                <enumeratedValue>
                  <name>111</name>
                  <description>Alternative 7 (chip-specific).</description>
                  <value>#111</value>
                </enumeratedValue>
              </enumeratedValues>
            </field>
            <field>
              <name>IRQC</name>
              <description>Interrupt Configuration</description>
              <bitOffset>16</bitOffset>
              <bitWidth>4</bitWidth>
              <access>read-write</access>
              <enumeratedValues>
                <enumeratedValue>
                  <name>0000</name>
                  <description>Interrupt/DMA request disabled.</description>
                  <value>#0000</value>
                </enumeratedValue>
                <enumeratedValue>
                  <name>0001</name>
                  <description>DMA request on rising edge.</description>
                  <value>#0001</value>
                </enumeratedValue>
                <enumeratedValue>
                  <name>0010</name>
                  <description>DMA request on falling edge.</description>
                  <value>#0010</value>
                </enumeratedValue>
                <enumeratedValue>
                  <name>0011</name>
                  <description>DMA request on either edge.</description>
                  <value>#0011</value>
                </enumeratedValue>
                <enumeratedValue>
                  <name>1000</name>
                  <description>Interrupt when logic 0.</description>
                  <value>#1000</value>
                </enumeratedValue>
                <enumeratedValue>
                  <name>1001</name>
                  <description>Interrupt on rising-edge.</description>
                  <value>#1001</value>
                </enumeratedValue>
                <enumeratedValue>
                  <name>1010</name>
                  <description>Interrupt on falling-edge.</description>
                  <value>#1010</value>
                </enumeratedValue>
                <enumeratedValue>
                  <name>1011</name>
                  <description>Interrupt on either edge.</description>
                  <value>#1011</value>
                </enumeratedValue>
                <enumeratedValue>
                  <name>1100</name>
                  <description>Interrupt when logic 1.</description>
                  <value>#1100</value>
                </enumeratedValue>
              </enumeratedValues>
            </field>
            <field>
              <name>ISF</name>
              <description>Interrupt Status Flag</description>
              <bitOffset>24</bitOffset>
              <bitWidth>1</bitWidth>
              <access>read-write</access>
              <enumeratedValues>
                <enumeratedValue>
                  <name>0</name>
                  <description>Configured interrupt is not detected.</description>
                  <value>#0</value>
                </enumeratedValue>
                <enumeratedValue>
                  <name>1</name>
                  <description>Configured interrupt is detected. If the pin is configured to generate a DMA request, then the corresponding flag will be cleared automatically at the completion of the requested DMA transfer. Otherwise, the flag remains set until a logic 1 is written to the flag. If the pin is configured for a level sensitive interrupt and the pin remains asserted, then the flag is set again immediately after it is cleared.</description>
                  <value>#1</value>
                </enumeratedValue>
              </enumeratedValues>
            </field>
          </fields>
        </register>
        <register>
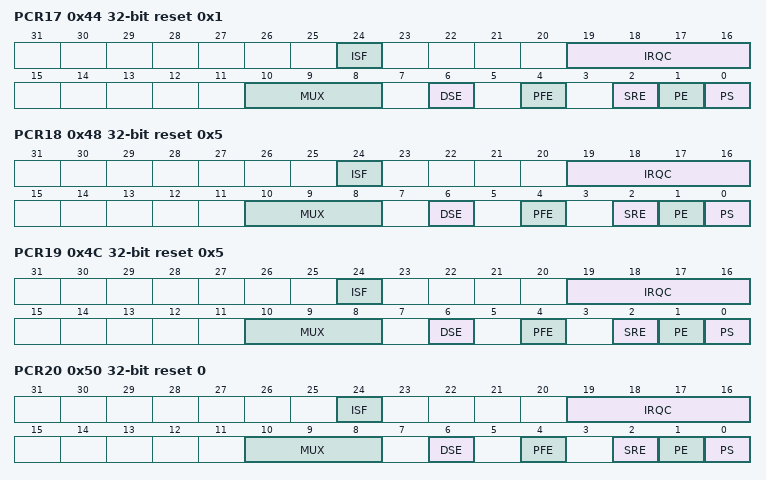
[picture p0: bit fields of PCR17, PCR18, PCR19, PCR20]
          <name>PCR17</name>
          <description>Pin Control Register n</description>
          <addressOffset>0x44</addressOffset>
          <size>32</size>
          <access>read-write</access>
          <resetValue>0x1</resetValue>
          <resetMask>0xFFFFFFFF</resetMask>
          <fields>
            <field>
              <name>PS</name>
              <description>Pull Select</description>
              <bitOffset>0</bitOffset>
              <bitWidth>1</bitWidth>
              <access>read-write</access>
              <enumeratedValues>
                <enumeratedValue>
                  <name>0</name>
                  <description>Internal pulldown resistor is enabled on the corresponding pin, if the corresponding PE field is set.</description>
                  <value>#0</value>
                </enumeratedValue>
                <enumeratedValue>
                  <name>1</name>
                  <description>Internal pullup resistor is enabled on the corresponding pin, if the corresponding PE field is set.</description>
                  <value>#1</value>
                </enumeratedValue>
              </enumeratedValues>
            </field>
            <field>
              <name>PE</name>
              <description>Pull Enable</description>
              <bitOffset>1</bitOffset>
              <bitWidth>1</bitWidth>
              <access>read-write</access>
              <enumeratedValues>
                <enumeratedValue>
                  <name>0</name>
                  <description>Internal pullup or pulldown resistor is not enabled on the corresponding pin.</description>
                  <value>#0</value>
                </enumeratedValue>
                <enumeratedValue>
                  <name>1</name>
                  <description>Internal pullup or pulldown resistor is enabled on the corresponding pin, if the pin is configured as a digital input.</description>
                  <value>#1</value>
                </enumeratedValue>
              </enumeratedValues>
            </field>
            <field>
              <name>SRE</name>
              <description>Slew Rate Enable</description>
              <bitOffset>2</bitOffset>
              <bitWidth>1</bitWidth>
              <access>read-write</access>
              <enumeratedValues>
                <enumeratedValue>
                  <name>0</name>
                  <description>Fast slew rate is configured on the corresponding pin, if the pin is configured as a digital output.</description>
                  <value>#0</value>
                </enumeratedValue>
                <enumeratedValue>
                  <name>1</name>
                  <description>Slow slew rate is configured on the corresponding pin, if the pin is configured as a digital output.</description>
                  <value>#1</value>
                </enumeratedValue>
              </enumeratedValues>
            </field>
            <field>
              <name>PFE</name>
              <description>Passive Filter Enable</description>
              <bitOffset>4</bitOffset>
              <bitWidth>1</bitWidth>
              <access>read-only</access>
              <enumeratedValues>
                <enumeratedValue>
                  <name>0</name>
                  <description>Passive input filter is disabled on the corresponding pin.</description>
                  <value>#0</value>
                </enumeratedValue>
                <enumeratedValue>
                  <name>1</name>
                  <description>Passive input filter is enabled on the corresponding pin, if the pin is configured as a digital input. Refer to the device data sheet for filter characteristics.</description>
                  <value>#1</value>
                </enumeratedValue>
              </enumeratedValues>
            </field>
            <field>
              <name>DSE</name>
              <description>Drive Strength Enable</description>
              <bitOffset>6</bitOffset>
              <bitWidth>1</bitWidth>
              <access>read-only</access>
              <enumeratedValues>
                <enumeratedValue>
                  <name>0</name>
                  <description>Low drive strength is configured on the corresponding pin, if pin is configured as a digital output.</description>
                  <value>#0</value>
                </enumeratedValue>
                <enumeratedValue>
                  <name>1</name>
                  <description>High drive strength is configured on the corresponding pin, if pin is configured as a digital output.</description>
                  <value>#1</value>
                </enumeratedValue>
              </enumeratedValues>
            </field>
            <field>
              <name>MUX</name>
              <description>Pin Mux Control</description>
              <bitOffset>8</bitOffset>
              <bitWidth>3</bitWidth>
              <access>read-write</access>
              <enumeratedValues>
                <enumeratedValue>
                  <name>000</name>
                  <description>Pin disabled (analog).</description>
                  <value>#000</value>
                </enumeratedValue>
                <enumeratedValue>
                  <name>001</name>
                  <description>Alternative 1 (GPIO).</description>
                  <value>#001</value>
                </enumeratedValue>
                <enumeratedValue>
                  <name>010</name>
                  <description>Alternative 2 (chip-specific).</description>
                  <value>#010</value>
                </enumeratedValue>
                <enumeratedValue>
                  <name>011</name>
                  <description>Alternative 3 (chip-specific).</description>
                  <value>#011</value>
                </enumeratedValue>
                <enumeratedValue>
                  <name>100</name>
                  <description>Alternative 4 (chip-specific).</description>
                  <value>#100</value>
                </enumeratedValue>
                <enumeratedValue>
                  <name>101</name>
                  <description>Alternative 5 (chip-specific).</description>
                  <value>#101</value>
                </enumeratedValue>
                <enumeratedValue>
                  <name>110</name>
                  <description>Alternative 6 (chip-specific).</description>
                  <value>#110</value>
                </enumeratedValue>
                <enumeratedValue>
                  <name>111</name>
                  <description>Alternative 7 (chip-specific).</description>
                  <value>#111</value>
                </enumeratedValue>
              </enumeratedValues>
            </field>
            <field>
              <name>IRQC</name>
              <description>Interrupt Configuration</description>
              <bitOffset>16</bitOffset>
              <bitWidth>4</bitWidth>
              <access>read-write</access>
              <enumeratedValues>
                <enumeratedValue>
                  <name>0000</name>
                  <description>Interrupt/DMA request disabled.</description>
                  <value>#0000</value>
                </enumeratedValue>
                <enumeratedValue>
                  <name>0001</name>
                  <description>DMA request on rising edge.</description>
                  <value>#0001</value>
                </enumeratedValue>
                <enumeratedValue>
                  <name>0010</name>
                  <description>DMA request on falling edge.</description>
                  <value>#0010</value>
                </enumeratedValue>
                <enumeratedValue>
                  <name>0011</name>
                  <description>DMA request on either edge.</description>
                  <value>#0011</value>
                </enumeratedValue>
                <enumeratedValue>
                  <name>1000</name>
                  <description>Interrupt when logic 0.</description>
                  <value>#1000</value>
                </enumeratedValue>
                <enumeratedValue>
                  <name>1001</name>
                  <description>Interrupt on rising-edge.</description>
                  <value>#1001</value>
                </enumeratedValue>
                <enumeratedValue>
                  <name>1010</name>
                  <description>Interrupt on falling-edge.</description>
                  <value>#1010</value>
                </enumeratedValue>
                <enumeratedValue>
                  <name>1011</name>
                  <description>Interrupt on either edge.</description>
                  <value>#1011</value>
                </enumeratedValue>
                <enumeratedValue>
                  <name>1100</name>
                  <description>Interrupt when logic 1.</description>
                  <value>#1100</value>
                </enumeratedValue>
              </enumeratedValues>
            </field>
            <field>
              <name>ISF</name>
              <description>Interrupt Status Flag</description>
              <bitOffset>24</bitOffset>
              <bitWidth>1</bitWidth>
              <access>read-write</access>
              <enumeratedValues>
                <enumeratedValue>
                  <name>0</name>
                  <description>Configured interrupt is not detected.</description>
                  <value>#0</value>
                </enumeratedValue>
                <enumeratedValue>
                  <name>1</name>
                  <description>Configured interrupt is detected. If the pin is configured to generate a DMA request, then the corresponding flag will be cleared automatically at the completion of the requested DMA transfer. Otherwise, the flag remains set until a logic 1 is written to the flag. If the pin is configured for a level sensitive interrupt and the pin remains asserted, then the flag is set again immediately after it is cleared.</description>
                  <value>#1</value>
                </enumeratedValue>
              </enumeratedValues>
            </field>
          </fields>
        </register>
        <register>
          <name>PCR18</name>
          <description>Pin Control Register n</description>
          <addressOffset>0x48</addressOffset>
          <size>32</size>
          <access>read-write</access>
          <resetValue>0x5</resetValue>
          <resetMask>0xFFFFFFFF</resetMask>
          <fields>
            <field>
              <name>PS</name>
              <description>Pull Select</description>
              <bitOffset>0</bitOffset>
              <bitWidth>1</bitWidth>
              <access>read-write</access>
              <enumeratedValues>
                <enumeratedValue>
                  <name>0</name>
                  <description>Internal pulldown resistor is enabled on the corresponding pin, if the corresponding PE field is set.</description>
                  <value>#0</value>
                </enumeratedValue>
                <enumeratedValue>
                  <name>1</name>
                  <description>Internal pullup resistor is enabled on the corresponding pin, if the corresponding PE field is set.</description>
                  <value>#1</value>
                </enumeratedValue>
              </enumeratedValues>
            </field>
            <field>
              <name>PE</name>
              <description>Pull Enable</description>
              <bitOffset>1</bitOffset>
              <bitWidth>1</bitWidth>
              <access>read-write</access>
              <enumeratedValues>
                <enumeratedValue>
                  <name>0</name>
                  <description>Internal pullup or pulldown resistor is not enabled on the corresponding pin.</description>
                  <value>#0</value>
                </enumeratedValue>
                <enumeratedValue>
                  <name>1</name>
                  <description>Internal pullup or pulldown resistor is enabled on the corresponding pin, if the pin is configured as a digital input.</description>
                  <value>#1</value>
                </enumeratedValue>
              </enumeratedValues>
            </field>
            <field>
              <name>SRE</name>
              <description>Slew Rate Enable</description>
              <bitOffset>2</bitOffset>
              <bitWidth>1</bitWidth>
              <access>read-write</access>
              <enumeratedValues>
                <enumeratedValue>
                  <name>0</name>
                  <description>Fast slew rate is configured on the corresponding pin, if the pin is configured as a digital output.</description>
                  <value>#0</value>
                </enumeratedValue>
                <enumeratedValue>
                  <name>1</name>
                  <description>Slow slew rate is configured on the corresponding pin, if the pin is configured as a digital output.</description>
                  <value>#1</value>
                </enumeratedValue>
              </enumeratedValues>
            </field>
            <field>
              <name>PFE</name>
              <description>Passive Filter Enable</description>
              <bitOffset>4</bitOffset>
              <bitWidth>1</bitWidth>
              <access>read-only</access>
              <enumeratedValues>
                <enumeratedValue>
                  <name>0</name>
                  <description>Passive input filter is disabled on the corresponding pin.</description>
                  <value>#0</value>
                </enumeratedValue>
                <enumeratedValue>
                  <name>1</name>
                  <description>Passive input filter is enabled on the corresponding pin, if the pin is configured as a digital input. Refer to the device data sheet for filter characteristics.</description>
                  <value>#1</value>
                </enumeratedValue>
              </enumeratedValues>
            </field>
            <field>
              <name>DSE</name>
              <description>Drive Strength Enable</description>
              <bitOffset>6</bitOffset>
              <bitWidth>1</bitWidth>
              <access>read-only</access>
              <enumeratedValues>
                <enumeratedValue>
                  <name>0</name>
                  <description>Low drive strength is configured on the corresponding pin, if pin is configured as a digital output.</description>
                  <value>#0</value>
                </enumeratedValue>
                <enumeratedValue>
                  <name>1</name>
                  <description>High drive strength is configured on the corresponding pin, if pin is configured as a digital output.</description>
                  <value>#1</value>
                </enumeratedValue>
              </enumeratedValues>
            </field>
            <field>
              <name>MUX</name>
              <description>Pin Mux Control</description>
              <bitOffset>8</bitOffset>
              <bitWidth>3</bitWidth>
              <access>read-write</access>
              <enumeratedValues>
                <enumeratedValue>
                  <name>000</name>
                  <description>Pin disabled (analog).</description>
                  <value>#000</value>
                </enumeratedValue>
                <enumeratedValue>
                  <name>001</name>
                  <description>Alternative 1 (GPIO).</description>
                  <value>#001</value>
                </enumeratedValue>
                <enumeratedValue>
                  <name>010</name>
                  <description>Alternative 2 (chip-specific).</description>
                  <value>#010</value>
                </enumeratedValue>
                <enumeratedValue>
                  <name>011</name>
                  <description>Alternative 3 (chip-specific).</description>
                  <value>#011</value>
                </enumeratedValue>
                <enumeratedValue>
                  <name>100</name>
                  <description>Alternative 4 (chip-specific).</description>
                  <value>#100</value>
                </enumeratedValue>
                <enumeratedValue>
                  <name>101</name>
                  <description>Alternative 5 (chip-specific).</description>
                  <value>#101</value>
                </enumeratedValue>
                <enumeratedValue>
                  <name>110</name>
                  <description>Alternative 6 (chip-specific).</description>
                  <value>#110</value>
                </enumeratedValue>
                <enumeratedValue>
                  <name>111</name>
                  <description>Alternative 7 (chip-specific).</description>
                  <value>#111</value>
                </enumeratedValue>
              </enumeratedValues>
            </field>
            <field>
              <name>IRQC</name>
              <description>Interrupt Configuration</description>
              <bitOffset>16</bitOffset>
              <bitWidth>4</bitWidth>
              <access>read-write</access>
              <enumeratedValues>
                <enumeratedValue>
                  <name>0000</name>
                  <description>Interrupt/DMA request disabled.</description>
                  <value>#0000</value>
                </enumeratedValue>
                <enumeratedValue>
                  <name>0001</name>
                  <description>DMA request on rising edge.</description>
                  <value>#0001</value>
                </enumeratedValue>
                <enumeratedValue>
                  <name>0010</name>
                  <description>DMA request on falling edge.</description>
                  <value>#0010</value>
                </enumeratedValue>
                <enumeratedValue>
                  <name>0011</name>
                  <description>DMA request on either edge.</description>
                  <value>#0011</value>
                </enumeratedValue>
                <enumeratedValue>
                  <name>1000</name>
                  <description>Interrupt when logic 0.</description>
                  <value>#1000</value>
                </enumeratedValue>
                <enumeratedValue>
                  <name>1001</name>
                  <description>Interrupt on rising-edge.</description>
                  <value>#1001</value>
                </enumeratedValue>
                <enumeratedValue>
                  <name>1010</name>
                  <description>Interrupt on falling-edge.</description>
                  <value>#1010</value>
                </enumeratedValue>
                <enumeratedValue>
                  <name>1011</name>
                  <description>Interrupt on either edge.</description>
                  <value>#1011</value>
                </enumeratedValue>
                <enumeratedValue>
                  <name>1100</name>
                  <description>Interrupt when logic 1.</description>
                  <value>#1100</value>
                </enumeratedValue>
              </enumeratedValues>
            </field>
            <field>
              <name>ISF</name>
              <description>Interrupt Status Flag</description>
              <bitOffset>24</bitOffset>
              <bitWidth>1</bitWidth>
              <access>read-write</access>
              <enumeratedValues>
                <enumeratedValue>
                  <name>0</name>
                  <description>Configured interrupt is not detected.</description>
                  <value>#0</value>
                </enumeratedValue>
                <enumeratedValue>
                  <name>1</name>
                  <description>Configured interrupt is detected. If the pin is configured to generate a DMA request, then the corresponding flag will be cleared automatically at the completion of the requested DMA transfer. Otherwise, the flag remains set until a logic 1 is written to the flag. If the pin is configured for a level sensitive interrupt and the pin remains asserted, then the flag is set again immediately after it is cleared.</description>
                  <value>#1</value>
                </enumeratedValue>
              </enumeratedValues>
            </field>
          </fields>
        </register>
        <register>
          <name>PCR19</name>
          <description>Pin Control Register n</description>
          <addressOffset>0x4C</addressOffset>
          <size>32</size>
          <access>read-write</access>
          <resetValue>0x5</resetValue>
          <resetMask>0xFFFFFFFF</resetMask>
          <fields>
            <field>
              <name>PS</name>
              <description>Pull Select</description>
              <bitOffset>0</bitOffset>
              <bitWidth>1</bitWidth>
              <access>read-write</access>
              <enumeratedValues>
                <enumeratedValue>
                  <name>0</name>
                  <description>Internal pulldown resistor is enabled on the corresponding pin, if the corresponding PE field is set.</description>
                  <value>#0</value>
                </enumeratedValue>
                <enumeratedValue>
                  <name>1</name>
                  <description>Internal pullup resistor is enabled on the corresponding pin, if the corresponding PE field is set.</description>
                  <value>#1</value>
                </enumeratedValue>
              </enumeratedValues>
            </field>
            <field>
              <name>PE</name>
              <description>Pull Enable</description>
              <bitOffset>1</bitOffset>
              <bitWidth>1</bitWidth>
              <access>read-write</access>
              <enumeratedValues>
                <enumeratedValue>
                  <name>0</name>
                  <description>Internal pullup or pulldown resistor is not enabled on the corresponding pin.</description>
                  <value>#0</value>
                </enumeratedValue>
                <enumeratedValue>
                  <name>1</name>
                  <description>Internal pullup or pulldown resistor is enabled on the corresponding pin, if the pin is configured as a digital input.</description>
                  <value>#1</value>
                </enumeratedValue>
              </enumeratedValues>
            </field>
            <field>
              <name>SRE</name>
              <description>Slew Rate Enable</description>
              <bitOffset>2</bitOffset>
              <bitWidth>1</bitWidth>
              <access>read-write</access>
              <enumeratedValues>
                <enumeratedValue>
                  <name>0</name>
                  <description>Fast slew rate is configured on the corresponding pin, if the pin is configured as a digital output.</description>
                  <value>#0</value>
                </enumeratedValue>
                <enumeratedValue>
                  <name>1</name>
                  <description>Slow slew rate is configured on the corresponding pin, if the pin is configured as a digital output.</description>
                  <value>#1</value>
                </enumeratedValue>
              </enumeratedValues>
            </field>
            <field>
              <name>PFE</name>
              <description>Passive Filter Enable</description>
              <bitOffset>4</bitOffset>
              <bitWidth>1</bitWidth>
              <access>read-only</access>
              <enumeratedValues>
                <enumeratedValue>
                  <name>0</name>
                  <description>Passive input filter is disabled on the corresponding pin.</description>
                  <value>#0</value>
                </enumeratedValue>
                <enumeratedValue>
                  <name>1</name>
                  <description>Passive input filter is enabled on the corresponding pin, if the pin is configured as a digital input. Refer to the device data sheet for filter characteristics.</description>
                  <value>#1</value>
                </enumeratedValue>
              </enumeratedValues>
            </field>
            <field>
              <name>DSE</name>
              <description>Drive Strength Enable</description>
              <bitOffset>6</bitOffset>
              <bitWidth>1</bitWidth>
              <access>read-only</access>
              <enumeratedValues>
                <enumeratedValue>
                  <name>0</name>
                  <description>Low drive strength is configured on the corresponding pin, if pin is configured as a digital output.</description>
                  <value>#0</value>
                </enumeratedValue>
                <enumeratedValue>
                  <name>1</name>
                  <description>High drive strength is configured on the corresponding pin, if pin is configured as a digital output.</description>
                  <value>#1</value>
                </enumeratedValue>
              </enumeratedValues>
            </field>
            <field>
              <name>MUX</name>
              <description>Pin Mux Control</description>
              <bitOffset>8</bitOffset>
              <bitWidth>3</bitWidth>
              <access>read-write</access>
              <enumeratedValues>
                <enumeratedValue>
                  <name>000</name>
                  <description>Pin disabled (analog).</description>
                  <value>#000</value>
                </enumeratedValue>
                <enumeratedValue>
                  <name>001</name>
                  <description>Alternative 1 (GPIO).</description>
                  <value>#001</value>
                </enumeratedValue>
                <enumeratedValue>
                  <name>010</name>
                  <description>Alternative 2 (chip-specific).</description>
                  <value>#010</value>
                </enumeratedValue>
                <enumeratedValue>
                  <name>011</name>
                  <description>Alternative 3 (chip-specific).</description>
                  <value>#011</value>
                </enumeratedValue>
                <enumeratedValue>
                  <name>100</name>
                  <description>Alternative 4 (chip-specific).</description>
                  <value>#100</value>
                </enumeratedValue>
                <enumeratedValue>
                  <name>101</name>
                  <description>Alternative 5 (chip-specific).</description>
                  <value>#101</value>
                </enumeratedValue>
                <enumeratedValue>
                  <name>110</name>
                  <description>Alternative 6 (chip-specific).</description>
                  <value>#110</value>
                </enumeratedValue>
                <enumeratedValue>
                  <name>111</name>
                  <description>Alternative 7 (chip-specific).</description>
                  <value>#111</value>
                </enumeratedValue>
              </enumeratedValues>
            </field>
            <field>
              <name>IRQC</name>
              <description>Interrupt Configuration</description>
              <bitOffset>16</bitOffset>
              <bitWidth>4</bitWidth>
              <access>read-write</access>
              <enumeratedValues>
                <enumeratedValue>
                  <name>0000</name>
                  <description>Interrupt/DMA request disabled.</description>
                  <value>#0000</value>
                </enumeratedValue>
                <enumeratedValue>
                  <name>0001</name>
                  <description>DMA request on rising edge.</description>
                  <value>#0001</value>
                </enumeratedValue>
                <enumeratedValue>
                  <name>0010</name>
                  <description>DMA request on falling edge.</description>
                  <value>#0010</value>
                </enumeratedValue>
                <enumeratedValue>
                  <name>0011</name>
                  <description>DMA request on either edge.</description>
                  <value>#0011</value>
                </enumeratedValue>
                <enumeratedValue>
                  <name>1000</name>
                  <description>Interrupt when logic 0.</description>
                  <value>#1000</value>
                </enumeratedValue>
                <enumeratedValue>
                  <name>1001</name>
                  <description>Interrupt on rising-edge.</description>
                  <value>#1001</value>
                </enumeratedValue>
                <enumeratedValue>
                  <name>1010</name>
                  <description>Interrupt on falling-edge.</description>
                  <value>#1010</value>
                </enumeratedValue>
                <enumeratedValue>
                  <name>1011</name>
                  <description>Interrupt on either edge.</description>
                  <value>#1011</value>
                </enumeratedValue>
                <enumeratedValue>
                  <name>1100</name>
                  <description>Interrupt when logic 1.</description>
                  <value>#1100</value>
                </enumeratedValue>
              </enumeratedValues>
            </field>
            <field>
              <name>ISF</name>
              <description>Interrupt Status Flag</description>
              <bitOffset>24</bitOffset>
              <bitWidth>1</bitWidth>
              <access>read-write</access>
              <enumeratedValues>
                <enumeratedValue>
                  <name>0</name>
                  <description>Configured interrupt is not detected.</description>
                  <value>#0</value>
                </enumeratedValue>
                <enumeratedValue>
                  <name>1</name>
                  <description>Configured interrupt is detected. If the pin is configured to generate a DMA request, then the corresponding flag will be cleared automatically at the completion of the requested DMA transfer. Otherwise, the flag remains set until a logic 1 is written to the flag. If the pin is configured for a level sensitive interrupt and the pin remains asserted, then the flag is set again immediately after it is cleared.</description>
                  <value>#1</value>
                </enumeratedValue>
              </enumeratedValues>
            </field>
          </fields>
        </register>
        <register>
          <name>PCR20</name>
          <description>Pin Control Register n</description>
          <addressOffset>0x50</addressOffset>
          <size>32</size>
          <access>read-write</access>
          <resetValue>0</resetValue>
          <resetMask>0xFFFFFFFF</resetMask>
          <fields>
            <field>
              <name>PS</name>
              <description>Pull Select</description>
              <bitOffset>0</bitOffset>
              <bitWidth>1</bitWidth>
              <access>read-only</access>
              <enumeratedValues>
                <enumeratedValue>
                  <name>0</name>
                  <description>Internal pulldown resistor is enabled on the corresponding pin, if the corresponding PE field is set.</description>
                  <value>#0</value>
                </enumeratedValue>
                <enumeratedValue>
                  <name>1</name>
                  <description>Internal pullup resistor is enabled on the corresponding pin, if the corresponding PE field is set.</description>
                  <value>#1</value>
                </enumeratedValue>
              </enumeratedValues>
            </field>
            <field>
              <name>PE</name>
              <description>Pull Enable</description>
              <bitOffset>1</bitOffset>
              <bitWidth>1</bitWidth>
              <access>read-only</access>
              <enumeratedValues>
                <enumeratedValue>
                  <name>0</name>
                  <description>Internal pullup or pulldown resistor is not enabled on the corresponding pin.</description>
                  <value>#0</value>
                </enumeratedValue>
                <enumeratedValue>
                  <name>1</name>
                  <description>Internal pullup or pulldown resistor is enabled on the corresponding pin, if the pin is configured as a digital input.</description>
                  <value>#1</value>
                </enumeratedValue>
              </enumeratedValues>
            </field>
            <field>
              <name>SRE</name>
              <description>Slew Rate Enable</description>
              <bitOffset>2</bitOffset>
              <bitWidth>1</bitWidth>
              <access>read-only</access>
              <enumeratedValues>
                <enumeratedValue>
                  <name>0</name>
                  <description>Fast slew rate is configured on the corresponding pin, if the pin is configured as a digital output.</description>
                  <value>#0</value>
                </enumeratedValue>
                <enumeratedValue>
                  <name>1</name>
                  <description>Slow slew rate is configured on the corresponding pin, if the pin is configured as a digital output.</description>
                  <value>#1</value>
                </enumeratedValue>
              </enumeratedValues>
            </field>
            <field>
              <name>PFE</name>
              <description>Passive Filter Enable</description>
              <bitOffset>4</bitOffset>
              <bitWidth>1</bitWidth>
              <access>read-only</access>
              <enumeratedValues>
                <enumeratedValue>
                  <name>0</name>
                  <description>Passive input filter is disabled on the corresponding pin.</description>
                  <value>#0</value>
                </enumeratedValue>
                <enumeratedValue>
                  <name>1</name>
                  <description>Passive input filter is enabled on the corresponding pin, if the pin is configured as a digital input. Refer to the device data sheet for filter characteristics.</description>
                  <value>#1</value>
                </enumeratedValue>
              </enumeratedValues>
            </field>
            <field>
              <name>DSE</name>
              <description>Drive Strength Enable</description>
              <bitOffset>6</bitOffset>
              <bitWidth>1</bitWidth>
              <access>read-only</access>
              <enumeratedValues>
                <enumeratedValue>
                  <name>0</name>
                  <description>Low drive strength is configured on the corresponding pin, if pin is configured as a digital output.</description>
                  <value>#0</value>
                </enumeratedValue>
                <enumeratedValue>
                  <name>1</name>
                  <description>High drive strength is configured on the corresponding pin, if pin is configured as a digital output.</description>
                  <value>#1</value>
                </enumeratedValue>
              </enumeratedValues>
            </field>
            <field>
              <name>MUX</name>
              <description>Pin Mux Control</description>
              <bitOffset>8</bitOffset>
              <bitWidth>3</bitWidth>
              <access>read-write</access>
              <enumeratedValues>
                <enumeratedValue>
                  <name>000</name>
                  <description>Pin disabled (analog).</description>
                  <value>#000</value>
                </enumeratedValue>
                <enumeratedValue>
                  <name>001</name>
                  <description>Alternative 1 (GPIO).</description>
                  <value>#001</value>
                </enumeratedValue>
                <enumeratedValue>
                  <name>010</name>
                  <description>Alternative 2 (chip-specific).</description>
                  <value>#010</value>
                </enumeratedValue>
                <enumeratedValue>
                  <name>011</name>
                  <description>Alternative 3 (chip-specific).</description>
                  <value>#011</value>
                </enumeratedValue>
                <enumeratedValue>
                  <name>100</name>
                  <description>Alternative 4 (chip-specific).</description>
                  <value>#100</value>
                </enumeratedValue>
                <enumeratedValue>
                  <name>101</name>
                  <description>Alternative 5 (chip-specific).</description>
                  <value>#101</value>
                </enumeratedValue>
                <enumeratedValue>
                  <name>110</name>
                  <description>Alternative 6 (chip-specific).</description>
                  <value>#110</value>
                </enumeratedValue>
                <enumeratedValue>
                  <name>111</name>
                  <description>Alternative 7 (chip-specific).</description>
                  <value>#111</value>
                </enumeratedValue>
              </enumeratedValues>
            </field>
            <field>
              <name>IRQC</name>
              <description>Interrupt Configuration</description>
              <bitOffset>16</bitOffset>
              <bitWidth>4</bitWidth>
              <access>read-write</access>
              <enumeratedValues>
                <enumeratedValue>
                  <name>0000</name>
                  <description>Interrupt/DMA request disabled.</description>
                  <value>#0000</value>
                </enumeratedValue>
                <enumeratedValue>
                  <name>0001</name>
                  <description>DMA request on rising edge.</description>
                  <value>#0001</value>
                </enumeratedValue>
                <enumeratedValue>
                  <name>0010</name>
                  <description>DMA request on falling edge.</description>
                  <value>#0010</value>
                </enumeratedValue>
                <enumeratedValue>
                  <name>0011</name>
                  <description>DMA request on either edge.</description>
                  <value>#0011</value>
                </enumeratedValue>
                <enumeratedValue>
                  <name>1000</name>
                  <description>Interrupt when logic 0.</description>
                  <value>#1000</value>
                </enumeratedValue>
                <enumeratedValue>
                  <name>1001</name>
                  <description>Interrupt on rising-edge.</description>
                  <value>#1001</value>
                </enumeratedValue>
                <enumeratedValue>
                  <name>1010</name>
                  <description>Interrupt on falling-edge.</description>
                  <value>#1010</value>
                </enumeratedValue>
                <enumeratedValue>
                  <name>1011</name>
                  <description>Interrupt on either edge.</description>
                  <value>#1011</value>
                </enumeratedValue>
                <enumeratedValue>
                  <name>1100</name>
                  <description>Interrupt when logic 1.</description>
                  <value>#1100</value>
                </enumeratedValue>
              </enumeratedValues>
            </field>
            <field>
              <name>ISF</name>
              <description>Interrupt Status Flag</description>
              <bitOffset>24</bitOffset>
              <bitWidth>1</bitWidth>
              <access>read-write</access>
              <enumeratedValues>
                <enumeratedValue>
                  <name>0</name>
                  <description>Configured interrupt is not detected.</description>
                  <value>#0</value>
                </enumeratedValue>
                <enumeratedValue>
                  <name>1</name>
                  <description>Configured interrupt is detected. If the pin is configured to generate a DMA request, then the corresponding flag will be cleared automatically at the completion of the requested DMA transfer. Otherwise, the flag remains set until a logic 1 is written to the flag. If the pin is configured for a level sensitive interrupt and the pin remains asserted, then the flag is set again immediately after it is cleared.</description>
                  <value>#1</value>
                </enumeratedValue>
              </enumeratedValues>
            </field>
          </fields>
        </register>
        <register>
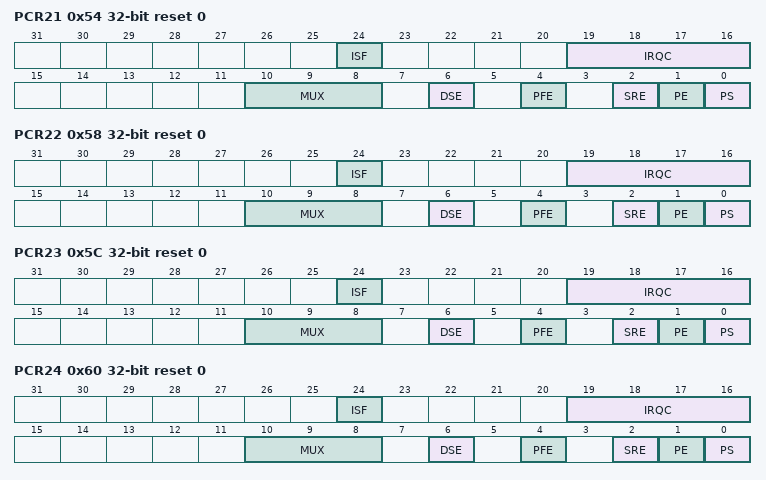
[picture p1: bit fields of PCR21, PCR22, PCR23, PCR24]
          <name>PCR21</name>
          <description>Pin Control Register n</description>
          <addressOffset>0x54</addressOffset>
          <size>32</size>
          <access>read-write</access>
          <resetValue>0</resetValue>
          <resetMask>0xFFFFFFFF</resetMask>
          <fields>
            <field>
              <name>PS</name>
              <description>Pull Select</description>
              <bitOffset>0</bitOffset>
              <bitWidth>1</bitWidth>
              <access>read-only</access>
              <enumeratedValues>
                <enumeratedValue>
                  <name>0</name>
                  <description>Internal pulldown resistor is enabled on the corresponding pin, if the corresponding PE field is set.</description>
                  <value>#0</value>
                </enumeratedValue>
                <enumeratedValue>
                  <name>1</name>
                  <description>Internal pullup resistor is enabled on the corresponding pin, if the corresponding PE field is set.</description>
                  <value>#1</value>
                </enumeratedValue>
              </enumeratedValues>
            </field>
            <field>
              <name>PE</name>
              <description>Pull Enable</description>
              <bitOffset>1</bitOffset>
              <bitWidth>1</bitWidth>
              <access>read-only</access>
              <enumeratedValues>
                <enumeratedValue>
                  <name>0</name>
                  <description>Internal pullup or pulldown resistor is not enabled on the corresponding pin.</description>
                  <value>#0</value>
                </enumeratedValue>
                <enumeratedValue>
                  <name>1</name>
                  <description>Internal pullup or pulldown resistor is enabled on the corresponding pin, if the pin is configured as a digital input.</description>
                  <value>#1</value>
                </enumeratedValue>
              </enumeratedValues>
            </field>
            <field>
              <name>SRE</name>
              <description>Slew Rate Enable</description>
              <bitOffset>2</bitOffset>
              <bitWidth>1</bitWidth>
              <access>read-only</access>
              <enumeratedValues>
                <enumeratedValue>
                  <name>0</name>
                  <description>Fast slew rate is configured on the corresponding pin, if the pin is configured as a digital output.</description>
                  <value>#0</value>
                </enumeratedValue>
                <enumeratedValue>
                  <name>1</name>
                  <description>Slow slew rate is configured on the corresponding pin, if the pin is configured as a digital output.</description>
                  <value>#1</value>
                </enumeratedValue>
              </enumeratedValues>
            </field>
            <field>
              <name>PFE</name>
              <description>Passive Filter Enable</description>
              <bitOffset>4</bitOffset>
              <bitWidth>1</bitWidth>
              <access>read-only</access>
              <enumeratedValues>
                <enumeratedValue>
                  <name>0</name>
                  <description>Passive input filter is disabled on the corresponding pin.</description>
                  <value>#0</value>
                </enumeratedValue>
                <enumeratedValue>
                  <name>1</name>
                  <description>Passive input filter is enabled on the corresponding pin, if the pin is configured as a digital input. Refer to the device data sheet for filter characteristics.</description>
                  <value>#1</value>
                </enumeratedValue>
              </enumeratedValues>
            </field>
            <field>
              <name>DSE</name>
              <description>Drive Strength Enable</description>
              <bitOffset>6</bitOffset>
              <bitWidth>1</bitWidth>
              <access>read-only</access>
              <enumeratedValues>
                <enumeratedValue>
                  <name>0</name>
                  <description>Low drive strength is configured on the corresponding pin, if pin is configured as a digital output.</description>
                  <value>#0</value>
                </enumeratedValue>
                <enumeratedValue>
                  <name>1</name>
                  <description>High drive strength is configured on the corresponding pin, if pin is configured as a digital output.</description>
                  <value>#1</value>
                </enumeratedValue>
              </enumeratedValues>
            </field>
            <field>
              <name>MUX</name>
              <description>Pin Mux Control</description>
              <bitOffset>8</bitOffset>
              <bitWidth>3</bitWidth>
              <access>read-write</access>
              <enumeratedValues>
                <enumeratedValue>
                  <name>000</name>
                  <description>Pin disabled (analog).</description>
                  <value>#000</value>
                </enumeratedValue>
                <enumeratedValue>
                  <name>001</name>
                  <description>Alternative 1 (GPIO).</description>
                  <value>#001</value>
                </enumeratedValue>
                <enumeratedValue>
                  <name>010</name>
                  <description>Alternative 2 (chip-specific).</description>
                  <value>#010</value>
                </enumeratedValue>
                <enumeratedValue>
                  <name>011</name>
                  <description>Alternative 3 (chip-specific).</description>
                  <value>#011</value>
                </enumeratedValue>
                <enumeratedValue>
                  <name>100</name>
                  <description>Alternative 4 (chip-specific).</description>
                  <value>#100</value>
                </enumeratedValue>
                <enumeratedValue>
                  <name>101</name>
                  <description>Alternative 5 (chip-specific).</description>
                  <value>#101</value>
                </enumeratedValue>
                <enumeratedValue>
                  <name>110</name>
                  <description>Alternative 6 (chip-specific).</description>
                  <value>#110</value>
                </enumeratedValue>
                <enumeratedValue>
                  <name>111</name>
                  <description>Alternative 7 (chip-specific).</description>
                  <value>#111</value>
                </enumeratedValue>
              </enumeratedValues>
            </field>
            <field>
              <name>IRQC</name>
              <description>Interrupt Configuration</description>
              <bitOffset>16</bitOffset>
              <bitWidth>4</bitWidth>
              <access>read-write</access>
              <enumeratedValues>
                <enumeratedValue>
                  <name>0000</name>
                  <description>Interrupt/DMA request disabled.</description>
                  <value>#0000</value>
                </enumeratedValue>
                <enumeratedValue>
                  <name>0001</name>
                  <description>DMA request on rising edge.</description>
                  <value>#0001</value>
                </enumeratedValue>
                <enumeratedValue>
                  <name>0010</name>
                  <description>DMA request on falling edge.</description>
                  <value>#0010</value>
                </enumeratedValue>
                <enumeratedValue>
                  <name>0011</name>
                  <description>DMA request on either edge.</description>
                  <value>#0011</value>
                </enumeratedValue>
                <enumeratedValue>
                  <name>1000</name>
                  <description>Interrupt when logic 0.</description>
                  <value>#1000</value>
                </enumeratedValue>
                <enumeratedValue>
                  <name>1001</name>
                  <description>Interrupt on rising-edge.</description>
                  <value>#1001</value>
                </enumeratedValue>
                <enumeratedValue>
                  <name>1010</name>
                  <description>Interrupt on falling-edge.</description>
                  <value>#1010</value>
                </enumeratedValue>
                <enumeratedValue>
                  <name>1011</name>
                  <description>Interrupt on either edge.</description>
                  <value>#1011</value>
                </enumeratedValue>
                <enumeratedValue>
                  <name>1100</name>
                  <description>Interrupt when logic 1.</description>
                  <value>#1100</value>
                </enumeratedValue>
              </enumeratedValues>
            </field>
            <field>
              <name>ISF</name>
              <description>Interrupt Status Flag</description>
              <bitOffset>24</bitOffset>
              <bitWidth>1</bitWidth>
              <access>read-write</access>
              <enumeratedValues>
                <enumeratedValue>
                  <name>0</name>
                  <description>Configured interrupt is not detected.</description>
                  <value>#0</value>
                </enumeratedValue>
                <enumeratedValue>
                  <name>1</name>
                  <description>Configured interrupt is detected. If the pin is configured to generate a DMA request, then the corresponding flag will be cleared automatically at the completion of the requested DMA transfer. Otherwise, the flag remains set until a logic 1 is written to the flag. If the pin is configured for a level sensitive interrupt and the pin remains asserted, then the flag is set again immediately after it is cleared.</description>
                  <value>#1</value>
                </enumeratedValue>
              </enumeratedValues>
            </field>
          </fields>
        </register>
        <register>
          <name>PCR22</name>
          <description>Pin Control Register n</description>
          <addressOffset>0x58</addressOffset>
          <size>32</size>
          <access>read-write</access>
          <resetValue>0</resetValue>
          <resetMask>0xFFFFFFFF</resetMask>
          <fields>
            <field>
              <name>PS</name>
              <description>Pull Select</description>
              <bitOffset>0</bitOffset>
              <bitWidth>1</bitWidth>
              <access>read-only</access>
              <enumeratedValues>
                <enumeratedValue>
                  <name>0</name>
                  <description>Internal pulldown resistor is enabled on the corresponding pin, if the corresponding PE field is set.</description>
                  <value>#0</value>
                </enumeratedValue>
                <enumeratedValue>
                  <name>1</name>
                  <description>Internal pullup resistor is enabled on the corresponding pin, if the corresponding PE field is set.</description>
                  <value>#1</value>
                </enumeratedValue>
              </enumeratedValues>
            </field>
            <field>
              <name>PE</name>
              <description>Pull Enable</description>
              <bitOffset>1</bitOffset>
              <bitWidth>1</bitWidth>
              <access>read-only</access>
              <enumeratedValues>
                <enumeratedValue>
                  <name>0</name>
                  <description>Internal pullup or pulldown resistor is not enabled on the corresponding pin.</description>
                  <value>#0</value>
                </enumeratedValue>
                <enumeratedValue>
                  <name>1</name>
                  <description>Internal pullup or pulldown resistor is enabled on the corresponding pin, if the pin is configured as a digital input.</description>
                  <value>#1</value>
                </enumeratedValue>
              </enumeratedValues>
            </field>
            <field>
              <name>SRE</name>
              <description>Slew Rate Enable</description>
              <bitOffset>2</bitOffset>
              <bitWidth>1</bitWidth>
              <access>read-only</access>
              <enumeratedValues>
                <enumeratedValue>
                  <name>0</name>
                  <description>Fast slew rate is configured on the corresponding pin, if the pin is configured as a digital output.</description>
                  <value>#0</value>
                </enumeratedValue>
                <enumeratedValue>
                  <name>1</name>
                  <description>Slow slew rate is configured on the corresponding pin, if the pin is configured as a digital output.</description>
                  <value>#1</value>
                </enumeratedValue>
              </enumeratedValues>
            </field>
            <field>
              <name>PFE</name>
              <description>Passive Filter Enable</description>
              <bitOffset>4</bitOffset>
              <bitWidth>1</bitWidth>
              <access>read-only</access>
              <enumeratedValues>
                <enumeratedValue>
                  <name>0</name>
                  <description>Passive input filter is disabled on the corresponding pin.</description>
                  <value>#0</value>
                </enumeratedValue>
                <enumeratedValue>
                  <name>1</name>
                  <description>Passive input filter is enabled on the corresponding pin, if the pin is configured as a digital input. Refer to the device data sheet for filter characteristics.</description>
                  <value>#1</value>
                </enumeratedValue>
              </enumeratedValues>
            </field>
            <field>
              <name>DSE</name>
              <description>Drive Strength Enable</description>
              <bitOffset>6</bitOffset>
              <bitWidth>1</bitWidth>
              <access>read-only</access>
              <enumeratedValues>
                <enumeratedValue>
                  <name>0</name>
                  <description>Low drive strength is configured on the corresponding pin, if pin is configured as a digital output.</description>
                  <value>#0</value>
                </enumeratedValue>
                <enumeratedValue>
                  <name>1</name>
                  <description>High drive strength is configured on the corresponding pin, if pin is configured as a digital output.</description>
                  <value>#1</value>
                </enumeratedValue>
              </enumeratedValues>
            </field>
            <field>
              <name>MUX</name>
              <description>Pin Mux Control</description>
              <bitOffset>8</bitOffset>
              <bitWidth>3</bitWidth>
              <access>read-write</access>
              <enumeratedValues>
                <enumeratedValue>
                  <name>000</name>
                  <description>Pin disabled (analog).</description>
                  <value>#000</value>
                </enumeratedValue>
                <enumeratedValue>
                  <name>001</name>
                  <description>Alternative 1 (GPIO).</description>
                  <value>#001</value>
                </enumeratedValue>
                <enumeratedValue>
                  <name>010</name>
                  <description>Alternative 2 (chip-specific).</description>
                  <value>#010</value>
                </enumeratedValue>
                <enumeratedValue>
                  <name>011</name>
                  <description>Alternative 3 (chip-specific).</description>
                  <value>#011</value>
                </enumeratedValue>
                <enumeratedValue>
                  <name>100</name>
                  <description>Alternative 4 (chip-specific).</description>
                  <value>#100</value>
                </enumeratedValue>
                <enumeratedValue>
                  <name>101</name>
                  <description>Alternative 5 (chip-specific).</description>
                  <value>#101</value>
                </enumeratedValue>
                <enumeratedValue>
                  <name>110</name>
                  <description>Alternative 6 (chip-specific).</description>
                  <value>#110</value>
                </enumeratedValue>
                <enumeratedValue>
                  <name>111</name>
                  <description>Alternative 7 (chip-specific).</description>
                  <value>#111</value>
                </enumeratedValue>
              </enumeratedValues>
            </field>
            <field>
              <name>IRQC</name>
              <description>Interrupt Configuration</description>
              <bitOffset>16</bitOffset>
              <bitWidth>4</bitWidth>
              <access>read-write</access>
              <enumeratedValues>
                <enumeratedValue>
                  <name>0000</name>
                  <description>Interrupt/DMA request disabled.</description>
                  <value>#0000</value>
                </enumeratedValue>
                <enumeratedValue>
                  <name>0001</name>
                  <description>DMA request on rising edge.</description>
                  <value>#0001</value>
                </enumeratedValue>
                <enumeratedValue>
                  <name>0010</name>
                  <description>DMA request on falling edge.</description>
                  <value>#0010</value>
                </enumeratedValue>
                <enumeratedValue>
                  <name>0011</name>
                  <description>DMA request on either edge.</description>
                  <value>#0011</value>
                </enumeratedValue>
                <enumeratedValue>
                  <name>1000</name>
                  <description>Interrupt when logic 0.</description>
                  <value>#1000</value>
                </enumeratedValue>
                <enumeratedValue>
                  <name>1001</name>
                  <description>Interrupt on rising-edge.</description>
                  <value>#1001</value>
                </enumeratedValue>
                <enumeratedValue>
                  <name>1010</name>
                  <description>Interrupt on falling-edge.</description>
                  <value>#1010</value>
                </enumeratedValue>
                <enumeratedValue>
                  <name>1011</name>
                  <description>Interrupt on either edge.</description>
                  <value>#1011</value>
                </enumeratedValue>
                <enumeratedValue>
                  <name>1100</name>
                  <description>Interrupt when logic 1.</description>
                  <value>#1100</value>
                </enumeratedValue>
              </enumeratedValues>
            </field>
            <field>
              <name>ISF</name>
              <description>Interrupt Status Flag</description>
              <bitOffset>24</bitOffset>
              <bitWidth>1</bitWidth>
              <access>read-write</access>
              <enumeratedValues>
                <enumeratedValue>
                  <name>0</name>
                  <description>Configured interrupt is not detected.</description>
                  <value>#0</value>
                </enumeratedValue>
                <enumeratedValue>
                  <name>1</name>
                  <description>Configured interrupt is detected. If the pin is configured to generate a DMA request, then the corresponding flag will be cleared automatically at the completion of the requested DMA transfer. Otherwise, the flag remains set until a logic 1 is written to the flag. If the pin is configured for a level sensitive interrupt and the pin remains asserted, then the flag is set again immediately after it is cleared.</description>
                  <value>#1</value>
                </enumeratedValue>
              </enumeratedValues>
            </field>
          </fields>
        </register>
        <register>
          <name>PCR23</name>
          <description>Pin Control Register n</description>
          <addressOffset>0x5C</addressOffset>
          <size>32</size>
          <access>read-write</access>
          <resetValue>0</resetValue>
          <resetMask>0xFFFFFFFF</resetMask>
          <fields>
            <field>
              <name>PS</name>
              <description>Pull Select</description>
              <bitOffset>0</bitOffset>
              <bitWidth>1</bitWidth>
              <access>read-only</access>
              <enumeratedValues>
                <enumeratedValue>
                  <name>0</name>
                  <description>Internal pulldown resistor is enabled on the corresponding pin, if the corresponding PE field is set.</description>
                  <value>#0</value>
                </enumeratedValue>
                <enumeratedValue>
                  <name>1</name>
                  <description>Internal pullup resistor is enabled on the corresponding pin, if the corresponding PE field is set.</description>
                  <value>#1</value>
                </enumeratedValue>
              </enumeratedValues>
            </field>
            <field>
              <name>PE</name>
              <description>Pull Enable</description>
              <bitOffset>1</bitOffset>
              <bitWidth>1</bitWidth>
              <access>read-only</access>
              <enumeratedValues>
                <enumeratedValue>
                  <name>0</name>
                  <description>Internal pullup or pulldown resistor is not enabled on the corresponding pin.</description>
                  <value>#0</value>
                </enumeratedValue>
                <enumeratedValue>
                  <name>1</name>
                  <description>Internal pullup or pulldown resistor is enabled on the corresponding pin, if the pin is configured as a digital input.</description>
                  <value>#1</value>
                </enumeratedValue>
              </enumeratedValues>
            </field>
            <field>
              <name>SRE</name>
              <description>Slew Rate Enable</description>
              <bitOffset>2</bitOffset>
              <bitWidth>1</bitWidth>
              <access>read-only</access>
              <enumeratedValues>
                <enumeratedValue>
                  <name>0</name>
                  <description>Fast slew rate is configured on the corresponding pin, if the pin is configured as a digital output.</description>
                  <value>#0</value>
                </enumeratedValue>
                <enumeratedValue>
                  <name>1</name>
                  <description>Slow slew rate is configured on the corresponding pin, if the pin is configured as a digital output.</description>
                  <value>#1</value>
                </enumeratedValue>
              </enumeratedValues>
            </field>
            <field>
              <name>PFE</name>
              <description>Passive Filter Enable</description>
              <bitOffset>4</bitOffset>
              <bitWidth>1</bitWidth>
              <access>read-only</access>
              <enumeratedValues>
                <enumeratedValue>
                  <name>0</name>
                  <description>Passive input filter is disabled on the corresponding pin.</description>
                  <value>#0</value>
                </enumeratedValue>
                <enumeratedValue>
                  <name>1</name>
                  <description>Passive input filter is enabled on the corresponding pin, if the pin is configured as a digital input. Refer to the device data sheet for filter characteristics.</description>
                  <value>#1</value>
                </enumeratedValue>
              </enumeratedValues>
            </field>
            <field>
              <name>DSE</name>
              <description>Drive Strength Enable</description>
              <bitOffset>6</bitOffset>
              <bitWidth>1</bitWidth>
              <access>read-only</access>
              <enumeratedValues>
                <enumeratedValue>
                  <name>0</name>
                  <description>Low drive strength is configured on the corresponding pin, if pin is configured as a digital output.</description>
                  <value>#0</value>
                </enumeratedValue>
                <enumeratedValue>
                  <name>1</name>
                  <description>High drive strength is configured on the corresponding pin, if pin is configured as a digital output.</description>
                  <value>#1</value>
                </enumeratedValue>
              </enumeratedValues>
            </field>
            <field>
              <name>MUX</name>
              <description>Pin Mux Control</description>
              <bitOffset>8</bitOffset>
              <bitWidth>3</bitWidth>
              <access>read-write</access>
              <enumeratedValues>
                <enumeratedValue>
                  <name>000</name>
                  <description>Pin disabled (analog).</description>
                  <value>#000</value>
                </enumeratedValue>
                <enumeratedValue>
                  <name>001</name>
                  <description>Alternative 1 (GPIO).</description>
                  <value>#001</value>
                </enumeratedValue>
                <enumeratedValue>
                  <name>010</name>
                  <description>Alternative 2 (chip-specific).</description>
                  <value>#010</value>
                </enumeratedValue>
                <enumeratedValue>
                  <name>011</name>
                  <description>Alternative 3 (chip-specific).</description>
                  <value>#011</value>
                </enumeratedValue>
                <enumeratedValue>
                  <name>100</name>
                  <description>Alternative 4 (chip-specific).</description>
                  <value>#100</value>
                </enumeratedValue>
                <enumeratedValue>
                  <name>101</name>
                  <description>Alternative 5 (chip-specific).</description>
                  <value>#101</value>
                </enumeratedValue>
                <enumeratedValue>
                  <name>110</name>
                  <description>Alternative 6 (chip-specific).</description>
                  <value>#110</value>
                </enumeratedValue>
                <enumeratedValue>
                  <name>111</name>
                  <description>Alternative 7 (chip-specific).</description>
                  <value>#111</value>
                </enumeratedValue>
              </enumeratedValues>
            </field>
            <field>
              <name>IRQC</name>
              <description>Interrupt Configuration</description>
              <bitOffset>16</bitOffset>
              <bitWidth>4</bitWidth>
              <access>read-write</access>
              <enumeratedValues>
                <enumeratedValue>
                  <name>0000</name>
                  <description>Interrupt/DMA request disabled.</description>
                  <value>#0000</value>
                </enumeratedValue>
                <enumeratedValue>
                  <name>0001</name>
                  <description>DMA request on rising edge.</description>
                  <value>#0001</value>
                </enumeratedValue>
                <enumeratedValue>
                  <name>0010</name>
                  <description>DMA request on falling edge.</description>
                  <value>#0010</value>
                </enumeratedValue>
                <enumeratedValue>
                  <name>0011</name>
                  <description>DMA request on either edge.</description>
                  <value>#0011</value>
                </enumeratedValue>
                <enumeratedValue>
                  <name>1000</name>
                  <description>Interrupt when logic 0.</description>
                  <value>#1000</value>
                </enumeratedValue>
                <enumeratedValue>
                  <name>1001</name>
                  <description>Interrupt on rising-edge.</description>
                  <value>#1001</value>
                </enumeratedValue>
                <enumeratedValue>
                  <name>1010</name>
                  <description>Interrupt on falling-edge.</description>
                  <value>#1010</value>
                </enumeratedValue>
                <enumeratedValue>
                  <name>1011</name>
                  <description>Interrupt on either edge.</description>
                  <value>#1011</value>
                </enumeratedValue>
                <enumeratedValue>
                  <name>1100</name>
                  <description>Interrupt when logic 1.</description>
                  <value>#1100</value>
                </enumeratedValue>
              </enumeratedValues>
            </field>
            <field>
              <name>ISF</name>
              <description>Interrupt Status Flag</description>
              <bitOffset>24</bitOffset>
              <bitWidth>1</bitWidth>
              <access>read-write</access>
              <enumeratedValues>
                <enumeratedValue>
                  <name>0</name>
                  <description>Configured interrupt is not detected.</description>
                  <value>#0</value>
                </enumeratedValue>
                <enumeratedValue>
                  <name>1</name>
                  <description>Configured interrupt is detected. If the pin is configured to generate a DMA request, then the corresponding flag will be cleared automatically at the completion of the requested DMA transfer. Otherwise, the flag remains set until a logic 1 is written to the flag. If the pin is configured for a level sensitive interrupt and the pin remains asserted, then the flag is set again immediately after it is cleared.</description>
                  <value>#1</value>
                </enumeratedValue>
              </enumeratedValues>
            </field>
          </fields>
        </register>
        <register>
          <name>PCR24</name>
          <description>Pin Control Register n</description>
          <addressOffset>0x60</addressOffset>
          <size>32</size>
          <access>read-write</access>
          <resetValue>0</resetValue>
          <resetMask>0xFFFFFFFF</resetMask>
          <fields>
            <field>
              <name>PS</name>
              <description>Pull Select</description>
              <bitOffset>0</bitOffset>
              <bitWidth>1</bitWidth>
              <access>read-only</access>
              <enumeratedValues>
                <enumeratedValue>
                  <name>0</name>
                  <description>Internal pulldown resistor is enabled on the corresponding pin, if the corresponding PE field is set.</description>
                  <value>#0</value>
                </enumeratedValue>
                <enumeratedValue>
                  <name>1</name>
                  <description>Internal pullup resistor is enabled on the corresponding pin, if the corresponding PE field is set.</description>
                  <value>#1</value>
                </enumeratedValue>
              </enumeratedValues>
            </field>
            <field>
              <name>PE</name>
              <description>Pull Enable</description>
              <bitOffset>1</bitOffset>
              <bitWidth>1</bitWidth>
              <access>read-only</access>
              <enumeratedValues>
                <enumeratedValue>
                  <name>0</name>
                  <description>Internal pullup or pulldown resistor is not enabled on the corresponding pin.</description>
                  <value>#0</value>
                </enumeratedValue>
                <enumeratedValue>
                  <name>1</name>
                  <description>Internal pullup or pulldown resistor is enabled on the corresponding pin, if the pin is configured as a digital input.</description>
                  <value>#1</value>
                </enumeratedValue>
              </enumeratedValues>
            </field>
            <field>
              <name>SRE</name>
              <description>Slew Rate Enable</description>
              <bitOffset>2</bitOffset>
              <bitWidth>1</bitWidth>
              <access>read-only</access>
              <enumeratedValues>
                <enumeratedValue>
                  <name>0</name>
                  <description>Fast slew rate is configured on the corresponding pin, if the pin is configured as a digital output.</description>
                  <value>#0</value>
                </enumeratedValue>
                <enumeratedValue>
                  <name>1</name>
                  <description>Slow slew rate is configured on the corresponding pin, if the pin is configured as a digital output.</description>
                  <value>#1</value>
                </enumeratedValue>
              </enumeratedValues>
            </field>
            <field>
              <name>PFE</name>
              <description>Passive Filter Enable</description>
              <bitOffset>4</bitOffset>
              <bitWidth>1</bitWidth>
              <access>read-only</access>
              <enumeratedValues>
                <enumeratedValue>
                  <name>0</name>
                  <description>Passive input filter is disabled on the corresponding pin.</description>
                  <value>#0</value>
                </enumeratedValue>
                <enumeratedValue>
                  <name>1</name>
                  <description>Passive input filter is enabled on the corresponding pin, if the pin is configured as a digital input. Refer to the device data sheet for filter characteristics.</description>
                  <value>#1</value>
                </enumeratedValue>
              </enumeratedValues>
            </field>
            <field>
              <name>DSE</name>
              <description>Drive Strength Enable</description>
              <bitOffset>6</bitOffset>
              <bitWidth>1</bitWidth>
              <access>read-only</access>
              <enumeratedValues>
                <enumeratedValue>
                  <name>0</name>
                  <description>Low drive strength is configured on the corresponding pin, if pin is configured as a digital output.</description>
                  <value>#0</value>
                </enumeratedValue>
                <enumeratedValue>
                  <name>1</name>
                  <description>High drive strength is configured on the corresponding pin, if pin is configured as a digital output.</description>
                  <value>#1</value>
                </enumeratedValue>
              </enumeratedValues>
            </field>
            <field>
              <name>MUX</name>
              <description>Pin Mux Control</description>
              <bitOffset>8</bitOffset>
              <bitWidth>3</bitWidth>
              <access>read-write</access>
              <enumeratedValues>
                <enumeratedValue>
                  <name>000</name>
                  <description>Pin disabled (analog).</description>
                  <value>#000</value>
                </enumeratedValue>
                <enumeratedValue>
                  <name>001</name>
                  <description>Alternative 1 (GPIO).</description>
                  <value>#001</value>
                </enumeratedValue>
                <enumeratedValue>
                  <name>010</name>
                  <description>Alternative 2 (chip-specific).</description>
                  <value>#010</value>
                </enumeratedValue>
                <enumeratedValue>
                  <name>011</name>
                  <description>Alternative 3 (chip-specific).</description>
                  <value>#011</value>
                </enumeratedValue>
                <enumeratedValue>
                  <name>100</name>
                  <description>Alternative 4 (chip-specific).</description>
                  <value>#100</value>
                </enumeratedValue>
                <enumeratedValue>
                  <name>101</name>
                  <description>Alternative 5 (chip-specific).</description>
                  <value>#101</value>
                </enumeratedValue>
                <enumeratedValue>
                  <name>110</name>
                  <description>Alternative 6 (chip-specific).</description>
                  <value>#110</value>
                </enumeratedValue>
                <enumeratedValue>
                  <name>111</name>
                  <description>Alternative 7 (chip-specific).</description>
                  <value>#111</value>
                </enumeratedValue>
              </enumeratedValues>
            </field>
            <field>
              <name>IRQC</name>
              <description>Interrupt Configuration</description>
              <bitOffset>16</bitOffset>
              <bitWidth>4</bitWidth>
              <access>read-write</access>
              <enumeratedValues>
                <enumeratedValue>
                  <name>0000</name>
                  <description>Interrupt/DMA request disabled.</description>
                  <value>#0000</value>
                </enumeratedValue>
                <enumeratedValue>
                  <name>0001</name>
                  <description>DMA request on rising edge.</description>
                  <value>#0001</value>
                </enumeratedValue>
                <enumeratedValue>
                  <name>0010</name>
                  <description>DMA request on falling edge.</description>
                  <value>#0010</value>
                </enumeratedValue>
                <enumeratedValue>
                  <name>0011</name>
                  <description>DMA request on either edge.</description>
                  <value>#0011</value>
                </enumeratedValue>
                <enumeratedValue>
                  <name>1000</name>
                  <description>Interrupt when logic 0.</description>
                  <value>#1000</value>
                </enumeratedValue>
                <enumeratedValue>
                  <name>1001</name>
                  <description>Interrupt on rising-edge.</description>
                  <value>#1001</value>
                </enumeratedValue>
                <enumeratedValue>
                  <name>1010</name>
                  <description>Interrupt on falling-edge.</description>
                  <value>#1010</value>
                </enumeratedValue>
                <enumeratedValue>
                  <name>1011</name>
                  <description>Interrupt on either edge.</description>
                  <value>#1011</value>
                </enumeratedValue>
                <enumeratedValue>
                  <name>1100</name>
                  <description>Interrupt when logic 1.</description>
                  <value>#1100</value>
                </enumeratedValue>
              </enumeratedValues>
            </field>
            <field>
              <name>ISF</name>
              <description>Interrupt Status Flag</description>
              <bitOffset>24</bitOffset>
              <bitWidth>1</bitWidth>
              <access>read-write</access>
              <enumeratedValues>
                <enumeratedValue>
                  <name>0</name>
                  <description>Configured interrupt is not detected.</description>
                  <value>#0</value>
                </enumeratedValue>
                <enumeratedValue>
                  <name>1</name>
                  <description>Configured interrupt is detected. If the pin is configured to generate a DMA request, then the corresponding flag will be cleared automatically at the completion of the requested DMA transfer. Otherwise, the flag remains set until a logic 1 is written to the flag. If the pin is configured for a level sensitive interrupt and the pin remains asserted, then the flag is set again immediately after it is cleared.</description>
                  <value>#1</value>
                </enumeratedValue>
              </enumeratedValues>
            </field>
          </fields>
        </register>
        <register>
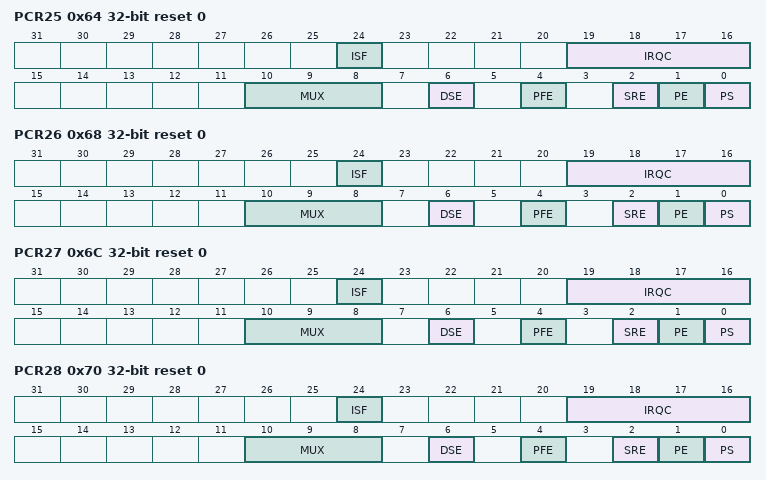
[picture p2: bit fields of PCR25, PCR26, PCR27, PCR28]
          <name>PCR25</name>
          <description>Pin Control Register n</description>
          <addressOffset>0x64</addressOffset>
          <size>32</size>
          <access>read-write</access>
          <resetValue>0</resetValue>
          <resetMask>0xFFFFFFFF</resetMask>
          <fields>
            <field>
              <name>PS</name>
              <description>Pull Select</description>
              <bitOffset>0</bitOffset>
              <bitWidth>1</bitWidth>
              <access>read-only</access>
              <enumeratedValues>
                <enumeratedValue>
                  <name>0</name>
                  <description>Internal pulldown resistor is enabled on the corresponding pin, if the corresponding PE field is set.</description>
                  <value>#0</value>
                </enumeratedValue>
                <enumeratedValue>
                  <name>1</name>
                  <description>Internal pullup resistor is enabled on the corresponding pin, if the corresponding PE field is set.</description>
                  <value>#1</value>
                </enumeratedValue>
              </enumeratedValues>
            </field>
            <field>
              <name>PE</name>
              <description>Pull Enable</description>
              <bitOffset>1</bitOffset>
              <bitWidth>1</bitWidth>
              <access>read-only</access>
              <enumeratedValues>
                <enumeratedValue>
                  <name>0</name>
                  <description>Internal pullup or pulldown resistor is not enabled on the corresponding pin.</description>
                  <value>#0</value>
                </enumeratedValue>
                <enumeratedValue>
                  <name>1</name>
                  <description>Internal pullup or pulldown resistor is enabled on the corresponding pin, if the pin is configured as a digital input.</description>
                  <value>#1</value>
                </enumeratedValue>
              </enumeratedValues>
            </field>
            <field>
              <name>SRE</name>
              <description>Slew Rate Enable</description>
              <bitOffset>2</bitOffset>
              <bitWidth>1</bitWidth>
              <access>read-only</access>
              <enumeratedValues>
                <enumeratedValue>
                  <name>0</name>
                  <description>Fast slew rate is configured on the corresponding pin, if the pin is configured as a digital output.</description>
                  <value>#0</value>
                </enumeratedValue>
                <enumeratedValue>
                  <name>1</name>
                  <description>Slow slew rate is configured on the corresponding pin, if the pin is configured as a digital output.</description>
                  <value>#1</value>
                </enumeratedValue>
              </enumeratedValues>
            </field>
            <field>
              <name>PFE</name>
              <description>Passive Filter Enable</description>
              <bitOffset>4</bitOffset>
              <bitWidth>1</bitWidth>
              <access>read-only</access>
              <enumeratedValues>
                <enumeratedValue>
                  <name>0</name>
                  <description>Passive input filter is disabled on the corresponding pin.</description>
                  <value>#0</value>
                </enumeratedValue>
                <enumeratedValue>
                  <name>1</name>
                  <description>Passive input filter is enabled on the corresponding pin, if the pin is configured as a digital input. Refer to the device data sheet for filter characteristics.</description>
                  <value>#1</value>
                </enumeratedValue>
              </enumeratedValues>
            </field>
            <field>
              <name>DSE</name>
              <description>Drive Strength Enable</description>
              <bitOffset>6</bitOffset>
              <bitWidth>1</bitWidth>
              <access>read-only</access>
              <enumeratedValues>
                <enumeratedValue>
                  <name>0</name>
                  <description>Low drive strength is configured on the corresponding pin, if pin is configured as a digital output.</description>
                  <value>#0</value>
                </enumeratedValue>
                <enumeratedValue>
                  <name>1</name>
                  <description>High drive strength is configured on the corresponding pin, if pin is configured as a digital output.</description>
                  <value>#1</value>
                </enumeratedValue>
              </enumeratedValues>
            </field>
            <field>
              <name>MUX</name>
              <description>Pin Mux Control</description>
              <bitOffset>8</bitOffset>
              <bitWidth>3</bitWidth>
              <access>read-write</access>
              <enumeratedValues>
                <enumeratedValue>
                  <name>000</name>
                  <description>Pin disabled (analog).</description>
                  <value>#000</value>
                </enumeratedValue>
                <enumeratedValue>
                  <name>001</name>
                  <description>Alternative 1 (GPIO).</description>
                  <value>#001</value>
                </enumeratedValue>
                <enumeratedValue>
                  <name>010</name>
                  <description>Alternative 2 (chip-specific).</description>
                  <value>#010</value>
                </enumeratedValue>
                <enumeratedValue>
                  <name>011</name>
                  <description>Alternative 3 (chip-specific).</description>
                  <value>#011</value>
                </enumeratedValue>
                <enumeratedValue>
                  <name>100</name>
                  <description>Alternative 4 (chip-specific).</description>
                  <value>#100</value>
                </enumeratedValue>
                <enumeratedValue>
                  <name>101</name>
                  <description>Alternative 5 (chip-specific).</description>
                  <value>#101</value>
                </enumeratedValue>
                <enumeratedValue>
                  <name>110</name>
                  <description>Alternative 6 (chip-specific).</description>
                  <value>#110</value>
                </enumeratedValue>
                <enumeratedValue>
                  <name>111</name>
                  <description>Alternative 7 (chip-specific).</description>
                  <value>#111</value>
                </enumeratedValue>
              </enumeratedValues>
            </field>
            <field>
              <name>IRQC</name>
              <description>Interrupt Configuration</description>
              <bitOffset>16</bitOffset>
              <bitWidth>4</bitWidth>
              <access>read-write</access>
              <enumeratedValues>
                <enumeratedValue>
                  <name>0000</name>
                  <description>Interrupt/DMA request disabled.</description>
                  <value>#0000</value>
                </enumeratedValue>
                <enumeratedValue>
                  <name>0001</name>
                  <description>DMA request on rising edge.</description>
                  <value>#0001</value>
                </enumeratedValue>
                <enumeratedValue>
                  <name>0010</name>
                  <description>DMA request on falling edge.</description>
                  <value>#0010</value>
                </enumeratedValue>
                <enumeratedValue>
                  <name>0011</name>
                  <description>DMA request on either edge.</description>
                  <value>#0011</value>
                </enumeratedValue>
                <enumeratedValue>
                  <name>1000</name>
                  <description>Interrupt when logic 0.</description>
                  <value>#1000</value>
                </enumeratedValue>
                <enumeratedValue>
                  <name>1001</name>
                  <description>Interrupt on rising-edge.</description>
                  <value>#1001</value>
                </enumeratedValue>
                <enumeratedValue>
                  <name>1010</name>
                  <description>Interrupt on falling-edge.</description>
                  <value>#1010</value>
                </enumeratedValue>
                <enumeratedValue>
                  <name>1011</name>
                  <description>Interrupt on either edge.</description>
                  <value>#1011</value>
                </enumeratedValue>
                <enumeratedValue>
                  <name>1100</name>
                  <description>Interrupt when logic 1.</description>
                  <value>#1100</value>
                </enumeratedValue>
              </enumeratedValues>
            </field>
            <field>
              <name>ISF</name>
              <description>Interrupt Status Flag</description>
              <bitOffset>24</bitOffset>
              <bitWidth>1</bitWidth>
              <access>read-write</access>
              <enumeratedValues>
                <enumeratedValue>
                  <name>0</name>
                  <description>Configured interrupt is not detected.</description>
                  <value>#0</value>
                </enumeratedValue>
                <enumeratedValue>
                  <name>1</name>
                  <description>Configured interrupt is detected. If the pin is configured to generate a DMA request, then the corresponding flag will be cleared automatically at the completion of the requested DMA transfer. Otherwise, the flag remains set until a logic 1 is written to the flag. If the pin is configured for a level sensitive interrupt and the pin remains asserted, then the flag is set again immediately after it is cleared.</description>
                  <value>#1</value>
                </enumeratedValue>
              </enumeratedValues>
            </field>
          </fields>
        </register>
        <register>
          <name>PCR26</name>
          <description>Pin Control Register n</description>
          <addressOffset>0x68</addressOffset>
          <size>32</size>
          <access>read-write</access>
          <resetValue>0</resetValue>
          <resetMask>0xFFFFFFFF</resetMask>
          <fields>
            <field>
              <name>PS</name>
              <description>Pull Select</description>
              <bitOffset>0</bitOffset>
              <bitWidth>1</bitWidth>
              <access>read-only</access>
              <enumeratedValues>
                <enumeratedValue>
                  <name>0</name>
                  <description>Internal pulldown resistor is enabled on the corresponding pin, if the corresponding PE field is set.</description>
                  <value>#0</value>
                </enumeratedValue>
                <enumeratedValue>
                  <name>1</name>
                  <description>Internal pullup resistor is enabled on the corresponding pin, if the corresponding PE field is set.</description>
                  <value>#1</value>
                </enumeratedValue>
              </enumeratedValues>
            </field>
            <field>
              <name>PE</name>
              <description>Pull Enable</description>
              <bitOffset>1</bitOffset>
              <bitWidth>1</bitWidth>
              <access>read-only</access>
              <enumeratedValues>
                <enumeratedValue>
                  <name>0</name>
                  <description>Internal pullup or pulldown resistor is not enabled on the corresponding pin.</description>
                  <value>#0</value>
                </enumeratedValue>
                <enumeratedValue>
                  <name>1</name>
                  <description>Internal pullup or pulldown resistor is enabled on the corresponding pin, if the pin is configured as a digital input.</description>
                  <value>#1</value>
                </enumeratedValue>
              </enumeratedValues>
            </field>
            <field>
              <name>SRE</name>
              <description>Slew Rate Enable</description>
              <bitOffset>2</bitOffset>
              <bitWidth>1</bitWidth>
              <access>read-only</access>
              <enumeratedValues>
                <enumeratedValue>
                  <name>0</name>
                  <description>Fast slew rate is configured on the corresponding pin, if the pin is configured as a digital output.</description>
                  <value>#0</value>
                </enumeratedValue>
                <enumeratedValue>
                  <name>1</name>
                  <description>Slow slew rate is configured on the corresponding pin, if the pin is configured as a digital output.</description>
                  <value>#1</value>
                </enumeratedValue>
              </enumeratedValues>
            </field>
            <field>
              <name>PFE</name>
              <description>Passive Filter Enable</description>
              <bitOffset>4</bitOffset>
              <bitWidth>1</bitWidth>
              <access>read-only</access>
              <enumeratedValues>
                <enumeratedValue>
                  <name>0</name>
                  <description>Passive input filter is disabled on the corresponding pin.</description>
                  <value>#0</value>
                </enumeratedValue>
                <enumeratedValue>
                  <name>1</name>
                  <description>Passive input filter is enabled on the corresponding pin, if the pin is configured as a digital input. Refer to the device data sheet for filter characteristics.</description>
                  <value>#1</value>
                </enumeratedValue>
              </enumeratedValues>
            </field>
            <field>
              <name>DSE</name>
              <description>Drive Strength Enable</description>
              <bitOffset>6</bitOffset>
              <bitWidth>1</bitWidth>
              <access>read-only</access>
              <enumeratedValues>
                <enumeratedValue>
                  <name>0</name>
                  <description>Low drive strength is configured on the corresponding pin, if pin is configured as a digital output.</description>
                  <value>#0</value>
                </enumeratedValue>
                <enumeratedValue>
                  <name>1</name>
                  <description>High drive strength is configured on the corresponding pin, if pin is configured as a digital output.</description>
                  <value>#1</value>
                </enumeratedValue>
              </enumeratedValues>
            </field>
            <field>
              <name>MUX</name>
              <description>Pin Mux Control</description>
              <bitOffset>8</bitOffset>
              <bitWidth>3</bitWidth>
              <access>read-write</access>
              <enumeratedValues>
                <enumeratedValue>
                  <name>000</name>
                  <description>Pin disabled (analog).</description>
                  <value>#000</value>
                </enumeratedValue>
                <enumeratedValue>
                  <name>001</name>
                  <description>Alternative 1 (GPIO).</description>
                  <value>#001</value>
                </enumeratedValue>
                <enumeratedValue>
                  <name>010</name>
                  <description>Alternative 2 (chip-specific).</description>
                  <value>#010</value>
                </enumeratedValue>
                <enumeratedValue>
                  <name>011</name>
                  <description>Alternative 3 (chip-specific).</description>
                  <value>#011</value>
                </enumeratedValue>
                <enumeratedValue>
                  <name>100</name>
                  <description>Alternative 4 (chip-specific).</description>
                  <value>#100</value>
                </enumeratedValue>
                <enumeratedValue>
                  <name>101</name>
                  <description>Alternative 5 (chip-specific).</description>
                  <value>#101</value>
                </enumeratedValue>
                <enumeratedValue>
                  <name>110</name>
                  <description>Alternative 6 (chip-specific).</description>
                  <value>#110</value>
                </enumeratedValue>
                <enumeratedValue>
                  <name>111</name>
                  <description>Alternative 7 (chip-specific).</description>
                  <value>#111</value>
                </enumeratedValue>
              </enumeratedValues>
            </field>
            <field>
              <name>IRQC</name>
              <description>Interrupt Configuration</description>
              <bitOffset>16</bitOffset>
              <bitWidth>4</bitWidth>
              <access>read-write</access>
              <enumeratedValues>
                <enumeratedValue>
                  <name>0000</name>
                  <description>Interrupt/DMA request disabled.</description>
                  <value>#0000</value>
                </enumeratedValue>
                <enumeratedValue>
                  <name>0001</name>
                  <description>DMA request on rising edge.</description>
                  <value>#0001</value>
                </enumeratedValue>
                <enumeratedValue>
                  <name>0010</name>
                  <description>DMA request on falling edge.</description>
                  <value>#0010</value>
                </enumeratedValue>
                <enumeratedValue>
                  <name>0011</name>
                  <description>DMA request on either edge.</description>
                  <value>#0011</value>
                </enumeratedValue>
                <enumeratedValue>
                  <name>1000</name>
                  <description>Interrupt when logic 0.</description>
                  <value>#1000</value>
                </enumeratedValue>
                <enumeratedValue>
                  <name>1001</name>
                  <description>Interrupt on rising-edge.</description>
                  <value>#1001</value>
                </enumeratedValue>
                <enumeratedValue>
                  <name>1010</name>
                  <description>Interrupt on falling-edge.</description>
                  <value>#1010</value>
                </enumeratedValue>
                <enumeratedValue>
                  <name>1011</name>
                  <description>Interrupt on either edge.</description>
                  <value>#1011</value>
                </enumeratedValue>
                <enumeratedValue>
                  <name>1100</name>
                  <description>Interrupt when logic 1.</description>
                  <value>#1100</value>
                </enumeratedValue>
              </enumeratedValues>
            </field>
            <field>
              <name>ISF</name>
              <description>Interrupt Status Flag</description>
              <bitOffset>24</bitOffset>
              <bitWidth>1</bitWidth>
              <access>read-write</access>
              <enumeratedValues>
                <enumeratedValue>
                  <name>0</name>
                  <description>Configured interrupt is not detected.</description>
                  <value>#0</value>
                </enumeratedValue>
                <enumeratedValue>
                  <name>1</name>
                  <description>Configured interrupt is detected. If the pin is configured to generate a DMA request, then the corresponding flag will be cleared automatically at the completion of the requested DMA transfer. Otherwise, the flag remains set until a logic 1 is written to the flag. If the pin is configured for a level sensitive interrupt and the pin remains asserted, then the flag is set again immediately after it is cleared.</description>
                  <value>#1</value>
                </enumeratedValue>
              </enumeratedValues>
            </field>
          </fields>
        </register>
        <register>
          <name>PCR27</name>
          <description>Pin Control Register n</description>
          <addressOffset>0x6C</addressOffset>
          <size>32</size>
          <access>read-write</access>
          <resetValue>0</resetValue>
          <resetMask>0xFFFFFFFF</resetMask>
          <fields>
            <field>
              <name>PS</name>
              <description>Pull Select</description>
              <bitOffset>0</bitOffset>
              <bitWidth>1</bitWidth>
              <access>read-only</access>
              <enumeratedValues>
                <enumeratedValue>
                  <name>0</name>
                  <description>Internal pulldown resistor is enabled on the corresponding pin, if the corresponding PE field is set.</description>
                  <value>#0</value>
                </enumeratedValue>
                <enumeratedValue>
                  <name>1</name>
                  <description>Internal pullup resistor is enabled on the corresponding pin, if the corresponding PE field is set.</description>
                  <value>#1</value>
                </enumeratedValue>
              </enumeratedValues>
            </field>
            <field>
              <name>PE</name>
              <description>Pull Enable</description>
              <bitOffset>1</bitOffset>
              <bitWidth>1</bitWidth>
              <access>read-only</access>
              <enumeratedValues>
                <enumeratedValue>
                  <name>0</name>
                  <description>Internal pullup or pulldown resistor is not enabled on the corresponding pin.</description>
                  <value>#0</value>
                </enumeratedValue>
                <enumeratedValue>
                  <name>1</name>
                  <description>Internal pullup or pulldown resistor is enabled on the corresponding pin, if the pin is configured as a digital input.</description>
                  <value>#1</value>
                </enumeratedValue>
              </enumeratedValues>
            </field>
            <field>
              <name>SRE</name>
              <description>Slew Rate Enable</description>
              <bitOffset>2</bitOffset>
              <bitWidth>1</bitWidth>
              <access>read-only</access>
              <enumeratedValues>
                <enumeratedValue>
                  <name>0</name>
                  <description>Fast slew rate is configured on the corresponding pin, if the pin is configured as a digital output.</description>
                  <value>#0</value>
                </enumeratedValue>
                <enumeratedValue>
                  <name>1</name>
                  <description>Slow slew rate is configured on the corresponding pin, if the pin is configured as a digital output.</description>
                  <value>#1</value>
                </enumeratedValue>
              </enumeratedValues>
            </field>
            <field>
              <name>PFE</name>
              <description>Passive Filter Enable</description>
              <bitOffset>4</bitOffset>
              <bitWidth>1</bitWidth>
              <access>read-only</access>
              <enumeratedValues>
                <enumeratedValue>
                  <name>0</name>
                  <description>Passive input filter is disabled on the corresponding pin.</description>
                  <value>#0</value>
                </enumeratedValue>
                <enumeratedValue>
                  <name>1</name>
                  <description>Passive input filter is enabled on the corresponding pin, if the pin is configured as a digital input. Refer to the device data sheet for filter characteristics.</description>
                  <value>#1</value>
                </enumeratedValue>
              </enumeratedValues>
            </field>
            <field>
              <name>DSE</name>
              <description>Drive Strength Enable</description>
              <bitOffset>6</bitOffset>
              <bitWidth>1</bitWidth>
              <access>read-only</access>
              <enumeratedValues>
                <enumeratedValue>
                  <name>0</name>
                  <description>Low drive strength is configured on the corresponding pin, if pin is configured as a digital output.</description>
                  <value>#0</value>
                </enumeratedValue>
                <enumeratedValue>
                  <name>1</name>
                  <description>High drive strength is configured on the corresponding pin, if pin is configured as a digital output.</description>
                  <value>#1</value>
                </enumeratedValue>
              </enumeratedValues>
            </field>
            <field>
              <name>MUX</name>
              <description>Pin Mux Control</description>
              <bitOffset>8</bitOffset>
              <bitWidth>3</bitWidth>
              <access>read-write</access>
              <enumeratedValues>
                <enumeratedValue>
                  <name>000</name>
                  <description>Pin disabled (analog).</description>
                  <value>#000</value>
                </enumeratedValue>
                <enumeratedValue>
                  <name>001</name>
                  <description>Alternative 1 (GPIO).</description>
                  <value>#001</value>
                </enumeratedValue>
                <enumeratedValue>
                  <name>010</name>
                  <description>Alternative 2 (chip-specific).</description>
                  <value>#010</value>
                </enumeratedValue>
                <enumeratedValue>
                  <name>011</name>
                  <description>Alternative 3 (chip-specific).</description>
                  <value>#011</value>
                </enumeratedValue>
                <enumeratedValue>
                  <name>100</name>
                  <description>Alternative 4 (chip-specific).</description>
                  <value>#100</value>
                </enumeratedValue>
                <enumeratedValue>
                  <name>101</name>
                  <description>Alternative 5 (chip-specific).</description>
                  <value>#101</value>
                </enumeratedValue>
                <enumeratedValue>
                  <name>110</name>
                  <description>Alternative 6 (chip-specific).</description>
                  <value>#110</value>
                </enumeratedValue>
                <enumeratedValue>
                  <name>111</name>
                  <description>Alternative 7 (chip-specific).</description>
                  <value>#111</value>
                </enumeratedValue>
              </enumeratedValues>
            </field>
            <field>
              <name>IRQC</name>
              <description>Interrupt Configuration</description>
              <bitOffset>16</bitOffset>
              <bitWidth>4</bitWidth>
              <access>read-write</access>
              <enumeratedValues>
                <enumeratedValue>
                  <name>0000</name>
                  <description>Interrupt/DMA request disabled.</description>
                  <value>#0000</value>
                </enumeratedValue>
                <enumeratedValue>
                  <name>0001</name>
                  <description>DMA request on rising edge.</description>
                  <value>#0001</value>
                </enumeratedValue>
                <enumeratedValue>
                  <name>0010</name>
                  <description>DMA request on falling edge.</description>
                  <value>#0010</value>
                </enumeratedValue>
                <enumeratedValue>
                  <name>0011</name>
                  <description>DMA request on either edge.</description>
                  <value>#0011</value>
                </enumeratedValue>
                <enumeratedValue>
                  <name>1000</name>
                  <description>Interrupt when logic 0.</description>
                  <value>#1000</value>
                </enumeratedValue>
                <enumeratedValue>
                  <name>1001</name>
                  <description>Interrupt on rising-edge.</description>
                  <value>#1001</value>
                </enumeratedValue>
                <enumeratedValue>
                  <name>1010</name>
                  <description>Interrupt on falling-edge.</description>
                  <value>#1010</value>
                </enumeratedValue>
                <enumeratedValue>
                  <name>1011</name>
                  <description>Interrupt on either edge.</description>
                  <value>#1011</value>
                </enumeratedValue>
                <enumeratedValue>
                  <name>1100</name>
                  <description>Interrupt when logic 1.</description>
                  <value>#1100</value>
                </enumeratedValue>
              </enumeratedValues>
            </field>
            <field>
              <name>ISF</name>
              <description>Interrupt Status Flag</description>
              <bitOffset>24</bitOffset>
              <bitWidth>1</bitWidth>
              <access>read-write</access>
              <enumeratedValues>
                <enumeratedValue>
                  <name>0</name>
                  <description>Configured interrupt is not detected.</description>
                  <value>#0</value>
                </enumeratedValue>
                <enumeratedValue>
                  <name>1</name>
                  <description>Configured interrupt is detected. If the pin is configured to generate a DMA request, then the corresponding flag will be cleared automatically at the completion of the requested DMA transfer. Otherwise, the flag remains set until a logic 1 is written to the flag. If the pin is configured for a level sensitive interrupt and the pin remains asserted, then the flag is set again immediately after it is cleared.</description>
                  <value>#1</value>
                </enumeratedValue>
              </enumeratedValues>
            </field>
          </fields>
        </register>
        <register>
          <name>PCR28</name>
          <description>Pin Control Register n</description>
          <addressOffset>0x70</addressOffset>
          <size>32</size>
          <access>read-write</access>
          <resetValue>0</resetValue>
          <resetMask>0xFFFFFFFF</resetMask>
          <fields>
            <field>
              <name>PS</name>
              <description>Pull Select</description>
              <bitOffset>0</bitOffset>
              <bitWidth>1</bitWidth>
              <access>read-only</access>
              <enumeratedValues>
                <enumeratedValue>
                  <name>0</name>
                  <description>Internal pulldown resistor is enabled on the corresponding pin, if the corresponding PE field is set.</description>
                  <value>#0</value>
                </enumeratedValue>
                <enumeratedValue>
                  <name>1</name>
                  <description>Internal pullup resistor is enabled on the corresponding pin, if the corresponding PE field is set.</description>
                  <value>#1</value>
                </enumeratedValue>
              </enumeratedValues>
            </field>
            <field>
              <name>PE</name>
              <description>Pull Enable</description>
              <bitOffset>1</bitOffset>
              <bitWidth>1</bitWidth>
              <access>read-only</access>
              <enumeratedValues>
                <enumeratedValue>
                  <name>0</name>
                  <description>Internal pullup or pulldown resistor is not enabled on the corresponding pin.</description>
                  <value>#0</value>
                </enumeratedValue>
                <enumeratedValue>
                  <name>1</name>
                  <description>Internal pullup or pulldown resistor is enabled on the corresponding pin, if the pin is configured as a digital input.</description>
                  <value>#1</value>
                </enumeratedValue>
              </enumeratedValues>
            </field>
            <field>
              <name>SRE</name>
              <description>Slew Rate Enable</description>
              <bitOffset>2</bitOffset>
              <bitWidth>1</bitWidth>
              <access>read-only</access>
              <enumeratedValues>
                <enumeratedValue>
                  <name>0</name>
                  <description>Fast slew rate is configured on the corresponding pin, if the pin is configured as a digital output.</description>
                  <value>#0</value>
                </enumeratedValue>
                <enumeratedValue>
                  <name>1</name>
                  <description>Slow slew rate is configured on the corresponding pin, if the pin is configured as a digital output.</description>
                  <value>#1</value>
                </enumeratedValue>
              </enumeratedValues>
            </field>
            <field>
              <name>PFE</name>
              <description>Passive Filter Enable</description>
              <bitOffset>4</bitOffset>
              <bitWidth>1</bitWidth>
              <access>read-only</access>
              <enumeratedValues>
                <enumeratedValue>
                  <name>0</name>
                  <description>Passive input filter is disabled on the corresponding pin.</description>
                  <value>#0</value>
                </enumeratedValue>
                <enumeratedValue>
                  <name>1</name>
                  <description>Passive input filter is enabled on the corresponding pin, if the pin is configured as a digital input. Refer to the device data sheet for filter characteristics.</description>
                  <value>#1</value>
                </enumeratedValue>
              </enumeratedValues>
            </field>
            <field>
              <name>DSE</name>
              <description>Drive Strength Enable</description>
              <bitOffset>6</bitOffset>
              <bitWidth>1</bitWidth>
              <access>read-only</access>
              <enumeratedValues>
                <enumeratedValue>
                  <name>0</name>
                  <description>Low drive strength is configured on the corresponding pin, if pin is configured as a digital output.</description>
                  <value>#0</value>
                </enumeratedValue>
                <enumeratedValue>
                  <name>1</name>
                  <description>High drive strength is configured on the corresponding pin, if pin is configured as a digital output.</description>
                  <value>#1</value>
                </enumeratedValue>
              </enumeratedValues>
            </field>
            <field>
              <name>MUX</name>
              <description>Pin Mux Control</description>
              <bitOffset>8</bitOffset>
              <bitWidth>3</bitWidth>
              <access>read-write</access>
              <enumeratedValues>
                <enumeratedValue>
                  <name>000</name>
                  <description>Pin disabled (analog).</description>
                  <value>#000</value>
                </enumeratedValue>
                <enumeratedValue>
                  <name>001</name>
                  <description>Alternative 1 (GPIO).</description>
                  <value>#001</value>
                </enumeratedValue>
                <enumeratedValue>
                  <name>010</name>
                  <description>Alternative 2 (chip-specific).</description>
                  <value>#010</value>
                </enumeratedValue>
                <enumeratedValue>
                  <name>011</name>
                  <description>Alternative 3 (chip-specific).</description>
                  <value>#011</value>
                </enumeratedValue>
                <enumeratedValue>
                  <name>100</name>
                  <description>Alternative 4 (chip-specific).</description>
                  <value>#100</value>
                </enumeratedValue>
                <enumeratedValue>
                  <name>101</name>
                  <description>Alternative 5 (chip-specific).</description>
                  <value>#101</value>
                </enumeratedValue>
                <enumeratedValue>
                  <name>110</name>
                  <description>Alternative 6 (chip-specific).</description>
                  <value>#110</value>
                </enumeratedValue>
                <enumeratedValue>
                  <name>111</name>
                  <description>Alternative 7 (chip-specific).</description>
                  <value>#111</value>
                </enumeratedValue>
              </enumeratedValues>
            </field>
            <field>
              <name>IRQC</name>
              <description>Interrupt Configuration</description>
              <bitOffset>16</bitOffset>
              <bitWidth>4</bitWidth>
              <access>read-write</access>
              <enumeratedValues>
                <enumeratedValue>
                  <name>0000</name>
                  <description>Interrupt/DMA request disabled.</description>
                  <value>#0000</value>
                </enumeratedValue>
                <enumeratedValue>
                  <name>0001</name>
                  <description>DMA request on rising edge.</description>
                  <value>#0001</value>
                </enumeratedValue>
                <enumeratedValue>
                  <name>0010</name>
                  <description>DMA request on falling edge.</description>
                  <value>#0010</value>
                </enumeratedValue>
                <enumeratedValue>
                  <name>0011</name>
                  <description>DMA request on either edge.</description>
                  <value>#0011</value>
                </enumeratedValue>
                <enumeratedValue>
                  <name>1000</name>
                  <description>Interrupt when logic 0.</description>
                  <value>#1000</value>
                </enumeratedValue>
                <enumeratedValue>
                  <name>1001</name>
                  <description>Interrupt on rising-edge.</description>
                  <value>#1001</value>
                </enumeratedValue>
                <enumeratedValue>
                  <name>1010</name>
                  <description>Interrupt on falling-edge.</description>
                  <value>#1010</value>
                </enumeratedValue>
                <enumeratedValue>
                  <name>1011</name>
                  <description>Interrupt on either edge.</description>
                  <value>#1011</value>
                </enumeratedValue>
                <enumeratedValue>
                  <name>1100</name>
                  <description>Interrupt when logic 1.</description>
                  <value>#1100</value>
                </enumeratedValue>
              </enumeratedValues>
            </field>
            <field>
              <name>ISF</name>
              <description>Interrupt Status Flag</description>
              <bitOffset>24</bitOffset>
              <bitWidth>1</bitWidth>
              <access>read-write</access>
              <enumeratedValues>
                <enumeratedValue>
                  <name>0</name>
                  <description>Configured interrupt is not detected.</description>
                  <value>#0</value>
                </enumeratedValue>
                <enumeratedValue>
                  <name>1</name>
                  <description>Configured interrupt is detected. If the pin is configured to generate a DMA request, then the corresponding flag will be cleared automatically at the completion of the requested DMA transfer. Otherwise, the flag remains set until a logic 1 is written to the flag. If the pin is configured for a level sensitive interrupt and the pin remains asserted, then the flag is set again immediately after it is cleared.</description>
                  <value>#1</value>
                </enumeratedValue>
              </enumeratedValues>
            </field>
          </fields>
        </register>
        <register>
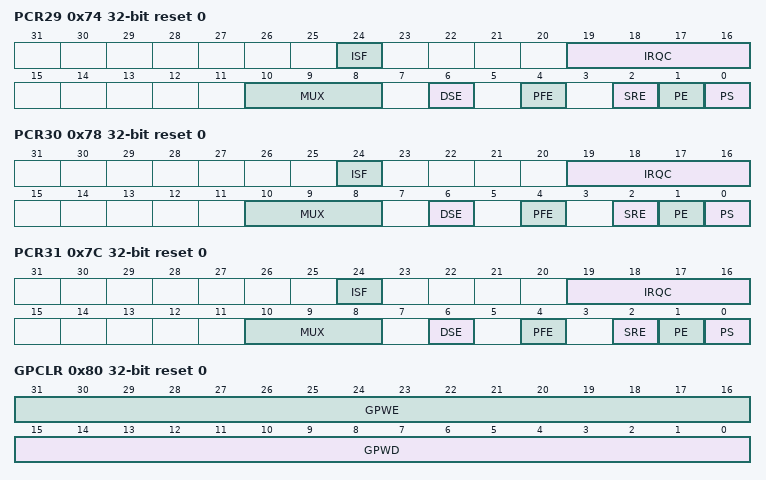
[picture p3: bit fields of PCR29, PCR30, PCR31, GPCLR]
          <name>PCR29</name>
          <description>Pin Control Register n</description>
          <addressOffset>0x74</addressOffset>
          <size>32</size>
          <access>read-write</access>
          <resetValue>0</resetValue>
          <resetMask>0xFFFFFFFF</resetMask>
          <fields>
            <field>
              <name>PS</name>
              <description>Pull Select</description>
              <bitOffset>0</bitOffset>
              <bitWidth>1</bitWidth>
              <access>read-only</access>
              <enumeratedValues>
                <enumeratedValue>
                  <name>0</name>
                  <description>Internal pulldown resistor is enabled on the corresponding pin, if the corresponding PE field is set.</description>
                  <value>#0</value>
                </enumeratedValue>
                <enumeratedValue>
                  <name>1</name>
                  <description>Internal pullup resistor is enabled on the corresponding pin, if the corresponding PE field is set.</description>
                  <value>#1</value>
                </enumeratedValue>
              </enumeratedValues>
            </field>
            <field>
              <name>PE</name>
              <description>Pull Enable</description>
              <bitOffset>1</bitOffset>
              <bitWidth>1</bitWidth>
              <access>read-only</access>
              <enumeratedValues>
                <enumeratedValue>
                  <name>0</name>
                  <description>Internal pullup or pulldown resistor is not enabled on the corresponding pin.</description>
                  <value>#0</value>
                </enumeratedValue>
                <enumeratedValue>
                  <name>1</name>
                  <description>Internal pullup or pulldown resistor is enabled on the corresponding pin, if the pin is configured as a digital input.</description>
                  <value>#1</value>
                </enumeratedValue>
              </enumeratedValues>
            </field>
            <field>
              <name>SRE</name>
              <description>Slew Rate Enable</description>
              <bitOffset>2</bitOffset>
              <bitWidth>1</bitWidth>
              <access>read-only</access>
              <enumeratedValues>
                <enumeratedValue>
                  <name>0</name>
                  <description>Fast slew rate is configured on the corresponding pin, if the pin is configured as a digital output.</description>
                  <value>#0</value>
                </enumeratedValue>
                <enumeratedValue>
                  <name>1</name>
                  <description>Slow slew rate is configured on the corresponding pin, if the pin is configured as a digital output.</description>
                  <value>#1</value>
                </enumeratedValue>
              </enumeratedValues>
            </field>
            <field>
              <name>PFE</name>
              <description>Passive Filter Enable</description>
              <bitOffset>4</bitOffset>
              <bitWidth>1</bitWidth>
              <access>read-only</access>
              <enumeratedValues>
                <enumeratedValue>
                  <name>0</name>
                  <description>Passive input filter is disabled on the corresponding pin.</description>
                  <value>#0</value>
                </enumeratedValue>
                <enumeratedValue>
                  <name>1</name>
                  <description>Passive input filter is enabled on the corresponding pin, if the pin is configured as a digital input. Refer to the device data sheet for filter characteristics.</description>
                  <value>#1</value>
                </enumeratedValue>
              </enumeratedValues>
            </field>
            <field>
              <name>DSE</name>
              <description>Drive Strength Enable</description>
              <bitOffset>6</bitOffset>
              <bitWidth>1</bitWidth>
              <access>read-only</access>
              <enumeratedValues>
                <enumeratedValue>
                  <name>0</name>
                  <description>Low drive strength is configured on the corresponding pin, if pin is configured as a digital output.</description>
                  <value>#0</value>
                </enumeratedValue>
                <enumeratedValue>
                  <name>1</name>
                  <description>High drive strength is configured on the corresponding pin, if pin is configured as a digital output.</description>
                  <value>#1</value>
                </enumeratedValue>
              </enumeratedValues>
            </field>
            <field>
              <name>MUX</name>
              <description>Pin Mux Control</description>
              <bitOffset>8</bitOffset>
              <bitWidth>3</bitWidth>
              <access>read-write</access>
              <enumeratedValues>
                <enumeratedValue>
                  <name>000</name>
                  <description>Pin disabled (analog).</description>
                  <value>#000</value>
                </enumeratedValue>
                <enumeratedValue>
                  <name>001</name>
                  <description>Alternative 1 (GPIO).</description>
                  <value>#001</value>
                </enumeratedValue>
                <enumeratedValue>
                  <name>010</name>
                  <description>Alternative 2 (chip-specific).</description>
                  <value>#010</value>
                </enumeratedValue>
                <enumeratedValue>
                  <name>011</name>
                  <description>Alternative 3 (chip-specific).</description>
                  <value>#011</value>
                </enumeratedValue>
                <enumeratedValue>
                  <name>100</name>
                  <description>Alternative 4 (chip-specific).</description>
                  <value>#100</value>
                </enumeratedValue>
                <enumeratedValue>
                  <name>101</name>
                  <description>Alternative 5 (chip-specific).</description>
                  <value>#101</value>
                </enumeratedValue>
                <enumeratedValue>
                  <name>110</name>
                  <description>Alternative 6 (chip-specific).</description>
                  <value>#110</value>
                </enumeratedValue>
                <enumeratedValue>
                  <name>111</name>
                  <description>Alternative 7 (chip-specific).</description>
                  <value>#111</value>
                </enumeratedValue>
              </enumeratedValues>
            </field>
            <field>
              <name>IRQC</name>
              <description>Interrupt Configuration</description>
              <bitOffset>16</bitOffset>
              <bitWidth>4</bitWidth>
              <access>read-write</access>
              <enumeratedValues>
                <enumeratedValue>
                  <name>0000</name>
                  <description>Interrupt/DMA request disabled.</description>
                  <value>#0000</value>
                </enumeratedValue>
                <enumeratedValue>
                  <name>0001</name>
                  <description>DMA request on rising edge.</description>
                  <value>#0001</value>
                </enumeratedValue>
                <enumeratedValue>
                  <name>0010</name>
                  <description>DMA request on falling edge.</description>
                  <value>#0010</value>
                </enumeratedValue>
                <enumeratedValue>
                  <name>0011</name>
                  <description>DMA request on either edge.</description>
                  <value>#0011</value>
                </enumeratedValue>
                <enumeratedValue>
                  <name>1000</name>
                  <description>Interrupt when logic 0.</description>
                  <value>#1000</value>
                </enumeratedValue>
                <enumeratedValue>
                  <name>1001</name>
                  <description>Interrupt on rising-edge.</description>
                  <value>#1001</value>
                </enumeratedValue>
                <enumeratedValue>
                  <name>1010</name>
                  <description>Interrupt on falling-edge.</description>
                  <value>#1010</value>
                </enumeratedValue>
                <enumeratedValue>
                  <name>1011</name>
                  <description>Interrupt on either edge.</description>
                  <value>#1011</value>
                </enumeratedValue>
                <enumeratedValue>
                  <name>1100</name>
                  <description>Interrupt when logic 1.</description>
                  <value>#1100</value>
                </enumeratedValue>
              </enumeratedValues>
            </field>
            <field>
              <name>ISF</name>
              <description>Interrupt Status Flag</description>
              <bitOffset>24</bitOffset>
              <bitWidth>1</bitWidth>
              <access>read-write</access>
              <enumeratedValues>
                <enumeratedValue>
                  <name>0</name>
                  <description>Configured interrupt is not detected.</description>
                  <value>#0</value>
                </enumeratedValue>
                <enumeratedValue>
                  <name>1</name>
                  <description>Configured interrupt is detected. If the pin is configured to generate a DMA request, then the corresponding flag will be cleared automatically at the completion of the requested DMA transfer. Otherwise, the flag remains set until a logic 1 is written to the flag. If the pin is configured for a level sensitive interrupt and the pin remains asserted, then the flag is set again immediately after it is cleared.</description>
                  <value>#1</value>
                </enumeratedValue>
              </enumeratedValues>
            </field>
          </fields>
        </register>
        <register>
          <name>PCR30</name>
          <description>Pin Control Register n</description>
          <addressOffset>0x78</addressOffset>
          <size>32</size>
          <access>read-write</access>
          <resetValue>0</resetValue>
          <resetMask>0xFFFFFFFF</resetMask>
          <fields>
            <field>
              <name>PS</name>
              <description>Pull Select</description>
              <bitOffset>0</bitOffset>
              <bitWidth>1</bitWidth>
              <access>read-only</access>
              <enumeratedValues>
                <enumeratedValue>
                  <name>0</name>
                  <description>Internal pulldown resistor is enabled on the corresponding pin, if the corresponding PE field is set.</description>
                  <value>#0</value>
                </enumeratedValue>
                <enumeratedValue>
                  <name>1</name>
                  <description>Internal pullup resistor is enabled on the corresponding pin, if the corresponding PE field is set.</description>
                  <value>#1</value>
                </enumeratedValue>
              </enumeratedValues>
            </field>
            <field>
              <name>PE</name>
              <description>Pull Enable</description>
              <bitOffset>1</bitOffset>
              <bitWidth>1</bitWidth>
              <access>read-only</access>
              <enumeratedValues>
                <enumeratedValue>
                  <name>0</name>
                  <description>Internal pullup or pulldown resistor is not enabled on the corresponding pin.</description>
                  <value>#0</value>
                </enumeratedValue>
                <enumeratedValue>
                  <name>1</name>
                  <description>Internal pullup or pulldown resistor is enabled on the corresponding pin, if the pin is configured as a digital input.</description>
                  <value>#1</value>
                </enumeratedValue>
              </enumeratedValues>
            </field>
            <field>
              <name>SRE</name>
              <description>Slew Rate Enable</description>
              <bitOffset>2</bitOffset>
              <bitWidth>1</bitWidth>
              <access>read-only</access>
              <enumeratedValues>
                <enumeratedValue>
                  <name>0</name>
                  <description>Fast slew rate is configured on the corresponding pin, if the pin is configured as a digital output.</description>
                  <value>#0</value>
                </enumeratedValue>
                <enumeratedValue>
                  <name>1</name>
                  <description>Slow slew rate is configured on the corresponding pin, if the pin is configured as a digital output.</description>
                  <value>#1</value>
                </enumeratedValue>
              </enumeratedValues>
            </field>
            <field>
              <name>PFE</name>
              <description>Passive Filter Enable</description>
              <bitOffset>4</bitOffset>
              <bitWidth>1</bitWidth>
              <access>read-only</access>
              <enumeratedValues>
                <enumeratedValue>
                  <name>0</name>
                  <description>Passive input filter is disabled on the corresponding pin.</description>
                  <value>#0</value>
                </enumeratedValue>
                <enumeratedValue>
                  <name>1</name>
                  <description>Passive input filter is enabled on the corresponding pin, if the pin is configured as a digital input. Refer to the device data sheet for filter characteristics.</description>
                  <value>#1</value>
                </enumeratedValue>
              </enumeratedValues>
            </field>
            <field>
              <name>DSE</name>
              <description>Drive Strength Enable</description>
              <bitOffset>6</bitOffset>
              <bitWidth>1</bitWidth>
              <access>read-only</access>
              <enumeratedValues>
                <enumeratedValue>
                  <name>0</name>
                  <description>Low drive strength is configured on the corresponding pin, if pin is configured as a digital output.</description>
                  <value>#0</value>
                </enumeratedValue>
                <enumeratedValue>
                  <name>1</name>
                  <description>High drive strength is configured on the corresponding pin, if pin is configured as a digital output.</description>
                  <value>#1</value>
                </enumeratedValue>
              </enumeratedValues>
            </field>
            <field>
              <name>MUX</name>
              <description>Pin Mux Control</description>
              <bitOffset>8</bitOffset>
              <bitWidth>3</bitWidth>
              <access>read-write</access>
              <enumeratedValues>
                <enumeratedValue>
                  <name>000</name>
                  <description>Pin disabled (analog).</description>
                  <value>#000</value>
                </enumeratedValue>
                <enumeratedValue>
                  <name>001</name>
                  <description>Alternative 1 (GPIO).</description>
                  <value>#001</value>
                </enumeratedValue>
                <enumeratedValue>
                  <name>010</name>
                  <description>Alternative 2 (chip-specific).</description>
                  <value>#010</value>
                </enumeratedValue>
                <enumeratedValue>
                  <name>011</name>
                  <description>Alternative 3 (chip-specific).</description>
                  <value>#011</value>
                </enumeratedValue>
                <enumeratedValue>
                  <name>100</name>
                  <description>Alternative 4 (chip-specific).</description>
                  <value>#100</value>
                </enumeratedValue>
                <enumeratedValue>
                  <name>101</name>
                  <description>Alternative 5 (chip-specific).</description>
                  <value>#101</value>
                </enumeratedValue>
                <enumeratedValue>
                  <name>110</name>
                  <description>Alternative 6 (chip-specific).</description>
                  <value>#110</value>
                </enumeratedValue>
                <enumeratedValue>
                  <name>111</name>
                  <description>Alternative 7 (chip-specific).</description>
                  <value>#111</value>
                </enumeratedValue>
              </enumeratedValues>
            </field>
            <field>
              <name>IRQC</name>
              <description>Interrupt Configuration</description>
              <bitOffset>16</bitOffset>
              <bitWidth>4</bitWidth>
              <access>read-write</access>
              <enumeratedValues>
                <enumeratedValue>
                  <name>0000</name>
                  <description>Interrupt/DMA request disabled.</description>
                  <value>#0000</value>
                </enumeratedValue>
                <enumeratedValue>
                  <name>0001</name>
                  <description>DMA request on rising edge.</description>
                  <value>#0001</value>
                </enumeratedValue>
                <enumeratedValue>
                  <name>0010</name>
                  <description>DMA request on falling edge.</description>
                  <value>#0010</value>
                </enumeratedValue>
                <enumeratedValue>
                  <name>0011</name>
                  <description>DMA request on either edge.</description>
                  <value>#0011</value>
                </enumeratedValue>
                <enumeratedValue>
                  <name>1000</name>
                  <description>Interrupt when logic 0.</description>
                  <value>#1000</value>
                </enumeratedValue>
                <enumeratedValue>
                  <name>1001</name>
                  <description>Interrupt on rising-edge.</description>
                  <value>#1001</value>
                </enumeratedValue>
                <enumeratedValue>
                  <name>1010</name>
                  <description>Interrupt on falling-edge.</description>
                  <value>#1010</value>
                </enumeratedValue>
                <enumeratedValue>
                  <name>1011</name>
                  <description>Interrupt on either edge.</description>
                  <value>#1011</value>
                </enumeratedValue>
                <enumeratedValue>
                  <name>1100</name>
                  <description>Interrupt when logic 1.</description>
                  <value>#1100</value>
                </enumeratedValue>
              </enumeratedValues>
            </field>
            <field>
              <name>ISF</name>
              <description>Interrupt Status Flag</description>
              <bitOffset>24</bitOffset>
              <bitWidth>1</bitWidth>
              <access>read-write</access>
              <enumeratedValues>
                <enumeratedValue>
                  <name>0</name>
                  <description>Configured interrupt is not detected.</description>
                  <value>#0</value>
                </enumeratedValue>
                <enumeratedValue>
                  <name>1</name>
                  <description>Configured interrupt is detected. If the pin is configured to generate a DMA request, then the corresponding flag will be cleared automatically at the completion of the requested DMA transfer. Otherwise, the flag remains set until a logic 1 is written to the flag. If the pin is configured for a level sensitive interrupt and the pin remains asserted, then the flag is set again immediately after it is cleared.</description>
                  <value>#1</value>
                </enumeratedValue>
              </enumeratedValues>
            </field>
          </fields>
        </register>
        <register>
          <name>PCR31</name>
          <description>Pin Control Register n</description>
          <addressOffset>0x7C</addressOffset>
          <size>32</size>
          <access>read-write</access>
          <resetValue>0</resetValue>
          <resetMask>0xFFFFFFFF</resetMask>
          <fields>
            <field>
              <name>PS</name>
              <description>Pull Select</description>
              <bitOffset>0</bitOffset>
              <bitWidth>1</bitWidth>
              <access>read-only</access>
              <enumeratedValues>
                <enumeratedValue>
                  <name>0</name>
                  <description>Internal pulldown resistor is enabled on the corresponding pin, if the corresponding PE field is set.</description>
                  <value>#0</value>
                </enumeratedValue>
                <enumeratedValue>
                  <name>1</name>
                  <description>Internal pullup resistor is enabled on the corresponding pin, if the corresponding PE field is set.</description>
                  <value>#1</value>
                </enumeratedValue>
              </enumeratedValues>
            </field>
            <field>
              <name>PE</name>
              <description>Pull Enable</description>
              <bitOffset>1</bitOffset>
              <bitWidth>1</bitWidth>
              <access>read-only</access>
              <enumeratedValues>
                <enumeratedValue>
                  <name>0</name>
                  <description>Internal pullup or pulldown resistor is not enabled on the corresponding pin.</description>
                  <value>#0</value>
                </enumeratedValue>
                <enumeratedValue>
                  <name>1</name>
                  <description>Internal pullup or pulldown resistor is enabled on the corresponding pin, if the pin is configured as a digital input.</description>
                  <value>#1</value>
                </enumeratedValue>
              </enumeratedValues>
            </field>
            <field>
              <name>SRE</name>
              <description>Slew Rate Enable</description>
              <bitOffset>2</bitOffset>
              <bitWidth>1</bitWidth>
              <access>read-only</access>
              <enumeratedValues>
                <enumeratedValue>
                  <name>0</name>
                  <description>Fast slew rate is configured on the corresponding pin, if the pin is configured as a digital output.</description>
                  <value>#0</value>
                </enumeratedValue>
                <enumeratedValue>
                  <name>1</name>
                  <description>Slow slew rate is configured on the corresponding pin, if the pin is configured as a digital output.</description>
                  <value>#1</value>
                </enumeratedValue>
              </enumeratedValues>
            </field>
            <field>
              <name>PFE</name>
              <description>Passive Filter Enable</description>
              <bitOffset>4</bitOffset>
              <bitWidth>1</bitWidth>
              <access>read-only</access>
              <enumeratedValues>
                <enumeratedValue>
                  <name>0</name>
                  <description>Passive input filter is disabled on the corresponding pin.</description>
                  <value>#0</value>
                </enumeratedValue>
                <enumeratedValue>
                  <name>1</name>
                  <description>Passive input filter is enabled on the corresponding pin, if the pin is configured as a digital input. Refer to the device data sheet for filter characteristics.</description>
                  <value>#1</value>
                </enumeratedValue>
              </enumeratedValues>
            </field>
            <field>
              <name>DSE</name>
              <description>Drive Strength Enable</description>
              <bitOffset>6</bitOffset>
              <bitWidth>1</bitWidth>
              <access>read-only</access>
              <enumeratedValues>
                <enumeratedValue>
                  <name>0</name>
                  <description>Low drive strength is configured on the corresponding pin, if pin is configured as a digital output.</description>
                  <value>#0</value>
                </enumeratedValue>
                <enumeratedValue>
                  <name>1</name>
                  <description>High drive strength is configured on the corresponding pin, if pin is configured as a digital output.</description>
                  <value>#1</value>
                </enumeratedValue>
              </enumeratedValues>
            </field>
            <field>
              <name>MUX</name>
              <description>Pin Mux Control</description>
              <bitOffset>8</bitOffset>
              <bitWidth>3</bitWidth>
              <access>read-write</access>
              <enumeratedValues>
                <enumeratedValue>
                  <name>000</name>
                  <description>Pin disabled (analog).</description>
                  <value>#000</value>
                </enumeratedValue>
                <enumeratedValue>
                  <name>001</name>
                  <description>Alternative 1 (GPIO).</description>
                  <value>#001</value>
                </enumeratedValue>
                <enumeratedValue>
                  <name>010</name>
                  <description>Alternative 2 (chip-specific).</description>
                  <value>#010</value>
                </enumeratedValue>
                <enumeratedValue>
                  <name>011</name>
                  <description>Alternative 3 (chip-specific).</description>
                  <value>#011</value>
                </enumeratedValue>
                <enumeratedValue>
                  <name>100</name>
                  <description>Alternative 4 (chip-specific).</description>
                  <value>#100</value>
                </enumeratedValue>
                <enumeratedValue>
                  <name>101</name>
                  <description>Alternative 5 (chip-specific).</description>
                  <value>#101</value>
                </enumeratedValue>
                <enumeratedValue>
                  <name>110</name>
                  <description>Alternative 6 (chip-specific).</description>
                  <value>#110</value>
                </enumeratedValue>
                <enumeratedValue>
                  <name>111</name>
                  <description>Alternative 7 (chip-specific).</description>
                  <value>#111</value>
                </enumeratedValue>
              </enumeratedValues>
            </field>
            <field>
              <name>IRQC</name>
              <description>Interrupt Configuration</description>
              <bitOffset>16</bitOffset>
              <bitWidth>4</bitWidth>
              <access>read-write</access>
              <enumeratedValues>
                <enumeratedValue>
                  <name>0000</name>
                  <description>Interrupt/DMA request disabled.</description>
                  <value>#0000</value>
                </enumeratedValue>
                <enumeratedValue>
                  <name>0001</name>
                  <description>DMA request on rising edge.</description>
                  <value>#0001</value>
                </enumeratedValue>
                <enumeratedValue>
                  <name>0010</name>
                  <description>DMA request on falling edge.</description>
                  <value>#0010</value>
                </enumeratedValue>
                <enumeratedValue>
                  <name>0011</name>
                  <description>DMA request on either edge.</description>
                  <value>#0011</value>
                </enumeratedValue>
                <enumeratedValue>
                  <name>1000</name>
                  <description>Interrupt when logic 0.</description>
                  <value>#1000</value>
                </enumeratedValue>
                <enumeratedValue>
                  <name>1001</name>
                  <description>Interrupt on rising-edge.</description>
                  <value>#1001</value>
                </enumeratedValue>
                <enumeratedValue>
                  <name>1010</name>
                  <description>Interrupt on falling-edge.</description>
                  <value>#1010</value>
                </enumeratedValue>
                <enumeratedValue>
                  <name>1011</name>
                  <description>Interrupt on either edge.</description>
                  <value>#1011</value>
                </enumeratedValue>
                <enumeratedValue>
                  <name>1100</name>
                  <description>Interrupt when logic 1.</description>
                  <value>#1100</value>
                </enumeratedValue>
              </enumeratedValues>
            </field>
            <field>
              <name>ISF</name>
              <description>Interrupt Status Flag</description>
              <bitOffset>24</bitOffset>
              <bitWidth>1</bitWidth>
              <access>read-write</access>
              <enumeratedValues>
                <enumeratedValue>
                  <name>0</name>
                  <description>Configured interrupt is not detected.</description>
                  <value>#0</value>
                </enumeratedValue>
                <enumeratedValue>
                  <name>1</name>
                  <description>Configured interrupt is detected. If the pin is configured to generate a DMA request, then the corresponding flag will be cleared automatically at the completion of the requested DMA transfer. Otherwise, the flag remains set until a logic 1 is written to the flag. If the pin is configured for a level sensitive interrupt and the pin remains asserted, then the flag is set again immediately after it is cleared.</description>
                  <value>#1</value>
                </enumeratedValue>
              </enumeratedValues>
            </field>
          </fields>
        </register>
        <register>
          <name>GPCLR</name>
          <description>Global Pin Control Low Register</description>
          <addressOffset>0x80</addressOffset>
          <size>32</size>
          <access>write-only</access>
          <resetValue>0</resetValue>
          <resetMask>0xFFFFFFFF</resetMask>
          <fields>
            <field>
              <name>GPWD</name>
              <description>Global Pin Write Data</description>
              <bitOffset>0</bitOffset>
              <bitWidth>16</bitWidth>
              <access>write-only</access>
            </field>
            <field>
              <name>GPWE</name>
              <description>Global Pin Write Enable</description>
              <bitOffset>16</bitOffset>
              <bitWidth>16</bitWidth>
              <access>write-only</access>
              <enumeratedValues>
                <enumeratedValue>
                  <name>0</name>
                  <description>Corresponding Pin Control Register is not updated with the value in GPWD.</description>
                  <value>#0</value>
                </enumeratedValue>
                <enumeratedValue>
                  <name>1</name>
                  <description>Corresponding Pin Control Register is updated with the value in GPWD.</description>
                  <value>#1</value>
                </enumeratedValue>
              </enumeratedValues>
            </field>
          </fields>
        </register>
        <register>
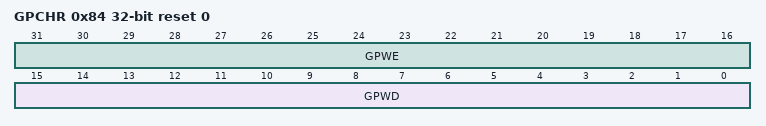
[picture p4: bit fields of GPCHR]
          <name>GPCHR</name>
          <description>Global Pin Control High Register</description>
          <addressOffset>0x84</addressOffset>
          <size>32</size>
          <access>write-only</access>
          <resetValue>0</resetValue>
          <resetMask>0xFFFFFFFF</resetMask>
          <fields>
            <field>
              <name>GPWD</name>
              <description>Global Pin Write Data</description>
              <bitOffset>0</bitOffset>
              <bitWidth>16</bitWidth>
              <access>write-only</access>
            </field>
            <field>
              <name>GPWE</name>
              <description>Global Pin Write Enable</description>
              <bitOffset>16</bitOffset>
              <bitWidth>16</bitWidth>
              <access>write-only</access>
              <enumeratedValues>
                <enumeratedValue>
                  <name>0</name>
                  <description>Corresponding Pin Control Register is not updated with the value in GPWD.</description>
                  <value>#0</value>
                </enumeratedValue>
                <enumeratedValue>
                  <name>1</name>
                  <description>Corresponding Pin Control Register is updated with the value in GPWD.</description>
                  <value>#1</value>
                </enumeratedValue>
              </enumeratedValues>
            </field>
          </fields>
        </register>
        <register>
          <name>ISFR</name>
          <description>Interrupt Status Flag Register</description>
          <addressOffset>0xA0</addressOffset>
          <size>32</size>
          <access>read-write</access>
          <resetValue>0</resetValue>
          <resetMask>0xFFFFFFFF</resetMask>
          <fields>
            <field>
              <name>ISF</name>
              <description>Interrupt Status Flag</description>
              <bitOffset>0</bitOffset>
              <bitWidth>32</bitWidth>
              <access>read-write</access>
              <enumeratedValues>
                <enumeratedValue>
                  <name>0</name>
                  <description>Configured interrupt is not detected.</description>
                  <value>#0</value>
                </enumeratedValue>
                <enumeratedValue>
                  <name>1</name>
                  <description>Configured interrupt is detected. If the pin is configured to generate a DMA request, then the corresponding flag will be cleared automatically at the completion of the requested DMA transfer. Otherwise, the flag remains set until a logic 1 is written to the flag. If the pin is configured for a level sensitive interrupt and the pin remains asserted, then the flag is set again immediately after it is cleared.</description>
                  <value>#1</value>
                </enumeratedValue>
              </enumeratedValues>
            </field>
          </fields>
        </register>
      </registers>
    </peripheral>
    <peripheral>
      <name>PORTC</name>
      <description>Pin Control and Interrupts</description>
      <groupName>PORT</groupName>
      <prependToName>PORTC_</prependToName>
      <baseAddress>0x4004B000</baseAddress>
      <addressBlock>
        <offset>0</offset>
        <size>0xA4</size>
        <usage>registers</usage>
      </addressBlock>
      <interrupt>
        <name>PORTC_PORTD</name>
        <value>31</value>
      </interrupt>
      <registers>
        <register>
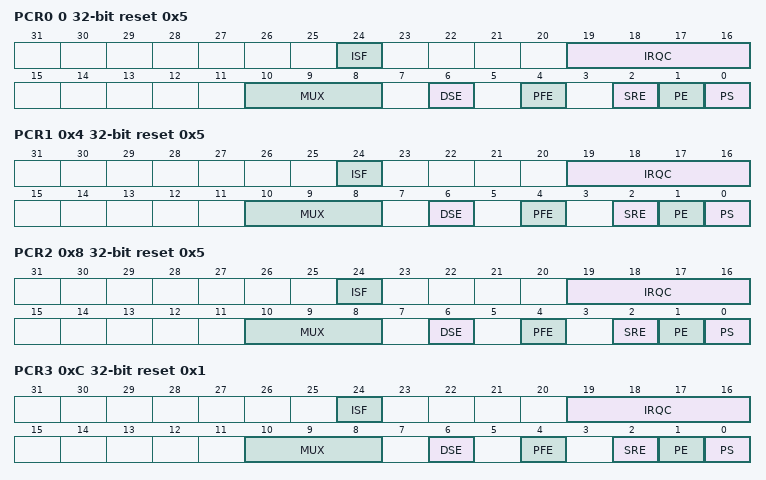
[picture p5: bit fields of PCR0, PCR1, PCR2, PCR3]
          <name>PCR0</name>
          <description>Pin Control Register n</description>
          <addressOffset>0</addressOffset>
          <size>32</size>
          <access>read-write</access>
          <resetValue>0x5</resetValue>
          <resetMask>0xFFFFFFFF</resetMask>
          <fields>
            <field>
              <name>PS</name>
              <description>Pull Select</description>
              <bitOffset>0</bitOffset>
              <bitWidth>1</bitWidth>
              <access>read-write</access>
              <enumeratedValues>
                <enumeratedValue>
                  <name>0</name>
                  <description>Internal pulldown resistor is enabled on the corresponding pin, if the corresponding PE field is set.</description>
                  <value>#0</value>
                </enumeratedValue>
                <enumeratedValue>
                  <name>1</name>
                  <description>Internal pullup resistor is enabled on the corresponding pin, if the corresponding PE field is set.</description>
                  <value>#1</value>
                </enumeratedValue>
              </enumeratedValues>
            </field>
            <field>
              <name>PE</name>
              <description>Pull Enable</description>
              <bitOffset>1</bitOffset>
              <bitWidth>1</bitWidth>
              <access>read-write</access>
              <enumeratedValues>
                <enumeratedValue>
                  <name>0</name>
                  <description>Internal pullup or pulldown resistor is not enabled on the corresponding pin.</description>
                  <value>#0</value>
                </enumeratedValue>
                <enumeratedValue>
                  <name>1</name>
                  <description>Internal pullup or pulldown resistor is enabled on the corresponding pin, if the pin is configured as a digital input.</description>
                  <value>#1</value>
                </enumeratedValue>
              </enumeratedValues>
            </field>
            <field>
              <name>SRE</name>
              <description>Slew Rate Enable</description>
              <bitOffset>2</bitOffset>
              <bitWidth>1</bitWidth>
              <access>read-write</access>
              <enumeratedValues>
                <enumeratedValue>
                  <name>0</name>
                  <description>Fast slew rate is configured on the corresponding pin, if the pin is configured as a digital output.</description>
                  <value>#0</value>
                </enumeratedValue>
                <enumeratedValue>
                  <name>1</name>
                  <description>Slow slew rate is configured on the corresponding pin, if the pin is configured as a digital output.</description>
                  <value>#1</value>
                </enumeratedValue>
              </enumeratedValues>
            </field>
            <field>
              <name>PFE</name>
              <description>Passive Filter Enable</description>
              <bitOffset>4</bitOffset>
              <bitWidth>1</bitWidth>
              <access>read-only</access>
              <enumeratedValues>
                <enumeratedValue>
                  <name>0</name>
                  <description>Passive input filter is disabled on the corresponding pin.</description>
                  <value>#0</value>
                </enumeratedValue>
                <enumeratedValue>
                  <name>1</name>
                  <description>Passive input filter is enabled on the corresponding pin, if the pin is configured as a digital input. Refer to the device data sheet for filter characteristics.</description>
                  <value>#1</value>
                </enumeratedValue>
              </enumeratedValues>
            </field>
            <field>
              <name>DSE</name>
              <description>Drive Strength Enable</description>
              <bitOffset>6</bitOffset>
              <bitWidth>1</bitWidth>
              <access>read-only</access>
              <enumeratedValues>
                <enumeratedValue>
                  <name>0</name>
                  <description>Low drive strength is configured on the corresponding pin, if pin is configured as a digital output.</description>
                  <value>#0</value>
                </enumeratedValue>
                <enumeratedValue>
                  <name>1</name>
                  <description>High drive strength is configured on the corresponding pin, if pin is configured as a digital output.</description>
                  <value>#1</value>
                </enumeratedValue>
              </enumeratedValues>
            </field>
            <field>
              <name>MUX</name>
              <description>Pin Mux Control</description>
              <bitOffset>8</bitOffset>
              <bitWidth>3</bitWidth>
              <access>read-write</access>
              <enumeratedValues>
                <enumeratedValue>
                  <name>000</name>
                  <description>Pin disabled (analog).</description>
                  <value>#000</value>
                </enumeratedValue>
                <enumeratedValue>
                  <name>001</name>
                  <description>Alternative 1 (GPIO).</description>
                  <value>#001</value>
                </enumeratedValue>
                <enumeratedValue>
                  <name>010</name>
                  <description>Alternative 2 (chip-specific).</description>
                  <value>#010</value>
                </enumeratedValue>
                <enumeratedValue>
                  <name>011</name>
                  <description>Alternative 3 (chip-specific).</description>
                  <value>#011</value>
                </enumeratedValue>
                <enumeratedValue>
                  <name>100</name>
                  <description>Alternative 4 (chip-specific).</description>
                  <value>#100</value>
                </enumeratedValue>
                <enumeratedValue>
                  <name>101</name>
                  <description>Alternative 5 (chip-specific).</description>
                  <value>#101</value>
                </enumeratedValue>
                <enumeratedValue>
                  <name>110</name>
                  <description>Alternative 6 (chip-specific).</description>
                  <value>#110</value>
                </enumeratedValue>
                <enumeratedValue>
                  <name>111</name>
                  <description>Alternative 7 (chip-specific).</description>
                  <value>#111</value>
                </enumeratedValue>
              </enumeratedValues>
            </field>
            <field>
              <name>IRQC</name>
              <description>Interrupt Configuration</description>
              <bitOffset>16</bitOffset>
              <bitWidth>4</bitWidth>
              <access>read-write</access>
              <enumeratedValues>
                <enumeratedValue>
                  <name>0000</name>
                  <description>Interrupt/DMA request disabled.</description>
                  <value>#0000</value>
                </enumeratedValue>
                <enumeratedValue>
                  <name>0001</name>
                  <description>DMA request on rising edge.</description>
                  <value>#0001</value>
                </enumeratedValue>
                <enumeratedValue>
                  <name>0010</name>
                  <description>DMA request on falling edge.</description>
                  <value>#0010</value>
                </enumeratedValue>
                <enumeratedValue>
                  <name>0011</name>
                  <description>DMA request on either edge.</description>
                  <value>#0011</value>
                </enumeratedValue>
                <enumeratedValue>
                  <name>1000</name>
                  <description>Interrupt when logic 0.</description>
                  <value>#1000</value>
                </enumeratedValue>
                <enumeratedValue>
                  <name>1001</name>
                  <description>Interrupt on rising-edge.</description>
                  <value>#1001</value>
                </enumeratedValue>
                <enumeratedValue>
                  <name>1010</name>
                  <description>Interrupt on falling-edge.</description>
                  <value>#1010</value>
                </enumeratedValue>
                <enumeratedValue>
                  <name>1011</name>
                  <description>Interrupt on either edge.</description>
                  <value>#1011</value>
                </enumeratedValue>
                <enumeratedValue>
                  <name>1100</name>
                  <description>Interrupt when logic 1.</description>
                  <value>#1100</value>
                </enumeratedValue>
              </enumeratedValues>
            </field>
            <field>
              <name>ISF</name>
              <description>Interrupt Status Flag</description>
              <bitOffset>24</bitOffset>
              <bitWidth>1</bitWidth>
              <access>read-write</access>
              <enumeratedValues>
                <enumeratedValue>
                  <name>0</name>
                  <description>Configured interrupt is not detected.</description>
                  <value>#0</value>
                </enumeratedValue>
                <enumeratedValue>
                  <name>1</name>
                  <description>Configured interrupt is detected. If the pin is configured to generate a DMA request, then the corresponding flag will be cleared automatically at the completion of the requested DMA transfer. Otherwise, the flag remains set until a logic 1 is written to the flag. If the pin is configured for a level sensitive interrupt and the pin remains asserted, then the flag is set again immediately after it is cleared.</description>
                  <value>#1</value>
                </enumeratedValue>
              </enumeratedValues>
            </field>
          </fields>
        </register>
        <register>
          <name>PCR1</name>
          <description>Pin Control Register n</description>
          <addressOffset>0x4</addressOffset>
          <size>32</size>
          <access>read-write</access>
          <resetValue>0x5</resetValue>
          <resetMask>0xFFFFFFFF</resetMask>
          <fields>
            <field>
              <name>PS</name>
              <description>Pull Select</description>
              <bitOffset>0</bitOffset>
              <bitWidth>1</bitWidth>
              <access>read-write</access>
              <enumeratedValues>
                <enumeratedValue>
                  <name>0</name>
                  <description>Internal pulldown resistor is enabled on the corresponding pin, if the corresponding PE field is set.</description>
                  <value>#0</value>
                </enumeratedValue>
                <enumeratedValue>
                  <name>1</name>
                  <description>Internal pullup resistor is enabled on the corresponding pin, if the corresponding PE field is set.</description>
                  <value>#1</value>
                </enumeratedValue>
              </enumeratedValues>
            </field>
            <field>
              <name>PE</name>
              <description>Pull Enable</description>
              <bitOffset>1</bitOffset>
              <bitWidth>1</bitWidth>
              <access>read-write</access>
              <enumeratedValues>
                <enumeratedValue>
                  <name>0</name>
                  <description>Internal pullup or pulldown resistor is not enabled on the corresponding pin.</description>
                  <value>#0</value>
                </enumeratedValue>
                <enumeratedValue>
                  <name>1</name>
                  <description>Internal pullup or pulldown resistor is enabled on the corresponding pin, if the pin is configured as a digital input.</description>
                  <value>#1</value>
                </enumeratedValue>
              </enumeratedValues>
            </field>
            <field>
              <name>SRE</name>
              <description>Slew Rate Enable</description>
              <bitOffset>2</bitOffset>
              <bitWidth>1</bitWidth>
              <access>read-write</access>
              <enumeratedValues>
                <enumeratedValue>
                  <name>0</name>
                  <description>Fast slew rate is configured on the corresponding pin, if the pin is configured as a digital output.</description>
                  <value>#0</value>
                </enumeratedValue>
                <enumeratedValue>
                  <name>1</name>
                  <description>Slow slew rate is configured on the corresponding pin, if the pin is configured as a digital output.</description>
                  <value>#1</value>
                </enumeratedValue>
              </enumeratedValues>
            </field>
            <field>
              <name>PFE</name>
              <description>Passive Filter Enable</description>
              <bitOffset>4</bitOffset>
              <bitWidth>1</bitWidth>
              <access>read-only</access>
              <enumeratedValues>
                <enumeratedValue>
                  <name>0</name>
                  <description>Passive input filter is disabled on the corresponding pin.</description>
                  <value>#0</value>
                </enumeratedValue>
                <enumeratedValue>
                  <name>1</name>
                  <description>Passive input filter is enabled on the corresponding pin, if the pin is configured as a digital input. Refer to the device data sheet for filter characteristics.</description>
                  <value>#1</value>
                </enumeratedValue>
              </enumeratedValues>
            </field>
            <field>
              <name>DSE</name>
              <description>Drive Strength Enable</description>
              <bitOffset>6</bitOffset>
              <bitWidth>1</bitWidth>
              <access>read-only</access>
              <enumeratedValues>
                <enumeratedValue>
                  <name>0</name>
                  <description>Low drive strength is configured on the corresponding pin, if pin is configured as a digital output.</description>
                  <value>#0</value>
                </enumeratedValue>
                <enumeratedValue>
                  <name>1</name>
                  <description>High drive strength is configured on the corresponding pin, if pin is configured as a digital output.</description>
                  <value>#1</value>
                </enumeratedValue>
              </enumeratedValues>
            </field>
            <field>
              <name>MUX</name>
              <description>Pin Mux Control</description>
              <bitOffset>8</bitOffset>
              <bitWidth>3</bitWidth>
              <access>read-write</access>
              <enumeratedValues>
                <enumeratedValue>
                  <name>000</name>
                  <description>Pin disabled (analog).</description>
                  <value>#000</value>
                </enumeratedValue>
                <enumeratedValue>
                  <name>001</name>
                  <description>Alternative 1 (GPIO).</description>
                  <value>#001</value>
                </enumeratedValue>
                <enumeratedValue>
                  <name>010</name>
                  <description>Alternative 2 (chip-specific).</description>
                  <value>#010</value>
                </enumeratedValue>
                <enumeratedValue>
                  <name>011</name>
                  <description>Alternative 3 (chip-specific).</description>
                  <value>#011</value>
                </enumeratedValue>
                <enumeratedValue>
                  <name>100</name>
                  <description>Alternative 4 (chip-specific).</description>
                  <value>#100</value>
                </enumeratedValue>
                <enumeratedValue>
                  <name>101</name>
                  <description>Alternative 5 (chip-specific).</description>
                  <value>#101</value>
                </enumeratedValue>
                <enumeratedValue>
                  <name>110</name>
                  <description>Alternative 6 (chip-specific).</description>
                  <value>#110</value>
                </enumeratedValue>
                <enumeratedValue>
                  <name>111</name>
                  <description>Alternative 7 (chip-specific).</description>
                  <value>#111</value>
                </enumeratedValue>
              </enumeratedValues>
            </field>
            <field>
              <name>IRQC</name>
              <description>Interrupt Configuration</description>
              <bitOffset>16</bitOffset>
              <bitWidth>4</bitWidth>
              <access>read-write</access>
              <enumeratedValues>
                <enumeratedValue>
                  <name>0000</name>
                  <description>Interrupt/DMA request disabled.</description>
                  <value>#0000</value>
                </enumeratedValue>
                <enumeratedValue>
                  <name>0001</name>
                  <description>DMA request on rising edge.</description>
                  <value>#0001</value>
                </enumeratedValue>
                <enumeratedValue>
                  <name>0010</name>
                  <description>DMA request on falling edge.</description>
                  <value>#0010</value>
                </enumeratedValue>
                <enumeratedValue>
                  <name>0011</name>
                  <description>DMA request on either edge.</description>
                  <value>#0011</value>
                </enumeratedValue>
                <enumeratedValue>
                  <name>1000</name>
                  <description>Interrupt when logic 0.</description>
                  <value>#1000</value>
                </enumeratedValue>
                <enumeratedValue>
                  <name>1001</name>
                  <description>Interrupt on rising-edge.</description>
                  <value>#1001</value>
                </enumeratedValue>
                <enumeratedValue>
                  <name>1010</name>
                  <description>Interrupt on falling-edge.</description>
                  <value>#1010</value>
                </enumeratedValue>
                <enumeratedValue>
                  <name>1011</name>
                  <description>Interrupt on either edge.</description>
                  <value>#1011</value>
                </enumeratedValue>
                <enumeratedValue>
                  <name>1100</name>
                  <description>Interrupt when logic 1.</description>
                  <value>#1100</value>
                </enumeratedValue>
              </enumeratedValues>
            </field>
            <field>
              <name>ISF</name>
              <description>Interrupt Status Flag</description>
              <bitOffset>24</bitOffset>
              <bitWidth>1</bitWidth>
              <access>read-write</access>
              <enumeratedValues>
                <enumeratedValue>
                  <name>0</name>
                  <description>Configured interrupt is not detected.</description>
                  <value>#0</value>
                </enumeratedValue>
                <enumeratedValue>
                  <name>1</name>
                  <description>Configured interrupt is detected. If the pin is configured to generate a DMA request, then the corresponding flag will be cleared automatically at the completion of the requested DMA transfer. Otherwise, the flag remains set until a logic 1 is written to the flag. If the pin is configured for a level sensitive interrupt and the pin remains asserted, then the flag is set again immediately after it is cleared.</description>
                  <value>#1</value>
                </enumeratedValue>
              </enumeratedValues>
            </field>
          </fields>
        </register>
        <register>
          <name>PCR2</name>
          <description>Pin Control Register n</description>
          <addressOffset>0x8</addressOffset>
          <size>32</size>
          <access>read-write</access>
          <resetValue>0x5</resetValue>
          <resetMask>0xFFFFFFFF</resetMask>
          <fields>
            <field>
              <name>PS</name>
              <description>Pull Select</description>
              <bitOffset>0</bitOffset>
              <bitWidth>1</bitWidth>
              <access>read-write</access>
              <enumeratedValues>
                <enumeratedValue>
                  <name>0</name>
                  <description>Internal pulldown resistor is enabled on the corresponding pin, if the corresponding PE field is set.</description>
                  <value>#0</value>
                </enumeratedValue>
                <enumeratedValue>
                  <name>1</name>
                  <description>Internal pullup resistor is enabled on the corresponding pin, if the corresponding PE field is set.</description>
                  <value>#1</value>
                </enumeratedValue>
              </enumeratedValues>
            </field>
            <field>
              <name>PE</name>
              <description>Pull Enable</description>
              <bitOffset>1</bitOffset>
              <bitWidth>1</bitWidth>
              <access>read-write</access>
              <enumeratedValues>
                <enumeratedValue>
                  <name>0</name>
                  <description>Internal pullup or pulldown resistor is not enabled on the corresponding pin.</description>
                  <value>#0</value>
                </enumeratedValue>
                <enumeratedValue>
                  <name>1</name>
                  <description>Internal pullup or pulldown resistor is enabled on the corresponding pin, if the pin is configured as a digital input.</description>
                  <value>#1</value>
                </enumeratedValue>
              </enumeratedValues>
            </field>
            <field>
              <name>SRE</name>
              <description>Slew Rate Enable</description>
              <bitOffset>2</bitOffset>
              <bitWidth>1</bitWidth>
              <access>read-write</access>
              <enumeratedValues>
                <enumeratedValue>
                  <name>0</name>
                  <description>Fast slew rate is configured on the corresponding pin, if the pin is configured as a digital output.</description>
                  <value>#0</value>
                </enumeratedValue>
                <enumeratedValue>
                  <name>1</name>
                  <description>Slow slew rate is configured on the corresponding pin, if the pin is configured as a digital output.</description>
                  <value>#1</value>
                </enumeratedValue>
              </enumeratedValues>
            </field>
            <field>
              <name>PFE</name>
              <description>Passive Filter Enable</description>
              <bitOffset>4</bitOffset>
              <bitWidth>1</bitWidth>
              <access>read-only</access>
              <enumeratedValues>
                <enumeratedValue>
                  <name>0</name>
                  <description>Passive input filter is disabled on the corresponding pin.</description>
                  <value>#0</value>
                </enumeratedValue>
                <enumeratedValue>
                  <name>1</name>
                  <description>Passive input filter is enabled on the corresponding pin, if the pin is configured as a digital input. Refer to the device data sheet for filter characteristics.</description>
                  <value>#1</value>
                </enumeratedValue>
              </enumeratedValues>
            </field>
            <field>
              <name>DSE</name>
              <description>Drive Strength Enable</description>
              <bitOffset>6</bitOffset>
              <bitWidth>1</bitWidth>
              <access>read-only</access>
              <enumeratedValues>
                <enumeratedValue>
                  <name>0</name>
                  <description>Low drive strength is configured on the corresponding pin, if pin is configured as a digital output.</description>
                  <value>#0</value>
                </enumeratedValue>
                <enumeratedValue>
                  <name>1</name>
                  <description>High drive strength is configured on the corresponding pin, if pin is configured as a digital output.</description>
                  <value>#1</value>
                </enumeratedValue>
              </enumeratedValues>
            </field>
            <field>
              <name>MUX</name>
              <description>Pin Mux Control</description>
              <bitOffset>8</bitOffset>
              <bitWidth>3</bitWidth>
              <access>read-write</access>
              <enumeratedValues>
                <enumeratedValue>
                  <name>000</name>
                  <description>Pin disabled (analog).</description>
                  <value>#000</value>
                </enumeratedValue>
                <enumeratedValue>
                  <name>001</name>
                  <description>Alternative 1 (GPIO).</description>
                  <value>#001</value>
                </enumeratedValue>
                <enumeratedValue>
                  <name>010</name>
                  <description>Alternative 2 (chip-specific).</description>
                  <value>#010</value>
                </enumeratedValue>
                <enumeratedValue>
                  <name>011</name>
                  <description>Alternative 3 (chip-specific).</description>
                  <value>#011</value>
                </enumeratedValue>
                <enumeratedValue>
                  <name>100</name>
                  <description>Alternative 4 (chip-specific).</description>
                  <value>#100</value>
                </enumeratedValue>
                <enumeratedValue>
                  <name>101</name>
                  <description>Alternative 5 (chip-specific).</description>
                  <value>#101</value>
                </enumeratedValue>
                <enumeratedValue>
                  <name>110</name>
                  <description>Alternative 6 (chip-specific).</description>
                  <value>#110</value>
                </enumeratedValue>
                <enumeratedValue>
                  <name>111</name>
                  <description>Alternative 7 (chip-specific).</description>
                  <value>#111</value>
                </enumeratedValue>
              </enumeratedValues>
            </field>
            <field>
              <name>IRQC</name>
              <description>Interrupt Configuration</description>
              <bitOffset>16</bitOffset>
              <bitWidth>4</bitWidth>
              <access>read-write</access>
              <enumeratedValues>
                <enumeratedValue>
                  <name>0000</name>
                  <description>Interrupt/DMA request disabled.</description>
                  <value>#0000</value>
                </enumeratedValue>
                <enumeratedValue>
                  <name>0001</name>
                  <description>DMA request on rising edge.</description>
                  <value>#0001</value>
                </enumeratedValue>
                <enumeratedValue>
                  <name>0010</name>
                  <description>DMA request on falling edge.</description>
                  <value>#0010</value>
                </enumeratedValue>
                <enumeratedValue>
                  <name>0011</name>
                  <description>DMA request on either edge.</description>
                  <value>#0011</value>
                </enumeratedValue>
                <enumeratedValue>
                  <name>1000</name>
                  <description>Interrupt when logic 0.</description>
                  <value>#1000</value>
                </enumeratedValue>
                <enumeratedValue>
                  <name>1001</name>
                  <description>Interrupt on rising-edge.</description>
                  <value>#1001</value>
                </enumeratedValue>
                <enumeratedValue>
                  <name>1010</name>
                  <description>Interrupt on falling-edge.</description>
                  <value>#1010</value>
                </enumeratedValue>
                <enumeratedValue>
                  <name>1011</name>
                  <description>Interrupt on either edge.</description>
                  <value>#1011</value>
                </enumeratedValue>
                <enumeratedValue>
                  <name>1100</name>
                  <description>Interrupt when logic 1.</description>
                  <value>#1100</value>
                </enumeratedValue>
              </enumeratedValues>
            </field>
            <field>
              <name>ISF</name>
              <description>Interrupt Status Flag</description>
              <bitOffset>24</bitOffset>
              <bitWidth>1</bitWidth>
              <access>read-write</access>
              <enumeratedValues>
                <enumeratedValue>
                  <name>0</name>
                  <description>Configured interrupt is not detected.</description>
                  <value>#0</value>
                </enumeratedValue>
                <enumeratedValue>
                  <name>1</name>
                  <description>Configured interrupt is detected. If the pin is configured to generate a DMA request, then the corresponding flag will be cleared automatically at the completion of the requested DMA transfer. Otherwise, the flag remains set until a logic 1 is written to the flag. If the pin is configured for a level sensitive interrupt and the pin remains asserted, then the flag is set again immediately after it is cleared.</description>
                  <value>#1</value>
                </enumeratedValue>
              </enumeratedValues>
            </field>
          </fields>
        </register>
        <register>
          <name>PCR3</name>
          <description>Pin Control Register n</description>
          <addressOffset>0xC</addressOffset>
          <size>32</size>
          <access>read-write</access>
          <resetValue>0x1</resetValue>
          <resetMask>0xFFFFFFFF</resetMask>
          <fields>
            <field>
              <name>PS</name>
              <description>Pull Select</description>
              <bitOffset>0</bitOffset>
              <bitWidth>1</bitWidth>
              <access>read-write</access>
              <enumeratedValues>
                <enumeratedValue>
                  <name>0</name>
                  <description>Internal pulldown resistor is enabled on the corresponding pin, if the corresponding PE field is set.</description>
                  <value>#0</value>
                </enumeratedValue>
                <enumeratedValue>
                  <name>1</name>
                  <description>Internal pullup resistor is enabled on the corresponding pin, if the corresponding PE field is set.</description>
                  <value>#1</value>
                </enumeratedValue>
              </enumeratedValues>
            </field>
            <field>
              <name>PE</name>
              <description>Pull Enable</description>
              <bitOffset>1</bitOffset>
              <bitWidth>1</bitWidth>
              <access>read-write</access>
              <enumeratedValues>
                <enumeratedValue>
                  <name>0</name>
                  <description>Internal pullup or pulldown resistor is not enabled on the corresponding pin.</description>
                  <value>#0</value>
                </enumeratedValue>
                <enumeratedValue>
                  <name>1</name>
                  <description>Internal pullup or pulldown resistor is enabled on the corresponding pin, if the pin is configured as a digital input.</description>
                  <value>#1</value>
                </enumeratedValue>
              </enumeratedValues>
            </field>
            <field>
              <name>SRE</name>
              <description>Slew Rate Enable</description>
              <bitOffset>2</bitOffset>
              <bitWidth>1</bitWidth>
              <access>read-write</access>
              <enumeratedValues>
                <enumeratedValue>
                  <name>0</name>
                  <description>Fast slew rate is configured on the corresponding pin, if the pin is configured as a digital output.</description>
                  <value>#0</value>
                </enumeratedValue>
                <enumeratedValue>
                  <name>1</name>
                  <description>Slow slew rate is configured on the corresponding pin, if the pin is configured as a digital output.</description>
                  <value>#1</value>
                </enumeratedValue>
              </enumeratedValues>
            </field>
            <field>
              <name>PFE</name>
              <description>Passive Filter Enable</description>
              <bitOffset>4</bitOffset>
              <bitWidth>1</bitWidth>
              <access>read-only</access>
              <enumeratedValues>
                <enumeratedValue>
                  <name>0</name>
                  <description>Passive input filter is disabled on the corresponding pin.</description>
                  <value>#0</value>
                </enumeratedValue>
                <enumeratedValue>
                  <name>1</name>
                  <description>Passive input filter is enabled on the corresponding pin, if the pin is configured as a digital input. Refer to the device data sheet for filter characteristics.</description>
                  <value>#1</value>
                </enumeratedValue>
              </enumeratedValues>
            </field>
            <field>
              <name>DSE</name>
              <description>Drive Strength Enable</description>
              <bitOffset>6</bitOffset>
              <bitWidth>1</bitWidth>
              <access>read-only</access>
              <enumeratedValues>
                <enumeratedValue>
                  <name>0</name>
                  <description>Low drive strength is configured on the corresponding pin, if pin is configured as a digital output.</description>
                  <value>#0</value>
                </enumeratedValue>
                <enumeratedValue>
                  <name>1</name>
                  <description>High drive strength is configured on the corresponding pin, if pin is configured as a digital output.</description>
                  <value>#1</value>
                </enumeratedValue>
              </enumeratedValues>
            </field>
            <field>
              <name>MUX</name>
              <description>Pin Mux Control</description>
              <bitOffset>8</bitOffset>
              <bitWidth>3</bitWidth>
              <access>read-write</access>
              <enumeratedValues>
                <enumeratedValue>
                  <name>000</name>
                  <description>Pin disabled (analog).</description>
                  <value>#000</value>
                </enumeratedValue>
                <enumeratedValue>
                  <name>001</name>
                  <description>Alternative 1 (GPIO).</description>
                  <value>#001</value>
                </enumeratedValue>
                <enumeratedValue>
                  <name>010</name>
                  <description>Alternative 2 (chip-specific).</description>
                  <value>#010</value>
                </enumeratedValue>
                <enumeratedValue>
                  <name>011</name>
                  <description>Alternative 3 (chip-specific).</description>
                  <value>#011</value>
                </enumeratedValue>
                <enumeratedValue>
                  <name>100</name>
                  <description>Alternative 4 (chip-specific).</description>
                  <value>#100</value>
                </enumeratedValue>
                <enumeratedValue>
                  <name>101</name>
                  <description>Alternative 5 (chip-specific).</description>
                  <value>#101</value>
                </enumeratedValue>
                <enumeratedValue>
                  <name>110</name>
                  <description>Alternative 6 (chip-specific).</description>
                  <value>#110</value>
                </enumeratedValue>
                <enumeratedValue>
                  <name>111</name>
                  <description>Alternative 7 (chip-specific).</description>
                  <value>#111</value>
                </enumeratedValue>
              </enumeratedValues>
            </field>
            <field>
              <name>IRQC</name>
              <description>Interrupt Configuration</description>
              <bitOffset>16</bitOffset>
              <bitWidth>4</bitWidth>
              <access>read-write</access>
              <enumeratedValues>
                <enumeratedValue>
                  <name>0000</name>
                  <description>Interrupt/DMA request disabled.</description>
                  <value>#0000</value>
                </enumeratedValue>
                <enumeratedValue>
                  <name>0001</name>
                  <description>DMA request on rising edge.</description>
                  <value>#0001</value>
                </enumeratedValue>
                <enumeratedValue>
                  <name>0010</name>
                  <description>DMA request on falling edge.</description>
                  <value>#0010</value>
                </enumeratedValue>
                <enumeratedValue>
                  <name>0011</name>
                  <description>DMA request on either edge.</description>
                  <value>#0011</value>
                </enumeratedValue>
                <enumeratedValue>
                  <name>1000</name>
                  <description>Interrupt when logic 0.</description>
                  <value>#1000</value>
                </enumeratedValue>
                <enumeratedValue>
                  <name>1001</name>
                  <description>Interrupt on rising-edge.</description>
                  <value>#1001</value>
                </enumeratedValue>
                <enumeratedValue>
                  <name>1010</name>
                  <description>Interrupt on falling-edge.</description>
                  <value>#1010</value>
                </enumeratedValue>
                <enumeratedValue>
                  <name>1011</name>
                  <description>Interrupt on either edge.</description>
                  <value>#1011</value>
                </enumeratedValue>
                <enumeratedValue>
                  <name>1100</name>
                  <description>Interrupt when logic 1.</description>
                  <value>#1100</value>
                </enumeratedValue>
              </enumeratedValues>
            </field>
            <field>
              <name>ISF</name>
              <description>Interrupt Status Flag</description>
              <bitOffset>24</bitOffset>
              <bitWidth>1</bitWidth>
              <access>read-write</access>
              <enumeratedValues>
                <enumeratedValue>
                  <name>0</name>
                  <description>Configured interrupt is not detected.</description>
                  <value>#0</value>
                </enumeratedValue>
                <enumeratedValue>
                  <name>1</name>
                  <description>Configured interrupt is detected. If the pin is configured to generate a DMA request, then the corresponding flag will be cleared automatically at the completion of the requested DMA transfer. Otherwise, the flag remains set until a logic 1 is written to the flag. If the pin is configured for a level sensitive interrupt and the pin remains asserted, then the flag is set again immediately after it is cleared.</description>
                  <value>#1</value>
                </enumeratedValue>
              </enumeratedValues>
            </field>
          </fields>
        </register>
        <register>
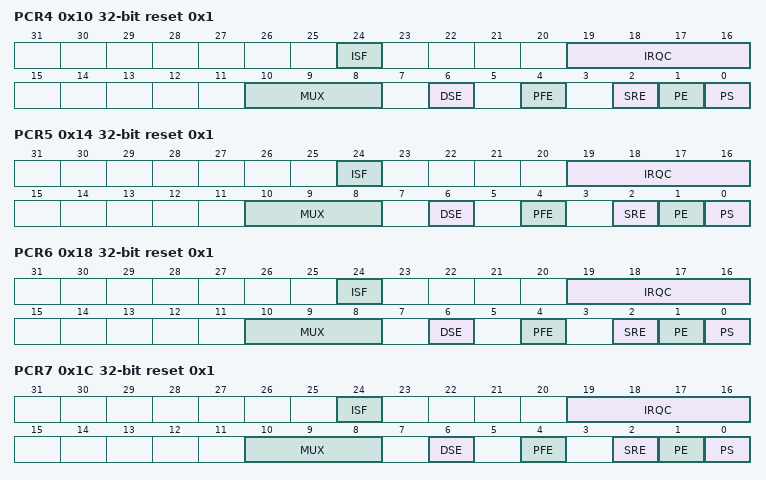
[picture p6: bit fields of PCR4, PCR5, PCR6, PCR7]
          <name>PCR4</name>
          <description>Pin Control Register n</description>
          <addressOffset>0x10</addressOffset>
          <size>32</size>
          <access>read-write</access>
          <resetValue>0x1</resetValue>
          <resetMask>0xFFFFFFFF</resetMask>
          <fields>
            <field>
              <name>PS</name>
              <description>Pull Select</description>
              <bitOffset>0</bitOffset>
              <bitWidth>1</bitWidth>
              <access>read-write</access>
              <enumeratedValues>
                <enumeratedValue>
                  <name>0</name>
                  <description>Internal pulldown resistor is enabled on the corresponding pin, if the corresponding PE field is set.</description>
                  <value>#0</value>
                </enumeratedValue>
                <enumeratedValue>
                  <name>1</name>
                  <description>Internal pullup resistor is enabled on the corresponding pin, if the corresponding PE field is set.</description>
                  <value>#1</value>
                </enumeratedValue>
              </enumeratedValues>
            </field>
            <field>
              <name>PE</name>
              <description>Pull Enable</description>
              <bitOffset>1</bitOffset>
              <bitWidth>1</bitWidth>
              <access>read-write</access>
              <enumeratedValues>
                <enumeratedValue>
                  <name>0</name>
                  <description>Internal pullup or pulldown resistor is not enabled on the corresponding pin.</description>
                  <value>#0</value>
                </enumeratedValue>
                <enumeratedValue>
                  <name>1</name>
                  <description>Internal pullup or pulldown resistor is enabled on the corresponding pin, if the pin is configured as a digital input.</description>
                  <value>#1</value>
                </enumeratedValue>
              </enumeratedValues>
            </field>
            <field>
              <name>SRE</name>
              <description>Slew Rate Enable</description>
              <bitOffset>2</bitOffset>
              <bitWidth>1</bitWidth>
              <access>read-write</access>
              <enumeratedValues>
                <enumeratedValue>
                  <name>0</name>
                  <description>Fast slew rate is configured on the corresponding pin, if the pin is configured as a digital output.</description>
                  <value>#0</value>
                </enumeratedValue>
                <enumeratedValue>
                  <name>1</name>
                  <description>Slow slew rate is configured on the corresponding pin, if the pin is configured as a digital output.</description>
                  <value>#1</value>
                </enumeratedValue>
              </enumeratedValues>
            </field>
            <field>
              <name>PFE</name>
              <description>Passive Filter Enable</description>
              <bitOffset>4</bitOffset>
              <bitWidth>1</bitWidth>
              <access>read-only</access>
              <enumeratedValues>
                <enumeratedValue>
                  <name>0</name>
                  <description>Passive input filter is disabled on the corresponding pin.</description>
                  <value>#0</value>
                </enumeratedValue>
                <enumeratedValue>
                  <name>1</name>
                  <description>Passive input filter is enabled on the corresponding pin, if the pin is configured as a digital input. Refer to the device data sheet for filter characteristics.</description>
                  <value>#1</value>
                </enumeratedValue>
              </enumeratedValues>
            </field>
            <field>
              <name>DSE</name>
              <description>Drive Strength Enable</description>
              <bitOffset>6</bitOffset>
              <bitWidth>1</bitWidth>
              <access>read-only</access>
              <enumeratedValues>
                <enumeratedValue>
                  <name>0</name>
                  <description>Low drive strength is configured on the corresponding pin, if pin is configured as a digital output.</description>
                  <value>#0</value>
                </enumeratedValue>
                <enumeratedValue>
                  <name>1</name>
                  <description>High drive strength is configured on the corresponding pin, if pin is configured as a digital output.</description>
                  <value>#1</value>
                </enumeratedValue>
              </enumeratedValues>
            </field>
            <field>
              <name>MUX</name>
              <description>Pin Mux Control</description>
              <bitOffset>8</bitOffset>
              <bitWidth>3</bitWidth>
              <access>read-write</access>
              <enumeratedValues>
                <enumeratedValue>
                  <name>000</name>
                  <description>Pin disabled (analog).</description>
                  <value>#000</value>
                </enumeratedValue>
                <enumeratedValue>
                  <name>001</name>
                  <description>Alternative 1 (GPIO).</description>
                  <value>#001</value>
                </enumeratedValue>
                <enumeratedValue>
                  <name>010</name>
                  <description>Alternative 2 (chip-specific).</description>
                  <value>#010</value>
                </enumeratedValue>
                <enumeratedValue>
                  <name>011</name>
                  <description>Alternative 3 (chip-specific).</description>
                  <value>#011</value>
                </enumeratedValue>
                <enumeratedValue>
                  <name>100</name>
                  <description>Alternative 4 (chip-specific).</description>
                  <value>#100</value>
                </enumeratedValue>
                <enumeratedValue>
                  <name>101</name>
                  <description>Alternative 5 (chip-specific).</description>
                  <value>#101</value>
                </enumeratedValue>
                <enumeratedValue>
                  <name>110</name>
                  <description>Alternative 6 (chip-specific).</description>
                  <value>#110</value>
                </enumeratedValue>
                <enumeratedValue>
                  <name>111</name>
                  <description>Alternative 7 (chip-specific).</description>
                  <value>#111</value>
                </enumeratedValue>
              </enumeratedValues>
            </field>
            <field>
              <name>IRQC</name>
              <description>Interrupt Configuration</description>
              <bitOffset>16</bitOffset>
              <bitWidth>4</bitWidth>
              <access>read-write</access>
              <enumeratedValues>
                <enumeratedValue>
                  <name>0000</name>
                  <description>Interrupt/DMA request disabled.</description>
                  <value>#0000</value>
                </enumeratedValue>
                <enumeratedValue>
                  <name>0001</name>
                  <description>DMA request on rising edge.</description>
                  <value>#0001</value>
                </enumeratedValue>
                <enumeratedValue>
                  <name>0010</name>
                  <description>DMA request on falling edge.</description>
                  <value>#0010</value>
                </enumeratedValue>
                <enumeratedValue>
                  <name>0011</name>
                  <description>DMA request on either edge.</description>
                  <value>#0011</value>
                </enumeratedValue>
                <enumeratedValue>
                  <name>1000</name>
                  <description>Interrupt when logic 0.</description>
                  <value>#1000</value>
                </enumeratedValue>
                <enumeratedValue>
                  <name>1001</name>
                  <description>Interrupt on rising-edge.</description>
                  <value>#1001</value>
                </enumeratedValue>
                <enumeratedValue>
                  <name>1010</name>
                  <description>Interrupt on falling-edge.</description>
                  <value>#1010</value>
                </enumeratedValue>
                <enumeratedValue>
                  <name>1011</name>
                  <description>Interrupt on either edge.</description>
                  <value>#1011</value>
                </enumeratedValue>
                <enumeratedValue>
                  <name>1100</name>
                  <description>Interrupt when logic 1.</description>
                  <value>#1100</value>
                </enumeratedValue>
              </enumeratedValues>
            </field>
            <field>
              <name>ISF</name>
              <description>Interrupt Status Flag</description>
              <bitOffset>24</bitOffset>
              <bitWidth>1</bitWidth>
              <access>read-write</access>
              <enumeratedValues>
                <enumeratedValue>
                  <name>0</name>
                  <description>Configured interrupt is not detected.</description>
                  <value>#0</value>
                </enumeratedValue>
                <enumeratedValue>
                  <name>1</name>
                  <description>Configured interrupt is detected. If the pin is configured to generate a DMA request, then the corresponding flag will be cleared automatically at the completion of the requested DMA transfer. Otherwise, the flag remains set until a logic 1 is written to the flag. If the pin is configured for a level sensitive interrupt and the pin remains asserted, then the flag is set again immediately after it is cleared.</description>
                  <value>#1</value>
                </enumeratedValue>
              </enumeratedValues>
            </field>
          </fields>
        </register>
        <register>
          <name>PCR5</name>
          <description>Pin Control Register n</description>
          <addressOffset>0x14</addressOffset>
          <size>32</size>
          <access>read-write</access>
          <resetValue>0x1</resetValue>
          <resetMask>0xFFFFFFFF</resetMask>
          <fields>
            <field>
              <name>PS</name>
              <description>Pull Select</description>
              <bitOffset>0</bitOffset>
              <bitWidth>1</bitWidth>
              <access>read-write</access>
              <enumeratedValues>
                <enumeratedValue>
                  <name>0</name>
                  <description>Internal pulldown resistor is enabled on the corresponding pin, if the corresponding PE field is set.</description>
                  <value>#0</value>
                </enumeratedValue>
                <enumeratedValue>
                  <name>1</name>
                  <description>Internal pullup resistor is enabled on the corresponding pin, if the corresponding PE field is set.</description>
                  <value>#1</value>
                </enumeratedValue>
              </enumeratedValues>
            </field>
            <field>
              <name>PE</name>
              <description>Pull Enable</description>
              <bitOffset>1</bitOffset>
              <bitWidth>1</bitWidth>
              <access>read-write</access>
              <enumeratedValues>
                <enumeratedValue>
                  <name>0</name>
                  <description>Internal pullup or pulldown resistor is not enabled on the corresponding pin.</description>
                  <value>#0</value>
                </enumeratedValue>
                <enumeratedValue>
                  <name>1</name>
                  <description>Internal pullup or pulldown resistor is enabled on the corresponding pin, if the pin is configured as a digital input.</description>
                  <value>#1</value>
                </enumeratedValue>
              </enumeratedValues>
            </field>
            <field>
              <name>SRE</name>
              <description>Slew Rate Enable</description>
              <bitOffset>2</bitOffset>
              <bitWidth>1</bitWidth>
              <access>read-write</access>
              <enumeratedValues>
                <enumeratedValue>
                  <name>0</name>
                  <description>Fast slew rate is configured on the corresponding pin, if the pin is configured as a digital output.</description>
                  <value>#0</value>
                </enumeratedValue>
                <enumeratedValue>
                  <name>1</name>
                  <description>Slow slew rate is configured on the corresponding pin, if the pin is configured as a digital output.</description>
                  <value>#1</value>
                </enumeratedValue>
              </enumeratedValues>
            </field>
            <field>
              <name>PFE</name>
              <description>Passive Filter Enable</description>
              <bitOffset>4</bitOffset>
              <bitWidth>1</bitWidth>
              <access>read-only</access>
              <enumeratedValues>
                <enumeratedValue>
                  <name>0</name>
                  <description>Passive input filter is disabled on the corresponding pin.</description>
                  <value>#0</value>
                </enumeratedValue>
                <enumeratedValue>
                  <name>1</name>
                  <description>Passive input filter is enabled on the corresponding pin, if the pin is configured as a digital input. Refer to the device data sheet for filter characteristics.</description>
                  <value>#1</value>
                </enumeratedValue>
              </enumeratedValues>
            </field>
            <field>
              <name>DSE</name>
              <description>Drive Strength Enable</description>
              <bitOffset>6</bitOffset>
              <bitWidth>1</bitWidth>
              <access>read-only</access>
              <enumeratedValues>
                <enumeratedValue>
                  <name>0</name>
                  <description>Low drive strength is configured on the corresponding pin, if pin is configured as a digital output.</description>
                  <value>#0</value>
                </enumeratedValue>
                <enumeratedValue>
                  <name>1</name>
                  <description>High drive strength is configured on the corresponding pin, if pin is configured as a digital output.</description>
                  <value>#1</value>
                </enumeratedValue>
              </enumeratedValues>
            </field>
            <field>
              <name>MUX</name>
              <description>Pin Mux Control</description>
              <bitOffset>8</bitOffset>
              <bitWidth>3</bitWidth>
              <access>read-write</access>
              <enumeratedValues>
                <enumeratedValue>
                  <name>000</name>
                  <description>Pin disabled (analog).</description>
                  <value>#000</value>
                </enumeratedValue>
                <enumeratedValue>
                  <name>001</name>
                  <description>Alternative 1 (GPIO).</description>
                  <value>#001</value>
                </enumeratedValue>
                <enumeratedValue>
                  <name>010</name>
                  <description>Alternative 2 (chip-specific).</description>
                  <value>#010</value>
                </enumeratedValue>
                <enumeratedValue>
                  <name>011</name>
                  <description>Alternative 3 (chip-specific).</description>
                  <value>#011</value>
                </enumeratedValue>
                <enumeratedValue>
                  <name>100</name>
                  <description>Alternative 4 (chip-specific).</description>
                  <value>#100</value>
                </enumeratedValue>
                <enumeratedValue>
                  <name>101</name>
                  <description>Alternative 5 (chip-specific).</description>
                  <value>#101</value>
                </enumeratedValue>
                <enumeratedValue>
                  <name>110</name>
                  <description>Alternative 6 (chip-specific).</description>
                  <value>#110</value>
                </enumeratedValue>
                <enumeratedValue>
                  <name>111</name>
                  <description>Alternative 7 (chip-specific).</description>
                  <value>#111</value>
                </enumeratedValue>
              </enumeratedValues>
            </field>
            <field>
              <name>IRQC</name>
              <description>Interrupt Configuration</description>
              <bitOffset>16</bitOffset>
              <bitWidth>4</bitWidth>
              <access>read-write</access>
              <enumeratedValues>
                <enumeratedValue>
                  <name>0000</name>
                  <description>Interrupt/DMA request disabled.</description>
                  <value>#0000</value>
                </enumeratedValue>
                <enumeratedValue>
                  <name>0001</name>
                  <description>DMA request on rising edge.</description>
                  <value>#0001</value>
                </enumeratedValue>
                <enumeratedValue>
                  <name>0010</name>
                  <description>DMA request on falling edge.</description>
                  <value>#0010</value>
                </enumeratedValue>
                <enumeratedValue>
                  <name>0011</name>
                  <description>DMA request on either edge.</description>
                  <value>#0011</value>
                </enumeratedValue>
                <enumeratedValue>
                  <name>1000</name>
                  <description>Interrupt when logic 0.</description>
                  <value>#1000</value>
                </enumeratedValue>
                <enumeratedValue>
                  <name>1001</name>
                  <description>Interrupt on rising-edge.</description>
                  <value>#1001</value>
                </enumeratedValue>
                <enumeratedValue>
                  <name>1010</name>
                  <description>Interrupt on falling-edge.</description>
                  <value>#1010</value>
                </enumeratedValue>
                <enumeratedValue>
                  <name>1011</name>
                  <description>Interrupt on either edge.</description>
                  <value>#1011</value>
                </enumeratedValue>
                <enumeratedValue>
                  <name>1100</name>
                  <description>Interrupt when logic 1.</description>
                  <value>#1100</value>
                </enumeratedValue>
              </enumeratedValues>
            </field>
            <field>
              <name>ISF</name>
              <description>Interrupt Status Flag</description>
              <bitOffset>24</bitOffset>
              <bitWidth>1</bitWidth>
              <access>read-write</access>
              <enumeratedValues>
                <enumeratedValue>
                  <name>0</name>
                  <description>Configured interrupt is not detected.</description>
                  <value>#0</value>
                </enumeratedValue>
                <enumeratedValue>
                  <name>1</name>
                  <description>Configured interrupt is detected. If the pin is configured to generate a DMA request, then the corresponding flag will be cleared automatically at the completion of the requested DMA transfer. Otherwise, the flag remains set until a logic 1 is written to the flag. If the pin is configured for a level sensitive interrupt and the pin remains asserted, then the flag is set again immediately after it is cleared.</description>
                  <value>#1</value>
                </enumeratedValue>
              </enumeratedValues>
            </field>
          </fields>
        </register>
        <register>
          <name>PCR6</name>
          <description>Pin Control Register n</description>
          <addressOffset>0x18</addressOffset>
          <size>32</size>
          <access>read-write</access>
          <resetValue>0x1</resetValue>
          <resetMask>0xFFFFFFFF</resetMask>
          <fields>
            <field>
              <name>PS</name>
              <description>Pull Select</description>
              <bitOffset>0</bitOffset>
              <bitWidth>1</bitWidth>
              <access>read-write</access>
              <enumeratedValues>
                <enumeratedValue>
                  <name>0</name>
                  <description>Internal pulldown resistor is enabled on the corresponding pin, if the corresponding PE field is set.</description>
                  <value>#0</value>
                </enumeratedValue>
                <enumeratedValue>
                  <name>1</name>
                  <description>Internal pullup resistor is enabled on the corresponding pin, if the corresponding PE field is set.</description>
                  <value>#1</value>
                </enumeratedValue>
              </enumeratedValues>
            </field>
            <field>
              <name>PE</name>
              <description>Pull Enable</description>
              <bitOffset>1</bitOffset>
              <bitWidth>1</bitWidth>
              <access>read-write</access>
              <enumeratedValues>
                <enumeratedValue>
                  <name>0</name>
                  <description>Internal pullup or pulldown resistor is not enabled on the corresponding pin.</description>
                  <value>#0</value>
                </enumeratedValue>
                <enumeratedValue>
                  <name>1</name>
                  <description>Internal pullup or pulldown resistor is enabled on the corresponding pin, if the pin is configured as a digital input.</description>
                  <value>#1</value>
                </enumeratedValue>
              </enumeratedValues>
            </field>
            <field>
              <name>SRE</name>
              <description>Slew Rate Enable</description>
              <bitOffset>2</bitOffset>
              <bitWidth>1</bitWidth>
              <access>read-write</access>
              <enumeratedValues>
                <enumeratedValue>
                  <name>0</name>
                  <description>Fast slew rate is configured on the corresponding pin, if the pin is configured as a digital output.</description>
                  <value>#0</value>
                </enumeratedValue>
                <enumeratedValue>
                  <name>1</name>
                  <description>Slow slew rate is configured on the corresponding pin, if the pin is configured as a digital output.</description>
                  <value>#1</value>
                </enumeratedValue>
              </enumeratedValues>
            </field>
            <field>
              <name>PFE</name>
              <description>Passive Filter Enable</description>
              <bitOffset>4</bitOffset>
              <bitWidth>1</bitWidth>
              <access>read-only</access>
              <enumeratedValues>
                <enumeratedValue>
                  <name>0</name>
                  <description>Passive input filter is disabled on the corresponding pin.</description>
                  <value>#0</value>
                </enumeratedValue>
                <enumeratedValue>
                  <name>1</name>
                  <description>Passive input filter is enabled on the corresponding pin, if the pin is configured as a digital input. Refer to the device data sheet for filter characteristics.</description>
                  <value>#1</value>
                </enumeratedValue>
              </enumeratedValues>
            </field>
            <field>
              <name>DSE</name>
              <description>Drive Strength Enable</description>
              <bitOffset>6</bitOffset>
              <bitWidth>1</bitWidth>
              <access>read-only</access>
              <enumeratedValues>
                <enumeratedValue>
                  <name>0</name>
                  <description>Low drive strength is configured on the corresponding pin, if pin is configured as a digital output.</description>
                  <value>#0</value>
                </enumeratedValue>
                <enumeratedValue>
                  <name>1</name>
                  <description>High drive strength is configured on the corresponding pin, if pin is configured as a digital output.</description>
                  <value>#1</value>
                </enumeratedValue>
              </enumeratedValues>
            </field>
            <field>
              <name>MUX</name>
              <description>Pin Mux Control</description>
              <bitOffset>8</bitOffset>
              <bitWidth>3</bitWidth>
              <access>read-write</access>
              <enumeratedValues>
                <enumeratedValue>
                  <name>000</name>
                  <description>Pin disabled (analog).</description>
                  <value>#000</value>
                </enumeratedValue>
                <enumeratedValue>
                  <name>001</name>
                  <description>Alternative 1 (GPIO).</description>
                  <value>#001</value>
                </enumeratedValue>
                <enumeratedValue>
                  <name>010</name>
                  <description>Alternative 2 (chip-specific).</description>
                  <value>#010</value>
                </enumeratedValue>
                <enumeratedValue>
                  <name>011</name>
                  <description>Alternative 3 (chip-specific).</description>
                  <value>#011</value>
                </enumeratedValue>
                <enumeratedValue>
                  <name>100</name>
                  <description>Alternative 4 (chip-specific).</description>
                  <value>#100</value>
                </enumeratedValue>
                <enumeratedValue>
                  <name>101</name>
                  <description>Alternative 5 (chip-specific).</description>
                  <value>#101</value>
                </enumeratedValue>
                <enumeratedValue>
                  <name>110</name>
                  <description>Alternative 6 (chip-specific).</description>
                  <value>#110</value>
                </enumeratedValue>
                <enumeratedValue>
                  <name>111</name>
                  <description>Alternative 7 (chip-specific).</description>
                  <value>#111</value>
                </enumeratedValue>
              </enumeratedValues>
            </field>
            <field>
              <name>IRQC</name>
              <description>Interrupt Configuration</description>
              <bitOffset>16</bitOffset>
              <bitWidth>4</bitWidth>
              <access>read-write</access>
              <enumeratedValues>
                <enumeratedValue>
                  <name>0000</name>
                  <description>Interrupt/DMA request disabled.</description>
                  <value>#0000</value>
                </enumeratedValue>
                <enumeratedValue>
                  <name>0001</name>
                  <description>DMA request on rising edge.</description>
                  <value>#0001</value>
                </enumeratedValue>
                <enumeratedValue>
                  <name>0010</name>
                  <description>DMA request on falling edge.</description>
                  <value>#0010</value>
                </enumeratedValue>
                <enumeratedValue>
                  <name>0011</name>
                  <description>DMA request on either edge.</description>
                  <value>#0011</value>
                </enumeratedValue>
                <enumeratedValue>
                  <name>1000</name>
                  <description>Interrupt when logic 0.</description>
                  <value>#1000</value>
                </enumeratedValue>
                <enumeratedValue>
                  <name>1001</name>
                  <description>Interrupt on rising-edge.</description>
                  <value>#1001</value>
                </enumeratedValue>
                <enumeratedValue>
                  <name>1010</name>
                  <description>Interrupt on falling-edge.</description>
                  <value>#1010</value>
                </enumeratedValue>
                <enumeratedValue>
                  <name>1011</name>
                  <description>Interrupt on either edge.</description>
                  <value>#1011</value>
                </enumeratedValue>
                <enumeratedValue>
                  <name>1100</name>
                  <description>Interrupt when logic 1.</description>
                  <value>#1100</value>
                </enumeratedValue>
              </enumeratedValues>
            </field>
            <field>
              <name>ISF</name>
              <description>Interrupt Status Flag</description>
              <bitOffset>24</bitOffset>
              <bitWidth>1</bitWidth>
              <access>read-write</access>
              <enumeratedValues>
                <enumeratedValue>
                  <name>0</name>
                  <description>Configured interrupt is not detected.</description>
                  <value>#0</value>
                </enumeratedValue>
                <enumeratedValue>
                  <name>1</name>
                  <description>Configured interrupt is detected. If the pin is configured to generate a DMA request, then the corresponding flag will be cleared automatically at the completion of the requested DMA transfer. Otherwise, the flag remains set until a logic 1 is written to the flag. If the pin is configured for a level sensitive interrupt and the pin remains asserted, then the flag is set again immediately after it is cleared.</description>
                  <value>#1</value>
                </enumeratedValue>
              </enumeratedValues>
            </field>
          </fields>
        </register>
        <register>
          <name>PCR7</name>
          <description>Pin Control Register n</description>
          <addressOffset>0x1C</addressOffset>
          <size>32</size>
          <access>read-write</access>
          <resetValue>0x1</resetValue>
          <resetMask>0xFFFFFFFF</resetMask>
          <fields>
            <field>
              <name>PS</name>
              <description>Pull Select</description>
              <bitOffset>0</bitOffset>
              <bitWidth>1</bitWidth>
              <access>read-write</access>
              <enumeratedValues>
                <enumeratedValue>
                  <name>0</name>
                  <description>Internal pulldown resistor is enabled on the corresponding pin, if the corresponding PE field is set.</description>
                  <value>#0</value>
                </enumeratedValue>
                <enumeratedValue>
                  <name>1</name>
                  <description>Internal pullup resistor is enabled on the corresponding pin, if the corresponding PE field is set.</description>
                  <value>#1</value>
                </enumeratedValue>
              </enumeratedValues>
            </field>
            <field>
              <name>PE</name>
              <description>Pull Enable</description>
              <bitOffset>1</bitOffset>
              <bitWidth>1</bitWidth>
              <access>read-write</access>
              <enumeratedValues>
                <enumeratedValue>
                  <name>0</name>
                  <description>Internal pullup or pulldown resistor is not enabled on the corresponding pin.</description>
                  <value>#0</value>
                </enumeratedValue>
                <enumeratedValue>
                  <name>1</name>
                  <description>Internal pullup or pulldown resistor is enabled on the corresponding pin, if the pin is configured as a digital input.</description>
                  <value>#1</value>
                </enumeratedValue>
              </enumeratedValues>
            </field>
            <field>
              <name>SRE</name>
              <description>Slew Rate Enable</description>
              <bitOffset>2</bitOffset>
              <bitWidth>1</bitWidth>
              <access>read-write</access>
              <enumeratedValues>
                <enumeratedValue>
                  <name>0</name>
                  <description>Fast slew rate is configured on the corresponding pin, if the pin is configured as a digital output.</description>
                  <value>#0</value>
                </enumeratedValue>
                <enumeratedValue>
                  <name>1</name>
                  <description>Slow slew rate is configured on the corresponding pin, if the pin is configured as a digital output.</description>
                  <value>#1</value>
                </enumeratedValue>
              </enumeratedValues>
            </field>
            <field>
              <name>PFE</name>
              <description>Passive Filter Enable</description>
              <bitOffset>4</bitOffset>
              <bitWidth>1</bitWidth>
              <access>read-only</access>
              <enumeratedValues>
                <enumeratedValue>
                  <name>0</name>
                  <description>Passive input filter is disabled on the corresponding pin.</description>
                  <value>#0</value>
                </enumeratedValue>
                <enumeratedValue>
                  <name>1</name>
                  <description>Passive input filter is enabled on the corresponding pin, if the pin is configured as a digital input. Refer to the device data sheet for filter characteristics.</description>
                  <value>#1</value>
                </enumeratedValue>
              </enumeratedValues>
            </field>
            <field>
              <name>DSE</name>
              <description>Drive Strength Enable</description>
              <bitOffset>6</bitOffset>
              <bitWidth>1</bitWidth>
              <access>read-only</access>
              <enumeratedValues>
                <enumeratedValue>
                  <name>0</name>
                  <description>Low drive strength is configured on the corresponding pin, if pin is configured as a digital output.</description>
                  <value>#0</value>
                </enumeratedValue>
                <enumeratedValue>
                  <name>1</name>
                  <description>High drive strength is configured on the corresponding pin, if pin is configured as a digital output.</description>
                  <value>#1</value>
                </enumeratedValue>
              </enumeratedValues>
            </field>
            <field>
              <name>MUX</name>
              <description>Pin Mux Control</description>
              <bitOffset>8</bitOffset>
              <bitWidth>3</bitWidth>
              <access>read-write</access>
              <enumeratedValues>
                <enumeratedValue>
                  <name>000</name>
                  <description>Pin disabled (analog).</description>
                  <value>#000</value>
                </enumeratedValue>
                <enumeratedValue>
                  <name>001</name>
                  <description>Alternative 1 (GPIO).</description>
                  <value>#001</value>
                </enumeratedValue>
                <enumeratedValue>
                  <name>010</name>
                  <description>Alternative 2 (chip-specific).</description>
                  <value>#010</value>
                </enumeratedValue>
                <enumeratedValue>
                  <name>011</name>
                  <description>Alternative 3 (chip-specific).</description>
                  <value>#011</value>
                </enumeratedValue>
                <enumeratedValue>
                  <name>100</name>
                  <description>Alternative 4 (chip-specific).</description>
                  <value>#100</value>
                </enumeratedValue>
                <enumeratedValue>
                  <name>101</name>
                  <description>Alternative 5 (chip-specific).</description>
                  <value>#101</value>
                </enumeratedValue>
                <enumeratedValue>
                  <name>110</name>
                  <description>Alternative 6 (chip-specific).</description>
                  <value>#110</value>
                </enumeratedValue>
                <enumeratedValue>
                  <name>111</name>
                  <description>Alternative 7 (chip-specific).</description>
                  <value>#111</value>
                </enumeratedValue>
              </enumeratedValues>
            </field>
            <field>
              <name>IRQC</name>
              <description>Interrupt Configuration</description>
              <bitOffset>16</bitOffset>
              <bitWidth>4</bitWidth>
              <access>read-write</access>
              <enumeratedValues>
                <enumeratedValue>
                  <name>0000</name>
                  <description>Interrupt/DMA request disabled.</description>
                  <value>#0000</value>
                </enumeratedValue>
                <enumeratedValue>
                  <name>0001</name>
                  <description>DMA request on rising edge.</description>
                  <value>#0001</value>
                </enumeratedValue>
                <enumeratedValue>
                  <name>0010</name>
                  <description>DMA request on falling edge.</description>
                  <value>#0010</value>
                </enumeratedValue>
                <enumeratedValue>
                  <name>0011</name>
                  <description>DMA request on either edge.</description>
                  <value>#0011</value>
                </enumeratedValue>
                <enumeratedValue>
                  <name>1000</name>
                  <description>Interrupt when logic 0.</description>
                  <value>#1000</value>
                </enumeratedValue>
                <enumeratedValue>
                  <name>1001</name>
                  <description>Interrupt on rising-edge.</description>
                  <value>#1001</value>
                </enumeratedValue>
                <enumeratedValue>
                  <name>1010</name>
                  <description>Interrupt on falling-edge.</description>
                  <value>#1010</value>
                </enumeratedValue>
                <enumeratedValue>
                  <name>1011</name>
                  <description>Interrupt on either edge.</description>
                  <value>#1011</value>
                </enumeratedValue>
                <enumeratedValue>
                  <name>1100</name>
                  <description>Interrupt when logic 1.</description>
                  <value>#1100</value>
                </enumeratedValue>
              </enumeratedValues>
            </field>
            <field>
              <name>ISF</name>
              <description>Interrupt Status Flag</description>
              <bitOffset>24</bitOffset>
              <bitWidth>1</bitWidth>
              <access>read-write</access>
              <enumeratedValues>
                <enumeratedValue>
                  <name>0</name>
                  <description>Configured interrupt is not detected.</description>
                  <value>#0</value>
                </enumeratedValue>
                <enumeratedValue>
                  <name>1</name>
                  <description>Configured interrupt is detected. If the pin is configured to generate a DMA request, then the corresponding flag will be cleared automatically at the completion of the requested DMA transfer. Otherwise, the flag remains set until a logic 1 is written to the flag. If the pin is configured for a level sensitive interrupt and the pin remains asserted, then the flag is set again immediately after it is cleared.</description>
                  <value>#1</value>
                </enumeratedValue>
              </enumeratedValues>
            </field>
          </fields>
        </register>
        <register>
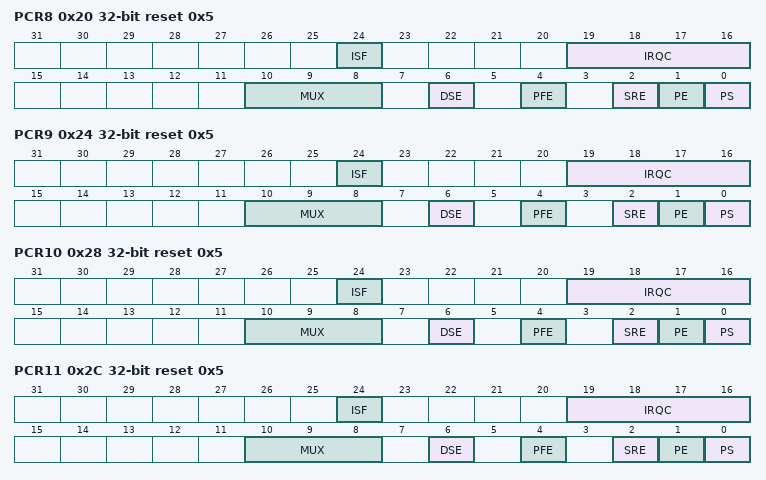
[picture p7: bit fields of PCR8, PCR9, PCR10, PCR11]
          <name>PCR8</name>
          <description>Pin Control Register n</description>
          <addressOffset>0x20</addressOffset>
          <size>32</size>
          <access>read-write</access>
          <resetValue>0x5</resetValue>
          <resetMask>0xFFFFFFFF</resetMask>
          <fields>
            <field>
              <name>PS</name>
              <description>Pull Select</description>
              <bitOffset>0</bitOffset>
              <bitWidth>1</bitWidth>
              <access>read-write</access>
              <enumeratedValues>
                <enumeratedValue>
                  <name>0</name>
                  <description>Internal pulldown resistor is enabled on the corresponding pin, if the corresponding PE field is set.</description>
                  <value>#0</value>
                </enumeratedValue>
                <enumeratedValue>
                  <name>1</name>
                  <description>Internal pullup resistor is enabled on the corresponding pin, if the corresponding PE field is set.</description>
                  <value>#1</value>
                </enumeratedValue>
              </enumeratedValues>
            </field>
            <field>
              <name>PE</name>
              <description>Pull Enable</description>
              <bitOffset>1</bitOffset>
              <bitWidth>1</bitWidth>
              <access>read-write</access>
              <enumeratedValues>
                <enumeratedValue>
                  <name>0</name>
                  <description>Internal pullup or pulldown resistor is not enabled on the corresponding pin.</description>
                  <value>#0</value>
                </enumeratedValue>
                <enumeratedValue>
                  <name>1</name>
                  <description>Internal pullup or pulldown resistor is enabled on the corresponding pin, if the pin is configured as a digital input.</description>
                  <value>#1</value>
                </enumeratedValue>
              </enumeratedValues>
            </field>
            <field>
              <name>SRE</name>
              <description>Slew Rate Enable</description>
              <bitOffset>2</bitOffset>
              <bitWidth>1</bitWidth>
              <access>read-write</access>
              <enumeratedValues>
                <enumeratedValue>
                  <name>0</name>
                  <description>Fast slew rate is configured on the corresponding pin, if the pin is configured as a digital output.</description>
                  <value>#0</value>
                </enumeratedValue>
                <enumeratedValue>
                  <name>1</name>
                  <description>Slow slew rate is configured on the corresponding pin, if the pin is configured as a digital output.</description>
                  <value>#1</value>
                </enumeratedValue>
              </enumeratedValues>
            </field>
            <field>
              <name>PFE</name>
              <description>Passive Filter Enable</description>
              <bitOffset>4</bitOffset>
              <bitWidth>1</bitWidth>
              <access>read-only</access>
              <enumeratedValues>
                <enumeratedValue>
                  <name>0</name>
                  <description>Passive input filter is disabled on the corresponding pin.</description>
                  <value>#0</value>
                </enumeratedValue>
                <enumeratedValue>
                  <name>1</name>
                  <description>Passive input filter is enabled on the corresponding pin, if the pin is configured as a digital input. Refer to the device data sheet for filter characteristics.</description>
                  <value>#1</value>
                </enumeratedValue>
              </enumeratedValues>
            </field>
            <field>
              <name>DSE</name>
              <description>Drive Strength Enable</description>
              <bitOffset>6</bitOffset>
              <bitWidth>1</bitWidth>
              <access>read-only</access>
              <enumeratedValues>
                <enumeratedValue>
                  <name>0</name>
                  <description>Low drive strength is configured on the corresponding pin, if pin is configured as a digital output.</description>
                  <value>#0</value>
                </enumeratedValue>
                <enumeratedValue>
                  <name>1</name>
                  <description>High drive strength is configured on the corresponding pin, if pin is configured as a digital output.</description>
                  <value>#1</value>
                </enumeratedValue>
              </enumeratedValues>
            </field>
            <field>
              <name>MUX</name>
              <description>Pin Mux Control</description>
              <bitOffset>8</bitOffset>
              <bitWidth>3</bitWidth>
              <access>read-write</access>
              <enumeratedValues>
                <enumeratedValue>
                  <name>000</name>
                  <description>Pin disabled (analog).</description>
                  <value>#000</value>
                </enumeratedValue>
                <enumeratedValue>
                  <name>001</name>
                  <description>Alternative 1 (GPIO).</description>
                  <value>#001</value>
                </enumeratedValue>
                <enumeratedValue>
                  <name>010</name>
                  <description>Alternative 2 (chip-specific).</description>
                  <value>#010</value>
                </enumeratedValue>
                <enumeratedValue>
                  <name>011</name>
                  <description>Alternative 3 (chip-specific).</description>
                  <value>#011</value>
                </enumeratedValue>
                <enumeratedValue>
                  <name>100</name>
                  <description>Alternative 4 (chip-specific).</description>
                  <value>#100</value>
                </enumeratedValue>
                <enumeratedValue>
                  <name>101</name>
                  <description>Alternative 5 (chip-specific).</description>
                  <value>#101</value>
                </enumeratedValue>
                <enumeratedValue>
                  <name>110</name>
                  <description>Alternative 6 (chip-specific).</description>
                  <value>#110</value>
                </enumeratedValue>
                <enumeratedValue>
                  <name>111</name>
                  <description>Alternative 7 (chip-specific).</description>
                  <value>#111</value>
                </enumeratedValue>
              </enumeratedValues>
            </field>
            <field>
              <name>IRQC</name>
              <description>Interrupt Configuration</description>
              <bitOffset>16</bitOffset>
              <bitWidth>4</bitWidth>
              <access>read-write</access>
              <enumeratedValues>
                <enumeratedValue>
                  <name>0000</name>
                  <description>Interrupt/DMA request disabled.</description>
                  <value>#0000</value>
                </enumeratedValue>
                <enumeratedValue>
                  <name>0001</name>
                  <description>DMA request on rising edge.</description>
                  <value>#0001</value>
                </enumeratedValue>
                <enumeratedValue>
                  <name>0010</name>
                  <description>DMA request on falling edge.</description>
                  <value>#0010</value>
                </enumeratedValue>
                <enumeratedValue>
                  <name>0011</name>
                  <description>DMA request on either edge.</description>
                  <value>#0011</value>
                </enumeratedValue>
                <enumeratedValue>
                  <name>1000</name>
                  <description>Interrupt when logic 0.</description>
                  <value>#1000</value>
                </enumeratedValue>
                <enumeratedValue>
                  <name>1001</name>
                  <description>Interrupt on rising-edge.</description>
                  <value>#1001</value>
                </enumeratedValue>
                <enumeratedValue>
                  <name>1010</name>
                  <description>Interrupt on falling-edge.</description>
                  <value>#1010</value>
                </enumeratedValue>
                <enumeratedValue>
                  <name>1011</name>
                  <description>Interrupt on either edge.</description>
                  <value>#1011</value>
                </enumeratedValue>
                <enumeratedValue>
                  <name>1100</name>
                  <description>Interrupt when logic 1.</description>
                  <value>#1100</value>
                </enumeratedValue>
              </enumeratedValues>
            </field>
            <field>
              <name>ISF</name>
              <description>Interrupt Status Flag</description>
              <bitOffset>24</bitOffset>
              <bitWidth>1</bitWidth>
              <access>read-write</access>
              <enumeratedValues>
                <enumeratedValue>
                  <name>0</name>
                  <description>Configured interrupt is not detected.</description>
                  <value>#0</value>
                </enumeratedValue>
                <enumeratedValue>
                  <name>1</name>
                  <description>Configured interrupt is detected. If the pin is configured to generate a DMA request, then the corresponding flag will be cleared automatically at the completion of the requested DMA transfer. Otherwise, the flag remains set until a logic 1 is written to the flag. If the pin is configured for a level sensitive interrupt and the pin remains asserted, then the flag is set again immediately after it is cleared.</description>
                  <value>#1</value>
                </enumeratedValue>
              </enumeratedValues>
            </field>
          </fields>
        </register>
        <register>
          <name>PCR9</name>
          <description>Pin Control Register n</description>
          <addressOffset>0x24</addressOffset>
          <size>32</size>
          <access>read-write</access>
          <resetValue>0x5</resetValue>
          <resetMask>0xFFFFFFFF</resetMask>
          <fields>
            <field>
              <name>PS</name>
              <description>Pull Select</description>
              <bitOffset>0</bitOffset>
              <bitWidth>1</bitWidth>
              <access>read-write</access>
              <enumeratedValues>
                <enumeratedValue>
                  <name>0</name>
                  <description>Internal pulldown resistor is enabled on the corresponding pin, if the corresponding PE field is set.</description>
                  <value>#0</value>
                </enumeratedValue>
                <enumeratedValue>
                  <name>1</name>
                  <description>Internal pullup resistor is enabled on the corresponding pin, if the corresponding PE field is set.</description>
                  <value>#1</value>
                </enumeratedValue>
              </enumeratedValues>
            </field>
            <field>
              <name>PE</name>
              <description>Pull Enable</description>
              <bitOffset>1</bitOffset>
              <bitWidth>1</bitWidth>
              <access>read-write</access>
              <enumeratedValues>
                <enumeratedValue>
                  <name>0</name>
                  <description>Internal pullup or pulldown resistor is not enabled on the corresponding pin.</description>
                  <value>#0</value>
                </enumeratedValue>
                <enumeratedValue>
                  <name>1</name>
                  <description>Internal pullup or pulldown resistor is enabled on the corresponding pin, if the pin is configured as a digital input.</description>
                  <value>#1</value>
                </enumeratedValue>
              </enumeratedValues>
            </field>
            <field>
              <name>SRE</name>
              <description>Slew Rate Enable</description>
              <bitOffset>2</bitOffset>
              <bitWidth>1</bitWidth>
              <access>read-write</access>
              <enumeratedValues>
                <enumeratedValue>
                  <name>0</name>
                  <description>Fast slew rate is configured on the corresponding pin, if the pin is configured as a digital output.</description>
                  <value>#0</value>
                </enumeratedValue>
                <enumeratedValue>
                  <name>1</name>
                  <description>Slow slew rate is configured on the corresponding pin, if the pin is configured as a digital output.</description>
                  <value>#1</value>
                </enumeratedValue>
              </enumeratedValues>
            </field>
            <field>
              <name>PFE</name>
              <description>Passive Filter Enable</description>
              <bitOffset>4</bitOffset>
              <bitWidth>1</bitWidth>
              <access>read-only</access>
              <enumeratedValues>
                <enumeratedValue>
                  <name>0</name>
                  <description>Passive input filter is disabled on the corresponding pin.</description>
                  <value>#0</value>
                </enumeratedValue>
                <enumeratedValue>
                  <name>1</name>
                  <description>Passive input filter is enabled on the corresponding pin, if the pin is configured as a digital input. Refer to the device data sheet for filter characteristics.</description>
                  <value>#1</value>
                </enumeratedValue>
              </enumeratedValues>
            </field>
            <field>
              <name>DSE</name>
              <description>Drive Strength Enable</description>
              <bitOffset>6</bitOffset>
              <bitWidth>1</bitWidth>
              <access>read-only</access>
              <enumeratedValues>
                <enumeratedValue>
                  <name>0</name>
                  <description>Low drive strength is configured on the corresponding pin, if pin is configured as a digital output.</description>
                  <value>#0</value>
                </enumeratedValue>
                <enumeratedValue>
                  <name>1</name>
                  <description>High drive strength is configured on the corresponding pin, if pin is configured as a digital output.</description>
                  <value>#1</value>
                </enumeratedValue>
              </enumeratedValues>
            </field>
            <field>
              <name>MUX</name>
              <description>Pin Mux Control</description>
              <bitOffset>8</bitOffset>
              <bitWidth>3</bitWidth>
              <access>read-write</access>
              <enumeratedValues>
                <enumeratedValue>
                  <name>000</name>
                  <description>Pin disabled (analog).</description>
                  <value>#000</value>
                </enumeratedValue>
                <enumeratedValue>
                  <name>001</name>
                  <description>Alternative 1 (GPIO).</description>
                  <value>#001</value>
                </enumeratedValue>
                <enumeratedValue>
                  <name>010</name>
                  <description>Alternative 2 (chip-specific).</description>
                  <value>#010</value>
                </enumeratedValue>
                <enumeratedValue>
                  <name>011</name>
                  <description>Alternative 3 (chip-specific).</description>
                  <value>#011</value>
                </enumeratedValue>
                <enumeratedValue>
                  <name>100</name>
                  <description>Alternative 4 (chip-specific).</description>
                  <value>#100</value>
                </enumeratedValue>
                <enumeratedValue>
                  <name>101</name>
                  <description>Alternative 5 (chip-specific).</description>
                  <value>#101</value>
                </enumeratedValue>
                <enumeratedValue>
                  <name>110</name>
                  <description>Alternative 6 (chip-specific).</description>
                  <value>#110</value>
                </enumeratedValue>
                <enumeratedValue>
                  <name>111</name>
                  <description>Alternative 7 (chip-specific).</description>
                  <value>#111</value>
                </enumeratedValue>
              </enumeratedValues>
            </field>
            <field>
              <name>IRQC</name>
              <description>Interrupt Configuration</description>
              <bitOffset>16</bitOffset>
              <bitWidth>4</bitWidth>
              <access>read-write</access>
              <enumeratedValues>
                <enumeratedValue>
                  <name>0000</name>
                  <description>Interrupt/DMA request disabled.</description>
                  <value>#0000</value>
                </enumeratedValue>
                <enumeratedValue>
                  <name>0001</name>
                  <description>DMA request on rising edge.</description>
                  <value>#0001</value>
                </enumeratedValue>
                <enumeratedValue>
                  <name>0010</name>
                  <description>DMA request on falling edge.</description>
                  <value>#0010</value>
                </enumeratedValue>
                <enumeratedValue>
                  <name>0011</name>
                  <description>DMA request on either edge.</description>
                  <value>#0011</value>
                </enumeratedValue>
                <enumeratedValue>
                  <name>1000</name>
                  <description>Interrupt when logic 0.</description>
                  <value>#1000</value>
                </enumeratedValue>
                <enumeratedValue>
                  <name>1001</name>
                  <description>Interrupt on rising-edge.</description>
                  <value>#1001</value>
                </enumeratedValue>
                <enumeratedValue>
                  <name>1010</name>
                  <description>Interrupt on falling-edge.</description>
                  <value>#1010</value>
                </enumeratedValue>
                <enumeratedValue>
                  <name>1011</name>
                  <description>Interrupt on either edge.</description>
                  <value>#1011</value>
                </enumeratedValue>
                <enumeratedValue>
                  <name>1100</name>
                  <description>Interrupt when logic 1.</description>
                  <value>#1100</value>
                </enumeratedValue>
              </enumeratedValues>
            </field>
            <field>
              <name>ISF</name>
              <description>Interrupt Status Flag</description>
              <bitOffset>24</bitOffset>
              <bitWidth>1</bitWidth>
              <access>read-write</access>
              <enumeratedValues>
                <enumeratedValue>
                  <name>0</name>
                  <description>Configured interrupt is not detected.</description>
                  <value>#0</value>
                </enumeratedValue>
                <enumeratedValue>
                  <name>1</name>
                  <description>Configured interrupt is detected. If the pin is configured to generate a DMA request, then the corresponding flag will be cleared automatically at the completion of the requested DMA transfer. Otherwise, the flag remains set until a logic 1 is written to the flag. If the pin is configured for a level sensitive interrupt and the pin remains asserted, then the flag is set again immediately after it is cleared.</description>
                  <value>#1</value>
                </enumeratedValue>
              </enumeratedValues>
            </field>
          </fields>
        </register>
        <register>
          <name>PCR10</name>
          <description>Pin Control Register n</description>
          <addressOffset>0x28</addressOffset>
          <size>32</size>
          <access>read-write</access>
          <resetValue>0x5</resetValue>
          <resetMask>0xFFFFFFFF</resetMask>
          <fields>
            <field>
              <name>PS</name>
              <description>Pull Select</description>
              <bitOffset>0</bitOffset>
              <bitWidth>1</bitWidth>
              <access>read-write</access>
              <enumeratedValues>
                <enumeratedValue>
                  <name>0</name>
                  <description>Internal pulldown resistor is enabled on the corresponding pin, if the corresponding PE field is set.</description>
                  <value>#0</value>
                </enumeratedValue>
                <enumeratedValue>
                  <name>1</name>
                  <description>Internal pullup resistor is enabled on the corresponding pin, if the corresponding PE field is set.</description>
                  <value>#1</value>
                </enumeratedValue>
              </enumeratedValues>
            </field>
            <field>
              <name>PE</name>
              <description>Pull Enable</description>
              <bitOffset>1</bitOffset>
              <bitWidth>1</bitWidth>
              <access>read-write</access>
              <enumeratedValues>
                <enumeratedValue>
                  <name>0</name>
                  <description>Internal pullup or pulldown resistor is not enabled on the corresponding pin.</description>
                  <value>#0</value>
                </enumeratedValue>
                <enumeratedValue>
                  <name>1</name>
                  <description>Internal pullup or pulldown resistor is enabled on the corresponding pin, if the pin is configured as a digital input.</description>
                  <value>#1</value>
                </enumeratedValue>
              </enumeratedValues>
            </field>
            <field>
              <name>SRE</name>
              <description>Slew Rate Enable</description>
              <bitOffset>2</bitOffset>
              <bitWidth>1</bitWidth>
              <access>read-write</access>
              <enumeratedValues>
                <enumeratedValue>
                  <name>0</name>
                  <description>Fast slew rate is configured on the corresponding pin, if the pin is configured as a digital output.</description>
                  <value>#0</value>
                </enumeratedValue>
                <enumeratedValue>
                  <name>1</name>
                  <description>Slow slew rate is configured on the corresponding pin, if the pin is configured as a digital output.</description>
                  <value>#1</value>
                </enumeratedValue>
              </enumeratedValues>
            </field>
            <field>
              <name>PFE</name>
              <description>Passive Filter Enable</description>
              <bitOffset>4</bitOffset>
              <bitWidth>1</bitWidth>
              <access>read-only</access>
              <enumeratedValues>
                <enumeratedValue>
                  <name>0</name>
                  <description>Passive input filter is disabled on the corresponding pin.</description>
                  <value>#0</value>
                </enumeratedValue>
                <enumeratedValue>
                  <name>1</name>
                  <description>Passive input filter is enabled on the corresponding pin, if the pin is configured as a digital input. Refer to the device data sheet for filter characteristics.</description>
                  <value>#1</value>
                </enumeratedValue>
              </enumeratedValues>
            </field>
            <field>
              <name>DSE</name>
              <description>Drive Strength Enable</description>
              <bitOffset>6</bitOffset>
              <bitWidth>1</bitWidth>
              <access>read-only</access>
              <enumeratedValues>
                <enumeratedValue>
                  <name>0</name>
                  <description>Low drive strength is configured on the corresponding pin, if pin is configured as a digital output.</description>
                  <value>#0</value>
                </enumeratedValue>
                <enumeratedValue>
                  <name>1</name>
                  <description>High drive strength is configured on the corresponding pin, if pin is configured as a digital output.</description>
                  <value>#1</value>
                </enumeratedValue>
              </enumeratedValues>
            </field>
            <field>
              <name>MUX</name>
              <description>Pin Mux Control</description>
              <bitOffset>8</bitOffset>
              <bitWidth>3</bitWidth>
              <access>read-write</access>
              <enumeratedValues>
                <enumeratedValue>
                  <name>000</name>
                  <description>Pin disabled (analog).</description>
                  <value>#000</value>
                </enumeratedValue>
                <enumeratedValue>
                  <name>001</name>
                  <description>Alternative 1 (GPIO).</description>
                  <value>#001</value>
                </enumeratedValue>
                <enumeratedValue>
                  <name>010</name>
                  <description>Alternative 2 (chip-specific).</description>
                  <value>#010</value>
                </enumeratedValue>
                <enumeratedValue>
                  <name>011</name>
                  <description>Alternative 3 (chip-specific).</description>
                  <value>#011</value>
                </enumeratedValue>
                <enumeratedValue>
                  <name>100</name>
                  <description>Alternative 4 (chip-specific).</description>
                  <value>#100</value>
                </enumeratedValue>
                <enumeratedValue>
                  <name>101</name>
                  <description>Alternative 5 (chip-specific).</description>
                  <value>#101</value>
                </enumeratedValue>
                <enumeratedValue>
                  <name>110</name>
                  <description>Alternative 6 (chip-specific).</description>
                  <value>#110</value>
                </enumeratedValue>
                <enumeratedValue>
                  <name>111</name>
                  <description>Alternative 7 (chip-specific).</description>
                  <value>#111</value>
                </enumeratedValue>
              </enumeratedValues>
            </field>
            <field>
              <name>IRQC</name>
              <description>Interrupt Configuration</description>
              <bitOffset>16</bitOffset>
              <bitWidth>4</bitWidth>
              <access>read-write</access>
              <enumeratedValues>
                <enumeratedValue>
                  <name>0000</name>
                  <description>Interrupt/DMA request disabled.</description>
                  <value>#0000</value>
                </enumeratedValue>
                <enumeratedValue>
                  <name>0001</name>
                  <description>DMA request on rising edge.</description>
                  <value>#0001</value>
                </enumeratedValue>
                <enumeratedValue>
                  <name>0010</name>
                  <description>DMA request on falling edge.</description>
                  <value>#0010</value>
                </enumeratedValue>
                <enumeratedValue>
                  <name>0011</name>
                  <description>DMA request on either edge.</description>
                  <value>#0011</value>
                </enumeratedValue>
                <enumeratedValue>
                  <name>1000</name>
                  <description>Interrupt when logic 0.</description>
                  <value>#1000</value>
                </enumeratedValue>
                <enumeratedValue>
                  <name>1001</name>
                  <description>Interrupt on rising-edge.</description>
                  <value>#1001</value>
                </enumeratedValue>
                <enumeratedValue>
                  <name>1010</name>
                  <description>Interrupt on falling-edge.</description>
                  <value>#1010</value>
                </enumeratedValue>
                <enumeratedValue>
                  <name>1011</name>
                  <description>Interrupt on either edge.</description>
                  <value>#1011</value>
                </enumeratedValue>
                <enumeratedValue>
                  <name>1100</name>
                  <description>Interrupt when logic 1.</description>
                  <value>#1100</value>
                </enumeratedValue>
              </enumeratedValues>
            </field>
            <field>
              <name>ISF</name>
              <description>Interrupt Status Flag</description>
              <bitOffset>24</bitOffset>
              <bitWidth>1</bitWidth>
              <access>read-write</access>
              <enumeratedValues>
                <enumeratedValue>
                  <name>0</name>
                  <description>Configured interrupt is not detected.</description>
                  <value>#0</value>
                </enumeratedValue>
                <enumeratedValue>
                  <name>1</name>
                  <description>Configured interrupt is detected. If the pin is configured to generate a DMA request, then the corresponding flag will be cleared automatically at the completion of the requested DMA transfer. Otherwise, the flag remains set until a logic 1 is written to the flag. If the pin is configured for a level sensitive interrupt and the pin remains asserted, then the flag is set again immediately after it is cleared.</description>
                  <value>#1</value>
                </enumeratedValue>
              </enumeratedValues>
            </field>
          </fields>
        </register>
        <register>
          <name>PCR11</name>
          <description>Pin Control Register n</description>
          <addressOffset>0x2C</addressOffset>
          <size>32</size>
          <access>read-write</access>
          <resetValue>0x5</resetValue>
          <resetMask>0xFFFFFFFF</resetMask>
          <fields>
            <field>
              <name>PS</name>
              <description>Pull Select</description>
              <bitOffset>0</bitOffset>
              <bitWidth>1</bitWidth>
              <access>read-write</access>
              <enumeratedValues>
                <enumeratedValue>
                  <name>0</name>
                  <description>Internal pulldown resistor is enabled on the corresponding pin, if the corresponding PE field is set.</description>
                  <value>#0</value>
                </enumeratedValue>
                <enumeratedValue>
                  <name>1</name>
                  <description>Internal pullup resistor is enabled on the corresponding pin, if the corresponding PE field is set.</description>
                  <value>#1</value>
                </enumeratedValue>
              </enumeratedValues>
            </field>
            <field>
              <name>PE</name>
              <description>Pull Enable</description>
              <bitOffset>1</bitOffset>
              <bitWidth>1</bitWidth>
              <access>read-write</access>
              <enumeratedValues>
                <enumeratedValue>
                  <name>0</name>
                  <description>Internal pullup or pulldown resistor is not enabled on the corresponding pin.</description>
                  <value>#0</value>
                </enumeratedValue>
                <enumeratedValue>
                  <name>1</name>
                  <description>Internal pullup or pulldown resistor is enabled on the corresponding pin, if the pin is configured as a digital input.</description>
                  <value>#1</value>
                </enumeratedValue>
              </enumeratedValues>
            </field>
            <field>
              <name>SRE</name>
              <description>Slew Rate Enable</description>
              <bitOffset>2</bitOffset>
              <bitWidth>1</bitWidth>
              <access>read-write</access>
              <enumeratedValues>
                <enumeratedValue>
                  <name>0</name>
                  <description>Fast slew rate is configured on the corresponding pin, if the pin is configured as a digital output.</description>
                  <value>#0</value>
                </enumeratedValue>
                <enumeratedValue>
                  <name>1</name>
                  <description>Slow slew rate is configured on the corresponding pin, if the pin is configured as a digital output.</description>
                  <value>#1</value>
                </enumeratedValue>
              </enumeratedValues>
            </field>
            <field>
              <name>PFE</name>
              <description>Passive Filter Enable</description>
              <bitOffset>4</bitOffset>
              <bitWidth>1</bitWidth>
              <access>read-only</access>
              <enumeratedValues>
                <enumeratedValue>
                  <name>0</name>
                  <description>Passive input filter is disabled on the corresponding pin.</description>
                  <value>#0</value>
                </enumeratedValue>
                <enumeratedValue>
                  <name>1</name>
                  <description>Passive input filter is enabled on the corresponding pin, if the pin is configured as a digital input. Refer to the device data sheet for filter characteristics.</description>
                  <value>#1</value>
                </enumeratedValue>
              </enumeratedValues>
            </field>
            <field>
              <name>DSE</name>
              <description>Drive Strength Enable</description>
              <bitOffset>6</bitOffset>
              <bitWidth>1</bitWidth>
              <access>read-only</access>
              <enumeratedValues>
                <enumeratedValue>
                  <name>0</name>
                  <description>Low drive strength is configured on the corresponding pin, if pin is configured as a digital output.</description>
                  <value>#0</value>
                </enumeratedValue>
                <enumeratedValue>
                  <name>1</name>
                  <description>High drive strength is configured on the corresponding pin, if pin is configured as a digital output.</description>
                  <value>#1</value>
                </enumeratedValue>
              </enumeratedValues>
            </field>
            <field>
              <name>MUX</name>
              <description>Pin Mux Control</description>
              <bitOffset>8</bitOffset>
              <bitWidth>3</bitWidth>
              <access>read-write</access>
              <enumeratedValues>
                <enumeratedValue>
                  <name>000</name>
                  <description>Pin disabled (analog).</description>
                  <value>#000</value>
                </enumeratedValue>
                <enumeratedValue>
                  <name>001</name>
                  <description>Alternative 1 (GPIO).</description>
                  <value>#001</value>
                </enumeratedValue>
                <enumeratedValue>
                  <name>010</name>
                  <description>Alternative 2 (chip-specific).</description>
                  <value>#010</value>
                </enumeratedValue>
                <enumeratedValue>
                  <name>011</name>
                  <description>Alternative 3 (chip-specific).</description>
                  <value>#011</value>
                </enumeratedValue>
                <enumeratedValue>
                  <name>100</name>
                  <description>Alternative 4 (chip-specific).</description>
                  <value>#100</value>
                </enumeratedValue>
                <enumeratedValue>
                  <name>101</name>
                  <description>Alternative 5 (chip-specific).</description>
                  <value>#101</value>
                </enumeratedValue>
                <enumeratedValue>
                  <name>110</name>
                  <description>Alternative 6 (chip-specific).</description>
                  <value>#110</value>
                </enumeratedValue>
                <enumeratedValue>
                  <name>111</name>
                  <description>Alternative 7 (chip-specific).</description>
                  <value>#111</value>
                </enumeratedValue>
              </enumeratedValues>
            </field>
            <field>
              <name>IRQC</name>
              <description>Interrupt Configuration</description>
              <bitOffset>16</bitOffset>
              <bitWidth>4</bitWidth>
              <access>read-write</access>
              <enumeratedValues>
                <enumeratedValue>
                  <name>0000</name>
                  <description>Interrupt/DMA request disabled.</description>
                  <value>#0000</value>
                </enumeratedValue>
                <enumeratedValue>
                  <name>0001</name>
                  <description>DMA request on rising edge.</description>
                  <value>#0001</value>
                </enumeratedValue>
                <enumeratedValue>
                  <name>0010</name>
                  <description>DMA request on falling edge.</description>
                  <value>#0010</value>
                </enumeratedValue>
                <enumeratedValue>
                  <name>0011</name>
                  <description>DMA request on either edge.</description>
                  <value>#0011</value>
                </enumeratedValue>
                <enumeratedValue>
                  <name>1000</name>
                  <description>Interrupt when logic 0.</description>
                  <value>#1000</value>
                </enumeratedValue>
                <enumeratedValue>
                  <name>1001</name>
                  <description>Interrupt on rising-edge.</description>
                  <value>#1001</value>
                </enumeratedValue>
                <enumeratedValue>
                  <name>1010</name>
                  <description>Interrupt on falling-edge.</description>
                  <value>#1010</value>
                </enumeratedValue>
                <enumeratedValue>
                  <name>1011</name>
                  <description>Interrupt on either edge.</description>
                  <value>#1011</value>
                </enumeratedValue>
                <enumeratedValue>
                  <name>1100</name>
                  <description>Interrupt when logic 1.</description>
                  <value>#1100</value>
                </enumeratedValue>
              </enumeratedValues>
            </field>
            <field>
              <name>ISF</name>
              <description>Interrupt Status Flag</description>
              <bitOffset>24</bitOffset>
              <bitWidth>1</bitWidth>
              <access>read-write</access>
              <enumeratedValues>
                <enumeratedValue>
                  <name>0</name>
                  <description>Configured interrupt is not detected.</description>
                  <value>#0</value>
                </enumeratedValue>
                <enumeratedValue>
                  <name>1</name>
                  <description>Configured interrupt is detected. If the pin is configured to generate a DMA request, then the corresponding flag will be cleared automatically at the completion of the requested DMA transfer. Otherwise, the flag remains set until a logic 1 is written to the flag. If the pin is configured for a level sensitive interrupt and the pin remains asserted, then the flag is set again immediately after it is cleared.</description>
                  <value>#1</value>
                </enumeratedValue>
              </enumeratedValues>
            </field>
          </fields>
        </register>
        <register>
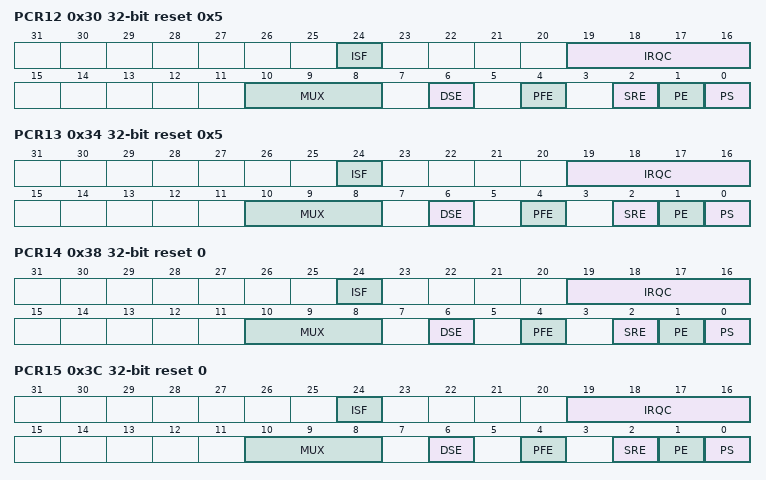
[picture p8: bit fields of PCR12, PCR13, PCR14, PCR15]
          <name>PCR12</name>
          <description>Pin Control Register n</description>
          <addressOffset>0x30</addressOffset>
          <size>32</size>
          <access>read-write</access>
          <resetValue>0x5</resetValue>
          <resetMask>0xFFFFFFFF</resetMask>
          <fields>
            <field>
              <name>PS</name>
              <description>Pull Select</description>
              <bitOffset>0</bitOffset>
              <bitWidth>1</bitWidth>
              <access>read-only</access>
              <enumeratedValues>
                <enumeratedValue>
                  <name>0</name>
                  <description>Internal pulldown resistor is enabled on the corresponding pin, if the corresponding PE field is set.</description>
                  <value>#0</value>
                </enumeratedValue>
                <enumeratedValue>
                  <name>1</name>
                  <description>Internal pullup resistor is enabled on the corresponding pin, if the corresponding PE field is set.</description>
                  <value>#1</value>
                </enumeratedValue>
              </enumeratedValues>
            </field>
            <field>
              <name>PE</name>
              <description>Pull Enable</description>
              <bitOffset>1</bitOffset>
              <bitWidth>1</bitWidth>
              <access>read-only</access>
              <enumeratedValues>
                <enumeratedValue>
                  <name>0</name>
                  <description>Internal pullup or pulldown resistor is not enabled on the corresponding pin.</description>
                  <value>#0</value>
                </enumeratedValue>
                <enumeratedValue>
                  <name>1</name>
                  <description>Internal pullup or pulldown resistor is enabled on the corresponding pin, if the pin is configured as a digital input.</description>
                  <value>#1</value>
                </enumeratedValue>
              </enumeratedValues>
            </field>
            <field>
              <name>SRE</name>
              <description>Slew Rate Enable</description>
              <bitOffset>2</bitOffset>
              <bitWidth>1</bitWidth>
              <access>read-only</access>
              <enumeratedValues>
                <enumeratedValue>
                  <name>0</name>
                  <description>Fast slew rate is configured on the corresponding pin, if the pin is configured as a digital output.</description>
                  <value>#0</value>
                </enumeratedValue>
                <enumeratedValue>
                  <name>1</name>
                  <description>Slow slew rate is configured on the corresponding pin, if the pin is configured as a digital output.</description>
                  <value>#1</value>
                </enumeratedValue>
              </enumeratedValues>
            </field>
            <field>
              <name>PFE</name>
              <description>Passive Filter Enable</description>
              <bitOffset>4</bitOffset>
              <bitWidth>1</bitWidth>
              <access>read-only</access>
              <enumeratedValues>
                <enumeratedValue>
                  <name>0</name>
                  <description>Passive input filter is disabled on the corresponding pin.</description>
                  <value>#0</value>
                </enumeratedValue>
                <enumeratedValue>
                  <name>1</name>
                  <description>Passive input filter is enabled on the corresponding pin, if the pin is configured as a digital input. Refer to the device data sheet for filter characteristics.</description>
                  <value>#1</value>
                </enumeratedValue>
              </enumeratedValues>
            </field>
            <field>
              <name>DSE</name>
              <description>Drive Strength Enable</description>
              <bitOffset>6</bitOffset>
              <bitWidth>1</bitWidth>
              <access>read-only</access>
              <enumeratedValues>
                <enumeratedValue>
                  <name>0</name>
                  <description>Low drive strength is configured on the corresponding pin, if pin is configured as a digital output.</description>
                  <value>#0</value>
                </enumeratedValue>
                <enumeratedValue>
                  <name>1</name>
                  <description>High drive strength is configured on the corresponding pin, if pin is configured as a digital output.</description>
                  <value>#1</value>
                </enumeratedValue>
              </enumeratedValues>
            </field>
            <field>
              <name>MUX</name>
              <description>Pin Mux Control</description>
              <bitOffset>8</bitOffset>
              <bitWidth>3</bitWidth>
              <access>read-write</access>
              <enumeratedValues>
                <enumeratedValue>
                  <name>000</name>
                  <description>Pin disabled (analog).</description>
                  <value>#000</value>
                </enumeratedValue>
                <enumeratedValue>
                  <name>001</name>
                  <description>Alternative 1 (GPIO).</description>
                  <value>#001</value>
                </enumeratedValue>
                <enumeratedValue>
                  <name>010</name>
                  <description>Alternative 2 (chip-specific).</description>
                  <value>#010</value>
                </enumeratedValue>
                <enumeratedValue>
                  <name>011</name>
                  <description>Alternative 3 (chip-specific).</description>
                  <value>#011</value>
                </enumeratedValue>
                <enumeratedValue>
                  <name>100</name>
                  <description>Alternative 4 (chip-specific).</description>
                  <value>#100</value>
                </enumeratedValue>
                <enumeratedValue>
                  <name>101</name>
                  <description>Alternative 5 (chip-specific).</description>
                  <value>#101</value>
                </enumeratedValue>
                <enumeratedValue>
                  <name>110</name>
                  <description>Alternative 6 (chip-specific).</description>
                  <value>#110</value>
                </enumeratedValue>
                <enumeratedValue>
                  <name>111</name>
                  <description>Alternative 7 (chip-specific).</description>
                  <value>#111</value>
                </enumeratedValue>
              </enumeratedValues>
            </field>
            <field>
              <name>IRQC</name>
              <description>Interrupt Configuration</description>
              <bitOffset>16</bitOffset>
              <bitWidth>4</bitWidth>
              <access>read-write</access>
              <enumeratedValues>
                <enumeratedValue>
                  <name>0000</name>
                  <description>Interrupt/DMA request disabled.</description>
                  <value>#0000</value>
                </enumeratedValue>
                <enumeratedValue>
                  <name>0001</name>
                  <description>DMA request on rising edge.</description>
                  <value>#0001</value>
                </enumeratedValue>
                <enumeratedValue>
                  <name>0010</name>
                  <description>DMA request on falling edge.</description>
                  <value>#0010</value>
                </enumeratedValue>
                <enumeratedValue>
                  <name>0011</name>
                  <description>DMA request on either edge.</description>
                  <value>#0011</value>
                </enumeratedValue>
                <enumeratedValue>
                  <name>1000</name>
                  <description>Interrupt when logic 0.</description>
                  <value>#1000</value>
                </enumeratedValue>
                <enumeratedValue>
                  <name>1001</name>
                  <description>Interrupt on rising-edge.</description>
                  <value>#1001</value>
                </enumeratedValue>
                <enumeratedValue>
                  <name>1010</name>
                  <description>Interrupt on falling-edge.</description>
                  <value>#1010</value>
                </enumeratedValue>
                <enumeratedValue>
                  <name>1011</name>
                  <description>Interrupt on either edge.</description>
                  <value>#1011</value>
                </enumeratedValue>
                <enumeratedValue>
                  <name>1100</name>
                  <description>Interrupt when logic 1.</description>
                  <value>#1100</value>
                </enumeratedValue>
              </enumeratedValues>
            </field>
            <field>
              <name>ISF</name>
              <description>Interrupt Status Flag</description>
              <bitOffset>24</bitOffset>
              <bitWidth>1</bitWidth>
              <access>read-write</access>
              <enumeratedValues>
                <enumeratedValue>
                  <name>0</name>
                  <description>Configured interrupt is not detected.</description>
                  <value>#0</value>
                </enumeratedValue>
                <enumeratedValue>
                  <name>1</name>
                  <description>Configured interrupt is detected. If the pin is configured to generate a DMA request, then the corresponding flag will be cleared automatically at the completion of the requested DMA transfer. Otherwise, the flag remains set until a logic 1 is written to the flag. If the pin is configured for a level sensitive interrupt and the pin remains asserted, then the flag is set again immediately after it is cleared.</description>
                  <value>#1</value>
                </enumeratedValue>
              </enumeratedValues>
            </field>
          </fields>
        </register>
        <register>
          <name>PCR13</name>
          <description>Pin Control Register n</description>
          <addressOffset>0x34</addressOffset>
          <size>32</size>
          <access>read-write</access>
          <resetValue>0x5</resetValue>
          <resetMask>0xFFFFFFFF</resetMask>
          <fields>
            <field>
              <name>PS</name>
              <description>Pull Select</description>
              <bitOffset>0</bitOffset>
              <bitWidth>1</bitWidth>
              <access>read-only</access>
              <enumeratedValues>
                <enumeratedValue>
                  <name>0</name>
                  <description>Internal pulldown resistor is enabled on the corresponding pin, if the corresponding PE field is set.</description>
                  <value>#0</value>
                </enumeratedValue>
                <enumeratedValue>
                  <name>1</name>
                  <description>Internal pullup resistor is enabled on the corresponding pin, if the corresponding PE field is set.</description>
                  <value>#1</value>
                </enumeratedValue>
              </enumeratedValues>
            </field>
            <field>
              <name>PE</name>
              <description>Pull Enable</description>
              <bitOffset>1</bitOffset>
              <bitWidth>1</bitWidth>
              <access>read-only</access>
              <enumeratedValues>
                <enumeratedValue>
                  <name>0</name>
                  <description>Internal pullup or pulldown resistor is not enabled on the corresponding pin.</description>
                  <value>#0</value>
                </enumeratedValue>
                <enumeratedValue>
                  <name>1</name>
                  <description>Internal pullup or pulldown resistor is enabled on the corresponding pin, if the pin is configured as a digital input.</description>
                  <value>#1</value>
                </enumeratedValue>
              </enumeratedValues>
            </field>
            <field>
              <name>SRE</name>
              <description>Slew Rate Enable</description>
              <bitOffset>2</bitOffset>
              <bitWidth>1</bitWidth>
              <access>read-only</access>
              <enumeratedValues>
                <enumeratedValue>
                  <name>0</name>
                  <description>Fast slew rate is configured on the corresponding pin, if the pin is configured as a digital output.</description>
                  <value>#0</value>
                </enumeratedValue>
                <enumeratedValue>
                  <name>1</name>
                  <description>Slow slew rate is configured on the corresponding pin, if the pin is configured as a digital output.</description>
                  <value>#1</value>
                </enumeratedValue>
              </enumeratedValues>
            </field>
            <field>
              <name>PFE</name>
              <description>Passive Filter Enable</description>
              <bitOffset>4</bitOffset>
              <bitWidth>1</bitWidth>
              <access>read-only</access>
              <enumeratedValues>
                <enumeratedValue>
                  <name>0</name>
                  <description>Passive input filter is disabled on the corresponding pin.</description>
                  <value>#0</value>
                </enumeratedValue>
                <enumeratedValue>
                  <name>1</name>
                  <description>Passive input filter is enabled on the corresponding pin, if the pin is configured as a digital input. Refer to the device data sheet for filter characteristics.</description>
                  <value>#1</value>
                </enumeratedValue>
              </enumeratedValues>
            </field>
            <field>
              <name>DSE</name>
              <description>Drive Strength Enable</description>
              <bitOffset>6</bitOffset>
              <bitWidth>1</bitWidth>
              <access>read-only</access>
              <enumeratedValues>
                <enumeratedValue>
                  <name>0</name>
                  <description>Low drive strength is configured on the corresponding pin, if pin is configured as a digital output.</description>
                  <value>#0</value>
                </enumeratedValue>
                <enumeratedValue>
                  <name>1</name>
                  <description>High drive strength is configured on the corresponding pin, if pin is configured as a digital output.</description>
                  <value>#1</value>
                </enumeratedValue>
              </enumeratedValues>
            </field>
            <field>
              <name>MUX</name>
              <description>Pin Mux Control</description>
              <bitOffset>8</bitOffset>
              <bitWidth>3</bitWidth>
              <access>read-write</access>
              <enumeratedValues>
                <enumeratedValue>
                  <name>000</name>
                  <description>Pin disabled (analog).</description>
                  <value>#000</value>
                </enumeratedValue>
                <enumeratedValue>
                  <name>001</name>
                  <description>Alternative 1 (GPIO).</description>
                  <value>#001</value>
                </enumeratedValue>
                <enumeratedValue>
                  <name>010</name>
                  <description>Alternative 2 (chip-specific).</description>
                  <value>#010</value>
                </enumeratedValue>
                <enumeratedValue>
                  <name>011</name>
                  <description>Alternative 3 (chip-specific).</description>
                  <value>#011</value>
                </enumeratedValue>
                <enumeratedValue>
                  <name>100</name>
                  <description>Alternative 4 (chip-specific).</description>
                  <value>#100</value>
                </enumeratedValue>
                <enumeratedValue>
                  <name>101</name>
                  <description>Alternative 5 (chip-specific).</description>
                  <value>#101</value>
                </enumeratedValue>
                <enumeratedValue>
                  <name>110</name>
                  <description>Alternative 6 (chip-specific).</description>
                  <value>#110</value>
                </enumeratedValue>
                <enumeratedValue>
                  <name>111</name>
                  <description>Alternative 7 (chip-specific).</description>
                  <value>#111</value>
                </enumeratedValue>
              </enumeratedValues>
            </field>
            <field>
              <name>IRQC</name>
              <description>Interrupt Configuration</description>
              <bitOffset>16</bitOffset>
              <bitWidth>4</bitWidth>
              <access>read-write</access>
              <enumeratedValues>
                <enumeratedValue>
                  <name>0000</name>
                  <description>Interrupt/DMA request disabled.</description>
                  <value>#0000</value>
                </enumeratedValue>
                <enumeratedValue>
                  <name>0001</name>
                  <description>DMA request on rising edge.</description>
                  <value>#0001</value>
                </enumeratedValue>
                <enumeratedValue>
                  <name>0010</name>
                  <description>DMA request on falling edge.</description>
                  <value>#0010</value>
                </enumeratedValue>
                <enumeratedValue>
                  <name>0011</name>
                  <description>DMA request on either edge.</description>
                  <value>#0011</value>
                </enumeratedValue>
                <enumeratedValue>
                  <name>1000</name>
                  <description>Interrupt when logic 0.</description>
                  <value>#1000</value>
                </enumeratedValue>
                <enumeratedValue>
                  <name>1001</name>
                  <description>Interrupt on rising-edge.</description>
                  <value>#1001</value>
                </enumeratedValue>
                <enumeratedValue>
                  <name>1010</name>
                  <description>Interrupt on falling-edge.</description>
                  <value>#1010</value>
                </enumeratedValue>
                <enumeratedValue>
                  <name>1011</name>
                  <description>Interrupt on either edge.</description>
                  <value>#1011</value>
                </enumeratedValue>
                <enumeratedValue>
                  <name>1100</name>
                  <description>Interrupt when logic 1.</description>
                  <value>#1100</value>
                </enumeratedValue>
              </enumeratedValues>
            </field>
            <field>
              <name>ISF</name>
              <description>Interrupt Status Flag</description>
              <bitOffset>24</bitOffset>
              <bitWidth>1</bitWidth>
              <access>read-write</access>
              <enumeratedValues>
                <enumeratedValue>
                  <name>0</name>
                  <description>Configured interrupt is not detected.</description>
                  <value>#0</value>
                </enumeratedValue>
                <enumeratedValue>
                  <name>1</name>
                  <description>Configured interrupt is detected. If the pin is configured to generate a DMA request, then the corresponding flag will be cleared automatically at the completion of the requested DMA transfer. Otherwise, the flag remains set until a logic 1 is written to the flag. If the pin is configured for a level sensitive interrupt and the pin remains asserted, then the flag is set again immediately after it is cleared.</description>
                  <value>#1</value>
                </enumeratedValue>
              </enumeratedValues>
            </field>
          </fields>
        </register>
        <register>
          <name>PCR14</name>
          <description>Pin Control Register n</description>
          <addressOffset>0x38</addressOffset>
          <size>32</size>
          <access>read-write</access>
          <resetValue>0</resetValue>
          <resetMask>0xFFFFFFFF</resetMask>
          <fields>
            <field>
              <name>PS</name>
              <description>Pull Select</description>
              <bitOffset>0</bitOffset>
              <bitWidth>1</bitWidth>
              <access>read-only</access>
              <enumeratedValues>
                <enumeratedValue>
                  <name>0</name>
                  <description>Internal pulldown resistor is enabled on the corresponding pin, if the corresponding PE field is set.</description>
                  <value>#0</value>
                </enumeratedValue>
                <enumeratedValue>
                  <name>1</name>
                  <description>Internal pullup resistor is enabled on the corresponding pin, if the corresponding PE field is set.</description>
                  <value>#1</value>
                </enumeratedValue>
              </enumeratedValues>
            </field>
            <field>
              <name>PE</name>
              <description>Pull Enable</description>
              <bitOffset>1</bitOffset>
              <bitWidth>1</bitWidth>
              <access>read-only</access>
              <enumeratedValues>
                <enumeratedValue>
                  <name>0</name>
                  <description>Internal pullup or pulldown resistor is not enabled on the corresponding pin.</description>
                  <value>#0</value>
                </enumeratedValue>
                <enumeratedValue>
                  <name>1</name>
                  <description>Internal pullup or pulldown resistor is enabled on the corresponding pin, if the pin is configured as a digital input.</description>
                  <value>#1</value>
                </enumeratedValue>
              </enumeratedValues>
            </field>
            <field>
              <name>SRE</name>
              <description>Slew Rate Enable</description>
              <bitOffset>2</bitOffset>
              <bitWidth>1</bitWidth>
              <access>read-only</access>
              <enumeratedValues>
                <enumeratedValue>
                  <name>0</name>
                  <description>Fast slew rate is configured on the corresponding pin, if the pin is configured as a digital output.</description>
                  <value>#0</value>
                </enumeratedValue>
                <enumeratedValue>
                  <name>1</name>
                  <description>Slow slew rate is configured on the corresponding pin, if the pin is configured as a digital output.</description>
                  <value>#1</value>
                </enumeratedValue>
              </enumeratedValues>
            </field>
            <field>
              <name>PFE</name>
              <description>Passive Filter Enable</description>
              <bitOffset>4</bitOffset>
              <bitWidth>1</bitWidth>
              <access>read-only</access>
              <enumeratedValues>
                <enumeratedValue>
                  <name>0</name>
                  <description>Passive input filter is disabled on the corresponding pin.</description>
                  <value>#0</value>
                </enumeratedValue>
                <enumeratedValue>
                  <name>1</name>
                  <description>Passive input filter is enabled on the corresponding pin, if the pin is configured as a digital input. Refer to the device data sheet for filter characteristics.</description>
                  <value>#1</value>
                </enumeratedValue>
              </enumeratedValues>
            </field>
            <field>
              <name>DSE</name>
              <description>Drive Strength Enable</description>
              <bitOffset>6</bitOffset>
              <bitWidth>1</bitWidth>
              <access>read-only</access>
              <enumeratedValues>
                <enumeratedValue>
                  <name>0</name>
                  <description>Low drive strength is configured on the corresponding pin, if pin is configured as a digital output.</description>
                  <value>#0</value>
                </enumeratedValue>
                <enumeratedValue>
                  <name>1</name>
                  <description>High drive strength is configured on the corresponding pin, if pin is configured as a digital output.</description>
                  <value>#1</value>
                </enumeratedValue>
              </enumeratedValues>
            </field>
            <field>
              <name>MUX</name>
              <description>Pin Mux Control</description>
              <bitOffset>8</bitOffset>
              <bitWidth>3</bitWidth>
              <access>read-write</access>
              <enumeratedValues>
                <enumeratedValue>
                  <name>000</name>
                  <description>Pin disabled (analog).</description>
                  <value>#000</value>
                </enumeratedValue>
                <enumeratedValue>
                  <name>001</name>
                  <description>Alternative 1 (GPIO).</description>
                  <value>#001</value>
                </enumeratedValue>
                <enumeratedValue>
                  <name>010</name>
                  <description>Alternative 2 (chip-specific).</description>
                  <value>#010</value>
                </enumeratedValue>
                <enumeratedValue>
                  <name>011</name>
                  <description>Alternative 3 (chip-specific).</description>
                  <value>#011</value>
                </enumeratedValue>
                <enumeratedValue>
                  <name>100</name>
                  <description>Alternative 4 (chip-specific).</description>
                  <value>#100</value>
                </enumeratedValue>
                <enumeratedValue>
                  <name>101</name>
                  <description>Alternative 5 (chip-specific).</description>
                  <value>#101</value>
                </enumeratedValue>
                <enumeratedValue>
                  <name>110</name>
                  <description>Alternative 6 (chip-specific).</description>
                  <value>#110</value>
                </enumeratedValue>
                <enumeratedValue>
                  <name>111</name>
                  <description>Alternative 7 (chip-specific).</description>
                  <value>#111</value>
                </enumeratedValue>
              </enumeratedValues>
            </field>
            <field>
              <name>IRQC</name>
              <description>Interrupt Configuration</description>
              <bitOffset>16</bitOffset>
              <bitWidth>4</bitWidth>
              <access>read-write</access>
              <enumeratedValues>
                <enumeratedValue>
                  <name>0000</name>
                  <description>Interrupt/DMA request disabled.</description>
                  <value>#0000</value>
                </enumeratedValue>
                <enumeratedValue>
                  <name>0001</name>
                  <description>DMA request on rising edge.</description>
                  <value>#0001</value>
                </enumeratedValue>
                <enumeratedValue>
                  <name>0010</name>
                  <description>DMA request on falling edge.</description>
                  <value>#0010</value>
                </enumeratedValue>
                <enumeratedValue>
                  <name>0011</name>
                  <description>DMA request on either edge.</description>
                  <value>#0011</value>
                </enumeratedValue>
                <enumeratedValue>
                  <name>1000</name>
                  <description>Interrupt when logic 0.</description>
                  <value>#1000</value>
                </enumeratedValue>
                <enumeratedValue>
                  <name>1001</name>
                  <description>Interrupt on rising-edge.</description>
                  <value>#1001</value>
                </enumeratedValue>
                <enumeratedValue>
                  <name>1010</name>
                  <description>Interrupt on falling-edge.</description>
                  <value>#1010</value>
                </enumeratedValue>
                <enumeratedValue>
                  <name>1011</name>
                  <description>Interrupt on either edge.</description>
                  <value>#1011</value>
                </enumeratedValue>
                <enumeratedValue>
                  <name>1100</name>
                  <description>Interrupt when logic 1.</description>
                  <value>#1100</value>
                </enumeratedValue>
              </enumeratedValues>
            </field>
            <field>
              <name>ISF</name>
              <description>Interrupt Status Flag</description>
              <bitOffset>24</bitOffset>
              <bitWidth>1</bitWidth>
              <access>read-write</access>
              <enumeratedValues>
                <enumeratedValue>
                  <name>0</name>
                  <description>Configured interrupt is not detected.</description>
                  <value>#0</value>
                </enumeratedValue>
                <enumeratedValue>
                  <name>1</name>
                  <description>Configured interrupt is detected. If the pin is configured to generate a DMA request, then the corresponding flag will be cleared automatically at the completion of the requested DMA transfer. Otherwise, the flag remains set until a logic 1 is written to the flag. If the pin is configured for a level sensitive interrupt and the pin remains asserted, then the flag is set again immediately after it is cleared.</description>
                  <value>#1</value>
                </enumeratedValue>
              </enumeratedValues>
            </field>
          </fields>
        </register>
        <register>
          <name>PCR15</name>
          <description>Pin Control Register n</description>
          <addressOffset>0x3C</addressOffset>
          <size>32</size>
          <access>read-write</access>
          <resetValue>0</resetValue>
          <resetMask>0xFFFFFFFF</resetMask>
          <fields>
            <field>
              <name>PS</name>
              <description>Pull Select</description>
              <bitOffset>0</bitOffset>
              <bitWidth>1</bitWidth>
              <access>read-only</access>
              <enumeratedValues>
                <enumeratedValue>
                  <name>0</name>
                  <description>Internal pulldown resistor is enabled on the corresponding pin, if the corresponding PE field is set.</description>
                  <value>#0</value>
                </enumeratedValue>
                <enumeratedValue>
                  <name>1</name>
                  <description>Internal pullup resistor is enabled on the corresponding pin, if the corresponding PE field is set.</description>
                  <value>#1</value>
                </enumeratedValue>
              </enumeratedValues>
            </field>
            <field>
              <name>PE</name>
              <description>Pull Enable</description>
              <bitOffset>1</bitOffset>
              <bitWidth>1</bitWidth>
              <access>read-only</access>
              <enumeratedValues>
                <enumeratedValue>
                  <name>0</name>
                  <description>Internal pullup or pulldown resistor is not enabled on the corresponding pin.</description>
                  <value>#0</value>
                </enumeratedValue>
                <enumeratedValue>
                  <name>1</name>
                  <description>Internal pullup or pulldown resistor is enabled on the corresponding pin, if the pin is configured as a digital input.</description>
                  <value>#1</value>
                </enumeratedValue>
              </enumeratedValues>
            </field>
            <field>
              <name>SRE</name>
              <description>Slew Rate Enable</description>
              <bitOffset>2</bitOffset>
              <bitWidth>1</bitWidth>
              <access>read-only</access>
              <enumeratedValues>
                <enumeratedValue>
                  <name>0</name>
                  <description>Fast slew rate is configured on the corresponding pin, if the pin is configured as a digital output.</description>
                  <value>#0</value>
                </enumeratedValue>
                <enumeratedValue>
                  <name>1</name>
                  <description>Slow slew rate is configured on the corresponding pin, if the pin is configured as a digital output.</description>
                  <value>#1</value>
                </enumeratedValue>
              </enumeratedValues>
            </field>
            <field>
              <name>PFE</name>
              <description>Passive Filter Enable</description>
              <bitOffset>4</bitOffset>
              <bitWidth>1</bitWidth>
              <access>read-only</access>
              <enumeratedValues>
                <enumeratedValue>
                  <name>0</name>
                  <description>Passive input filter is disabled on the corresponding pin.</description>
                  <value>#0</value>
                </enumeratedValue>
                <enumeratedValue>
                  <name>1</name>
                  <description>Passive input filter is enabled on the corresponding pin, if the pin is configured as a digital input. Refer to the device data sheet for filter characteristics.</description>
                  <value>#1</value>
                </enumeratedValue>
              </enumeratedValues>
            </field>
            <field>
              <name>DSE</name>
              <description>Drive Strength Enable</description>
              <bitOffset>6</bitOffset>
              <bitWidth>1</bitWidth>
              <access>read-only</access>
              <enumeratedValues>
                <enumeratedValue>
                  <name>0</name>
                  <description>Low drive strength is configured on the corresponding pin, if pin is configured as a digital output.</description>
                  <value>#0</value>
                </enumeratedValue>
                <enumeratedValue>
                  <name>1</name>
                  <description>High drive strength is configured on the corresponding pin, if pin is configured as a digital output.</description>
                  <value>#1</value>
                </enumeratedValue>
              </enumeratedValues>
            </field>
            <field>
              <name>MUX</name>
              <description>Pin Mux Control</description>
              <bitOffset>8</bitOffset>
              <bitWidth>3</bitWidth>
              <access>read-write</access>
              <enumeratedValues>
                <enumeratedValue>
                  <name>000</name>
                  <description>Pin disabled (analog).</description>
                  <value>#000</value>
                </enumeratedValue>
                <enumeratedValue>
                  <name>001</name>
                  <description>Alternative 1 (GPIO).</description>
                  <value>#001</value>
                </enumeratedValue>
                <enumeratedValue>
                  <name>010</name>
                  <description>Alternative 2 (chip-specific).</description>
                  <value>#010</value>
                </enumeratedValue>
                <enumeratedValue>
                  <name>011</name>
                  <description>Alternative 3 (chip-specific).</description>
                  <value>#011</value>
                </enumeratedValue>
                <enumeratedValue>
                  <name>100</name>
                  <description>Alternative 4 (chip-specific).</description>
                  <value>#100</value>
                </enumeratedValue>
                <enumeratedValue>
                  <name>101</name>
                  <description>Alternative 5 (chip-specific).</description>
                  <value>#101</value>
                </enumeratedValue>
                <enumeratedValue>
                  <name>110</name>
                  <description>Alternative 6 (chip-specific).</description>
                  <value>#110</value>
                </enumeratedValue>
                <enumeratedValue>
                  <name>111</name>
                  <description>Alternative 7 (chip-specific).</description>
                  <value>#111</value>
                </enumeratedValue>
              </enumeratedValues>
            </field>
            <field>
              <name>IRQC</name>
              <description>Interrupt Configuration</description>
              <bitOffset>16</bitOffset>
              <bitWidth>4</bitWidth>
              <access>read-write</access>
              <enumeratedValues>
                <enumeratedValue>
                  <name>0000</name>
                  <description>Interrupt/DMA request disabled.</description>
                  <value>#0000</value>
                </enumeratedValue>
                <enumeratedValue>
                  <name>0001</name>
                  <description>DMA request on rising edge.</description>
                  <value>#0001</value>
                </enumeratedValue>
                <enumeratedValue>
                  <name>0010</name>
                  <description>DMA request on falling edge.</description>
                  <value>#0010</value>
                </enumeratedValue>
                <enumeratedValue>
                  <name>0011</name>
                  <description>DMA request on either edge.</description>
                  <value>#0011</value>
                </enumeratedValue>
                <enumeratedValue>
                  <name>1000</name>
                  <description>Interrupt when logic 0.</description>
                  <value>#1000</value>
                </enumeratedValue>
                <enumeratedValue>
                  <name>1001</name>
                  <description>Interrupt on rising-edge.</description>
                  <value>#1001</value>
                </enumeratedValue>
                <enumeratedValue>
                  <name>1010</name>
                  <description>Interrupt on falling-edge.</description>
                  <value>#1010</value>
                </enumeratedValue>
                <enumeratedValue>
                  <name>1011</name>
                  <description>Interrupt on either edge.</description>
                  <value>#1011</value>
                </enumeratedValue>
                <enumeratedValue>
                  <name>1100</name>
                  <description>Interrupt when logic 1.</description>
                  <value>#1100</value>
                </enumeratedValue>
              </enumeratedValues>
            </field>
            <field>
              <name>ISF</name>
              <description>Interrupt Status Flag</description>
              <bitOffset>24</bitOffset>
              <bitWidth>1</bitWidth>
              <access>read-write</access>
              <enumeratedValues>
                <enumeratedValue>
                  <name>0</name>
                  <description>Configured interrupt is not detected.</description>
                  <value>#0</value>
                </enumeratedValue>
                <enumeratedValue>
                  <name>1</name>
                  <description>Configured interrupt is detected. If the pin is configured to generate a DMA request, then the corresponding flag will be cleared automatically at the completion of the requested DMA transfer. Otherwise, the flag remains set until a logic 1 is written to the flag. If the pin is configured for a level sensitive interrupt and the pin remains asserted, then the flag is set again immediately after it is cleared.</description>
                  <value>#1</value>
                </enumeratedValue>
              </enumeratedValues>
            </field>
          </fields>
        </register>
        <register>
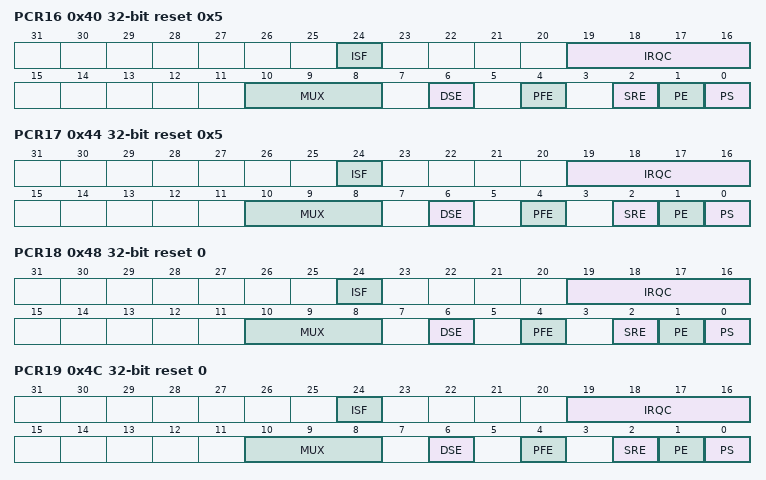
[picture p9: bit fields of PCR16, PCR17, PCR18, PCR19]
          <name>PCR16</name>
          <description>Pin Control Register n</description>
          <addressOffset>0x40</addressOffset>
          <size>32</size>
          <access>read-write</access>
          <resetValue>0x5</resetValue>
          <resetMask>0xFFFFFFFF</resetMask>
          <fields>
            <field>
              <name>PS</name>
              <description>Pull Select</description>
              <bitOffset>0</bitOffset>
              <bitWidth>1</bitWidth>
              <access>read-only</access>
              <enumeratedValues>
                <enumeratedValue>
                  <name>0</name>
                  <description>Internal pulldown resistor is enabled on the corresponding pin, if the corresponding PE field is set.</description>
                  <value>#0</value>
                </enumeratedValue>
                <enumeratedValue>
                  <name>1</name>
                  <description>Internal pullup resistor is enabled on the corresponding pin, if the corresponding PE field is set.</description>
                  <value>#1</value>
                </enumeratedValue>
              </enumeratedValues>
            </field>
            <field>
              <name>PE</name>
              <description>Pull Enable</description>
              <bitOffset>1</bitOffset>
              <bitWidth>1</bitWidth>
              <access>read-only</access>
              <enumeratedValues>
                <enumeratedValue>
                  <name>0</name>
                  <description>Internal pullup or pulldown resistor is not enabled on the corresponding pin.</description>
                  <value>#0</value>
                </enumeratedValue>
                <enumeratedValue>
                  <name>1</name>
                  <description>Internal pullup or pulldown resistor is enabled on the corresponding pin, if the pin is configured as a digital input.</description>
                  <value>#1</value>
                </enumeratedValue>
              </enumeratedValues>
            </field>
            <field>
              <name>SRE</name>
              <description>Slew Rate Enable</description>
              <bitOffset>2</bitOffset>
              <bitWidth>1</bitWidth>
              <access>read-only</access>
              <enumeratedValues>
                <enumeratedValue>
                  <name>0</name>
                  <description>Fast slew rate is configured on the corresponding pin, if the pin is configured as a digital output.</description>
                  <value>#0</value>
                </enumeratedValue>
                <enumeratedValue>
                  <name>1</name>
                  <description>Slow slew rate is configured on the corresponding pin, if the pin is configured as a digital output.</description>
                  <value>#1</value>
                </enumeratedValue>
              </enumeratedValues>
            </field>
            <field>
              <name>PFE</name>
              <description>Passive Filter Enable</description>
              <bitOffset>4</bitOffset>
              <bitWidth>1</bitWidth>
              <access>read-only</access>
              <enumeratedValues>
                <enumeratedValue>
                  <name>0</name>
                  <description>Passive input filter is disabled on the corresponding pin.</description>
                  <value>#0</value>
                </enumeratedValue>
                <enumeratedValue>
                  <name>1</name>
                  <description>Passive input filter is enabled on the corresponding pin, if the pin is configured as a digital input. Refer to the device data sheet for filter characteristics.</description>
                  <value>#1</value>
                </enumeratedValue>
              </enumeratedValues>
            </field>
            <field>
              <name>DSE</name>
              <description>Drive Strength Enable</description>
              <bitOffset>6</bitOffset>
              <bitWidth>1</bitWidth>
              <access>read-only</access>
              <enumeratedValues>
                <enumeratedValue>
                  <name>0</name>
                  <description>Low drive strength is configured on the corresponding pin, if pin is configured as a digital output.</description>
                  <value>#0</value>
                </enumeratedValue>
                <enumeratedValue>
                  <name>1</name>
                  <description>High drive strength is configured on the corresponding pin, if pin is configured as a digital output.</description>
                  <value>#1</value>
                </enumeratedValue>
              </enumeratedValues>
            </field>
            <field>
              <name>MUX</name>
              <description>Pin Mux Control</description>
              <bitOffset>8</bitOffset>
              <bitWidth>3</bitWidth>
              <access>read-write</access>
              <enumeratedValues>
                <enumeratedValue>
                  <name>000</name>
                  <description>Pin disabled (analog).</description>
                  <value>#000</value>
                </enumeratedValue>
                <enumeratedValue>
                  <name>001</name>
                  <description>Alternative 1 (GPIO).</description>
                  <value>#001</value>
                </enumeratedValue>
                <enumeratedValue>
                  <name>010</name>
                  <description>Alternative 2 (chip-specific).</description>
                  <value>#010</value>
                </enumeratedValue>
                <enumeratedValue>
                  <name>011</name>
                  <description>Alternative 3 (chip-specific).</description>
                  <value>#011</value>
                </enumeratedValue>
                <enumeratedValue>
                  <name>100</name>
                  <description>Alternative 4 (chip-specific).</description>
                  <value>#100</value>
                </enumeratedValue>
                <enumeratedValue>
                  <name>101</name>
                  <description>Alternative 5 (chip-specific).</description>
                  <value>#101</value>
                </enumeratedValue>
                <enumeratedValue>
                  <name>110</name>
                  <description>Alternative 6 (chip-specific).</description>
                  <value>#110</value>
                </enumeratedValue>
                <enumeratedValue>
                  <name>111</name>
                  <description>Alternative 7 (chip-specific).</description>
                  <value>#111</value>
                </enumeratedValue>
              </enumeratedValues>
            </field>
            <field>
              <name>IRQC</name>
              <description>Interrupt Configuration</description>
              <bitOffset>16</bitOffset>
              <bitWidth>4</bitWidth>
              <access>read-write</access>
              <enumeratedValues>
                <enumeratedValue>
                  <name>0000</name>
                  <description>Interrupt/DMA request disabled.</description>
                  <value>#0000</value>
                </enumeratedValue>
                <enumeratedValue>
                  <name>0001</name>
                  <description>DMA request on rising edge.</description>
                  <value>#0001</value>
                </enumeratedValue>
                <enumeratedValue>
                  <name>0010</name>
                  <description>DMA request on falling edge.</description>
                  <value>#0010</value>
                </enumeratedValue>
                <enumeratedValue>
                  <name>0011</name>
                  <description>DMA request on either edge.</description>
                  <value>#0011</value>
                </enumeratedValue>
                <enumeratedValue>
                  <name>1000</name>
                  <description>Interrupt when logic 0.</description>
                  <value>#1000</value>
                </enumeratedValue>
                <enumeratedValue>
                  <name>1001</name>
                  <description>Interrupt on rising-edge.</description>
                  <value>#1001</value>
                </enumeratedValue>
                <enumeratedValue>
                  <name>1010</name>
                  <description>Interrupt on falling-edge.</description>
                  <value>#1010</value>
                </enumeratedValue>
                <enumeratedValue>
                  <name>1011</name>
                  <description>Interrupt on either edge.</description>
                  <value>#1011</value>
                </enumeratedValue>
                <enumeratedValue>
                  <name>1100</name>
                  <description>Interrupt when logic 1.</description>
                  <value>#1100</value>
                </enumeratedValue>
              </enumeratedValues>
            </field>
            <field>
              <name>ISF</name>
              <description>Interrupt Status Flag</description>
              <bitOffset>24</bitOffset>
              <bitWidth>1</bitWidth>
              <access>read-write</access>
              <enumeratedValues>
                <enumeratedValue>
                  <name>0</name>
                  <description>Configured interrupt is not detected.</description>
                  <value>#0</value>
                </enumeratedValue>
                <enumeratedValue>
                  <name>1</name>
                  <description>Configured interrupt is detected. If the pin is configured to generate a DMA request, then the corresponding flag will be cleared automatically at the completion of the requested DMA transfer. Otherwise, the flag remains set until a logic 1 is written to the flag. If the pin is configured for a level sensitive interrupt and the pin remains asserted, then the flag is set again immediately after it is cleared.</description>
                  <value>#1</value>
                </enumeratedValue>
              </enumeratedValues>
            </field>
          </fields>
        </register>
        <register>
          <name>PCR17</name>
          <description>Pin Control Register n</description>
          <addressOffset>0x44</addressOffset>
          <size>32</size>
          <access>read-write</access>
          <resetValue>0x5</resetValue>
          <resetMask>0xFFFFFFFF</resetMask>
          <fields>
            <field>
              <name>PS</name>
              <description>Pull Select</description>
              <bitOffset>0</bitOffset>
              <bitWidth>1</bitWidth>
              <access>read-only</access>
              <enumeratedValues>
                <enumeratedValue>
                  <name>0</name>
                  <description>Internal pulldown resistor is enabled on the corresponding pin, if the corresponding PE field is set.</description>
                  <value>#0</value>
                </enumeratedValue>
                <enumeratedValue>
                  <name>1</name>
                  <description>Internal pullup resistor is enabled on the corresponding pin, if the corresponding PE field is set.</description>
                  <value>#1</value>
                </enumeratedValue>
              </enumeratedValues>
            </field>
            <field>
              <name>PE</name>
              <description>Pull Enable</description>
              <bitOffset>1</bitOffset>
              <bitWidth>1</bitWidth>
              <access>read-only</access>
              <enumeratedValues>
                <enumeratedValue>
                  <name>0</name>
                  <description>Internal pullup or pulldown resistor is not enabled on the corresponding pin.</description>
                  <value>#0</value>
                </enumeratedValue>
                <enumeratedValue>
                  <name>1</name>
                  <description>Internal pullup or pulldown resistor is enabled on the corresponding pin, if the pin is configured as a digital input.</description>
                  <value>#1</value>
                </enumeratedValue>
              </enumeratedValues>
            </field>
            <field>
              <name>SRE</name>
              <description>Slew Rate Enable</description>
              <bitOffset>2</bitOffset>
              <bitWidth>1</bitWidth>
              <access>read-only</access>
              <enumeratedValues>
                <enumeratedValue>
                  <name>0</name>
                  <description>Fast slew rate is configured on the corresponding pin, if the pin is configured as a digital output.</description>
                  <value>#0</value>
                </enumeratedValue>
                <enumeratedValue>
                  <name>1</name>
                  <description>Slow slew rate is configured on the corresponding pin, if the pin is configured as a digital output.</description>
                  <value>#1</value>
                </enumeratedValue>
              </enumeratedValues>
            </field>
            <field>
              <name>PFE</name>
              <description>Passive Filter Enable</description>
              <bitOffset>4</bitOffset>
              <bitWidth>1</bitWidth>
              <access>read-only</access>
              <enumeratedValues>
                <enumeratedValue>
                  <name>0</name>
                  <description>Passive input filter is disabled on the corresponding pin.</description>
                  <value>#0</value>
                </enumeratedValue>
                <enumeratedValue>
                  <name>1</name>
                  <description>Passive input filter is enabled on the corresponding pin, if the pin is configured as a digital input. Refer to the device data sheet for filter characteristics.</description>
                  <value>#1</value>
                </enumeratedValue>
              </enumeratedValues>
            </field>
            <field>
              <name>DSE</name>
              <description>Drive Strength Enable</description>
              <bitOffset>6</bitOffset>
              <bitWidth>1</bitWidth>
              <access>read-only</access>
              <enumeratedValues>
                <enumeratedValue>
                  <name>0</name>
                  <description>Low drive strength is configured on the corresponding pin, if pin is configured as a digital output.</description>
                  <value>#0</value>
                </enumeratedValue>
                <enumeratedValue>
                  <name>1</name>
                  <description>High drive strength is configured on the corresponding pin, if pin is configured as a digital output.</description>
                  <value>#1</value>
                </enumeratedValue>
              </enumeratedValues>
            </field>
            <field>
              <name>MUX</name>
              <description>Pin Mux Control</description>
              <bitOffset>8</bitOffset>
              <bitWidth>3</bitWidth>
              <access>read-write</access>
              <enumeratedValues>
                <enumeratedValue>
                  <name>000</name>
                  <description>Pin disabled (analog).</description>
                  <value>#000</value>
                </enumeratedValue>
                <enumeratedValue>
                  <name>001</name>
                  <description>Alternative 1 (GPIO).</description>
                  <value>#001</value>
                </enumeratedValue>
                <enumeratedValue>
                  <name>010</name>
                  <description>Alternative 2 (chip-specific).</description>
                  <value>#010</value>
                </enumeratedValue>
                <enumeratedValue>
                  <name>011</name>
                  <description>Alternative 3 (chip-specific).</description>
                  <value>#011</value>
                </enumeratedValue>
                <enumeratedValue>
                  <name>100</name>
                  <description>Alternative 4 (chip-specific).</description>
                  <value>#100</value>
                </enumeratedValue>
                <enumeratedValue>
                  <name>101</name>
                  <description>Alternative 5 (chip-specific).</description>
                  <value>#101</value>
                </enumeratedValue>
                <enumeratedValue>
                  <name>110</name>
                  <description>Alternative 6 (chip-specific).</description>
                  <value>#110</value>
                </enumeratedValue>
                <enumeratedValue>
                  <name>111</name>
                  <description>Alternative 7 (chip-specific).</description>
                  <value>#111</value>
                </enumeratedValue>
              </enumeratedValues>
            </field>
            <field>
              <name>IRQC</name>
              <description>Interrupt Configuration</description>
              <bitOffset>16</bitOffset>
              <bitWidth>4</bitWidth>
              <access>read-write</access>
              <enumeratedValues>
                <enumeratedValue>
                  <name>0000</name>
                  <description>Interrupt/DMA request disabled.</description>
                  <value>#0000</value>
                </enumeratedValue>
                <enumeratedValue>
                  <name>0001</name>
                  <description>DMA request on rising edge.</description>
                  <value>#0001</value>
                </enumeratedValue>
                <enumeratedValue>
                  <name>0010</name>
                  <description>DMA request on falling edge.</description>
                  <value>#0010</value>
                </enumeratedValue>
                <enumeratedValue>
                  <name>0011</name>
                  <description>DMA request on either edge.</description>
                  <value>#0011</value>
                </enumeratedValue>
                <enumeratedValue>
                  <name>1000</name>
                  <description>Interrupt when logic 0.</description>
                  <value>#1000</value>
                </enumeratedValue>
                <enumeratedValue>
                  <name>1001</name>
                  <description>Interrupt on rising-edge.</description>
                  <value>#1001</value>
                </enumeratedValue>
                <enumeratedValue>
                  <name>1010</name>
                  <description>Interrupt on falling-edge.</description>
                  <value>#1010</value>
                </enumeratedValue>
                <enumeratedValue>
                  <name>1011</name>
                  <description>Interrupt on either edge.</description>
                  <value>#1011</value>
                </enumeratedValue>
                <enumeratedValue>
                  <name>1100</name>
                  <description>Interrupt when logic 1.</description>
                  <value>#1100</value>
                </enumeratedValue>
              </enumeratedValues>
            </field>
            <field>
              <name>ISF</name>
              <description>Interrupt Status Flag</description>
              <bitOffset>24</bitOffset>
              <bitWidth>1</bitWidth>
              <access>read-write</access>
              <enumeratedValues>
                <enumeratedValue>
                  <name>0</name>
                  <description>Configured interrupt is not detected.</description>
                  <value>#0</value>
                </enumeratedValue>
                <enumeratedValue>
                  <name>1</name>
                  <description>Configured interrupt is detected. If the pin is configured to generate a DMA request, then the corresponding flag will be cleared automatically at the completion of the requested DMA transfer. Otherwise, the flag remains set until a logic 1 is written to the flag. If the pin is configured for a level sensitive interrupt and the pin remains asserted, then the flag is set again immediately after it is cleared.</description>
                  <value>#1</value>
                </enumeratedValue>
              </enumeratedValues>
            </field>
          </fields>
        </register>
        <register>
          <name>PCR18</name>
          <description>Pin Control Register n</description>
          <addressOffset>0x48</addressOffset>
          <size>32</size>
          <access>read-write</access>
          <resetValue>0</resetValue>
          <resetMask>0xFFFFFFFF</resetMask>
          <fields>
            <field>
              <name>PS</name>
              <description>Pull Select</description>
              <bitOffset>0</bitOffset>
              <bitWidth>1</bitWidth>
              <access>read-only</access>
              <enumeratedValues>
                <enumeratedValue>
                  <name>0</name>
                  <description>Internal pulldown resistor is enabled on the corresponding pin, if the corresponding PE field is set.</description>
                  <value>#0</value>
                </enumeratedValue>
                <enumeratedValue>
                  <name>1</name>
                  <description>Internal pullup resistor is enabled on the corresponding pin, if the corresponding PE field is set.</description>
                  <value>#1</value>
                </enumeratedValue>
              </enumeratedValues>
            </field>
            <field>
              <name>PE</name>
              <description>Pull Enable</description>
              <bitOffset>1</bitOffset>
              <bitWidth>1</bitWidth>
              <access>read-only</access>
              <enumeratedValues>
                <enumeratedValue>
                  <name>0</name>
                  <description>Internal pullup or pulldown resistor is not enabled on the corresponding pin.</description>
                  <value>#0</value>
                </enumeratedValue>
                <enumeratedValue>
                  <name>1</name>
                  <description>Internal pullup or pulldown resistor is enabled on the corresponding pin, if the pin is configured as a digital input.</description>
                  <value>#1</value>
                </enumeratedValue>
              </enumeratedValues>
            </field>
            <field>
              <name>SRE</name>
              <description>Slew Rate Enable</description>
              <bitOffset>2</bitOffset>
              <bitWidth>1</bitWidth>
              <access>read-only</access>
              <enumeratedValues>
                <enumeratedValue>
                  <name>0</name>
                  <description>Fast slew rate is configured on the corresponding pin, if the pin is configured as a digital output.</description>
                  <value>#0</value>
                </enumeratedValue>
                <enumeratedValue>
                  <name>1</name>
                  <description>Slow slew rate is configured on the corresponding pin, if the pin is configured as a digital output.</description>
                  <value>#1</value>
                </enumeratedValue>
              </enumeratedValues>
            </field>
            <field>
              <name>PFE</name>
              <description>Passive Filter Enable</description>
              <bitOffset>4</bitOffset>
              <bitWidth>1</bitWidth>
              <access>read-only</access>
              <enumeratedValues>
                <enumeratedValue>
                  <name>0</name>
                  <description>Passive input filter is disabled on the corresponding pin.</description>
                  <value>#0</value>
                </enumeratedValue>
                <enumeratedValue>
                  <name>1</name>
                  <description>Passive input filter is enabled on the corresponding pin, if the pin is configured as a digital input. Refer to the device data sheet for filter characteristics.</description>
                  <value>#1</value>
                </enumeratedValue>
              </enumeratedValues>
            </field>
            <field>
              <name>DSE</name>
              <description>Drive Strength Enable</description>
              <bitOffset>6</bitOffset>
              <bitWidth>1</bitWidth>
              <access>read-only</access>
              <enumeratedValues>
                <enumeratedValue>
                  <name>0</name>
                  <description>Low drive strength is configured on the corresponding pin, if pin is configured as a digital output.</description>
                  <value>#0</value>
                </enumeratedValue>
                <enumeratedValue>
                  <name>1</name>
                  <description>High drive strength is configured on the corresponding pin, if pin is configured as a digital output.</description>
                  <value>#1</value>
                </enumeratedValue>
              </enumeratedValues>
            </field>
            <field>
              <name>MUX</name>
              <description>Pin Mux Control</description>
              <bitOffset>8</bitOffset>
              <bitWidth>3</bitWidth>
              <access>read-write</access>
              <enumeratedValues>
                <enumeratedValue>
                  <name>000</name>
                  <description>Pin disabled (analog).</description>
                  <value>#000</value>
                </enumeratedValue>
                <enumeratedValue>
                  <name>001</name>
                  <description>Alternative 1 (GPIO).</description>
                  <value>#001</value>
                </enumeratedValue>
                <enumeratedValue>
                  <name>010</name>
                  <description>Alternative 2 (chip-specific).</description>
                  <value>#010</value>
                </enumeratedValue>
                <enumeratedValue>
                  <name>011</name>
                  <description>Alternative 3 (chip-specific).</description>
                  <value>#011</value>
                </enumeratedValue>
                <enumeratedValue>
                  <name>100</name>
                  <description>Alternative 4 (chip-specific).</description>
                  <value>#100</value>
                </enumeratedValue>
                <enumeratedValue>
                  <name>101</name>
                  <description>Alternative 5 (chip-specific).</description>
                  <value>#101</value>
                </enumeratedValue>
                <enumeratedValue>
                  <name>110</name>
                  <description>Alternative 6 (chip-specific).</description>
                  <value>#110</value>
                </enumeratedValue>
                <enumeratedValue>
                  <name>111</name>
                  <description>Alternative 7 (chip-specific).</description>
                  <value>#111</value>
                </enumeratedValue>
              </enumeratedValues>
            </field>
            <field>
              <name>IRQC</name>
              <description>Interrupt Configuration</description>
              <bitOffset>16</bitOffset>
              <bitWidth>4</bitWidth>
              <access>read-write</access>
              <enumeratedValues>
                <enumeratedValue>
                  <name>0000</name>
                  <description>Interrupt/DMA request disabled.</description>
                  <value>#0000</value>
                </enumeratedValue>
                <enumeratedValue>
                  <name>0001</name>
                  <description>DMA request on rising edge.</description>
                  <value>#0001</value>
                </enumeratedValue>
                <enumeratedValue>
                  <name>0010</name>
                  <description>DMA request on falling edge.</description>
                  <value>#0010</value>
                </enumeratedValue>
                <enumeratedValue>
                  <name>0011</name>
                  <description>DMA request on either edge.</description>
                  <value>#0011</value>
                </enumeratedValue>
                <enumeratedValue>
                  <name>1000</name>
                  <description>Interrupt when logic 0.</description>
                  <value>#1000</value>
                </enumeratedValue>
                <enumeratedValue>
                  <name>1001</name>
                  <description>Interrupt on rising-edge.</description>
                  <value>#1001</value>
                </enumeratedValue>
                <enumeratedValue>
                  <name>1010</name>
                  <description>Interrupt on falling-edge.</description>
                  <value>#1010</value>
                </enumeratedValue>
                <enumeratedValue>
                  <name>1011</name>
                  <description>Interrupt on either edge.</description>
                  <value>#1011</value>
                </enumeratedValue>
                <enumeratedValue>
                  <name>1100</name>
                  <description>Interrupt when logic 1.</description>
                  <value>#1100</value>
                </enumeratedValue>
              </enumeratedValues>
            </field>
            <field>
              <name>ISF</name>
              <description>Interrupt Status Flag</description>
              <bitOffset>24</bitOffset>
              <bitWidth>1</bitWidth>
              <access>read-write</access>
              <enumeratedValues>
                <enumeratedValue>
                  <name>0</name>
                  <description>Configured interrupt is not detected.</description>
                  <value>#0</value>
                </enumeratedValue>
                <enumeratedValue>
                  <name>1</name>
                  <description>Configured interrupt is detected. If the pin is configured to generate a DMA request, then the corresponding flag will be cleared automatically at the completion of the requested DMA transfer. Otherwise, the flag remains set until a logic 1 is written to the flag. If the pin is configured for a level sensitive interrupt and the pin remains asserted, then the flag is set again immediately after it is cleared.</description>
                  <value>#1</value>
                </enumeratedValue>
              </enumeratedValues>
            </field>
          </fields>
        </register>
        <register>
          <name>PCR19</name>
          <description>Pin Control Register n</description>
          <addressOffset>0x4C</addressOffset>
          <size>32</size>
          <access>read-write</access>
          <resetValue>0</resetValue>
          <resetMask>0xFFFFFFFF</resetMask>
          <fields>
            <field>
              <name>PS</name>
              <description>Pull Select</description>
              <bitOffset>0</bitOffset>
              <bitWidth>1</bitWidth>
              <access>read-only</access>
              <enumeratedValues>
                <enumeratedValue>
                  <name>0</name>
                  <description>Internal pulldown resistor is enabled on the corresponding pin, if the corresponding PE field is set.</description>
                  <value>#0</value>
                </enumeratedValue>
                <enumeratedValue>
                  <name>1</name>
                  <description>Internal pullup resistor is enabled on the corresponding pin, if the corresponding PE field is set.</description>
                  <value>#1</value>
                </enumeratedValue>
              </enumeratedValues>
            </field>
            <field>
              <name>PE</name>
              <description>Pull Enable</description>
              <bitOffset>1</bitOffset>
              <bitWidth>1</bitWidth>
              <access>read-only</access>
              <enumeratedValues>
                <enumeratedValue>
                  <name>0</name>
                  <description>Internal pullup or pulldown resistor is not enabled on the corresponding pin.</description>
                  <value>#0</value>
                </enumeratedValue>
                <enumeratedValue>
                  <name>1</name>
                  <description>Internal pullup or pulldown resistor is enabled on the corresponding pin, if the pin is configured as a digital input.</description>
                  <value>#1</value>
                </enumeratedValue>
              </enumeratedValues>
            </field>
            <field>
              <name>SRE</name>
              <description>Slew Rate Enable</description>
              <bitOffset>2</bitOffset>
              <bitWidth>1</bitWidth>
              <access>read-only</access>
              <enumeratedValues>
                <enumeratedValue>
                  <name>0</name>
                  <description>Fast slew rate is configured on the corresponding pin, if the pin is configured as a digital output.</description>
                  <value>#0</value>
                </enumeratedValue>
                <enumeratedValue>
                  <name>1</name>
                  <description>Slow slew rate is configured on the corresponding pin, if the pin is configured as a digital output.</description>
                  <value>#1</value>
                </enumeratedValue>
              </enumeratedValues>
            </field>
            <field>
              <name>PFE</name>
              <description>Passive Filter Enable</description>
              <bitOffset>4</bitOffset>
              <bitWidth>1</bitWidth>
              <access>read-only</access>
              <enumeratedValues>
                <enumeratedValue>
                  <name>0</name>
                  <description>Passive input filter is disabled on the corresponding pin.</description>
                  <value>#0</value>
                </enumeratedValue>
                <enumeratedValue>
                  <name>1</name>
                  <description>Passive input filter is enabled on the corresponding pin, if the pin is configured as a digital input. Refer to the device data sheet for filter characteristics.</description>
                  <value>#1</value>
                </enumeratedValue>
              </enumeratedValues>
            </field>
            <field>
              <name>DSE</name>
              <description>Drive Strength Enable</description>
              <bitOffset>6</bitOffset>
              <bitWidth>1</bitWidth>
              <access>read-only</access>
              <enumeratedValues>
                <enumeratedValue>
                  <name>0</name>
                  <description>Low drive strength is configured on the corresponding pin, if pin is configured as a digital output.</description>
                  <value>#0</value>
                </enumeratedValue>
                <enumeratedValue>
                  <name>1</name>
                  <description>High drive strength is configured on the corresponding pin, if pin is configured as a digital output.</description>
                  <value>#1</value>
                </enumeratedValue>
              </enumeratedValues>
            </field>
            <field>
              <name>MUX</name>
              <description>Pin Mux Control</description>
              <bitOffset>8</bitOffset>
              <bitWidth>3</bitWidth>
              <access>read-write</access>
              <enumeratedValues>
                <enumeratedValue>
                  <name>000</name>
                  <description>Pin disabled (analog).</description>
                  <value>#000</value>
                </enumeratedValue>
                <enumeratedValue>
                  <name>001</name>
                  <description>Alternative 1 (GPIO).</description>
                  <value>#001</value>
                </enumeratedValue>
                <enumeratedValue>
                  <name>010</name>
                  <description>Alternative 2 (chip-specific).</description>
                  <value>#010</value>
                </enumeratedValue>
                <enumeratedValue>
                  <name>011</name>
                  <description>Alternative 3 (chip-specific).</description>
                  <value>#011</value>
                </enumeratedValue>
                <enumeratedValue>
                  <name>100</name>
                  <description>Alternative 4 (chip-specific).</description>
                  <value>#100</value>
                </enumeratedValue>
                <enumeratedValue>
                  <name>101</name>
                  <description>Alternative 5 (chip-specific).</description>
                  <value>#101</value>
                </enumeratedValue>
                <enumeratedValue>
                  <name>110</name>
                  <description>Alternative 6 (chip-specific).</description>
                  <value>#110</value>
                </enumeratedValue>
                <enumeratedValue>
                  <name>111</name>
                  <description>Alternative 7 (chip-specific).</description>
                  <value>#111</value>
                </enumeratedValue>
              </enumeratedValues>
            </field>
            <field>
              <name>IRQC</name>
              <description>Interrupt Configuration</description>
              <bitOffset>16</bitOffset>
              <bitWidth>4</bitWidth>
              <access>read-write</access>
              <enumeratedValues>
                <enumeratedValue>
                  <name>0000</name>
                  <description>Interrupt/DMA request disabled.</description>
                  <value>#0000</value>
                </enumeratedValue>
                <enumeratedValue>
                  <name>0001</name>
                  <description>DMA request on rising edge.</description>
                  <value>#0001</value>
                </enumeratedValue>
                <enumeratedValue>
                  <name>0010</name>
                  <description>DMA request on falling edge.</description>
                  <value>#0010</value>
                </enumeratedValue>
                <enumeratedValue>
                  <name>0011</name>
                  <description>DMA request on either edge.</description>
                  <value>#0011</value>
                </enumeratedValue>
                <enumeratedValue>
                  <name>1000</name>
                  <description>Interrupt when logic 0.</description>
                  <value>#1000</value>
                </enumeratedValue>
                <enumeratedValue>
                  <name>1001</name>
                  <description>Interrupt on rising-edge.</description>
                  <value>#1001</value>
                </enumeratedValue>
                <enumeratedValue>
                  <name>1010</name>
                  <description>Interrupt on falling-edge.</description>
                  <value>#1010</value>
                </enumeratedValue>
                <enumeratedValue>
                  <name>1011</name>
                  <description>Interrupt on either edge.</description>
                  <value>#1011</value>
                </enumeratedValue>
                <enumeratedValue>
                  <name>1100</name>
                  <description>Interrupt when logic 1.</description>
                  <value>#1100</value>
                </enumeratedValue>
              </enumeratedValues>
            </field>
            <field>
              <name>ISF</name>
              <description>Interrupt Status Flag</description>
              <bitOffset>24</bitOffset>
              <bitWidth>1</bitWidth>
              <access>read-write</access>
              <enumeratedValues>
                <enumeratedValue>
                  <name>0</name>
                  <description>Configured interrupt is not detected.</description>
                  <value>#0</value>
                </enumeratedValue>
                <enumeratedValue>
                  <name>1</name>
                  <description>Configured interrupt is detected. If the pin is configured to generate a DMA request, then the corresponding flag will be cleared automatically at the completion of the requested DMA transfer. Otherwise, the flag remains set until a logic 1 is written to the flag. If the pin is configured for a level sensitive interrupt and the pin remains asserted, then the flag is set again immediately after it is cleared.</description>
                  <value>#1</value>
                </enumeratedValue>
              </enumeratedValues>
            </field>
          </fields>
        </register>
        <register>
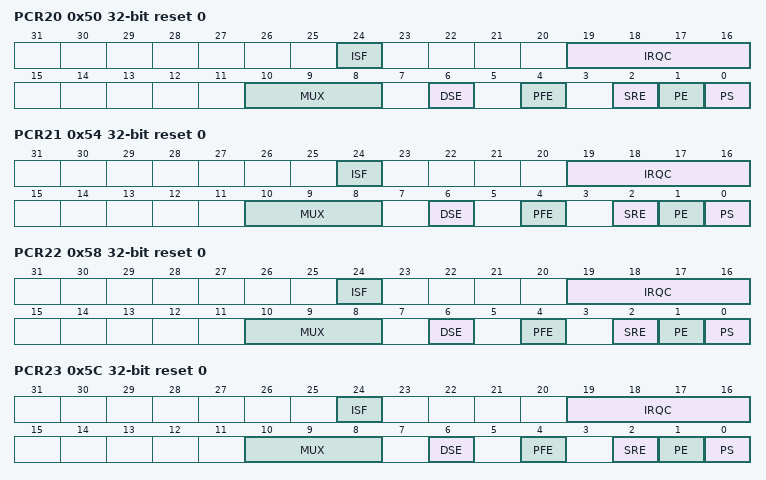
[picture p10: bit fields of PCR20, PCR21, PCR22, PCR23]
          <name>PCR20</name>
          <description>Pin Control Register n</description>
          <addressOffset>0x50</addressOffset>
          <size>32</size>
          <access>read-write</access>
          <resetValue>0</resetValue>
          <resetMask>0xFFFFFFFF</resetMask>
          <fields>
            <field>
              <name>PS</name>
              <description>Pull Select</description>
              <bitOffset>0</bitOffset>
              <bitWidth>1</bitWidth>
              <access>read-only</access>
              <enumeratedValues>
                <enumeratedValue>
                  <name>0</name>
                  <description>Internal pulldown resistor is enabled on the corresponding pin, if the corresponding PE field is set.</description>
                  <value>#0</value>
                </enumeratedValue>
                <enumeratedValue>
                  <name>1</name>
                  <description>Internal pullup resistor is enabled on the corresponding pin, if the corresponding PE field is set.</description>
                  <value>#1</value>
                </enumeratedValue>
              </enumeratedValues>
            </field>
            <field>
              <name>PE</name>
              <description>Pull Enable</description>
              <bitOffset>1</bitOffset>
              <bitWidth>1</bitWidth>
              <access>read-only</access>
              <enumeratedValues>
                <enumeratedValue>
                  <name>0</name>
                  <description>Internal pullup or pulldown resistor is not enabled on the corresponding pin.</description>
                  <value>#0</value>
                </enumeratedValue>
                <enumeratedValue>
                  <name>1</name>
                  <description>Internal pullup or pulldown resistor is enabled on the corresponding pin, if the pin is configured as a digital input.</description>
                  <value>#1</value>
                </enumeratedValue>
              </enumeratedValues>
            </field>
            <field>
              <name>SRE</name>
              <description>Slew Rate Enable</description>
              <bitOffset>2</bitOffset>
              <bitWidth>1</bitWidth>
              <access>read-only</access>
              <enumeratedValues>
                <enumeratedValue>
                  <name>0</name>
                  <description>Fast slew rate is configured on the corresponding pin, if the pin is configured as a digital output.</description>
                  <value>#0</value>
                </enumeratedValue>
                <enumeratedValue>
                  <name>1</name>
                  <description>Slow slew rate is configured on the corresponding pin, if the pin is configured as a digital output.</description>
                  <value>#1</value>
                </enumeratedValue>
              </enumeratedValues>
            </field>
            <field>
              <name>PFE</name>
              <description>Passive Filter Enable</description>
              <bitOffset>4</bitOffset>
              <bitWidth>1</bitWidth>
              <access>read-only</access>
              <enumeratedValues>
                <enumeratedValue>
                  <name>0</name>
                  <description>Passive input filter is disabled on the corresponding pin.</description>
                  <value>#0</value>
                </enumeratedValue>
                <enumeratedValue>
                  <name>1</name>
                  <description>Passive input filter is enabled on the corresponding pin, if the pin is configured as a digital input. Refer to the device data sheet for filter characteristics.</description>
                  <value>#1</value>
                </enumeratedValue>
              </enumeratedValues>
            </field>
            <field>
              <name>DSE</name>
              <description>Drive Strength Enable</description>
              <bitOffset>6</bitOffset>
              <bitWidth>1</bitWidth>
              <access>read-only</access>
              <enumeratedValues>
                <enumeratedValue>
                  <name>0</name>
                  <description>Low drive strength is configured on the corresponding pin, if pin is configured as a digital output.</description>
                  <value>#0</value>
                </enumeratedValue>
                <enumeratedValue>
                  <name>1</name>
                  <description>High drive strength is configured on the corresponding pin, if pin is configured as a digital output.</description>
                  <value>#1</value>
                </enumeratedValue>
              </enumeratedValues>
            </field>
            <field>
              <name>MUX</name>
              <description>Pin Mux Control</description>
              <bitOffset>8</bitOffset>
              <bitWidth>3</bitWidth>
              <access>read-write</access>
              <enumeratedValues>
                <enumeratedValue>
                  <name>000</name>
                  <description>Pin disabled (analog).</description>
                  <value>#000</value>
                </enumeratedValue>
                <enumeratedValue>
                  <name>001</name>
                  <description>Alternative 1 (GPIO).</description>
                  <value>#001</value>
                </enumeratedValue>
                <enumeratedValue>
                  <name>010</name>
                  <description>Alternative 2 (chip-specific).</description>
                  <value>#010</value>
                </enumeratedValue>
                <enumeratedValue>
                  <name>011</name>
                  <description>Alternative 3 (chip-specific).</description>
                  <value>#011</value>
                </enumeratedValue>
                <enumeratedValue>
                  <name>100</name>
                  <description>Alternative 4 (chip-specific).</description>
                  <value>#100</value>
                </enumeratedValue>
                <enumeratedValue>
                  <name>101</name>
                  <description>Alternative 5 (chip-specific).</description>
                  <value>#101</value>
                </enumeratedValue>
                <enumeratedValue>
                  <name>110</name>
                  <description>Alternative 6 (chip-specific).</description>
                  <value>#110</value>
                </enumeratedValue>
                <enumeratedValue>
                  <name>111</name>
                  <description>Alternative 7 (chip-specific).</description>
                  <value>#111</value>
                </enumeratedValue>
              </enumeratedValues>
            </field>
            <field>
              <name>IRQC</name>
              <description>Interrupt Configuration</description>
              <bitOffset>16</bitOffset>
              <bitWidth>4</bitWidth>
              <access>read-write</access>
              <enumeratedValues>
                <enumeratedValue>
                  <name>0000</name>
                  <description>Interrupt/DMA request disabled.</description>
                  <value>#0000</value>
                </enumeratedValue>
                <enumeratedValue>
                  <name>0001</name>
                  <description>DMA request on rising edge.</description>
                  <value>#0001</value>
                </enumeratedValue>
                <enumeratedValue>
                  <name>0010</name>
                  <description>DMA request on falling edge.</description>
                  <value>#0010</value>
                </enumeratedValue>
                <enumeratedValue>
                  <name>0011</name>
                  <description>DMA request on either edge.</description>
                  <value>#0011</value>
                </enumeratedValue>
                <enumeratedValue>
                  <name>1000</name>
                  <description>Interrupt when logic 0.</description>
                  <value>#1000</value>
                </enumeratedValue>
                <enumeratedValue>
                  <name>1001</name>
                  <description>Interrupt on rising-edge.</description>
                  <value>#1001</value>
                </enumeratedValue>
                <enumeratedValue>
                  <name>1010</name>
                  <description>Interrupt on falling-edge.</description>
                  <value>#1010</value>
                </enumeratedValue>
                <enumeratedValue>
                  <name>1011</name>
                  <description>Interrupt on either edge.</description>
                  <value>#1011</value>
                </enumeratedValue>
                <enumeratedValue>
                  <name>1100</name>
                  <description>Interrupt when logic 1.</description>
                  <value>#1100</value>
                </enumeratedValue>
              </enumeratedValues>
            </field>
            <field>
              <name>ISF</name>
              <description>Interrupt Status Flag</description>
              <bitOffset>24</bitOffset>
              <bitWidth>1</bitWidth>
              <access>read-write</access>
              <enumeratedValues>
                <enumeratedValue>
                  <name>0</name>
                  <description>Configured interrupt is not detected.</description>
                  <value>#0</value>
                </enumeratedValue>
                <enumeratedValue>
                  <name>1</name>
                  <description>Configured interrupt is detected. If the pin is configured to generate a DMA request, then the corresponding flag will be cleared automatically at the completion of the requested DMA transfer. Otherwise, the flag remains set until a logic 1 is written to the flag. If the pin is configured for a level sensitive interrupt and the pin remains asserted, then the flag is set again immediately after it is cleared.</description>
                  <value>#1</value>
                </enumeratedValue>
              </enumeratedValues>
            </field>
          </fields>
        </register>
        <register>
          <name>PCR21</name>
          <description>Pin Control Register n</description>
          <addressOffset>0x54</addressOffset>
          <size>32</size>
          <access>read-write</access>
          <resetValue>0</resetValue>
          <resetMask>0xFFFFFFFF</resetMask>
          <fields>
            <field>
              <name>PS</name>
              <description>Pull Select</description>
              <bitOffset>0</bitOffset>
              <bitWidth>1</bitWidth>
              <access>read-only</access>
              <enumeratedValues>
                <enumeratedValue>
                  <name>0</name>
                  <description>Internal pulldown resistor is enabled on the corresponding pin, if the corresponding PE field is set.</description>
                  <value>#0</value>
                </enumeratedValue>
                <enumeratedValue>
                  <name>1</name>
                  <description>Internal pullup resistor is enabled on the corresponding pin, if the corresponding PE field is set.</description>
                  <value>#1</value>
                </enumeratedValue>
              </enumeratedValues>
            </field>
            <field>
              <name>PE</name>
              <description>Pull Enable</description>
              <bitOffset>1</bitOffset>
              <bitWidth>1</bitWidth>
              <access>read-only</access>
              <enumeratedValues>
                <enumeratedValue>
                  <name>0</name>
                  <description>Internal pullup or pulldown resistor is not enabled on the corresponding pin.</description>
                  <value>#0</value>
                </enumeratedValue>
                <enumeratedValue>
                  <name>1</name>
                  <description>Internal pullup or pulldown resistor is enabled on the corresponding pin, if the pin is configured as a digital input.</description>
                  <value>#1</value>
                </enumeratedValue>
              </enumeratedValues>
            </field>
            <field>
              <name>SRE</name>
              <description>Slew Rate Enable</description>
              <bitOffset>2</bitOffset>
              <bitWidth>1</bitWidth>
              <access>read-only</access>
              <enumeratedValues>
                <enumeratedValue>
                  <name>0</name>
                  <description>Fast slew rate is configured on the corresponding pin, if the pin is configured as a digital output.</description>
                  <value>#0</value>
                </enumeratedValue>
                <enumeratedValue>
                  <name>1</name>
                  <description>Slow slew rate is configured on the corresponding pin, if the pin is configured as a digital output.</description>
                  <value>#1</value>
                </enumeratedValue>
              </enumeratedValues>
            </field>
            <field>
              <name>PFE</name>
              <description>Passive Filter Enable</description>
              <bitOffset>4</bitOffset>
              <bitWidth>1</bitWidth>
              <access>read-only</access>
              <enumeratedValues>
                <enumeratedValue>
                  <name>0</name>
                  <description>Passive input filter is disabled on the corresponding pin.</description>
                  <value>#0</value>
                </enumeratedValue>
                <enumeratedValue>
                  <name>1</name>
                  <description>Passive input filter is enabled on the corresponding pin, if the pin is configured as a digital input. Refer to the device data sheet for filter characteristics.</description>
                  <value>#1</value>
                </enumeratedValue>
              </enumeratedValues>
            </field>
            <field>
              <name>DSE</name>
              <description>Drive Strength Enable</description>
              <bitOffset>6</bitOffset>
              <bitWidth>1</bitWidth>
              <access>read-only</access>
              <enumeratedValues>
                <enumeratedValue>
                  <name>0</name>
                  <description>Low drive strength is configured on the corresponding pin, if pin is configured as a digital output.</description>
                  <value>#0</value>
                </enumeratedValue>
                <enumeratedValue>
                  <name>1</name>
                  <description>High drive strength is configured on the corresponding pin, if pin is configured as a digital output.</description>
                  <value>#1</value>
                </enumeratedValue>
              </enumeratedValues>
            </field>
            <field>
              <name>MUX</name>
              <description>Pin Mux Control</description>
              <bitOffset>8</bitOffset>
              <bitWidth>3</bitWidth>
              <access>read-write</access>
              <enumeratedValues>
                <enumeratedValue>
                  <name>000</name>
                  <description>Pin disabled (analog).</description>
                  <value>#000</value>
                </enumeratedValue>
                <enumeratedValue>
                  <name>001</name>
                  <description>Alternative 1 (GPIO).</description>
                  <value>#001</value>
                </enumeratedValue>
                <enumeratedValue>
                  <name>010</name>
                  <description>Alternative 2 (chip-specific).</description>
                  <value>#010</value>
                </enumeratedValue>
                <enumeratedValue>
                  <name>011</name>
                  <description>Alternative 3 (chip-specific).</description>
                  <value>#011</value>
                </enumeratedValue>
                <enumeratedValue>
                  <name>100</name>
                  <description>Alternative 4 (chip-specific).</description>
                  <value>#100</value>
                </enumeratedValue>
                <enumeratedValue>
                  <name>101</name>
                  <description>Alternative 5 (chip-specific).</description>
                  <value>#101</value>
                </enumeratedValue>
                <enumeratedValue>
                  <name>110</name>
                  <description>Alternative 6 (chip-specific).</description>
                  <value>#110</value>
                </enumeratedValue>
                <enumeratedValue>
                  <name>111</name>
                  <description>Alternative 7 (chip-specific).</description>
                  <value>#111</value>
                </enumeratedValue>
              </enumeratedValues>
            </field>
            <field>
              <name>IRQC</name>
              <description>Interrupt Configuration</description>
              <bitOffset>16</bitOffset>
              <bitWidth>4</bitWidth>
              <access>read-write</access>
              <enumeratedValues>
                <enumeratedValue>
                  <name>0000</name>
                  <description>Interrupt/DMA request disabled.</description>
                  <value>#0000</value>
                </enumeratedValue>
                <enumeratedValue>
                  <name>0001</name>
                  <description>DMA request on rising edge.</description>
                  <value>#0001</value>
                </enumeratedValue>
                <enumeratedValue>
                  <name>0010</name>
                  <description>DMA request on falling edge.</description>
                  <value>#0010</value>
                </enumeratedValue>
                <enumeratedValue>
                  <name>0011</name>
                  <description>DMA request on either edge.</description>
                  <value>#0011</value>
                </enumeratedValue>
                <enumeratedValue>
                  <name>1000</name>
                  <description>Interrupt when logic 0.</description>
                  <value>#1000</value>
                </enumeratedValue>
                <enumeratedValue>
                  <name>1001</name>
                  <description>Interrupt on rising-edge.</description>
                  <value>#1001</value>
                </enumeratedValue>
                <enumeratedValue>
                  <name>1010</name>
                  <description>Interrupt on falling-edge.</description>
                  <value>#1010</value>
                </enumeratedValue>
                <enumeratedValue>
                  <name>1011</name>
                  <description>Interrupt on either edge.</description>
                  <value>#1011</value>
                </enumeratedValue>
                <enumeratedValue>
                  <name>1100</name>
                  <description>Interrupt when logic 1.</description>
                  <value>#1100</value>
                </enumeratedValue>
              </enumeratedValues>
            </field>
            <field>
              <name>ISF</name>
              <description>Interrupt Status Flag</description>
              <bitOffset>24</bitOffset>
              <bitWidth>1</bitWidth>
              <access>read-write</access>
              <enumeratedValues>
                <enumeratedValue>
                  <name>0</name>
                  <description>Configured interrupt is not detected.</description>
                  <value>#0</value>
                </enumeratedValue>
                <enumeratedValue>
                  <name>1</name>
                  <description>Configured interrupt is detected. If the pin is configured to generate a DMA request, then the corresponding flag will be cleared automatically at the completion of the requested DMA transfer. Otherwise, the flag remains set until a logic 1 is written to the flag. If the pin is configured for a level sensitive interrupt and the pin remains asserted, then the flag is set again immediately after it is cleared.</description>
                  <value>#1</value>
                </enumeratedValue>
              </enumeratedValues>
            </field>
          </fields>
        </register>
        <register>
          <name>PCR22</name>
          <description>Pin Control Register n</description>
          <addressOffset>0x58</addressOffset>
          <size>32</size>
          <access>read-write</access>
          <resetValue>0</resetValue>
          <resetMask>0xFFFFFFFF</resetMask>
          <fields>
            <field>
              <name>PS</name>
              <description>Pull Select</description>
              <bitOffset>0</bitOffset>
              <bitWidth>1</bitWidth>
              <access>read-only</access>
              <enumeratedValues>
                <enumeratedValue>
                  <name>0</name>
                  <description>Internal pulldown resistor is enabled on the corresponding pin, if the corresponding PE field is set.</description>
                  <value>#0</value>
                </enumeratedValue>
                <enumeratedValue>
                  <name>1</name>
                  <description>Internal pullup resistor is enabled on the corresponding pin, if the corresponding PE field is set.</description>
                  <value>#1</value>
                </enumeratedValue>
              </enumeratedValues>
            </field>
            <field>
              <name>PE</name>
              <description>Pull Enable</description>
              <bitOffset>1</bitOffset>
              <bitWidth>1</bitWidth>
              <access>read-only</access>
              <enumeratedValues>
                <enumeratedValue>
                  <name>0</name>
                  <description>Internal pullup or pulldown resistor is not enabled on the corresponding pin.</description>
                  <value>#0</value>
                </enumeratedValue>
                <enumeratedValue>
                  <name>1</name>
                  <description>Internal pullup or pulldown resistor is enabled on the corresponding pin, if the pin is configured as a digital input.</description>
                  <value>#1</value>
                </enumeratedValue>
              </enumeratedValues>
            </field>
            <field>
              <name>SRE</name>
              <description>Slew Rate Enable</description>
              <bitOffset>2</bitOffset>
              <bitWidth>1</bitWidth>
              <access>read-only</access>
              <enumeratedValues>
                <enumeratedValue>
                  <name>0</name>
                  <description>Fast slew rate is configured on the corresponding pin, if the pin is configured as a digital output.</description>
                  <value>#0</value>
                </enumeratedValue>
                <enumeratedValue>
                  <name>1</name>
                  <description>Slow slew rate is configured on the corresponding pin, if the pin is configured as a digital output.</description>
                  <value>#1</value>
                </enumeratedValue>
              </enumeratedValues>
            </field>
            <field>
              <name>PFE</name>
              <description>Passive Filter Enable</description>
              <bitOffset>4</bitOffset>
              <bitWidth>1</bitWidth>
              <access>read-only</access>
              <enumeratedValues>
                <enumeratedValue>
                  <name>0</name>
                  <description>Passive input filter is disabled on the corresponding pin.</description>
                  <value>#0</value>
                </enumeratedValue>
                <enumeratedValue>
                  <name>1</name>
                  <description>Passive input filter is enabled on the corresponding pin, if the pin is configured as a digital input. Refer to the device data sheet for filter characteristics.</description>
                  <value>#1</value>
                </enumeratedValue>
              </enumeratedValues>
            </field>
            <field>
              <name>DSE</name>
              <description>Drive Strength Enable</description>
              <bitOffset>6</bitOffset>
              <bitWidth>1</bitWidth>
              <access>read-only</access>
              <enumeratedValues>
                <enumeratedValue>
                  <name>0</name>
                  <description>Low drive strength is configured on the corresponding pin, if pin is configured as a digital output.</description>
                  <value>#0</value>
                </enumeratedValue>
                <enumeratedValue>
                  <name>1</name>
                  <description>High drive strength is configured on the corresponding pin, if pin is configured as a digital output.</description>
                  <value>#1</value>
                </enumeratedValue>
              </enumeratedValues>
            </field>
            <field>
              <name>MUX</name>
              <description>Pin Mux Control</description>
              <bitOffset>8</bitOffset>
              <bitWidth>3</bitWidth>
              <access>read-write</access>
              <enumeratedValues>
                <enumeratedValue>
                  <name>000</name>
                  <description>Pin disabled (analog).</description>
                  <value>#000</value>
                </enumeratedValue>
                <enumeratedValue>
                  <name>001</name>
                  <description>Alternative 1 (GPIO).</description>
                  <value>#001</value>
                </enumeratedValue>
                <enumeratedValue>
                  <name>010</name>
                  <description>Alternative 2 (chip-specific).</description>
                  <value>#010</value>
                </enumeratedValue>
                <enumeratedValue>
                  <name>011</name>
                  <description>Alternative 3 (chip-specific).</description>
                  <value>#011</value>
                </enumeratedValue>
                <enumeratedValue>
                  <name>100</name>
                  <description>Alternative 4 (chip-specific).</description>
                  <value>#100</value>
                </enumeratedValue>
                <enumeratedValue>
                  <name>101</name>
                  <description>Alternative 5 (chip-specific).</description>
                  <value>#101</value>
                </enumeratedValue>
                <enumeratedValue>
                  <name>110</name>
                  <description>Alternative 6 (chip-specific).</description>
                  <value>#110</value>
                </enumeratedValue>
                <enumeratedValue>
                  <name>111</name>
                  <description>Alternative 7 (chip-specific).</description>
                  <value>#111</value>
                </enumeratedValue>
              </enumeratedValues>
            </field>
            <field>
              <name>IRQC</name>
              <description>Interrupt Configuration</description>
              <bitOffset>16</bitOffset>
              <bitWidth>4</bitWidth>
              <access>read-write</access>
              <enumeratedValues>
                <enumeratedValue>
                  <name>0000</name>
                  <description>Interrupt/DMA request disabled.</description>
                  <value>#0000</value>
                </enumeratedValue>
                <enumeratedValue>
                  <name>0001</name>
                  <description>DMA request on rising edge.</description>
                  <value>#0001</value>
                </enumeratedValue>
                <enumeratedValue>
                  <name>0010</name>
                  <description>DMA request on falling edge.</description>
                  <value>#0010</value>
                </enumeratedValue>
                <enumeratedValue>
                  <name>0011</name>
                  <description>DMA request on either edge.</description>
                  <value>#0011</value>
                </enumeratedValue>
                <enumeratedValue>
                  <name>1000</name>
                  <description>Interrupt when logic 0.</description>
                  <value>#1000</value>
                </enumeratedValue>
                <enumeratedValue>
                  <name>1001</name>
                  <description>Interrupt on rising-edge.</description>
                  <value>#1001</value>
                </enumeratedValue>
                <enumeratedValue>
                  <name>1010</name>
                  <description>Interrupt on falling-edge.</description>
                  <value>#1010</value>
                </enumeratedValue>
                <enumeratedValue>
                  <name>1011</name>
                  <description>Interrupt on either edge.</description>
                  <value>#1011</value>
                </enumeratedValue>
                <enumeratedValue>
                  <name>1100</name>
                  <description>Interrupt when logic 1.</description>
                  <value>#1100</value>
                </enumeratedValue>
              </enumeratedValues>
            </field>
            <field>
              <name>ISF</name>
              <description>Interrupt Status Flag</description>
              <bitOffset>24</bitOffset>
              <bitWidth>1</bitWidth>
              <access>read-write</access>
              <enumeratedValues>
                <enumeratedValue>
                  <name>0</name>
                  <description>Configured interrupt is not detected.</description>
                  <value>#0</value>
                </enumeratedValue>
                <enumeratedValue>
                  <name>1</name>
                  <description>Configured interrupt is detected. If the pin is configured to generate a DMA request, then the corresponding flag will be cleared automatically at the completion of the requested DMA transfer. Otherwise, the flag remains set until a logic 1 is written to the flag. If the pin is configured for a level sensitive interrupt and the pin remains asserted, then the flag is set again immediately after it is cleared.</description>
                  <value>#1</value>
                </enumeratedValue>
              </enumeratedValues>
            </field>
          </fields>
        </register>
        <register>
          <name>PCR23</name>
          <description>Pin Control Register n</description>
          <addressOffset>0x5C</addressOffset>
          <size>32</size>
          <access>read-write</access>
          <resetValue>0</resetValue>
          <resetMask>0xFFFFFFFF</resetMask>
          <fields>
            <field>
              <name>PS</name>
              <description>Pull Select</description>
              <bitOffset>0</bitOffset>
              <bitWidth>1</bitWidth>
              <access>read-only</access>
              <enumeratedValues>
                <enumeratedValue>
                  <name>0</name>
                  <description>Internal pulldown resistor is enabled on the corresponding pin, if the corresponding PE field is set.</description>
                  <value>#0</value>
                </enumeratedValue>
                <enumeratedValue>
                  <name>1</name>
                  <description>Internal pullup resistor is enabled on the corresponding pin, if the corresponding PE field is set.</description>
                  <value>#1</value>
                </enumeratedValue>
              </enumeratedValues>
            </field>
            <field>
              <name>PE</name>
              <description>Pull Enable</description>
              <bitOffset>1</bitOffset>
              <bitWidth>1</bitWidth>
              <access>read-only</access>
              <enumeratedValues>
                <enumeratedValue>
                  <name>0</name>
                  <description>Internal pullup or pulldown resistor is not enabled on the corresponding pin.</description>
                  <value>#0</value>
                </enumeratedValue>
                <enumeratedValue>
                  <name>1</name>
                  <description>Internal pullup or pulldown resistor is enabled on the corresponding pin, if the pin is configured as a digital input.</description>
                  <value>#1</value>
                </enumeratedValue>
              </enumeratedValues>
            </field>
            <field>
              <name>SRE</name>
              <description>Slew Rate Enable</description>
              <bitOffset>2</bitOffset>
              <bitWidth>1</bitWidth>
              <access>read-only</access>
              <enumeratedValues>
                <enumeratedValue>
                  <name>0</name>
                  <description>Fast slew rate is configured on the corresponding pin, if the pin is configured as a digital output.</description>
                  <value>#0</value>
                </enumeratedValue>
                <enumeratedValue>
                  <name>1</name>
                  <description>Slow slew rate is configured on the corresponding pin, if the pin is configured as a digital output.</description>
                  <value>#1</value>
                </enumeratedValue>
              </enumeratedValues>
            </field>
            <field>
              <name>PFE</name>
              <description>Passive Filter Enable</description>
              <bitOffset>4</bitOffset>
              <bitWidth>1</bitWidth>
              <access>read-only</access>
              <enumeratedValues>
                <enumeratedValue>
                  <name>0</name>
                  <description>Passive input filter is disabled on the corresponding pin.</description>
                  <value>#0</value>
                </enumeratedValue>
                <enumeratedValue>
                  <name>1</name>
                  <description>Passive input filter is enabled on the corresponding pin, if the pin is configured as a digital input. Refer to the device data sheet for filter characteristics.</description>
                  <value>#1</value>
                </enumeratedValue>
              </enumeratedValues>
            </field>
            <field>
              <name>DSE</name>
              <description>Drive Strength Enable</description>
              <bitOffset>6</bitOffset>
              <bitWidth>1</bitWidth>
              <access>read-only</access>
              <enumeratedValues>
                <enumeratedValue>
                  <name>0</name>
                  <description>Low drive strength is configured on the corresponding pin, if pin is configured as a digital output.</description>
                  <value>#0</value>
                </enumeratedValue>
                <enumeratedValue>
                  <name>1</name>
                  <description>High drive strength is configured on the corresponding pin, if pin is configured as a digital output.</description>
                  <value>#1</value>
                </enumeratedValue>
              </enumeratedValues>
            </field>
            <field>
              <name>MUX</name>
              <description>Pin Mux Control</description>
              <bitOffset>8</bitOffset>
              <bitWidth>3</bitWidth>
              <access>read-write</access>
              <enumeratedValues>
                <enumeratedValue>
                  <name>000</name>
                  <description>Pin disabled (analog).</description>
                  <value>#000</value>
                </enumeratedValue>
                <enumeratedValue>
                  <name>001</name>
                  <description>Alternative 1 (GPIO).</description>
                  <value>#001</value>
                </enumeratedValue>
                <enumeratedValue>
                  <name>010</name>
                  <description>Alternative 2 (chip-specific).</description>
                  <value>#010</value>
                </enumeratedValue>
                <enumeratedValue>
                  <name>011</name>
                  <description>Alternative 3 (chip-specific).</description>
                  <value>#011</value>
                </enumeratedValue>
                <enumeratedValue>
                  <name>100</name>
                  <description>Alternative 4 (chip-specific).</description>
                  <value>#100</value>
                </enumeratedValue>
                <enumeratedValue>
                  <name>101</name>
                  <description>Alternative 5 (chip-specific).</description>
                  <value>#101</value>
                </enumeratedValue>
                <enumeratedValue>
                  <name>110</name>
                  <description>Alternative 6 (chip-specific).</description>
                  <value>#110</value>
                </enumeratedValue>
                <enumeratedValue>
                  <name>111</name>
                  <description>Alternative 7 (chip-specific).</description>
                  <value>#111</value>
                </enumeratedValue>
              </enumeratedValues>
            </field>
            <field>
              <name>IRQC</name>
              <description>Interrupt Configuration</description>
              <bitOffset>16</bitOffset>
              <bitWidth>4</bitWidth>
              <access>read-write</access>
              <enumeratedValues>
                <enumeratedValue>
                  <name>0000</name>
                  <description>Interrupt/DMA request disabled.</description>
                  <value>#0000</value>
                </enumeratedValue>
                <enumeratedValue>
                  <name>0001</name>
                  <description>DMA request on rising edge.</description>
                  <value>#0001</value>
                </enumeratedValue>
                <enumeratedValue>
                  <name>0010</name>
                  <description>DMA request on falling edge.</description>
                  <value>#0010</value>
                </enumeratedValue>
                <enumeratedValue>
                  <name>0011</name>
                  <description>DMA request on either edge.</description>
                  <value>#0011</value>
                </enumeratedValue>
                <enumeratedValue>
                  <name>1000</name>
                  <description>Interrupt when logic 0.</description>
                  <value>#1000</value>
                </enumeratedValue>
                <enumeratedValue>
                  <name>1001</name>
                  <description>Interrupt on rising-edge.</description>
                  <value>#1001</value>
                </enumeratedValue>
                <enumeratedValue>
                  <name>1010</name>
                  <description>Interrupt on falling-edge.</description>
                  <value>#1010</value>
                </enumeratedValue>
                <enumeratedValue>
                  <name>1011</name>
                  <description>Interrupt on either edge.</description>
                  <value>#1011</value>
                </enumeratedValue>
                <enumeratedValue>
                  <name>1100</name>
                  <description>Interrupt when logic 1.</description>
                  <value>#1100</value>
                </enumeratedValue>
              </enumeratedValues>
            </field>
            <field>
              <name>ISF</name>
              <description>Interrupt Status Flag</description>
              <bitOffset>24</bitOffset>
              <bitWidth>1</bitWidth>
              <access>read-write</access>
              <enumeratedValues>
                <enumeratedValue>
                  <name>0</name>
                  <description>Configured interrupt is not detected.</description>
                  <value>#0</value>
                </enumeratedValue>
                <enumeratedValue>
                  <name>1</name>
                  <description>Configured interrupt is detected. If the pin is configured to generate a DMA request, then the corresponding flag will be cleared automatically at the completion of the requested DMA transfer. Otherwise, the flag remains set until a logic 1 is written to the flag. If the pin is configured for a level sensitive interrupt and the pin remains asserted, then the flag is set again immediately after it is cleared.</description>
                  <value>#1</value>
                </enumeratedValue>
              </enumeratedValues>
            </field>
          </fields>
        </register>
        <register>
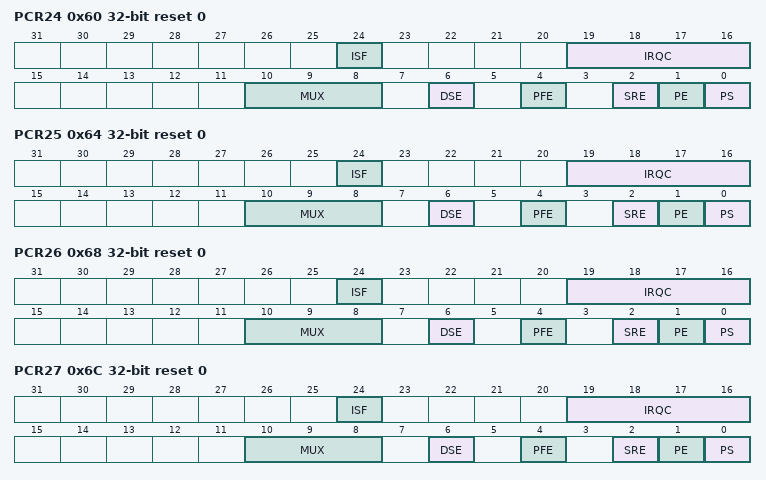
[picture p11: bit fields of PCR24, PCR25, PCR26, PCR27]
          <name>PCR24</name>
          <description>Pin Control Register n</description>
          <addressOffset>0x60</addressOffset>
          <size>32</size>
          <access>read-write</access>
          <resetValue>0</resetValue>
          <resetMask>0xFFFFFFFF</resetMask>
          <fields>
            <field>
              <name>PS</name>
              <description>Pull Select</description>
              <bitOffset>0</bitOffset>
              <bitWidth>1</bitWidth>
              <access>read-only</access>
              <enumeratedValues>
                <enumeratedValue>
                  <name>0</name>
                  <description>Internal pulldown resistor is enabled on the corresponding pin, if the corresponding PE field is set.</description>
                  <value>#0</value>
                </enumeratedValue>
                <enumeratedValue>
                  <name>1</name>
                  <description>Internal pullup resistor is enabled on the corresponding pin, if the corresponding PE field is set.</description>
                  <value>#1</value>
                </enumeratedValue>
              </enumeratedValues>
            </field>
            <field>
              <name>PE</name>
              <description>Pull Enable</description>
              <bitOffset>1</bitOffset>
              <bitWidth>1</bitWidth>
              <access>read-only</access>
              <enumeratedValues>
                <enumeratedValue>
                  <name>0</name>
                  <description>Internal pullup or pulldown resistor is not enabled on the corresponding pin.</description>
                  <value>#0</value>
                </enumeratedValue>
                <enumeratedValue>
                  <name>1</name>
                  <description>Internal pullup or pulldown resistor is enabled on the corresponding pin, if the pin is configured as a digital input.</description>
                  <value>#1</value>
                </enumeratedValue>
              </enumeratedValues>
            </field>
            <field>
              <name>SRE</name>
              <description>Slew Rate Enable</description>
              <bitOffset>2</bitOffset>
              <bitWidth>1</bitWidth>
              <access>read-only</access>
              <enumeratedValues>
                <enumeratedValue>
                  <name>0</name>
                  <description>Fast slew rate is configured on the corresponding pin, if the pin is configured as a digital output.</description>
                  <value>#0</value>
                </enumeratedValue>
                <enumeratedValue>
                  <name>1</name>
                  <description>Slow slew rate is configured on the corresponding pin, if the pin is configured as a digital output.</description>
                  <value>#1</value>
                </enumeratedValue>
              </enumeratedValues>
            </field>
            <field>
              <name>PFE</name>
              <description>Passive Filter Enable</description>
              <bitOffset>4</bitOffset>
              <bitWidth>1</bitWidth>
              <access>read-only</access>
              <enumeratedValues>
                <enumeratedValue>
                  <name>0</name>
                  <description>Passive input filter is disabled on the corresponding pin.</description>
                  <value>#0</value>
                </enumeratedValue>
                <enumeratedValue>
                  <name>1</name>
                  <description>Passive input filter is enabled on the corresponding pin, if the pin is configured as a digital input. Refer to the device data sheet for filter characteristics.</description>
                  <value>#1</value>
                </enumeratedValue>
              </enumeratedValues>
            </field>
            <field>
              <name>DSE</name>
              <description>Drive Strength Enable</description>
              <bitOffset>6</bitOffset>
              <bitWidth>1</bitWidth>
              <access>read-only</access>
              <enumeratedValues>
                <enumeratedValue>
                  <name>0</name>
                  <description>Low drive strength is configured on the corresponding pin, if pin is configured as a digital output.</description>
                  <value>#0</value>
                </enumeratedValue>
                <enumeratedValue>
                  <name>1</name>
                  <description>High drive strength is configured on the corresponding pin, if pin is configured as a digital output.</description>
                  <value>#1</value>
                </enumeratedValue>
              </enumeratedValues>
            </field>
            <field>
              <name>MUX</name>
              <description>Pin Mux Control</description>
              <bitOffset>8</bitOffset>
              <bitWidth>3</bitWidth>
              <access>read-write</access>
              <enumeratedValues>
                <enumeratedValue>
                  <name>000</name>
                  <description>Pin disabled (analog).</description>
                  <value>#000</value>
                </enumeratedValue>
                <enumeratedValue>
                  <name>001</name>
                  <description>Alternative 1 (GPIO).</description>
                  <value>#001</value>
                </enumeratedValue>
                <enumeratedValue>
                  <name>010</name>
                  <description>Alternative 2 (chip-specific).</description>
                  <value>#010</value>
                </enumeratedValue>
                <enumeratedValue>
                  <name>011</name>
                  <description>Alternative 3 (chip-specific).</description>
                  <value>#011</value>
                </enumeratedValue>
                <enumeratedValue>
                  <name>100</name>
                  <description>Alternative 4 (chip-specific).</description>
                  <value>#100</value>
                </enumeratedValue>
                <enumeratedValue>
                  <name>101</name>
                  <description>Alternative 5 (chip-specific).</description>
                  <value>#101</value>
                </enumeratedValue>
                <enumeratedValue>
                  <name>110</name>
                  <description>Alternative 6 (chip-specific).</description>
                  <value>#110</value>
                </enumeratedValue>
                <enumeratedValue>
                  <name>111</name>
                  <description>Alternative 7 (chip-specific).</description>
                  <value>#111</value>
                </enumeratedValue>
              </enumeratedValues>
            </field>
            <field>
              <name>IRQC</name>
              <description>Interrupt Configuration</description>
              <bitOffset>16</bitOffset>
              <bitWidth>4</bitWidth>
              <access>read-write</access>
              <enumeratedValues>
                <enumeratedValue>
                  <name>0000</name>
                  <description>Interrupt/DMA request disabled.</description>
                  <value>#0000</value>
                </enumeratedValue>
                <enumeratedValue>
                  <name>0001</name>
                  <description>DMA request on rising edge.</description>
                  <value>#0001</value>
                </enumeratedValue>
                <enumeratedValue>
                  <name>0010</name>
                  <description>DMA request on falling edge.</description>
                  <value>#0010</value>
                </enumeratedValue>
                <enumeratedValue>
                  <name>0011</name>
                  <description>DMA request on either edge.</description>
                  <value>#0011</value>
                </enumeratedValue>
                <enumeratedValue>
                  <name>1000</name>
                  <description>Interrupt when logic 0.</description>
                  <value>#1000</value>
                </enumeratedValue>
                <enumeratedValue>
                  <name>1001</name>
                  <description>Interrupt on rising-edge.</description>
                  <value>#1001</value>
                </enumeratedValue>
                <enumeratedValue>
                  <name>1010</name>
                  <description>Interrupt on falling-edge.</description>
                  <value>#1010</value>
                </enumeratedValue>
                <enumeratedValue>
                  <name>1011</name>
                  <description>Interrupt on either edge.</description>
                  <value>#1011</value>
                </enumeratedValue>
                <enumeratedValue>
                  <name>1100</name>
                  <description>Interrupt when logic 1.</description>
                  <value>#1100</value>
                </enumeratedValue>
              </enumeratedValues>
            </field>
            <field>
              <name>ISF</name>
              <description>Interrupt Status Flag</description>
              <bitOffset>24</bitOffset>
              <bitWidth>1</bitWidth>
              <access>read-write</access>
              <enumeratedValues>
                <enumeratedValue>
                  <name>0</name>
                  <description>Configured interrupt is not detected.</description>
                  <value>#0</value>
                </enumeratedValue>
                <enumeratedValue>
                  <name>1</name>
                  <description>Configured interrupt is detected. If the pin is configured to generate a DMA request, then the corresponding flag will be cleared automatically at the completion of the requested DMA transfer. Otherwise, the flag remains set until a logic 1 is written to the flag. If the pin is configured for a level sensitive interrupt and the pin remains asserted, then the flag is set again immediately after it is cleared.</description>
                  <value>#1</value>
                </enumeratedValue>
              </enumeratedValues>
            </field>
          </fields>
        </register>
        <register>
          <name>PCR25</name>
          <description>Pin Control Register n</description>
          <addressOffset>0x64</addressOffset>
          <size>32</size>
          <access>read-write</access>
          <resetValue>0</resetValue>
          <resetMask>0xFFFFFFFF</resetMask>
          <fields>
            <field>
              <name>PS</name>
              <description>Pull Select</description>
              <bitOffset>0</bitOffset>
              <bitWidth>1</bitWidth>
              <access>read-only</access>
              <enumeratedValues>
                <enumeratedValue>
                  <name>0</name>
                  <description>Internal pulldown resistor is enabled on the corresponding pin, if the corresponding PE field is set.</description>
                  <value>#0</value>
                </enumeratedValue>
                <enumeratedValue>
                  <name>1</name>
                  <description>Internal pullup resistor is enabled on the corresponding pin, if the corresponding PE field is set.</description>
                  <value>#1</value>
                </enumeratedValue>
              </enumeratedValues>
            </field>
            <field>
              <name>PE</name>
              <description>Pull Enable</description>
              <bitOffset>1</bitOffset>
              <bitWidth>1</bitWidth>
              <access>read-only</access>
              <enumeratedValues>
                <enumeratedValue>
                  <name>0</name>
                  <description>Internal pullup or pulldown resistor is not enabled on the corresponding pin.</description>
                  <value>#0</value>
                </enumeratedValue>
                <enumeratedValue>
                  <name>1</name>
                  <description>Internal pullup or pulldown resistor is enabled on the corresponding pin, if the pin is configured as a digital input.</description>
                  <value>#1</value>
                </enumeratedValue>
              </enumeratedValues>
            </field>
            <field>
              <name>SRE</name>
              <description>Slew Rate Enable</description>
              <bitOffset>2</bitOffset>
              <bitWidth>1</bitWidth>
              <access>read-only</access>
              <enumeratedValues>
                <enumeratedValue>
                  <name>0</name>
                  <description>Fast slew rate is configured on the corresponding pin, if the pin is configured as a digital output.</description>
                  <value>#0</value>
                </enumeratedValue>
                <enumeratedValue>
                  <name>1</name>
                  <description>Slow slew rate is configured on the corresponding pin, if the pin is configured as a digital output.</description>
                  <value>#1</value>
                </enumeratedValue>
              </enumeratedValues>
            </field>
            <field>
              <name>PFE</name>
              <description>Passive Filter Enable</description>
              <bitOffset>4</bitOffset>
              <bitWidth>1</bitWidth>
              <access>read-only</access>
              <enumeratedValues>
                <enumeratedValue>
                  <name>0</name>
                  <description>Passive input filter is disabled on the corresponding pin.</description>
                  <value>#0</value>
                </enumeratedValue>
                <enumeratedValue>
                  <name>1</name>
                  <description>Passive input filter is enabled on the corresponding pin, if the pin is configured as a digital input. Refer to the device data sheet for filter characteristics.</description>
                  <value>#1</value>
                </enumeratedValue>
              </enumeratedValues>
            </field>
            <field>
              <name>DSE</name>
              <description>Drive Strength Enable</description>
              <bitOffset>6</bitOffset>
              <bitWidth>1</bitWidth>
              <access>read-only</access>
              <enumeratedValues>
                <enumeratedValue>
                  <name>0</name>
                  <description>Low drive strength is configured on the corresponding pin, if pin is configured as a digital output.</description>
                  <value>#0</value>
                </enumeratedValue>
                <enumeratedValue>
                  <name>1</name>
                  <description>High drive strength is configured on the corresponding pin, if pin is configured as a digital output.</description>
                  <value>#1</value>
                </enumeratedValue>
              </enumeratedValues>
            </field>
            <field>
              <name>MUX</name>
              <description>Pin Mux Control</description>
              <bitOffset>8</bitOffset>
              <bitWidth>3</bitWidth>
              <access>read-write</access>
              <enumeratedValues>
                <enumeratedValue>
                  <name>000</name>
                  <description>Pin disabled (analog).</description>
                  <value>#000</value>
                </enumeratedValue>
                <enumeratedValue>
                  <name>001</name>
                  <description>Alternative 1 (GPIO).</description>
                  <value>#001</value>
                </enumeratedValue>
                <enumeratedValue>
                  <name>010</name>
                  <description>Alternative 2 (chip-specific).</description>
                  <value>#010</value>
                </enumeratedValue>
                <enumeratedValue>
                  <name>011</name>
                  <description>Alternative 3 (chip-specific).</description>
                  <value>#011</value>
                </enumeratedValue>
                <enumeratedValue>
                  <name>100</name>
                  <description>Alternative 4 (chip-specific).</description>
                  <value>#100</value>
                </enumeratedValue>
                <enumeratedValue>
                  <name>101</name>
                  <description>Alternative 5 (chip-specific).</description>
                  <value>#101</value>
                </enumeratedValue>
                <enumeratedValue>
                  <name>110</name>
                  <description>Alternative 6 (chip-specific).</description>
                  <value>#110</value>
                </enumeratedValue>
                <enumeratedValue>
                  <name>111</name>
                  <description>Alternative 7 (chip-specific).</description>
                  <value>#111</value>
                </enumeratedValue>
              </enumeratedValues>
            </field>
            <field>
              <name>IRQC</name>
              <description>Interrupt Configuration</description>
              <bitOffset>16</bitOffset>
              <bitWidth>4</bitWidth>
              <access>read-write</access>
              <enumeratedValues>
                <enumeratedValue>
                  <name>0000</name>
                  <description>Interrupt/DMA request disabled.</description>
                  <value>#0000</value>
                </enumeratedValue>
                <enumeratedValue>
                  <name>0001</name>
                  <description>DMA request on rising edge.</description>
                  <value>#0001</value>
                </enumeratedValue>
                <enumeratedValue>
                  <name>0010</name>
                  <description>DMA request on falling edge.</description>
                  <value>#0010</value>
                </enumeratedValue>
                <enumeratedValue>
                  <name>0011</name>
                  <description>DMA request on either edge.</description>
                  <value>#0011</value>
                </enumeratedValue>
                <enumeratedValue>
                  <name>1000</name>
                  <description>Interrupt when logic 0.</description>
                  <value>#1000</value>
                </enumeratedValue>
                <enumeratedValue>
                  <name>1001</name>
                  <description>Interrupt on rising-edge.</description>
                  <value>#1001</value>
                </enumeratedValue>
                <enumeratedValue>
                  <name>1010</name>
                  <description>Interrupt on falling-edge.</description>
                  <value>#1010</value>
                </enumeratedValue>
                <enumeratedValue>
                  <name>1011</name>
                  <description>Interrupt on either edge.</description>
                  <value>#1011</value>
                </enumeratedValue>
                <enumeratedValue>
                  <name>1100</name>
                  <description>Interrupt when logic 1.</description>
                  <value>#1100</value>
                </enumeratedValue>
              </enumeratedValues>
            </field>
            <field>
              <name>ISF</name>
              <description>Interrupt Status Flag</description>
              <bitOffset>24</bitOffset>
              <bitWidth>1</bitWidth>
              <access>read-write</access>
              <enumeratedValues>
                <enumeratedValue>
                  <name>0</name>
                  <description>Configured interrupt is not detected.</description>
                  <value>#0</value>
                </enumeratedValue>
                <enumeratedValue>
                  <name>1</name>
                  <description>Configured interrupt is detected. If the pin is configured to generate a DMA request, then the corresponding flag will be cleared automatically at the completion of the requested DMA transfer. Otherwise, the flag remains set until a logic 1 is written to the flag. If the pin is configured for a level sensitive interrupt and the pin remains asserted, then the flag is set again immediately after it is cleared.</description>
                  <value>#1</value>
                </enumeratedValue>
              </enumeratedValues>
            </field>
          </fields>
        </register>
        <register>
          <name>PCR26</name>
          <description>Pin Control Register n</description>
          <addressOffset>0x68</addressOffset>
          <size>32</size>
          <access>read-write</access>
          <resetValue>0</resetValue>
          <resetMask>0xFFFFFFFF</resetMask>
          <fields>
            <field>
              <name>PS</name>
              <description>Pull Select</description>
              <bitOffset>0</bitOffset>
              <bitWidth>1</bitWidth>
              <access>read-only</access>
              <enumeratedValues>
                <enumeratedValue>
                  <name>0</name>
                  <description>Internal pulldown resistor is enabled on the corresponding pin, if the corresponding PE field is set.</description>
                  <value>#0</value>
                </enumeratedValue>
                <enumeratedValue>
                  <name>1</name>
                  <description>Internal pullup resistor is enabled on the corresponding pin, if the corresponding PE field is set.</description>
                  <value>#1</value>
                </enumeratedValue>
              </enumeratedValues>
            </field>
            <field>
              <name>PE</name>
              <description>Pull Enable</description>
              <bitOffset>1</bitOffset>
              <bitWidth>1</bitWidth>
              <access>read-only</access>
              <enumeratedValues>
                <enumeratedValue>
                  <name>0</name>
                  <description>Internal pullup or pulldown resistor is not enabled on the corresponding pin.</description>
                  <value>#0</value>
                </enumeratedValue>
                <enumeratedValue>
                  <name>1</name>
                  <description>Internal pullup or pulldown resistor is enabled on the corresponding pin, if the pin is configured as a digital input.</description>
                  <value>#1</value>
                </enumeratedValue>
              </enumeratedValues>
            </field>
            <field>
              <name>SRE</name>
              <description>Slew Rate Enable</description>
              <bitOffset>2</bitOffset>
              <bitWidth>1</bitWidth>
              <access>read-only</access>
              <enumeratedValues>
                <enumeratedValue>
                  <name>0</name>
                  <description>Fast slew rate is configured on the corresponding pin, if the pin is configured as a digital output.</description>
                  <value>#0</value>
                </enumeratedValue>
                <enumeratedValue>
                  <name>1</name>
                  <description>Slow slew rate is configured on the corresponding pin, if the pin is configured as a digital output.</description>
                  <value>#1</value>
                </enumeratedValue>
              </enumeratedValues>
            </field>
            <field>
              <name>PFE</name>
              <description>Passive Filter Enable</description>
              <bitOffset>4</bitOffset>
              <bitWidth>1</bitWidth>
              <access>read-only</access>
              <enumeratedValues>
                <enumeratedValue>
                  <name>0</name>
                  <description>Passive input filter is disabled on the corresponding pin.</description>
                  <value>#0</value>
                </enumeratedValue>
                <enumeratedValue>
                  <name>1</name>
                  <description>Passive input filter is enabled on the corresponding pin, if the pin is configured as a digital input. Refer to the device data sheet for filter characteristics.</description>
                  <value>#1</value>
                </enumeratedValue>
              </enumeratedValues>
            </field>
            <field>
              <name>DSE</name>
              <description>Drive Strength Enable</description>
              <bitOffset>6</bitOffset>
              <bitWidth>1</bitWidth>
              <access>read-only</access>
              <enumeratedValues>
                <enumeratedValue>
                  <name>0</name>
                  <description>Low drive strength is configured on the corresponding pin, if pin is configured as a digital output.</description>
                  <value>#0</value>
                </enumeratedValue>
                <enumeratedValue>
                  <name>1</name>
                  <description>High drive strength is configured on the corresponding pin, if pin is configured as a digital output.</description>
                  <value>#1</value>
                </enumeratedValue>
              </enumeratedValues>
            </field>
            <field>
              <name>MUX</name>
              <description>Pin Mux Control</description>
              <bitOffset>8</bitOffset>
              <bitWidth>3</bitWidth>
              <access>read-write</access>
              <enumeratedValues>
                <enumeratedValue>
                  <name>000</name>
                  <description>Pin disabled (analog).</description>
                  <value>#000</value>
                </enumeratedValue>
                <enumeratedValue>
                  <name>001</name>
                  <description>Alternative 1 (GPIO).</description>
                  <value>#001</value>
                </enumeratedValue>
                <enumeratedValue>
                  <name>010</name>
                  <description>Alternative 2 (chip-specific).</description>
                  <value>#010</value>
                </enumeratedValue>
                <enumeratedValue>
                  <name>011</name>
                  <description>Alternative 3 (chip-specific).</description>
                  <value>#011</value>
                </enumeratedValue>
                <enumeratedValue>
                  <name>100</name>
                  <description>Alternative 4 (chip-specific).</description>
                  <value>#100</value>
                </enumeratedValue>
                <enumeratedValue>
                  <name>101</name>
                  <description>Alternative 5 (chip-specific).</description>
                  <value>#101</value>
                </enumeratedValue>
                <enumeratedValue>
                  <name>110</name>
                  <description>Alternative 6 (chip-specific).</description>
                  <value>#110</value>
                </enumeratedValue>
                <enumeratedValue>
                  <name>111</name>
                  <description>Alternative 7 (chip-specific).</description>
                  <value>#111</value>
                </enumeratedValue>
              </enumeratedValues>
            </field>
            <field>
              <name>IRQC</name>
              <description>Interrupt Configuration</description>
              <bitOffset>16</bitOffset>
              <bitWidth>4</bitWidth>
              <access>read-write</access>
              <enumeratedValues>
                <enumeratedValue>
                  <name>0000</name>
                  <description>Interrupt/DMA request disabled.</description>
                  <value>#0000</value>
                </enumeratedValue>
                <enumeratedValue>
                  <name>0001</name>
                  <description>DMA request on rising edge.</description>
                  <value>#0001</value>
                </enumeratedValue>
                <enumeratedValue>
                  <name>0010</name>
                  <description>DMA request on falling edge.</description>
                  <value>#0010</value>
                </enumeratedValue>
                <enumeratedValue>
                  <name>0011</name>
                  <description>DMA request on either edge.</description>
                  <value>#0011</value>
                </enumeratedValue>
                <enumeratedValue>
                  <name>1000</name>
                  <description>Interrupt when logic 0.</description>
                  <value>#1000</value>
                </enumeratedValue>
                <enumeratedValue>
                  <name>1001</name>
                  <description>Interrupt on rising-edge.</description>
                  <value>#1001</value>
                </enumeratedValue>
                <enumeratedValue>
                  <name>1010</name>
                  <description>Interrupt on falling-edge.</description>
                  <value>#1010</value>
                </enumeratedValue>
                <enumeratedValue>
                  <name>1011</name>
                  <description>Interrupt on either edge.</description>
                  <value>#1011</value>
                </enumeratedValue>
                <enumeratedValue>
                  <name>1100</name>
                  <description>Interrupt when logic 1.</description>
                  <value>#1100</value>
                </enumeratedValue>
              </enumeratedValues>
            </field>
            <field>
              <name>ISF</name>
              <description>Interrupt Status Flag</description>
              <bitOffset>24</bitOffset>
              <bitWidth>1</bitWidth>
              <access>read-write</access>
              <enumeratedValues>
                <enumeratedValue>
                  <name>0</name>
                  <description>Configured interrupt is not detected.</description>
                  <value>#0</value>
                </enumeratedValue>
                <enumeratedValue>
                  <name>1</name>
                  <description>Configured interrupt is detected. If the pin is configured to generate a DMA request, then the corresponding flag will be cleared automatically at the completion of the requested DMA transfer. Otherwise, the flag remains set until a logic 1 is written to the flag. If the pin is configured for a level sensitive interrupt and the pin remains asserted, then the flag is set again immediately after it is cleared.</description>
                  <value>#1</value>
                </enumeratedValue>
              </enumeratedValues>
            </field>
          </fields>
        </register>
        <register>
          <name>PCR27</name>
          <description>Pin Control Register n</description>
          <addressOffset>0x6C</addressOffset>
          <size>32</size>
          <access>read-write</access>
          <resetValue>0</resetValue>
          <resetMask>0xFFFFFFFF</resetMask>
          <fields>
            <field>
              <name>PS</name>
              <description>Pull Select</description>
              <bitOffset>0</bitOffset>
              <bitWidth>1</bitWidth>
              <access>read-only</access>
              <enumeratedValues>
                <enumeratedValue>
                  <name>0</name>
                  <description>Internal pulldown resistor is enabled on the corresponding pin, if the corresponding PE field is set.</description>
                  <value>#0</value>
                </enumeratedValue>
                <enumeratedValue>
                  <name>1</name>
                  <description>Internal pullup resistor is enabled on the corresponding pin, if the corresponding PE field is set.</description>
                  <value>#1</value>
                </enumeratedValue>
              </enumeratedValues>
            </field>
            <field>
              <name>PE</name>
              <description>Pull Enable</description>
              <bitOffset>1</bitOffset>
              <bitWidth>1</bitWidth>
              <access>read-only</access>
              <enumeratedValues>
                <enumeratedValue>
                  <name>0</name>
                  <description>Internal pullup or pulldown resistor is not enabled on the corresponding pin.</description>
                  <value>#0</value>
                </enumeratedValue>
                <enumeratedValue>
                  <name>1</name>
                  <description>Internal pullup or pulldown resistor is enabled on the corresponding pin, if the pin is configured as a digital input.</description>
                  <value>#1</value>
                </enumeratedValue>
              </enumeratedValues>
            </field>
            <field>
              <name>SRE</name>
              <description>Slew Rate Enable</description>
              <bitOffset>2</bitOffset>
              <bitWidth>1</bitWidth>
              <access>read-only</access>
              <enumeratedValues>
                <enumeratedValue>
                  <name>0</name>
                  <description>Fast slew rate is configured on the corresponding pin, if the pin is configured as a digital output.</description>
                  <value>#0</value>
                </enumeratedValue>
                <enumeratedValue>
                  <name>1</name>
                  <description>Slow slew rate is configured on the corresponding pin, if the pin is configured as a digital output.</description>
                  <value>#1</value>
                </enumeratedValue>
              </enumeratedValues>
            </field>
            <field>
              <name>PFE</name>
              <description>Passive Filter Enable</description>
              <bitOffset>4</bitOffset>
              <bitWidth>1</bitWidth>
              <access>read-only</access>
              <enumeratedValues>
                <enumeratedValue>
                  <name>0</name>
                  <description>Passive input filter is disabled on the corresponding pin.</description>
                  <value>#0</value>
                </enumeratedValue>
                <enumeratedValue>
                  <name>1</name>
                  <description>Passive input filter is enabled on the corresponding pin, if the pin is configured as a digital input. Refer to the device data sheet for filter characteristics.</description>
                  <value>#1</value>
                </enumeratedValue>
              </enumeratedValues>
            </field>
            <field>
              <name>DSE</name>
              <description>Drive Strength Enable</description>
              <bitOffset>6</bitOffset>
              <bitWidth>1</bitWidth>
              <access>read-only</access>
              <enumeratedValues>
                <enumeratedValue>
                  <name>0</name>
                  <description>Low drive strength is configured on the corresponding pin, if pin is configured as a digital output.</description>
                  <value>#0</value>
                </enumeratedValue>
                <enumeratedValue>
                  <name>1</name>
                  <description>High drive strength is configured on the corresponding pin, if pin is configured as a digital output.</description>
                  <value>#1</value>
                </enumeratedValue>
              </enumeratedValues>
            </field>
            <field>
              <name>MUX</name>
              <description>Pin Mux Control</description>
              <bitOffset>8</bitOffset>
              <bitWidth>3</bitWidth>
              <access>read-write</access>
              <enumeratedValues>
                <enumeratedValue>
                  <name>000</name>
                  <description>Pin disabled (analog).</description>
                  <value>#000</value>
                </enumeratedValue>
                <enumeratedValue>
                  <name>001</name>
                  <description>Alternative 1 (GPIO).</description>
                  <value>#001</value>
                </enumeratedValue>
                <enumeratedValue>
                  <name>010</name>
                  <description>Alternative 2 (chip-specific).</description>
                  <value>#010</value>
                </enumeratedValue>
                <enumeratedValue>
                  <name>011</name>
                  <description>Alternative 3 (chip-specific).</description>
                  <value>#011</value>
                </enumeratedValue>
                <enumeratedValue>
                  <name>100</name>
                  <description>Alternative 4 (chip-specific).</description>
                  <value>#100</value>
                </enumeratedValue>
                <enumeratedValue>
                  <name>101</name>
                  <description>Alternative 5 (chip-specific).</description>
                  <value>#101</value>
                </enumeratedValue>
                <enumeratedValue>
                  <name>110</name>
                  <description>Alternative 6 (chip-specific).</description>
                  <value>#110</value>
                </enumeratedValue>
                <enumeratedValue>
                  <name>111</name>
                  <description>Alternative 7 (chip-specific).</description>
                  <value>#111</value>
                </enumeratedValue>
              </enumeratedValues>
            </field>
            <field>
              <name>IRQC</name>
              <description>Interrupt Configuration</description>
              <bitOffset>16</bitOffset>
              <bitWidth>4</bitWidth>
              <access>read-write</access>
              <enumeratedValues>
                <enumeratedValue>
                  <name>0000</name>
                  <description>Interrupt/DMA request disabled.</description>
                  <value>#0000</value>
                </enumeratedValue>
                <enumeratedValue>
                  <name>0001</name>
                  <description>DMA request on rising edge.</description>
                  <value>#0001</value>
                </enumeratedValue>
                <enumeratedValue>
                  <name>0010</name>
                  <description>DMA request on falling edge.</description>
                  <value>#0010</value>
                </enumeratedValue>
                <enumeratedValue>
                  <name>0011</name>
                  <description>DMA request on either edge.</description>
                  <value>#0011</value>
                </enumeratedValue>
                <enumeratedValue>
                  <name>1000</name>
                  <description>Interrupt when logic 0.</description>
                  <value>#1000</value>
                </enumeratedValue>
                <enumeratedValue>
                  <name>1001</name>
                  <description>Interrupt on rising-edge.</description>
                  <value>#1001</value>
                </enumeratedValue>
                <enumeratedValue>
                  <name>1010</name>
                  <description>Interrupt on falling-edge.</description>
                  <value>#1010</value>
                </enumeratedValue>
                <enumeratedValue>
                  <name>1011</name>
                  <description>Interrupt on either edge.</description>
                  <value>#1011</value>
                </enumeratedValue>
                <enumeratedValue>
                  <name>1100</name>
                  <description>Interrupt when logic 1.</description>
                  <value>#1100</value>
                </enumeratedValue>
              </enumeratedValues>
            </field>
            <field>
              <name>ISF</name>
              <description>Interrupt Status Flag</description>
              <bitOffset>24</bitOffset>
              <bitWidth>1</bitWidth>
              <access>read-write</access>
              <enumeratedValues>
                <enumeratedValue>
                  <name>0</name>
                  <description>Configured interrupt is not detected.</description>
                  <value>#0</value>
                </enumeratedValue>
                <enumeratedValue>
                  <name>1</name>
                  <description>Configured interrupt is detected. If the pin is configured to generate a DMA request, then the corresponding flag will be cleared automatically at the completion of the requested DMA transfer. Otherwise, the flag remains set until a logic 1 is written to the flag. If the pin is configured for a level sensitive interrupt and the pin remains asserted, then the flag is set again immediately after it is cleared.</description>
                  <value>#1</value>
                </enumeratedValue>
              </enumeratedValues>
            </field>
          </fields>
        </register>
        <register>
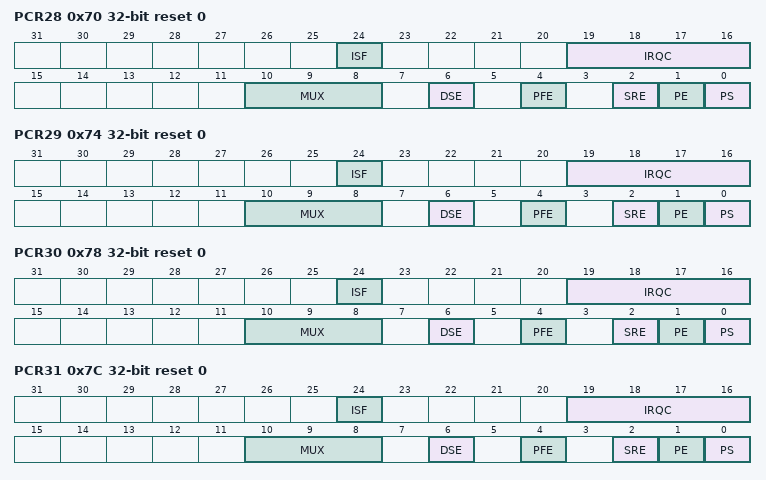
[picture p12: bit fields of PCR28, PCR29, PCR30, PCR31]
          <name>PCR28</name>
          <description>Pin Control Register n</description>
          <addressOffset>0x70</addressOffset>
          <size>32</size>
          <access>read-write</access>
          <resetValue>0</resetValue>
          <resetMask>0xFFFFFFFF</resetMask>
          <fields>
            <field>
              <name>PS</name>
              <description>Pull Select</description>
              <bitOffset>0</bitOffset>
              <bitWidth>1</bitWidth>
              <access>read-only</access>
              <enumeratedValues>
                <enumeratedValue>
                  <name>0</name>
                  <description>Internal pulldown resistor is enabled on the corresponding pin, if the corresponding PE field is set.</description>
                  <value>#0</value>
                </enumeratedValue>
                <enumeratedValue>
                  <name>1</name>
                  <description>Internal pullup resistor is enabled on the corresponding pin, if the corresponding PE field is set.</description>
                  <value>#1</value>
                </enumeratedValue>
              </enumeratedValues>
            </field>
            <field>
              <name>PE</name>
              <description>Pull Enable</description>
              <bitOffset>1</bitOffset>
              <bitWidth>1</bitWidth>
              <access>read-only</access>
              <enumeratedValues>
                <enumeratedValue>
                  <name>0</name>
                  <description>Internal pullup or pulldown resistor is not enabled on the corresponding pin.</description>
                  <value>#0</value>
                </enumeratedValue>
                <enumeratedValue>
                  <name>1</name>
                  <description>Internal pullup or pulldown resistor is enabled on the corresponding pin, if the pin is configured as a digital input.</description>
                  <value>#1</value>
                </enumeratedValue>
              </enumeratedValues>
            </field>
            <field>
              <name>SRE</name>
              <description>Slew Rate Enable</description>
              <bitOffset>2</bitOffset>
              <bitWidth>1</bitWidth>
              <access>read-only</access>
              <enumeratedValues>
                <enumeratedValue>
                  <name>0</name>
                  <description>Fast slew rate is configured on the corresponding pin, if the pin is configured as a digital output.</description>
                  <value>#0</value>
                </enumeratedValue>
                <enumeratedValue>
                  <name>1</name>
                  <description>Slow slew rate is configured on the corresponding pin, if the pin is configured as a digital output.</description>
                  <value>#1</value>
                </enumeratedValue>
              </enumeratedValues>
            </field>
            <field>
              <name>PFE</name>
              <description>Passive Filter Enable</description>
              <bitOffset>4</bitOffset>
              <bitWidth>1</bitWidth>
              <access>read-only</access>
              <enumeratedValues>
                <enumeratedValue>
                  <name>0</name>
                  <description>Passive input filter is disabled on the corresponding pin.</description>
                  <value>#0</value>
                </enumeratedValue>
                <enumeratedValue>
                  <name>1</name>
                  <description>Passive input filter is enabled on the corresponding pin, if the pin is configured as a digital input. Refer to the device data sheet for filter characteristics.</description>
                  <value>#1</value>
                </enumeratedValue>
              </enumeratedValues>
            </field>
            <field>
              <name>DSE</name>
              <description>Drive Strength Enable</description>
              <bitOffset>6</bitOffset>
              <bitWidth>1</bitWidth>
              <access>read-only</access>
              <enumeratedValues>
                <enumeratedValue>
                  <name>0</name>
                  <description>Low drive strength is configured on the corresponding pin, if pin is configured as a digital output.</description>
                  <value>#0</value>
                </enumeratedValue>
                <enumeratedValue>
                  <name>1</name>
                  <description>High drive strength is configured on the corresponding pin, if pin is configured as a digital output.</description>
                  <value>#1</value>
                </enumeratedValue>
              </enumeratedValues>
            </field>
            <field>
              <name>MUX</name>
              <description>Pin Mux Control</description>
              <bitOffset>8</bitOffset>
              <bitWidth>3</bitWidth>
              <access>read-write</access>
              <enumeratedValues>
                <enumeratedValue>
                  <name>000</name>
                  <description>Pin disabled (analog).</description>
                  <value>#000</value>
                </enumeratedValue>
                <enumeratedValue>
                  <name>001</name>
                  <description>Alternative 1 (GPIO).</description>
                  <value>#001</value>
                </enumeratedValue>
                <enumeratedValue>
                  <name>010</name>
                  <description>Alternative 2 (chip-specific).</description>
                  <value>#010</value>
                </enumeratedValue>
                <enumeratedValue>
                  <name>011</name>
                  <description>Alternative 3 (chip-specific).</description>
                  <value>#011</value>
                </enumeratedValue>
                <enumeratedValue>
                  <name>100</name>
                  <description>Alternative 4 (chip-specific).</description>
                  <value>#100</value>
                </enumeratedValue>
                <enumeratedValue>
                  <name>101</name>
                  <description>Alternative 5 (chip-specific).</description>
                  <value>#101</value>
                </enumeratedValue>
                <enumeratedValue>
                  <name>110</name>
                  <description>Alternative 6 (chip-specific).</description>
                  <value>#110</value>
                </enumeratedValue>
                <enumeratedValue>
                  <name>111</name>
                  <description>Alternative 7 (chip-specific).</description>
                  <value>#111</value>
                </enumeratedValue>
              </enumeratedValues>
            </field>
            <field>
              <name>IRQC</name>
              <description>Interrupt Configuration</description>
              <bitOffset>16</bitOffset>
              <bitWidth>4</bitWidth>
              <access>read-write</access>
              <enumeratedValues>
                <enumeratedValue>
                  <name>0000</name>
                  <description>Interrupt/DMA request disabled.</description>
                  <value>#0000</value>
                </enumeratedValue>
                <enumeratedValue>
                  <name>0001</name>
                  <description>DMA request on rising edge.</description>
                  <value>#0001</value>
                </enumeratedValue>
                <enumeratedValue>
                  <name>0010</name>
                  <description>DMA request on falling edge.</description>
                  <value>#0010</value>
                </enumeratedValue>
                <enumeratedValue>
                  <name>0011</name>
                  <description>DMA request on either edge.</description>
                  <value>#0011</value>
                </enumeratedValue>
                <enumeratedValue>
                  <name>1000</name>
                  <description>Interrupt when logic 0.</description>
                  <value>#1000</value>
                </enumeratedValue>
                <enumeratedValue>
                  <name>1001</name>
                  <description>Interrupt on rising-edge.</description>
                  <value>#1001</value>
                </enumeratedValue>
                <enumeratedValue>
                  <name>1010</name>
                  <description>Interrupt on falling-edge.</description>
                  <value>#1010</value>
                </enumeratedValue>
                <enumeratedValue>
                  <name>1011</name>
                  <description>Interrupt on either edge.</description>
                  <value>#1011</value>
                </enumeratedValue>
                <enumeratedValue>
                  <name>1100</name>
                  <description>Interrupt when logic 1.</description>
                  <value>#1100</value>
                </enumeratedValue>
              </enumeratedValues>
            </field>
            <field>
              <name>ISF</name>
              <description>Interrupt Status Flag</description>
              <bitOffset>24</bitOffset>
              <bitWidth>1</bitWidth>
              <access>read-write</access>
              <enumeratedValues>
                <enumeratedValue>
                  <name>0</name>
                  <description>Configured interrupt is not detected.</description>
                  <value>#0</value>
                </enumeratedValue>
                <enumeratedValue>
                  <name>1</name>
                  <description>Configured interrupt is detected. If the pin is configured to generate a DMA request, then the corresponding flag will be cleared automatically at the completion of the requested DMA transfer. Otherwise, the flag remains set until a logic 1 is written to the flag. If the pin is configured for a level sensitive interrupt and the pin remains asserted, then the flag is set again immediately after it is cleared.</description>
                  <value>#1</value>
                </enumeratedValue>
              </enumeratedValues>
            </field>
          </fields>
        </register>
        <register>
          <name>PCR29</name>
          <description>Pin Control Register n</description>
          <addressOffset>0x74</addressOffset>
          <size>32</size>
          <access>read-write</access>
          <resetValue>0</resetValue>
          <resetMask>0xFFFFFFFF</resetMask>
          <fields>
            <field>
              <name>PS</name>
              <description>Pull Select</description>
              <bitOffset>0</bitOffset>
              <bitWidth>1</bitWidth>
              <access>read-only</access>
              <enumeratedValues>
                <enumeratedValue>
                  <name>0</name>
                  <description>Internal pulldown resistor is enabled on the corresponding pin, if the corresponding PE field is set.</description>
                  <value>#0</value>
                </enumeratedValue>
                <enumeratedValue>
                  <name>1</name>
                  <description>Internal pullup resistor is enabled on the corresponding pin, if the corresponding PE field is set.</description>
                  <value>#1</value>
                </enumeratedValue>
              </enumeratedValues>
            </field>
            <field>
              <name>PE</name>
              <description>Pull Enable</description>
              <bitOffset>1</bitOffset>
              <bitWidth>1</bitWidth>
              <access>read-only</access>
              <enumeratedValues>
                <enumeratedValue>
                  <name>0</name>
                  <description>Internal pullup or pulldown resistor is not enabled on the corresponding pin.</description>
                  <value>#0</value>
                </enumeratedValue>
                <enumeratedValue>
                  <name>1</name>
                  <description>Internal pullup or pulldown resistor is enabled on the corresponding pin, if the pin is configured as a digital input.</description>
                  <value>#1</value>
                </enumeratedValue>
              </enumeratedValues>
            </field>
            <field>
              <name>SRE</name>
              <description>Slew Rate Enable</description>
              <bitOffset>2</bitOffset>
              <bitWidth>1</bitWidth>
              <access>read-only</access>
              <enumeratedValues>
                <enumeratedValue>
                  <name>0</name>
                  <description>Fast slew rate is configured on the corresponding pin, if the pin is configured as a digital output.</description>
                  <value>#0</value>
                </enumeratedValue>
                <enumeratedValue>
                  <name>1</name>
                  <description>Slow slew rate is configured on the corresponding pin, if the pin is configured as a digital output.</description>
                  <value>#1</value>
                </enumeratedValue>
              </enumeratedValues>
            </field>
            <field>
              <name>PFE</name>
              <description>Passive Filter Enable</description>
              <bitOffset>4</bitOffset>
              <bitWidth>1</bitWidth>
              <access>read-only</access>
              <enumeratedValues>
                <enumeratedValue>
                  <name>0</name>
                  <description>Passive input filter is disabled on the corresponding pin.</description>
                  <value>#0</value>
                </enumeratedValue>
                <enumeratedValue>
                  <name>1</name>
                  <description>Passive input filter is enabled on the corresponding pin, if the pin is configured as a digital input. Refer to the device data sheet for filter characteristics.</description>
                  <value>#1</value>
                </enumeratedValue>
              </enumeratedValues>
            </field>
            <field>
              <name>DSE</name>
              <description>Drive Strength Enable</description>
              <bitOffset>6</bitOffset>
              <bitWidth>1</bitWidth>
              <access>read-only</access>
              <enumeratedValues>
                <enumeratedValue>
                  <name>0</name>
                  <description>Low drive strength is configured on the corresponding pin, if pin is configured as a digital output.</description>
                  <value>#0</value>
                </enumeratedValue>
                <enumeratedValue>
                  <name>1</name>
                  <description>High drive strength is configured on the corresponding pin, if pin is configured as a digital output.</description>
                  <value>#1</value>
                </enumeratedValue>
              </enumeratedValues>
            </field>
            <field>
              <name>MUX</name>
              <description>Pin Mux Control</description>
              <bitOffset>8</bitOffset>
              <bitWidth>3</bitWidth>
              <access>read-write</access>
              <enumeratedValues>
                <enumeratedValue>
                  <name>000</name>
                  <description>Pin disabled (analog).</description>
                  <value>#000</value>
                </enumeratedValue>
                <enumeratedValue>
                  <name>001</name>
                  <description>Alternative 1 (GPIO).</description>
                  <value>#001</value>
                </enumeratedValue>
                <enumeratedValue>
                  <name>010</name>
                  <description>Alternative 2 (chip-specific).</description>
                  <value>#010</value>
                </enumeratedValue>
                <enumeratedValue>
                  <name>011</name>
                  <description>Alternative 3 (chip-specific).</description>
                  <value>#011</value>
                </enumeratedValue>
                <enumeratedValue>
                  <name>100</name>
                  <description>Alternative 4 (chip-specific).</description>
                  <value>#100</value>
                </enumeratedValue>
                <enumeratedValue>
                  <name>101</name>
                  <description>Alternative 5 (chip-specific).</description>
                  <value>#101</value>
                </enumeratedValue>
                <enumeratedValue>
                  <name>110</name>
                  <description>Alternative 6 (chip-specific).</description>
                  <value>#110</value>
                </enumeratedValue>
                <enumeratedValue>
                  <name>111</name>
                  <description>Alternative 7 (chip-specific).</description>
                  <value>#111</value>
                </enumeratedValue>
              </enumeratedValues>
            </field>
            <field>
              <name>IRQC</name>
              <description>Interrupt Configuration</description>
              <bitOffset>16</bitOffset>
              <bitWidth>4</bitWidth>
              <access>read-write</access>
              <enumeratedValues>
                <enumeratedValue>
                  <name>0000</name>
                  <description>Interrupt/DMA request disabled.</description>
                  <value>#0000</value>
                </enumeratedValue>
                <enumeratedValue>
                  <name>0001</name>
                  <description>DMA request on rising edge.</description>
                  <value>#0001</value>
                </enumeratedValue>
                <enumeratedValue>
                  <name>0010</name>
                  <description>DMA request on falling edge.</description>
                  <value>#0010</value>
                </enumeratedValue>
                <enumeratedValue>
                  <name>0011</name>
                  <description>DMA request on either edge.</description>
                  <value>#0011</value>
                </enumeratedValue>
                <enumeratedValue>
                  <name>1000</name>
                  <description>Interrupt when logic 0.</description>
                  <value>#1000</value>
                </enumeratedValue>
                <enumeratedValue>
                  <name>1001</name>
                  <description>Interrupt on rising-edge.</description>
                  <value>#1001</value>
                </enumeratedValue>
                <enumeratedValue>
                  <name>1010</name>
                  <description>Interrupt on falling-edge.</description>
                  <value>#1010</value>
                </enumeratedValue>
                <enumeratedValue>
                  <name>1011</name>
                  <description>Interrupt on either edge.</description>
                  <value>#1011</value>
                </enumeratedValue>
                <enumeratedValue>
                  <name>1100</name>
                  <description>Interrupt when logic 1.</description>
                  <value>#1100</value>
                </enumeratedValue>
              </enumeratedValues>
            </field>
            <field>
              <name>ISF</name>
              <description>Interrupt Status Flag</description>
              <bitOffset>24</bitOffset>
              <bitWidth>1</bitWidth>
              <access>read-write</access>
              <enumeratedValues>
                <enumeratedValue>
                  <name>0</name>
                  <description>Configured interrupt is not detected.</description>
                  <value>#0</value>
                </enumeratedValue>
                <enumeratedValue>
                  <name>1</name>
                  <description>Configured interrupt is detected. If the pin is configured to generate a DMA request, then the corresponding flag will be cleared automatically at the completion of the requested DMA transfer. Otherwise, the flag remains set until a logic 1 is written to the flag. If the pin is configured for a level sensitive interrupt and the pin remains asserted, then the flag is set again immediately after it is cleared.</description>
                  <value>#1</value>
                </enumeratedValue>
              </enumeratedValues>
            </field>
          </fields>
        </register>
        <register>
          <name>PCR30</name>
          <description>Pin Control Register n</description>
          <addressOffset>0x78</addressOffset>
          <size>32</size>
          <access>read-write</access>
          <resetValue>0</resetValue>
          <resetMask>0xFFFFFFFF</resetMask>
          <fields>
            <field>
              <name>PS</name>
              <description>Pull Select</description>
              <bitOffset>0</bitOffset>
              <bitWidth>1</bitWidth>
              <access>read-only</access>
              <enumeratedValues>
                <enumeratedValue>
                  <name>0</name>
                  <description>Internal pulldown resistor is enabled on the corresponding pin, if the corresponding PE field is set.</description>
                  <value>#0</value>
                </enumeratedValue>
                <enumeratedValue>
                  <name>1</name>
                  <description>Internal pullup resistor is enabled on the corresponding pin, if the corresponding PE field is set.</description>
                  <value>#1</value>
                </enumeratedValue>
              </enumeratedValues>
            </field>
            <field>
              <name>PE</name>
              <description>Pull Enable</description>
              <bitOffset>1</bitOffset>
              <bitWidth>1</bitWidth>
              <access>read-only</access>
              <enumeratedValues>
                <enumeratedValue>
                  <name>0</name>
                  <description>Internal pullup or pulldown resistor is not enabled on the corresponding pin.</description>
                  <value>#0</value>
                </enumeratedValue>
                <enumeratedValue>
                  <name>1</name>
                  <description>Internal pullup or pulldown resistor is enabled on the corresponding pin, if the pin is configured as a digital input.</description>
                  <value>#1</value>
                </enumeratedValue>
              </enumeratedValues>
            </field>
            <field>
              <name>SRE</name>
              <description>Slew Rate Enable</description>
              <bitOffset>2</bitOffset>
              <bitWidth>1</bitWidth>
              <access>read-only</access>
              <enumeratedValues>
                <enumeratedValue>
                  <name>0</name>
                  <description>Fast slew rate is configured on the corresponding pin, if the pin is configured as a digital output.</description>
                  <value>#0</value>
                </enumeratedValue>
                <enumeratedValue>
                  <name>1</name>
                  <description>Slow slew rate is configured on the corresponding pin, if the pin is configured as a digital output.</description>
                  <value>#1</value>
                </enumeratedValue>
              </enumeratedValues>
            </field>
            <field>
              <name>PFE</name>
              <description>Passive Filter Enable</description>
              <bitOffset>4</bitOffset>
              <bitWidth>1</bitWidth>
              <access>read-only</access>
              <enumeratedValues>
                <enumeratedValue>
                  <name>0</name>
                  <description>Passive input filter is disabled on the corresponding pin.</description>
                  <value>#0</value>
                </enumeratedValue>
                <enumeratedValue>
                  <name>1</name>
                  <description>Passive input filter is enabled on the corresponding pin, if the pin is configured as a digital input. Refer to the device data sheet for filter characteristics.</description>
                  <value>#1</value>
                </enumeratedValue>
              </enumeratedValues>
            </field>
            <field>
              <name>DSE</name>
              <description>Drive Strength Enable</description>
              <bitOffset>6</bitOffset>
              <bitWidth>1</bitWidth>
              <access>read-only</access>
              <enumeratedValues>
                <enumeratedValue>
                  <name>0</name>
                  <description>Low drive strength is configured on the corresponding pin, if pin is configured as a digital output.</description>
                  <value>#0</value>
                </enumeratedValue>
                <enumeratedValue>
                  <name>1</name>
                  <description>High drive strength is configured on the corresponding pin, if pin is configured as a digital output.</description>
                  <value>#1</value>
                </enumeratedValue>
              </enumeratedValues>
            </field>
            <field>
              <name>MUX</name>
              <description>Pin Mux Control</description>
              <bitOffset>8</bitOffset>
              <bitWidth>3</bitWidth>
              <access>read-write</access>
              <enumeratedValues>
                <enumeratedValue>
                  <name>000</name>
                  <description>Pin disabled (analog).</description>
                  <value>#000</value>
                </enumeratedValue>
                <enumeratedValue>
                  <name>001</name>
                  <description>Alternative 1 (GPIO).</description>
                  <value>#001</value>
                </enumeratedValue>
                <enumeratedValue>
                  <name>010</name>
                  <description>Alternative 2 (chip-specific).</description>
                  <value>#010</value>
                </enumeratedValue>
                <enumeratedValue>
                  <name>011</name>
                  <description>Alternative 3 (chip-specific).</description>
                  <value>#011</value>
                </enumeratedValue>
                <enumeratedValue>
                  <name>100</name>
                  <description>Alternative 4 (chip-specific).</description>
                  <value>#100</value>
                </enumeratedValue>
                <enumeratedValue>
                  <name>101</name>
                  <description>Alternative 5 (chip-specific).</description>
                  <value>#101</value>
                </enumeratedValue>
                <enumeratedValue>
                  <name>110</name>
                  <description>Alternative 6 (chip-specific).</description>
                  <value>#110</value>
                </enumeratedValue>
                <enumeratedValue>
                  <name>111</name>
                  <description>Alternative 7 (chip-specific).</description>
                  <value>#111</value>
                </enumeratedValue>
              </enumeratedValues>
            </field>
            <field>
              <name>IRQC</name>
              <description>Interrupt Configuration</description>
              <bitOffset>16</bitOffset>
              <bitWidth>4</bitWidth>
              <access>read-write</access>
              <enumeratedValues>
                <enumeratedValue>
                  <name>0000</name>
                  <description>Interrupt/DMA request disabled.</description>
                  <value>#0000</value>
                </enumeratedValue>
                <enumeratedValue>
                  <name>0001</name>
                  <description>DMA request on rising edge.</description>
                  <value>#0001</value>
                </enumeratedValue>
                <enumeratedValue>
                  <name>0010</name>
                  <description>DMA request on falling edge.</description>
                  <value>#0010</value>
                </enumeratedValue>
                <enumeratedValue>
                  <name>0011</name>
                  <description>DMA request on either edge.</description>
                  <value>#0011</value>
                </enumeratedValue>
                <enumeratedValue>
                  <name>1000</name>
                  <description>Interrupt when logic 0.</description>
                  <value>#1000</value>
                </enumeratedValue>
                <enumeratedValue>
                  <name>1001</name>
                  <description>Interrupt on rising-edge.</description>
                  <value>#1001</value>
                </enumeratedValue>
                <enumeratedValue>
                  <name>1010</name>
                  <description>Interrupt on falling-edge.</description>
                  <value>#1010</value>
                </enumeratedValue>
                <enumeratedValue>
                  <name>1011</name>
                  <description>Interrupt on either edge.</description>
                  <value>#1011</value>
                </enumeratedValue>
                <enumeratedValue>
                  <name>1100</name>
                  <description>Interrupt when logic 1.</description>
                  <value>#1100</value>
                </enumeratedValue>
              </enumeratedValues>
            </field>
            <field>
              <name>ISF</name>
              <description>Interrupt Status Flag</description>
              <bitOffset>24</bitOffset>
              <bitWidth>1</bitWidth>
              <access>read-write</access>
              <enumeratedValues>
                <enumeratedValue>
                  <name>0</name>
                  <description>Configured interrupt is not detected.</description>
                  <value>#0</value>
                </enumeratedValue>
                <enumeratedValue>
                  <name>1</name>
                  <description>Configured interrupt is detected. If the pin is configured to generate a DMA request, then the corresponding flag will be cleared automatically at the completion of the requested DMA transfer. Otherwise, the flag remains set until a logic 1 is written to the flag. If the pin is configured for a level sensitive interrupt and the pin remains asserted, then the flag is set again immediately after it is cleared.</description>
                  <value>#1</value>
                </enumeratedValue>
              </enumeratedValues>
            </field>
          </fields>
        </register>
        <register>
          <name>PCR31</name>
          <description>Pin Control Register n</description>
          <addressOffset>0x7C</addressOffset>
          <size>32</size>
          <access>read-write</access>
          <resetValue>0</resetValue>
          <resetMask>0xFFFFFFFF</resetMask>
          <fields>
            <field>
              <name>PS</name>
              <description>Pull Select</description>
              <bitOffset>0</bitOffset>
              <bitWidth>1</bitWidth>
              <access>read-only</access>
              <enumeratedValues>
                <enumeratedValue>
                  <name>0</name>
                  <description>Internal pulldown resistor is enabled on the corresponding pin, if the corresponding PE field is set.</description>
                  <value>#0</value>
                </enumeratedValue>
                <enumeratedValue>
                  <name>1</name>
                  <description>Internal pullup resistor is enabled on the corresponding pin, if the corresponding PE field is set.</description>
                  <value>#1</value>
                </enumeratedValue>
              </enumeratedValues>
            </field>
            <field>
              <name>PE</name>
              <description>Pull Enable</description>
              <bitOffset>1</bitOffset>
              <bitWidth>1</bitWidth>
              <access>read-only</access>
              <enumeratedValues>
                <enumeratedValue>
                  <name>0</name>
                  <description>Internal pullup or pulldown resistor is not enabled on the corresponding pin.</description>
                  <value>#0</value>
                </enumeratedValue>
                <enumeratedValue>
                  <name>1</name>
                  <description>Internal pullup or pulldown resistor is enabled on the corresponding pin, if the pin is configured as a digital input.</description>
                  <value>#1</value>
                </enumeratedValue>
              </enumeratedValues>
            </field>
            <field>
              <name>SRE</name>
              <description>Slew Rate Enable</description>
              <bitOffset>2</bitOffset>
              <bitWidth>1</bitWidth>
              <access>read-only</access>
              <enumeratedValues>
                <enumeratedValue>
                  <name>0</name>
                  <description>Fast slew rate is configured on the corresponding pin, if the pin is configured as a digital output.</description>
                  <value>#0</value>
                </enumeratedValue>
                <enumeratedValue>
                  <name>1</name>
                  <description>Slow slew rate is configured on the corresponding pin, if the pin is configured as a digital output.</description>
                  <value>#1</value>
                </enumeratedValue>
              </enumeratedValues>
            </field>
            <field>
              <name>PFE</name>
              <description>Passive Filter Enable</description>
              <bitOffset>4</bitOffset>
              <bitWidth>1</bitWidth>
              <access>read-only</access>
              <enumeratedValues>
                <enumeratedValue>
                  <name>0</name>
                  <description>Passive input filter is disabled on the corresponding pin.</description>
                  <value>#0</value>
                </enumeratedValue>
                <enumeratedValue>
                  <name>1</name>
                  <description>Passive input filter is enabled on the corresponding pin, if the pin is configured as a digital input. Refer to the device data sheet for filter characteristics.</description>
                  <value>#1</value>
                </enumeratedValue>
              </enumeratedValues>
            </field>
            <field>
              <name>DSE</name>
              <description>Drive Strength Enable</description>
              <bitOffset>6</bitOffset>
              <bitWidth>1</bitWidth>
              <access>read-only</access>
              <enumeratedValues>
                <enumeratedValue>
                  <name>0</name>
                  <description>Low drive strength is configured on the corresponding pin, if pin is configured as a digital output.</description>
                  <value>#0</value>
                </enumeratedValue>
                <enumeratedValue>
                  <name>1</name>
                  <description>High drive strength is configured on the corresponding pin, if pin is configured as a digital output.</description>
                  <value>#1</value>
                </enumeratedValue>
              </enumeratedValues>
            </field>
            <field>
              <name>MUX</name>
              <description>Pin Mux Control</description>
              <bitOffset>8</bitOffset>
              <bitWidth>3</bitWidth>
              <access>read-write</access>
              <enumeratedValues>
                <enumeratedValue>
                  <name>000</name>
                  <description>Pin disabled (analog).</description>
                  <value>#000</value>
                </enumeratedValue>
                <enumeratedValue>
                  <name>001</name>
                  <description>Alternative 1 (GPIO).</description>
                  <value>#001</value>
                </enumeratedValue>
                <enumeratedValue>
                  <name>010</name>
                  <description>Alternative 2 (chip-specific).</description>
                  <value>#010</value>
                </enumeratedValue>
                <enumeratedValue>
                  <name>011</name>
                  <description>Alternative 3 (chip-specific).</description>
                  <value>#011</value>
                </enumeratedValue>
                <enumeratedValue>
                  <name>100</name>
                  <description>Alternative 4 (chip-specific).</description>
                  <value>#100</value>
                </enumeratedValue>
                <enumeratedValue>
                  <name>101</name>
                  <description>Alternative 5 (chip-specific).</description>
                  <value>#101</value>
                </enumeratedValue>
                <enumeratedValue>
                  <name>110</name>
                  <description>Alternative 6 (chip-specific).</description>
                  <value>#110</value>
                </enumeratedValue>
                <enumeratedValue>
                  <name>111</name>
                  <description>Alternative 7 (chip-specific).</description>
                  <value>#111</value>
                </enumeratedValue>
              </enumeratedValues>
            </field>
            <field>
              <name>IRQC</name>
              <description>Interrupt Configuration</description>
              <bitOffset>16</bitOffset>
              <bitWidth>4</bitWidth>
              <access>read-write</access>
              <enumeratedValues>
                <enumeratedValue>
                  <name>0000</name>
                  <description>Interrupt/DMA request disabled.</description>
                  <value>#0000</value>
                </enumeratedValue>
                <enumeratedValue>
                  <name>0001</name>
                  <description>DMA request on rising edge.</description>
                  <value>#0001</value>
                </enumeratedValue>
                <enumeratedValue>
                  <name>0010</name>
                  <description>DMA request on falling edge.</description>
                  <value>#0010</value>
                </enumeratedValue>
                <enumeratedValue>
                  <name>0011</name>
                  <description>DMA request on either edge.</description>
                  <value>#0011</value>
                </enumeratedValue>
                <enumeratedValue>
                  <name>1000</name>
                  <description>Interrupt when logic 0.</description>
                  <value>#1000</value>
                </enumeratedValue>
                <enumeratedValue>
                  <name>1001</name>
                  <description>Interrupt on rising-edge.</description>
                  <value>#1001</value>
                </enumeratedValue>
                <enumeratedValue>
                  <name>1010</name>
                  <description>Interrupt on falling-edge.</description>
                  <value>#1010</value>
                </enumeratedValue>
                <enumeratedValue>
                  <name>1011</name>
                  <description>Interrupt on either edge.</description>
                  <value>#1011</value>
                </enumeratedValue>
                <enumeratedValue>
                  <name>1100</name>
                  <description>Interrupt when logic 1.</description>
                  <value>#1100</value>
                </enumeratedValue>
              </enumeratedValues>
            </field>
            <field>
              <name>ISF</name>
              <description>Interrupt Status Flag</description>
              <bitOffset>24</bitOffset>
              <bitWidth>1</bitWidth>
              <access>read-write</access>
              <enumeratedValues>
                <enumeratedValue>
                  <name>0</name>
                  <description>Configured interrupt is not detected.</description>
                  <value>#0</value>
                </enumeratedValue>
                <enumeratedValue>
                  <name>1</name>
                  <description>Configured interrupt is detected. If the pin is configured to generate a DMA request, then the corresponding flag will be cleared automatically at the completion of the requested DMA transfer. Otherwise, the flag remains set until a logic 1 is written to the flag. If the pin is configured for a level sensitive interrupt and the pin remains asserted, then the flag is set again immediately after it is cleared.</description>
                  <value>#1</value>
                </enumeratedValue>
              </enumeratedValues>
            </field>
          </fields>
        </register>
        <register>
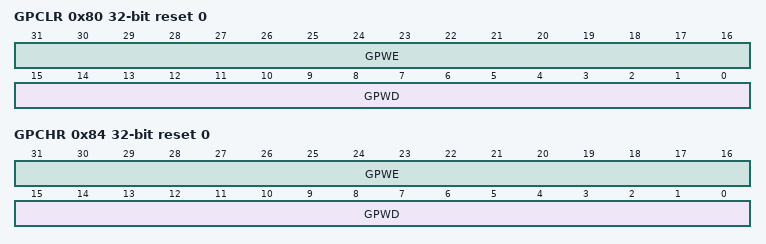
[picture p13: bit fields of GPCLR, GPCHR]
          <name>GPCLR</name>
          <description>Global Pin Control Low Register</description>
          <addressOffset>0x80</addressOffset>
          <size>32</size>
          <access>write-only</access>
          <resetValue>0</resetValue>
          <resetMask>0xFFFFFFFF</resetMask>
          <fields>
            <field>
              <name>GPWD</name>
              <description>Global Pin Write Data</description>
              <bitOffset>0</bitOffset>
              <bitWidth>16</bitWidth>
              <access>write-only</access>
            </field>
            <field>
              <name>GPWE</name>
              <description>Global Pin Write Enable</description>
              <bitOffset>16</bitOffset>
              <bitWidth>16</bitWidth>
              <access>write-only</access>
              <enumeratedValues>
                <enumeratedValue>
                  <name>0</name>
                  <description>Corresponding Pin Control Register is not updated with the value in GPWD.</description>
                  <value>#0</value>
                </enumeratedValue>
                <enumeratedValue>
                  <name>1</name>
                  <description>Corresponding Pin Control Register is updated with the value in GPWD.</description>
                  <value>#1</value>
                </enumeratedValue>
              </enumeratedValues>
            </field>
          </fields>
        </register>
        <register>
          <name>GPCHR</name>
          <description>Global Pin Control High Register</description>
          <addressOffset>0x84</addressOffset>
          <size>32</size>
          <access>write-only</access>
          <resetValue>0</resetValue>
          <resetMask>0xFFFFFFFF</resetMask>
          <fields>
            <field>
              <name>GPWD</name>
              <description>Global Pin Write Data</description>
              <bitOffset>0</bitOffset>
              <bitWidth>16</bitWidth>
              <access>write-only</access>
            </field>
            <field>
              <name>GPWE</name>
              <description>Global Pin Write Enable</description>
              <bitOffset>16</bitOffset>
              <bitWidth>16</bitWidth>
              <access>write-only</access>
              <enumeratedValues>
                <enumeratedValue>
                  <name>0</name>
                  <description>Corresponding Pin Control Register is not updated with the value in GPWD.</description>
                  <value>#0</value>
                </enumeratedValue>
                <enumeratedValue>
                  <name>1</name>
                  <description>Corresponding Pin Control Register is updated with the value in GPWD.</description>
                  <value>#1</value>
                </enumeratedValue>
              </enumeratedValues>
            </field>
          </fields>
        </register>
        <register>
          <name>ISFR</name>
          <description>Interrupt Status Flag Register</description>
          <addressOffset>0xA0</addressOffset>
          <size>32</size>
          <access>read-write</access>
          <resetValue>0</resetValue>
          <resetMask>0xFFFFFFFF</resetMask>
          <fields>
            <field>
              <name>ISF</name>
              <description>Interrupt Status Flag</description>
              <bitOffset>0</bitOffset>
              <bitWidth>32</bitWidth>
              <access>read-write</access>
              <enumeratedValues>
                <enumeratedValue>
                  <name>0</name>
                  <description>Configured interrupt is not detected.</description>
                  <value>#0</value>
                </enumeratedValue>
                <enumeratedValue>
                  <name>1</name>
                  <description>Configured interrupt is detected. If the pin is configured to generate a DMA request, then the corresponding flag will be cleared automatically at the completion of the requested DMA transfer. Otherwise, the flag remains set until a logic 1 is written to the flag. If the pin is configured for a level sensitive interrupt and the pin remains asserted, then the flag is set again immediately after it is cleared.</description>
                  <value>#1</value>
                </enumeratedValue>
              </enumeratedValues>
            </field>
          </fields>
        </register>
      </registers>
    </peripheral>
    <peripheral>
      <name>PORTD</name>
      <description>Pin Control and Interrupts</description>
      <groupName>PORT</groupName>
      <prependToName>PORTD_</prependToName>
      <baseAddress>0x4004C000</baseAddress>
      <addressBlock>
        <offset>0</offset>
        <size>0xA4</size>
        <usage>registers</usage>
      </addressBlock>
      <interrupt>
        <name>PORTC_PORTD</name>
        <value>31</value>
      </interrupt>
      <registers>
        <register>
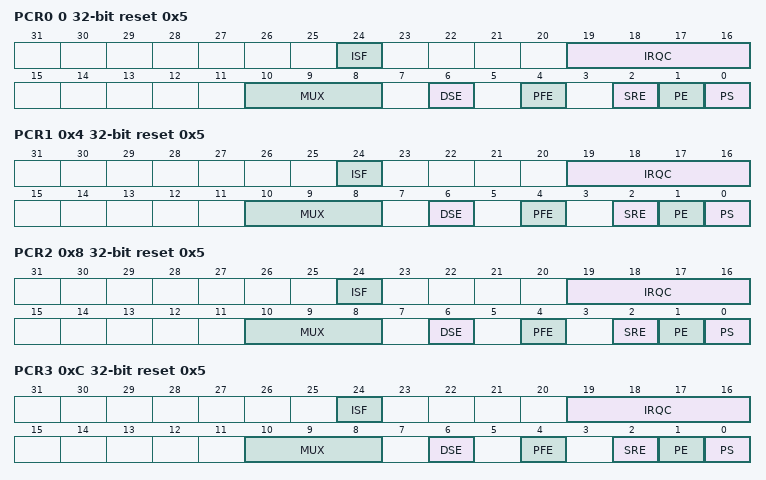
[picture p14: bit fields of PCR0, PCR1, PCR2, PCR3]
          <name>PCR0</name>
          <description>Pin Control Register n</description>
          <addressOffset>0</addressOffset>
          <size>32</size>
          <access>read-write</access>
          <resetValue>0x5</resetValue>
          <resetMask>0xFFFFFFFF</resetMask>
          <fields>
            <field>
              <name>PS</name>
              <description>Pull Select</description>
              <bitOffset>0</bitOffset>
              <bitWidth>1</bitWidth>
              <access>read-write</access>
              <enumeratedValues>
                <enumeratedValue>
                  <name>0</name>
                  <description>Internal pulldown resistor is enabled on the corresponding pin, if the corresponding PE field is set.</description>
                  <value>#0</value>
                </enumeratedValue>
                <enumeratedValue>
                  <name>1</name>
                  <description>Internal pullup resistor is enabled on the corresponding pin, if the corresponding PE field is set.</description>
                  <value>#1</value>
                </enumeratedValue>
              </enumeratedValues>
            </field>
            <field>
              <name>PE</name>
              <description>Pull Enable</description>
              <bitOffset>1</bitOffset>
              <bitWidth>1</bitWidth>
              <access>read-write</access>
              <enumeratedValues>
                <enumeratedValue>
                  <name>0</name>
                  <description>Internal pullup or pulldown resistor is not enabled on the corresponding pin.</description>
                  <value>#0</value>
                </enumeratedValue>
                <enumeratedValue>
                  <name>1</name>
                  <description>Internal pullup or pulldown resistor is enabled on the corresponding pin, if the pin is configured as a digital input.</description>
                  <value>#1</value>
                </enumeratedValue>
              </enumeratedValues>
            </field>
            <field>
              <name>SRE</name>
              <description>Slew Rate Enable</description>
              <bitOffset>2</bitOffset>
              <bitWidth>1</bitWidth>
              <access>read-write</access>
              <enumeratedValues>
                <enumeratedValue>
                  <name>0</name>
                  <description>Fast slew rate is configured on the corresponding pin, if the pin is configured as a digital output.</description>
                  <value>#0</value>
                </enumeratedValue>
                <enumeratedValue>
                  <name>1</name>
                  <description>Slow slew rate is configured on the corresponding pin, if the pin is configured as a digital output.</description>
                  <value>#1</value>
                </enumeratedValue>
              </enumeratedValues>
            </field>
            <field>
              <name>PFE</name>
              <description>Passive Filter Enable</description>
              <bitOffset>4</bitOffset>
              <bitWidth>1</bitWidth>
              <access>read-only</access>
              <enumeratedValues>
                <enumeratedValue>
                  <name>0</name>
                  <description>Passive input filter is disabled on the corresponding pin.</description>
                  <value>#0</value>
                </enumeratedValue>
                <enumeratedValue>
                  <name>1</name>
                  <description>Passive input filter is enabled on the corresponding pin, if the pin is configured as a digital input. Refer to the device data sheet for filter characteristics.</description>
                  <value>#1</value>
                </enumeratedValue>
              </enumeratedValues>
            </field>
            <field>
              <name>DSE</name>
              <description>Drive Strength Enable</description>
              <bitOffset>6</bitOffset>
              <bitWidth>1</bitWidth>
              <access>read-only</access>
              <enumeratedValues>
                <enumeratedValue>
                  <name>0</name>
                  <description>Low drive strength is configured on the corresponding pin, if pin is configured as a digital output.</description>
                  <value>#0</value>
                </enumeratedValue>
                <enumeratedValue>
                  <name>1</name>
                  <description>High drive strength is configured on the corresponding pin, if pin is configured as a digital output.</description>
                  <value>#1</value>
                </enumeratedValue>
              </enumeratedValues>
            </field>
            <field>
              <name>MUX</name>
              <description>Pin Mux Control</description>
              <bitOffset>8</bitOffset>
              <bitWidth>3</bitWidth>
              <access>read-write</access>
              <enumeratedValues>
                <enumeratedValue>
                  <name>000</name>
                  <description>Pin disabled (analog).</description>
                  <value>#000</value>
                </enumeratedValue>
                <enumeratedValue>
                  <name>001</name>
                  <description>Alternative 1 (GPIO).</description>
                  <value>#001</value>
                </enumeratedValue>
                <enumeratedValue>
                  <name>010</name>
                  <description>Alternative 2 (chip-specific).</description>
                  <value>#010</value>
                </enumeratedValue>
                <enumeratedValue>
                  <name>011</name>
                  <description>Alternative 3 (chip-specific).</description>
                  <value>#011</value>
                </enumeratedValue>
                <enumeratedValue>
                  <name>100</name>
                  <description>Alternative 4 (chip-specific).</description>
                  <value>#100</value>
                </enumeratedValue>
                <enumeratedValue>
                  <name>101</name>
                  <description>Alternative 5 (chip-specific).</description>
                  <value>#101</value>
                </enumeratedValue>
                <enumeratedValue>
                  <name>110</name>
                  <description>Alternative 6 (chip-specific).</description>
                  <value>#110</value>
                </enumeratedValue>
                <enumeratedValue>
                  <name>111</name>
                  <description>Alternative 7 (chip-specific).</description>
                  <value>#111</value>
                </enumeratedValue>
              </enumeratedValues>
            </field>
            <field>
              <name>IRQC</name>
              <description>Interrupt Configuration</description>
              <bitOffset>16</bitOffset>
              <bitWidth>4</bitWidth>
              <access>read-write</access>
              <enumeratedValues>
                <enumeratedValue>
                  <name>0000</name>
                  <description>Interrupt/DMA request disabled.</description>
                  <value>#0000</value>
                </enumeratedValue>
                <enumeratedValue>
                  <name>0001</name>
                  <description>DMA request on rising edge.</description>
                  <value>#0001</value>
                </enumeratedValue>
                <enumeratedValue>
                  <name>0010</name>
                  <description>DMA request on falling edge.</description>
                  <value>#0010</value>
                </enumeratedValue>
                <enumeratedValue>
                  <name>0011</name>
                  <description>DMA request on either edge.</description>
                  <value>#0011</value>
                </enumeratedValue>
                <enumeratedValue>
                  <name>1000</name>
                  <description>Interrupt when logic 0.</description>
                  <value>#1000</value>
                </enumeratedValue>
                <enumeratedValue>
                  <name>1001</name>
                  <description>Interrupt on rising-edge.</description>
                  <value>#1001</value>
                </enumeratedValue>
                <enumeratedValue>
                  <name>1010</name>
                  <description>Interrupt on falling-edge.</description>
                  <value>#1010</value>
                </enumeratedValue>
                <enumeratedValue>
                  <name>1011</name>
                  <description>Interrupt on either edge.</description>
                  <value>#1011</value>
                </enumeratedValue>
                <enumeratedValue>
                  <name>1100</name>
                  <description>Interrupt when logic 1.</description>
                  <value>#1100</value>
                </enumeratedValue>
              </enumeratedValues>
            </field>
            <field>
              <name>ISF</name>
              <description>Interrupt Status Flag</description>
              <bitOffset>24</bitOffset>
              <bitWidth>1</bitWidth>
              <access>read-write</access>
              <enumeratedValues>
                <enumeratedValue>
                  <name>0</name>
                  <description>Configured interrupt is not detected.</description>
                  <value>#0</value>
                </enumeratedValue>
                <enumeratedValue>
                  <name>1</name>
                  <description>Configured interrupt is detected. If the pin is configured to generate a DMA request, then the corresponding flag will be cleared automatically at the completion of the requested DMA transfer. Otherwise, the flag remains set until a logic 1 is written to the flag. If the pin is configured for a level sensitive interrupt and the pin remains asserted, then the flag is set again immediately after it is cleared.</description>
                  <value>#1</value>
                </enumeratedValue>
              </enumeratedValues>
            </field>
          </fields>
        </register>
        <register>
          <name>PCR1</name>
          <description>Pin Control Register n</description>
          <addressOffset>0x4</addressOffset>
          <size>32</size>
          <access>read-write</access>
          <resetValue>0x5</resetValue>
          <resetMask>0xFFFFFFFF</resetMask>
          <fields>
            <field>
              <name>PS</name>
              <description>Pull Select</description>
              <bitOffset>0</bitOffset>
              <bitWidth>1</bitWidth>
              <access>read-write</access>
              <enumeratedValues>
                <enumeratedValue>
                  <name>0</name>
                  <description>Internal pulldown resistor is enabled on the corresponding pin, if the corresponding PE field is set.</description>
                  <value>#0</value>
                </enumeratedValue>
                <enumeratedValue>
                  <name>1</name>
                  <description>Internal pullup resistor is enabled on the corresponding pin, if the corresponding PE field is set.</description>
                  <value>#1</value>
                </enumeratedValue>
              </enumeratedValues>
            </field>
            <field>
              <name>PE</name>
              <description>Pull Enable</description>
              <bitOffset>1</bitOffset>
              <bitWidth>1</bitWidth>
              <access>read-write</access>
              <enumeratedValues>
                <enumeratedValue>
                  <name>0</name>
                  <description>Internal pullup or pulldown resistor is not enabled on the corresponding pin.</description>
                  <value>#0</value>
                </enumeratedValue>
                <enumeratedValue>
                  <name>1</name>
                  <description>Internal pullup or pulldown resistor is enabled on the corresponding pin, if the pin is configured as a digital input.</description>
                  <value>#1</value>
                </enumeratedValue>
              </enumeratedValues>
            </field>
            <field>
              <name>SRE</name>
              <description>Slew Rate Enable</description>
              <bitOffset>2</bitOffset>
              <bitWidth>1</bitWidth>
              <access>read-write</access>
              <enumeratedValues>
                <enumeratedValue>
                  <name>0</name>
                  <description>Fast slew rate is configured on the corresponding pin, if the pin is configured as a digital output.</description>
                  <value>#0</value>
                </enumeratedValue>
                <enumeratedValue>
                  <name>1</name>
                  <description>Slow slew rate is configured on the corresponding pin, if the pin is configured as a digital output.</description>
                  <value>#1</value>
                </enumeratedValue>
              </enumeratedValues>
            </field>
            <field>
              <name>PFE</name>
              <description>Passive Filter Enable</description>
              <bitOffset>4</bitOffset>
              <bitWidth>1</bitWidth>
              <access>read-only</access>
              <enumeratedValues>
                <enumeratedValue>
                  <name>0</name>
                  <description>Passive input filter is disabled on the corresponding pin.</description>
                  <value>#0</value>
                </enumeratedValue>
                <enumeratedValue>
                  <name>1</name>
                  <description>Passive input filter is enabled on the corresponding pin, if the pin is configured as a digital input. Refer to the device data sheet for filter characteristics.</description>
                  <value>#1</value>
                </enumeratedValue>
              </enumeratedValues>
            </field>
            <field>
              <name>DSE</name>
              <description>Drive Strength Enable</description>
              <bitOffset>6</bitOffset>
              <bitWidth>1</bitWidth>
              <access>read-only</access>
              <enumeratedValues>
                <enumeratedValue>
                  <name>0</name>
                  <description>Low drive strength is configured on the corresponding pin, if pin is configured as a digital output.</description>
                  <value>#0</value>
                </enumeratedValue>
                <enumeratedValue>
                  <name>1</name>
                  <description>High drive strength is configured on the corresponding pin, if pin is configured as a digital output.</description>
                  <value>#1</value>
                </enumeratedValue>
              </enumeratedValues>
            </field>
            <field>
              <name>MUX</name>
              <description>Pin Mux Control</description>
              <bitOffset>8</bitOffset>
              <bitWidth>3</bitWidth>
              <access>read-write</access>
              <enumeratedValues>
                <enumeratedValue>
                  <name>000</name>
                  <description>Pin disabled (analog).</description>
                  <value>#000</value>
                </enumeratedValue>
                <enumeratedValue>
                  <name>001</name>
                  <description>Alternative 1 (GPIO).</description>
                  <value>#001</value>
                </enumeratedValue>
                <enumeratedValue>
                  <name>010</name>
                  <description>Alternative 2 (chip-specific).</description>
                  <value>#010</value>
                </enumeratedValue>
                <enumeratedValue>
                  <name>011</name>
                  <description>Alternative 3 (chip-specific).</description>
                  <value>#011</value>
                </enumeratedValue>
                <enumeratedValue>
                  <name>100</name>
                  <description>Alternative 4 (chip-specific).</description>
                  <value>#100</value>
                </enumeratedValue>
                <enumeratedValue>
                  <name>101</name>
                  <description>Alternative 5 (chip-specific).</description>
                  <value>#101</value>
                </enumeratedValue>
                <enumeratedValue>
                  <name>110</name>
                  <description>Alternative 6 (chip-specific).</description>
                  <value>#110</value>
                </enumeratedValue>
                <enumeratedValue>
                  <name>111</name>
                  <description>Alternative 7 (chip-specific).</description>
                  <value>#111</value>
                </enumeratedValue>
              </enumeratedValues>
            </field>
            <field>
              <name>IRQC</name>
              <description>Interrupt Configuration</description>
              <bitOffset>16</bitOffset>
              <bitWidth>4</bitWidth>
              <access>read-write</access>
              <enumeratedValues>
                <enumeratedValue>
                  <name>0000</name>
                  <description>Interrupt/DMA request disabled.</description>
                  <value>#0000</value>
                </enumeratedValue>
                <enumeratedValue>
                  <name>0001</name>
                  <description>DMA request on rising edge.</description>
                  <value>#0001</value>
                </enumeratedValue>
                <enumeratedValue>
                  <name>0010</name>
                  <description>DMA request on falling edge.</description>
                  <value>#0010</value>
                </enumeratedValue>
                <enumeratedValue>
                  <name>0011</name>
                  <description>DMA request on either edge.</description>
                  <value>#0011</value>
                </enumeratedValue>
                <enumeratedValue>
                  <name>1000</name>
                  <description>Interrupt when logic 0.</description>
                  <value>#1000</value>
                </enumeratedValue>
                <enumeratedValue>
                  <name>1001</name>
                  <description>Interrupt on rising-edge.</description>
                  <value>#1001</value>
                </enumeratedValue>
                <enumeratedValue>
                  <name>1010</name>
                  <description>Interrupt on falling-edge.</description>
                  <value>#1010</value>
                </enumeratedValue>
                <enumeratedValue>
                  <name>1011</name>
                  <description>Interrupt on either edge.</description>
                  <value>#1011</value>
                </enumeratedValue>
                <enumeratedValue>
                  <name>1100</name>
                  <description>Interrupt when logic 1.</description>
                  <value>#1100</value>
                </enumeratedValue>
              </enumeratedValues>
            </field>
            <field>
              <name>ISF</name>
              <description>Interrupt Status Flag</description>
              <bitOffset>24</bitOffset>
              <bitWidth>1</bitWidth>
              <access>read-write</access>
              <enumeratedValues>
                <enumeratedValue>
                  <name>0</name>
                  <description>Configured interrupt is not detected.</description>
                  <value>#0</value>
                </enumeratedValue>
                <enumeratedValue>
                  <name>1</name>
                  <description>Configured interrupt is detected. If the pin is configured to generate a DMA request, then the corresponding flag will be cleared automatically at the completion of the requested DMA transfer. Otherwise, the flag remains set until a logic 1 is written to the flag. If the pin is configured for a level sensitive interrupt and the pin remains asserted, then the flag is set again immediately after it is cleared.</description>
                  <value>#1</value>
                </enumeratedValue>
              </enumeratedValues>
            </field>
          </fields>
        </register>
        <register>
          <name>PCR2</name>
          <description>Pin Control Register n</description>
          <addressOffset>0x8</addressOffset>
          <size>32</size>
          <access>read-write</access>
          <resetValue>0x5</resetValue>
          <resetMask>0xFFFFFFFF</resetMask>
          <fields>
            <field>
              <name>PS</name>
              <description>Pull Select</description>
              <bitOffset>0</bitOffset>
              <bitWidth>1</bitWidth>
              <access>read-write</access>
              <enumeratedValues>
                <enumeratedValue>
                  <name>0</name>
                  <description>Internal pulldown resistor is enabled on the corresponding pin, if the corresponding PE field is set.</description>
                  <value>#0</value>
                </enumeratedValue>
                <enumeratedValue>
                  <name>1</name>
                  <description>Internal pullup resistor is enabled on the corresponding pin, if the corresponding PE field is set.</description>
                  <value>#1</value>
                </enumeratedValue>
              </enumeratedValues>
            </field>
            <field>
              <name>PE</name>
              <description>Pull Enable</description>
              <bitOffset>1</bitOffset>
              <bitWidth>1</bitWidth>
              <access>read-write</access>
              <enumeratedValues>
                <enumeratedValue>
                  <name>0</name>
                  <description>Internal pullup or pulldown resistor is not enabled on the corresponding pin.</description>
                  <value>#0</value>
                </enumeratedValue>
                <enumeratedValue>
                  <name>1</name>
                  <description>Internal pullup or pulldown resistor is enabled on the corresponding pin, if the pin is configured as a digital input.</description>
                  <value>#1</value>
                </enumeratedValue>
              </enumeratedValues>
            </field>
            <field>
              <name>SRE</name>
              <description>Slew Rate Enable</description>
              <bitOffset>2</bitOffset>
              <bitWidth>1</bitWidth>
              <access>read-write</access>
              <enumeratedValues>
                <enumeratedValue>
                  <name>0</name>
                  <description>Fast slew rate is configured on the corresponding pin, if the pin is configured as a digital output.</description>
                  <value>#0</value>
                </enumeratedValue>
                <enumeratedValue>
                  <name>1</name>
                  <description>Slow slew rate is configured on the corresponding pin, if the pin is configured as a digital output.</description>
                  <value>#1</value>
                </enumeratedValue>
              </enumeratedValues>
            </field>
            <field>
              <name>PFE</name>
              <description>Passive Filter Enable</description>
              <bitOffset>4</bitOffset>
              <bitWidth>1</bitWidth>
              <access>read-only</access>
              <enumeratedValues>
                <enumeratedValue>
                  <name>0</name>
                  <description>Passive input filter is disabled on the corresponding pin.</description>
                  <value>#0</value>
                </enumeratedValue>
                <enumeratedValue>
                  <name>1</name>
                  <description>Passive input filter is enabled on the corresponding pin, if the pin is configured as a digital input. Refer to the device data sheet for filter characteristics.</description>
                  <value>#1</value>
                </enumeratedValue>
              </enumeratedValues>
            </field>
            <field>
              <name>DSE</name>
              <description>Drive Strength Enable</description>
              <bitOffset>6</bitOffset>
              <bitWidth>1</bitWidth>
              <access>read-only</access>
              <enumeratedValues>
                <enumeratedValue>
                  <name>0</name>
                  <description>Low drive strength is configured on the corresponding pin, if pin is configured as a digital output.</description>
                  <value>#0</value>
                </enumeratedValue>
                <enumeratedValue>
                  <name>1</name>
                  <description>High drive strength is configured on the corresponding pin, if pin is configured as a digital output.</description>
                  <value>#1</value>
                </enumeratedValue>
              </enumeratedValues>
            </field>
            <field>
              <name>MUX</name>
              <description>Pin Mux Control</description>
              <bitOffset>8</bitOffset>
              <bitWidth>3</bitWidth>
              <access>read-write</access>
              <enumeratedValues>
                <enumeratedValue>
                  <name>000</name>
                  <description>Pin disabled (analog).</description>
                  <value>#000</value>
                </enumeratedValue>
                <enumeratedValue>
                  <name>001</name>
                  <description>Alternative 1 (GPIO).</description>
                  <value>#001</value>
                </enumeratedValue>
                <enumeratedValue>
                  <name>010</name>
                  <description>Alternative 2 (chip-specific).</description>
                  <value>#010</value>
                </enumeratedValue>
                <enumeratedValue>
                  <name>011</name>
                  <description>Alternative 3 (chip-specific).</description>
                  <value>#011</value>
                </enumeratedValue>
                <enumeratedValue>
                  <name>100</name>
                  <description>Alternative 4 (chip-specific).</description>
                  <value>#100</value>
                </enumeratedValue>
                <enumeratedValue>
                  <name>101</name>
                  <description>Alternative 5 (chip-specific).</description>
                  <value>#101</value>
                </enumeratedValue>
                <enumeratedValue>
                  <name>110</name>
                  <description>Alternative 6 (chip-specific).</description>
                  <value>#110</value>
                </enumeratedValue>
                <enumeratedValue>
                  <name>111</name>
                  <description>Alternative 7 (chip-specific).</description>
                  <value>#111</value>
                </enumeratedValue>
              </enumeratedValues>
            </field>
            <field>
              <name>IRQC</name>
              <description>Interrupt Configuration</description>
              <bitOffset>16</bitOffset>
              <bitWidth>4</bitWidth>
              <access>read-write</access>
              <enumeratedValues>
                <enumeratedValue>
                  <name>0000</name>
                  <description>Interrupt/DMA request disabled.</description>
                  <value>#0000</value>
                </enumeratedValue>
                <enumeratedValue>
                  <name>0001</name>
                  <description>DMA request on rising edge.</description>
                  <value>#0001</value>
                </enumeratedValue>
                <enumeratedValue>
                  <name>0010</name>
                  <description>DMA request on falling edge.</description>
                  <value>#0010</value>
                </enumeratedValue>
                <enumeratedValue>
                  <name>0011</name>
                  <description>DMA request on either edge.</description>
                  <value>#0011</value>
                </enumeratedValue>
                <enumeratedValue>
                  <name>1000</name>
                  <description>Interrupt when logic 0.</description>
                  <value>#1000</value>
                </enumeratedValue>
                <enumeratedValue>
                  <name>1001</name>
                  <description>Interrupt on rising-edge.</description>
                  <value>#1001</value>
                </enumeratedValue>
                <enumeratedValue>
                  <name>1010</name>
                  <description>Interrupt on falling-edge.</description>
                  <value>#1010</value>
                </enumeratedValue>
                <enumeratedValue>
                  <name>1011</name>
                  <description>Interrupt on either edge.</description>
                  <value>#1011</value>
                </enumeratedValue>
                <enumeratedValue>
                  <name>1100</name>
                  <description>Interrupt when logic 1.</description>
                  <value>#1100</value>
                </enumeratedValue>
              </enumeratedValues>
            </field>
            <field>
              <name>ISF</name>
              <description>Interrupt Status Flag</description>
              <bitOffset>24</bitOffset>
              <bitWidth>1</bitWidth>
              <access>read-write</access>
              <enumeratedValues>
                <enumeratedValue>
                  <name>0</name>
                  <description>Configured interrupt is not detected.</description>
                  <value>#0</value>
                </enumeratedValue>
                <enumeratedValue>
                  <name>1</name>
                  <description>Configured interrupt is detected. If the pin is configured to generate a DMA request, then the corresponding flag will be cleared automatically at the completion of the requested DMA transfer. Otherwise, the flag remains set until a logic 1 is written to the flag. If the pin is configured for a level sensitive interrupt and the pin remains asserted, then the flag is set again immediately after it is cleared.</description>
                  <value>#1</value>
                </enumeratedValue>
              </enumeratedValues>
            </field>
          </fields>
        </register>
        <register>
          <name>PCR3</name>
          <description>Pin Control Register n</description>
          <addressOffset>0xC</addressOffset>
          <size>32</size>
          <access>read-write</access>
          <resetValue>0x5</resetValue>
          <resetMask>0xFFFFFFFF</resetMask>
          <fields>
            <field>
              <name>PS</name>
              <description>Pull Select</description>
              <bitOffset>0</bitOffset>
              <bitWidth>1</bitWidth>
              <access>read-write</access>
              <enumeratedValues>
                <enumeratedValue>
                  <name>0</name>
                  <description>Internal pulldown resistor is enabled on the corresponding pin, if the corresponding PE field is set.</description>
                  <value>#0</value>
                </enumeratedValue>
                <enumeratedValue>
                  <name>1</name>
                  <description>Internal pullup resistor is enabled on the corresponding pin, if the corresponding PE field is set.</description>
                  <value>#1</value>
                </enumeratedValue>
              </enumeratedValues>
            </field>
            <field>
              <name>PE</name>
              <description>Pull Enable</description>
              <bitOffset>1</bitOffset>
              <bitWidth>1</bitWidth>
              <access>read-write</access>
              <enumeratedValues>
                <enumeratedValue>
                  <name>0</name>
                  <description>Internal pullup or pulldown resistor is not enabled on the corresponding pin.</description>
                  <value>#0</value>
                </enumeratedValue>
                <enumeratedValue>
                  <name>1</name>
                  <description>Internal pullup or pulldown resistor is enabled on the corresponding pin, if the pin is configured as a digital input.</description>
                  <value>#1</value>
                </enumeratedValue>
              </enumeratedValues>
            </field>
            <field>
              <name>SRE</name>
              <description>Slew Rate Enable</description>
              <bitOffset>2</bitOffset>
              <bitWidth>1</bitWidth>
              <access>read-write</access>
              <enumeratedValues>
                <enumeratedValue>
                  <name>0</name>
                  <description>Fast slew rate is configured on the corresponding pin, if the pin is configured as a digital output.</description>
                  <value>#0</value>
                </enumeratedValue>
                <enumeratedValue>
                  <name>1</name>
                  <description>Slow slew rate is configured on the corresponding pin, if the pin is configured as a digital output.</description>
                  <value>#1</value>
                </enumeratedValue>
              </enumeratedValues>
            </field>
            <field>
              <name>PFE</name>
              <description>Passive Filter Enable</description>
              <bitOffset>4</bitOffset>
              <bitWidth>1</bitWidth>
              <access>read-only</access>
              <enumeratedValues>
                <enumeratedValue>
                  <name>0</name>
                  <description>Passive input filter is disabled on the corresponding pin.</description>
                  <value>#0</value>
                </enumeratedValue>
                <enumeratedValue>
                  <name>1</name>
                  <description>Passive input filter is enabled on the corresponding pin, if the pin is configured as a digital input. Refer to the device data sheet for filter characteristics.</description>
                  <value>#1</value>
                </enumeratedValue>
              </enumeratedValues>
            </field>
            <field>
              <name>DSE</name>
              <description>Drive Strength Enable</description>
              <bitOffset>6</bitOffset>
              <bitWidth>1</bitWidth>
              <access>read-only</access>
              <enumeratedValues>
                <enumeratedValue>
                  <name>0</name>
                  <description>Low drive strength is configured on the corresponding pin, if pin is configured as a digital output.</description>
                  <value>#0</value>
                </enumeratedValue>
                <enumeratedValue>
                  <name>1</name>
                  <description>High drive strength is configured on the corresponding pin, if pin is configured as a digital output.</description>
                  <value>#1</value>
                </enumeratedValue>
              </enumeratedValues>
            </field>
            <field>
              <name>MUX</name>
              <description>Pin Mux Control</description>
              <bitOffset>8</bitOffset>
              <bitWidth>3</bitWidth>
              <access>read-write</access>
              <enumeratedValues>
                <enumeratedValue>
                  <name>000</name>
                  <description>Pin disabled (analog).</description>
                  <value>#000</value>
                </enumeratedValue>
                <enumeratedValue>
                  <name>001</name>
                  <description>Alternative 1 (GPIO).</description>
                  <value>#001</value>
                </enumeratedValue>
                <enumeratedValue>
                  <name>010</name>
                  <description>Alternative 2 (chip-specific).</description>
                  <value>#010</value>
                </enumeratedValue>
                <enumeratedValue>
                  <name>011</name>
                  <description>Alternative 3 (chip-specific).</description>
                  <value>#011</value>
                </enumeratedValue>
                <enumeratedValue>
                  <name>100</name>
                  <description>Alternative 4 (chip-specific).</description>
                  <value>#100</value>
                </enumeratedValue>
                <enumeratedValue>
                  <name>101</name>
                  <description>Alternative 5 (chip-specific).</description>
                  <value>#101</value>
                </enumeratedValue>
                <enumeratedValue>
                  <name>110</name>
                  <description>Alternative 6 (chip-specific).</description>
                  <value>#110</value>
                </enumeratedValue>
                <enumeratedValue>
                  <name>111</name>
                  <description>Alternative 7 (chip-specific).</description>
                  <value>#111</value>
                </enumeratedValue>
              </enumeratedValues>
            </field>
            <field>
              <name>IRQC</name>
              <description>Interrupt Configuration</description>
              <bitOffset>16</bitOffset>
              <bitWidth>4</bitWidth>
              <access>read-write</access>
              <enumeratedValues>
                <enumeratedValue>
                  <name>0000</name>
                  <description>Interrupt/DMA request disabled.</description>
                  <value>#0000</value>
                </enumeratedValue>
                <enumeratedValue>
                  <name>0001</name>
                  <description>DMA request on rising edge.</description>
                  <value>#0001</value>
                </enumeratedValue>
                <enumeratedValue>
                  <name>0010</name>
                  <description>DMA request on falling edge.</description>
                  <value>#0010</value>
                </enumeratedValue>
                <enumeratedValue>
                  <name>0011</name>
                  <description>DMA request on either edge.</description>
                  <value>#0011</value>
                </enumeratedValue>
                <enumeratedValue>
                  <name>1000</name>
                  <description>Interrupt when logic 0.</description>
                  <value>#1000</value>
                </enumeratedValue>
                <enumeratedValue>
                  <name>1001</name>
                  <description>Interrupt on rising-edge.</description>
                  <value>#1001</value>
                </enumeratedValue>
                <enumeratedValue>
                  <name>1010</name>
                  <description>Interrupt on falling-edge.</description>
                  <value>#1010</value>
                </enumeratedValue>
                <enumeratedValue>
                  <name>1011</name>
                  <description>Interrupt on either edge.</description>
                  <value>#1011</value>
                </enumeratedValue>
                <enumeratedValue>
                  <name>1100</name>
                  <description>Interrupt when logic 1.</description>
                  <value>#1100</value>
                </enumeratedValue>
              </enumeratedValues>
            </field>
            <field>
              <name>ISF</name>
              <description>Interrupt Status Flag</description>
              <bitOffset>24</bitOffset>
              <bitWidth>1</bitWidth>
              <access>read-write</access>
              <enumeratedValues>
                <enumeratedValue>
                  <name>0</name>
                  <description>Configured interrupt is not detected.</description>
                  <value>#0</value>
                </enumeratedValue>
                <enumeratedValue>
                  <name>1</name>
                  <description>Configured interrupt is detected. If the pin is configured to generate a DMA request, then the corresponding flag will be cleared automatically at the completion of the requested DMA transfer. Otherwise, the flag remains set until a logic 1 is written to the flag. If the pin is configured for a level sensitive interrupt and the pin remains asserted, then the flag is set again immediately after it is cleared.</description>
                  <value>#1</value>
                </enumeratedValue>
              </enumeratedValues>
            </field>
          </fields>
        </register>
        <register>
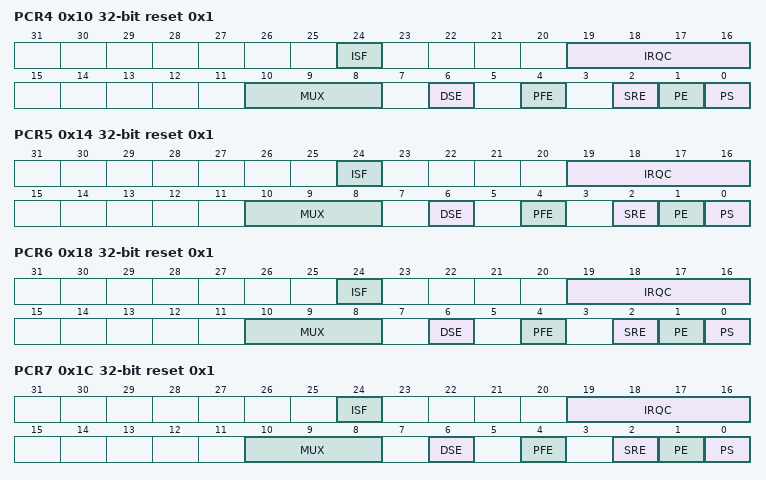
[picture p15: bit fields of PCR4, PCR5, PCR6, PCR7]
          <name>PCR4</name>
          <description>Pin Control Register n</description>
          <addressOffset>0x10</addressOffset>
          <size>32</size>
          <access>read-write</access>
          <resetValue>0x1</resetValue>
          <resetMask>0xFFFFFFFF</resetMask>
          <fields>
            <field>
              <name>PS</name>
              <description>Pull Select</description>
              <bitOffset>0</bitOffset>
              <bitWidth>1</bitWidth>
              <access>read-write</access>
              <enumeratedValues>
                <enumeratedValue>
                  <name>0</name>
                  <description>Internal pulldown resistor is enabled on the corresponding pin, if the corresponding PE field is set.</description>
                  <value>#0</value>
                </enumeratedValue>
                <enumeratedValue>
                  <name>1</name>
                  <description>Internal pullup resistor is enabled on the corresponding pin, if the corresponding PE field is set.</description>
                  <value>#1</value>
                </enumeratedValue>
              </enumeratedValues>
            </field>
            <field>
              <name>PE</name>
              <description>Pull Enable</description>
              <bitOffset>1</bitOffset>
              <bitWidth>1</bitWidth>
              <access>read-write</access>
              <enumeratedValues>
                <enumeratedValue>
                  <name>0</name>
                  <description>Internal pullup or pulldown resistor is not enabled on the corresponding pin.</description>
                  <value>#0</value>
                </enumeratedValue>
                <enumeratedValue>
                  <name>1</name>
                  <description>Internal pullup or pulldown resistor is enabled on the corresponding pin, if the pin is configured as a digital input.</description>
                  <value>#1</value>
                </enumeratedValue>
              </enumeratedValues>
            </field>
            <field>
              <name>SRE</name>
              <description>Slew Rate Enable</description>
              <bitOffset>2</bitOffset>
              <bitWidth>1</bitWidth>
              <access>read-write</access>
              <enumeratedValues>
                <enumeratedValue>
                  <name>0</name>
                  <description>Fast slew rate is configured on the corresponding pin, if the pin is configured as a digital output.</description>
                  <value>#0</value>
                </enumeratedValue>
                <enumeratedValue>
                  <name>1</name>
                  <description>Slow slew rate is configured on the corresponding pin, if the pin is configured as a digital output.</description>
                  <value>#1</value>
                </enumeratedValue>
              </enumeratedValues>
            </field>
            <field>
              <name>PFE</name>
              <description>Passive Filter Enable</description>
              <bitOffset>4</bitOffset>
              <bitWidth>1</bitWidth>
              <access>read-only</access>
              <enumeratedValues>
                <enumeratedValue>
                  <name>0</name>
                  <description>Passive input filter is disabled on the corresponding pin.</description>
                  <value>#0</value>
                </enumeratedValue>
                <enumeratedValue>
                  <name>1</name>
                  <description>Passive input filter is enabled on the corresponding pin, if the pin is configured as a digital input. Refer to the device data sheet for filter characteristics.</description>
                  <value>#1</value>
                </enumeratedValue>
              </enumeratedValues>
            </field>
            <field>
              <name>DSE</name>
              <description>Drive Strength Enable</description>
              <bitOffset>6</bitOffset>
              <bitWidth>1</bitWidth>
              <access>read-only</access>
              <enumeratedValues>
                <enumeratedValue>
                  <name>0</name>
                  <description>Low drive strength is configured on the corresponding pin, if pin is configured as a digital output.</description>
                  <value>#0</value>
                </enumeratedValue>
                <enumeratedValue>
                  <name>1</name>
                  <description>High drive strength is configured on the corresponding pin, if pin is configured as a digital output.</description>
                  <value>#1</value>
                </enumeratedValue>
              </enumeratedValues>
            </field>
            <field>
              <name>MUX</name>
              <description>Pin Mux Control</description>
              <bitOffset>8</bitOffset>
              <bitWidth>3</bitWidth>
              <access>read-write</access>
              <enumeratedValues>
                <enumeratedValue>
                  <name>000</name>
                  <description>Pin disabled (analog).</description>
                  <value>#000</value>
                </enumeratedValue>
                <enumeratedValue>
                  <name>001</name>
                  <description>Alternative 1 (GPIO).</description>
                  <value>#001</value>
                </enumeratedValue>
                <enumeratedValue>
                  <name>010</name>
                  <description>Alternative 2 (chip-specific).</description>
                  <value>#010</value>
                </enumeratedValue>
                <enumeratedValue>
                  <name>011</name>
                  <description>Alternative 3 (chip-specific).</description>
                  <value>#011</value>
                </enumeratedValue>
                <enumeratedValue>
                  <name>100</name>
                  <description>Alternative 4 (chip-specific).</description>
                  <value>#100</value>
                </enumeratedValue>
                <enumeratedValue>
                  <name>101</name>
                  <description>Alternative 5 (chip-specific).</description>
                  <value>#101</value>
                </enumeratedValue>
                <enumeratedValue>
                  <name>110</name>
                  <description>Alternative 6 (chip-specific).</description>
                  <value>#110</value>
                </enumeratedValue>
                <enumeratedValue>
                  <name>111</name>
                  <description>Alternative 7 (chip-specific).</description>
                  <value>#111</value>
                </enumeratedValue>
              </enumeratedValues>
            </field>
            <field>
              <name>IRQC</name>
              <description>Interrupt Configuration</description>
              <bitOffset>16</bitOffset>
              <bitWidth>4</bitWidth>
              <access>read-write</access>
              <enumeratedValues>
                <enumeratedValue>
                  <name>0000</name>
                  <description>Interrupt/DMA request disabled.</description>
                  <value>#0000</value>
                </enumeratedValue>
                <enumeratedValue>
                  <name>0001</name>
                  <description>DMA request on rising edge.</description>
                  <value>#0001</value>
                </enumeratedValue>
                <enumeratedValue>
                  <name>0010</name>
                  <description>DMA request on falling edge.</description>
                  <value>#0010</value>
                </enumeratedValue>
                <enumeratedValue>
                  <name>0011</name>
                  <description>DMA request on either edge.</description>
                  <value>#0011</value>
                </enumeratedValue>
                <enumeratedValue>
                  <name>1000</name>
                  <description>Interrupt when logic 0.</description>
                  <value>#1000</value>
                </enumeratedValue>
                <enumeratedValue>
                  <name>1001</name>
                  <description>Interrupt on rising-edge.</description>
                  <value>#1001</value>
                </enumeratedValue>
                <enumeratedValue>
                  <name>1010</name>
                  <description>Interrupt on falling-edge.</description>
                  <value>#1010</value>
                </enumeratedValue>
                <enumeratedValue>
                  <name>1011</name>
                  <description>Interrupt on either edge.</description>
                  <value>#1011</value>
                </enumeratedValue>
                <enumeratedValue>
                  <name>1100</name>
                  <description>Interrupt when logic 1.</description>
                  <value>#1100</value>
                </enumeratedValue>
              </enumeratedValues>
            </field>
            <field>
              <name>ISF</name>
              <description>Interrupt Status Flag</description>
              <bitOffset>24</bitOffset>
              <bitWidth>1</bitWidth>
              <access>read-write</access>
              <enumeratedValues>
                <enumeratedValue>
                  <name>0</name>
                  <description>Configured interrupt is not detected.</description>
                  <value>#0</value>
                </enumeratedValue>
                <enumeratedValue>
                  <name>1</name>
                  <description>Configured interrupt is detected. If the pin is configured to generate a DMA request, then the corresponding flag will be cleared automatically at the completion of the requested DMA transfer. Otherwise, the flag remains set until a logic 1 is written to the flag. If the pin is configured for a level sensitive interrupt and the pin remains asserted, then the flag is set again immediately after it is cleared.</description>
                  <value>#1</value>
                </enumeratedValue>
              </enumeratedValues>
            </field>
          </fields>
        </register>
        <register>
          <name>PCR5</name>
          <description>Pin Control Register n</description>
          <addressOffset>0x14</addressOffset>
          <size>32</size>
          <access>read-write</access>
          <resetValue>0x1</resetValue>
          <resetMask>0xFFFFFFFF</resetMask>
          <fields>
            <field>
              <name>PS</name>
              <description>Pull Select</description>
              <bitOffset>0</bitOffset>
              <bitWidth>1</bitWidth>
              <access>read-write</access>
              <enumeratedValues>
                <enumeratedValue>
                  <name>0</name>
                  <description>Internal pulldown resistor is enabled on the corresponding pin, if the corresponding PE field is set.</description>
                  <value>#0</value>
                </enumeratedValue>
                <enumeratedValue>
                  <name>1</name>
                  <description>Internal pullup resistor is enabled on the corresponding pin, if the corresponding PE field is set.</description>
                  <value>#1</value>
                </enumeratedValue>
              </enumeratedValues>
            </field>
            <field>
              <name>PE</name>
              <description>Pull Enable</description>
              <bitOffset>1</bitOffset>
              <bitWidth>1</bitWidth>
              <access>read-write</access>
              <enumeratedValues>
                <enumeratedValue>
                  <name>0</name>
                  <description>Internal pullup or pulldown resistor is not enabled on the corresponding pin.</description>
                  <value>#0</value>
                </enumeratedValue>
                <enumeratedValue>
                  <name>1</name>
                  <description>Internal pullup or pulldown resistor is enabled on the corresponding pin, if the pin is configured as a digital input.</description>
                  <value>#1</value>
                </enumeratedValue>
              </enumeratedValues>
            </field>
            <field>
              <name>SRE</name>
              <description>Slew Rate Enable</description>
              <bitOffset>2</bitOffset>
              <bitWidth>1</bitWidth>
              <access>read-write</access>
              <enumeratedValues>
                <enumeratedValue>
                  <name>0</name>
                  <description>Fast slew rate is configured on the corresponding pin, if the pin is configured as a digital output.</description>
                  <value>#0</value>
                </enumeratedValue>
                <enumeratedValue>
                  <name>1</name>
                  <description>Slow slew rate is configured on the corresponding pin, if the pin is configured as a digital output.</description>
                  <value>#1</value>
                </enumeratedValue>
              </enumeratedValues>
            </field>
            <field>
              <name>PFE</name>
              <description>Passive Filter Enable</description>
              <bitOffset>4</bitOffset>
              <bitWidth>1</bitWidth>
              <access>read-only</access>
              <enumeratedValues>
                <enumeratedValue>
                  <name>0</name>
                  <description>Passive input filter is disabled on the corresponding pin.</description>
                  <value>#0</value>
                </enumeratedValue>
                <enumeratedValue>
                  <name>1</name>
                  <description>Passive input filter is enabled on the corresponding pin, if the pin is configured as a digital input. Refer to the device data sheet for filter characteristics.</description>
                  <value>#1</value>
                </enumeratedValue>
              </enumeratedValues>
            </field>
            <field>
              <name>DSE</name>
              <description>Drive Strength Enable</description>
              <bitOffset>6</bitOffset>
              <bitWidth>1</bitWidth>
              <access>read-only</access>
              <enumeratedValues>
                <enumeratedValue>
                  <name>0</name>
                  <description>Low drive strength is configured on the corresponding pin, if pin is configured as a digital output.</description>
                  <value>#0</value>
                </enumeratedValue>
                <enumeratedValue>
                  <name>1</name>
                  <description>High drive strength is configured on the corresponding pin, if pin is configured as a digital output.</description>
                  <value>#1</value>
                </enumeratedValue>
              </enumeratedValues>
            </field>
            <field>
              <name>MUX</name>
              <description>Pin Mux Control</description>
              <bitOffset>8</bitOffset>
              <bitWidth>3</bitWidth>
              <access>read-write</access>
              <enumeratedValues>
                <enumeratedValue>
                  <name>000</name>
                  <description>Pin disabled (analog).</description>
                  <value>#000</value>
                </enumeratedValue>
                <enumeratedValue>
                  <name>001</name>
                  <description>Alternative 1 (GPIO).</description>
                  <value>#001</value>
                </enumeratedValue>
                <enumeratedValue>
                  <name>010</name>
                  <description>Alternative 2 (chip-specific).</description>
                  <value>#010</value>
                </enumeratedValue>
                <enumeratedValue>
                  <name>011</name>
                  <description>Alternative 3 (chip-specific).</description>
                  <value>#011</value>
                </enumeratedValue>
                <enumeratedValue>
                  <name>100</name>
                  <description>Alternative 4 (chip-specific).</description>
                  <value>#100</value>
                </enumeratedValue>
                <enumeratedValue>
                  <name>101</name>
                  <description>Alternative 5 (chip-specific).</description>
                  <value>#101</value>
                </enumeratedValue>
                <enumeratedValue>
                  <name>110</name>
                  <description>Alternative 6 (chip-specific).</description>
                  <value>#110</value>
                </enumeratedValue>
                <enumeratedValue>
                  <name>111</name>
                  <description>Alternative 7 (chip-specific).</description>
                  <value>#111</value>
                </enumeratedValue>
              </enumeratedValues>
            </field>
            <field>
              <name>IRQC</name>
              <description>Interrupt Configuration</description>
              <bitOffset>16</bitOffset>
              <bitWidth>4</bitWidth>
              <access>read-write</access>
              <enumeratedValues>
                <enumeratedValue>
                  <name>0000</name>
                  <description>Interrupt/DMA request disabled.</description>
                  <value>#0000</value>
                </enumeratedValue>
                <enumeratedValue>
                  <name>0001</name>
                  <description>DMA request on rising edge.</description>
                  <value>#0001</value>
                </enumeratedValue>
                <enumeratedValue>
                  <name>0010</name>
                  <description>DMA request on falling edge.</description>
                  <value>#0010</value>
                </enumeratedValue>
                <enumeratedValue>
                  <name>0011</name>
                  <description>DMA request on either edge.</description>
                  <value>#0011</value>
                </enumeratedValue>
                <enumeratedValue>
                  <name>1000</name>
                  <description>Interrupt when logic 0.</description>
                  <value>#1000</value>
                </enumeratedValue>
                <enumeratedValue>
                  <name>1001</name>
                  <description>Interrupt on rising-edge.</description>
                  <value>#1001</value>
                </enumeratedValue>
                <enumeratedValue>
                  <name>1010</name>
                  <description>Interrupt on falling-edge.</description>
                  <value>#1010</value>
                </enumeratedValue>
                <enumeratedValue>
                  <name>1011</name>
                  <description>Interrupt on either edge.</description>
                  <value>#1011</value>
                </enumeratedValue>
                <enumeratedValue>
                  <name>1100</name>
                  <description>Interrupt when logic 1.</description>
                  <value>#1100</value>
                </enumeratedValue>
              </enumeratedValues>
            </field>
            <field>
              <name>ISF</name>
              <description>Interrupt Status Flag</description>
              <bitOffset>24</bitOffset>
              <bitWidth>1</bitWidth>
              <access>read-write</access>
              <enumeratedValues>
                <enumeratedValue>
                  <name>0</name>
                  <description>Configured interrupt is not detected.</description>
                  <value>#0</value>
                </enumeratedValue>
                <enumeratedValue>
                  <name>1</name>
                  <description>Configured interrupt is detected. If the pin is configured to generate a DMA request, then the corresponding flag will be cleared automatically at the completion of the requested DMA transfer. Otherwise, the flag remains set until a logic 1 is written to the flag. If the pin is configured for a level sensitive interrupt and the pin remains asserted, then the flag is set again immediately after it is cleared.</description>
                  <value>#1</value>
                </enumeratedValue>
              </enumeratedValues>
            </field>
          </fields>
        </register>
        <register>
          <name>PCR6</name>
          <description>Pin Control Register n</description>
          <addressOffset>0x18</addressOffset>
          <size>32</size>
          <access>read-write</access>
          <resetValue>0x1</resetValue>
          <resetMask>0xFFFFFFFF</resetMask>
          <fields>
            <field>
              <name>PS</name>
              <description>Pull Select</description>
              <bitOffset>0</bitOffset>
              <bitWidth>1</bitWidth>
              <access>read-write</access>
              <enumeratedValues>
                <enumeratedValue>
                  <name>0</name>
                  <description>Internal pulldown resistor is enabled on the corresponding pin, if the corresponding PE field is set.</description>
                  <value>#0</value>
                </enumeratedValue>
                <enumeratedValue>
                  <name>1</name>
                  <description>Internal pullup resistor is enabled on the corresponding pin, if the corresponding PE field is set.</description>
                  <value>#1</value>
                </enumeratedValue>
              </enumeratedValues>
            </field>
            <field>
              <name>PE</name>
              <description>Pull Enable</description>
              <bitOffset>1</bitOffset>
              <bitWidth>1</bitWidth>
              <access>read-write</access>
              <enumeratedValues>
                <enumeratedValue>
                  <name>0</name>
                  <description>Internal pullup or pulldown resistor is not enabled on the corresponding pin.</description>
                  <value>#0</value>
                </enumeratedValue>
                <enumeratedValue>
                  <name>1</name>
                  <description>Internal pullup or pulldown resistor is enabled on the corresponding pin, if the pin is configured as a digital input.</description>
                  <value>#1</value>
                </enumeratedValue>
              </enumeratedValues>
            </field>
            <field>
              <name>SRE</name>
              <description>Slew Rate Enable</description>
              <bitOffset>2</bitOffset>
              <bitWidth>1</bitWidth>
              <access>read-write</access>
              <enumeratedValues>
                <enumeratedValue>
                  <name>0</name>
                  <description>Fast slew rate is configured on the corresponding pin, if the pin is configured as a digital output.</description>
                  <value>#0</value>
                </enumeratedValue>
                <enumeratedValue>
                  <name>1</name>
                  <description>Slow slew rate is configured on the corresponding pin, if the pin is configured as a digital output.</description>
                  <value>#1</value>
                </enumeratedValue>
              </enumeratedValues>
            </field>
            <field>
              <name>PFE</name>
              <description>Passive Filter Enable</description>
              <bitOffset>4</bitOffset>
              <bitWidth>1</bitWidth>
              <access>read-only</access>
              <enumeratedValues>
                <enumeratedValue>
                  <name>0</name>
                  <description>Passive input filter is disabled on the corresponding pin.</description>
                  <value>#0</value>
                </enumeratedValue>
                <enumeratedValue>
                  <name>1</name>
                  <description>Passive input filter is enabled on the corresponding pin, if the pin is configured as a digital input. Refer to the device data sheet for filter characteristics.</description>
                  <value>#1</value>
                </enumeratedValue>
              </enumeratedValues>
            </field>
            <field>
              <name>DSE</name>
              <description>Drive Strength Enable</description>
              <bitOffset>6</bitOffset>
              <bitWidth>1</bitWidth>
              <access>read-write</access>
              <enumeratedValues>
                <enumeratedValue>
                  <name>0</name>
                  <description>Low drive strength is configured on the corresponding pin, if pin is configured as a digital output.</description>
                  <value>#0</value>
                </enumeratedValue>
                <enumeratedValue>
                  <name>1</name>
                  <description>High drive strength is configured on the corresponding pin, if pin is configured as a digital output.</description>
                  <value>#1</value>
                </enumeratedValue>
              </enumeratedValues>
            </field>
            <field>
              <name>MUX</name>
              <description>Pin Mux Control</description>
              <bitOffset>8</bitOffset>
              <bitWidth>3</bitWidth>
              <access>read-write</access>
              <enumeratedValues>
                <enumeratedValue>
                  <name>000</name>
                  <description>Pin disabled (analog).</description>
                  <value>#000</value>
                </enumeratedValue>
                <enumeratedValue>
                  <name>001</name>
                  <description>Alternative 1 (GPIO).</description>
                  <value>#001</value>
                </enumeratedValue>
                <enumeratedValue>
                  <name>010</name>
                  <description>Alternative 2 (chip-specific).</description>
                  <value>#010</value>
                </enumeratedValue>
                <enumeratedValue>
                  <name>011</name>
                  <description>Alternative 3 (chip-specific).</description>
                  <value>#011</value>
                </enumeratedValue>
                <enumeratedValue>
                  <name>100</name>
                  <description>Alternative 4 (chip-specific).</description>
                  <value>#100</value>
                </enumeratedValue>
                <enumeratedValue>
                  <name>101</name>
                  <description>Alternative 5 (chip-specific).</description>
                  <value>#101</value>
                </enumeratedValue>
                <enumeratedValue>
                  <name>110</name>
                  <description>Alternative 6 (chip-specific).</description>
                  <value>#110</value>
                </enumeratedValue>
                <enumeratedValue>
                  <name>111</name>
                  <description>Alternative 7 (chip-specific).</description>
                  <value>#111</value>
                </enumeratedValue>
              </enumeratedValues>
            </field>
            <field>
              <name>IRQC</name>
              <description>Interrupt Configuration</description>
              <bitOffset>16</bitOffset>
              <bitWidth>4</bitWidth>
              <access>read-write</access>
              <enumeratedValues>
                <enumeratedValue>
                  <name>0000</name>
                  <description>Interrupt/DMA request disabled.</description>
                  <value>#0000</value>
                </enumeratedValue>
                <enumeratedValue>
                  <name>0001</name>
                  <description>DMA request on rising edge.</description>
                  <value>#0001</value>
                </enumeratedValue>
                <enumeratedValue>
                  <name>0010</name>
                  <description>DMA request on falling edge.</description>
                  <value>#0010</value>
                </enumeratedValue>
                <enumeratedValue>
                  <name>0011</name>
                  <description>DMA request on either edge.</description>
                  <value>#0011</value>
                </enumeratedValue>
                <enumeratedValue>
                  <name>1000</name>
                  <description>Interrupt when logic 0.</description>
                  <value>#1000</value>
                </enumeratedValue>
                <enumeratedValue>
                  <name>1001</name>
                  <description>Interrupt on rising-edge.</description>
                  <value>#1001</value>
                </enumeratedValue>
                <enumeratedValue>
                  <name>1010</name>
                  <description>Interrupt on falling-edge.</description>
                  <value>#1010</value>
                </enumeratedValue>
                <enumeratedValue>
                  <name>1011</name>
                  <description>Interrupt on either edge.</description>
                  <value>#1011</value>
                </enumeratedValue>
                <enumeratedValue>
                  <name>1100</name>
                  <description>Interrupt when logic 1.</description>
                  <value>#1100</value>
                </enumeratedValue>
              </enumeratedValues>
            </field>
            <field>
              <name>ISF</name>
              <description>Interrupt Status Flag</description>
              <bitOffset>24</bitOffset>
              <bitWidth>1</bitWidth>
              <access>read-write</access>
              <enumeratedValues>
                <enumeratedValue>
                  <name>0</name>
                  <description>Configured interrupt is not detected.</description>
                  <value>#0</value>
                </enumeratedValue>
                <enumeratedValue>
                  <name>1</name>
                  <description>Configured interrupt is detected. If the pin is configured to generate a DMA request, then the corresponding flag will be cleared automatically at the completion of the requested DMA transfer. Otherwise, the flag remains set until a logic 1 is written to the flag. If the pin is configured for a level sensitive interrupt and the pin remains asserted, then the flag is set again immediately after it is cleared.</description>
                  <value>#1</value>
                </enumeratedValue>
              </enumeratedValues>
            </field>
          </fields>
        </register>
        <register>
          <name>PCR7</name>
          <description>Pin Control Register n</description>
          <addressOffset>0x1C</addressOffset>
          <size>32</size>
          <access>read-write</access>
          <resetValue>0x1</resetValue>
          <resetMask>0xFFFFFFFF</resetMask>
          <fields>
            <field>
              <name>PS</name>
              <description>Pull Select</description>
              <bitOffset>0</bitOffset>
              <bitWidth>1</bitWidth>
              <access>read-write</access>
              <enumeratedValues>
                <enumeratedValue>
                  <name>0</name>
                  <description>Internal pulldown resistor is enabled on the corresponding pin, if the corresponding PE field is set.</description>
                  <value>#0</value>
                </enumeratedValue>
                <enumeratedValue>
                  <name>1</name>
                  <description>Internal pullup resistor is enabled on the corresponding pin, if the corresponding PE field is set.</description>
                  <value>#1</value>
                </enumeratedValue>
              </enumeratedValues>
            </field>
            <field>
              <name>PE</name>
              <description>Pull Enable</description>
              <bitOffset>1</bitOffset>
              <bitWidth>1</bitWidth>
              <access>read-write</access>
              <enumeratedValues>
                <enumeratedValue>
                  <name>0</name>
                  <description>Internal pullup or pulldown resistor is not enabled on the corresponding pin.</description>
                  <value>#0</value>
                </enumeratedValue>
                <enumeratedValue>
                  <name>1</name>
                  <description>Internal pullup or pulldown resistor is enabled on the corresponding pin, if the pin is configured as a digital input.</description>
                  <value>#1</value>
                </enumeratedValue>
              </enumeratedValues>
            </field>
            <field>
              <name>SRE</name>
              <description>Slew Rate Enable</description>
              <bitOffset>2</bitOffset>
              <bitWidth>1</bitWidth>
              <access>read-write</access>
              <enumeratedValues>
                <enumeratedValue>
                  <name>0</name>
                  <description>Fast slew rate is configured on the corresponding pin, if the pin is configured as a digital output.</description>
                  <value>#0</value>
                </enumeratedValue>
                <enumeratedValue>
                  <name>1</name>
                  <description>Slow slew rate is configured on the corresponding pin, if the pin is configured as a digital output.</description>
                  <value>#1</value>
                </enumeratedValue>
              </enumeratedValues>
            </field>
            <field>
              <name>PFE</name>
              <description>Passive Filter Enable</description>
              <bitOffset>4</bitOffset>
              <bitWidth>1</bitWidth>
              <access>read-only</access>
              <enumeratedValues>
                <enumeratedValue>
                  <name>0</name>
                  <description>Passive input filter is disabled on the corresponding pin.</description>
                  <value>#0</value>
                </enumeratedValue>
                <enumeratedValue>
                  <name>1</name>
                  <description>Passive input filter is enabled on the corresponding pin, if the pin is configured as a digital input. Refer to the device data sheet for filter characteristics.</description>
                  <value>#1</value>
                </enumeratedValue>
              </enumeratedValues>
            </field>
            <field>
              <name>DSE</name>
              <description>Drive Strength Enable</description>
              <bitOffset>6</bitOffset>
              <bitWidth>1</bitWidth>
              <access>read-write</access>
              <enumeratedValues>
                <enumeratedValue>
                  <name>0</name>
                  <description>Low drive strength is configured on the corresponding pin, if pin is configured as a digital output.</description>
                  <value>#0</value>
                </enumeratedValue>
                <enumeratedValue>
                  <name>1</name>
                  <description>High drive strength is configured on the corresponding pin, if pin is configured as a digital output.</description>
                  <value>#1</value>
                </enumeratedValue>
              </enumeratedValues>
            </field>
            <field>
              <name>MUX</name>
              <description>Pin Mux Control</description>
              <bitOffset>8</bitOffset>
              <bitWidth>3</bitWidth>
              <access>read-write</access>
              <enumeratedValues>
                <enumeratedValue>
                  <name>000</name>
                  <description>Pin disabled (analog).</description>
                  <value>#000</value>
                </enumeratedValue>
                <enumeratedValue>
                  <name>001</name>
                  <description>Alternative 1 (GPIO).</description>
                  <value>#001</value>
                </enumeratedValue>
                <enumeratedValue>
                  <name>010</name>
                  <description>Alternative 2 (chip-specific).</description>
                  <value>#010</value>
                </enumeratedValue>
                <enumeratedValue>
                  <name>011</name>
                  <description>Alternative 3 (chip-specific).</description>
                  <value>#011</value>
                </enumeratedValue>
                <enumeratedValue>
                  <name>100</name>
                  <description>Alternative 4 (chip-specific).</description>
                  <value>#100</value>
                </enumeratedValue>
                <enumeratedValue>
                  <name>101</name>
                  <description>Alternative 5 (chip-specific).</description>
                  <value>#101</value>
                </enumeratedValue>
                <enumeratedValue>
                  <name>110</name>
                  <description>Alternative 6 (chip-specific).</description>
                  <value>#110</value>
                </enumeratedValue>
                <enumeratedValue>
                  <name>111</name>
                  <description>Alternative 7 (chip-specific).</description>
                  <value>#111</value>
                </enumeratedValue>
              </enumeratedValues>
            </field>
            <field>
              <name>IRQC</name>
              <description>Interrupt Configuration</description>
              <bitOffset>16</bitOffset>
              <bitWidth>4</bitWidth>
              <access>read-write</access>
              <enumeratedValues>
                <enumeratedValue>
                  <name>0000</name>
                  <description>Interrupt/DMA request disabled.</description>
                  <value>#0000</value>
                </enumeratedValue>
                <enumeratedValue>
                  <name>0001</name>
                  <description>DMA request on rising edge.</description>
                  <value>#0001</value>
                </enumeratedValue>
                <enumeratedValue>
                  <name>0010</name>
                  <description>DMA request on falling edge.</description>
                  <value>#0010</value>
                </enumeratedValue>
                <enumeratedValue>
                  <name>0011</name>
                  <description>DMA request on either edge.</description>
                  <value>#0011</value>
                </enumeratedValue>
                <enumeratedValue>
                  <name>1000</name>
                  <description>Interrupt when logic 0.</description>
                  <value>#1000</value>
                </enumeratedValue>
                <enumeratedValue>
                  <name>1001</name>
                  <description>Interrupt on rising-edge.</description>
                  <value>#1001</value>
                </enumeratedValue>
                <enumeratedValue>
                  <name>1010</name>
                  <description>Interrupt on falling-edge.</description>
                  <value>#1010</value>
                </enumeratedValue>
                <enumeratedValue>
                  <name>1011</name>
                  <description>Interrupt on either edge.</description>
                  <value>#1011</value>
                </enumeratedValue>
                <enumeratedValue>
                  <name>1100</name>
                  <description>Interrupt when logic 1.</description>
                  <value>#1100</value>
                </enumeratedValue>
              </enumeratedValues>
            </field>
            <field>
              <name>ISF</name>
              <description>Interrupt Status Flag</description>
              <bitOffset>24</bitOffset>
              <bitWidth>1</bitWidth>
              <access>read-write</access>
              <enumeratedValues>
                <enumeratedValue>
                  <name>0</name>
                  <description>Configured interrupt is not detected.</description>
                  <value>#0</value>
                </enumeratedValue>
                <enumeratedValue>
                  <name>1</name>
                  <description>Configured interrupt is detected. If the pin is configured to generate a DMA request, then the corresponding flag will be cleared automatically at the completion of the requested DMA transfer. Otherwise, the flag remains set until a logic 1 is written to the flag. If the pin is configured for a level sensitive interrupt and the pin remains asserted, then the flag is set again immediately after it is cleared.</description>
                  <value>#1</value>
                </enumeratedValue>
              </enumeratedValues>
            </field>
          </fields>
        </register>
        <register>
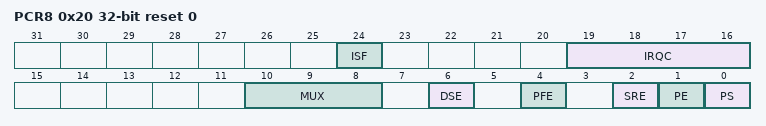
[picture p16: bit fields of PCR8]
          <name>PCR8</name>
          <description>Pin Control Register n</description>
          <addressOffset>0x20</addressOffset>
          <size>32</size>
          <access>read-write</access>
          <resetValue>0</resetValue>
          <resetMask>0xFFFFFFFF</resetMask>
          <fields>
            <field>
              <name>PS</name>
              <description>Pull Select</description>
              <bitOffset>0</bitOffset>
              <bitWidth>1</bitWidth>
              <access>read-only</access>
              <enumeratedValues>
                <enumeratedValue>
                  <name>0</name>
                  <description>Internal pulldown resistor is enabled on the corresponding pin, if the corresponding PE field is set.</description>
                  <value>#0</value>
                </enumeratedValue>
                <enumeratedValue>
                  <name>1</name>
                  <description>Internal pullup resistor is enabled on the corresponding pin, if the corresponding PE field is set.</description>
                  <value>#1</value>
                </enumeratedValue>
              </enumeratedValues>
            </field>
            <field>
              <name>PE</name>
              <description>Pull Enable</description>
              <bitOffset>1</bitOffset>
              <bitWidth>1</bitWidth>
              <access>read-only</access>
              <enumeratedValues>
                <enumeratedValue>
                  <name>0</name>
                  <description>Internal pullup or pulldown resistor is not enabled on the corresponding pin.</description>
                  <value>#0</value>
                </enumeratedValue>
                <enumeratedValue>
                  <name>1</name>
                  <description>Internal pullup or pulldown resistor is enabled on the corresponding pin, if the pin is configured as a digital input.</description>
                  <value>#1</value>
                </enumeratedValue>
              </enumeratedValues>
            </field>
            <field>
              <name>SRE</name>
              <description>Slew Rate Enable</description>
              <bitOffset>2</bitOffset>
              <bitWidth>1</bitWidth>
              <access>read-only</access>
              <enumeratedValues>
                <enumeratedValue>
                  <name>0</name>
                  <description>Fast slew rate is configured on the corresponding pin, if the pin is configured as a digital output.</description>
                  <value>#0</value>
                </enumeratedValue>
                <enumeratedValue>
                  <name>1</name>
                  <description>Slow slew rate is configured on the corresponding pin, if the pin is configured as a digital output.</description>
                  <value>#1</value>
                </enumeratedValue>
              </enumeratedValues>
            </field>
            <field>
              <name>PFE</name>
              <description>Passive Filter Enable</description>
              <bitOffset>4</bitOffset>
              <bitWidth>1</bitWidth>
              <access>read-only</access>
              <enumeratedValues>
                <enumeratedValue>
                  <name>0</name>
                  <description>Passive input filter is disabled on the corresponding pin.</description>
                  <value>#0</value>
                </enumeratedValue>
                <enumeratedValue>
                  <name>1</name>
                  <description>Passive input filter is enabled on the corresponding pin, if the pin is configured as a digital input. Refer to the device data sheet for filter characteristics.</description>
                  <value>#1</value>
                </enumeratedValue>
              </enumeratedValues>
            </field>
            <field>
              <name>DSE</name>
              <description>Drive Strength Enable</description>
              <bitOffset>6</bitOffset>
              <bitWidth>1</bitWidth>
              <access>read-only</access>
              <enumeratedValues>
                <enumeratedValue>
                  <name>0</name>
                  <description>Low drive strength is configured on the corresponding pin, if pin is configured as a digital output.</description>
                  <value>#0</value>
                </enumeratedValue>
                <enumeratedValue>
                  <name>1</name>
                  <description>High drive strength is configured on the corresponding pin, if pin is configured as a digital output.</description>
                  <value>#1</value>
                </enumeratedValue>
              </enumeratedValues>
            </field>
            <field>
              <name>MUX</name>
              <description>Pin Mux Control</description>
              <bitOffset>8</bitOffset>
              <bitWidth>3</bitWidth>
              <access>read-write</access>
              <enumeratedValues>
                <enumeratedValue>
                  <name>000</name>
                  <description>Pin disabled (analog).</description>
                  <value>#000</value>
                </enumeratedValue>
                <enumeratedValue>
                  <name>001</name>
                  <description>Alternative 1 (GPIO).</description>
                  <value>#001</value>
                </enumeratedValue>
                <enumeratedValue>
                  <name>010</name>
                  <description>Alternative 2 (chip-specific).</description>
                  <value>#010</value>
                </enumeratedValue>
                <enumeratedValue>
                  <name>011</name>
                  <description>Alternative 3 (chip-specific).</description>
                  <value>#011</value>
                </enumeratedValue>
                <enumeratedValue>
                  <name>100</name>
                  <description>Alternative 4 (chip-specific).</description>
                  <value>#100</value>
                </enumeratedValue>
                <enumeratedValue>
                  <name>101</name>
                  <description>Alternative 5 (chip-specific).</description>
                  <value>#101</value>
                </enumeratedValue>
                <enumeratedValue>
                  <name>110</name>
                  <description>Alternative 6 (chip-specific).</description>
                  <value>#110</value>
                </enumeratedValue>
                <enumeratedValue>
                  <name>111</name>
                  <description>Alternative 7 (chip-specific).</description>
                  <value>#111</value>
                </enumeratedValue>
              </enumeratedValues>
            </field>
            <field>
              <name>IRQC</name>
              <description>Interrupt Configuration</description>
              <bitOffset>16</bitOffset>
              <bitWidth>4</bitWidth>
              <access>read-write</access>
              <enumeratedValues>
                <enumeratedValue>
                  <name>0000</name>
                  <description>Interrupt/DMA request disabled.</description>
                  <value>#0000</value>
                </enumeratedValue>
                <enumeratedValue>
                  <name>0001</name>
                  <description>DMA request on rising edge.</description>
                  <value>#0001</value>
                </enumeratedValue>
                <enumeratedValue>
                  <name>0010</name>
                  <description>DMA request on falling edge.</description>
                  <value>#0010</value>
                </enumeratedValue>
                <enumeratedValue>
                  <name>0011</name>
                  <description>DMA request on either edge.</description>
                  <value>#0011</value>
                </enumeratedValue>
                <enumeratedValue>
                  <name>1000</name>
                  <description>Interrupt when logic 0.</description>
                  <value>#1000</value>
                </enumeratedValue>
                <enumeratedValue>
                  <name>1001</name>
                  <description>Interrupt on rising-edge.</description>
                  <value>#1001</value>
                </enumeratedValue>
                <enumeratedValue>
                  <name>1010</name>
                  <description>Interrupt on falling-edge.</description>
                  <value>#1010</value>
                </enumeratedValue>
                <enumeratedValue>
                  <name>1011</name>
                  <description>Interrupt on either edge.</description>
                  <value>#1011</value>
                </enumeratedValue>
                <enumeratedValue>
                  <name>1100</name>
                  <description>Interrupt when logic 1.</description>
                  <value>#1100</value>
                </enumeratedValue>
              </enumeratedValues>
            </field>
            <field>
              <name>ISF</name>
              <description>Interrupt Status Flag</description>
              <bitOffset>24</bitOffset>
              <bitWidth>1</bitWidth>
              <access>read-write</access>
              <enumeratedValues>
                <enumeratedValue>
                  <name>0</name>
                  <description>Configured interrupt is not detected.</description>
                  <value>#0</value>
                </enumeratedValue>
                <enumeratedValue>
                  <name>1</name>
                  <description>Configured interrupt is detected. If the pin is configured to generate a DMA request, then the corresponding flag will be cleared automatically at the completion of the requested DMA transfer. Otherwise, the flag remains set until a logic 1 is written to the flag. If the pin is configured for a level sensitive interrupt and the pin remains asserted, then the flag is set again immediately after it is cleared.</description>
                  <value>#1</value>
                </enumeratedValue>
              </enumeratedValues>
            </field>
          </fields>
        </register>
        <register>
          <name>PCR9</name>
          <description>Pin Control Register n</description>
          <addressOffset>0x24</addressOffset>
          <size>32</size>
          <access>read-write</access>
          <resetValue>0</resetValue>
          <resetMask>0xFFFFFFFF</resetMask>
          <fields>
            <field>
              <name>PS</name>
              <description>Pull Select</description>
              <bitOffset>0</bitOffset>
              <bitWidth>1</bitWidth>
              <access>read-only</access>
              <enumeratedValues>
                <enumeratedValue>
                  <name>0</name>
                  <description>Internal pulldown resistor is enabled on the corresponding pin, if the corresponding PE field is set.</description>
                  <value>#0</value>
                </enumeratedValue>
                <enumeratedValue>
                  <name>1</name>
                  <description>Internal pullup resistor is enabled on the corresponding pin, if the corresponding PE field is set.</description>
                  <value>#1</value>
                </enumeratedValue>
              </enumeratedValues>
            </field>
            <field>
              <name>PE</name>
              <description>Pull Enable</description>
              <bitOffset>1</bitOffset>
              <bitWidth>1</bitWidth>
              <access>read-only</access>
              <enumeratedValues>
                <enumeratedValue>
                  <name>0</name>
                  <description>Internal pullup or pulldown resistor is not enabled on the corresponding pin.</description>
                  <value>#0</value>
                </enumeratedValue>
                <enumeratedValue>
                  <name>1</name>
                  <description>Internal pullup or pulldown resistor is enabled on the corresponding pin, if the pin is configured as a digital input.</description>
                  <value>#1</value>
                </enumeratedValue>
              </enumeratedValues>
            </field>
            <field>
              <name>SRE</name>
              <description>Slew Rate Enable</description>
              <bitOffset>2</bitOffset>
              <bitWidth>1</bitWidth>
              <access>read-only</access>
              <enumeratedValues>
                <enumeratedValue>
                  <name>0</name>
                  <description>Fast slew rate is configured on the corresponding pin, if the pin is configured as a digital output.</description>
                  <value>#0</value>
                </enumeratedValue>
                <enumeratedValue>
                  <name>1</name>
                  <description>Slow slew rate is configured on the corresponding pin, if the pin is configured as a digital output.</description>
                  <value>#1</value>
                </enumeratedValue>
              </enumeratedValues>
            </field>
            <field>
              <name>PFE</name>
              <description>Passive Filter Enable</description>
              <bitOffset>4</bitOffset>
              <bitWidth>1</bitWidth>
              <access>read-only</access>
              <enumeratedValues>
                <enumeratedValue>
                  <name>0</name>
                  <description>Passive input filter is disabled on the corresponding pin.</description>
                  <value>#0</value>
                </enumeratedValue>
                <enumeratedValue>
                  <name>1</name>
                  <description>Passive input filter is enabled on the corresponding pin, if the pin is configured as a digital input. Refer to the device data sheet for filter characteristics.</description>
                  <value>#1</value>
                </enumeratedValue>
              </enumeratedValues>
            </field>
            <field>
              <name>DSE</name>
              <description>Drive Strength Enable</description>
              <bitOffset>6</bitOffset>
              <bitWidth>1</bitWidth>
              <access>read-only</access>
              <enumeratedValues>
                <enumeratedValue>
                  <name>0</name>
                  <description>Low drive strength is configured on the corresponding pin, if pin is configured as a digital output.</description>
                  <value>#0</value>
                </enumeratedValue>
                <enumeratedValue>
                  <name>1</name>
                  <description>High drive strength is configured on the corresponding pin, if pin is configured as a digital output.</description>
                  <value>#1</value>
                </enumeratedValue>
              </enumeratedValues>
            </field>
            <field>
              <name>MUX</name>
              <description>Pin Mux Control</description>
              <bitOffset>8</bitOffset>
              <bitWidth>3</bitWidth>
              <access>read-write</access>
              <enumeratedValues>
                <enumeratedValue>
                  <name>000</name>
                  <description>Pin disabled (analog).</description>
                  <value>#000</value>
                </enumeratedValue>
                <enumeratedValue>
                  <name>001</name>
                  <description>Alternative 1 (GPIO).</description>
                  <value>#001</value>
                </enumeratedValue>
                <enumeratedValue>
                  <name>010</name>
                  <description>Alternative 2 (chip-specific).</description>
                  <value>#010</value>
                </enumeratedValue>
                <enumeratedValue>
                  <name>011</name>
                  <description>Alternative 3 (chip-specific).</description>
                  <value>#011</value>
                </enumeratedValue>
                <enumeratedValue>
                  <name>100</name>
                  <description>Alternative 4 (chip-specific).</description>
                  <value>#100</value>
                </enumeratedValue>
                <enumeratedValue>
                  <name>101</name>
                  <description>Alternative 5 (chip-specific).</description>
                  <value>#101</value>
                </enumeratedValue>
                <enumeratedValue>
                  <name>110</name>
                  <description>Alternative 6 (chip-specific).</description>
                  <value>#110</value>
                </enumeratedValue>
                <enumeratedValue>
                  <name>111</name>
                  <description>Alternative 7 (chip-specific).</description>
                  <value>#111</value>
                </enumeratedValue>
              </enumeratedValues>
            </field>
            <field>
              <name>IRQC</name>
              <description>Interrupt Configuration</description>
              <bitOffset>16</bitOffset>
              <bitWidth>4</bitWidth>
              <access>read-write</access>
              <enumeratedValues>
                <enumeratedValue>
                  <name>0000</name>
                  <description>Interrupt/DMA request disabled.</description>
                  <value>#0000</value>
                </enumeratedValue>
                <enumeratedValue>
                  <name>0001</name>
                  <description>DMA request on rising edge.</description>
                  <value>#0001</value>
                </enumeratedValue>
                <enumeratedValue>
                  <name>0010</name>
                  <description>DMA request on falling edge.</description>
                  <value>#0010</value>
                </enumeratedValue>
                <enumeratedValue>
                  <name>0011</name>
                  <description>DMA request on either edge.</description>
                  <value>#0011</value>
                </enumeratedValue>
                <enumeratedValue>
                  <name>1000</name>
                  <description>Interrupt when logic 0.</description>
                  <value>#1000</value>
                </enumeratedValue>
                <enumeratedValue>
                  <name>1001</name>
                  <description>Interrupt on rising-edge.</description>
                  <value>#1001</value>
                </enumeratedValue>
                <enumeratedValue>
                  <name>1010</name>
                  <description>Interrupt on falling-edge.</description>
                  <value>#1010</value>
                </enumeratedValue>
                <enumeratedValue>
                  <name>1011</name>
                  <description>Interrupt on either edge.</description>
                  <value>#1011</value>
                </enumeratedValue>
                <enumeratedValue>
                  <name>1100</name>
                  <description>Interrupt when logic 1.</description>
                  <value>#1100</value>
                </enumeratedValue>
              </enumeratedValues>
            </field>
            <field>
              <name>ISF</name>
              <description>Interrupt Status Flag</description>
              <bitOffset>24</bitOffset>
              <bitWidth>1</bitWidth>
              <access>read-write</access>
              <enumeratedValues>
                <enumeratedValue>
                  <name>0</name>
                  <description>Configured interrupt is not detected.</description>
                  <value>#0</value>
                </enumeratedValue>
                <enumeratedValue>
                  <name>1</name>
                  <description>Configured interrupt is detected. If the pin is configured to generate a DMA request, then the corresponding flag will be cleared automatically at the completion of the requested DMA transfer. Otherwise, the flag remains set until a logic 1 is written to the flag. If the pin is configured for a level sensitive interrupt and the pin remains asserted, then the flag is set again immediately after it is cleared.</description>
                  <value>#1</value>
                </enumeratedValue>
              </enumeratedValues>
            </field>
          </fields>
        </register>
        <register>
          <name>PCR10</name>
          <description>Pin Control Register n</description>
          <addressOffset>0x28</addressOffset>
          <size>32</size>
          <access>read-write</access>
          <resetValue>0</resetValue>
          <resetMask>0xFFFFFFFF</resetMask>
          <fields>
            <field>
              <name>PS</name>
              <description>Pull Select</description>
              <bitOffset>0</bitOffset>
              <bitWidth>1</bitWidth>
              <access>read-only</access>
              <enumeratedValues>
                <enumeratedValue>
                  <name>0</name>
                  <description>Internal pulldown resistor is enabled on the corresponding pin, if the corresponding PE field is set.</description>
                  <value>#0</value>
                </enumeratedValue>
                <enumeratedValue>
                  <name>1</name>
                  <description>Internal pullup resistor is enabled on the corresponding pin, if the corresponding PE field is set.</description>
                  <value>#1</value>
                </enumeratedValue>
              </enumeratedValues>
            </field>
            <field>
              <name>PE</name>
              <description>Pull Enable</description>
              <bitOffset>1</bitOffset>
              <bitWidth>1</bitWidth>
              <access>read-only</access>
              <enumeratedValues>
                <enumeratedValue>
                  <name>0</name>
                  <description>Internal pullup or pulldown resistor is not enabled on the corresponding pin.</description>
                  <value>#0</value>
                </enumeratedValue>
                <enumeratedValue>
                  <name>1</name>
                  <description>Internal pullup or pulldown resistor is enabled on the corresponding pin, if the pin is configured as a digital input.</description>
                  <value>#1</value>
                </enumeratedValue>
              </enumeratedValues>
            </field>
            <field>
              <name>SRE</name>
              <description>Slew Rate Enable</description>
              <bitOffset>2</bitOffset>
              <bitWidth>1</bitWidth>
              <access>read-only</access>
              <enumeratedValues>
                <enumeratedValue>
                  <name>0</name>
                  <description>Fast slew rate is configured on the corresponding pin, if the pin is configured as a digital output.</description>
                  <value>#0</value>
                </enumeratedValue>
                <enumeratedValue>
                  <name>1</name>
                  <description>Slow slew rate is configured on the corresponding pin, if the pin is configured as a digital output.</description>
                  <value>#1</value>
                </enumeratedValue>
              </enumeratedValues>
            </field>
            <field>
              <name>PFE</name>
              <description>Passive Filter Enable</description>
              <bitOffset>4</bitOffset>
              <bitWidth>1</bitWidth>
              <access>read-only</access>
              <enumeratedValues>
                <enumeratedValue>
                  <name>0</name>
                  <description>Passive input filter is disabled on the corresponding pin.</description>
                  <value>#0</value>
                </enumeratedValue>
                <enumeratedValue>
                  <name>1</name>
                  <description>Passive input filter is enabled on the corresponding pin, if the pin is configured as a digital input. Refer to the device data sheet for filter characteristics.</description>
                  <value>#1</value>
                </enumeratedValue>
              </enumeratedValues>
            </field>
            <field>
              <name>DSE</name>
              <description>Drive Strength Enable</description>
              <bitOffset>6</bitOffset>
              <bitWidth>1</bitWidth>
              <access>read-only</access>
              <enumeratedValues>
                <enumeratedValue>
                  <name>0</name>
                  <description>Low drive strength is configured on the corresponding pin, if pin is configured as a digital output.</description>
                  <value>#0</value>
                </enumeratedValue>
                <enumeratedValue>
                  <name>1</name>
                  <description>High drive strength is configured on the corresponding pin, if pin is configured as a digital output.</description>
                  <value>#1</value>
                </enumeratedValue>
              </enumeratedValues>
            </field>
            <field>
              <name>MUX</name>
              <description>Pin Mux Control</description>
              <bitOffset>8</bitOffset>
              <bitWidth>3</bitWidth>
              <access>read-write</access>
              <enumeratedValues>
                <enumeratedValue>
                  <name>000</name>
                  <description>Pin disabled (analog).</description>
                  <value>#000</value>
                </enumeratedValue>
                <enumeratedValue>
                  <name>001</name>
                  <description>Alternative 1 (GPIO).</description>
                  <value>#001</value>
                </enumeratedValue>
                <enumeratedValue>
                  <name>010</name>
                  <description>Alternative 2 (chip-specific).</description>
                  <value>#010</value>
                </enumeratedValue>
                <enumeratedValue>
                  <name>011</name>
                  <description>Alternative 3 (chip-specific).</description>
                  <value>#011</value>
                </enumeratedValue>
                <enumeratedValue>
                  <name>100</name>
                  <description>Alternative 4 (chip-specific).</description>
                  <value>#100</value>
                </enumeratedValue>
                <enumeratedValue>
                  <name>101</name>
                  <description>Alternative 5 (chip-specific).</description>
                  <value>#101</value>
                </enumeratedValue>
                <enumeratedValue>
                  <name>110</name>
                  <description>Alternative 6 (chip-specific).</description>
                  <value>#110</value>
                </enumeratedValue>
                <enumeratedValue>
                  <name>111</name>
                  <description>Alternative 7 (chip-specific).</description>
                  <value>#111</value>
                </enumeratedValue>
              </enumeratedValues>
            </field>
            <field>
              <name>IRQC</name>
              <description>Interrupt Configuration</description>
              <bitOffset>16</bitOffset>
              <bitWidth>4</bitWidth>
              <access>read-write</access>
              <enumeratedValues>
                <enumeratedValue>
                  <name>0000</name>
                  <description>Interrupt/DMA request disabled.</description>
                  <value>#0000</value>
                </enumeratedValue>
                <enumeratedValue>
                  <name>0001</name>
                  <description>DMA request on rising edge.</description>
                  <value>#0001</value>
                </enumeratedValue>
                <enumeratedValue>
                  <name>0010</name>
                  <description>DMA request on falling edge.</description>
                  <value>#0010</value>
                </enumeratedValue>
                <enumeratedValue>
                  <name>0011</name>
                  <description>DMA request on either edge.</description>
                  <value>#0011</value>
                </enumeratedValue>
                <enumeratedValue>
                  <name>1000</name>
                  <description>Interrupt when logic 0.</description>
                  <value>#1000</value>
                </enumeratedValue>
                <enumeratedValue>
                  <name>1001</name>
                  <description>Interrupt on rising-edge.</description>
                  <value>#1001</value>
                </enumeratedValue>
                <enumeratedValue>
                  <name>1010</name>
                  <description>Interrupt on falling-edge.</description>
                  <value>#1010</value>
                </enumeratedValue>
                <enumeratedValue>
                  <name>1011</name>
                  <description>Interrupt on either edge.</description>
                  <value>#1011</value>
                </enumeratedValue>
                <enumeratedValue>
                  <name>1100</name>
                  <description>Interrupt when logic 1.</description>
                  <value>#1100</value>
                </enumeratedValue>
              </enumeratedValues>
            </field>
            <field>
              <name>ISF</name>
              <description>Interrupt Status Flag</description>
              <bitOffset>24</bitOffset>
              <bitWidth>1</bitWidth>
              <access>read-write</access>
              <enumeratedValues>
                <enumeratedValue>
                  <name>0</name>
                  <description>Configured interrupt is not detected.</description>
                  <value>#0</value>
                </enumeratedValue>
                <enumeratedValue>
                  <name>1</name>
                  <description>Configured interrupt is detected. If the pin is configured to generate a DMA request, then the corresponding flag will be cleared automatically at the completion of the requested DMA transfer. Otherwise, the flag remains set until a logic 1 is written to the flag. If the pin is configured for a level sensitive interrupt and the pin remains asserted, then the flag is set again immediately after it is cleared.</description>
                  <value>#1</value>
                </enumeratedValue>
              </enumeratedValues>
            </field>
          </fields>
        </register>
        <register>
          <name>PCR11</name>
          <description>Pin Control Register n</description>
          <addressOffset>0x2C</addressOffset>
          <size>32</size>
          <access>read-write</access>
          <resetValue>0</resetValue>
          <resetMask>0xFFFFFFFF</resetMask>
          <fields>
            <field>
              <name>PS</name>
              <description>Pull Select</description>
              <bitOffset>0</bitOffset>
              <bitWidth>1</bitWidth>
              <access>read-only</access>
              <enumeratedValues>
                <enumeratedValue>
                  <name>0</name>
                  <description>Internal pulldown resistor is enabled on the corresponding pin, if the corresponding PE field is set.</description>
                  <value>#0</value>
                </enumeratedValue>
                <enumeratedValue>
                  <name>1</name>
                  <description>Internal pullup resistor is enabled on the corresponding pin, if the corresponding PE field is set.</description>
                  <value>#1</value>
                </enumeratedValue>
              </enumeratedValues>
            </field>
            <field>
              <name>PE</name>
              <description>Pull Enable</description>
              <bitOffset>1</bitOffset>
              <bitWidth>1</bitWidth>
              <access>read-only</access>
              <enumeratedValues>
                <enumeratedValue>
                  <name>0</name>
                  <description>Internal pullup or pulldown resistor is not enabled on the corresponding pin.</description>
                  <value>#0</value>
                </enumeratedValue>
                <enumeratedValue>
                  <name>1</name>
                  <description>Internal pullup or pulldown resistor is enabled on the corresponding pin, if the pin is configured as a digital input.</description>
                  <value>#1</value>
                </enumeratedValue>
              </enumeratedValues>
            </field>
            <field>
              <name>SRE</name>
              <description>Slew Rate Enable</description>
              <bitOffset>2</bitOffset>
              <bitWidth>1</bitWidth>
              <access>read-only</access>
              <enumeratedValues>
                <enumeratedValue>
                  <name>0</name>
                  <description>Fast slew rate is configured on the corresponding pin, if the pin is configured as a digital output.</description>
                  <value>#0</value>
                </enumeratedValue>
                <enumeratedValue>
                  <name>1</name>
                  <description>Slow slew rate is configured on the corresponding pin, if the pin is configured as a digital output.</description>
                  <value>#1</value>
                </enumeratedValue>
              </enumeratedValues>
            </field>
            <field>
              <name>PFE</name>
              <description>Passive Filter Enable</description>
              <bitOffset>4</bitOffset>
              <bitWidth>1</bitWidth>
              <access>read-only</access>
              <enumeratedValues>
                <enumeratedValue>
                  <name>0</name>
                  <description>Passive input filter is disabled on the corresponding pin.</description>
                  <value>#0</value>
                </enumeratedValue>
                <enumeratedValue>
                  <name>1</name>
                  <description>Passive input filter is enabled on the corresponding pin, if the pin is configured as a digital input. Refer to the device data sheet for filter characteristics.</description>
                  <value>#1</value>
                </enumeratedValue>
              </enumeratedValues>
            </field>
            <field>
              <name>DSE</name>
              <description>Drive Strength Enable</description>
              <bitOffset>6</bitOffset>
              <bitWidth>1</bitWidth>
              <access>read-only</access>
              <enumeratedValues>
                <enumeratedValue>
                  <name>0</name>
                  <description>Low drive strength is configured on the corresponding pin, if pin is configured as a digital output.</description>
                  <value>#0</value>
                </enumeratedValue>
                <enumeratedValue>
                  <name>1</name>
                  <description>High drive strength is configured on the corresponding pin, if pin is configured as a digital output.</description>
                  <value>#1</value>
                </enumeratedValue>
              </enumeratedValues>
            </field>
            <field>
              <name>MUX</name>
              <description>Pin Mux Control</description>
              <bitOffset>8</bitOffset>
              <bitWidth>3</bitWidth>
              <access>read-write</access>
              <enumeratedValues>
                <enumeratedValue>
                  <name>000</name>
                  <description>Pin disabled (analog).</description>
                  <value>#000</value>
                </enumeratedValue>
                <enumeratedValue>
                  <name>001</name>
                  <description>Alternative 1 (GPIO).</description>
                  <value>#001</value>
                </enumeratedValue>
                <enumeratedValue>
                  <name>010</name>
                  <description>Alternative 2 (chip-specific).</description>
                  <value>#010</value>
                </enumeratedValue>
                <enumeratedValue>
                  <name>011</name>
                  <description>Alternative 3 (chip-specific).</description>
                  <value>#011</value>
                </enumeratedValue>
                <enumeratedValue>
                  <name>100</name>
                  <description>Alternative 4 (chip-specific).</description>
                  <value>#100</value>
                </enumeratedValue>
                <enumeratedValue>
                  <name>101</name>
                  <description>Alternative 5 (chip-specific).</description>
                  <value>#101</value>
                </enumeratedValue>
                <enumeratedValue>
                  <name>110</name>
                  <description>Alternative 6 (chip-specific).</description>
                  <value>#110</value>
                </enumeratedValue>
                <enumeratedValue>
                  <name>111</name>
                  <description>Alternative 7 (chip-specific).</description>
                  <value>#111</value>
                </enumeratedValue>
              </enumeratedValues>
            </field>
            <field>
              <name>IRQC</name>
              <description>Interrupt Configuration</description>
              <bitOffset>16</bitOffset>
              <bitWidth>4</bitWidth>
              <access>read-write</access>
              <enumeratedValues>
                <enumeratedValue>
                  <name>0000</name>
                  <description>Interrupt/DMA request disabled.</description>
                  <value>#0000</value>
                </enumeratedValue>
                <enumeratedValue>
                  <name>0001</name>
                  <description>DMA request on rising edge.</description>
                  <value>#0001</value>
                </enumeratedValue>
                <enumeratedValue>
                  <name>0010</name>
                  <description>DMA request on falling edge.</description>
                  <value>#0010</value>
                </enumeratedValue>
                <enumeratedValue>
                  <name>0011</name>
                  <description>DMA request on either edge.</description>
                  <value>#0011</value>
                </enumeratedValue>
                <enumeratedValue>
                  <name>1000</name>
                  <description>Interrupt when logic 0.</description>
                  <value>#1000</value>
                </enumeratedValue>
                <enumeratedValue>
                  <name>1001</name>
                  <description>Interrupt on rising-edge.</description>
                  <value>#1001</value>
                </enumeratedValue>
                <enumeratedValue>
                  <name>1010</name>
                  <description>Interrupt on falling-edge.</description>
                  <value>#1010</value>
                </enumeratedValue>
                <enumeratedValue>
                  <name>1011</name>
                  <description>Interrupt on either edge.</description>
                  <value>#1011</value>
                </enumeratedValue>
                <enumeratedValue>
                  <name>1100</name>
                  <description>Interrupt when logic 1.</description>
                  <value>#1100</value>
                </enumeratedValue>
              </enumeratedValues>
            </field>
            <field>
              <name>ISF</name>
              <description>Interrupt Status Flag</description>
              <bitOffset>24</bitOffset>
              <bitWidth>1</bitWidth>
              <access>read-write</access>
              <enumeratedValues>
                <enumeratedValue>
                  <name>0</name>
                  <description>Configured interrupt is not detected.</description>
                  <value>#0</value>
                </enumeratedValue>
                <enumeratedValue>
                  <name>1</name>
                  <description>Configured interrupt is detected. If the pin is configured to generate a DMA request, then the corresponding flag will be cleared automatically at the completion of the requested DMA transfer. Otherwise, the flag remains set until a logic 1 is written to the flag. If the pin is configured for a level sensitive interrupt and the pin remains asserted, then the flag is set again immediately after it is cleared.</description>
                  <value>#1</value>
                </enumeratedValue>
              </enumeratedValues>
            </field>
          </fields>
        </register>
        <register>
          <name>PCR12</name>
          <description>Pin Control Register n</description>
          <addressOffset>0x30</addressOffset>
          <size>32</size>
          <access>read-write</access>
          <resetValue>0</resetValue>
          <resetMask>0xFFFFFFFF</resetMask>
          <fields>
            <field>
              <name>PS</name>
              <description>Pull Select</description>
              <bitOffset>0</bitOffset>
              <bitWidth>1</bitWidth>
              <access>read-only</access>
              <enumeratedValues>
                <enumeratedValue>
                  <name>0</name>
                  <description>Internal pulldown resistor is enabled on the corresponding pin, if the corresponding PE field is set.</description>
                  <value>#0</value>
                </enumeratedValue>
                <enumeratedValue>
                  <name>1</name>
                  <description>Internal pullup resistor is enabled on the corresponding pin, if the corresponding PE field is set.</description>
                  <value>#1</value>
                </enumeratedValue>
              </enumeratedValues>
            </field>
            <field>
              <name>PE</name>
              <description>Pull Enable</description>
              <bitOffset>1</bitOffset>
              <bitWidth>1</bitWidth>
              <access>read-only</access>
              <enumeratedValues>
                <enumeratedValue>
                  <name>0</name>
                  <description>Internal pullup or pulldown resistor is not enabled on the corresponding pin.</description>
                  <value>#0</value>
                </enumeratedValue>
                <enumeratedValue>
                  <name>1</name>
                  <description>Internal pullup or pulldown resistor is enabled on the corresponding pin, if the pin is configured as a digital input.</description>
                  <value>#1</value>
                </enumeratedValue>
              </enumeratedValues>
            </field>
            <field>
              <name>SRE</name>
              <description>Slew Rate Enable</description>
              <bitOffset>2</bitOffset>
              <bitWidth>1</bitWidth>
              <access>read-only</access>
              <enumeratedValues>
                <enumeratedValue>
                  <name>0</name>
                  <description>Fast slew rate is configured on the corresponding pin, if the pin is configured as a digital output.</description>
                  <value>#0</value>
                </enumeratedValue>
                <enumeratedValue>
                  <name>1</name>
                  <description>Slow slew rate is configured on the corresponding pin, if the pin is configured as a digital output.</description>
                  <value>#1</value>
                </enumeratedValue>
              </enumeratedValues>
            </field>
            <field>
              <name>PFE</name>
              <description>Passive Filter Enable</description>
              <bitOffset>4</bitOffset>
              <bitWidth>1</bitWidth>
              <access>read-only</access>
              <enumeratedValues>
                <enumeratedValue>
                  <name>0</name>
                  <description>Passive input filter is disabled on the corresponding pin.</description>
                  <value>#0</value>
                </enumeratedValue>
                <enumeratedValue>
                  <name>1</name>
                  <description>Passive input filter is enabled on the corresponding pin, if the pin is configured as a digital input. Refer to the device data sheet for filter characteristics.</description>
                  <value>#1</value>
                </enumeratedValue>
              </enumeratedValues>
            </field>
            <field>
              <name>DSE</name>
              <description>Drive Strength Enable</description>
              <bitOffset>6</bitOffset>
              <bitWidth>1</bitWidth>
              <access>read-only</access>
              <enumeratedValues>
                <enumeratedValue>
                  <name>0</name>
                  <description>Low drive strength is configured on the corresponding pin, if pin is configured as a digital output.</description>
                  <value>#0</value>
                </enumeratedValue>
                <enumeratedValue>
                  <name>1</name>
                  <description>High drive strength is configured on the corresponding pin, if pin is configured as a digital output.</description>
                  <value>#1</value>
                </enumeratedValue>
              </enumeratedValues>
            </field>
            <field>
              <name>MUX</name>
              <description>Pin Mux Control</description>
              <bitOffset>8</bitOffset>
              <bitWidth>3</bitWidth>
              <access>read-write</access>
              <enumeratedValues>
                <enumeratedValue>
                  <name>000</name>
                  <description>Pin disabled (analog).</description>
                  <value>#000</value>
                </enumeratedValue>
                <enumeratedValue>
                  <name>001</name>
                  <description>Alternative 1 (GPIO).</description>
                  <value>#001</value>
                </enumeratedValue>
                <enumeratedValue>
                  <name>010</name>
                  <description>Alternative 2 (chip-specific).</description>
                  <value>#010</value>
                </enumeratedValue>
                <enumeratedValue>
                  <name>011</name>
                  <description>Alternative 3 (chip-specific).</description>
                  <value>#011</value>
                </enumeratedValue>
                <enumeratedValue>
                  <name>100</name>
                  <description>Alternative 4 (chip-specific).</description>
                  <value>#100</value>
                </enumeratedValue>
                <enumeratedValue>
                  <name>101</name>
                  <description>Alternative 5 (chip-specific).</description>
                  <value>#101</value>
                </enumeratedValue>
                <enumeratedValue>
                  <name>110</name>
                  <description>Alternative 6 (chip-specific).</description>
                  <value>#110</value>
                </enumeratedValue>
                <enumeratedValue>
                  <name>111</name>
                  <description>Alternative 7 (chip-specific).</description>
                  <value>#111</value>
                </enumeratedValue>
              </enumeratedValues>
            </field>
            <field>
              <name>IRQC</name>
              <description>Interrupt Configuration</description>
              <bitOffset>16</bitOffset>
              <bitWidth>4</bitWidth>
              <access>read-write</access>
              <enumeratedValues>
                <enumeratedValue>
                  <name>0000</name>
                  <description>Interrupt/DMA request disabled.</description>
                  <value>#0000</value>
                </enumeratedValue>
                <enumeratedValue>
                  <name>0001</name>
                  <description>DMA request on rising edge.</description>
                  <value>#0001</value>
                </enumeratedValue>
                <enumeratedValue>
                  <name>0010</name>
                  <description>DMA request on falling edge.</description>
                  <value>#0010</value>
                </enumeratedValue>
                <enumeratedValue>
                  <name>0011</name>
                  <description>DMA request on either edge.</description>
                  <value>#0011</value>
                </enumeratedValue>
                <enumeratedValue>
                  <name>1000</name>
                  <description>Interrupt when logic 0.</description>
                  <value>#1000</value>
                </enumeratedValue>
                <enumeratedValue>
                  <name>1001</name>
                  <description>Interrupt on rising-edge.</description>
                  <value>#1001</value>
                </enumeratedValue>
                <enumeratedValue>
                  <name>1010</name>
                  <description>Interrupt on falling-edge.</description>
                  <value>#1010</value>
                </enumeratedValue>
                <enumeratedValue>
                  <name>1011</name>
                  <description>Interrupt on either edge.</description>
                  <value>#1011</value>
                </enumeratedValue>
                <enumeratedValue>
                  <name>1100</name>
                  <description>Interrupt when logic 1.</description>
                  <value>#1100</value>
                </enumeratedValue>
              </enumeratedValues>
            </field>
            <field>
              <name>ISF</name>
              <description>Interrupt Status Flag</description>
              <bitOffset>24</bitOffset>
              <bitWidth>1</bitWidth>
              <access>read-write</access>
              <enumeratedValues>
                <enumeratedValue>
                  <name>0</name>
                  <description>Configured interrupt is not detected.</description>
                  <value>#0</value>
                </enumeratedValue>
                <enumeratedValue>
                  <name>1</name>
                  <description>Configured interrupt is detected. If the pin is configured to generate a DMA request, then the corresponding flag will be cleared automatically at the completion of the requested DMA transfer. Otherwise, the flag remains set until a logic 1 is written to the flag. If the pin is configured for a level sensitive interrupt and the pin remains asserted, then the flag is set again immediately after it is cleared.</description>
                  <value>#1</value>
                </enumeratedValue>
              </enumeratedValues>
            </field>
          </fields>
        </register>
        <register>
          <name>PCR13</name>
          <description>Pin Control Register n</description>
          <addressOffset>0x34</addressOffset>
          <size>32</size>
          <access>read-write</access>
          <resetValue>0</resetValue>
          <resetMask>0xFFFFFFFF</resetMask>
          <fields>
            <field>
              <name>PS</name>
              <description>Pull Select</description>
              <bitOffset>0</bitOffset>
              <bitWidth>1</bitWidth>
              <access>read-only</access>
              <enumeratedValues>
                <enumeratedValue>
                  <name>0</name>
                  <description>Internal pulldown resistor is enabled on the corresponding pin, if the corresponding PE field is set.</description>
                  <value>#0</value>
                </enumeratedValue>
                <enumeratedValue>
                  <name>1</name>
                  <description>Internal pullup resistor is enabled on the corresponding pin, if the corresponding PE field is set.</description>
                  <value>#1</value>
                </enumeratedValue>
              </enumeratedValues>
            </field>
            <field>
              <name>PE</name>
              <description>Pull Enable</description>
              <bitOffset>1</bitOffset>
              <bitWidth>1</bitWidth>
              <access>read-only</access>
              <enumeratedValues>
                <enumeratedValue>
                  <name>0</name>
                  <description>Internal pullup or pulldown resistor is not enabled on the corresponding pin.</description>
                  <value>#0</value>
                </enumeratedValue>
                <enumeratedValue>
                  <name>1</name>
                  <description>Internal pullup or pulldown resistor is enabled on the corresponding pin, if the pin is configured as a digital input.</description>
                  <value>#1</value>
                </enumeratedValue>
              </enumeratedValues>
            </field>
            <field>
              <name>SRE</name>
              <description>Slew Rate Enable</description>
              <bitOffset>2</bitOffset>
              <bitWidth>1</bitWidth>
              <access>read-only</access>
              <enumeratedValues>
                <enumeratedValue>
                  <name>0</name>
                  <description>Fast slew rate is configured on the corresponding pin, if the pin is configured as a digital output.</description>
                  <value>#0</value>
                </enumeratedValue>
                <enumeratedValue>
                  <name>1</name>
                  <description>Slow slew rate is configured on the corresponding pin, if the pin is configured as a digital output.</description>
                  <value>#1</value>
                </enumeratedValue>
              </enumeratedValues>
            </field>
            <field>
              <name>PFE</name>
              <description>Passive Filter Enable</description>
              <bitOffset>4</bitOffset>
              <bitWidth>1</bitWidth>
              <access>read-only</access>
              <enumeratedValues>
                <enumeratedValue>
                  <name>0</name>
                  <description>Passive input filter is disabled on the corresponding pin.</description>
                  <value>#0</value>
                </enumeratedValue>
                <enumeratedValue>
                  <name>1</name>
                  <description>Passive input filter is enabled on the corresponding pin, if the pin is configured as a digital input. Refer to the device data sheet for filter characteristics.</description>
                  <value>#1</value>
                </enumeratedValue>
              </enumeratedValues>
            </field>
            <field>
              <name>DSE</name>
              <description>Drive Strength Enable</description>
              <bitOffset>6</bitOffset>
              <bitWidth>1</bitWidth>
              <access>read-only</access>
              <enumeratedValues>
                <enumeratedValue>
                  <name>0</name>
                  <description>Low drive strength is configured on the corresponding pin, if pin is configured as a digital output.</description>
                  <value>#0</value>
                </enumeratedValue>
                <enumeratedValue>
                  <name>1</name>
                  <description>High drive strength is configured on the corresponding pin, if pin is configured as a digital output.</description>
                  <value>#1</value>
                </enumeratedValue>
              </enumeratedValues>
            </field>
            <field>
              <name>MUX</name>
              <description>Pin Mux Control</description>
              <bitOffset>8</bitOffset>
              <bitWidth>3</bitWidth>
              <access>read-write</access>
              <enumeratedValues>
                <enumeratedValue>
                  <name>000</name>
                  <description>Pin disabled (analog).</description>
                  <value>#000</value>
                </enumeratedValue>
                <enumeratedValue>
                  <name>001</name>
                  <description>Alternative 1 (GPIO).</description>
                  <value>#001</value>
                </enumeratedValue>
                <enumeratedValue>
                  <name>010</name>
                  <description>Alternative 2 (chip-specific).</description>
                  <value>#010</value>
                </enumeratedValue>
                <enumeratedValue>
                  <name>011</name>
                  <description>Alternative 3 (chip-specific).</description>
                  <value>#011</value>
                </enumeratedValue>
                <enumeratedValue>
                  <name>100</name>
                  <description>Alternative 4 (chip-specific).</description>
                  <value>#100</value>
                </enumeratedValue>
                <enumeratedValue>
                  <name>101</name>
                  <description>Alternative 5 (chip-specific).</description>
                  <value>#101</value>
                </enumeratedValue>
                <enumeratedValue>
                  <name>110</name>
                  <description>Alternative 6 (chip-specific).</description>
                  <value>#110</value>
                </enumeratedValue>
                <enumeratedValue>
                  <name>111</name>
                  <description>Alternative 7 (chip-specific).</description>
                  <value>#111</value>
                </enumeratedValue>
              </enumeratedValues>
            </field>
            <field>
              <name>IRQC</name>
              <description>Interrupt Configuration</description>
              <bitOffset>16</bitOffset>
              <bitWidth>4</bitWidth>
              <access>read-write</access>
              <enumeratedValues>
                <enumeratedValue>
                  <name>0000</name>
                  <description>Interrupt/DMA request disabled.</description>
                  <value>#0000</value>
                </enumeratedValue>
                <enumeratedValue>
                  <name>0001</name>
                  <description>DMA request on rising edge.</description>
                  <value>#0001</value>
                </enumeratedValue>
                <enumeratedValue>
                  <name>0010</name>
                  <description>DMA request on falling edge.</description>
                  <value>#0010</value>
                </enumeratedValue>
                <enumeratedValue>
                  <name>0011</name>
                  <description>DMA request on either edge.</description>
                  <value>#0011</value>
                </enumeratedValue>
                <enumeratedValue>
                  <name>1000</name>
                  <description>Interrupt when logic 0.</description>
                  <value>#1000</value>
                </enumeratedValue>
                <enumeratedValue>
                  <name>1001</name>
                  <description>Interrupt on rising-edge.</description>
                  <value>#1001</value>
                </enumeratedValue>
                <enumeratedValue>
                  <name>1010</name>
                  <description>Interrupt on falling-edge.</description>
                  <value>#1010</value>
                </enumeratedValue>
                <enumeratedValue>
                  <name>1011</name>
                  <description>Interrupt on either edge.</description>
                  <value>#1011</value>
                </enumeratedValue>
                <enumeratedValue>
                  <name>1100</name>
                  <description>Interrupt when logic 1.</description>
                  <value>#1100</value>
                </enumeratedValue>
              </enumeratedValues>
            </field>
            <field>
              <name>ISF</name>
              <description>Interrupt Status Flag</description>
              <bitOffset>24</bitOffset>
              <bitWidth>1</bitWidth>
              <access>read-write</access>
              <enumeratedValues>
                <enumeratedValue>
                  <name>0</name>
                  <description>Configured interrupt is not detected.</description>
                  <value>#0</value>
                </enumeratedValue>
                <enumeratedValue>
                  <name>1</name>
                  <description>Configured interrupt is detected. If the pin is configured to generate a DMA request, then the corresponding flag will be cleared automatically at the completion of the requested DMA transfer. Otherwise, the flag remains set until a logic 1 is written to the flag. If the pin is configured for a level sensitive interrupt and the pin remains asserted, then the flag is set again immediately after it is cleared.</description>
                  <value>#1</value>
                </enumeratedValue>
              </enumeratedValues>
            </field>
          </fields>
        </register>
        <register>
          <name>PCR14</name>
          <description>Pin Control Register n</description>
          <addressOffset>0x38</addressOffset>
          <size>32</size>
          <access>read-write</access>
          <resetValue>0</resetValue>
          <resetMask>0xFFFFFFFF</resetMask>
          <fields>
            <field>
              <name>PS</name>
              <description>Pull Select</description>
              <bitOffset>0</bitOffset>
              <bitWidth>1</bitWidth>
              <access>read-only</access>
              <enumeratedValues>
                <enumeratedValue>
                  <name>0</name>
                  <description>Internal pulldown resistor is enabled on the corresponding pin, if the corresponding PE field is set.</description>
                  <value>#0</value>
                </enumeratedValue>
                <enumeratedValue>
                  <name>1</name>
                  <description>Internal pullup resistor is enabled on the corresponding pin, if the corresponding PE field is set.</description>
                  <value>#1</value>
                </enumeratedValue>
              </enumeratedValues>
            </field>
            <field>
              <name>PE</name>
              <description>Pull Enable</description>
              <bitOffset>1</bitOffset>
              <bitWidth>1</bitWidth>
              <access>read-only</access>
              <enumeratedValues>
                <enumeratedValue>
                  <name>0</name>
                  <description>Internal pullup or pulldown resistor is not enabled on the corresponding pin.</description>
                  <value>#0</value>
                </enumeratedValue>
                <enumeratedValue>
                  <name>1</name>
                  <description>Internal pullup or pulldown resistor is enabled on the corresponding pin, if the pin is configured as a digital input.</description>
                  <value>#1</value>
                </enumeratedValue>
              </enumeratedValues>
            </field>
            <field>
              <name>SRE</name>
              <description>Slew Rate Enable</description>
              <bitOffset>2</bitOffset>
              <bitWidth>1</bitWidth>
              <access>read-only</access>
              <enumeratedValues>
                <enumeratedValue>
                  <name>0</name>
                  <description>Fast slew rate is configured on the corresponding pin, if the pin is configured as a digital output.</description>
                  <value>#0</value>
                </enumeratedValue>
                <enumeratedValue>
                  <name>1</name>
                  <description>Slow slew rate is configured on the corresponding pin, if the pin is configured as a digital output.</description>
                  <value>#1</value>
                </enumeratedValue>
              </enumeratedValues>
            </field>
            <field>
              <name>PFE</name>
              <description>Passive Filter Enable</description>
              <bitOffset>4</bitOffset>
              <bitWidth>1</bitWidth>
              <access>read-only</access>
              <enumeratedValues>
                <enumeratedValue>
                  <name>0</name>
                  <description>Passive input filter is disabled on the corresponding pin.</description>
                  <value>#0</value>
                </enumeratedValue>
                <enumeratedValue>
                  <name>1</name>
                  <description>Passive input filter is enabled on the corresponding pin, if the pin is configured as a digital input. Refer to the device data sheet for filter characteristics.</description>
                  <value>#1</value>
                </enumeratedValue>
              </enumeratedValues>
            </field>
            <field>
              <name>DSE</name>
              <description>Drive Strength Enable</description>
              <bitOffset>6</bitOffset>
              <bitWidth>1</bitWidth>
              <access>read-only</access>
              <enumeratedValues>
                <enumeratedValue>
                  <name>0</name>
                  <description>Low drive strength is configured on the corresponding pin, if pin is configured as a digital output.</description>
                  <value>#0</value>
                </enumeratedValue>
                <enumeratedValue>
                  <name>1</name>
                  <description>High drive strength is configured on the corresponding pin, if pin is configured as a digital output.</description>
                  <value>#1</value>
                </enumeratedValue>
              </enumeratedValues>
            </field>
            <field>
              <name>MUX</name>
              <description>Pin Mux Control</description>
              <bitOffset>8</bitOffset>
              <bitWidth>3</bitWidth>
              <access>read-write</access>
              <enumeratedValues>
                <enumeratedValue>
                  <name>000</name>
                  <description>Pin disabled (analog).</description>
                  <value>#000</value>
                </enumeratedValue>
                <enumeratedValue>
                  <name>001</name>
                  <description>Alternative 1 (GPIO).</description>
                  <value>#001</value>
                </enumeratedValue>
                <enumeratedValue>
                  <name>010</name>
                  <description>Alternative 2 (chip-specific).</description>
                  <value>#010</value>
                </enumeratedValue>
                <enumeratedValue>
                  <name>011</name>
                  <description>Alternative 3 (chip-specific).</description>
                  <value>#011</value>
                </enumeratedValue>
                <enumeratedValue>
                  <name>100</name>
                  <description>Alternative 4 (chip-specific).</description>
                  <value>#100</value>
                </enumeratedValue>
                <enumeratedValue>
                  <name>101</name>
                  <description>Alternative 5 (chip-specific).</description>
                  <value>#101</value>
                </enumeratedValue>
                <enumeratedValue>
                  <name>110</name>
                  <description>Alternative 6 (chip-specific).</description>
                  <value>#110</value>
                </enumeratedValue>
                <enumeratedValue>
                  <name>111</name>
                  <description>Alternative 7 (chip-specific).</description>
                  <value>#111</value>
                </enumeratedValue>
              </enumeratedValues>
            </field>
            <field>
              <name>IRQC</name>
              <description>Interrupt Configuration</description>
              <bitOffset>16</bitOffset>
              <bitWidth>4</bitWidth>
              <access>read-write</access>
              <enumeratedValues>
                <enumeratedValue>
                  <name>0000</name>
                  <description>Interrupt/DMA request disabled.</description>
                  <value>#0000</value>
                </enumeratedValue>
                <enumeratedValue>
                  <name>0001</name>
                  <description>DMA request on rising edge.</description>
                  <value>#0001</value>
                </enumeratedValue>
                <enumeratedValue>
                  <name>0010</name>
                  <description>DMA request on falling edge.</description>
                  <value>#0010</value>
                </enumeratedValue>
                <enumeratedValue>
                  <name>0011</name>
                  <description>DMA request on either edge.</description>
                  <value>#0011</value>
                </enumeratedValue>
                <enumeratedValue>
                  <name>1000</name>
                  <description>Interrupt when logic 0.</description>
                  <value>#1000</value>
                </enumeratedValue>
                <enumeratedValue>
                  <name>1001</name>
                  <description>Interrupt on rising-edge.</description>
                  <value>#1001</value>
                </enumeratedValue>
                <enumeratedValue>
                  <name>1010</name>
                  <description>Interrupt on falling-edge.</description>
                  <value>#1010</value>
                </enumeratedValue>
                <enumeratedValue>
                  <name>1011</name>
                  <description>Interrupt on either edge.</description>
                  <value>#1011</value>
                </enumeratedValue>
                <enumeratedValue>
                  <name>1100</name>
                  <description>Interrupt when logic 1.</description>
                  <value>#1100</value>
                </enumeratedValue>
              </enumeratedValues>
            </field>
            <field>
              <name>ISF</name>
              <description>Interrupt Status Flag</description>
              <bitOffset>24</bitOffset>
              <bitWidth>1</bitWidth>
              <access>read-write</access>
              <enumeratedValues>
                <enumeratedValue>
                  <name>0</name>
                  <description>Configured interrupt is not detected.</description>
                  <value>#0</value>
                </enumeratedValue>
                <enumeratedValue>
                  <name>1</name>
                  <description>Configured interrupt is detected. If the pin is configured to generate a DMA request, then the corresponding flag will be cleared automatically at the completion of the requested DMA transfer. Otherwise, the flag remains set until a logic 1 is written to the flag. If the pin is configured for a level sensitive interrupt and the pin remains asserted, then the flag is set again immediately after it is cleared.</description>
                  <value>#1</value>
                </enumeratedValue>
              </enumeratedValues>
            </field>
          </fields>
        </register>
        <register>
          <name>PCR15</name>
          <description>Pin Control Register n</description>
          <addressOffset>0x3C</addressOffset>
          <size>32</size>
          <access>read-write</access>
          <resetValue>0</resetValue>
          <resetMask>0xFFFFFFFF</resetMask>
          <fields>
            <field>
              <name>PS</name>
              <description>Pull Select</description>
              <bitOffset>0</bitOffset>
              <bitWidth>1</bitWidth>
              <access>read-only</access>
              <enumeratedValues>
                <enumeratedValue>
                  <name>0</name>
                  <description>Internal pulldown resistor is enabled on the corresponding pin, if the corresponding PE field is set.</description>
                  <value>#0</value>
                </enumeratedValue>
                <enumeratedValue>
                  <name>1</name>
                  <description>Internal pullup resistor is enabled on the corresponding pin, if the corresponding PE field is set.</description>
                  <value>#1</value>
                </enumeratedValue>
              </enumeratedValues>
            </field>
            <field>
              <name>PE</name>
              <description>Pull Enable</description>
              <bitOffset>1</bitOffset>
              <bitWidth>1</bitWidth>
              <access>read-only</access>
              <enumeratedValues>
                <enumeratedValue>
                  <name>0</name>
                  <description>Internal pullup or pulldown resistor is not enabled on the corresponding pin.</description>
                  <value>#0</value>
                </enumeratedValue>
                <enumeratedValue>
                  <name>1</name>
                  <description>Internal pullup or pulldown resistor is enabled on the corresponding pin, if the pin is configured as a digital input.</description>
                  <value>#1</value>
                </enumeratedValue>
              </enumeratedValues>
            </field>
            <field>
              <name>SRE</name>
              <description>Slew Rate Enable</description>
              <bitOffset>2</bitOffset>
              <bitWidth>1</bitWidth>
              <access>read-only</access>
              <enumeratedValues>
                <enumeratedValue>
                  <name>0</name>
                  <description>Fast slew rate is configured on the corresponding pin, if the pin is configured as a digital output.</description>
                  <value>#0</value>
                </enumeratedValue>
                <enumeratedValue>
                  <name>1</name>
                  <description>Slow slew rate is configured on the corresponding pin, if the pin is configured as a digital output.</description>
                  <value>#1</value>
                </enumeratedValue>
              </enumeratedValues>
            </field>
            <field>
              <name>PFE</name>
              <description>Passive Filter Enable</description>
              <bitOffset>4</bitOffset>
              <bitWidth>1</bitWidth>
              <access>read-only</access>
              <enumeratedValues>
                <enumeratedValue>
                  <name>0</name>
                  <description>Passive input filter is disabled on the corresponding pin.</description>
                  <value>#0</value>
                </enumeratedValue>
                <enumeratedValue>
                  <name>1</name>
                  <description>Passive input filter is enabled on the corresponding pin, if the pin is configured as a digital input. Refer to the device data sheet for filter characteristics.</description>
                  <value>#1</value>
                </enumeratedValue>
              </enumeratedValues>
            </field>
            <field>
              <name>DSE</name>
              <description>Drive Strength Enable</description>
              <bitOffset>6</bitOffset>
              <bitWidth>1</bitWidth>
              <access>read-only</access>
              <enumeratedValues>
                <enumeratedValue>
                  <name>0</name>
                  <description>Low drive strength is configured on the corresponding pin, if pin is configured as a digital output.</description>
                  <value>#0</value>
                </enumeratedValue>
                <enumeratedValue>
                  <name>1</name>
                  <description>High drive strength is configured on the corresponding pin, if pin is configured as a digital output.</description>
                  <value>#1</value>
                </enumeratedValue>
              </enumeratedValues>
            </field>
            <field>
              <name>MUX</name>
              <description>Pin Mux Control</description>
              <bitOffset>8</bitOffset>
              <bitWidth>3</bitWidth>
              <access>read-write</access>
              <enumeratedValues>
                <enumeratedValue>
                  <name>000</name>
                  <description>Pin disabled (analog).</description>
                  <value>#000</value>
                </enumeratedValue>
                <enumeratedValue>
                  <name>001</name>
                  <description>Alternative 1 (GPIO).</description>
                  <value>#001</value>
                </enumeratedValue>
                <enumeratedValue>
                  <name>010</name>
                  <description>Alternative 2 (chip-specific).</description>
                  <value>#010</value>
                </enumeratedValue>
                <enumeratedValue>
                  <name>011</name>
                  <description>Alternative 3 (chip-specific).</description>
                  <value>#011</value>
                </enumeratedValue>
                <enumeratedValue>
                  <name>100</name>
                  <description>Alternative 4 (chip-specific).</description>
                  <value>#100</value>
                </enumeratedValue>
                <enumeratedValue>
                  <name>101</name>
                  <description>Alternative 5 (chip-specific).</description>
                  <value>#101</value>
                </enumeratedValue>
                <enumeratedValue>
                  <name>110</name>
                  <description>Alternative 6 (chip-specific).</description>
                  <value>#110</value>
                </enumeratedValue>
                <enumeratedValue>
                  <name>111</name>
                  <description>Alternative 7 (chip-specific).</description>
                  <value>#111</value>
                </enumeratedValue>
              </enumeratedValues>
            </field>
            <field>
              <name>IRQC</name>
              <description>Interrupt Configuration</description>
              <bitOffset>16</bitOffset>
              <bitWidth>4</bitWidth>
              <access>read-write</access>
              <enumeratedValues>
                <enumeratedValue>
                  <name>0000</name>
                  <description>Interrupt/DMA request disabled.</description>
                  <value>#0000</value>
                </enumeratedValue>
                <enumeratedValue>
                  <name>0001</name>
                  <description>DMA request on rising edge.</description>
                  <value>#0001</value>
                </enumeratedValue>
                <enumeratedValue>
                  <name>0010</name>
                  <description>DMA request on falling edge.</description>
                  <value>#0010</value>
                </enumeratedValue>
                <enumeratedValue>
                  <name>0011</name>
                  <description>DMA request on either edge.</description>
                  <value>#0011</value>
                </enumeratedValue>
                <enumeratedValue>
                  <name>1000</name>
                  <description>Interrupt when logic 0.</description>
                  <value>#1000</value>
                </enumeratedValue>
                <enumeratedValue>
                  <name>1001</name>
                  <description>Interrupt on rising-edge.</description>
                  <value>#1001</value>
                </enumeratedValue>
                <enumeratedValue>
                  <name>1010</name>
                  <description>Interrupt on falling-edge.</description>
                  <value>#1010</value>
                </enumeratedValue>
                <enumeratedValue>
                  <name>1011</name>
                  <description>Interrupt on either edge.</description>
                  <value>#1011</value>
                </enumeratedValue>
                <enumeratedValue>
                  <name>1100</name>
                  <description>Interrupt when logic 1.</description>
                  <value>#1100</value>
                </enumeratedValue>
              </enumeratedValues>
            </field>
            <field>
              <name>ISF</name>
              <description>Interrupt Status Flag</description>
              <bitOffset>24</bitOffset>
              <bitWidth>1</bitWidth>
              <access>read-write</access>
              <enumeratedValues>
                <enumeratedValue>
                  <name>0</name>
                  <description>Configured interrupt is not detected.</description>
                  <value>#0</value>
                </enumeratedValue>
                <enumeratedValue>
                  <name>1</name>
                  <description>Configured interrupt is detected. If the pin is configured to generate a DMA request, then the corresponding flag will be cleared automatically at the completion of the requested DMA transfer. Otherwise, the flag remains set until a logic 1 is written to the flag. If the pin is configured for a level sensitive interrupt and the pin remains asserted, then the flag is set again immediately after it is cleared.</description>
                  <value>#1</value>
                </enumeratedValue>
              </enumeratedValues>
            </field>
          </fields>
        </register>
        <register>
          <name>PCR16</name>
          <description>Pin Control Register n</description>
          <addressOffset>0x40</addressOffset>
          <size>32</size>
          <access>read-write</access>
          <resetValue>0</resetValue>
          <resetMask>0xFFFFFFFF</resetMask>
          <fields>
            <field>
              <name>PS</name>
              <description>Pull Select</description>
              <bitOffset>0</bitOffset>
              <bitWidth>1</bitWidth>
              <access>read-only</access>
              <enumeratedValues>
                <enumeratedValue>
                  <name>0</name>
                  <description>Internal pulldown resistor is enabled on the corresponding pin, if the corresponding PE field is set.</description>
                  <value>#0</value>
                </enumeratedValue>
                <enumeratedValue>
                  <name>1</name>
                  <description>Internal pullup resistor is enabled on the corresponding pin, if the corresponding PE field is set.</description>
                  <value>#1</value>
                </enumeratedValue>
              </enumeratedValues>
            </field>
            <field>
              <name>PE</name>
              <description>Pull Enable</description>
              <bitOffset>1</bitOffset>
              <bitWidth>1</bitWidth>
              <access>read-only</access>
              <enumeratedValues>
                <enumeratedValue>
                  <name>0</name>
                  <description>Internal pullup or pulldown resistor is not enabled on the corresponding pin.</description>
                  <value>#0</value>
                </enumeratedValue>
                <enumeratedValue>
                  <name>1</name>
                  <description>Internal pullup or pulldown resistor is enabled on the corresponding pin, if the pin is configured as a digital input.</description>
                  <value>#1</value>
                </enumeratedValue>
              </enumeratedValues>
            </field>
            <field>
              <name>SRE</name>
              <description>Slew Rate Enable</description>
              <bitOffset>2</bitOffset>
              <bitWidth>1</bitWidth>
              <access>read-only</access>
              <enumeratedValues>
                <enumeratedValue>
                  <name>0</name>
                  <description>Fast slew rate is configured on the corresponding pin, if the pin is configured as a digital output.</description>
                  <value>#0</value>
                </enumeratedValue>
                <enumeratedValue>
                  <name>1</name>
                  <description>Slow slew rate is configured on the corresponding pin, if the pin is configured as a digital output.</description>
                  <value>#1</value>
                </enumeratedValue>
              </enumeratedValues>
            </field>
            <field>
              <name>PFE</name>
              <description>Passive Filter Enable</description>
              <bitOffset>4</bitOffset>
              <bitWidth>1</bitWidth>
              <access>read-only</access>
              <enumeratedValues>
                <enumeratedValue>
                  <name>0</name>
                  <description>Passive input filter is disabled on the corresponding pin.</description>
                  <value>#0</value>
                </enumeratedValue>
                <enumeratedValue>
                  <name>1</name>
                  <description>Passive input filter is enabled on the corresponding pin, if the pin is configured as a digital input. Refer to the device data sheet for filter characteristics.</description>
                  <value>#1</value>
                </enumeratedValue>
              </enumeratedValues>
            </field>
            <field>
              <name>DSE</name>
              <description>Drive Strength Enable</description>
              <bitOffset>6</bitOffset>
              <bitWidth>1</bitWidth>
              <access>read-only</access>
              <enumeratedValues>
                <enumeratedValue>
                  <name>0</name>
                  <description>Low drive strength is configured on the corresponding pin, if pin is configured as a digital output.</description>
                  <value>#0</value>
                </enumeratedValue>
                <enumeratedValue>
                  <name>1</name>
                  <description>High drive strength is configured on the corresponding pin, if pin is configured as a digital output.</description>
                  <value>#1</value>
                </enumeratedValue>
              </enumeratedValues>
            </field>
            <field>
              <name>MUX</name>
              <description>Pin Mux Control</description>
              <bitOffset>8</bitOffset>
              <bitWidth>3</bitWidth>
              <access>read-write</access>
              <enumeratedValues>
                <enumeratedValue>
                  <name>000</name>
                  <description>Pin disabled (analog).</description>
                  <value>#000</value>
                </enumeratedValue>
                <enumeratedValue>
                  <name>001</name>
                  <description>Alternative 1 (GPIO).</description>
                  <value>#001</value>
                </enumeratedValue>
                <enumeratedValue>
                  <name>010</name>
                  <description>Alternative 2 (chip-specific).</description>
                  <value>#010</value>
                </enumeratedValue>
                <enumeratedValue>
                  <name>011</name>
                  <description>Alternative 3 (chip-specific).</description>
                  <value>#011</value>
                </enumeratedValue>
                <enumeratedValue>
                  <name>100</name>
                  <description>Alternative 4 (chip-specific).</description>
                  <value>#100</value>
                </enumeratedValue>
                <enumeratedValue>
                  <name>101</name>
                  <description>Alternative 5 (chip-specific).</description>
                  <value>#101</value>
                </enumeratedValue>
                <enumeratedValue>
                  <name>110</name>
                  <description>Alternative 6 (chip-specific).</description>
                  <value>#110</value>
                </enumeratedValue>
                <enumeratedValue>
                  <name>111</name>
                  <description>Alternative 7 (chip-specific).</description>
                  <value>#111</value>
                </enumeratedValue>
              </enumeratedValues>
            </field>
            <field>
              <name>IRQC</name>
              <description>Interrupt Configuration</description>
              <bitOffset>16</bitOffset>
              <bitWidth>4</bitWidth>
              <access>read-write</access>
              <enumeratedValues>
                <enumeratedValue>
                  <name>0000</name>
                  <description>Interrupt/DMA request disabled.</description>
                  <value>#0000</value>
                </enumeratedValue>
                <enumeratedValue>
                  <name>0001</name>
                  <description>DMA request on rising edge.</description>
                  <value>#0001</value>
                </enumeratedValue>
                <enumeratedValue>
                  <name>0010</name>
                  <description>DMA request on falling edge.</description>
                  <value>#0010</value>
                </enumeratedValue>
                <enumeratedValue>
                  <name>0011</name>
                  <description>DMA request on either edge.</description>
                  <value>#0011</value>
                </enumeratedValue>
                <enumeratedValue>
                  <name>1000</name>
                  <description>Interrupt when logic 0.</description>
                  <value>#1000</value>
                </enumeratedValue>
                <enumeratedValue>
                  <name>1001</name>
                  <description>Interrupt on rising-edge.</description>
                  <value>#1001</value>
                </enumeratedValue>
                <enumeratedValue>
                  <name>1010</name>
                  <description>Interrupt on falling-edge.</description>
                  <value>#1010</value>
                </enumeratedValue>
                <enumeratedValue>
                  <name>1011</name>
                  <description>Interrupt on either edge.</description>
                  <value>#1011</value>
                </enumeratedValue>
                <enumeratedValue>
                  <name>1100</name>
                  <description>Interrupt when logic 1.</description>
                  <value>#1100</value>
                </enumeratedValue>
              </enumeratedValues>
            </field>
            <field>
              <name>ISF</name>
              <description>Interrupt Status Flag</description>
              <bitOffset>24</bitOffset>
              <bitWidth>1</bitWidth>
              <access>read-write</access>
              <enumeratedValues>
                <enumeratedValue>
                  <name>0</name>
                  <description>Configured interrupt is not detected.</description>
                  <value>#0</value>
                </enumeratedValue>
                <enumeratedValue>
                  <name>1</name>
                  <description>Configured interrupt is detected. If the pin is configured to generate a DMA request, then the corresponding flag will be cleared automatically at the completion of the requested DMA transfer. Otherwise, the flag remains set until a logic 1 is written to the flag. If the pin is configured for a level sensitive interrupt and the pin remains asserted, then the flag is set again immediately after it is cleared.</description>
                  <value>#1</value>
                </enumeratedValue>
              </enumeratedValues>
            </field>
          </fields>
        </register>
        <register>
          <name>PCR17</name>
          <description>Pin Control Register n</description>
          <addressOffset>0x44</addressOffset>
          <size>32</size>
          <access>read-write</access>
          <resetValue>0</resetValue>
          <resetMask>0xFFFFFFFF</resetMask>
          <fields>
            <field>
              <name>PS</name>
              <description>Pull Select</description>
              <bitOffset>0</bitOffset>
              <bitWidth>1</bitWidth>
              <access>read-only</access>
              <enumeratedValues>
                <enumeratedValue>
                  <name>0</name>
                  <description>Internal pulldown resistor is enabled on the corresponding pin, if the corresponding PE field is set.</description>
                  <value>#0</value>
                </enumeratedValue>
                <enumeratedValue>
                  <name>1</name>
                  <description>Internal pullup resistor is enabled on the corresponding pin, if the corresponding PE field is set.</description>
                  <value>#1</value>
                </enumeratedValue>
              </enumeratedValues>
            </field>
            <field>
              <name>PE</name>
              <description>Pull Enable</description>
              <bitOffset>1</bitOffset>
              <bitWidth>1</bitWidth>
              <access>read-only</access>
              <enumeratedValues>
                <enumeratedValue>
                  <name>0</name>
                  <description>Internal pullup or pulldown resistor is not enabled on the corresponding pin.</description>
                  <value>#0</value>
                </enumeratedValue>
                <enumeratedValue>
                  <name>1</name>
                  <description>Internal pullup or pulldown resistor is enabled on the corresponding pin, if the pin is configured as a digital input.</description>
                  <value>#1</value>
                </enumeratedValue>
              </enumeratedValues>
            </field>
            <field>
              <name>SRE</name>
              <description>Slew Rate Enable</description>
              <bitOffset>2</bitOffset>
              <bitWidth>1</bitWidth>
              <access>read-only</access>
              <enumeratedValues>
                <enumeratedValue>
                  <name>0</name>
                  <description>Fast slew rate is configured on the corresponding pin, if the pin is configured as a digital output.</description>
                  <value>#0</value>
                </enumeratedValue>
                <enumeratedValue>
                  <name>1</name>
                  <description>Slow slew rate is configured on the corresponding pin, if the pin is configured as a digital output.</description>
                  <value>#1</value>
                </enumeratedValue>
              </enumeratedValues>
            </field>
            <field>
              <name>PFE</name>
              <description>Passive Filter Enable</description>
              <bitOffset>4</bitOffset>
              <bitWidth>1</bitWidth>
              <access>read-only</access>
              <enumeratedValues>
                <enumeratedValue>
                  <name>0</name>
                  <description>Passive input filter is disabled on the corresponding pin.</description>
                  <value>#0</value>
                </enumeratedValue>
                <enumeratedValue>
                  <name>1</name>
                  <description>Passive input filter is enabled on the corresponding pin, if the pin is configured as a digital input. Refer to the device data sheet for filter characteristics.</description>
                  <value>#1</value>
                </enumeratedValue>
              </enumeratedValues>
            </field>
            <field>
              <name>DSE</name>
              <description>Drive Strength Enable</description>
              <bitOffset>6</bitOffset>
              <bitWidth>1</bitWidth>
              <access>read-only</access>
              <enumeratedValues>
                <enumeratedValue>
                  <name>0</name>
                  <description>Low drive strength is configured on the corresponding pin, if pin is configured as a digital output.</description>
                  <value>#0</value>
                </enumeratedValue>
                <enumeratedValue>
                  <name>1</name>
                  <description>High drive strength is configured on the corresponding pin, if pin is configured as a digital output.</description>
                  <value>#1</value>
                </enumeratedValue>
              </enumeratedValues>
            </field>
            <field>
              <name>MUX</name>
              <description>Pin Mux Control</description>
              <bitOffset>8</bitOffset>
              <bitWidth>3</bitWidth>
              <access>read-write</access>
              <enumeratedValues>
                <enumeratedValue>
                  <name>000</name>
                  <description>Pin disabled (analog).</description>
                  <value>#000</value>
                </enumeratedValue>
                <enumeratedValue>
                  <name>001</name>
                  <description>Alternative 1 (GPIO).</description>
                  <value>#001</value>
                </enumeratedValue>
                <enumeratedValue>
                  <name>010</name>
                  <description>Alternative 2 (chip-specific).</description>
                  <value>#010</value>
                </enumeratedValue>
                <enumeratedValue>
                  <name>011</name>
                  <description>Alternative 3 (chip-specific).</description>
                  <value>#011</value>
                </enumeratedValue>
                <enumeratedValue>
                  <name>100</name>
                  <description>Alternative 4 (chip-specific).</description>
                  <value>#100</value>
                </enumeratedValue>
                <enumeratedValue>
                  <name>101</name>
                  <description>Alternative 5 (chip-specific).</description>
                  <value>#101</value>
                </enumeratedValue>
                <enumeratedValue>
                  <name>110</name>
                  <description>Alternative 6 (chip-specific).</description>
                  <value>#110</value>
                </enumeratedValue>
                <enumeratedValue>
                  <name>111</name>
                  <description>Alternative 7 (chip-specific).</description>
                  <value>#111</value>
                </enumeratedValue>
              </enumeratedValues>
            </field>
            <field>
              <name>IRQC</name>
              <description>Interrupt Configuration</description>
              <bitOffset>16</bitOffset>
              <bitWidth>4</bitWidth>
              <access>read-write</access>
              <enumeratedValues>
                <enumeratedValue>
                  <name>0000</name>
                  <description>Interrupt/DMA request disabled.</description>
                  <value>#0000</value>
                </enumeratedValue>
                <enumeratedValue>
                  <name>0001</name>
                  <description>DMA request on rising edge.</description>
                  <value>#0001</value>
                </enumeratedValue>
                <enumeratedValue>
                  <name>0010</name>
                  <description>DMA request on falling edge.</description>
                  <value>#0010</value>
                </enumeratedValue>
                <enumeratedValue>
                  <name>0011</name>
                  <description>DMA request on either edge.</description>
                  <value>#0011</value>
                </enumeratedValue>
                <enumeratedValue>
                  <name>1000</name>
                  <description>Interrupt when logic 0.</description>
                  <value>#1000</value>
                </enumeratedValue>
                <enumeratedValue>
                  <name>1001</name>
                  <description>Interrupt on rising-edge.</description>
                  <value>#1001</value>
                </enumeratedValue>
                <enumeratedValue>
                  <name>1010</name>
                  <description>Interrupt on falling-edge.</description>
                  <value>#1010</value>
                </enumeratedValue>
                <enumeratedValue>
                  <name>1011</name>
                  <description>Interrupt on either edge.</description>
                  <value>#1011</value>
                </enumeratedValue>
                <enumeratedValue>
                  <name>1100</name>
                  <description>Interrupt when logic 1.</description>
                  <value>#1100</value>
                </enumeratedValue>
              </enumeratedValues>
            </field>
            <field>
              <name>ISF</name>
              <description>Interrupt Status Flag</description>
              <bitOffset>24</bitOffset>
              <bitWidth>1</bitWidth>
              <access>read-write</access>
              <enumeratedValues>
                <enumeratedValue>
                  <name>0</name>
                  <description>Configured interrupt is not detected.</description>
                  <value>#0</value>
                </enumeratedValue>
                <enumeratedValue>
                  <name>1</name>
                  <description>Configured interrupt is detected. If the pin is configured to generate a DMA request, then the corresponding flag will be cleared automatically at the completion of the requested DMA transfer. Otherwise, the flag remains set until a logic 1 is written to the flag. If the pin is configured for a level sensitive interrupt and the pin remains asserted, then the flag is set again immediately after it is cleared.</description>
                  <value>#1</value>
                </enumeratedValue>
              </enumeratedValues>
            </field>
          </fields>
        </register>
        <register>
          <name>PCR18</name>
          <description>Pin Control Register n</description>
          <addressOffset>0x48</addressOffset>
          <size>32</size>
          <access>read-write</access>
          <resetValue>0</resetValue>
          <resetMask>0xFFFFFFFF</resetMask>
          <fields>
            <field>
              <name>PS</name>
              <description>Pull Select</description>
              <bitOffset>0</bitOffset>
              <bitWidth>1</bitWidth>
              <access>read-only</access>
              <enumeratedValues>
                <enumeratedValue>
                  <name>0</name>
                  <description>Internal pulldown resistor is enabled on the corresponding pin, if the corresponding PE field is set.</description>
                  <value>#0</value>
                </enumeratedValue>
                <enumeratedValue>
                  <name>1</name>
                  <description>Internal pullup resistor is enabled on the corresponding pin, if the corresponding PE field is set.</description>
                  <value>#1</value>
                </enumeratedValue>
              </enumeratedValues>
            </field>
            <field>
              <name>PE</name>
              <description>Pull Enable</description>
              <bitOffset>1</bitOffset>
              <bitWidth>1</bitWidth>
              <access>read-only</access>
              <enumeratedValues>
                <enumeratedValue>
                  <name>0</name>
                  <description>Internal pullup or pulldown resistor is not enabled on the corresponding pin.</description>
                  <value>#0</value>
                </enumeratedValue>
                <enumeratedValue>
                  <name>1</name>
                  <description>Internal pullup or pulldown resistor is enabled on the corresponding pin, if the pin is configured as a digital input.</description>
                  <value>#1</value>
                </enumeratedValue>
              </enumeratedValues>
            </field>
            <field>
              <name>SRE</name>
              <description>Slew Rate Enable</description>
              <bitOffset>2</bitOffset>
              <bitWidth>1</bitWidth>
              <access>read-only</access>
              <enumeratedValues>
                <enumeratedValue>
                  <name>0</name>
                  <description>Fast slew rate is configured on the corresponding pin, if the pin is configured as a digital output.</description>
                  <value>#0</value>
                </enumeratedValue>
                <enumeratedValue>
                  <name>1</name>
                  <description>Slow slew rate is configured on the corresponding pin, if the pin is configured as a digital output.</description>
                  <value>#1</value>
                </enumeratedValue>
              </enumeratedValues>
            </field>
            <field>
              <name>PFE</name>
              <description>Passive Filter Enable</description>
              <bitOffset>4</bitOffset>
              <bitWidth>1</bitWidth>
              <access>read-only</access>
              <enumeratedValues>
                <enumeratedValue>
                  <name>0</name>
                  <description>Passive input filter is disabled on the corresponding pin.</description>
                  <value>#0</value>
                </enumeratedValue>
                <enumeratedValue>
                  <name>1</name>
                  <description>Passive input filter is enabled on the corresponding pin, if the pin is configured as a digital input. Refer to the device data sheet for filter characteristics.</description>
                  <value>#1</value>
                </enumeratedValue>
              </enumeratedValues>
            </field>
            <field>
              <name>DSE</name>
              <description>Drive Strength Enable</description>
              <bitOffset>6</bitOffset>
              <bitWidth>1</bitWidth>
              <access>read-only</access>
              <enumeratedValues>
                <enumeratedValue>
                  <name>0</name>
                  <description>Low drive strength is configured on the corresponding pin, if pin is configured as a digital output.</description>
                  <value>#0</value>
                </enumeratedValue>
                <enumeratedValue>
                  <name>1</name>
                  <description>High drive strength is configured on the corresponding pin, if pin is configured as a digital output.</description>
                  <value>#1</value>
                </enumeratedValue>
              </enumeratedValues>
            </field>
            <field>
              <name>MUX</name>
              <description>Pin Mux Control</description>
              <bitOffset>8</bitOffset>
              <bitWidth>3</bitWidth>
              <access>read-write</access>
              <enumeratedValues>
                <enumeratedValue>
                  <name>000</name>
                  <description>Pin disabled (analog).</description>
                  <value>#000</value>
                </enumeratedValue>
                <enumeratedValue>
                  <name>001</name>
                  <description>Alternative 1 (GPIO).</description>
                  <value>#001</value>
                </enumeratedValue>
                <enumeratedValue>
                  <name>010</name>
                  <description>Alternative 2 (chip-specific).</description>
                  <value>#010</value>
                </enumeratedValue>
                <enumeratedValue>
                  <name>011</name>
                  <description>Alternative 3 (chip-specific).</description>
                  <value>#011</value>
                </enumeratedValue>
                <enumeratedValue>
                  <name>100</name>
                  <description>Alternative 4 (chip-specific).</description>
                  <value>#100</value>
                </enumeratedValue>
                <enumeratedValue>
                  <name>101</name>
                  <description>Alternative 5 (chip-specific).</description>
                  <value>#101</value>
                </enumeratedValue>
                <enumeratedValue>
                  <name>110</name>
                  <description>Alternative 6 (chip-specific).</description>
                  <value>#110</value>
                </enumeratedValue>
                <enumeratedValue>
                  <name>111</name>
                  <description>Alternative 7 (chip-specific).</description>
                  <value>#111</value>
                </enumeratedValue>
              </enumeratedValues>
            </field>
            <field>
              <name>IRQC</name>
              <description>Interrupt Configuration</description>
              <bitOffset>16</bitOffset>
              <bitWidth>4</bitWidth>
              <access>read-write</access>
              <enumeratedValues>
                <enumeratedValue>
                  <name>0000</name>
                  <description>Interrupt/DMA request disabled.</description>
                  <value>#0000</value>
                </enumeratedValue>
                <enumeratedValue>
                  <name>0001</name>
                  <description>DMA request on rising edge.</description>
                  <value>#0001</value>
                </enumeratedValue>
                <enumeratedValue>
                  <name>0010</name>
                  <description>DMA request on falling edge.</description>
                  <value>#0010</value>
                </enumeratedValue>
                <enumeratedValue>
                  <name>0011</name>
                  <description>DMA request on either edge.</description>
                  <value>#0011</value>
                </enumeratedValue>
                <enumeratedValue>
                  <name>1000</name>
                  <description>Interrupt when logic 0.</description>
                  <value>#1000</value>
                </enumeratedValue>
                <enumeratedValue>
                  <name>1001</name>
                  <description>Interrupt on rising-edge.</description>
                  <value>#1001</value>
                </enumeratedValue>
                <enumeratedValue>
                  <name>1010</name>
                  <description>Interrupt on falling-edge.</description>
                  <value>#1010</value>
                </enumeratedValue>
                <enumeratedValue>
                  <name>1011</name>
                  <description>Interrupt on either edge.</description>
                  <value>#1011</value>
                </enumeratedValue>
                <enumeratedValue>
                  <name>1100</name>
                  <description>Interrupt when logic 1.</description>
                  <value>#1100</value>
                </enumeratedValue>
              </enumeratedValues>
            </field>
            <field>
              <name>ISF</name>
              <description>Interrupt Status Flag</description>
              <bitOffset>24</bitOffset>
              <bitWidth>1</bitWidth>
              <access>read-write</access>
              <enumeratedValues>
                <enumeratedValue>
                  <name>0</name>
                  <description>Configured interrupt is not detected.</description>
                  <value>#0</value>
                </enumeratedValue>
                <enumeratedValue>
                  <name>1</name>
                  <description>Configured interrupt is detected. If the pin is configured to generate a DMA request, then the corresponding flag will be cleared automatically at the completion of the requested DMA transfer. Otherwise, the flag remains set until a logic 1 is written to the flag. If the pin is configured for a level sensitive interrupt and the pin remains asserted, then the flag is set again immediately after it is cleared.</description>
                  <value>#1</value>
                </enumeratedValue>
              </enumeratedValues>
            </field>
          </fields>
        </register>
        <register>
          <name>PCR19</name>
          <description>Pin Control Register n</description>
          <addressOffset>0x4C</addressOffset>
          <size>32</size>
          <access>read-write</access>
          <resetValue>0</resetValue>
          <resetMask>0xFFFFFFFF</resetMask>
          <fields>
            <field>
              <name>PS</name>
              <description>Pull Select</description>
              <bitOffset>0</bitOffset>
              <bitWidth>1</bitWidth>
              <access>read-only</access>
              <enumeratedValues>
                <enumeratedValue>
                  <name>0</name>
                  <description>Internal pulldown resistor is enabled on the corresponding pin, if the corresponding PE field is set.</description>
                  <value>#0</value>
                </enumeratedValue>
                <enumeratedValue>
                  <name>1</name>
                  <description>Internal pullup resistor is enabled on the corresponding pin, if the corresponding PE field is set.</description>
                  <value>#1</value>
                </enumeratedValue>
              </enumeratedValues>
            </field>
            <field>
              <name>PE</name>
              <description>Pull Enable</description>
              <bitOffset>1</bitOffset>
              <bitWidth>1</bitWidth>
              <access>read-only</access>
              <enumeratedValues>
                <enumeratedValue>
                  <name>0</name>
                  <description>Internal pullup or pulldown resistor is not enabled on the corresponding pin.</description>
                  <value>#0</value>
                </enumeratedValue>
                <enumeratedValue>
                  <name>1</name>
                  <description>Internal pullup or pulldown resistor is enabled on the corresponding pin, if the pin is configured as a digital input.</description>
                  <value>#1</value>
                </enumeratedValue>
              </enumeratedValues>
            </field>
            <field>
              <name>SRE</name>
              <description>Slew Rate Enable</description>
              <bitOffset>2</bitOffset>
              <bitWidth>1</bitWidth>
              <access>read-only</access>
              <enumeratedValues>
                <enumeratedValue>
                  <name>0</name>
                  <description>Fast slew rate is configured on the corresponding pin, if the pin is configured as a digital output.</description>
                  <value>#0</value>
                </enumeratedValue>
                <enumeratedValue>
                  <name>1</name>
                  <description>Slow slew rate is configured on the corresponding pin, if the pin is configured as a digital output.</description>
                  <value>#1</value>
                </enumeratedValue>
              </enumeratedValues>
            </field>
            <field>
              <name>PFE</name>
              <description>Passive Filter Enable</description>
              <bitOffset>4</bitOffset>
              <bitWidth>1</bitWidth>
              <access>read-only</access>
              <enumeratedValues>
                <enumeratedValue>
                  <name>0</name>
                  <description>Passive input filter is disabled on the corresponding pin.</description>
                  <value>#0</value>
                </enumeratedValue>
                <enumeratedValue>
                  <name>1</name>
                  <description>Passive input filter is enabled on the corresponding pin, if the pin is configured as a digital input. Refer to the device data sheet for filter characteristics.</description>
                  <value>#1</value>
                </enumeratedValue>
              </enumeratedValues>
            </field>
            <field>
              <name>DSE</name>
              <description>Drive Strength Enable</description>
              <bitOffset>6</bitOffset>
              <bitWidth>1</bitWidth>
              <access>read-only</access>
              <enumeratedValues>
                <enumeratedValue>
                  <name>0</name>
                  <description>Low drive strength is configured on the corresponding pin, if pin is configured as a digital output.</description>
                  <value>#0</value>
                </enumeratedValue>
                <enumeratedValue>
                  <name>1</name>
                  <description>High drive strength is configured on the corresponding pin, if pin is configured as a digital output.</description>
                  <value>#1</value>
                </enumeratedValue>
              </enumeratedValues>
            </field>
            <field>
              <name>MUX</name>
              <description>Pin Mux Control</description>
              <bitOffset>8</bitOffset>
              <bitWidth>3</bitWidth>
              <access>read-write</access>
              <enumeratedValues>
                <enumeratedValue>
                  <name>000</name>
                  <description>Pin disabled (analog).</description>
                  <value>#000</value>
                </enumeratedValue>
                <enumeratedValue>
                  <name>001</name>
                  <description>Alternative 1 (GPIO).</description>
                  <value>#001</value>
                </enumeratedValue>
                <enumeratedValue>
                  <name>010</name>
                  <description>Alternative 2 (chip-specific).</description>
                  <value>#010</value>
                </enumeratedValue>
                <enumeratedValue>
                  <name>011</name>
                  <description>Alternative 3 (chip-specific).</description>
                  <value>#011</value>
                </enumeratedValue>
                <enumeratedValue>
                  <name>100</name>
                  <description>Alternative 4 (chip-specific).</description>
                  <value>#100</value>
                </enumeratedValue>
                <enumeratedValue>
                  <name>101</name>
                  <description>Alternative 5 (chip-specific).</description>
                  <value>#101</value>
                </enumeratedValue>
                <enumeratedValue>
                  <name>110</name>
                  <description>Alternative 6 (chip-specific).</description>
                  <value>#110</value>
                </enumeratedValue>
                <enumeratedValue>
                  <name>111</name>
                  <description>Alternative 7 (chip-specific).</description>
                  <value>#111</value>
                </enumeratedValue>
              </enumeratedValues>
            </field>
            <field>
              <name>IRQC</name>
              <description>Interrupt Configuration</description>
              <bitOffset>16</bitOffset>
              <bitWidth>4</bitWidth>
              <access>read-write</access>
              <enumeratedValues>
                <enumeratedValue>
                  <name>0000</name>
                  <description>Interrupt/DMA request disabled.</description>
                  <value>#0000</value>
                </enumeratedValue>
                <enumeratedValue>
                  <name>0001</name>
                  <description>DMA request on rising edge.</description>
                  <value>#0001</value>
                </enumeratedValue>
                <enumeratedValue>
                  <name>0010</name>
                  <description>DMA request on falling edge.</description>
                  <value>#0010</value>
                </enumeratedValue>
                <enumeratedValue>
                  <name>0011</name>
                  <description>DMA request on either edge.</description>
                  <value>#0011</value>
                </enumeratedValue>
                <enumeratedValue>
                  <name>1000</name>
                  <description>Interrupt when logic 0.</description>
                  <value>#1000</value>
                </enumeratedValue>
                <enumeratedValue>
                  <name>1001</name>
                  <description>Interrupt on rising-edge.</description>
                  <value>#1001</value>
                </enumeratedValue>
                <enumeratedValue>
                  <name>1010</name>
                  <description>Interrupt on falling-edge.</description>
                  <value>#1010</value>
                </enumeratedValue>
                <enumeratedValue>
                  <name>1011</name>
                  <description>Interrupt on either edge.</description>
                  <value>#1011</value>
                </enumeratedValue>
                <enumeratedValue>
                  <name>1100</name>
                  <description>Interrupt when logic 1.</description>
                  <value>#1100</value>
                </enumeratedValue>
              </enumeratedValues>
            </field>
            <field>
              <name>ISF</name>
              <description>Interrupt Status Flag</description>
              <bitOffset>24</bitOffset>
              <bitWidth>1</bitWidth>
              <access>read-write</access>
              <enumeratedValues>
                <enumeratedValue>
                  <name>0</name>
                  <description>Configured interrupt is not detected.</description>
                  <value>#0</value>
                </enumeratedValue>
                <enumeratedValue>
                  <name>1</name>
                  <description>Configured interrupt is detected. If the pin is configured to generate a DMA request, then the corresponding flag will be cleared automatically at the completion of the requested DMA transfer. Otherwise, the flag remains set until a logic 1 is written to the flag. If the pin is configured for a level sensitive interrupt and the pin remains asserted, then the flag is set again immediately after it is cleared.</description>
                  <value>#1</value>
                </enumeratedValue>
              </enumeratedValues>
            </field>
          </fields>
        </register>
        <register>
          <name>PCR20</name>
          <description>Pin Control Register n</description>
          <addressOffset>0x50</addressOffset>
          <size>32</size>
          <access>read-write</access>
          <resetValue>0</resetValue>
          <resetMask>0xFFFFFFFF</resetMask>
          <fields>
            <field>
              <name>PS</name>
              <description>Pull Select</description>
              <bitOffset>0</bitOffset>
              <bitWidth>1</bitWidth>
              <access>read-only</access>
              <enumeratedValues>
                <enumeratedValue>
                  <name>0</name>
                  <description>Internal pulldown resistor is enabled on the corresponding pin, if the corresponding PE field is set.</description>
                  <value>#0</value>
                </enumeratedValue>
                <enumeratedValue>
                  <name>1</name>
                  <description>Internal pullup resistor is enabled on the corresponding pin, if the corresponding PE field is set.</description>
                  <value>#1</value>
                </enumeratedValue>
              </enumeratedValues>
            </field>
            <field>
              <name>PE</name>
              <description>Pull Enable</description>
              <bitOffset>1</bitOffset>
              <bitWidth>1</bitWidth>
              <access>read-only</access>
              <enumeratedValues>
                <enumeratedValue>
                  <name>0</name>
                  <description>Internal pullup or pulldown resistor is not enabled on the corresponding pin.</description>
                  <value>#0</value>
                </enumeratedValue>
                <enumeratedValue>
                  <name>1</name>
                  <description>Internal pullup or pulldown resistor is enabled on the corresponding pin, if the pin is configured as a digital input.</description>
                  <value>#1</value>
                </enumeratedValue>
              </enumeratedValues>
            </field>
            <field>
              <name>SRE</name>
              <description>Slew Rate Enable</description>
              <bitOffset>2</bitOffset>
              <bitWidth>1</bitWidth>
              <access>read-only</access>
              <enumeratedValues>
                <enumeratedValue>
                  <name>0</name>
                  <description>Fast slew rate is configured on the corresponding pin, if the pin is configured as a digital output.</description>
                  <value>#0</value>
                </enumeratedValue>
                <enumeratedValue>
                  <name>1</name>
                  <description>Slow slew rate is configured on the corresponding pin, if the pin is configured as a digital output.</description>
                  <value>#1</value>
                </enumeratedValue>
              </enumeratedValues>
            </field>
            <field>
              <name>PFE</name>
              <description>Passive Filter Enable</description>
              <bitOffset>4</bitOffset>
              <bitWidth>1</bitWidth>
              <access>read-only</access>
              <enumeratedValues>
                <enumeratedValue>
                  <name>0</name>
                  <description>Passive input filter is disabled on the corresponding pin.</description>
                  <value>#0</value>
                </enumeratedValue>
                <enumeratedValue>
                  <name>1</name>
                  <description>Passive input filter is enabled on the corresponding pin, if the pin is configured as a digital input. Refer to the device data sheet for filter characteristics.</description>
                  <value>#1</value>
                </enumeratedValue>
              </enumeratedValues>
            </field>
            <field>
              <name>DSE</name>
              <description>Drive Strength Enable</description>
              <bitOffset>6</bitOffset>
              <bitWidth>1</bitWidth>
              <access>read-only</access>
              <enumeratedValues>
                <enumeratedValue>
                  <name>0</name>
                  <description>Low drive strength is configured on the corresponding pin, if pin is configured as a digital output.</description>
                  <value>#0</value>
                </enumeratedValue>
                <enumeratedValue>
                  <name>1</name>
                  <description>High drive strength is configured on the corresponding pin, if pin is configured as a digital output.</description>
                  <value>#1</value>
                </enumeratedValue>
              </enumeratedValues>
            </field>
            <field>
              <name>MUX</name>
              <description>Pin Mux Control</description>
              <bitOffset>8</bitOffset>
              <bitWidth>3</bitWidth>
              <access>read-write</access>
              <enumeratedValues>
                <enumeratedValue>
                  <name>000</name>
                  <description>Pin disabled (analog).</description>
                  <value>#000</value>
                </enumeratedValue>
                <enumeratedValue>
                  <name>001</name>
                  <description>Alternative 1 (GPIO).</description>
                  <value>#001</value>
                </enumeratedValue>
                <enumeratedValue>
                  <name>010</name>
                  <description>Alternative 2 (chip-specific).</description>
                  <value>#010</value>
                </enumeratedValue>
                <enumeratedValue>
                  <name>011</name>
                  <description>Alternative 3 (chip-specific).</description>
                  <value>#011</value>
                </enumeratedValue>
                <enumeratedValue>
                  <name>100</name>
                  <description>Alternative 4 (chip-specific).</description>
                  <value>#100</value>
                </enumeratedValue>
                <enumeratedValue>
                  <name>101</name>
                  <description>Alternative 5 (chip-specific).</description>
                  <value>#101</value>
                </enumeratedValue>
                <enumeratedValue>
                  <name>110</name>
                  <description>Alternative 6 (chip-specific).</description>
                  <value>#110</value>
                </enumeratedValue>
                <enumeratedValue>
                  <name>111</name>
                  <description>Alternative 7 (chip-specific).</description>
                  <value>#111</value>
                </enumeratedValue>
              </enumeratedValues>
            </field>
            <field>
              <name>IRQC</name>
              <description>Interrupt Configuration</description>
              <bitOffset>16</bitOffset>
              <bitWidth>4</bitWidth>
              <access>read-write</access>
              <enumeratedValues>
                <enumeratedValue>
                  <name>0000</name>
                  <description>Interrupt/DMA request disabled.</description>
                  <value>#0000</value>
                </enumeratedValue>
                <enumeratedValue>
                  <name>0001</name>
                  <description>DMA request on rising edge.</description>
                  <value>#0001</value>
                </enumeratedValue>
                <enumeratedValue>
                  <name>0010</name>
                  <description>DMA request on falling edge.</description>
                  <value>#0010</value>
                </enumeratedValue>
                <enumeratedValue>
                  <name>0011</name>
                  <description>DMA request on either edge.</description>
                  <value>#0011</value>
                </enumeratedValue>
                <enumeratedValue>
                  <name>1000</name>
                  <description>Interrupt when logic 0.</description>
                  <value>#1000</value>
                </enumeratedValue>
                <enumeratedValue>
                  <name>1001</name>
                  <description>Interrupt on rising-edge.</description>
                  <value>#1001</value>
                </enumeratedValue>
                <enumeratedValue>
                  <name>1010</name>
                  <description>Interrupt on falling-edge.</description>
                  <value>#1010</value>
                </enumeratedValue>
                <enumeratedValue>
                  <name>1011</name>
                  <description>Interrupt on either edge.</description>
                  <value>#1011</value>
                </enumeratedValue>
                <enumeratedValue>
                  <name>1100</name>
                  <description>Interrupt when logic 1.</description>
                  <value>#1100</value>
                </enumeratedValue>
              </enumeratedValues>
            </field>
            <field>
              <name>ISF</name>
              <description>Interrupt Status Flag</description>
              <bitOffset>24</bitOffset>
              <bitWidth>1</bitWidth>
              <access>read-write</access>
              <enumeratedValues>
                <enumeratedValue>
                  <name>0</name>
                  <description>Configured interrupt is not detected.</description>
                  <value>#0</value>
                </enumeratedValue>
                <enumeratedValue>
                  <name>1</name>
                  <description>Configured interrupt is detected. If the pin is configured to generate a DMA request, then the corresponding flag will be cleared automatically at the completion of the requested DMA transfer. Otherwise, the flag remains set until a logic 1 is written to the flag. If the pin is configured for a level sensitive interrupt and the pin remains asserted, then the flag is set again immediately after it is cleared.</description>
                  <value>#1</value>
                </enumeratedValue>
              </enumeratedValues>
            </field>
          </fields>
        </register>
        <register>
          <name>PCR21</name>
          <description>Pin Control Register n</description>
          <addressOffset>0x54</addressOffset>
          <size>32</size>
          <access>read-write</access>
          <resetValue>0</resetValue>
          <resetMask>0xFFFFFFFF</resetMask>
          <fields>
            <field>
              <name>PS</name>
              <description>Pull Select</description>
              <bitOffset>0</bitOffset>
              <bitWidth>1</bitWidth>
              <access>read-only</access>
              <enumeratedValues>
                <enumeratedValue>
                  <name>0</name>
                  <description>Internal pulldown resistor is enabled on the corresponding pin, if the corresponding PE field is set.</description>
                  <value>#0</value>
                </enumeratedValue>
                <enumeratedValue>
                  <name>1</name>
                  <description>Internal pullup resistor is enabled on the corresponding pin, if the corresponding PE field is set.</description>
                  <value>#1</value>
                </enumeratedValue>
              </enumeratedValues>
            </field>
            <field>
              <name>PE</name>
              <description>Pull Enable</description>
              <bitOffset>1</bitOffset>
              <bitWidth>1</bitWidth>
              <access>read-only</access>
              <enumeratedValues>
                <enumeratedValue>
                  <name>0</name>
                  <description>Internal pullup or pulldown resistor is not enabled on the corresponding pin.</description>
                  <value>#0</value>
                </enumeratedValue>
                <enumeratedValue>
                  <name>1</name>
                  <description>Internal pullup or pulldown resistor is enabled on the corresponding pin, if the pin is configured as a digital input.</description>
                  <value>#1</value>
                </enumeratedValue>
              </enumeratedValues>
            </field>
            <field>
              <name>SRE</name>
              <description>Slew Rate Enable</description>
              <bitOffset>2</bitOffset>
              <bitWidth>1</bitWidth>
              <access>read-only</access>
              <enumeratedValues>
                <enumeratedValue>
                  <name>0</name>
                  <description>Fast slew rate is configured on the corresponding pin, if the pin is configured as a digital output.</description>
                  <value>#0</value>
                </enumeratedValue>
                <enumeratedValue>
                  <name>1</name>
                  <description>Slow slew rate is configured on the corresponding pin, if the pin is configured as a digital output.</description>
                  <value>#1</value>
                </enumeratedValue>
              </enumeratedValues>
            </field>
            <field>
              <name>PFE</name>
              <description>Passive Filter Enable</description>
              <bitOffset>4</bitOffset>
              <bitWidth>1</bitWidth>
              <access>read-only</access>
              <enumeratedValues>
                <enumeratedValue>
                  <name>0</name>
                  <description>Passive input filter is disabled on the corresponding pin.</description>
                  <value>#0</value>
                </enumeratedValue>
                <enumeratedValue>
                  <name>1</name>
                  <description>Passive input filter is enabled on the corresponding pin, if the pin is configured as a digital input. Refer to the device data sheet for filter characteristics.</description>
                  <value>#1</value>
                </enumeratedValue>
              </enumeratedValues>
            </field>
            <field>
              <name>DSE</name>
              <description>Drive Strength Enable</description>
              <bitOffset>6</bitOffset>
              <bitWidth>1</bitWidth>
              <access>read-only</access>
              <enumeratedValues>
                <enumeratedValue>
                  <name>0</name>
                  <description>Low drive strength is configured on the corresponding pin, if pin is configured as a digital output.</description>
                  <value>#0</value>
                </enumeratedValue>
                <enumeratedValue>
                  <name>1</name>
                  <description>High drive strength is configured on the corresponding pin, if pin is configured as a digital output.</description>
                  <value>#1</value>
                </enumeratedValue>
              </enumeratedValues>
            </field>
            <field>
              <name>MUX</name>
              <description>Pin Mux Control</description>
              <bitOffset>8</bitOffset>
              <bitWidth>3</bitWidth>
              <access>read-write</access>
              <enumeratedValues>
                <enumeratedValue>
                  <name>000</name>
                  <description>Pin disabled (analog).</description>
                  <value>#000</value>
                </enumeratedValue>
                <enumeratedValue>
                  <name>001</name>
                  <description>Alternative 1 (GPIO).</description>
                  <value>#001</value>
                </enumeratedValue>
                <enumeratedValue>
                  <name>010</name>
                  <description>Alternative 2 (chip-specific).</description>
                  <value>#010</value>
                </enumeratedValue>
                <enumeratedValue>
                  <name>011</name>
                  <description>Alternative 3 (chip-specific).</description>
                  <value>#011</value>
                </enumeratedValue>
                <enumeratedValue>
                  <name>100</name>
                  <description>Alternative 4 (chip-specific).</description>
                  <value>#100</value>
                </enumeratedValue>
                <enumeratedValue>
                  <name>101</name>
                  <description>Alternative 5 (chip-specific).</description>
                  <value>#101</value>
                </enumeratedValue>
                <enumeratedValue>
                  <name>110</name>
                  <description>Alternative 6 (chip-specific).</description>
                  <value>#110</value>
                </enumeratedValue>
                <enumeratedValue>
                  <name>111</name>
                  <description>Alternative 7 (chip-specific).</description>
                  <value>#111</value>
                </enumeratedValue>
              </enumeratedValues>
            </field>
            <field>
              <name>IRQC</name>
              <description>Interrupt Configuration</description>
              <bitOffset>16</bitOffset>
              <bitWidth>4</bitWidth>
              <access>read-write</access>
              <enumeratedValues>
                <enumeratedValue>
                  <name>0000</name>
                  <description>Interrupt/DMA request disabled.</description>
                  <value>#0000</value>
                </enumeratedValue>
                <enumeratedValue>
                  <name>0001</name>
                  <description>DMA request on rising edge.</description>
                  <value>#0001</value>
                </enumeratedValue>
                <enumeratedValue>
                  <name>0010</name>
                  <description>DMA request on falling edge.</description>
                  <value>#0010</value>
                </enumeratedValue>
                <enumeratedValue>
                  <name>0011</name>
                  <description>DMA request on either edge.</description>
                  <value>#0011</value>
                </enumeratedValue>
                <enumeratedValue>
                  <name>1000</name>
                  <description>Interrupt when logic 0.</description>
                  <value>#1000</value>
                </enumeratedValue>
                <enumeratedValue>
                  <name>1001</name>
                  <description>Interrupt on rising-edge.</description>
                  <value>#1001</value>
                </enumeratedValue>
                <enumeratedValue>
                  <name>1010</name>
                  <description>Interrupt on falling-edge.</description>
                  <value>#1010</value>
                </enumeratedValue>
                <enumeratedValue>
                  <name>1011</name>
                  <description>Interrupt on either edge.</description>
                  <value>#1011</value>
                </enumeratedValue>
                <enumeratedValue>
                  <name>1100</name>
                  <description>Interrupt when logic 1.</description>
                  <value>#1100</value>
                </enumeratedValue>
              </enumeratedValues>
            </field>
            <field>
              <name>ISF</name>
              <description>Interrupt Status Flag</description>
              <bitOffset>24</bitOffset>
              <bitWidth>1</bitWidth>
              <access>read-write</access>
              <enumeratedValues>
                <enumeratedValue>
                  <name>0</name>
                  <description>Configured interrupt is not detected.</description>
                  <value>#0</value>
                </enumeratedValue>
                <enumeratedValue>
                  <name>1</name>
                  <description>Configured interrupt is detected. If the pin is configured to generate a DMA request, then the corresponding flag will be cleared automatically at the completion of the requested DMA transfer. Otherwise, the flag remains set until a logic 1 is written to the flag. If the pin is configured for a level sensitive interrupt and the pin remains asserted, then the flag is set again immediately after it is cleared.</description>
                  <value>#1</value>
                </enumeratedValue>
              </enumeratedValues>
            </field>
          </fields>
        </register>
        <register>
          <name>PCR22</name>
          <description>Pin Control Register n</description>
          <addressOffset>0x58</addressOffset>
          <size>32</size>
          <access>read-write</access>
          <resetValue>0</resetValue>
          <resetMask>0xFFFFFFFF</resetMask>
          <fields>
            <field>
              <name>PS</name>
              <description>Pull Select</description>
              <bitOffset>0</bitOffset>
              <bitWidth>1</bitWidth>
              <access>read-only</access>
              <enumeratedValues>
                <enumeratedValue>
                  <name>0</name>
                  <description>Internal pulldown resistor is enabled on the corresponding pin, if the corresponding PE field is set.</description>
                  <value>#0</value>
                </enumeratedValue>
                <enumeratedValue>
                  <name>1</name>
                  <description>Internal pullup resistor is enabled on the corresponding pin, if the corresponding PE field is set.</description>
                  <value>#1</value>
                </enumeratedValue>
              </enumeratedValues>
            </field>
            <field>
              <name>PE</name>
              <description>Pull Enable</description>
              <bitOffset>1</bitOffset>
              <bitWidth>1</bitWidth>
              <access>read-only</access>
              <enumeratedValues>
                <enumeratedValue>
                  <name>0</name>
                  <description>Internal pullup or pulldown resistor is not enabled on the corresponding pin.</description>
                  <value>#0</value>
                </enumeratedValue>
                <enumeratedValue>
                  <name>1</name>
                  <description>Internal pullup or pulldown resistor is enabled on the corresponding pin, if the pin is configured as a digital input.</description>
                  <value>#1</value>
                </enumeratedValue>
              </enumeratedValues>
            </field>
            <field>
              <name>SRE</name>
              <description>Slew Rate Enable</description>
              <bitOffset>2</bitOffset>
              <bitWidth>1</bitWidth>
              <access>read-only</access>
              <enumeratedValues>
                <enumeratedValue>
                  <name>0</name>
                  <description>Fast slew rate is configured on the corresponding pin, if the pin is configured as a digital output.</description>
                  <value>#0</value>
                </enumeratedValue>
                <enumeratedValue>
                  <name>1</name>
                  <description>Slow slew rate is configured on the corresponding pin, if the pin is configured as a digital output.</description>
                  <value>#1</value>
                </enumeratedValue>
              </enumeratedValues>
            </field>
            <field>
              <name>PFE</name>
              <description>Passive Filter Enable</description>
              <bitOffset>4</bitOffset>
              <bitWidth>1</bitWidth>
              <access>read-only</access>
              <enumeratedValues>
                <enumeratedValue>
                  <name>0</name>
                  <description>Passive input filter is disabled on the corresponding pin.</description>
                  <value>#0</value>
                </enumeratedValue>
                <enumeratedValue>
                  <name>1</name>
                  <description>Passive input filter is enabled on the corresponding pin, if the pin is configured as a digital input. Refer to the device data sheet for filter characteristics.</description>
                  <value>#1</value>
                </enumeratedValue>
              </enumeratedValues>
            </field>
            <field>
              <name>DSE</name>
              <description>Drive Strength Enable</description>
              <bitOffset>6</bitOffset>
              <bitWidth>1</bitWidth>
              <access>read-only</access>
              <enumeratedValues>
                <enumeratedValue>
                  <name>0</name>
                  <description>Low drive strength is configured on the corresponding pin, if pin is configured as a digital output.</description>
                  <value>#0</value>
                </enumeratedValue>
                <enumeratedValue>
                  <name>1</name>
                  <description>High drive strength is configured on the corresponding pin, if pin is configured as a digital output.</description>
                  <value>#1</value>
                </enumeratedValue>
              </enumeratedValues>
            </field>
            <field>
              <name>MUX</name>
              <description>Pin Mux Control</description>
              <bitOffset>8</bitOffset>
              <bitWidth>3</bitWidth>
              <access>read-write</access>
              <enumeratedValues>
                <enumeratedValue>
                  <name>000</name>
                  <description>Pin disabled (analog).</description>
                  <value>#000</value>
                </enumeratedValue>
                <enumeratedValue>
                  <name>001</name>
                  <description>Alternative 1 (GPIO).</description>
                  <value>#001</value>
                </enumeratedValue>
                <enumeratedValue>
                  <name>010</name>
                  <description>Alternative 2 (chip-specific).</description>
                  <value>#010</value>
                </enumeratedValue>
                <enumeratedValue>
                  <name>011</name>
                  <description>Alternative 3 (chip-specific).</description>
                  <value>#011</value>
                </enumeratedValue>
                <enumeratedValue>
                  <name>100</name>
                  <description>Alternative 4 (chip-specific).</description>
                  <value>#100</value>
                </enumeratedValue>
                <enumeratedValue>
                  <name>101</name>
                  <description>Alternative 5 (chip-specific).</description>
                  <value>#101</value>
                </enumeratedValue>
                <enumeratedValue>
                  <name>110</name>
                  <description>Alternative 6 (chip-specific).</description>
                  <value>#110</value>
                </enumeratedValue>
                <enumeratedValue>
                  <name>111</name>
                  <description>Alternative 7 (chip-specific).</description>
                  <value>#111</value>
                </enumeratedValue>
              </enumeratedValues>
            </field>
            <field>
              <name>IRQC</name>
              <description>Interrupt Configuration</description>
              <bitOffset>16</bitOffset>
              <bitWidth>4</bitWidth>
              <access>read-write</access>
              <enumeratedValues>
                <enumeratedValue>
                  <name>0000</name>
                  <description>Interrupt/DMA request disabled.</description>
                  <value>#0000</value>
                </enumeratedValue>
                <enumeratedValue>
                  <name>0001</name>
                  <description>DMA request on rising edge.</description>
                  <value>#0001</value>
                </enumeratedValue>
                <enumeratedValue>
                  <name>0010</name>
                  <description>DMA request on falling edge.</description>
                  <value>#0010</value>
                </enumeratedValue>
                <enumeratedValue>
                  <name>0011</name>
                  <description>DMA request on either edge.</description>
                  <value>#0011</value>
                </enumeratedValue>
                <enumeratedValue>
                  <name>1000</name>
                  <description>Interrupt when logic 0.</description>
                  <value>#1000</value>
                </enumeratedValue>
                <enumeratedValue>
                  <name>1001</name>
                  <description>Interrupt on rising-edge.</description>
                  <value>#1001</value>
                </enumeratedValue>
                <enumeratedValue>
                  <name>1010</name>
                  <description>Interrupt on falling-edge.</description>
                  <value>#1010</value>
                </enumeratedValue>
                <enumeratedValue>
                  <name>1011</name>
                  <description>Interrupt on either edge.</description>
                  <value>#1011</value>
                </enumeratedValue>
                <enumeratedValue>
                  <name>1100</name>
                  <description>Interrupt when logic 1.</description>
                  <value>#1100</value>
                </enumeratedValue>
              </enumeratedValues>
            </field>
            <field>
              <name>ISF</name>
              <description>Interrupt Status Flag</description>
              <bitOffset>24</bitOffset>
              <bitWidth>1</bitWidth>
              <access>read-write</access>
              <enumeratedValues>
                <enumeratedValue>
                  <name>0</name>
                  <description>Configured interrupt is not detected.</description>
                  <value>#0</value>
                </enumeratedValue>
                <enumeratedValue>
                  <name>1</name>
                  <description>Configured interrupt is detected. If the pin is configured to generate a DMA request, then the corresponding flag will be cleared automatically at the completion of the requested DMA transfer. Otherwise, the flag remains set until a logic 1 is written to the flag. If the pin is configured for a level sensitive interrupt and the pin remains asserted, then the flag is set again immediately after it is cleared.</description>
                  <value>#1</value>
                </enumeratedValue>
              </enumeratedValues>
            </field>
          </fields>
        </register>
        <register>
          <name>PCR23</name>
          <description>Pin Control Register n</description>
          <addressOffset>0x5C</addressOffset>
          <size>32</size>
          <access>read-write</access>
          <resetValue>0</resetValue>
          <resetMask>0xFFFFFFFF</resetMask>
          <fields>
            <field>
              <name>PS</name>
              <description>Pull Select</description>
              <bitOffset>0</bitOffset>
              <bitWidth>1</bitWidth>
              <access>read-only</access>
              <enumeratedValues>
                <enumeratedValue>
                  <name>0</name>
                  <description>Internal pulldown resistor is enabled on the corresponding pin, if the corresponding PE field is set.</description>
                  <value>#0</value>
                </enumeratedValue>
                <enumeratedValue>
                  <name>1</name>
                  <description>Internal pullup resistor is enabled on the corresponding pin, if the corresponding PE field is set.</description>
                  <value>#1</value>
                </enumeratedValue>
              </enumeratedValues>
            </field>
            <field>
              <name>PE</name>
              <description>Pull Enable</description>
              <bitOffset>1</bitOffset>
              <bitWidth>1</bitWidth>
              <access>read-only</access>
              <enumeratedValues>
                <enumeratedValue>
                  <name>0</name>
                  <description>Internal pullup or pulldown resistor is not enabled on the corresponding pin.</description>
                  <value>#0</value>
                </enumeratedValue>
                <enumeratedValue>
                  <name>1</name>
                  <description>Internal pullup or pulldown resistor is enabled on the corresponding pin, if the pin is configured as a digital input.</description>
                  <value>#1</value>
                </enumeratedValue>
              </enumeratedValues>
            </field>
            <field>
              <name>SRE</name>
              <description>Slew Rate Enable</description>
              <bitOffset>2</bitOffset>
              <bitWidth>1</bitWidth>
              <access>read-only</access>
              <enumeratedValues>
                <enumeratedValue>
                  <name>0</name>
                  <description>Fast slew rate is configured on the corresponding pin, if the pin is configured as a digital output.</description>
                  <value>#0</value>
                </enumeratedValue>
                <enumeratedValue>
                  <name>1</name>
                  <description>Slow slew rate is configured on the corresponding pin, if the pin is configured as a digital output.</description>
                  <value>#1</value>
                </enumeratedValue>
              </enumeratedValues>
            </field>
            <field>
              <name>PFE</name>
              <description>Passive Filter Enable</description>
              <bitOffset>4</bitOffset>
              <bitWidth>1</bitWidth>
              <access>read-only</access>
              <enumeratedValues>
                <enumeratedValue>
                  <name>0</name>
                  <description>Passive input filter is disabled on the corresponding pin.</description>
                  <value>#0</value>
                </enumeratedValue>
                <enumeratedValue>
                  <name>1</name>
                  <description>Passive input filter is enabled on the corresponding pin, if the pin is configured as a digital input. Refer to the device data sheet for filter characteristics.</description>
                  <value>#1</value>
                </enumeratedValue>
              </enumeratedValues>
            </field>
            <field>
              <name>DSE</name>
              <description>Drive Strength Enable</description>
              <bitOffset>6</bitOffset>
              <bitWidth>1</bitWidth>
              <access>read-only</access>
              <enumeratedValues>
                <enumeratedValue>
                  <name>0</name>
                  <description>Low drive strength is configured on the corresponding pin, if pin is configured as a digital output.</description>
                  <value>#0</value>
                </enumeratedValue>
                <enumeratedValue>
                  <name>1</name>
                  <description>High drive strength is configured on the corresponding pin, if pin is configured as a digital output.</description>
                  <value>#1</value>
                </enumeratedValue>
              </enumeratedValues>
            </field>
            <field>
              <name>MUX</name>
              <description>Pin Mux Control</description>
              <bitOffset>8</bitOffset>
              <bitWidth>3</bitWidth>
              <access>read-write</access>
              <enumeratedValues>
                <enumeratedValue>
                  <name>000</name>
                  <description>Pin disabled (analog).</description>
                  <value>#000</value>
                </enumeratedValue>
                <enumeratedValue>
                  <name>001</name>
                  <description>Alternative 1 (GPIO).</description>
                  <value>#001</value>
                </enumeratedValue>
                <enumeratedValue>
                  <name>010</name>
                  <description>Alternative 2 (chip-specific).</description>
                  <value>#010</value>
                </enumeratedValue>
                <enumeratedValue>
                  <name>011</name>
                  <description>Alternative 3 (chip-specific).</description>
                  <value>#011</value>
                </enumeratedValue>
                <enumeratedValue>
                  <name>100</name>
                  <description>Alternative 4 (chip-specific).</description>
                  <value>#100</value>
                </enumeratedValue>
                <enumeratedValue>
                  <name>101</name>
                  <description>Alternative 5 (chip-specific).</description>
                  <value>#101</value>
                </enumeratedValue>
                <enumeratedValue>
                  <name>110</name>
                  <description>Alternative 6 (chip-specific).</description>
                  <value>#110</value>
                </enumeratedValue>
                <enumeratedValue>
                  <name>111</name>
                  <description>Alternative 7 (chip-specific).</description>
                  <value>#111</value>
                </enumeratedValue>
              </enumeratedValues>
            </field>
            <field>
              <name>IRQC</name>
              <description>Interrupt Configuration</description>
              <bitOffset>16</bitOffset>
              <bitWidth>4</bitWidth>
              <access>read-write</access>
              <enumeratedValues>
                <enumeratedValue>
                  <name>0000</name>
                  <description>Interrupt/DMA request disabled.</description>
                  <value>#0000</value>
                </enumeratedValue>
                <enumeratedValue>
                  <name>0001</name>
                  <description>DMA request on rising edge.</description>
                  <value>#0001</value>
                </enumeratedValue>
                <enumeratedValue>
                  <name>0010</name>
                  <description>DMA request on falling edge.</description>
                  <value>#0010</value>
                </enumeratedValue>
                <enumeratedValue>
                  <name>0011</name>
                  <description>DMA request on either edge.</description>
                  <value>#0011</value>
                </enumeratedValue>
                <enumeratedValue>
                  <name>1000</name>
                  <description>Interrupt when logic 0.</description>
                  <value>#1000</value>
                </enumeratedValue>
                <enumeratedValue>
                  <name>1001</name>
                  <description>Interrupt on rising-edge.</description>
                  <value>#1001</value>
                </enumeratedValue>
                <enumeratedValue>
                  <name>1010</name>
                  <description>Interrupt on falling-edge.</description>
                  <value>#1010</value>
                </enumeratedValue>
                <enumeratedValue>
                  <name>1011</name>
                  <description>Interrupt on either edge.</description>
                  <value>#1011</value>
                </enumeratedValue>
                <enumeratedValue>
                  <name>1100</name>
                  <description>Interrupt when logic 1.</description>
                  <value>#1100</value>
                </enumeratedValue>
              </enumeratedValues>
            </field>
            <field>
              <name>ISF</name>
              <description>Interrupt Status Flag</description>
              <bitOffset>24</bitOffset>
              <bitWidth>1</bitWidth>
              <access>read-write</access>
              <enumeratedValues>
                <enumeratedValue>
                  <name>0</name>
                  <description>Configured interrupt is not detected.</description>
                  <value>#0</value>
                </enumeratedValue>
                <enumeratedValue>
                  <name>1</name>
                  <description>Configured interrupt is detected. If the pin is configured to generate a DMA request, then the corresponding flag will be cleared automatically at the completion of the requested DMA transfer. Otherwise, the flag remains set until a logic 1 is written to the flag. If the pin is configured for a level sensitive interrupt and the pin remains asserted, then the flag is set again immediately after it is cleared.</description>
                  <value>#1</value>
                </enumeratedValue>
              </enumeratedValues>
            </field>
          </fields>
        </register>
        <register>
          <name>PCR24</name>
          <description>Pin Control Register n</description>
          <addressOffset>0x60</addressOffset>
          <size>32</size>
          <access>read-write</access>
          <resetValue>0</resetValue>
          <resetMask>0xFFFFFFFF</resetMask>
          <fields>
            <field>
              <name>PS</name>
              <description>Pull Select</description>
              <bitOffset>0</bitOffset>
              <bitWidth>1</bitWidth>
              <access>read-only</access>
              <enumeratedValues>
                <enumeratedValue>
                  <name>0</name>
                  <description>Internal pulldown resistor is enabled on the corresponding pin, if the corresponding PE field is set.</description>
                  <value>#0</value>
                </enumeratedValue>
                <enumeratedValue>
                  <name>1</name>
                  <description>Internal pullup resistor is enabled on the corresponding pin, if the corresponding PE field is set.</description>
                  <value>#1</value>
                </enumeratedValue>
              </enumeratedValues>
            </field>
            <field>
              <name>PE</name>
              <description>Pull Enable</description>
              <bitOffset>1</bitOffset>
              <bitWidth>1</bitWidth>
              <access>read-only</access>
              <enumeratedValues>
                <enumeratedValue>
                  <name>0</name>
                  <description>Internal pullup or pulldown resistor is not enabled on the corresponding pin.</description>
                  <value>#0</value>
                </enumeratedValue>
                <enumeratedValue>
                  <name>1</name>
                  <description>Internal pullup or pulldown resistor is enabled on the corresponding pin, if the pin is configured as a digital input.</description>
                  <value>#1</value>
                </enumeratedValue>
              </enumeratedValues>
            </field>
            <field>
              <name>SRE</name>
              <description>Slew Rate Enable</description>
              <bitOffset>2</bitOffset>
              <bitWidth>1</bitWidth>
              <access>read-only</access>
              <enumeratedValues>
                <enumeratedValue>
                  <name>0</name>
                  <description>Fast slew rate is configured on the corresponding pin, if the pin is configured as a digital output.</description>
                  <value>#0</value>
                </enumeratedValue>
                <enumeratedValue>
                  <name>1</name>
                  <description>Slow slew rate is configured on the corresponding pin, if the pin is configured as a digital output.</description>
                  <value>#1</value>
                </enumeratedValue>
              </enumeratedValues>
            </field>
            <field>
              <name>PFE</name>
              <description>Passive Filter Enable</description>
              <bitOffset>4</bitOffset>
              <bitWidth>1</bitWidth>
              <access>read-only</access>
              <enumeratedValues>
                <enumeratedValue>
                  <name>0</name>
                  <description>Passive input filter is disabled on the corresponding pin.</description>
                  <value>#0</value>
                </enumeratedValue>
                <enumeratedValue>
                  <name>1</name>
                  <description>Passive input filter is enabled on the corresponding pin, if the pin is configured as a digital input. Refer to the device data sheet for filter characteristics.</description>
                  <value>#1</value>
                </enumeratedValue>
              </enumeratedValues>
            </field>
            <field>
              <name>DSE</name>
              <description>Drive Strength Enable</description>
              <bitOffset>6</bitOffset>
              <bitWidth>1</bitWidth>
              <access>read-only</access>
              <enumeratedValues>
                <enumeratedValue>
                  <name>0</name>
                  <description>Low drive strength is configured on the corresponding pin, if pin is configured as a digital output.</description>
                  <value>#0</value>
                </enumeratedValue>
                <enumeratedValue>
                  <name>1</name>
                  <description>High drive strength is configured on the corresponding pin, if pin is configured as a digital output.</description>
                  <value>#1</value>
                </enumeratedValue>
              </enumeratedValues>
            </field>
            <field>
              <name>MUX</name>
              <description>Pin Mux Control</description>
              <bitOffset>8</bitOffset>
              <bitWidth>3</bitWidth>
              <access>read-write</access>
              <enumeratedValues>
                <enumeratedValue>
                  <name>000</name>
                  <description>Pin disabled (analog).</description>
                  <value>#000</value>
                </enumeratedValue>
                <enumeratedValue>
                  <name>001</name>
                  <description>Alternative 1 (GPIO).</description>
                  <value>#001</value>
                </enumeratedValue>
                <enumeratedValue>
                  <name>010</name>
                  <description>Alternative 2 (chip-specific).</description>
                  <value>#010</value>
                </enumeratedValue>
                <enumeratedValue>
                  <name>011</name>
                  <description>Alternative 3 (chip-specific).</description>
                  <value>#011</value>
                </enumeratedValue>
                <enumeratedValue>
                  <name>100</name>
                  <description>Alternative 4 (chip-specific).</description>
                  <value>#100</value>
                </enumeratedValue>
                <enumeratedValue>
                  <name>101</name>
                  <description>Alternative 5 (chip-specific).</description>
                  <value>#101</value>
                </enumeratedValue>
                <enumeratedValue>
                  <name>110</name>
                  <description>Alternative 6 (chip-specific).</description>
                  <value>#110</value>
                </enumeratedValue>
                <enumeratedValue>
                  <name>111</name>
                  <description>Alternative 7 (chip-specific).</description>
                  <value>#111</value>
                </enumeratedValue>
              </enumeratedValues>
            </field>
            <field>
              <name>IRQC</name>
              <description>Interrupt Configuration</description>
              <bitOffset>16</bitOffset>
              <bitWidth>4</bitWidth>
              <access>read-write</access>
              <enumeratedValues>
                <enumeratedValue>
                  <name>0000</name>
                  <description>Interrupt/DMA request disabled.</description>
                  <value>#0000</value>
                </enumeratedValue>
                <enumeratedValue>
                  <name>0001</name>
                  <description>DMA request on rising edge.</description>
                  <value>#0001</value>
                </enumeratedValue>
                <enumeratedValue>
                  <name>0010</name>
                  <description>DMA request on falling edge.</description>
                  <value>#0010</value>
                </enumeratedValue>
                <enumeratedValue>
                  <name>0011</name>
                  <description>DMA request on either edge.</description>
                  <value>#0011</value>
                </enumeratedValue>
                <enumeratedValue>
                  <name>1000</name>
                  <description>Interrupt when logic 0.</description>
                  <value>#1000</value>
                </enumeratedValue>
                <enumeratedValue>
                  <name>1001</name>
                  <description>Interrupt on rising-edge.</description>
                  <value>#1001</value>
                </enumeratedValue>
                <enumeratedValue>
                  <name>1010</name>
                  <description>Interrupt on falling-edge.</description>
                  <value>#1010</value>
                </enumeratedValue>
                <enumeratedValue>
                  <name>1011</name>
                  <description>Interrupt on either edge.</description>
                  <value>#1011</value>
                </enumeratedValue>
                <enumeratedValue>
                  <name>1100</name>
                  <description>Interrupt when logic 1.</description>
                  <value>#1100</value>
                </enumeratedValue>
              </enumeratedValues>
            </field>
            <field>
              <name>ISF</name>
              <description>Interrupt Status Flag</description>
              <bitOffset>24</bitOffset>
              <bitWidth>1</bitWidth>
              <access>read-write</access>
              <enumeratedValues>
                <enumeratedValue>
                  <name>0</name>
                  <description>Configured interrupt is not detected.</description>
                  <value>#0</value>
                </enumeratedValue>
                <enumeratedValue>
                  <name>1</name>
                  <description>Configured interrupt is detected. If the pin is configured to generate a DMA request, then the corresponding flag will be cleared automatically at the completion of the requested DMA transfer. Otherwise, the flag remains set until a logic 1 is written to the flag. If the pin is configured for a level sensitive interrupt and the pin remains asserted, then the flag is set again immediately after it is cleared.</description>
                  <value>#1</value>
                </enumeratedValue>
              </enumeratedValues>
            </field>
          </fields>
        </register>
        <register>
          <name>PCR25</name>
          <description>Pin Control Register n</description>
          <addressOffset>0x64</addressOffset>
          <size>32</size>
          <access>read-write</access>
          <resetValue>0</resetValue>
          <resetMask>0xFFFFFFFF</resetMask>
          <fields>
            <field>
              <name>PS</name>
              <description>Pull Select</description>
              <bitOffset>0</bitOffset>
              <bitWidth>1</bitWidth>
              <access>read-only</access>
              <enumeratedValues>
                <enumeratedValue>
                  <name>0</name>
                  <description>Internal pulldown resistor is enabled on the corresponding pin, if the corresponding PE field is set.</description>
                  <value>#0</value>
                </enumeratedValue>
                <enumeratedValue>
                  <name>1</name>
                  <description>Internal pullup resistor is enabled on the corresponding pin, if the corresponding PE field is set.</description>
                  <value>#1</value>
                </enumeratedValue>
              </enumeratedValues>
            </field>
            <field>
              <name>PE</name>
              <description>Pull Enable</description>
              <bitOffset>1</bitOffset>
              <bitWidth>1</bitWidth>
              <access>read-only</access>
              <enumeratedValues>
                <enumeratedValue>
                  <name>0</name>
                  <description>Internal pullup or pulldown resistor is not enabled on the corresponding pin.</description>
                  <value>#0</value>
                </enumeratedValue>
                <enumeratedValue>
                  <name>1</name>
                  <description>Internal pullup or pulldown resistor is enabled on the corresponding pin, if the pin is configured as a digital input.</description>
                  <value>#1</value>
                </enumeratedValue>
              </enumeratedValues>
            </field>
            <field>
              <name>SRE</name>
              <description>Slew Rate Enable</description>
              <bitOffset>2</bitOffset>
              <bitWidth>1</bitWidth>
              <access>read-only</access>
              <enumeratedValues>
                <enumeratedValue>
                  <name>0</name>
                  <description>Fast slew rate is configured on the corresponding pin, if the pin is configured as a digital output.</description>
                  <value>#0</value>
                </enumeratedValue>
                <enumeratedValue>
                  <name>1</name>
                  <description>Slow slew rate is configured on the corresponding pin, if the pin is configured as a digital output.</description>
                  <value>#1</value>
                </enumeratedValue>
              </enumeratedValues>
            </field>
            <field>
              <name>PFE</name>
              <description>Passive Filter Enable</description>
              <bitOffset>4</bitOffset>
              <bitWidth>1</bitWidth>
              <access>read-only</access>
              <enumeratedValues>
                <enumeratedValue>
                  <name>0</name>
                  <description>Passive input filter is disabled on the corresponding pin.</description>
                  <value>#0</value>
                </enumeratedValue>
                <enumeratedValue>
                  <name>1</name>
                  <description>Passive input filter is enabled on the corresponding pin, if the pin is configured as a digital input. Refer to the device data sheet for filter characteristics.</description>
                  <value>#1</value>
                </enumeratedValue>
              </enumeratedValues>
            </field>
            <field>
              <name>DSE</name>
              <description>Drive Strength Enable</description>
              <bitOffset>6</bitOffset>
              <bitWidth>1</bitWidth>
              <access>read-only</access>
              <enumeratedValues>
                <enumeratedValue>
                  <name>0</name>
                  <description>Low drive strength is configured on the corresponding pin, if pin is configured as a digital output.</description>
                  <value>#0</value>
                </enumeratedValue>
                <enumeratedValue>
                  <name>1</name>
                  <description>High drive strength is configured on the corresponding pin, if pin is configured as a digital output.</description>
                  <value>#1</value>
                </enumeratedValue>
              </enumeratedValues>
            </field>
            <field>
              <name>MUX</name>
              <description>Pin Mux Control</description>
              <bitOffset>8</bitOffset>
              <bitWidth>3</bitWidth>
              <access>read-write</access>
              <enumeratedValues>
                <enumeratedValue>
                  <name>000</name>
                  <description>Pin disabled (analog).</description>
                  <value>#000</value>
                </enumeratedValue>
                <enumeratedValue>
                  <name>001</name>
                  <description>Alternative 1 (GPIO).</description>
                  <value>#001</value>
                </enumeratedValue>
                <enumeratedValue>
                  <name>010</name>
                  <description>Alternative 2 (chip-specific).</description>
                  <value>#010</value>
                </enumeratedValue>
                <enumeratedValue>
                  <name>011</name>
                  <description>Alternative 3 (chip-specific).</description>
                  <value>#011</value>
                </enumeratedValue>
                <enumeratedValue>
                  <name>100</name>
                  <description>Alternative 4 (chip-specific).</description>
                  <value>#100</value>
                </enumeratedValue>
                <enumeratedValue>
                  <name>101</name>
                  <description>Alternative 5 (chip-specific).</description>
                  <value>#101</value>
                </enumeratedValue>
                <enumeratedValue>
                  <name>110</name>
                  <description>Alternative 6 (chip-specific).</description>
                  <value>#110</value>
                </enumeratedValue>
                <enumeratedValue>
                  <name>111</name>
                  <description>Alternative 7 (chip-specific).</description>
                  <value>#111</value>
                </enumeratedValue>
              </enumeratedValues>
            </field>
            <field>
              <name>IRQC</name>
              <description>Interrupt Configuration</description>
              <bitOffset>16</bitOffset>
              <bitWidth>4</bitWidth>
              <access>read-write</access>
              <enumeratedValues>
                <enumeratedValue>
                  <name>0000</name>
                  <description>Interrupt/DMA request disabled.</description>
                  <value>#0000</value>
                </enumeratedValue>
                <enumeratedValue>
                  <name>0001</name>
                  <description>DMA request on rising edge.</description>
                  <value>#0001</value>
                </enumeratedValue>
                <enumeratedValue>
                  <name>0010</name>
                  <description>DMA request on falling edge.</description>
                  <value>#0010</value>
                </enumeratedValue>
                <enumeratedValue>
                  <name>0011</name>
                  <description>DMA request on either edge.</description>
                  <value>#0011</value>
                </enumeratedValue>
                <enumeratedValue>
                  <name>1000</name>
                  <description>Interrupt when logic 0.</description>
                  <value>#1000</value>
                </enumeratedValue>
                <enumeratedValue>
                  <name>1001</name>
                  <description>Interrupt on rising-edge.</description>
                  <value>#1001</value>
                </enumeratedValue>
                <enumeratedValue>
                  <name>1010</name>
                  <description>Interrupt on falling-edge.</description>
                  <value>#1010</value>
                </enumeratedValue>
                <enumeratedValue>
                  <name>1011</name>
                  <description>Interrupt on either edge.</description>
                  <value>#1011</value>
                </enumeratedValue>
                <enumeratedValue>
                  <name>1100</name>
                  <description>Interrupt when logic 1.</description>
                  <value>#1100</value>
                </enumeratedValue>
              </enumeratedValues>
            </field>
            <field>
              <name>ISF</name>
              <description>Interrupt Status Flag</description>
              <bitOffset>24</bitOffset>
              <bitWidth>1</bitWidth>
              <access>read-write</access>
              <enumeratedValues>
                <enumeratedValue>
                  <name>0</name>
                  <description>Configured interrupt is not detected.</description>
                  <value>#0</value>
                </enumeratedValue>
                <enumeratedValue>
                  <name>1</name>
                  <description>Configured interrupt is detected. If the pin is configured to generate a DMA request, then the corresponding flag will be cleared automatically at the completion of the requested DMA transfer. Otherwise, the flag remains set until a logic 1 is written to the flag. If the pin is configured for a level sensitive interrupt and the pin remains asserted, then the flag is set again immediately after it is cleared.</description>
                  <value>#1</value>
                </enumeratedValue>
              </enumeratedValues>
            </field>
          </fields>
        </register>
        <register>
          <name>PCR26</name>
          <description>Pin Control Register n</description>
          <addressOffset>0x68</addressOffset>
          <size>32</size>
          <access>read-write</access>
          <resetValue>0</resetValue>
          <resetMask>0xFFFFFFFF</resetMask>
          <fields>
            <field>
              <name>PS</name>
              <description>Pull Select</description>
              <bitOffset>0</bitOffset>
              <bitWidth>1</bitWidth>
              <access>read-only</access>
              <enumeratedValues>
                <enumeratedValue>
                  <name>0</name>
                  <description>Internal pulldown resistor is enabled on the corresponding pin, if the corresponding PE field is set.</description>
                  <value>#0</value>
                </enumeratedValue>
                <enumeratedValue>
                  <name>1</name>
                  <description>Internal pullup resistor is enabled on the corresponding pin, if the corresponding PE field is set.</description>
                  <value>#1</value>
                </enumeratedValue>
              </enumeratedValues>
            </field>
            <field>
              <name>PE</name>
              <description>Pull Enable</description>
              <bitOffset>1</bitOffset>
              <bitWidth>1</bitWidth>
              <access>read-only</access>
              <enumeratedValues>
                <enumeratedValue>
                  <name>0</name>
                  <description>Internal pullup or pulldown resistor is not enabled on the corresponding pin.</description>
                  <value>#0</value>
                </enumeratedValue>
                <enumeratedValue>
                  <name>1</name>
                  <description>Internal pullup or pulldown resistor is enabled on the corresponding pin, if the pin is configured as a digital input.</description>
                  <value>#1</value>
                </enumeratedValue>
              </enumeratedValues>
            </field>
            <field>
              <name>SRE</name>
              <description>Slew Rate Enable</description>
              <bitOffset>2</bitOffset>
              <bitWidth>1</bitWidth>
              <access>read-only</access>
              <enumeratedValues>
                <enumeratedValue>
                  <name>0</name>
                  <description>Fast slew rate is configured on the corresponding pin, if the pin is configured as a digital output.</description>
                  <value>#0</value>
                </enumeratedValue>
                <enumeratedValue>
                  <name>1</name>
                  <description>Slow slew rate is configured on the corresponding pin, if the pin is configured as a digital output.</description>
                  <value>#1</value>
                </enumeratedValue>
              </enumeratedValues>
            </field>
            <field>
              <name>PFE</name>
              <description>Passive Filter Enable</description>
              <bitOffset>4</bitOffset>
              <bitWidth>1</bitWidth>
              <access>read-only</access>
              <enumeratedValues>
                <enumeratedValue>
                  <name>0</name>
                  <description>Passive input filter is disabled on the corresponding pin.</description>
                  <value>#0</value>
                </enumeratedValue>
                <enumeratedValue>
                  <name>1</name>
                  <description>Passive input filter is enabled on the corresponding pin, if the pin is configured as a digital input. Refer to the device data sheet for filter characteristics.</description>
                  <value>#1</value>
                </enumeratedValue>
              </enumeratedValues>
            </field>
            <field>
              <name>DSE</name>
              <description>Drive Strength Enable</description>
              <bitOffset>6</bitOffset>
              <bitWidth>1</bitWidth>
              <access>read-only</access>
              <enumeratedValues>
                <enumeratedValue>
                  <name>0</name>
                  <description>Low drive strength is configured on the corresponding pin, if pin is configured as a digital output.</description>
                  <value>#0</value>
                </enumeratedValue>
                <enumeratedValue>
                  <name>1</name>
                  <description>High drive strength is configured on the corresponding pin, if pin is configured as a digital output.</description>
                  <value>#1</value>
                </enumeratedValue>
              </enumeratedValues>
            </field>
            <field>
              <name>MUX</name>
              <description>Pin Mux Control</description>
              <bitOffset>8</bitOffset>
              <bitWidth>3</bitWidth>
              <access>read-write</access>
              <enumeratedValues>
                <enumeratedValue>
                  <name>000</name>
                  <description>Pin disabled (analog).</description>
                  <value>#000</value>
                </enumeratedValue>
                <enumeratedValue>
                  <name>001</name>
                  <description>Alternative 1 (GPIO).</description>
                  <value>#001</value>
                </enumeratedValue>
                <enumeratedValue>
                  <name>010</name>
                  <description>Alternative 2 (chip-specific).</description>
                  <value>#010</value>
                </enumeratedValue>
                <enumeratedValue>
                  <name>011</name>
                  <description>Alternative 3 (chip-specific).</description>
                  <value>#011</value>
                </enumeratedValue>
                <enumeratedValue>
                  <name>100</name>
                  <description>Alternative 4 (chip-specific).</description>
                  <value>#100</value>
                </enumeratedValue>
                <enumeratedValue>
                  <name>101</name>
                  <description>Alternative 5 (chip-specific).</description>
                  <value>#101</value>
                </enumeratedValue>
                <enumeratedValue>
                  <name>110</name>
                  <description>Alternative 6 (chip-specific).</description>
                  <value>#110</value>
                </enumeratedValue>
                <enumeratedValue>
                  <name>111</name>
                  <description>Alternative 7 (chip-specific).</description>
                  <value>#111</value>
                </enumeratedValue>
              </enumeratedValues>
            </field>
            <field>
              <name>IRQC</name>
              <description>Interrupt Configuration</description>
              <bitOffset>16</bitOffset>
              <bitWidth>4</bitWidth>
              <access>read-write</access>
              <enumeratedValues>
                <enumeratedValue>
                  <name>0000</name>
                  <description>Interrupt/DMA request disabled.</description>
                  <value>#0000</value>
                </enumeratedValue>
                <enumeratedValue>
                  <name>0001</name>
                  <description>DMA request on rising edge.</description>
                  <value>#0001</value>
                </enumeratedValue>
                <enumeratedValue>
                  <name>0010</name>
                  <description>DMA request on falling edge.</description>
                  <value>#0010</value>
                </enumeratedValue>
                <enumeratedValue>
                  <name>0011</name>
                  <description>DMA request on either edge.</description>
                  <value>#0011</value>
                </enumeratedValue>
                <enumeratedValue>
                  <name>1000</name>
                  <description>Interrupt when logic 0.</description>
                  <value>#1000</value>
                </enumeratedValue>
                <enumeratedValue>
                  <name>1001</name>
                  <description>Interrupt on rising-edge.</description>
                  <value>#1001</value>
                </enumeratedValue>
                <enumeratedValue>
                  <name>1010</name>
                  <description>Interrupt on falling-edge.</description>
                  <value>#1010</value>
                </enumeratedValue>
                <enumeratedValue>
                  <name>1011</name>
                  <description>Interrupt on either edge.</description>
                  <value>#1011</value>
                </enumeratedValue>
                <enumeratedValue>
                  <name>1100</name>
                  <description>Interrupt when logic 1.</description>
                  <value>#1100</value>
                </enumeratedValue>
              </enumeratedValues>
            </field>
            <field>
              <name>ISF</name>
              <description>Interrupt Status Flag</description>
              <bitOffset>24</bitOffset>
              <bitWidth>1</bitWidth>
              <access>read-write</access>
              <enumeratedValues>
                <enumeratedValue>
                  <name>0</name>
                  <description>Configured interrupt is not detected.</description>
                  <value>#0</value>
                </enumeratedValue>
                <enumeratedValue>
                  <name>1</name>
                  <description>Configured interrupt is detected. If the pin is configured to generate a DMA request, then the corresponding flag will be cleared automatically at the completion of the requested DMA transfer. Otherwise, the flag remains set until a logic 1 is written to the flag. If the pin is configured for a level sensitive interrupt and the pin remains asserted, then the flag is set again immediately after it is cleared.</description>
                  <value>#1</value>
                </enumeratedValue>
              </enumeratedValues>
            </field>
          </fields>
        </register>
        <register>
          <name>PCR27</name>
          <description>Pin Control Register n</description>
          <addressOffset>0x6C</addressOffset>
          <size>32</size>
          <access>read-write</access>
          <resetValue>0</resetValue>
          <resetMask>0xFFFFFFFF</resetMask>
          <fields>
            <field>
              <name>PS</name>
              <description>Pull Select</description>
              <bitOffset>0</bitOffset>
              <bitWidth>1</bitWidth>
              <access>read-only</access>
              <enumeratedValues>
                <enumeratedValue>
                  <name>0</name>
                  <description>Internal pulldown resistor is enabled on the corresponding pin, if the corresponding PE field is set.</description>
                  <value>#0</value>
                </enumeratedValue>
                <enumeratedValue>
                  <name>1</name>
                  <description>Internal pullup resistor is enabled on the corresponding pin, if the corresponding PE field is set.</description>
                  <value>#1</value>
                </enumeratedValue>
              </enumeratedValues>
            </field>
            <field>
              <name>PE</name>
              <description>Pull Enable</description>
              <bitOffset>1</bitOffset>
              <bitWidth>1</bitWidth>
              <access>read-only</access>
              <enumeratedValues>
                <enumeratedValue>
                  <name>0</name>
                  <description>Internal pullup or pulldown resistor is not enabled on the corresponding pin.</description>
                  <value>#0</value>
                </enumeratedValue>
                <enumeratedValue>
                  <name>1</name>
                  <description>Internal pullup or pulldown resistor is enabled on the corresponding pin, if the pin is configured as a digital input.</description>
                  <value>#1</value>
                </enumeratedValue>
              </enumeratedValues>
            </field>
            <field>
              <name>SRE</name>
              <description>Slew Rate Enable</description>
              <bitOffset>2</bitOffset>
              <bitWidth>1</bitWidth>
              <access>read-only</access>
              <enumeratedValues>
                <enumeratedValue>
                  <name>0</name>
                  <description>Fast slew rate is configured on the corresponding pin, if the pin is configured as a digital output.</description>
                  <value>#0</value>
                </enumeratedValue>
                <enumeratedValue>
                  <name>1</name>
                  <description>Slow slew rate is configured on the corresponding pin, if the pin is configured as a digital output.</description>
                  <value>#1</value>
                </enumeratedValue>
              </enumeratedValues>
            </field>
            <field>
              <name>PFE</name>
              <description>Passive Filter Enable</description>
              <bitOffset>4</bitOffset>
              <bitWidth>1</bitWidth>
              <access>read-only</access>
              <enumeratedValues>
                <enumeratedValue>
                  <name>0</name>
                  <description>Passive input filter is disabled on the corresponding pin.</description>
                  <value>#0</value>
                </enumeratedValue>
                <enumeratedValue>
                  <name>1</name>
                  <description>Passive input filter is enabled on the corresponding pin, if the pin is configured as a digital input. Refer to the device data sheet for filter characteristics.</description>
                  <value>#1</value>
                </enumeratedValue>
              </enumeratedValues>
            </field>
            <field>
              <name>DSE</name>
              <description>Drive Strength Enable</description>
              <bitOffset>6</bitOffset>
              <bitWidth>1</bitWidth>
              <access>read-only</access>
              <enumeratedValues>
                <enumeratedValue>
                  <name>0</name>
                  <description>Low drive strength is configured on the corresponding pin, if pin is configured as a digital output.</description>
                  <value>#0</value>
                </enumeratedValue>
                <enumeratedValue>
                  <name>1</name>
                  <description>High drive strength is configured on the corresponding pin, if pin is configured as a digital output.</description>
                  <value>#1</value>
                </enumeratedValue>
              </enumeratedValues>
            </field>
            <field>
              <name>MUX</name>
              <description>Pin Mux Control</description>
              <bitOffset>8</bitOffset>
              <bitWidth>3</bitWidth>
              <access>read-write</access>
              <enumeratedValues>
                <enumeratedValue>
                  <name>000</name>
                  <description>Pin disabled (analog).</description>
                  <value>#000</value>
                </enumeratedValue>
                <enumeratedValue>
                  <name>001</name>
                  <description>Alternative 1 (GPIO).</description>
                  <value>#001</value>
                </enumeratedValue>
                <enumeratedValue>
                  <name>010</name>
                  <description>Alternative 2 (chip-specific).</description>
                  <value>#010</value>
                </enumeratedValue>
                <enumeratedValue>
                  <name>011</name>
                  <description>Alternative 3 (chip-specific).</description>
                  <value>#011</value>
                </enumeratedValue>
                <enumeratedValue>
                  <name>100</name>
                  <description>Alternative 4 (chip-specific).</description>
                  <value>#100</value>
                </enumeratedValue>
                <enumeratedValue>
                  <name>101</name>
                  <description>Alternative 5 (chip-specific).</description>
                  <value>#101</value>
                </enumeratedValue>
                <enumeratedValue>
                  <name>110</name>
                  <description>Alternative 6 (chip-specific).</description>
                  <value>#110</value>
                </enumeratedValue>
                <enumeratedValue>
                  <name>111</name>
                  <description>Alternative 7 (chip-specific).</description>
                  <value>#111</value>
                </enumeratedValue>
              </enumeratedValues>
            </field>
            <field>
              <name>IRQC</name>
              <description>Interrupt Configuration</description>
              <bitOffset>16</bitOffset>
              <bitWidth>4</bitWidth>
              <access>read-write</access>
              <enumeratedValues>
                <enumeratedValue>
                  <name>0000</name>
                  <description>Interrupt/DMA request disabled.</description>
                  <value>#0000</value>
                </enumeratedValue>
                <enumeratedValue>
                  <name>0001</name>
                  <description>DMA request on rising edge.</description>
                  <value>#0001</value>
                </enumeratedValue>
                <enumeratedValue>
                  <name>0010</name>
                  <description>DMA request on falling edge.</description>
                  <value>#0010</value>
                </enumeratedValue>
                <enumeratedValue>
                  <name>0011</name>
                  <description>DMA request on either edge.</description>
                  <value>#0011</value>
                </enumeratedValue>
                <enumeratedValue>
                  <name>1000</name>
                  <description>Interrupt when logic 0.</description>
                  <value>#1000</value>
                </enumeratedValue>
                <enumeratedValue>
                  <name>1001</name>
                  <description>Interrupt on rising-edge.</description>
                  <value>#1001</value>
                </enumeratedValue>
                <enumeratedValue>
                  <name>1010</name>
                  <description>Interrupt on falling-edge.</description>
                  <value>#1010</value>
                </enumeratedValue>
                <enumeratedValue>
                  <name>1011</name>
                  <description>Interrupt on either edge.</description>
                  <value>#1011</value>
                </enumeratedValue>
                <enumeratedValue>
                  <name>1100</name>
                  <description>Interrupt when logic 1.</description>
                  <value>#1100</value>
                </enumeratedValue>
              </enumeratedValues>
            </field>
            <field>
              <name>ISF</name>
              <description>Interrupt Status Flag</description>
              <bitOffset>24</bitOffset>
              <bitWidth>1</bitWidth>
              <access>read-write</access>
              <enumeratedValues>
                <enumeratedValue>
                  <name>0</name>
                  <description>Configured interrupt is not detected.</description>
                  <value>#0</value>
                </enumeratedValue>
                <enumeratedValue>
                  <name>1</name>
                  <description>Configured interrupt is detected. If the pin is configured to generate a DMA request, then the corresponding flag will be cleared automatically at the completion of the requested DMA transfer. Otherwise, the flag remains set until a logic 1 is written to the flag. If the pin is configured for a level sensitive interrupt and the pin remains asserted, then the flag is set again immediately after it is cleared.</description>
                  <value>#1</value>
                </enumeratedValue>
              </enumeratedValues>
            </field>
          </fields>
        </register>
        <register>
          <name>PCR28</name>
          <description>Pin Control Register n</description>
          <addressOffset>0x70</addressOffset>
          <size>32</size>
          <access>read-write</access>
          <resetValue>0</resetValue>
          <resetMask>0xFFFFFFFF</resetMask>
          <fields>
            <field>
              <name>PS</name>
              <description>Pull Select</description>
              <bitOffset>0</bitOffset>
              <bitWidth>1</bitWidth>
              <access>read-only</access>
              <enumeratedValues>
                <enumeratedValue>
                  <name>0</name>
                  <description>Internal pulldown resistor is enabled on the corresponding pin, if the corresponding PE field is set.</description>
                  <value>#0</value>
                </enumeratedValue>
                <enumeratedValue>
                  <name>1</name>
                  <description>Internal pullup resistor is enabled on the corresponding pin, if the corresponding PE field is set.</description>
                  <value>#1</value>
                </enumeratedValue>
              </enumeratedValues>
            </field>
            <field>
              <name>PE</name>
              <description>Pull Enable</description>
              <bitOffset>1</bitOffset>
              <bitWidth>1</bitWidth>
              <access>read-only</access>
              <enumeratedValues>
                <enumeratedValue>
                  <name>0</name>
                  <description>Internal pullup or pulldown resistor is not enabled on the corresponding pin.</description>
                  <value>#0</value>
                </enumeratedValue>
                <enumeratedValue>
                  <name>1</name>
                  <description>Internal pullup or pulldown resistor is enabled on the corresponding pin, if the pin is configured as a digital input.</description>
                  <value>#1</value>
                </enumeratedValue>
              </enumeratedValues>
            </field>
            <field>
              <name>SRE</name>
              <description>Slew Rate Enable</description>
              <bitOffset>2</bitOffset>
              <bitWidth>1</bitWidth>
              <access>read-only</access>
              <enumeratedValues>
                <enumeratedValue>
                  <name>0</name>
                  <description>Fast slew rate is configured on the corresponding pin, if the pin is configured as a digital output.</description>
                  <value>#0</value>
                </enumeratedValue>
                <enumeratedValue>
                  <name>1</name>
                  <description>Slow slew rate is configured on the corresponding pin, if the pin is configured as a digital output.</description>
                  <value>#1</value>
                </enumeratedValue>
              </enumeratedValues>
            </field>
            <field>
              <name>PFE</name>
              <description>Passive Filter Enable</description>
              <bitOffset>4</bitOffset>
              <bitWidth>1</bitWidth>
              <access>read-only</access>
              <enumeratedValues>
                <enumeratedValue>
                  <name>0</name>
                  <description>Passive input filter is disabled on the corresponding pin.</description>
                  <value>#0</value>
                </enumeratedValue>
                <enumeratedValue>
                  <name>1</name>
                  <description>Passive input filter is enabled on the corresponding pin, if the pin is configured as a digital input. Refer to the device data sheet for filter characteristics.</description>
                  <value>#1</value>
                </enumeratedValue>
              </enumeratedValues>
            </field>
            <field>
              <name>DSE</name>
              <description>Drive Strength Enable</description>
              <bitOffset>6</bitOffset>
              <bitWidth>1</bitWidth>
              <access>read-only</access>
              <enumeratedValues>
                <enumeratedValue>
                  <name>0</name>
                  <description>Low drive strength is configured on the corresponding pin, if pin is configured as a digital output.</description>
                  <value>#0</value>
                </enumeratedValue>
                <enumeratedValue>
                  <name>1</name>
                  <description>High drive strength is configured on the corresponding pin, if pin is configured as a digital output.</description>
                  <value>#1</value>
                </enumeratedValue>
              </enumeratedValues>
            </field>
            <field>
              <name>MUX</name>
              <description>Pin Mux Control</description>
              <bitOffset>8</bitOffset>
              <bitWidth>3</bitWidth>
              <access>read-write</access>
              <enumeratedValues>
                <enumeratedValue>
                  <name>000</name>
                  <description>Pin disabled (analog).</description>
                  <value>#000</value>
                </enumeratedValue>
                <enumeratedValue>
                  <name>001</name>
                  <description>Alternative 1 (GPIO).</description>
                  <value>#001</value>
                </enumeratedValue>
                <enumeratedValue>
                  <name>010</name>
                  <description>Alternative 2 (chip-specific).</description>
                  <value>#010</value>
                </enumeratedValue>
                <enumeratedValue>
                  <name>011</name>
                  <description>Alternative 3 (chip-specific).</description>
                  <value>#011</value>
                </enumeratedValue>
                <enumeratedValue>
                  <name>100</name>
                  <description>Alternative 4 (chip-specific).</description>
                  <value>#100</value>
                </enumeratedValue>
                <enumeratedValue>
                  <name>101</name>
                  <description>Alternative 5 (chip-specific).</description>
                  <value>#101</value>
                </enumeratedValue>
                <enumeratedValue>
                  <name>110</name>
                  <description>Alternative 6 (chip-specific).</description>
                  <value>#110</value>
                </enumeratedValue>
                <enumeratedValue>
                  <name>111</name>
                  <description>Alternative 7 (chip-specific).</description>
                  <value>#111</value>
                </enumeratedValue>
              </enumeratedValues>
            </field>
            <field>
              <name>IRQC</name>
              <description>Interrupt Configuration</description>
              <bitOffset>16</bitOffset>
              <bitWidth>4</bitWidth>
              <access>read-write</access>
              <enumeratedValues>
                <enumeratedValue>
                  <name>0000</name>
                  <description>Interrupt/DMA request disabled.</description>
                  <value>#0000</value>
                </enumeratedValue>
                <enumeratedValue>
                  <name>0001</name>
                  <description>DMA request on rising edge.</description>
                  <value>#0001</value>
                </enumeratedValue>
                <enumeratedValue>
                  <name>0010</name>
                  <description>DMA request on falling edge.</description>
                  <value>#0010</value>
                </enumeratedValue>
                <enumeratedValue>
                  <name>0011</name>
                  <description>DMA request on either edge.</description>
                  <value>#0011</value>
                </enumeratedValue>
                <enumeratedValue>
                  <name>1000</name>
                  <description>Interrupt when logic 0.</description>
                  <value>#1000</value>
                </enumeratedValue>
                <enumeratedValue>
                  <name>1001</name>
                  <description>Interrupt on rising-edge.</description>
                  <value>#1001</value>
                </enumeratedValue>
                <enumeratedValue>
                  <name>1010</name>
                  <description>Interrupt on falling-edge.</description>
                  <value>#1010</value>
                </enumeratedValue>
                <enumeratedValue>
                  <name>1011</name>
                  <description>Interrupt on either edge.</description>
                  <value>#1011</value>
                </enumeratedValue>
                <enumeratedValue>
                  <name>1100</name>
                  <description>Interrupt when logic 1.</description>
                  <value>#1100</value>
                </enumeratedValue>
              </enumeratedValues>
            </field>
            <field>
              <name>ISF</name>
              <description>Interrupt Status Flag</description>
              <bitOffset>24</bitOffset>
              <bitWidth>1</bitWidth>
              <access>read-write</access>
              <enumeratedValues>
                <enumeratedValue>
                  <name>0</name>
                  <description>Configured interrupt is not detected.</description>
                  <value>#0</value>
                </enumeratedValue>
                <enumeratedValue>
                  <name>1</name>
                  <description>Configured interrupt is detected. If the pin is configured to generate a DMA request, then the corresponding flag will be cleared automatically at the completion of the requested DMA transfer. Otherwise, the flag remains set until a logic 1 is written to the flag. If the pin is configured for a level sensitive interrupt and the pin remains asserted, then the flag is set again immediately after it is cleared.</description>
                  <value>#1</value>
                </enumeratedValue>
              </enumeratedValues>
            </field>
          </fields>
        </register>
        <register>
          <name>PCR29</name>
          <description>Pin Control Register n</description>
          <addressOffset>0x74</addressOffset>
          <size>32</size>
          <access>read-write</access>
          <resetValue>0</resetValue>
          <resetMask>0xFFFFFFFF</resetMask>
          <fields>
            <field>
              <name>PS</name>
              <description>Pull Select</description>
              <bitOffset>0</bitOffset>
              <bitWidth>1</bitWidth>
              <access>read-only</access>
              <enumeratedValues>
                <enumeratedValue>
                  <name>0</name>
                  <description>Internal pulldown resistor is enabled on the corresponding pin, if the corresponding PE field is set.</description>
                  <value>#0</value>
                </enumeratedValue>
                <enumeratedValue>
                  <name>1</name>
                  <description>Internal pullup resistor is enabled on the corresponding pin, if the corresponding PE field is set.</description>
                  <value>#1</value>
                </enumeratedValue>
              </enumeratedValues>
            </field>
            <field>
              <name>PE</name>
              <description>Pull Enable</description>
              <bitOffset>1</bitOffset>
              <bitWidth>1</bitWidth>
              <access>read-only</access>
              <enumeratedValues>
                <enumeratedValue>
                  <name>0</name>
                  <description>Internal pullup or pulldown resistor is not enabled on the corresponding pin.</description>
                  <value>#0</value>
                </enumeratedValue>
                <enumeratedValue>
                  <name>1</name>
                  <description>Internal pullup or pulldown resistor is enabled on the corresponding pin, if the pin is configured as a digital input.</description>
                  <value>#1</value>
                </enumeratedValue>
              </enumeratedValues>
            </field>
            <field>
              <name>SRE</name>
              <description>Slew Rate Enable</description>
              <bitOffset>2</bitOffset>
              <bitWidth>1</bitWidth>
              <access>read-only</access>
              <enumeratedValues>
                <enumeratedValue>
                  <name>0</name>
                  <description>Fast slew rate is configured on the corresponding pin, if the pin is configured as a digital output.</description>
                  <value>#0</value>
                </enumeratedValue>
                <enumeratedValue>
                  <name>1</name>
                  <description>Slow slew rate is configured on the corresponding pin, if the pin is configured as a digital output.</description>
                  <value>#1</value>
                </enumeratedValue>
              </enumeratedValues>
            </field>
            <field>
              <name>PFE</name>
              <description>Passive Filter Enable</description>
              <bitOffset>4</bitOffset>
              <bitWidth>1</bitWidth>
              <access>read-only</access>
              <enumeratedValues>
                <enumeratedValue>
                  <name>0</name>
                  <description>Passive input filter is disabled on the corresponding pin.</description>
                  <value>#0</value>
                </enumeratedValue>
                <enumeratedValue>
                  <name>1</name>
                  <description>Passive input filter is enabled on the corresponding pin, if the pin is configured as a digital input. Refer to the device data sheet for filter characteristics.</description>
                  <value>#1</value>
                </enumeratedValue>
              </enumeratedValues>
            </field>
            <field>
              <name>DSE</name>
              <description>Drive Strength Enable</description>
              <bitOffset>6</bitOffset>
              <bitWidth>1</bitWidth>
              <access>read-only</access>
              <enumeratedValues>
                <enumeratedValue>
                  <name>0</name>
                  <description>Low drive strength is configured on the corresponding pin, if pin is configured as a digital output.</description>
                  <value>#0</value>
                </enumeratedValue>
                <enumeratedValue>
                  <name>1</name>
                  <description>High drive strength is configured on the corresponding pin, if pin is configured as a digital output.</description>
                  <value>#1</value>
                </enumeratedValue>
              </enumeratedValues>
            </field>
            <field>
              <name>MUX</name>
              <description>Pin Mux Control</description>
              <bitOffset>8</bitOffset>
              <bitWidth>3</bitWidth>
              <access>read-write</access>
              <enumeratedValues>
                <enumeratedValue>
                  <name>000</name>
                  <description>Pin disabled (analog).</description>
                  <value>#000</value>
                </enumeratedValue>
                <enumeratedValue>
                  <name>001</name>
                  <description>Alternative 1 (GPIO).</description>
                  <value>#001</value>
                </enumeratedValue>
                <enumeratedValue>
                  <name>010</name>
                  <description>Alternative 2 (chip-specific).</description>
                  <value>#010</value>
                </enumeratedValue>
                <enumeratedValue>
                  <name>011</name>
                  <description>Alternative 3 (chip-specific).</description>
                  <value>#011</value>
                </enumeratedValue>
                <enumeratedValue>
                  <name>100</name>
                  <description>Alternative 4 (chip-specific).</description>
                  <value>#100</value>
                </enumeratedValue>
                <enumeratedValue>
                  <name>101</name>
                  <description>Alternative 5 (chip-specific).</description>
                  <value>#101</value>
                </enumeratedValue>
                <enumeratedValue>
                  <name>110</name>
                  <description>Alternative 6 (chip-specific).</description>
                  <value>#110</value>
                </enumeratedValue>
                <enumeratedValue>
                  <name>111</name>
                  <description>Alternative 7 (chip-specific).</description>
                  <value>#111</value>
                </enumeratedValue>
              </enumeratedValues>
            </field>
            <field>
              <name>IRQC</name>
              <description>Interrupt Configuration</description>
              <bitOffset>16</bitOffset>
              <bitWidth>4</bitWidth>
              <access>read-write</access>
              <enumeratedValues>
                <enumeratedValue>
                  <name>0000</name>
                  <description>Interrupt/DMA request disabled.</description>
                  <value>#0000</value>
                </enumeratedValue>
                <enumeratedValue>
                  <name>0001</name>
                  <description>DMA request on rising edge.</description>
                  <value>#0001</value>
                </enumeratedValue>
                <enumeratedValue>
                  <name>0010</name>
                  <description>DMA request on falling edge.</description>
                  <value>#0010</value>
                </enumeratedValue>
                <enumeratedValue>
                  <name>0011</name>
                  <description>DMA request on either edge.</description>
                  <value>#0011</value>
                </enumeratedValue>
                <enumeratedValue>
                  <name>1000</name>
                  <description>Interrupt when logic 0.</description>
                  <value>#1000</value>
                </enumeratedValue>
                <enumeratedValue>
                  <name>1001</name>
                  <description>Interrupt on rising-edge.</description>
                  <value>#1001</value>
                </enumeratedValue>
                <enumeratedValue>
                  <name>1010</name>
                  <description>Interrupt on falling-edge.</description>
                  <value>#1010</value>
                </enumeratedValue>
                <enumeratedValue>
                  <name>1011</name>
                  <description>Interrupt on either edge.</description>
                  <value>#1011</value>
                </enumeratedValue>
                <enumeratedValue>
                  <name>1100</name>
                  <description>Interrupt when logic 1.</description>
                  <value>#1100</value>
                </enumeratedValue>
              </enumeratedValues>
            </field>
            <field>
              <name>ISF</name>
              <description>Interrupt Status Flag</description>
              <bitOffset>24</bitOffset>
              <bitWidth>1</bitWidth>
              <access>read-write</access>
              <enumeratedValues>
                <enumeratedValue>
                  <name>0</name>
                  <description>Configured interrupt is not detected.</description>
                  <value>#0</value>
                </enumeratedValue>
                <enumeratedValue>
                  <name>1</name>
                  <description>Configured interrupt is detected. If the pin is configured to generate a DMA request, then the corresponding flag will be cleared automatically at the completion of the requested DMA transfer. Otherwise, the flag remains set until a logic 1 is written to the flag. If the pin is configured for a level sensitive interrupt and the pin remains asserted, then the flag is set again immediately after it is cleared.</description>
                  <value>#1</value>
                </enumeratedValue>
              </enumeratedValues>
            </field>
          </fields>
        </register>
        <register>
          <name>PCR30</name>
          <description>Pin Control Register n</description>
          <addressOffset>0x78</addressOffset>
          <size>32</size>
          <access>read-write</access>
          <resetValue>0</resetValue>
          <resetMask>0xFFFFFFFF</resetMask>
          <fields>
            <field>
              <name>PS</name>
              <description>Pull Select</description>
              <bitOffset>0</bitOffset>
              <bitWidth>1</bitWidth>
              <access>read-only</access>
              <enumeratedValues>
                <enumeratedValue>
                  <name>0</name>
                  <description>Internal pulldown resistor is enabled on the corresponding pin, if the corresponding PE field is set.</description>
                  <value>#0</value>
                </enumeratedValue>
                <enumeratedValue>
                  <name>1</name>
                  <description>Internal pullup resistor is enabled on the corresponding pin, if the corresponding PE field is set.</description>
                  <value>#1</value>
                </enumeratedValue>
              </enumeratedValues>
            </field>
            <field>
              <name>PE</name>
              <description>Pull Enable</description>
              <bitOffset>1</bitOffset>
              <bitWidth>1</bitWidth>
              <access>read-only</access>
              <enumeratedValues>
                <enumeratedValue>
                  <name>0</name>
                  <description>Internal pullup or pulldown resistor is not enabled on the corresponding pin.</description>
                  <value>#0</value>
                </enumeratedValue>
                <enumeratedValue>
                  <name>1</name>
                  <description>Internal pullup or pulldown resistor is enabled on the corresponding pin, if the pin is configured as a digital input.</description>
                  <value>#1</value>
                </enumeratedValue>
              </enumeratedValues>
            </field>
            <field>
              <name>SRE</name>
              <description>Slew Rate Enable</description>
              <bitOffset>2</bitOffset>
              <bitWidth>1</bitWidth>
              <access>read-only</access>
              <enumeratedValues>
                <enumeratedValue>
                  <name>0</name>
                  <description>Fast slew rate is configured on the corresponding pin, if the pin is configured as a digital output.</description>
                  <value>#0</value>
                </enumeratedValue>
                <enumeratedValue>
                  <name>1</name>
                  <description>Slow slew rate is configured on the corresponding pin, if the pin is configured as a digital output.</description>
                  <value>#1</value>
                </enumeratedValue>
              </enumeratedValues>
            </field>
            <field>
              <name>PFE</name>
              <description>Passive Filter Enable</description>
              <bitOffset>4</bitOffset>
              <bitWidth>1</bitWidth>
              <access>read-only</access>
              <enumeratedValues>
                <enumeratedValue>
                  <name>0</name>
                  <description>Passive input filter is disabled on the corresponding pin.</description>
                  <value>#0</value>
                </enumeratedValue>
                <enumeratedValue>
                  <name>1</name>
                  <description>Passive input filter is enabled on the corresponding pin, if the pin is configured as a digital input. Refer to the device data sheet for filter characteristics.</description>
                  <value>#1</value>
                </enumeratedValue>
              </enumeratedValues>
            </field>
            <field>
              <name>DSE</name>
              <description>Drive Strength Enable</description>
              <bitOffset>6</bitOffset>
              <bitWidth>1</bitWidth>
              <access>read-only</access>
              <enumeratedValues>
                <enumeratedValue>
                  <name>0</name>
                  <description>Low drive strength is configured on the corresponding pin, if pin is configured as a digital output.</description>
                  <value>#0</value>
                </enumeratedValue>
                <enumeratedValue>
                  <name>1</name>
                  <description>High drive strength is configured on the corresponding pin, if pin is configured as a digital output.</description>
                  <value>#1</value>
                </enumeratedValue>
              </enumeratedValues>
            </field>
            <field>
              <name>MUX</name>
              <description>Pin Mux Control</description>
              <bitOffset>8</bitOffset>
              <bitWidth>3</bitWidth>
              <access>read-write</access>
              <enumeratedValues>
                <enumeratedValue>
                  <name>000</name>
                  <description>Pin disabled (analog).</description>
                  <value>#000</value>
                </enumeratedValue>
                <enumeratedValue>
                  <name>001</name>
                  <description>Alternative 1 (GPIO).</description>
                  <value>#001</value>
                </enumeratedValue>
                <enumeratedValue>
                  <name>010</name>
                  <description>Alternative 2 (chip-specific).</description>
                  <value>#010</value>
                </enumeratedValue>
                <enumeratedValue>
                  <name>011</name>
                  <description>Alternative 3 (chip-specific).</description>
                  <value>#011</value>
                </enumeratedValue>
                <enumeratedValue>
                  <name>100</name>
                  <description>Alternative 4 (chip-specific).</description>
                  <value>#100</value>
                </enumeratedValue>
                <enumeratedValue>
                  <name>101</name>
                  <description>Alternative 5 (chip-specific).</description>
                  <value>#101</value>
                </enumeratedValue>
                <enumeratedValue>
                  <name>110</name>
                  <description>Alternative 6 (chip-specific).</description>
                  <value>#110</value>
                </enumeratedValue>
                <enumeratedValue>
                  <name>111</name>
                  <description>Alternative 7 (chip-specific).</description>
                  <value>#111</value>
                </enumeratedValue>
              </enumeratedValues>
            </field>
            <field>
              <name>IRQC</name>
              <description>Interrupt Configuration</description>
              <bitOffset>16</bitOffset>
              <bitWidth>4</bitWidth>
              <access>read-write</access>
              <enumeratedValues>
                <enumeratedValue>
                  <name>0000</name>
                  <description>Interrupt/DMA request disabled.</description>
                  <value>#0000</value>
                </enumeratedValue>
                <enumeratedValue>
                  <name>0001</name>
                  <description>DMA request on rising edge.</description>
                  <value>#0001</value>
                </enumeratedValue>
                <enumeratedValue>
                  <name>0010</name>
                  <description>DMA request on falling edge.</description>
                  <value>#0010</value>
                </enumeratedValue>
                <enumeratedValue>
                  <name>0011</name>
                  <description>DMA request on either edge.</description>
                  <value>#0011</value>
                </enumeratedValue>
                <enumeratedValue>
                  <name>1000</name>
                  <description>Interrupt when logic 0.</description>
                  <value>#1000</value>
                </enumeratedValue>
                <enumeratedValue>
                  <name>1001</name>
                  <description>Interrupt on rising-edge.</description>
                  <value>#1001</value>
                </enumeratedValue>
                <enumeratedValue>
                  <name>1010</name>
                  <description>Interrupt on falling-edge.</description>
                  <value>#1010</value>
                </enumeratedValue>
                <enumeratedValue>
                  <name>1011</name>
                  <description>Interrupt on either edge.</description>
                  <value>#1011</value>
                </enumeratedValue>
                <enumeratedValue>
                  <name>1100</name>
                  <description>Interrupt when logic 1.</description>
                  <value>#1100</value>
                </enumeratedValue>
              </enumeratedValues>
            </field>
            <field>
              <name>ISF</name>
              <description>Interrupt Status Flag</description>
              <bitOffset>24</bitOffset>
              <bitWidth>1</bitWidth>
              <access>read-write</access>
              <enumeratedValues>
                <enumeratedValue>
                  <name>0</name>
                  <description>Configured interrupt is not detected.</description>
                  <value>#0</value>
                </enumeratedValue>
                <enumeratedValue>
                  <name>1</name>
                  <description>Configured interrupt is detected. If the pin is configured to generate a DMA request, then the corresponding flag will be cleared automatically at the completion of the requested DMA transfer. Otherwise, the flag remains set until a logic 1 is written to the flag. If the pin is configured for a level sensitive interrupt and the pin remains asserted, then the flag is set again immediately after it is cleared.</description>
                  <value>#1</value>
                </enumeratedValue>
              </enumeratedValues>
            </field>
          </fields>
        </register>
        <register>
          <name>PCR31</name>
          <description>Pin Control Register n</description>
          <addressOffset>0x7C</addressOffset>
          <size>32</size>
          <access>read-write</access>
          <resetValue>0</resetValue>
          <resetMask>0xFFFFFFFF</resetMask>
          <fields>
            <field>
              <name>PS</name>
              <description>Pull Select</description>
              <bitOffset>0</bitOffset>
              <bitWidth>1</bitWidth>
              <access>read-only</access>
              <enumeratedValues>
                <enumeratedValue>
                  <name>0</name>
                  <description>Internal pulldown resistor is enabled on the corresponding pin, if the corresponding PE field is set.</description>
                  <value>#0</value>
                </enumeratedValue>
                <enumeratedValue>
                  <name>1</name>
                  <description>Internal pullup resistor is enabled on the corresponding pin, if the corresponding PE field is set.</description>
                  <value>#1</value>
                </enumeratedValue>
              </enumeratedValues>
            </field>
            <field>
              <name>PE</name>
              <description>Pull Enable</description>
              <bitOffset>1</bitOffset>
              <bitWidth>1</bitWidth>
              <access>read-only</access>
              <enumeratedValues>
                <enumeratedValue>
                  <name>0</name>
                  <description>Internal pullup or pulldown resistor is not enabled on the corresponding pin.</description>
                  <value>#0</value>
                </enumeratedValue>
                <enumeratedValue>
                  <name>1</name>
                  <description>Internal pullup or pulldown resistor is enabled on the corresponding pin, if the pin is configured as a digital input.</description>
                  <value>#1</value>
                </enumeratedValue>
              </enumeratedValues>
            </field>
            <field>
              <name>SRE</name>
              <description>Slew Rate Enable</description>
              <bitOffset>2</bitOffset>
              <bitWidth>1</bitWidth>
              <access>read-only</access>
              <enumeratedValues>
                <enumeratedValue>
                  <name>0</name>
                  <description>Fast slew rate is configured on the corresponding pin, if the pin is configured as a digital output.</description>
                  <value>#0</value>
                </enumeratedValue>
                <enumeratedValue>
                  <name>1</name>
                  <description>Slow slew rate is configured on the corresponding pin, if the pin is configured as a digital output.</description>
                  <value>#1</value>
                </enumeratedValue>
              </enumeratedValues>
            </field>
            <field>
              <name>PFE</name>
              <description>Passive Filter Enable</description>
              <bitOffset>4</bitOffset>
              <bitWidth>1</bitWidth>
              <access>read-only</access>
              <enumeratedValues>
                <enumeratedValue>
                  <name>0</name>
                  <description>Passive input filter is disabled on the corresponding pin.</description>
                  <value>#0</value>
                </enumeratedValue>
                <enumeratedValue>
                  <name>1</name>
                  <description>Passive input filter is enabled on the corresponding pin, if the pin is configured as a digital input. Refer to the device data sheet for filter characteristics.</description>
                  <value>#1</value>
                </enumeratedValue>
              </enumeratedValues>
            </field>
            <field>
              <name>DSE</name>
              <description>Drive Strength Enable</description>
              <bitOffset>6</bitOffset>
              <bitWidth>1</bitWidth>
              <access>read-only</access>
              <enumeratedValues>
                <enumeratedValue>
                  <name>0</name>
                  <description>Low drive strength is configured on the corresponding pin, if pin is configured as a digital output.</description>
                  <value>#0</value>
                </enumeratedValue>
                <enumeratedValue>
                  <name>1</name>
                  <description>High drive strength is configured on the corresponding pin, if pin is configured as a digital output.</description>
                  <value>#1</value>
                </enumeratedValue>
              </enumeratedValues>
            </field>
            <field>
              <name>MUX</name>
              <description>Pin Mux Control</description>
              <bitOffset>8</bitOffset>
              <bitWidth>3</bitWidth>
              <access>read-write</access>
              <enumeratedValues>
                <enumeratedValue>
                  <name>000</name>
                  <description>Pin disabled (analog).</description>
                  <value>#000</value>
                </enumeratedValue>
                <enumeratedValue>
                  <name>001</name>
                  <description>Alternative 1 (GPIO).</description>
                  <value>#001</value>
                </enumeratedValue>
                <enumeratedValue>
                  <name>010</name>
                  <description>Alternative 2 (chip-specific).</description>
                  <value>#010</value>
                </enumeratedValue>
                <enumeratedValue>
                  <name>011</name>
                  <description>Alternative 3 (chip-specific).</description>
                  <value>#011</value>
                </enumeratedValue>
                <enumeratedValue>
                  <name>100</name>
                  <description>Alternative 4 (chip-specific).</description>
                  <value>#100</value>
                </enumeratedValue>
                <enumeratedValue>
                  <name>101</name>
                  <description>Alternative 5 (chip-specific).</description>
                  <value>#101</value>
                </enumeratedValue>
                <enumeratedValue>
                  <name>110</name>
                  <description>Alternative 6 (chip-specific).</description>
                  <value>#110</value>
                </enumeratedValue>
                <enumeratedValue>
                  <name>111</name>
                  <description>Alternative 7 (chip-specific).</description>
                  <value>#111</value>
                </enumeratedValue>
              </enumeratedValues>
            </field>
            <field>
              <name>IRQC</name>
              <description>Interrupt Configuration</description>
              <bitOffset>16</bitOffset>
              <bitWidth>4</bitWidth>
              <access>read-write</access>
              <enumeratedValues>
                <enumeratedValue>
                  <name>0000</name>
                  <description>Interrupt/DMA request disabled.</description>
                  <value>#0000</value>
                </enumeratedValue>
                <enumeratedValue>
                  <name>0001</name>
                  <description>DMA request on rising edge.</description>
                  <value>#0001</value>
                </enumeratedValue>
                <enumeratedValue>
                  <name>0010</name>
                  <description>DMA request on falling edge.</description>
                  <value>#0010</value>
                </enumeratedValue>
                <enumeratedValue>
                  <name>0011</name>
                  <description>DMA request on either edge.</description>
                  <value>#0011</value>
                </enumeratedValue>
                <enumeratedValue>
                  <name>1000</name>
                  <description>Interrupt when logic 0.</description>
                  <value>#1000</value>
                </enumeratedValue>
                <enumeratedValue>
                  <name>1001</name>
                  <description>Interrupt on rising-edge.</description>
                  <value>#1001</value>
                </enumeratedValue>
                <enumeratedValue>
                  <name>1010</name>
                  <description>Interrupt on falling-edge.</description>
                  <value>#1010</value>
                </enumeratedValue>
                <enumeratedValue>
                  <name>1011</name>
                  <description>Interrupt on either edge.</description>
                  <value>#1011</value>
                </enumeratedValue>
                <enumeratedValue>
                  <name>1100</name>
                  <description>Interrupt when logic 1.</description>
                  <value>#1100</value>
                </enumeratedValue>
              </enumeratedValues>
            </field>
            <field>
              <name>ISF</name>
              <description>Interrupt Status Flag</description>
              <bitOffset>24</bitOffset>
              <bitWidth>1</bitWidth>
              <access>read-write</access>
              <enumeratedValues>
                <enumeratedValue>
                  <name>0</name>
                  <description>Configured interrupt is not detected.</description>
                  <value>#0</value>
                </enumeratedValue>
                <enumeratedValue>
                  <name>1</name>
                  <description>Configured interrupt is detected. If the pin is configured to generate a DMA request, then the corresponding flag will be cleared automatically at the completion of the requested DMA transfer. Otherwise, the flag remains set until a logic 1 is written to the flag. If the pin is configured for a level sensitive interrupt and the pin remains asserted, then the flag is set again immediately after it is cleared.</description>
                  <value>#1</value>
                </enumeratedValue>
              </enumeratedValues>
            </field>
          </fields>
        </register>
        <register>
          <name>GPCLR</name>
          <description>Global Pin Control Low Register</description>
          <addressOffset>0x80</addressOffset>
          <size>32</size>
          <access>write-only</access>
          <resetValue>0</resetValue>
          <resetMask>0xFFFFFFFF</resetMask>
          <fields>
            <field>
              <name>GPWD</name>
              <description>Global Pin Write Data</description>
              <bitOffset>0</bitOffset>
              <bitWidth>16</bitWidth>
              <access>write-only</access>
            </field>
            <field>
              <name>GPWE</name>
              <description>Global Pin Write Enable</description>
              <bitOffset>16</bitOffset>
              <bitWidth>16</bitWidth>
              <access>write-only</access>
              <enumeratedValues>
                <enumeratedValue>
                  <name>0</name>
                  <description>Corresponding Pin Control Register is not updated with the value in GPWD.</description>
                  <value>#0</value>
                </enumeratedValue>
                <enumeratedValue>
                  <name>1</name>
                  <description>Corresponding Pin Control Register is updated with the value in GPWD.</description>
                  <value>#1</value>
                </enumeratedValue>
              </enumeratedValues>
            </field>
          </fields>
        </register>
        <register>
          <name>GPCHR</name>
          <description>Global Pin Control High Register</description>
          <addressOffset>0x84</addressOffset>
          <size>32</size>
          <access>write-only</access>
          <resetValue>0</resetValue>
          <resetMask>0xFFFFFFFF</resetMask>
          <fields>
            <field>
              <name>GPWD</name>
              <description>Global Pin Write Data</description>
              <bitOffset>0</bitOffset>
              <bitWidth>16</bitWidth>
              <access>write-only</access>
            </field>
            <field>
              <name>GPWE</name>
              <description>Global Pin Write Enable</description>
              <bitOffset>16</bitOffset>
              <bitWidth>16</bitWidth>
              <access>write-only</access>
              <enumeratedValues>
                <enumeratedValue>
                  <name>0</name>
                  <description>Corresponding Pin Control Register is not updated with the value in GPWD.</description>
                  <value>#0</value>
                </enumeratedValue>
                <enumeratedValue>
                  <name>1</name>
                  <description>Corresponding Pin Control Register is updated with the value in GPWD.</description>
                  <value>#1</value>
                </enumeratedValue>
              </enumeratedValues>
            </field>
          </fields>
        </register>
        <register>
          <name>ISFR</name>
          <description>Interrupt Status Flag Register</description>
          <addressOffset>0xA0</addressOffset>
          <size>32</size>
          <access>read-write</access>
          <resetValue>0</resetValue>
          <resetMask>0xFFFFFFFF</resetMask>
          <fields>
            <field>
              <name>ISF</name>
              <description>Interrupt Status Flag</description>
              <bitOffset>0</bitOffset>
              <bitWidth>32</bitWidth>
              <access>read-write</access>
              <enumeratedValues>
                <enumeratedValue>
                  <name>0</name>
                  <description>Configured interrupt is not detected.</description>
                  <value>#0</value>
                </enumeratedValue>
                <enumeratedValue>
                  <name>1</name>
                  <description>Configured interrupt is detected. If the pin is configured to generate a DMA request, then the corresponding flag will be cleared automatically at the completion of the requested DMA transfer. Otherwise, the flag remains set until a logic 1 is written to the flag. If the pin is configured for a level sensitive interrupt and the pin remains asserted, then the flag is set again immediately after it is cleared.</description>
                  <value>#1</value>
                </enumeratedValue>
              </enumeratedValues>
            </field>
          </fields>
        </register>
      </registers>
    </peripheral>
    <peripheral>
      <name>PORTE</name>
      <description>Pin Control and Interrupts</description>
      <groupName>PORT</groupName>
      <prependToName>PORTE_</prependToName>
      <baseAddress>0x4004D000</baseAddress>
      <addressBlock>
        <offset>0</offset>
        <size>0xA4</size>
        <usage>registers</usage>
      </addressBlock>
      <registers>
        <register>
          <name>PCR0</name>
          <description>Pin Control Register n</description>
          <addressOffset>0</addressOffset>
          <size>32</size>
          <access>read-write</access>
          <resetValue>0x5</resetValue>
          <resetMask>0xFFFFFFFF</resetMask>
          <fields>
            <field>
              <name>PS</name>
              <description>Pull Select</description>
              <bitOffset>0</bitOffset>
              <bitWidth>1</bitWidth>
              <access>read-write</access>
              <enumeratedValues>
                <enumeratedValue>
                  <name>0</name>
                  <description>Internal pulldown resistor is enabled on the corresponding pin, if the corresponding PE field is set.</description>
                  <value>#0</value>
                </enumeratedValue>
                <enumeratedValue>
                  <name>1</name>
                  <description>Internal pullup resistor is enabled on the corresponding pin, if the corresponding PE field is set.</description>
                  <value>#1</value>
                </enumeratedValue>
              </enumeratedValues>
            </field>
            <field>
              <name>PE</name>
              <description>Pull Enable</description>
              <bitOffset>1</bitOffset>
              <bitWidth>1</bitWidth>
              <access>read-write</access>
              <enumeratedValues>
                <enumeratedValue>
                  <name>0</name>
                  <description>Internal pullup or pulldown resistor is not enabled on the corresponding pin.</description>
                  <value>#0</value>
                </enumeratedValue>
                <enumeratedValue>
                  <name>1</name>
                  <description>Internal pullup or pulldown resistor is enabled on the corresponding pin, if the pin is configured as a digital input.</description>
                  <value>#1</value>
                </enumeratedValue>
              </enumeratedValues>
            </field>
            <field>
              <name>SRE</name>
              <description>Slew Rate Enable</description>
              <bitOffset>2</bitOffset>
              <bitWidth>1</bitWidth>
              <access>read-write</access>
              <enumeratedValues>
                <enumeratedValue>
                  <name>0</name>
                  <description>Fast slew rate is configured on the corresponding pin, if the pin is configured as a digital output.</description>
                  <value>#0</value>
                </enumeratedValue>
                <enumeratedValue>
                  <name>1</name>
                  <description>Slow slew rate is configured on the corresponding pin, if the pin is configured as a digital output.</description>
                  <value>#1</value>
                </enumeratedValue>
              </enumeratedValues>
            </field>
            <field>
              <name>PFE</name>
              <description>Passive Filter Enable</description>
              <bitOffset>4</bitOffset>
              <bitWidth>1</bitWidth>
              <access>read-only</access>
              <enumeratedValues>
                <enumeratedValue>
                  <name>0</name>
                  <description>Passive input filter is disabled on the corresponding pin.</description>
                  <value>#0</value>
                </enumeratedValue>
                <enumeratedValue>
                  <name>1</name>
                  <description>Passive input filter is enabled on the corresponding pin, if the pin is configured as a digital input. Refer to the device data sheet for filter characteristics.</description>
                  <value>#1</value>
                </enumeratedValue>
              </enumeratedValues>
            </field>
            <field>
              <name>DSE</name>
              <description>Drive Strength Enable</description>
              <bitOffset>6</bitOffset>
              <bitWidth>1</bitWidth>
              <access>read-only</access>
              <enumeratedValues>
                <enumeratedValue>
                  <name>0</name>
                  <description>Low drive strength is configured on the corresponding pin, if pin is configured as a digital output.</description>
                  <value>#0</value>
                </enumeratedValue>
                <enumeratedValue>
                  <name>1</name>
                  <description>High drive strength is configured on the corresponding pin, if pin is configured as a digital output.</description>
                  <value>#1</value>
                </enumeratedValue>
              </enumeratedValues>
            </field>
            <field>
              <name>MUX</name>
              <description>Pin Mux Control</description>
              <bitOffset>8</bitOffset>
              <bitWidth>3</bitWidth>
              <access>read-write</access>
              <enumeratedValues>
                <enumeratedValue>
                  <name>000</name>
                  <description>Pin disabled (analog).</description>
                  <value>#000</value>
                </enumeratedValue>
                <enumeratedValue>
                  <name>001</name>
                  <description>Alternative 1 (GPIO).</description>
                  <value>#001</value>
                </enumeratedValue>
                <enumeratedValue>
                  <name>010</name>
                  <description>Alternative 2 (chip-specific).</description>
                  <value>#010</value>
                </enumeratedValue>
                <enumeratedValue>
                  <name>011</name>
                  <description>Alternative 3 (chip-specific).</description>
                  <value>#011</value>
                </enumeratedValue>
                <enumeratedValue>
                  <name>100</name>
                  <description>Alternative 4 (chip-specific).</description>
                  <value>#100</value>
                </enumeratedValue>
                <enumeratedValue>
                  <name>101</name>
                  <description>Alternative 5 (chip-specific).</description>
                  <value>#101</value>
                </enumeratedValue>
                <enumeratedValue>
                  <name>110</name>
                  <description>Alternative 6 (chip-specific).</description>
                  <value>#110</value>
                </enumeratedValue>
                <enumeratedValue>
                  <name>111</name>
                  <description>Alternative 7 (chip-specific).</description>
                  <value>#111</value>
                </enumeratedValue>
              </enumeratedValues>
            </field>
            <field>
              <name>IRQC</name>
              <description>Interrupt Configuration</description>
              <bitOffset>16</bitOffset>
              <bitWidth>4</bitWidth>
              <access>read-write</access>
              <enumeratedValues>
                <enumeratedValue>
                  <name>0000</name>
                  <description>Interrupt/DMA request disabled.</description>
                  <value>#0000</value>
                </enumeratedValue>
                <enumeratedValue>
                  <name>0001</name>
                  <description>DMA request on rising edge.</description>
                  <value>#0001</value>
                </enumeratedValue>
                <enumeratedValue>
                  <name>0010</name>
                  <description>DMA request on falling edge.</description>
                  <value>#0010</value>
                </enumeratedValue>
                <enumeratedValue>
                  <name>0011</name>
                  <description>DMA request on either edge.</description>
                  <value>#0011</value>
                </enumeratedValue>
                <enumeratedValue>
                  <name>1000</name>
                  <description>Interrupt when logic 0.</description>
                  <value>#1000</value>
                </enumeratedValue>
                <enumeratedValue>
                  <name>1001</name>
                  <description>Interrupt on rising-edge.</description>
                  <value>#1001</value>
                </enumeratedValue>
                <enumeratedValue>
                  <name>1010</name>
                  <description>Interrupt on falling-edge.</description>
                  <value>#1010</value>
                </enumeratedValue>
                <enumeratedValue>
                  <name>1011</name>
                  <description>Interrupt on either edge.</description>
                  <value>#1011</value>
                </enumeratedValue>
                <enumeratedValue>
                  <name>1100</name>
                  <description>Interrupt when logic 1.</description>
                  <value>#1100</value>
                </enumeratedValue>
              </enumeratedValues>
            </field>
            <field>
              <name>ISF</name>
              <description>Interrupt Status Flag</description>
              <bitOffset>24</bitOffset>
              <bitWidth>1</bitWidth>
              <access>read-write</access>
              <enumeratedValues>
                <enumeratedValue>
                  <name>0</name>
                  <description>Configured interrupt is not detected.</description>
                  <value>#0</value>
                </enumeratedValue>
                <enumeratedValue>
                  <name>1</name>
                  <description>Configured interrupt is detected. If the pin is configured to generate a DMA request, then the corresponding flag will be cleared automatically at the completion of the requested DMA transfer. Otherwise, the flag remains set until a logic 1 is written to the flag. If the pin is configured for a level sensitive interrupt and the pin remains asserted, then the flag is set again immediately after it is cleared.</description>
                  <value>#1</value>
                </enumeratedValue>
              </enumeratedValues>
            </field>
          </fields>
        </register>
        <register>
          <name>PCR1</name>
          <description>Pin Control Register n</description>
          <addressOffset>0x4</addressOffset>
          <size>32</size>
          <access>read-write</access>
          <resetValue>0x5</resetValue>
          <resetMask>0xFFFFFFFF</resetMask>
          <fields>
            <field>
              <name>PS</name>
              <description>Pull Select</description>
              <bitOffset>0</bitOffset>
              <bitWidth>1</bitWidth>
              <access>read-write</access>
              <enumeratedValues>
                <enumeratedValue>
                  <name>0</name>
                  <description>Internal pulldown resistor is enabled on the corresponding pin, if the corresponding PE field is set.</description>
                  <value>#0</value>
                </enumeratedValue>
                <enumeratedValue>
                  <name>1</name>
                  <description>Internal pullup resistor is enabled on the corresponding pin, if the corresponding PE field is set.</description>
                  <value>#1</value>
                </enumeratedValue>
              </enumeratedValues>
            </field>
            <field>
              <name>PE</name>
              <description>Pull Enable</description>
              <bitOffset>1</bitOffset>
              <bitWidth>1</bitWidth>
              <access>read-write</access>
              <enumeratedValues>
                <enumeratedValue>
                  <name>0</name>
                  <description>Internal pullup or pulldown resistor is not enabled on the corresponding pin.</description>
                  <value>#0</value>
                </enumeratedValue>
                <enumeratedValue>
                  <name>1</name>
                  <description>Internal pullup or pulldown resistor is enabled on the corresponding pin, if the pin is configured as a digital input.</description>
                  <value>#1</value>
                </enumeratedValue>
              </enumeratedValues>
            </field>
            <field>
              <name>SRE</name>
              <description>Slew Rate Enable</description>
              <bitOffset>2</bitOffset>
              <bitWidth>1</bitWidth>
              <access>read-write</access>
              <enumeratedValues>
                <enumeratedValue>
                  <name>0</name>
                  <description>Fast slew rate is configured on the corresponding pin, if the pin is configured as a digital output.</description>
                  <value>#0</value>
                </enumeratedValue>
                <enumeratedValue>
                  <name>1</name>
                  <description>Slow slew rate is configured on the corresponding pin, if the pin is configured as a digital output.</description>
                  <value>#1</value>
                </enumeratedValue>
              </enumeratedValues>
            </field>
            <field>
              <name>PFE</name>
              <description>Passive Filter Enable</description>
              <bitOffset>4</bitOffset>
              <bitWidth>1</bitWidth>
              <access>read-only</access>
              <enumeratedValues>
                <enumeratedValue>
                  <name>0</name>
                  <description>Passive input filter is disabled on the corresponding pin.</description>
                  <value>#0</value>
                </enumeratedValue>
                <enumeratedValue>
                  <name>1</name>
                  <description>Passive input filter is enabled on the corresponding pin, if the pin is configured as a digital input. Refer to the device data sheet for filter characteristics.</description>
                  <value>#1</value>
                </enumeratedValue>
              </enumeratedValues>
            </field>
            <field>
              <name>DSE</name>
              <description>Drive Strength Enable</description>
              <bitOffset>6</bitOffset>
              <bitWidth>1</bitWidth>
              <access>read-only</access>
              <enumeratedValues>
                <enumeratedValue>
                  <name>0</name>
                  <description>Low drive strength is configured on the corresponding pin, if pin is configured as a digital output.</description>
                  <value>#0</value>
                </enumeratedValue>
                <enumeratedValue>
                  <name>1</name>
                  <description>High drive strength is configured on the corresponding pin, if pin is configured as a digital output.</description>
                  <value>#1</value>
                </enumeratedValue>
              </enumeratedValues>
            </field>
            <field>
              <name>MUX</name>
              <description>Pin Mux Control</description>
              <bitOffset>8</bitOffset>
              <bitWidth>3</bitWidth>
              <access>read-write</access>
              <enumeratedValues>
                <enumeratedValue>
                  <name>000</name>
                  <description>Pin disabled (analog).</description>
                  <value>#000</value>
                </enumeratedValue>
                <enumeratedValue>
                  <name>001</name>
                  <description>Alternative 1 (GPIO).</description>
                  <value>#001</value>
                </enumeratedValue>
                <enumeratedValue>
                  <name>010</name>
                  <description>Alternative 2 (chip-specific).</description>
                  <value>#010</value>
                </enumeratedValue>
                <enumeratedValue>
                  <name>011</name>
                  <description>Alternative 3 (chip-specific).</description>
                  <value>#011</value>
                </enumeratedValue>
                <enumeratedValue>
                  <name>100</name>
                  <description>Alternative 4 (chip-specific).</description>
                  <value>#100</value>
                </enumeratedValue>
                <enumeratedValue>
                  <name>101</name>
                  <description>Alternative 5 (chip-specific).</description>
                  <value>#101</value>
                </enumeratedValue>
                <enumeratedValue>
                  <name>110</name>
                  <description>Alternative 6 (chip-specific).</description>
                  <value>#110</value>
                </enumeratedValue>
                <enumeratedValue>
                  <name>111</name>
                  <description>Alternative 7 (chip-specific).</description>
                  <value>#111</value>
                </enumeratedValue>
              </enumeratedValues>
            </field>
            <field>
              <name>IRQC</name>
              <description>Interrupt Configuration</description>
              <bitOffset>16</bitOffset>
              <bitWidth>4</bitWidth>
              <access>read-write</access>
              <enumeratedValues>
                <enumeratedValue>
                  <name>0000</name>
                  <description>Interrupt/DMA request disabled.</description>
                  <value>#0000</value>
                </enumeratedValue>
                <enumeratedValue>
                  <name>0001</name>
                  <description>DMA request on rising edge.</description>
                  <value>#0001</value>
                </enumeratedValue>
                <enumeratedValue>
                  <name>0010</name>
                  <description>DMA request on falling edge.</description>
                  <value>#0010</value>
                </enumeratedValue>
                <enumeratedValue>
                  <name>0011</name>
                  <description>DMA request on either edge.</description>
                  <value>#0011</value>
                </enumeratedValue>
                <enumeratedValue>
                  <name>1000</name>
                  <description>Interrupt when logic 0.</description>
                  <value>#1000</value>
                </enumeratedValue>
                <enumeratedValue>
                  <name>1001</name>
                  <description>Interrupt on rising-edge.</description>
                  <value>#1001</value>
                </enumeratedValue>
                <enumeratedValue>
                  <name>1010</name>
                  <description>Interrupt on falling-edge.</description>
                  <value>#1010</value>
                </enumeratedValue>
                <enumeratedValue>
                  <name>1011</name>
                  <description>Interrupt on either edge.</description>
                  <value>#1011</value>
                </enumeratedValue>
                <enumeratedValue>
                  <name>1100</name>
                  <description>Interrupt when logic 1.</description>
                  <value>#1100</value>
                </enumeratedValue>
              </enumeratedValues>
            </field>
            <field>
              <name>ISF</name>
              <description>Interrupt Status Flag</description>
              <bitOffset>24</bitOffset>
              <bitWidth>1</bitWidth>
              <access>read-write</access>
              <enumeratedValues>
                <enumeratedValue>
                  <name>0</name>
                  <description>Configured interrupt is not detected.</description>
                  <value>#0</value>
                </enumeratedValue>
                <enumeratedValue>
                  <name>1</name>
                  <description>Configured interrupt is detected. If the pin is configured to generate a DMA request, then the corresponding flag will be cleared automatically at the completion of the requested DMA transfer. Otherwise, the flag remains set until a logic 1 is written to the flag. If the pin is configured for a level sensitive interrupt and the pin remains asserted, then the flag is set again immediately after it is cleared.</description>
                  <value>#1</value>
                </enumeratedValue>
              </enumeratedValues>
            </field>
          </fields>
        </register>
        <register>
          <name>PCR2</name>
          <description>Pin Control Register n</description>
          <addressOffset>0x8</addressOffset>
          <size>32</size>
          <access>read-write</access>
          <resetValue>0x5</resetValue>
          <resetMask>0xFFFFFFFF</resetMask>
          <fields>
            <field>
              <name>PS</name>
              <description>Pull Select</description>
              <bitOffset>0</bitOffset>
              <bitWidth>1</bitWidth>
              <access>read-only</access>
              <enumeratedValues>
                <enumeratedValue>
                  <name>0</name>
                  <description>Internal pulldown resistor is enabled on the corresponding pin, if the corresponding PE field is set.</description>
                  <value>#0</value>
                </enumeratedValue>
                <enumeratedValue>
                  <name>1</name>
                  <description>Internal pullup resistor is enabled on the corresponding pin, if the corresponding PE field is set.</description>
                  <value>#1</value>
                </enumeratedValue>
              </enumeratedValues>
            </field>
            <field>
              <name>PE</name>
              <description>Pull Enable</description>
              <bitOffset>1</bitOffset>
              <bitWidth>1</bitWidth>
              <access>read-only</access>
              <enumeratedValues>
                <enumeratedValue>
                  <name>0</name>
                  <description>Internal pullup or pulldown resistor is not enabled on the corresponding pin.</description>
                  <value>#0</value>
                </enumeratedValue>
                <enumeratedValue>
                  <name>1</name>
                  <description>Internal pullup or pulldown resistor is enabled on the corresponding pin, if the pin is configured as a digital input.</description>
                  <value>#1</value>
                </enumeratedValue>
              </enumeratedValues>
            </field>
            <field>
              <name>SRE</name>
              <description>Slew Rate Enable</description>
              <bitOffset>2</bitOffset>
              <bitWidth>1</bitWidth>
              <access>read-only</access>
              <enumeratedValues>
                <enumeratedValue>
                  <name>0</name>
                  <description>Fast slew rate is configured on the corresponding pin, if the pin is configured as a digital output.</description>
                  <value>#0</value>
                </enumeratedValue>
                <enumeratedValue>
                  <name>1</name>
                  <description>Slow slew rate is configured on the corresponding pin, if the pin is configured as a digital output.</description>
                  <value>#1</value>
                </enumeratedValue>
              </enumeratedValues>
            </field>
            <field>
              <name>PFE</name>
              <description>Passive Filter Enable</description>
              <bitOffset>4</bitOffset>
              <bitWidth>1</bitWidth>
              <access>read-only</access>
              <enumeratedValues>
                <enumeratedValue>
                  <name>0</name>
                  <description>Passive input filter is disabled on the corresponding pin.</description>
                  <value>#0</value>
                </enumeratedValue>
                <enumeratedValue>
                  <name>1</name>
                  <description>Passive input filter is enabled on the corresponding pin, if the pin is configured as a digital input. Refer to the device data sheet for filter characteristics.</description>
                  <value>#1</value>
                </enumeratedValue>
              </enumeratedValues>
            </field>
            <field>
              <name>DSE</name>
              <description>Drive Strength Enable</description>
              <bitOffset>6</bitOffset>
              <bitWidth>1</bitWidth>
              <access>read-only</access>
              <enumeratedValues>
                <enumeratedValue>
                  <name>0</name>
                  <description>Low drive strength is configured on the corresponding pin, if pin is configured as a digital output.</description>
                  <value>#0</value>
                </enumeratedValue>
                <enumeratedValue>
                  <name>1</name>
                  <description>High drive strength is configured on the corresponding pin, if pin is configured as a digital output.</description>
                  <value>#1</value>
                </enumeratedValue>
              </enumeratedValues>
            </field>
            <field>
              <name>MUX</name>
              <description>Pin Mux Control</description>
              <bitOffset>8</bitOffset>
              <bitWidth>3</bitWidth>
              <access>read-write</access>
              <enumeratedValues>
                <enumeratedValue>
                  <name>000</name>
                  <description>Pin disabled (analog).</description>
                  <value>#000</value>
                </enumeratedValue>
                <enumeratedValue>
                  <name>001</name>
                  <description>Alternative 1 (GPIO).</description>
                  <value>#001</value>
                </enumeratedValue>
                <enumeratedValue>
                  <name>010</name>
                  <description>Alternative 2 (chip-specific).</description>
                  <value>#010</value>
                </enumeratedValue>
                <enumeratedValue>
                  <name>011</name>
                  <description>Alternative 3 (chip-specific).</description>
                  <value>#011</value>
                </enumeratedValue>
                <enumeratedValue>
                  <name>100</name>
                  <description>Alternative 4 (chip-specific).</description>
                  <value>#100</value>
                </enumeratedValue>
                <enumeratedValue>
                  <name>101</name>
                  <description>Alternative 5 (chip-specific).</description>
                  <value>#101</value>
                </enumeratedValue>
                <enumeratedValue>
                  <name>110</name>
                  <description>Alternative 6 (chip-specific).</description>
                  <value>#110</value>
                </enumeratedValue>
                <enumeratedValue>
                  <name>111</name>
                  <description>Alternative 7 (chip-specific).</description>
                  <value>#111</value>
                </enumeratedValue>
              </enumeratedValues>
            </field>
            <field>
              <name>IRQC</name>
              <description>Interrupt Configuration</description>
              <bitOffset>16</bitOffset>
              <bitWidth>4</bitWidth>
              <access>read-write</access>
              <enumeratedValues>
                <enumeratedValue>
                  <name>0000</name>
                  <description>Interrupt/DMA request disabled.</description>
                  <value>#0000</value>
                </enumeratedValue>
                <enumeratedValue>
                  <name>0001</name>
                  <description>DMA request on rising edge.</description>
                  <value>#0001</value>
                </enumeratedValue>
                <enumeratedValue>
                  <name>0010</name>
                  <description>DMA request on falling edge.</description>
                  <value>#0010</value>
                </enumeratedValue>
                <enumeratedValue>
                  <name>0011</name>
                  <description>DMA request on either edge.</description>
                  <value>#0011</value>
                </enumeratedValue>
                <enumeratedValue>
                  <name>1000</name>
                  <description>Interrupt when logic 0.</description>
                  <value>#1000</value>
                </enumeratedValue>
                <enumeratedValue>
                  <name>1001</name>
                  <description>Interrupt on rising-edge.</description>
                  <value>#1001</value>
                </enumeratedValue>
                <enumeratedValue>
                  <name>1010</name>
                  <description>Interrupt on falling-edge.</description>
                  <value>#1010</value>
                </enumeratedValue>
                <enumeratedValue>
                  <name>1011</name>
                  <description>Interrupt on either edge.</description>
                  <value>#1011</value>
                </enumeratedValue>
                <enumeratedValue>
                  <name>1100</name>
                  <description>Interrupt when logic 1.</description>
                  <value>#1100</value>
                </enumeratedValue>
              </enumeratedValues>
            </field>
            <field>
              <name>ISF</name>
              <description>Interrupt Status Flag</description>
              <bitOffset>24</bitOffset>
              <bitWidth>1</bitWidth>
              <access>read-write</access>
              <enumeratedValues>
                <enumeratedValue>
                  <name>0</name>
                  <description>Configured interrupt is not detected.</description>
                  <value>#0</value>
                </enumeratedValue>
                <enumeratedValue>
                  <name>1</name>
                  <description>Configured interrupt is detected. If the pin is configured to generate a DMA request, then the corresponding flag will be cleared automatically at the completion of the requested DMA transfer. Otherwise, the flag remains set until a logic 1 is written to the flag. If the pin is configured for a level sensitive interrupt and the pin remains asserted, then the flag is set again immediately after it is cleared.</description>
                  <value>#1</value>
                </enumeratedValue>
              </enumeratedValues>
            </field>
          </fields>
        </register>
        <register>
          <name>PCR3</name>
          <description>Pin Control Register n</description>
          <addressOffset>0xC</addressOffset>
          <size>32</size>
          <access>read-write</access>
          <resetValue>0x5</resetValue>
          <resetMask>0xFFFFFFFF</resetMask>
          <fields>
            <field>
              <name>PS</name>
              <description>Pull Select</description>
              <bitOffset>0</bitOffset>
              <bitWidth>1</bitWidth>
              <access>read-only</access>
              <enumeratedValues>
                <enumeratedValue>
                  <name>0</name>
                  <description>Internal pulldown resistor is enabled on the corresponding pin, if the corresponding PE field is set.</description>
                  <value>#0</value>
                </enumeratedValue>
                <enumeratedValue>
                  <name>1</name>
                  <description>Internal pullup resistor is enabled on the corresponding pin, if the corresponding PE field is set.</description>
                  <value>#1</value>
                </enumeratedValue>
              </enumeratedValues>
            </field>
            <field>
              <name>PE</name>
              <description>Pull Enable</description>
              <bitOffset>1</bitOffset>
              <bitWidth>1</bitWidth>
              <access>read-only</access>
              <enumeratedValues>
                <enumeratedValue>
                  <name>0</name>
                  <description>Internal pullup or pulldown resistor is not enabled on the corresponding pin.</description>
                  <value>#0</value>
                </enumeratedValue>
                <enumeratedValue>
                  <name>1</name>
                  <description>Internal pullup or pulldown resistor is enabled on the corresponding pin, if the pin is configured as a digital input.</description>
                  <value>#1</value>
                </enumeratedValue>
              </enumeratedValues>
            </field>
            <field>
              <name>SRE</name>
              <description>Slew Rate Enable</description>
              <bitOffset>2</bitOffset>
              <bitWidth>1</bitWidth>
              <access>read-only</access>
              <enumeratedValues>
                <enumeratedValue>
                  <name>0</name>
                  <description>Fast slew rate is configured on the corresponding pin, if the pin is configured as a digital output.</description>
                  <value>#0</value>
                </enumeratedValue>
                <enumeratedValue>
                  <name>1</name>
                  <description>Slow slew rate is configured on the corresponding pin, if the pin is configured as a digital output.</description>
                  <value>#1</value>
                </enumeratedValue>
              </enumeratedValues>
            </field>
            <field>
              <name>PFE</name>
              <description>Passive Filter Enable</description>
              <bitOffset>4</bitOffset>
              <bitWidth>1</bitWidth>
              <access>read-only</access>
              <enumeratedValues>
                <enumeratedValue>
                  <name>0</name>
                  <description>Passive input filter is disabled on the corresponding pin.</description>
                  <value>#0</value>
                </enumeratedValue>
                <enumeratedValue>
                  <name>1</name>
                  <description>Passive input filter is enabled on the corresponding pin, if the pin is configured as a digital input. Refer to the device data sheet for filter characteristics.</description>
                  <value>#1</value>
                </enumeratedValue>
              </enumeratedValues>
            </field>
            <field>
              <name>DSE</name>
              <description>Drive Strength Enable</description>
              <bitOffset>6</bitOffset>
              <bitWidth>1</bitWidth>
              <access>read-only</access>
              <enumeratedValues>
                <enumeratedValue>
                  <name>0</name>
                  <description>Low drive strength is configured on the corresponding pin, if pin is configured as a digital output.</description>
                  <value>#0</value>
                </enumeratedValue>
                <enumeratedValue>
                  <name>1</name>
                  <description>High drive strength is configured on the corresponding pin, if pin is configured as a digital output.</description>
                  <value>#1</value>
                </enumeratedValue>
              </enumeratedValues>
            </field>
            <field>
              <name>MUX</name>
              <description>Pin Mux Control</description>
              <bitOffset>8</bitOffset>
              <bitWidth>3</bitWidth>
              <access>read-write</access>
              <enumeratedValues>
                <enumeratedValue>
                  <name>000</name>
                  <description>Pin disabled (analog).</description>
                  <value>#000</value>
                </enumeratedValue>
                <enumeratedValue>
                  <name>001</name>
                  <description>Alternative 1 (GPIO).</description>
                  <value>#001</value>
                </enumeratedValue>
                <enumeratedValue>
                  <name>010</name>
                  <description>Alternative 2 (chip-specific).</description>
                  <value>#010</value>
                </enumeratedValue>
                <enumeratedValue>
                  <name>011</name>
                  <description>Alternative 3 (chip-specific).</description>
                  <value>#011</value>
                </enumeratedValue>
                <enumeratedValue>
                  <name>100</name>
                  <description>Alternative 4 (chip-specific).</description>
                  <value>#100</value>
                </enumeratedValue>
                <enumeratedValue>
                  <name>101</name>
                  <description>Alternative 5 (chip-specific).</description>
                  <value>#101</value>
                </enumeratedValue>
                <enumeratedValue>
                  <name>110</name>
                  <description>Alternative 6 (chip-specific).</description>
                  <value>#110</value>
                </enumeratedValue>
                <enumeratedValue>
                  <name>111</name>
                  <description>Alternative 7 (chip-specific).</description>
                  <value>#111</value>
                </enumeratedValue>
              </enumeratedValues>
            </field>
            <field>
              <name>IRQC</name>
              <description>Interrupt Configuration</description>
              <bitOffset>16</bitOffset>
              <bitWidth>4</bitWidth>
              <access>read-write</access>
              <enumeratedValues>
                <enumeratedValue>
                  <name>0000</name>
                  <description>Interrupt/DMA request disabled.</description>
                  <value>#0000</value>
                </enumeratedValue>
                <enumeratedValue>
                  <name>0001</name>
                  <description>DMA request on rising edge.</description>
                  <value>#0001</value>
                </enumeratedValue>
                <enumeratedValue>
                  <name>0010</name>
                  <description>DMA request on falling edge.</description>
                  <value>#0010</value>
                </enumeratedValue>
                <enumeratedValue>
                  <name>0011</name>
                  <description>DMA request on either edge.</description>
                  <value>#0011</value>
                </enumeratedValue>
                <enumeratedValue>
                  <name>1000</name>
                  <description>Interrupt when logic 0.</description>
                  <value>#1000</value>
                </enumeratedValue>
                <enumeratedValue>
                  <name>1001</name>
                  <description>Interrupt on rising-edge.</description>
                  <value>#1001</value>
                </enumeratedValue>
                <enumeratedValue>
                  <name>1010</name>
                  <description>Interrupt on falling-edge.</description>
                  <value>#1010</value>
                </enumeratedValue>
                <enumeratedValue>
                  <name>1011</name>
                  <description>Interrupt on either edge.</description>
                  <value>#1011</value>
                </enumeratedValue>
                <enumeratedValue>
                  <name>1100</name>
                  <description>Interrupt when logic 1.</description>
                  <value>#1100</value>
                </enumeratedValue>
              </enumeratedValues>
            </field>
            <field>
              <name>ISF</name>
              <description>Interrupt Status Flag</description>
              <bitOffset>24</bitOffset>
              <bitWidth>1</bitWidth>
              <access>read-write</access>
              <enumeratedValues>
                <enumeratedValue>
                  <name>0</name>
                  <description>Configured interrupt is not detected.</description>
                  <value>#0</value>
                </enumeratedValue>
                <enumeratedValue>
                  <name>1</name>
                  <description>Configured interrupt is detected. If the pin is configured to generate a DMA request, then the corresponding flag will be cleared automatically at the completion of the requested DMA transfer. Otherwise, the flag remains set until a logic 1 is written to the flag. If the pin is configured for a level sensitive interrupt and the pin remains asserted, then the flag is set again immediately after it is cleared.</description>
                  <value>#1</value>
                </enumeratedValue>
              </enumeratedValues>
            </field>
          </fields>
        </register>
        <register>
          <name>PCR4</name>
          <description>Pin Control Register n</description>
          <addressOffset>0x10</addressOffset>
          <size>32</size>
          <access>read-write</access>
          <resetValue>0x5</resetValue>
          <resetMask>0xFFFFFFFF</resetMask>
          <fields>
            <field>
              <name>PS</name>
              <description>Pull Select</description>
              <bitOffset>0</bitOffset>
              <bitWidth>1</bitWidth>
              <access>read-only</access>
              <enumeratedValues>
                <enumeratedValue>
                  <name>0</name>
                  <description>Internal pulldown resistor is enabled on the corresponding pin, if the corresponding PE field is set.</description>
                  <value>#0</value>
                </enumeratedValue>
                <enumeratedValue>
                  <name>1</name>
                  <description>Internal pullup resistor is enabled on the corresponding pin, if the corresponding PE field is set.</description>
                  <value>#1</value>
                </enumeratedValue>
              </enumeratedValues>
            </field>
            <field>
              <name>PE</name>
              <description>Pull Enable</description>
              <bitOffset>1</bitOffset>
              <bitWidth>1</bitWidth>
              <access>read-only</access>
              <enumeratedValues>
                <enumeratedValue>
                  <name>0</name>
                  <description>Internal pullup or pulldown resistor is not enabled on the corresponding pin.</description>
                  <value>#0</value>
                </enumeratedValue>
                <enumeratedValue>
                  <name>1</name>
                  <description>Internal pullup or pulldown resistor is enabled on the corresponding pin, if the pin is configured as a digital input.</description>
                  <value>#1</value>
                </enumeratedValue>
              </enumeratedValues>
            </field>
            <field>
              <name>SRE</name>
              <description>Slew Rate Enable</description>
              <bitOffset>2</bitOffset>
              <bitWidth>1</bitWidth>
              <access>read-only</access>
              <enumeratedValues>
                <enumeratedValue>
                  <name>0</name>
                  <description>Fast slew rate is configured on the corresponding pin, if the pin is configured as a digital output.</description>
                  <value>#0</value>
                </enumeratedValue>
                <enumeratedValue>
                  <name>1</name>
                  <description>Slow slew rate is configured on the corresponding pin, if the pin is configured as a digital output.</description>
                  <value>#1</value>
                </enumeratedValue>
              </enumeratedValues>
            </field>
            <field>
              <name>PFE</name>
              <description>Passive Filter Enable</description>
              <bitOffset>4</bitOffset>
              <bitWidth>1</bitWidth>
              <access>read-only</access>
              <enumeratedValues>
                <enumeratedValue>
                  <name>0</name>
                  <description>Passive input filter is disabled on the corresponding pin.</description>
                  <value>#0</value>
                </enumeratedValue>
                <enumeratedValue>
                  <name>1</name>
                  <description>Passive input filter is enabled on the corresponding pin, if the pin is configured as a digital input. Refer to the device data sheet for filter characteristics.</description>
                  <value>#1</value>
                </enumeratedValue>
              </enumeratedValues>
            </field>
            <field>
              <name>DSE</name>
              <description>Drive Strength Enable</description>
              <bitOffset>6</bitOffset>
              <bitWidth>1</bitWidth>
              <access>read-only</access>
              <enumeratedValues>
                <enumeratedValue>
                  <name>0</name>
                  <description>Low drive strength is configured on the corresponding pin, if pin is configured as a digital output.</description>
                  <value>#0</value>
                </enumeratedValue>
                <enumeratedValue>
                  <name>1</name>
                  <description>High drive strength is configured on the corresponding pin, if pin is configured as a digital output.</description>
                  <value>#1</value>
                </enumeratedValue>
              </enumeratedValues>
            </field>
            <field>
              <name>MUX</name>
              <description>Pin Mux Control</description>
              <bitOffset>8</bitOffset>
              <bitWidth>3</bitWidth>
              <access>read-write</access>
              <enumeratedValues>
                <enumeratedValue>
                  <name>000</name>
                  <description>Pin disabled (analog).</description>
                  <value>#000</value>
                </enumeratedValue>
                <enumeratedValue>
                  <name>001</name>
                  <description>Alternative 1 (GPIO).</description>
                  <value>#001</value>
                </enumeratedValue>
                <enumeratedValue>
                  <name>010</name>
                  <description>Alternative 2 (chip-specific).</description>
                  <value>#010</value>
                </enumeratedValue>
                <enumeratedValue>
                  <name>011</name>
                  <description>Alternative 3 (chip-specific).</description>
                  <value>#011</value>
                </enumeratedValue>
                <enumeratedValue>
                  <name>100</name>
                  <description>Alternative 4 (chip-specific).</description>
                  <value>#100</value>
                </enumeratedValue>
                <enumeratedValue>
                  <name>101</name>
                  <description>Alternative 5 (chip-specific).</description>
                  <value>#101</value>
                </enumeratedValue>
                <enumeratedValue>
                  <name>110</name>
                  <description>Alternative 6 (chip-specific).</description>
                  <value>#110</value>
                </enumeratedValue>
                <enumeratedValue>
                  <name>111</name>
                  <description>Alternative 7 (chip-specific).</description>
                  <value>#111</value>
                </enumeratedValue>
              </enumeratedValues>
            </field>
            <field>
              <name>IRQC</name>
              <description>Interrupt Configuration</description>
              <bitOffset>16</bitOffset>
              <bitWidth>4</bitWidth>
              <access>read-write</access>
              <enumeratedValues>
                <enumeratedValue>
                  <name>0000</name>
                  <description>Interrupt/DMA request disabled.</description>
                  <value>#0000</value>
                </enumeratedValue>
                <enumeratedValue>
                  <name>0001</name>
                  <description>DMA request on rising edge.</description>
                  <value>#0001</value>
                </enumeratedValue>
                <enumeratedValue>
                  <name>0010</name>
                  <description>DMA request on falling edge.</description>
                  <value>#0010</value>
                </enumeratedValue>
                <enumeratedValue>
                  <name>0011</name>
                  <description>DMA request on either edge.</description>
                  <value>#0011</value>
                </enumeratedValue>
                <enumeratedValue>
                  <name>1000</name>
                  <description>Interrupt when logic 0.</description>
                  <value>#1000</value>
                </enumeratedValue>
                <enumeratedValue>
                  <name>1001</name>
                  <description>Interrupt on rising-edge.</description>
                  <value>#1001</value>
                </enumeratedValue>
                <enumeratedValue>
                  <name>1010</name>
                  <description>Interrupt on falling-edge.</description>
                  <value>#1010</value>
                </enumeratedValue>
                <enumeratedValue>
                  <name>1011</name>
                  <description>Interrupt on either edge.</description>
                  <value>#1011</value>
                </enumeratedValue>
                <enumeratedValue>
                  <name>1100</name>
                  <description>Interrupt when logic 1.</description>
                  <value>#1100</value>
                </enumeratedValue>
              </enumeratedValues>
            </field>
            <field>
              <name>ISF</name>
              <description>Interrupt Status Flag</description>
              <bitOffset>24</bitOffset>
              <bitWidth>1</bitWidth>
              <access>read-write</access>
              <enumeratedValues>
                <enumeratedValue>
                  <name>0</name>
                  <description>Configured interrupt is not detected.</description>
                  <value>#0</value>
                </enumeratedValue>
                <enumeratedValue>
                  <name>1</name>
                  <description>Configured interrupt is detected. If the pin is configured to generate a DMA request, then the corresponding flag will be cleared automatically at the completion of the requested DMA transfer. Otherwise, the flag remains set until a logic 1 is written to the flag. If the pin is configured for a level sensitive interrupt and the pin remains asserted, then the flag is set again immediately after it is cleared.</description>
                  <value>#1</value>
                </enumeratedValue>
              </enumeratedValues>
            </field>
          </fields>
        </register>
        <register>
          <name>PCR5</name>
          <description>Pin Control Register n</description>
          <addressOffset>0x14</addressOffset>
          <size>32</size>
          <access>read-write</access>
          <resetValue>0x5</resetValue>
          <resetMask>0xFFFFFFFF</resetMask>
          <fields>
            <field>
              <name>PS</name>
              <description>Pull Select</description>
              <bitOffset>0</bitOffset>
              <bitWidth>1</bitWidth>
              <access>read-only</access>
              <enumeratedValues>
                <enumeratedValue>
                  <name>0</name>
                  <description>Internal pulldown resistor is enabled on the corresponding pin, if the corresponding PE field is set.</description>
                  <value>#0</value>
                </enumeratedValue>
                <enumeratedValue>
                  <name>1</name>
                  <description>Internal pullup resistor is enabled on the corresponding pin, if the corresponding PE field is set.</description>
                  <value>#1</value>
                </enumeratedValue>
              </enumeratedValues>
            </field>
            <field>
              <name>PE</name>
              <description>Pull Enable</description>
              <bitOffset>1</bitOffset>
              <bitWidth>1</bitWidth>
              <access>read-only</access>
              <enumeratedValues>
                <enumeratedValue>
                  <name>0</name>
                  <description>Internal pullup or pulldown resistor is not enabled on the corresponding pin.</description>
                  <value>#0</value>
                </enumeratedValue>
                <enumeratedValue>
                  <name>1</name>
                  <description>Internal pullup or pulldown resistor is enabled on the corresponding pin, if the pin is configured as a digital input.</description>
                  <value>#1</value>
                </enumeratedValue>
              </enumeratedValues>
            </field>
            <field>
              <name>SRE</name>
              <description>Slew Rate Enable</description>
              <bitOffset>2</bitOffset>
              <bitWidth>1</bitWidth>
              <access>read-only</access>
              <enumeratedValues>
                <enumeratedValue>
                  <name>0</name>
                  <description>Fast slew rate is configured on the corresponding pin, if the pin is configured as a digital output.</description>
                  <value>#0</value>
                </enumeratedValue>
                <enumeratedValue>
                  <name>1</name>
                  <description>Slow slew rate is configured on the corresponding pin, if the pin is configured as a digital output.</description>
                  <value>#1</value>
                </enumeratedValue>
              </enumeratedValues>
            </field>
            <field>
              <name>PFE</name>
              <description>Passive Filter Enable</description>
              <bitOffset>4</bitOffset>
              <bitWidth>1</bitWidth>
              <access>read-only</access>
              <enumeratedValues>
                <enumeratedValue>
                  <name>0</name>
                  <description>Passive input filter is disabled on the corresponding pin.</description>
                  <value>#0</value>
                </enumeratedValue>
                <enumeratedValue>
                  <name>1</name>
                  <description>Passive input filter is enabled on the corresponding pin, if the pin is configured as a digital input. Refer to the device data sheet for filter characteristics.</description>
                  <value>#1</value>
                </enumeratedValue>
              </enumeratedValues>
            </field>
            <field>
              <name>DSE</name>
              <description>Drive Strength Enable</description>
              <bitOffset>6</bitOffset>
              <bitWidth>1</bitWidth>
              <access>read-only</access>
              <enumeratedValues>
                <enumeratedValue>
                  <name>0</name>
                  <description>Low drive strength is configured on the corresponding pin, if pin is configured as a digital output.</description>
                  <value>#0</value>
                </enumeratedValue>
                <enumeratedValue>
                  <name>1</name>
                  <description>High drive strength is configured on the corresponding pin, if pin is configured as a digital output.</description>
                  <value>#1</value>
                </enumeratedValue>
              </enumeratedValues>
            </field>
            <field>
              <name>MUX</name>
              <description>Pin Mux Control</description>
              <bitOffset>8</bitOffset>
              <bitWidth>3</bitWidth>
              <access>read-write</access>
              <enumeratedValues>
                <enumeratedValue>
                  <name>000</name>
                  <description>Pin disabled (analog).</description>
                  <value>#000</value>
                </enumeratedValue>
                <enumeratedValue>
                  <name>001</name>
                  <description>Alternative 1 (GPIO).</description>
                  <value>#001</value>
                </enumeratedValue>
                <enumeratedValue>
                  <name>010</name>
                  <description>Alternative 2 (chip-specific).</description>
                  <value>#010</value>
                </enumeratedValue>
                <enumeratedValue>
                  <name>011</name>
                  <description>Alternative 3 (chip-specific).</description>
                  <value>#011</value>
                </enumeratedValue>
                <enumeratedValue>
                  <name>100</name>
                  <description>Alternative 4 (chip-specific).</description>
                  <value>#100</value>
                </enumeratedValue>
                <enumeratedValue>
                  <name>101</name>
                  <description>Alternative 5 (chip-specific).</description>
                  <value>#101</value>
                </enumeratedValue>
                <enumeratedValue>
                  <name>110</name>
                  <description>Alternative 6 (chip-specific).</description>
                  <value>#110</value>
                </enumeratedValue>
                <enumeratedValue>
                  <name>111</name>
                  <description>Alternative 7 (chip-specific).</description>
                  <value>#111</value>
                </enumeratedValue>
              </enumeratedValues>
            </field>
            <field>
              <name>IRQC</name>
              <description>Interrupt Configuration</description>
              <bitOffset>16</bitOffset>
              <bitWidth>4</bitWidth>
              <access>read-write</access>
              <enumeratedValues>
                <enumeratedValue>
                  <name>0000</name>
                  <description>Interrupt/DMA request disabled.</description>
                  <value>#0000</value>
                </enumeratedValue>
                <enumeratedValue>
                  <name>0001</name>
                  <description>DMA request on rising edge.</description>
                  <value>#0001</value>
                </enumeratedValue>
                <enumeratedValue>
                  <name>0010</name>
                  <description>DMA request on falling edge.</description>
                  <value>#0010</value>
                </enumeratedValue>
                <enumeratedValue>
                  <name>0011</name>
                  <description>DMA request on either edge.</description>
                  <value>#0011</value>
                </enumeratedValue>
                <enumeratedValue>
                  <name>1000</name>
                  <description>Interrupt when logic 0.</description>
                  <value>#1000</value>
                </enumeratedValue>
                <enumeratedValue>
                  <name>1001</name>
                  <description>Interrupt on rising-edge.</description>
                  <value>#1001</value>
                </enumeratedValue>
                <enumeratedValue>
                  <name>1010</name>
                  <description>Interrupt on falling-edge.</description>
                  <value>#1010</value>
                </enumeratedValue>
                <enumeratedValue>
                  <name>1011</name>
                  <description>Interrupt on either edge.</description>
                  <value>#1011</value>
                </enumeratedValue>
                <enumeratedValue>
                  <name>1100</name>
                  <description>Interrupt when logic 1.</description>
                  <value>#1100</value>
                </enumeratedValue>
              </enumeratedValues>
            </field>
            <field>
              <name>ISF</name>
              <description>Interrupt Status Flag</description>
              <bitOffset>24</bitOffset>
              <bitWidth>1</bitWidth>
              <access>read-write</access>
              <enumeratedValues>
                <enumeratedValue>
                  <name>0</name>
                  <description>Configured interrupt is not detected.</description>
                  <value>#0</value>
                </enumeratedValue>
                <enumeratedValue>
                  <name>1</name>
                  <description>Configured interrupt is detected. If the pin is configured to generate a DMA request, then the corresponding flag will be cleared automatically at the completion of the requested DMA transfer. Otherwise, the flag remains set until a logic 1 is written to the flag. If the pin is configured for a level sensitive interrupt and the pin remains asserted, then the flag is set again immediately after it is cleared.</description>
                  <value>#1</value>
                </enumeratedValue>
              </enumeratedValues>
            </field>
          </fields>
        </register>
        <register>
          <name>PCR6</name>
          <description>Pin Control Register n</description>
          <addressOffset>0x18</addressOffset>
          <size>32</size>
          <access>read-write</access>
          <resetValue>0</resetValue>
          <resetMask>0xFFFFFFFF</resetMask>
          <fields>
            <field>
              <name>PS</name>
              <description>Pull Select</description>
              <bitOffset>0</bitOffset>
              <bitWidth>1</bitWidth>
              <access>read-only</access>
              <enumeratedValues>
                <enumeratedValue>
                  <name>0</name>
                  <description>Internal pulldown resistor is enabled on the corresponding pin, if the corresponding PE field is set.</description>
                  <value>#0</value>
                </enumeratedValue>
                <enumeratedValue>
                  <name>1</name>
                  <description>Internal pullup resistor is enabled on the corresponding pin, if the corresponding PE field is set.</description>
                  <value>#1</value>
                </enumeratedValue>
              </enumeratedValues>
            </field>
            <field>
              <name>PE</name>
              <description>Pull Enable</description>
              <bitOffset>1</bitOffset>
              <bitWidth>1</bitWidth>
              <access>read-only</access>
              <enumeratedValues>
                <enumeratedValue>
                  <name>0</name>
                  <description>Internal pullup or pulldown resistor is not enabled on the corresponding pin.</description>
                  <value>#0</value>
                </enumeratedValue>
                <enumeratedValue>
                  <name>1</name>
                  <description>Internal pullup or pulldown resistor is enabled on the corresponding pin, if the pin is configured as a digital input.</description>
                  <value>#1</value>
                </enumeratedValue>
              </enumeratedValues>
            </field>
            <field>
              <name>SRE</name>
              <description>Slew Rate Enable</description>
              <bitOffset>2</bitOffset>
              <bitWidth>1</bitWidth>
              <access>read-only</access>
              <enumeratedValues>
                <enumeratedValue>
                  <name>0</name>
                  <description>Fast slew rate is configured on the corresponding pin, if the pin is configured as a digital output.</description>
                  <value>#0</value>
                </enumeratedValue>
                <enumeratedValue>
                  <name>1</name>
                  <description>Slow slew rate is configured on the corresponding pin, if the pin is configured as a digital output.</description>
                  <value>#1</value>
                </enumeratedValue>
              </enumeratedValues>
            </field>
            <field>
              <name>PFE</name>
              <description>Passive Filter Enable</description>
              <bitOffset>4</bitOffset>
              <bitWidth>1</bitWidth>
              <access>read-only</access>
              <enumeratedValues>
                <enumeratedValue>
                  <name>0</name>
                  <description>Passive input filter is disabled on the corresponding pin.</description>
                  <value>#0</value>
                </enumeratedValue>
                <enumeratedValue>
                  <name>1</name>
                  <description>Passive input filter is enabled on the corresponding pin, if the pin is configured as a digital input. Refer to the device data sheet for filter characteristics.</description>
                  <value>#1</value>
                </enumeratedValue>
              </enumeratedValues>
            </field>
            <field>
              <name>DSE</name>
              <description>Drive Strength Enable</description>
              <bitOffset>6</bitOffset>
              <bitWidth>1</bitWidth>
              <access>read-only</access>
              <enumeratedValues>
                <enumeratedValue>
                  <name>0</name>
                  <description>Low drive strength is configured on the corresponding pin, if pin is configured as a digital output.</description>
                  <value>#0</value>
                </enumeratedValue>
                <enumeratedValue>
                  <name>1</name>
                  <description>High drive strength is configured on the corresponding pin, if pin is configured as a digital output.</description>
                  <value>#1</value>
                </enumeratedValue>
              </enumeratedValues>
            </field>
            <field>
              <name>MUX</name>
              <description>Pin Mux Control</description>
              <bitOffset>8</bitOffset>
              <bitWidth>3</bitWidth>
              <access>read-write</access>
              <enumeratedValues>
                <enumeratedValue>
                  <name>000</name>
                  <description>Pin disabled (analog).</description>
                  <value>#000</value>
                </enumeratedValue>
                <enumeratedValue>
                  <name>001</name>
                  <description>Alternative 1 (GPIO).</description>
                  <value>#001</value>
                </enumeratedValue>
                <enumeratedValue>
                  <name>010</name>
                  <description>Alternative 2 (chip-specific).</description>
                  <value>#010</value>
                </enumeratedValue>
                <enumeratedValue>
                  <name>011</name>
                  <description>Alternative 3 (chip-specific).</description>
                  <value>#011</value>
                </enumeratedValue>
                <enumeratedValue>
                  <name>100</name>
                  <description>Alternative 4 (chip-specific).</description>
                  <value>#100</value>
                </enumeratedValue>
                <enumeratedValue>
                  <name>101</name>
                  <description>Alternative 5 (chip-specific).</description>
                  <value>#101</value>
                </enumeratedValue>
                <enumeratedValue>
                  <name>110</name>
                  <description>Alternative 6 (chip-specific).</description>
                  <value>#110</value>
                </enumeratedValue>
                <enumeratedValue>
                  <name>111</name>
                  <description>Alternative 7 (chip-specific).</description>
                  <value>#111</value>
                </enumeratedValue>
              </enumeratedValues>
            </field>
            <field>
              <name>IRQC</name>
              <description>Interrupt Configuration</description>
              <bitOffset>16</bitOffset>
              <bitWidth>4</bitWidth>
              <access>read-write</access>
              <enumeratedValues>
                <enumeratedValue>
                  <name>0000</name>
                  <description>Interrupt/DMA request disabled.</description>
                  <value>#0000</value>
                </enumeratedValue>
                <enumeratedValue>
                  <name>0001</name>
                  <description>DMA request on rising edge.</description>
                  <value>#0001</value>
                </enumeratedValue>
                <enumeratedValue>
                  <name>0010</name>
                  <description>DMA request on falling edge.</description>
                  <value>#0010</value>
                </enumeratedValue>
                <enumeratedValue>
                  <name>0011</name>
                  <description>DMA request on either edge.</description>
                  <value>#0011</value>
                </enumeratedValue>
                <enumeratedValue>
                  <name>1000</name>
                  <description>Interrupt when logic 0.</description>
                  <value>#1000</value>
                </enumeratedValue>
                <enumeratedValue>
                  <name>1001</name>
                  <description>Interrupt on rising-edge.</description>
                  <value>#1001</value>
                </enumeratedValue>
                <enumeratedValue>
                  <name>1010</name>
                  <description>Interrupt on falling-edge.</description>
                  <value>#1010</value>
                </enumeratedValue>
                <enumeratedValue>
                  <name>1011</name>
                  <description>Interrupt on either edge.</description>
                  <value>#1011</value>
                </enumeratedValue>
                <enumeratedValue>
                  <name>1100</name>
                  <description>Interrupt when logic 1.</description>
                  <value>#1100</value>
                </enumeratedValue>
              </enumeratedValues>
            </field>
            <field>
              <name>ISF</name>
              <description>Interrupt Status Flag</description>
              <bitOffset>24</bitOffset>
              <bitWidth>1</bitWidth>
              <access>read-write</access>
              <enumeratedValues>
                <enumeratedValue>
                  <name>0</name>
                  <description>Configured interrupt is not detected.</description>
                  <value>#0</value>
                </enumeratedValue>
                <enumeratedValue>
                  <name>1</name>
                  <description>Configured interrupt is detected. If the pin is configured to generate a DMA request, then the corresponding flag will be cleared automatically at the completion of the requested DMA transfer. Otherwise, the flag remains set until a logic 1 is written to the flag. If the pin is configured for a level sensitive interrupt and the pin remains asserted, then the flag is set again immediately after it is cleared.</description>
                  <value>#1</value>
                </enumeratedValue>
              </enumeratedValues>
            </field>
          </fields>
        </register>
        <register>
          <name>PCR7</name>
          <description>Pin Control Register n</description>
          <addressOffset>0x1C</addressOffset>
          <size>32</size>
          <access>read-write</access>
          <resetValue>0</resetValue>
          <resetMask>0xFFFFFFFF</resetMask>
          <fields>
            <field>
              <name>PS</name>
              <description>Pull Select</description>
              <bitOffset>0</bitOffset>
              <bitWidth>1</bitWidth>
              <access>read-only</access>
              <enumeratedValues>
                <enumeratedValue>
                  <name>0</name>
                  <description>Internal pulldown resistor is enabled on the corresponding pin, if the corresponding PE field is set.</description>
                  <value>#0</value>
                </enumeratedValue>
                <enumeratedValue>
                  <name>1</name>
                  <description>Internal pullup resistor is enabled on the corresponding pin, if the corresponding PE field is set.</description>
                  <value>#1</value>
                </enumeratedValue>
              </enumeratedValues>
            </field>
            <field>
              <name>PE</name>
              <description>Pull Enable</description>
              <bitOffset>1</bitOffset>
              <bitWidth>1</bitWidth>
              <access>read-only</access>
              <enumeratedValues>
                <enumeratedValue>
                  <name>0</name>
                  <description>Internal pullup or pulldown resistor is not enabled on the corresponding pin.</description>
                  <value>#0</value>
                </enumeratedValue>
                <enumeratedValue>
                  <name>1</name>
                  <description>Internal pullup or pulldown resistor is enabled on the corresponding pin, if the pin is configured as a digital input.</description>
                  <value>#1</value>
                </enumeratedValue>
              </enumeratedValues>
            </field>
            <field>
              <name>SRE</name>
              <description>Slew Rate Enable</description>
              <bitOffset>2</bitOffset>
              <bitWidth>1</bitWidth>
              <access>read-only</access>
              <enumeratedValues>
                <enumeratedValue>
                  <name>0</name>
                  <description>Fast slew rate is configured on the corresponding pin, if the pin is configured as a digital output.</description>
                  <value>#0</value>
                </enumeratedValue>
                <enumeratedValue>
                  <name>1</name>
                  <description>Slow slew rate is configured on the corresponding pin, if the pin is configured as a digital output.</description>
                  <value>#1</value>
                </enumeratedValue>
              </enumeratedValues>
            </field>
            <field>
              <name>PFE</name>
              <description>Passive Filter Enable</description>
              <bitOffset>4</bitOffset>
              <bitWidth>1</bitWidth>
              <access>read-only</access>
              <enumeratedValues>
                <enumeratedValue>
                  <name>0</name>
                  <description>Passive input filter is disabled on the corresponding pin.</description>
                  <value>#0</value>
                </enumeratedValue>
                <enumeratedValue>
                  <name>1</name>
                  <description>Passive input filter is enabled on the corresponding pin, if the pin is configured as a digital input. Refer to the device data sheet for filter characteristics.</description>
                  <value>#1</value>
                </enumeratedValue>
              </enumeratedValues>
            </field>
            <field>
              <name>DSE</name>
              <description>Drive Strength Enable</description>
              <bitOffset>6</bitOffset>
              <bitWidth>1</bitWidth>
              <access>read-only</access>
              <enumeratedValues>
                <enumeratedValue>
                  <name>0</name>
                  <description>Low drive strength is configured on the corresponding pin, if pin is configured as a digital output.</description>
                  <value>#0</value>
                </enumeratedValue>
                <enumeratedValue>
                  <name>1</name>
                  <description>High drive strength is configured on the corresponding pin, if pin is configured as a digital output.</description>
                  <value>#1</value>
                </enumeratedValue>
              </enumeratedValues>
            </field>
            <field>
              <name>MUX</name>
              <description>Pin Mux Control</description>
              <bitOffset>8</bitOffset>
              <bitWidth>3</bitWidth>
              <access>read-write</access>
              <enumeratedValues>
                <enumeratedValue>
                  <name>000</name>
                  <description>Pin disabled (analog).</description>
                  <value>#000</value>
                </enumeratedValue>
                <enumeratedValue>
                  <name>001</name>
                  <description>Alternative 1 (GPIO).</description>
                  <value>#001</value>
                </enumeratedValue>
                <enumeratedValue>
                  <name>010</name>
                  <description>Alternative 2 (chip-specific).</description>
                  <value>#010</value>
                </enumeratedValue>
                <enumeratedValue>
                  <name>011</name>
                  <description>Alternative 3 (chip-specific).</description>
                  <value>#011</value>
                </enumeratedValue>
                <enumeratedValue>
                  <name>100</name>
                  <description>Alternative 4 (chip-specific).</description>
                  <value>#100</value>
                </enumeratedValue>
                <enumeratedValue>
                  <name>101</name>
                  <description>Alternative 5 (chip-specific).</description>
                  <value>#101</value>
                </enumeratedValue>
                <enumeratedValue>
                  <name>110</name>
                  <description>Alternative 6 (chip-specific).</description>
                  <value>#110</value>
                </enumeratedValue>
                <enumeratedValue>
                  <name>111</name>
                  <description>Alternative 7 (chip-specific).</description>
                  <value>#111</value>
                </enumeratedValue>
              </enumeratedValues>
            </field>
            <field>
              <name>IRQC</name>
              <description>Interrupt Configuration</description>
              <bitOffset>16</bitOffset>
              <bitWidth>4</bitWidth>
              <access>read-write</access>
              <enumeratedValues>
                <enumeratedValue>
                  <name>0000</name>
                  <description>Interrupt/DMA request disabled.</description>
                  <value>#0000</value>
                </enumeratedValue>
                <enumeratedValue>
                  <name>0001</name>
                  <description>DMA request on rising edge.</description>
                  <value>#0001</value>
                </enumeratedValue>
                <enumeratedValue>
                  <name>0010</name>
                  <description>DMA request on falling edge.</description>
                  <value>#0010</value>
                </enumeratedValue>
                <enumeratedValue>
                  <name>0011</name>
                  <description>DMA request on either edge.</description>
                  <value>#0011</value>
                </enumeratedValue>
                <enumeratedValue>
                  <name>1000</name>
                  <description>Interrupt when logic 0.</description>
                  <value>#1000</value>
                </enumeratedValue>
                <enumeratedValue>
                  <name>1001</name>
                  <description>Interrupt on rising-edge.</description>
                  <value>#1001</value>
                </enumeratedValue>
                <enumeratedValue>
                  <name>1010</name>
                  <description>Interrupt on falling-edge.</description>
                  <value>#1010</value>
                </enumeratedValue>
                <enumeratedValue>
                  <name>1011</name>
                  <description>Interrupt on either edge.</description>
                  <value>#1011</value>
                </enumeratedValue>
                <enumeratedValue>
                  <name>1100</name>
                  <description>Interrupt when logic 1.</description>
                  <value>#1100</value>
                </enumeratedValue>
              </enumeratedValues>
            </field>
            <field>
              <name>ISF</name>
              <description>Interrupt Status Flag</description>
              <bitOffset>24</bitOffset>
              <bitWidth>1</bitWidth>
              <access>read-write</access>
              <enumeratedValues>
                <enumeratedValue>
                  <name>0</name>
                  <description>Configured interrupt is not detected.</description>
                  <value>#0</value>
                </enumeratedValue>
                <enumeratedValue>
                  <name>1</name>
                  <description>Configured interrupt is detected. If the pin is configured to generate a DMA request, then the corresponding flag will be cleared automatically at the completion of the requested DMA transfer. Otherwise, the flag remains set until a logic 1 is written to the flag. If the pin is configured for a level sensitive interrupt and the pin remains asserted, then the flag is set again immediately after it is cleared.</description>
                  <value>#1</value>
                </enumeratedValue>
              </enumeratedValues>
            </field>
          </fields>
        </register>
        <register>
          <name>PCR8</name>
          <description>Pin Control Register n</description>
          <addressOffset>0x20</addressOffset>
          <size>32</size>
          <access>read-write</access>
          <resetValue>0</resetValue>
          <resetMask>0xFFFFFFFF</resetMask>
          <fields>
            <field>
              <name>PS</name>
              <description>Pull Select</description>
              <bitOffset>0</bitOffset>
              <bitWidth>1</bitWidth>
              <access>read-only</access>
              <enumeratedValues>
                <enumeratedValue>
                  <name>0</name>
                  <description>Internal pulldown resistor is enabled on the corresponding pin, if the corresponding PE field is set.</description>
                  <value>#0</value>
                </enumeratedValue>
                <enumeratedValue>
                  <name>1</name>
                  <description>Internal pullup resistor is enabled on the corresponding pin, if the corresponding PE field is set.</description>
                  <value>#1</value>
                </enumeratedValue>
              </enumeratedValues>
            </field>
            <field>
              <name>PE</name>
              <description>Pull Enable</description>
              <bitOffset>1</bitOffset>
              <bitWidth>1</bitWidth>
              <access>read-only</access>
              <enumeratedValues>
                <enumeratedValue>
                  <name>0</name>
                  <description>Internal pullup or pulldown resistor is not enabled on the corresponding pin.</description>
                  <value>#0</value>
                </enumeratedValue>
                <enumeratedValue>
                  <name>1</name>
                  <description>Internal pullup or pulldown resistor is enabled on the corresponding pin, if the pin is configured as a digital input.</description>
                  <value>#1</value>
                </enumeratedValue>
              </enumeratedValues>
            </field>
            <field>
              <name>SRE</name>
              <description>Slew Rate Enable</description>
              <bitOffset>2</bitOffset>
              <bitWidth>1</bitWidth>
              <access>read-only</access>
              <enumeratedValues>
                <enumeratedValue>
                  <name>0</name>
                  <description>Fast slew rate is configured on the corresponding pin, if the pin is configured as a digital output.</description>
                  <value>#0</value>
                </enumeratedValue>
                <enumeratedValue>
                  <name>1</name>
                  <description>Slow slew rate is configured on the corresponding pin, if the pin is configured as a digital output.</description>
                  <value>#1</value>
                </enumeratedValue>
              </enumeratedValues>
            </field>
            <field>
              <name>PFE</name>
              <description>Passive Filter Enable</description>
              <bitOffset>4</bitOffset>
              <bitWidth>1</bitWidth>
              <access>read-only</access>
              <enumeratedValues>
                <enumeratedValue>
                  <name>0</name>
                  <description>Passive input filter is disabled on the corresponding pin.</description>
                  <value>#0</value>
                </enumeratedValue>
                <enumeratedValue>
                  <name>1</name>
                  <description>Passive input filter is enabled on the corresponding pin, if the pin is configured as a digital input. Refer to the device data sheet for filter characteristics.</description>
                  <value>#1</value>
                </enumeratedValue>
              </enumeratedValues>
            </field>
            <field>
              <name>DSE</name>
              <description>Drive Strength Enable</description>
              <bitOffset>6</bitOffset>
              <bitWidth>1</bitWidth>
              <access>read-only</access>
              <enumeratedValues>
                <enumeratedValue>
                  <name>0</name>
                  <description>Low drive strength is configured on the corresponding pin, if pin is configured as a digital output.</description>
                  <value>#0</value>
                </enumeratedValue>
                <enumeratedValue>
                  <name>1</name>
                  <description>High drive strength is configured on the corresponding pin, if pin is configured as a digital output.</description>
                  <value>#1</value>
                </enumeratedValue>
              </enumeratedValues>
            </field>
            <field>
              <name>MUX</name>
              <description>Pin Mux Control</description>
              <bitOffset>8</bitOffset>
              <bitWidth>3</bitWidth>
              <access>read-write</access>
              <enumeratedValues>
                <enumeratedValue>
                  <name>000</name>
                  <description>Pin disabled (analog).</description>
                  <value>#000</value>
                </enumeratedValue>
                <enumeratedValue>
                  <name>001</name>
                  <description>Alternative 1 (GPIO).</description>
                  <value>#001</value>
                </enumeratedValue>
                <enumeratedValue>
                  <name>010</name>
                  <description>Alternative 2 (chip-specific).</description>
                  <value>#010</value>
                </enumeratedValue>
                <enumeratedValue>
                  <name>011</name>
                  <description>Alternative 3 (chip-specific).</description>
                  <value>#011</value>
                </enumeratedValue>
                <enumeratedValue>
                  <name>100</name>
                  <description>Alternative 4 (chip-specific).</description>
                  <value>#100</value>
                </enumeratedValue>
                <enumeratedValue>
                  <name>101</name>
                  <description>Alternative 5 (chip-specific).</description>
                  <value>#101</value>
                </enumeratedValue>
                <enumeratedValue>
                  <name>110</name>
                  <description>Alternative 6 (chip-specific).</description>
                  <value>#110</value>
                </enumeratedValue>
                <enumeratedValue>
                  <name>111</name>
                  <description>Alternative 7 (chip-specific).</description>
                  <value>#111</value>
                </enumeratedValue>
              </enumeratedValues>
            </field>
            <field>
              <name>IRQC</name>
              <description>Interrupt Configuration</description>
              <bitOffset>16</bitOffset>
              <bitWidth>4</bitWidth>
              <access>read-write</access>
              <enumeratedValues>
                <enumeratedValue>
                  <name>0000</name>
                  <description>Interrupt/DMA request disabled.</description>
                  <value>#0000</value>
                </enumeratedValue>
                <enumeratedValue>
                  <name>0001</name>
                  <description>DMA request on rising edge.</description>
                  <value>#0001</value>
                </enumeratedValue>
                <enumeratedValue>
                  <name>0010</name>
                  <description>DMA request on falling edge.</description>
                  <value>#0010</value>
                </enumeratedValue>
                <enumeratedValue>
                  <name>0011</name>
                  <description>DMA request on either edge.</description>
                  <value>#0011</value>
                </enumeratedValue>
                <enumeratedValue>
                  <name>1000</name>
                  <description>Interrupt when logic 0.</description>
                  <value>#1000</value>
                </enumeratedValue>
                <enumeratedValue>
                  <name>1001</name>
                  <description>Interrupt on rising-edge.</description>
                  <value>#1001</value>
                </enumeratedValue>
                <enumeratedValue>
                  <name>1010</name>
                  <description>Interrupt on falling-edge.</description>
                  <value>#1010</value>
                </enumeratedValue>
                <enumeratedValue>
                  <name>1011</name>
                  <description>Interrupt on either edge.</description>
                  <value>#1011</value>
                </enumeratedValue>
                <enumeratedValue>
                  <name>1100</name>
                  <description>Interrupt when logic 1.</description>
                  <value>#1100</value>
                </enumeratedValue>
              </enumeratedValues>
            </field>
            <field>
              <name>ISF</name>
              <description>Interrupt Status Flag</description>
              <bitOffset>24</bitOffset>
              <bitWidth>1</bitWidth>
              <access>read-write</access>
              <enumeratedValues>
                <enumeratedValue>
                  <name>0</name>
                  <description>Configured interrupt is not detected.</description>
                  <value>#0</value>
                </enumeratedValue>
                <enumeratedValue>
                  <name>1</name>
                  <description>Configured interrupt is detected. If the pin is configured to generate a DMA request, then the corresponding flag will be cleared automatically at the completion of the requested DMA transfer. Otherwise, the flag remains set until a logic 1 is written to the flag. If the pin is configured for a level sensitive interrupt and the pin remains asserted, then the flag is set again immediately after it is cleared.</description>
                  <value>#1</value>
                </enumeratedValue>
              </enumeratedValues>
            </field>
          </fields>
        </register>
        <register>
          <name>PCR9</name>
          <description>Pin Control Register n</description>
          <addressOffset>0x24</addressOffset>
          <size>32</size>
          <access>read-write</access>
          <resetValue>0</resetValue>
          <resetMask>0xFFFFFFFF</resetMask>
          <fields>
            <field>
              <name>PS</name>
              <description>Pull Select</description>
              <bitOffset>0</bitOffset>
              <bitWidth>1</bitWidth>
              <access>read-only</access>
              <enumeratedValues>
                <enumeratedValue>
                  <name>0</name>
                  <description>Internal pulldown resistor is enabled on the corresponding pin, if the corresponding PE field is set.</description>
                  <value>#0</value>
                </enumeratedValue>
                <enumeratedValue>
                  <name>1</name>
                  <description>Internal pullup resistor is enabled on the corresponding pin, if the corresponding PE field is set.</description>
                  <value>#1</value>
                </enumeratedValue>
              </enumeratedValues>
            </field>
            <field>
              <name>PE</name>
              <description>Pull Enable</description>
              <bitOffset>1</bitOffset>
              <bitWidth>1</bitWidth>
              <access>read-only</access>
              <enumeratedValues>
                <enumeratedValue>
                  <name>0</name>
                  <description>Internal pullup or pulldown resistor is not enabled on the corresponding pin.</description>
                  <value>#0</value>
                </enumeratedValue>
                <enumeratedValue>
                  <name>1</name>
                  <description>Internal pullup or pulldown resistor is enabled on the corresponding pin, if the pin is configured as a digital input.</description>
                  <value>#1</value>
                </enumeratedValue>
              </enumeratedValues>
            </field>
            <field>
              <name>SRE</name>
              <description>Slew Rate Enable</description>
              <bitOffset>2</bitOffset>
              <bitWidth>1</bitWidth>
              <access>read-only</access>
              <enumeratedValues>
                <enumeratedValue>
                  <name>0</name>
                  <description>Fast slew rate is configured on the corresponding pin, if the pin is configured as a digital output.</description>
                  <value>#0</value>
                </enumeratedValue>
                <enumeratedValue>
                  <name>1</name>
                  <description>Slow slew rate is configured on the corresponding pin, if the pin is configured as a digital output.</description>
                  <value>#1</value>
                </enumeratedValue>
              </enumeratedValues>
            </field>
            <field>
              <name>PFE</name>
              <description>Passive Filter Enable</description>
              <bitOffset>4</bitOffset>
              <bitWidth>1</bitWidth>
              <access>read-only</access>
              <enumeratedValues>
                <enumeratedValue>
                  <name>0</name>
                  <description>Passive input filter is disabled on the corresponding pin.</description>
                  <value>#0</value>
                </enumeratedValue>
                <enumeratedValue>
                  <name>1</name>
                  <description>Passive input filter is enabled on the corresponding pin, if the pin is configured as a digital input. Refer to the device data sheet for filter characteristics.</description>
                  <value>#1</value>
                </enumeratedValue>
              </enumeratedValues>
            </field>
            <field>
              <name>DSE</name>
              <description>Drive Strength Enable</description>
              <bitOffset>6</bitOffset>
              <bitWidth>1</bitWidth>
              <access>read-only</access>
              <enumeratedValues>
                <enumeratedValue>
                  <name>0</name>
                  <description>Low drive strength is configured on the corresponding pin, if pin is configured as a digital output.</description>
                  <value>#0</value>
                </enumeratedValue>
                <enumeratedValue>
                  <name>1</name>
                  <description>High drive strength is configured on the corresponding pin, if pin is configured as a digital output.</description>
                  <value>#1</value>
                </enumeratedValue>
              </enumeratedValues>
            </field>
            <field>
              <name>MUX</name>
              <description>Pin Mux Control</description>
              <bitOffset>8</bitOffset>
              <bitWidth>3</bitWidth>
              <access>read-write</access>
              <enumeratedValues>
                <enumeratedValue>
                  <name>000</name>
                  <description>Pin disabled (analog).</description>
                  <value>#000</value>
                </enumeratedValue>
                <enumeratedValue>
                  <name>001</name>
                  <description>Alternative 1 (GPIO).</description>
                  <value>#001</value>
                </enumeratedValue>
                <enumeratedValue>
                  <name>010</name>
                  <description>Alternative 2 (chip-specific).</description>
                  <value>#010</value>
                </enumeratedValue>
                <enumeratedValue>
                  <name>011</name>
                  <description>Alternative 3 (chip-specific).</description>
                  <value>#011</value>
                </enumeratedValue>
                <enumeratedValue>
                  <name>100</name>
                  <description>Alternative 4 (chip-specific).</description>
                  <value>#100</value>
                </enumeratedValue>
                <enumeratedValue>
                  <name>101</name>
                  <description>Alternative 5 (chip-specific).</description>
                  <value>#101</value>
                </enumeratedValue>
                <enumeratedValue>
                  <name>110</name>
                  <description>Alternative 6 (chip-specific).</description>
                  <value>#110</value>
                </enumeratedValue>
                <enumeratedValue>
                  <name>111</name>
                  <description>Alternative 7 (chip-specific).</description>
                  <value>#111</value>
                </enumeratedValue>
              </enumeratedValues>
            </field>
            <field>
              <name>IRQC</name>
              <description>Interrupt Configuration</description>
              <bitOffset>16</bitOffset>
              <bitWidth>4</bitWidth>
              <access>read-write</access>
              <enumeratedValues>
                <enumeratedValue>
                  <name>0000</name>
                  <description>Interrupt/DMA request disabled.</description>
                  <value>#0000</value>
                </enumeratedValue>
                <enumeratedValue>
                  <name>0001</name>
                  <description>DMA request on rising edge.</description>
                  <value>#0001</value>
                </enumeratedValue>
                <enumeratedValue>
                  <name>0010</name>
                  <description>DMA request on falling edge.</description>
                  <value>#0010</value>
                </enumeratedValue>
                <enumeratedValue>
                  <name>0011</name>
                  <description>DMA request on either edge.</description>
                  <value>#0011</value>
                </enumeratedValue>
                <enumeratedValue>
                  <name>1000</name>
                  <description>Interrupt when logic 0.</description>
                  <value>#1000</value>
                </enumeratedValue>
                <enumeratedValue>
                  <name>1001</name>
                  <description>Interrupt on rising-edge.</description>
                  <value>#1001</value>
                </enumeratedValue>
                <enumeratedValue>
                  <name>1010</name>
                  <description>Interrupt on falling-edge.</description>
                  <value>#1010</value>
                </enumeratedValue>
                <enumeratedValue>
                  <name>1011</name>
                  <description>Interrupt on either edge.</description>
                  <value>#1011</value>
                </enumeratedValue>
                <enumeratedValue>
                  <name>1100</name>
                  <description>Interrupt when logic 1.</description>
                  <value>#1100</value>
                </enumeratedValue>
              </enumeratedValues>
            </field>
            <field>
              <name>ISF</name>
              <description>Interrupt Status Flag</description>
              <bitOffset>24</bitOffset>
              <bitWidth>1</bitWidth>
              <access>read-write</access>
              <enumeratedValues>
                <enumeratedValue>
                  <name>0</name>
                  <description>Configured interrupt is not detected.</description>
                  <value>#0</value>
                </enumeratedValue>
                <enumeratedValue>
                  <name>1</name>
                  <description>Configured interrupt is detected. If the pin is configured to generate a DMA request, then the corresponding flag will be cleared automatically at the completion of the requested DMA transfer. Otherwise, the flag remains set until a logic 1 is written to the flag. If the pin is configured for a level sensitive interrupt and the pin remains asserted, then the flag is set again immediately after it is cleared.</description>
                  <value>#1</value>
                </enumeratedValue>
              </enumeratedValues>
            </field>
          </fields>
        </register>
        <register>
          <name>PCR10</name>
          <description>Pin Control Register n</description>
          <addressOffset>0x28</addressOffset>
          <size>32</size>
          <access>read-write</access>
          <resetValue>0</resetValue>
          <resetMask>0xFFFFFFFF</resetMask>
          <fields>
            <field>
              <name>PS</name>
              <description>Pull Select</description>
              <bitOffset>0</bitOffset>
              <bitWidth>1</bitWidth>
              <access>read-only</access>
              <enumeratedValues>
                <enumeratedValue>
                  <name>0</name>
                  <description>Internal pulldown resistor is enabled on the corresponding pin, if the corresponding PE field is set.</description>
                  <value>#0</value>
                </enumeratedValue>
                <enumeratedValue>
                  <name>1</name>
                  <description>Internal pullup resistor is enabled on the corresponding pin, if the corresponding PE field is set.</description>
                  <value>#1</value>
                </enumeratedValue>
              </enumeratedValues>
            </field>
            <field>
              <name>PE</name>
              <description>Pull Enable</description>
              <bitOffset>1</bitOffset>
              <bitWidth>1</bitWidth>
              <access>read-only</access>
              <enumeratedValues>
                <enumeratedValue>
                  <name>0</name>
                  <description>Internal pullup or pulldown resistor is not enabled on the corresponding pin.</description>
                  <value>#0</value>
                </enumeratedValue>
                <enumeratedValue>
                  <name>1</name>
                  <description>Internal pullup or pulldown resistor is enabled on the corresponding pin, if the pin is configured as a digital input.</description>
                  <value>#1</value>
                </enumeratedValue>
              </enumeratedValues>
            </field>
            <field>
              <name>SRE</name>
              <description>Slew Rate Enable</description>
              <bitOffset>2</bitOffset>
              <bitWidth>1</bitWidth>
              <access>read-only</access>
              <enumeratedValues>
                <enumeratedValue>
                  <name>0</name>
                  <description>Fast slew rate is configured on the corresponding pin, if the pin is configured as a digital output.</description>
                  <value>#0</value>
                </enumeratedValue>
                <enumeratedValue>
                  <name>1</name>
                  <description>Slow slew rate is configured on the corresponding pin, if the pin is configured as a digital output.</description>
                  <value>#1</value>
                </enumeratedValue>
              </enumeratedValues>
            </field>
            <field>
              <name>PFE</name>
              <description>Passive Filter Enable</description>
              <bitOffset>4</bitOffset>
              <bitWidth>1</bitWidth>
              <access>read-only</access>
              <enumeratedValues>
                <enumeratedValue>
                  <name>0</name>
                  <description>Passive input filter is disabled on the corresponding pin.</description>
                  <value>#0</value>
                </enumeratedValue>
                <enumeratedValue>
                  <name>1</name>
                  <description>Passive input filter is enabled on the corresponding pin, if the pin is configured as a digital input. Refer to the device data sheet for filter characteristics.</description>
                  <value>#1</value>
                </enumeratedValue>
              </enumeratedValues>
            </field>
            <field>
              <name>DSE</name>
              <description>Drive Strength Enable</description>
              <bitOffset>6</bitOffset>
              <bitWidth>1</bitWidth>
              <access>read-only</access>
              <enumeratedValues>
                <enumeratedValue>
                  <name>0</name>
                  <description>Low drive strength is configured on the corresponding pin, if pin is configured as a digital output.</description>
                  <value>#0</value>
                </enumeratedValue>
                <enumeratedValue>
                  <name>1</name>
                  <description>High drive strength is configured on the corresponding pin, if pin is configured as a digital output.</description>
                  <value>#1</value>
                </enumeratedValue>
              </enumeratedValues>
            </field>
            <field>
              <name>MUX</name>
              <description>Pin Mux Control</description>
              <bitOffset>8</bitOffset>
              <bitWidth>3</bitWidth>
              <access>read-write</access>
              <enumeratedValues>
                <enumeratedValue>
                  <name>000</name>
                  <description>Pin disabled (analog).</description>
                  <value>#000</value>
                </enumeratedValue>
                <enumeratedValue>
                  <name>001</name>
                  <description>Alternative 1 (GPIO).</description>
                  <value>#001</value>
                </enumeratedValue>
                <enumeratedValue>
                  <name>010</name>
                  <description>Alternative 2 (chip-specific).</description>
                  <value>#010</value>
                </enumeratedValue>
                <enumeratedValue>
                  <name>011</name>
                  <description>Alternative 3 (chip-specific).</description>
                  <value>#011</value>
                </enumeratedValue>
                <enumeratedValue>
                  <name>100</name>
                  <description>Alternative 4 (chip-specific).</description>
                  <value>#100</value>
                </enumeratedValue>
                <enumeratedValue>
                  <name>101</name>
                  <description>Alternative 5 (chip-specific).</description>
                  <value>#101</value>
                </enumeratedValue>
                <enumeratedValue>
                  <name>110</name>
                  <description>Alternative 6 (chip-specific).</description>
                  <value>#110</value>
                </enumeratedValue>
                <enumeratedValue>
                  <name>111</name>
                  <description>Alternative 7 (chip-specific).</description>
                  <value>#111</value>
                </enumeratedValue>
              </enumeratedValues>
            </field>
            <field>
              <name>IRQC</name>
              <description>Interrupt Configuration</description>
              <bitOffset>16</bitOffset>
              <bitWidth>4</bitWidth>
              <access>read-write</access>
              <enumeratedValues>
                <enumeratedValue>
                  <name>0000</name>
                  <description>Interrupt/DMA request disabled.</description>
                  <value>#0000</value>
                </enumeratedValue>
                <enumeratedValue>
                  <name>0001</name>
                  <description>DMA request on rising edge.</description>
                  <value>#0001</value>
                </enumeratedValue>
                <enumeratedValue>
                  <name>0010</name>
                  <description>DMA request on falling edge.</description>
                  <value>#0010</value>
                </enumeratedValue>
                <enumeratedValue>
                  <name>0011</name>
                  <description>DMA request on either edge.</description>
                  <value>#0011</value>
                </enumeratedValue>
                <enumeratedValue>
                  <name>1000</name>
                  <description>Interrupt when logic 0.</description>
                  <value>#1000</value>
                </enumeratedValue>
                <enumeratedValue>
                  <name>1001</name>
                  <description>Interrupt on rising-edge.</description>
                  <value>#1001</value>
                </enumeratedValue>
                <enumeratedValue>
                  <name>1010</name>
                  <description>Interrupt on falling-edge.</description>
                  <value>#1010</value>
                </enumeratedValue>
                <enumeratedValue>
                  <name>1011</name>
                  <description>Interrupt on either edge.</description>
                  <value>#1011</value>
                </enumeratedValue>
                <enumeratedValue>
                  <name>1100</name>
                  <description>Interrupt when logic 1.</description>
                  <value>#1100</value>
                </enumeratedValue>
              </enumeratedValues>
            </field>
            <field>
              <name>ISF</name>
              <description>Interrupt Status Flag</description>
              <bitOffset>24</bitOffset>
              <bitWidth>1</bitWidth>
              <access>read-write</access>
              <enumeratedValues>
                <enumeratedValue>
                  <name>0</name>
                  <description>Configured interrupt is not detected.</description>
                  <value>#0</value>
                </enumeratedValue>
                <enumeratedValue>
                  <name>1</name>
                  <description>Configured interrupt is detected. If the pin is configured to generate a DMA request, then the corresponding flag will be cleared automatically at the completion of the requested DMA transfer. Otherwise, the flag remains set until a logic 1 is written to the flag. If the pin is configured for a level sensitive interrupt and the pin remains asserted, then the flag is set again immediately after it is cleared.</description>
                  <value>#1</value>
                </enumeratedValue>
              </enumeratedValues>
            </field>
          </fields>
        </register>
        <register>
          <name>PCR11</name>
          <description>Pin Control Register n</description>
          <addressOffset>0x2C</addressOffset>
          <size>32</size>
          <access>read-write</access>
          <resetValue>0</resetValue>
          <resetMask>0xFFFFFFFF</resetMask>
          <fields>
            <field>
              <name>PS</name>
              <description>Pull Select</description>
              <bitOffset>0</bitOffset>
              <bitWidth>1</bitWidth>
              <access>read-only</access>
              <enumeratedValues>
                <enumeratedValue>
                  <name>0</name>
                  <description>Internal pulldown resistor is enabled on the corresponding pin, if the corresponding PE field is set.</description>
                  <value>#0</value>
                </enumeratedValue>
                <enumeratedValue>
                  <name>1</name>
                  <description>Internal pullup resistor is enabled on the corresponding pin, if the corresponding PE field is set.</description>
                  <value>#1</value>
                </enumeratedValue>
              </enumeratedValues>
            </field>
            <field>
              <name>PE</name>
              <description>Pull Enable</description>
              <bitOffset>1</bitOffset>
              <bitWidth>1</bitWidth>
              <access>read-only</access>
              <enumeratedValues>
                <enumeratedValue>
                  <name>0</name>
                  <description>Internal pullup or pulldown resistor is not enabled on the corresponding pin.</description>
                  <value>#0</value>
                </enumeratedValue>
                <enumeratedValue>
                  <name>1</name>
                  <description>Internal pullup or pulldown resistor is enabled on the corresponding pin, if the pin is configured as a digital input.</description>
                  <value>#1</value>
                </enumeratedValue>
              </enumeratedValues>
            </field>
            <field>
              <name>SRE</name>
              <description>Slew Rate Enable</description>
              <bitOffset>2</bitOffset>
              <bitWidth>1</bitWidth>
              <access>read-only</access>
              <enumeratedValues>
                <enumeratedValue>
                  <name>0</name>
                  <description>Fast slew rate is configured on the corresponding pin, if the pin is configured as a digital output.</description>
                  <value>#0</value>
                </enumeratedValue>
                <enumeratedValue>
                  <name>1</name>
                  <description>Slow slew rate is configured on the corresponding pin, if the pin is configured as a digital output.</description>
                  <value>#1</value>
                </enumeratedValue>
              </enumeratedValues>
            </field>
            <field>
              <name>PFE</name>
              <description>Passive Filter Enable</description>
              <bitOffset>4</bitOffset>
              <bitWidth>1</bitWidth>
              <access>read-only</access>
              <enumeratedValues>
                <enumeratedValue>
                  <name>0</name>
                  <description>Passive input filter is disabled on the corresponding pin.</description>
                  <value>#0</value>
                </enumeratedValue>
                <enumeratedValue>
                  <name>1</name>
                  <description>Passive input filter is enabled on the corresponding pin, if the pin is configured as a digital input. Refer to the device data sheet for filter characteristics.</description>
                  <value>#1</value>
                </enumeratedValue>
              </enumeratedValues>
            </field>
            <field>
              <name>DSE</name>
              <description>Drive Strength Enable</description>
              <bitOffset>6</bitOffset>
              <bitWidth>1</bitWidth>
              <access>read-only</access>
              <enumeratedValues>
                <enumeratedValue>
                  <name>0</name>
                  <description>Low drive strength is configured on the corresponding pin, if pin is configured as a digital output.</description>
                  <value>#0</value>
                </enumeratedValue>
                <enumeratedValue>
                  <name>1</name>
                  <description>High drive strength is configured on the corresponding pin, if pin is configured as a digital output.</description>
                  <value>#1</value>
                </enumeratedValue>
              </enumeratedValues>
            </field>
            <field>
              <name>MUX</name>
              <description>Pin Mux Control</description>
              <bitOffset>8</bitOffset>
              <bitWidth>3</bitWidth>
              <access>read-write</access>
              <enumeratedValues>
                <enumeratedValue>
                  <name>000</name>
                  <description>Pin disabled (analog).</description>
                  <value>#000</value>
                </enumeratedValue>
                <enumeratedValue>
                  <name>001</name>
                  <description>Alternative 1 (GPIO).</description>
                  <value>#001</value>
                </enumeratedValue>
                <enumeratedValue>
                  <name>010</name>
                  <description>Alternative 2 (chip-specific).</description>
                  <value>#010</value>
                </enumeratedValue>
                <enumeratedValue>
                  <name>011</name>
                  <description>Alternative 3 (chip-specific).</description>
                  <value>#011</value>
                </enumeratedValue>
                <enumeratedValue>
                  <name>100</name>
                  <description>Alternative 4 (chip-specific).</description>
                  <value>#100</value>
                </enumeratedValue>
                <enumeratedValue>
                  <name>101</name>
                  <description>Alternative 5 (chip-specific).</description>
                  <value>#101</value>
                </enumeratedValue>
                <enumeratedValue>
                  <name>110</name>
                  <description>Alternative 6 (chip-specific).</description>
                  <value>#110</value>
                </enumeratedValue>
                <enumeratedValue>
                  <name>111</name>
                  <description>Alternative 7 (chip-specific).</description>
                  <value>#111</value>
                </enumeratedValue>
              </enumeratedValues>
            </field>
            <field>
              <name>IRQC</name>
              <description>Interrupt Configuration</description>
              <bitOffset>16</bitOffset>
              <bitWidth>4</bitWidth>
              <access>read-write</access>
              <enumeratedValues>
                <enumeratedValue>
                  <name>0000</name>
                  <description>Interrupt/DMA request disabled.</description>
                  <value>#0000</value>
                </enumeratedValue>
                <enumeratedValue>
                  <name>0001</name>
                  <description>DMA request on rising edge.</description>
                  <value>#0001</value>
                </enumeratedValue>
                <enumeratedValue>
                  <name>0010</name>
                  <description>DMA request on falling edge.</description>
                  <value>#0010</value>
                </enumeratedValue>
                <enumeratedValue>
                  <name>0011</name>
                  <description>DMA request on either edge.</description>
                  <value>#0011</value>
                </enumeratedValue>
                <enumeratedValue>
                  <name>1000</name>
                  <description>Interrupt when logic 0.</description>
                  <value>#1000</value>
                </enumeratedValue>
                <enumeratedValue>
                  <name>1001</name>
                  <description>Interrupt on rising-edge.</description>
                  <value>#1001</value>
                </enumeratedValue>
                <enumeratedValue>
                  <name>1010</name>
                  <description>Interrupt on falling-edge.</description>
                  <value>#1010</value>
                </enumeratedValue>
                <enumeratedValue>
                  <name>1011</name>
                  <description>Interrupt on either edge.</description>
                  <value>#1011</value>
                </enumeratedValue>
                <enumeratedValue>
                  <name>1100</name>
                  <description>Interrupt when logic 1.</description>
                  <value>#1100</value>
                </enumeratedValue>
              </enumeratedValues>
            </field>
            <field>
              <name>ISF</name>
              <description>Interrupt Status Flag</description>
              <bitOffset>24</bitOffset>
              <bitWidth>1</bitWidth>
              <access>read-write</access>
              <enumeratedValues>
                <enumeratedValue>
                  <name>0</name>
                  <description>Configured interrupt is not detected.</description>
                  <value>#0</value>
                </enumeratedValue>
                <enumeratedValue>
                  <name>1</name>
                  <description>Configured interrupt is detected. If the pin is configured to generate a DMA request, then the corresponding flag will be cleared automatically at the completion of the requested DMA transfer. Otherwise, the flag remains set until a logic 1 is written to the flag. If the pin is configured for a level sensitive interrupt and the pin remains asserted, then the flag is set again immediately after it is cleared.</description>
                  <value>#1</value>
                </enumeratedValue>
              </enumeratedValues>
            </field>
          </fields>
        </register>
        <register>
          <name>PCR12</name>
          <description>Pin Control Register n</description>
          <addressOffset>0x30</addressOffset>
          <size>32</size>
          <access>read-write</access>
          <resetValue>0</resetValue>
          <resetMask>0xFFFFFFFF</resetMask>
          <fields>
            <field>
              <name>PS</name>
              <description>Pull Select</description>
              <bitOffset>0</bitOffset>
              <bitWidth>1</bitWidth>
              <access>read-only</access>
              <enumeratedValues>
                <enumeratedValue>
                  <name>0</name>
                  <description>Internal pulldown resistor is enabled on the corresponding pin, if the corresponding PE field is set.</description>
                  <value>#0</value>
                </enumeratedValue>
                <enumeratedValue>
                  <name>1</name>
                  <description>Internal pullup resistor is enabled on the corresponding pin, if the corresponding PE field is set.</description>
                  <value>#1</value>
                </enumeratedValue>
              </enumeratedValues>
            </field>
            <field>
              <name>PE</name>
              <description>Pull Enable</description>
              <bitOffset>1</bitOffset>
              <bitWidth>1</bitWidth>
              <access>read-only</access>
              <enumeratedValues>
                <enumeratedValue>
                  <name>0</name>
                  <description>Internal pullup or pulldown resistor is not enabled on the corresponding pin.</description>
                  <value>#0</value>
                </enumeratedValue>
                <enumeratedValue>
                  <name>1</name>
                  <description>Internal pullup or pulldown resistor is enabled on the corresponding pin, if the pin is configured as a digital input.</description>
                  <value>#1</value>
                </enumeratedValue>
              </enumeratedValues>
            </field>
            <field>
              <name>SRE</name>
              <description>Slew Rate Enable</description>
              <bitOffset>2</bitOffset>
              <bitWidth>1</bitWidth>
              <access>read-only</access>
              <enumeratedValues>
                <enumeratedValue>
                  <name>0</name>
                  <description>Fast slew rate is configured on the corresponding pin, if the pin is configured as a digital output.</description>
                  <value>#0</value>
                </enumeratedValue>
                <enumeratedValue>
                  <name>1</name>
                  <description>Slow slew rate is configured on the corresponding pin, if the pin is configured as a digital output.</description>
                  <value>#1</value>
                </enumeratedValue>
              </enumeratedValues>
            </field>
            <field>
              <name>PFE</name>
              <description>Passive Filter Enable</description>
              <bitOffset>4</bitOffset>
              <bitWidth>1</bitWidth>
              <access>read-only</access>
              <enumeratedValues>
                <enumeratedValue>
                  <name>0</name>
                  <description>Passive input filter is disabled on the corresponding pin.</description>
                  <value>#0</value>
                </enumeratedValue>
                <enumeratedValue>
                  <name>1</name>
                  <description>Passive input filter is enabled on the corresponding pin, if the pin is configured as a digital input. Refer to the device data sheet for filter characteristics.</description>
                  <value>#1</value>
                </enumeratedValue>
              </enumeratedValues>
            </field>
            <field>
              <name>DSE</name>
              <description>Drive Strength Enable</description>
              <bitOffset>6</bitOffset>
              <bitWidth>1</bitWidth>
              <access>read-only</access>
              <enumeratedValues>
                <enumeratedValue>
                  <name>0</name>
                  <description>Low drive strength is configured on the corresponding pin, if pin is configured as a digital output.</description>
                  <value>#0</value>
                </enumeratedValue>
                <enumeratedValue>
                  <name>1</name>
                  <description>High drive strength is configured on the corresponding pin, if pin is configured as a digital output.</description>
                  <value>#1</value>
                </enumeratedValue>
              </enumeratedValues>
            </field>
            <field>
              <name>MUX</name>
              <description>Pin Mux Control</description>
              <bitOffset>8</bitOffset>
              <bitWidth>3</bitWidth>
              <access>read-write</access>
              <enumeratedValues>
                <enumeratedValue>
                  <name>000</name>
                  <description>Pin disabled (analog).</description>
                  <value>#000</value>
                </enumeratedValue>
                <enumeratedValue>
                  <name>001</name>
                  <description>Alternative 1 (GPIO).</description>
                  <value>#001</value>
                </enumeratedValue>
                <enumeratedValue>
                  <name>010</name>
                  <description>Alternative 2 (chip-specific).</description>
                  <value>#010</value>
                </enumeratedValue>
                <enumeratedValue>
                  <name>011</name>
                  <description>Alternative 3 (chip-specific).</description>
                  <value>#011</value>
                </enumeratedValue>
                <enumeratedValue>
                  <name>100</name>
                  <description>Alternative 4 (chip-specific).</description>
                  <value>#100</value>
                </enumeratedValue>
                <enumeratedValue>
                  <name>101</name>
                  <description>Alternative 5 (chip-specific).</description>
                  <value>#101</value>
                </enumeratedValue>
                <enumeratedValue>
                  <name>110</name>
                  <description>Alternative 6 (chip-specific).</description>
                  <value>#110</value>
                </enumeratedValue>
                <enumeratedValue>
                  <name>111</name>
                  <description>Alternative 7 (chip-specific).</description>
                  <value>#111</value>
                </enumeratedValue>
              </enumeratedValues>
            </field>
            <field>
              <name>IRQC</name>
              <description>Interrupt Configuration</description>
              <bitOffset>16</bitOffset>
              <bitWidth>4</bitWidth>
              <access>read-write</access>
              <enumeratedValues>
                <enumeratedValue>
                  <name>0000</name>
                  <description>Interrupt/DMA request disabled.</description>
                  <value>#0000</value>
                </enumeratedValue>
                <enumeratedValue>
                  <name>0001</name>
                  <description>DMA request on rising edge.</description>
                  <value>#0001</value>
                </enumeratedValue>
                <enumeratedValue>
                  <name>0010</name>
                  <description>DMA request on falling edge.</description>
                  <value>#0010</value>
                </enumeratedValue>
                <enumeratedValue>
                  <name>0011</name>
                  <description>DMA request on either edge.</description>
                  <value>#0011</value>
                </enumeratedValue>
                <enumeratedValue>
                  <name>1000</name>
                  <description>Interrupt when logic 0.</description>
                  <value>#1000</value>
                </enumeratedValue>
                <enumeratedValue>
                  <name>1001</name>
                  <description>Interrupt on rising-edge.</description>
                  <value>#1001</value>
                </enumeratedValue>
                <enumeratedValue>
                  <name>1010</name>
                  <description>Interrupt on falling-edge.</description>
                  <value>#1010</value>
                </enumeratedValue>
                <enumeratedValue>
                  <name>1011</name>
                  <description>Interrupt on either edge.</description>
                  <value>#1011</value>
                </enumeratedValue>
                <enumeratedValue>
                  <name>1100</name>
                  <description>Interrupt when logic 1.</description>
                  <value>#1100</value>
                </enumeratedValue>
              </enumeratedValues>
            </field>
            <field>
              <name>ISF</name>
              <description>Interrupt Status Flag</description>
              <bitOffset>24</bitOffset>
              <bitWidth>1</bitWidth>
              <access>read-write</access>
              <enumeratedValues>
                <enumeratedValue>
                  <name>0</name>
                  <description>Configured interrupt is not detected.</description>
                  <value>#0</value>
                </enumeratedValue>
                <enumeratedValue>
                  <name>1</name>
                  <description>Configured interrupt is detected. If the pin is configured to generate a DMA request, then the corresponding flag will be cleared automatically at the completion of the requested DMA transfer. Otherwise, the flag remains set until a logic 1 is written to the flag. If the pin is configured for a level sensitive interrupt and the pin remains asserted, then the flag is set again immediately after it is cleared.</description>
                  <value>#1</value>
                </enumeratedValue>
              </enumeratedValues>
            </field>
          </fields>
        </register>
        <register>
          <name>PCR13</name>
          <description>Pin Control Register n</description>
          <addressOffset>0x34</addressOffset>
          <size>32</size>
          <access>read-write</access>
          <resetValue>0</resetValue>
          <resetMask>0xFFFFFFFF</resetMask>
          <fields>
            <field>
              <name>PS</name>
              <description>Pull Select</description>
              <bitOffset>0</bitOffset>
              <bitWidth>1</bitWidth>
              <access>read-only</access>
              <enumeratedValues>
                <enumeratedValue>
                  <name>0</name>
                  <description>Internal pulldown resistor is enabled on the corresponding pin, if the corresponding PE field is set.</description>
                  <value>#0</value>
                </enumeratedValue>
                <enumeratedValue>
                  <name>1</name>
                  <description>Internal pullup resistor is enabled on the corresponding pin, if the corresponding PE field is set.</description>
                  <value>#1</value>
                </enumeratedValue>
              </enumeratedValues>
            </field>
            <field>
              <name>PE</name>
              <description>Pull Enable</description>
              <bitOffset>1</bitOffset>
              <bitWidth>1</bitWidth>
              <access>read-only</access>
              <enumeratedValues>
                <enumeratedValue>
                  <name>0</name>
                  <description>Internal pullup or pulldown resistor is not enabled on the corresponding pin.</description>
                  <value>#0</value>
                </enumeratedValue>
                <enumeratedValue>
                  <name>1</name>
                  <description>Internal pullup or pulldown resistor is enabled on the corresponding pin, if the pin is configured as a digital input.</description>
                  <value>#1</value>
                </enumeratedValue>
              </enumeratedValues>
            </field>
            <field>
              <name>SRE</name>
              <description>Slew Rate Enable</description>
              <bitOffset>2</bitOffset>
              <bitWidth>1</bitWidth>
              <access>read-only</access>
              <enumeratedValues>
                <enumeratedValue>
                  <name>0</name>
                  <description>Fast slew rate is configured on the corresponding pin, if the pin is configured as a digital output.</description>
                  <value>#0</value>
                </enumeratedValue>
                <enumeratedValue>
                  <name>1</name>
                  <description>Slow slew rate is configured on the corresponding pin, if the pin is configured as a digital output.</description>
                  <value>#1</value>
                </enumeratedValue>
              </enumeratedValues>
            </field>
            <field>
              <name>PFE</name>
              <description>Passive Filter Enable</description>
              <bitOffset>4</bitOffset>
              <bitWidth>1</bitWidth>
              <access>read-only</access>
              <enumeratedValues>
                <enumeratedValue>
                  <name>0</name>
                  <description>Passive input filter is disabled on the corresponding pin.</description>
                  <value>#0</value>
                </enumeratedValue>
                <enumeratedValue>
                  <name>1</name>
                  <description>Passive input filter is enabled on the corresponding pin, if the pin is configured as a digital input. Refer to the device data sheet for filter characteristics.</description>
                  <value>#1</value>
                </enumeratedValue>
              </enumeratedValues>
            </field>
            <field>
              <name>DSE</name>
              <description>Drive Strength Enable</description>
              <bitOffset>6</bitOffset>
              <bitWidth>1</bitWidth>
              <access>read-only</access>
              <enumeratedValues>
                <enumeratedValue>
                  <name>0</name>
                  <description>Low drive strength is configured on the corresponding pin, if pin is configured as a digital output.</description>
                  <value>#0</value>
                </enumeratedValue>
                <enumeratedValue>
                  <name>1</name>
                  <description>High drive strength is configured on the corresponding pin, if pin is configured as a digital output.</description>
                  <value>#1</value>
                </enumeratedValue>
              </enumeratedValues>
            </field>
            <field>
              <name>MUX</name>
              <description>Pin Mux Control</description>
              <bitOffset>8</bitOffset>
              <bitWidth>3</bitWidth>
              <access>read-write</access>
              <enumeratedValues>
                <enumeratedValue>
                  <name>000</name>
                  <description>Pin disabled (analog).</description>
                  <value>#000</value>
                </enumeratedValue>
                <enumeratedValue>
                  <name>001</name>
                  <description>Alternative 1 (GPIO).</description>
                  <value>#001</value>
                </enumeratedValue>
                <enumeratedValue>
                  <name>010</name>
                  <description>Alternative 2 (chip-specific).</description>
                  <value>#010</value>
                </enumeratedValue>
                <enumeratedValue>
                  <name>011</name>
                  <description>Alternative 3 (chip-specific).</description>
                  <value>#011</value>
                </enumeratedValue>
                <enumeratedValue>
                  <name>100</name>
                  <description>Alternative 4 (chip-specific).</description>
                  <value>#100</value>
                </enumeratedValue>
                <enumeratedValue>
                  <name>101</name>
                  <description>Alternative 5 (chip-specific).</description>
                  <value>#101</value>
                </enumeratedValue>
                <enumeratedValue>
                  <name>110</name>
                  <description>Alternative 6 (chip-specific).</description>
                  <value>#110</value>
                </enumeratedValue>
                <enumeratedValue>
                  <name>111</name>
                  <description>Alternative 7 (chip-specific).</description>
                  <value>#111</value>
                </enumeratedValue>
              </enumeratedValues>
            </field>
            <field>
              <name>IRQC</name>
              <description>Interrupt Configuration</description>
              <bitOffset>16</bitOffset>
              <bitWidth>4</bitWidth>
              <access>read-write</access>
              <enumeratedValues>
                <enumeratedValue>
                  <name>0000</name>
                  <description>Interrupt/DMA request disabled.</description>
                  <value>#0000</value>
                </enumeratedValue>
                <enumeratedValue>
                  <name>0001</name>
                  <description>DMA request on rising edge.</description>
                  <value>#0001</value>
                </enumeratedValue>
                <enumeratedValue>
                  <name>0010</name>
                  <description>DMA request on falling edge.</description>
                  <value>#0010</value>
                </enumeratedValue>
                <enumeratedValue>
                  <name>0011</name>
                  <description>DMA request on either edge.</description>
                  <value>#0011</value>
                </enumeratedValue>
                <enumeratedValue>
                  <name>1000</name>
                  <description>Interrupt when logic 0.</description>
                  <value>#1000</value>
                </enumeratedValue>
                <enumeratedValue>
                  <name>1001</name>
                  <description>Interrupt on rising-edge.</description>
                  <value>#1001</value>
                </enumeratedValue>
                <enumeratedValue>
                  <name>1010</name>
                  <description>Interrupt on falling-edge.</description>
                  <value>#1010</value>
                </enumeratedValue>
                <enumeratedValue>
                  <name>1011</name>
                  <description>Interrupt on either edge.</description>
                  <value>#1011</value>
                </enumeratedValue>
                <enumeratedValue>
                  <name>1100</name>
                  <description>Interrupt when logic 1.</description>
                  <value>#1100</value>
                </enumeratedValue>
              </enumeratedValues>
            </field>
            <field>
              <name>ISF</name>
              <description>Interrupt Status Flag</description>
              <bitOffset>24</bitOffset>
              <bitWidth>1</bitWidth>
              <access>read-write</access>
              <enumeratedValues>
                <enumeratedValue>
                  <name>0</name>
                  <description>Configured interrupt is not detected.</description>
                  <value>#0</value>
                </enumeratedValue>
                <enumeratedValue>
                  <name>1</name>
                  <description>Configured interrupt is detected. If the pin is configured to generate a DMA request, then the corresponding flag will be cleared automatically at the completion of the requested DMA transfer. Otherwise, the flag remains set until a logic 1 is written to the flag. If the pin is configured for a level sensitive interrupt and the pin remains asserted, then the flag is set again immediately after it is cleared.</description>
                  <value>#1</value>
                </enumeratedValue>
              </enumeratedValues>
            </field>
          </fields>
        </register>
        <register>
          <name>PCR14</name>
          <description>Pin Control Register n</description>
          <addressOffset>0x38</addressOffset>
          <size>32</size>
          <access>read-write</access>
          <resetValue>0</resetValue>
          <resetMask>0xFFFFFFFF</resetMask>
          <fields>
            <field>
              <name>PS</name>
              <description>Pull Select</description>
              <bitOffset>0</bitOffset>
              <bitWidth>1</bitWidth>
              <access>read-only</access>
              <enumeratedValues>
                <enumeratedValue>
                  <name>0</name>
                  <description>Internal pulldown resistor is enabled on the corresponding pin, if the corresponding PE field is set.</description>
                  <value>#0</value>
                </enumeratedValue>
                <enumeratedValue>
                  <name>1</name>
                  <description>Internal pullup resistor is enabled on the corresponding pin, if the corresponding PE field is set.</description>
                  <value>#1</value>
                </enumeratedValue>
              </enumeratedValues>
            </field>
            <field>
              <name>PE</name>
              <description>Pull Enable</description>
              <bitOffset>1</bitOffset>
              <bitWidth>1</bitWidth>
              <access>read-only</access>
              <enumeratedValues>
                <enumeratedValue>
                  <name>0</name>
                  <description>Internal pullup or pulldown resistor is not enabled on the corresponding pin.</description>
                  <value>#0</value>
                </enumeratedValue>
                <enumeratedValue>
                  <name>1</name>
                  <description>Internal pullup or pulldown resistor is enabled on the corresponding pin, if the pin is configured as a digital input.</description>
                  <value>#1</value>
                </enumeratedValue>
              </enumeratedValues>
            </field>
            <field>
              <name>SRE</name>
              <description>Slew Rate Enable</description>
              <bitOffset>2</bitOffset>
              <bitWidth>1</bitWidth>
              <access>read-only</access>
              <enumeratedValues>
                <enumeratedValue>
                  <name>0</name>
                  <description>Fast slew rate is configured on the corresponding pin, if the pin is configured as a digital output.</description>
                  <value>#0</value>
                </enumeratedValue>
                <enumeratedValue>
                  <name>1</name>
                  <description>Slow slew rate is configured on the corresponding pin, if the pin is configured as a digital output.</description>
                  <value>#1</value>
                </enumeratedValue>
              </enumeratedValues>
            </field>
            <field>
              <name>PFE</name>
              <description>Passive Filter Enable</description>
              <bitOffset>4</bitOffset>
              <bitWidth>1</bitWidth>
              <access>read-only</access>
              <enumeratedValues>
                <enumeratedValue>
                  <name>0</name>
                  <description>Passive input filter is disabled on the corresponding pin.</description>
                  <value>#0</value>
                </enumeratedValue>
                <enumeratedValue>
                  <name>1</name>
                  <description>Passive input filter is enabled on the corresponding pin, if the pin is configured as a digital input. Refer to the device data sheet for filter characteristics.</description>
                  <value>#1</value>
                </enumeratedValue>
              </enumeratedValues>
            </field>
            <field>
              <name>DSE</name>
              <description>Drive Strength Enable</description>
              <bitOffset>6</bitOffset>
              <bitWidth>1</bitWidth>
              <access>read-only</access>
              <enumeratedValues>
                <enumeratedValue>
                  <name>0</name>
                  <description>Low drive strength is configured on the corresponding pin, if pin is configured as a digital output.</description>
                  <value>#0</value>
                </enumeratedValue>
                <enumeratedValue>
                  <name>1</name>
                  <description>High drive strength is configured on the corresponding pin, if pin is configured as a digital output.</description>
                  <value>#1</value>
                </enumeratedValue>
              </enumeratedValues>
            </field>
            <field>
              <name>MUX</name>
              <description>Pin Mux Control</description>
              <bitOffset>8</bitOffset>
              <bitWidth>3</bitWidth>
              <access>read-write</access>
              <enumeratedValues>
                <enumeratedValue>
                  <name>000</name>
                  <description>Pin disabled (analog).</description>
                  <value>#000</value>
                </enumeratedValue>
                <enumeratedValue>
                  <name>001</name>
                  <description>Alternative 1 (GPIO).</description>
                  <value>#001</value>
                </enumeratedValue>
                <enumeratedValue>
                  <name>010</name>
                  <description>Alternative 2 (chip-specific).</description>
                  <value>#010</value>
                </enumeratedValue>
                <enumeratedValue>
                  <name>011</name>
                  <description>Alternative 3 (chip-specific).</description>
                  <value>#011</value>
                </enumeratedValue>
                <enumeratedValue>
                  <name>100</name>
                  <description>Alternative 4 (chip-specific).</description>
                  <value>#100</value>
                </enumeratedValue>
                <enumeratedValue>
                  <name>101</name>
                  <description>Alternative 5 (chip-specific).</description>
                  <value>#101</value>
                </enumeratedValue>
                <enumeratedValue>
                  <name>110</name>
                  <description>Alternative 6 (chip-specific).</description>
                  <value>#110</value>
                </enumeratedValue>
                <enumeratedValue>
                  <name>111</name>
                  <description>Alternative 7 (chip-specific).</description>
                  <value>#111</value>
                </enumeratedValue>
              </enumeratedValues>
            </field>
            <field>
              <name>IRQC</name>
              <description>Interrupt Configuration</description>
              <bitOffset>16</bitOffset>
              <bitWidth>4</bitWidth>
              <access>read-write</access>
              <enumeratedValues>
                <enumeratedValue>
                  <name>0000</name>
                  <description>Interrupt/DMA request disabled.</description>
                  <value>#0000</value>
                </enumeratedValue>
                <enumeratedValue>
                  <name>0001</name>
                  <description>DMA request on rising edge.</description>
                  <value>#0001</value>
                </enumeratedValue>
                <enumeratedValue>
                  <name>0010</name>
                  <description>DMA request on falling edge.</description>
                  <value>#0010</value>
                </enumeratedValue>
                <enumeratedValue>
                  <name>0011</name>
                  <description>DMA request on either edge.</description>
                  <value>#0011</value>
                </enumeratedValue>
                <enumeratedValue>
                  <name>1000</name>
                  <description>Interrupt when logic 0.</description>
                  <value>#1000</value>
                </enumeratedValue>
                <enumeratedValue>
                  <name>1001</name>
                  <description>Interrupt on rising-edge.</description>
                  <value>#1001</value>
                </enumeratedValue>
                <enumeratedValue>
                  <name>1010</name>
                  <description>Interrupt on falling-edge.</description>
                  <value>#1010</value>
                </enumeratedValue>
                <enumeratedValue>
                  <name>1011</name>
                  <description>Interrupt on either edge.</description>
                  <value>#1011</value>
                </enumeratedValue>
                <enumeratedValue>
                  <name>1100</name>
                  <description>Interrupt when logic 1.</description>
                  <value>#1100</value>
                </enumeratedValue>
              </enumeratedValues>
            </field>
            <field>
              <name>ISF</name>
              <description>Interrupt Status Flag</description>
              <bitOffset>24</bitOffset>
              <bitWidth>1</bitWidth>
              <access>read-write</access>
              <enumeratedValues>
                <enumeratedValue>
                  <name>0</name>
                  <description>Configured interrupt is not detected.</description>
                  <value>#0</value>
                </enumeratedValue>
                <enumeratedValue>
                  <name>1</name>
                  <description>Configured interrupt is detected. If the pin is configured to generate a DMA request, then the corresponding flag will be cleared automatically at the completion of the requested DMA transfer. Otherwise, the flag remains set until a logic 1 is written to the flag. If the pin is configured for a level sensitive interrupt and the pin remains asserted, then the flag is set again immediately after it is cleared.</description>
                  <value>#1</value>
                </enumeratedValue>
              </enumeratedValues>
            </field>
          </fields>
        </register>
        <register>
          <name>PCR15</name>
          <description>Pin Control Register n</description>
          <addressOffset>0x3C</addressOffset>
          <size>32</size>
          <access>read-write</access>
          <resetValue>0</resetValue>
          <resetMask>0xFFFFFFFF</resetMask>
          <fields>
            <field>
              <name>PS</name>
              <description>Pull Select</description>
              <bitOffset>0</bitOffset>
              <bitWidth>1</bitWidth>
              <access>read-only</access>
              <enumeratedValues>
                <enumeratedValue>
                  <name>0</name>
                  <description>Internal pulldown resistor is enabled on the corresponding pin, if the corresponding PE field is set.</description>
                  <value>#0</value>
                </enumeratedValue>
                <enumeratedValue>
                  <name>1</name>
                  <description>Internal pullup resistor is enabled on the corresponding pin, if the corresponding PE field is set.</description>
                  <value>#1</value>
                </enumeratedValue>
              </enumeratedValues>
            </field>
            <field>
              <name>PE</name>
              <description>Pull Enable</description>
              <bitOffset>1</bitOffset>
              <bitWidth>1</bitWidth>
              <access>read-only</access>
              <enumeratedValues>
                <enumeratedValue>
                  <name>0</name>
                  <description>Internal pullup or pulldown resistor is not enabled on the corresponding pin.</description>
                  <value>#0</value>
                </enumeratedValue>
                <enumeratedValue>
                  <name>1</name>
                  <description>Internal pullup or pulldown resistor is enabled on the corresponding pin, if the pin is configured as a digital input.</description>
                  <value>#1</value>
                </enumeratedValue>
              </enumeratedValues>
            </field>
            <field>
              <name>SRE</name>
              <description>Slew Rate Enable</description>
              <bitOffset>2</bitOffset>
              <bitWidth>1</bitWidth>
              <access>read-only</access>
              <enumeratedValues>
                <enumeratedValue>
                  <name>0</name>
                  <description>Fast slew rate is configured on the corresponding pin, if the pin is configured as a digital output.</description>
                  <value>#0</value>
                </enumeratedValue>
                <enumeratedValue>
                  <name>1</name>
                  <description>Slow slew rate is configured on the corresponding pin, if the pin is configured as a digital output.</description>
                  <value>#1</value>
                </enumeratedValue>
              </enumeratedValues>
            </field>
            <field>
              <name>PFE</name>
              <description>Passive Filter Enable</description>
              <bitOffset>4</bitOffset>
              <bitWidth>1</bitWidth>
              <access>read-only</access>
              <enumeratedValues>
                <enumeratedValue>
                  <name>0</name>
                  <description>Passive input filter is disabled on the corresponding pin.</description>
                  <value>#0</value>
                </enumeratedValue>
                <enumeratedValue>
                  <name>1</name>
                  <description>Passive input filter is enabled on the corresponding pin, if the pin is configured as a digital input. Refer to the device data sheet for filter characteristics.</description>
                  <value>#1</value>
                </enumeratedValue>
              </enumeratedValues>
            </field>
            <field>
              <name>DSE</name>
              <description>Drive Strength Enable</description>
              <bitOffset>6</bitOffset>
              <bitWidth>1</bitWidth>
              <access>read-only</access>
              <enumeratedValues>
                <enumeratedValue>
                  <name>0</name>
                  <description>Low drive strength is configured on the corresponding pin, if pin is configured as a digital output.</description>
                  <value>#0</value>
                </enumeratedValue>
                <enumeratedValue>
                  <name>1</name>
                  <description>High drive strength is configured on the corresponding pin, if pin is configured as a digital output.</description>
                  <value>#1</value>
                </enumeratedValue>
              </enumeratedValues>
            </field>
            <field>
              <name>MUX</name>
              <description>Pin Mux Control</description>
              <bitOffset>8</bitOffset>
              <bitWidth>3</bitWidth>
              <access>read-write</access>
              <enumeratedValues>
                <enumeratedValue>
                  <name>000</name>
                  <description>Pin disabled (analog).</description>
                  <value>#000</value>
                </enumeratedValue>
                <enumeratedValue>
                  <name>001</name>
                  <description>Alternative 1 (GPIO).</description>
                  <value>#001</value>
                </enumeratedValue>
                <enumeratedValue>
                  <name>010</name>
                  <description>Alternative 2 (chip-specific).</description>
                  <value>#010</value>
                </enumeratedValue>
                <enumeratedValue>
                  <name>011</name>
                  <description>Alternative 3 (chip-specific).</description>
                  <value>#011</value>
                </enumeratedValue>
                <enumeratedValue>
                  <name>100</name>
                  <description>Alternative 4 (chip-specific).</description>
                  <value>#100</value>
                </enumeratedValue>
                <enumeratedValue>
                  <name>101</name>
                  <description>Alternative 5 (chip-specific).</description>
                  <value>#101</value>
                </enumeratedValue>
                <enumeratedValue>
                  <name>110</name>
                  <description>Alternative 6 (chip-specific).</description>
                  <value>#110</value>
                </enumeratedValue>
                <enumeratedValue>
                  <name>111</name>
                  <description>Alternative 7 (chip-specific).</description>
                  <value>#111</value>
                </enumeratedValue>
              </enumeratedValues>
            </field>
            <field>
              <name>IRQC</name>
              <description>Interrupt Configuration</description>
              <bitOffset>16</bitOffset>
              <bitWidth>4</bitWidth>
              <access>read-write</access>
              <enumeratedValues>
                <enumeratedValue>
                  <name>0000</name>
                  <description>Interrupt/DMA request disabled.</description>
                  <value>#0000</value>
                </enumeratedValue>
                <enumeratedValue>
                  <name>0001</name>
                  <description>DMA request on rising edge.</description>
                  <value>#0001</value>
                </enumeratedValue>
                <enumeratedValue>
                  <name>0010</name>
                  <description>DMA request on falling edge.</description>
                  <value>#0010</value>
                </enumeratedValue>
                <enumeratedValue>
                  <name>0011</name>
                  <description>DMA request on either edge.</description>
                  <value>#0011</value>
                </enumeratedValue>
                <enumeratedValue>
                  <name>1000</name>
                  <description>Interrupt when logic 0.</description>
                  <value>#1000</value>
                </enumeratedValue>
                <enumeratedValue>
                  <name>1001</name>
                  <description>Interrupt on rising-edge.</description>
                  <value>#1001</value>
                </enumeratedValue>
                <enumeratedValue>
                  <name>1010</name>
                  <description>Interrupt on falling-edge.</description>
                  <value>#1010</value>
                </enumeratedValue>
                <enumeratedValue>
                  <name>1011</name>
                  <description>Interrupt on either edge.</description>
                  <value>#1011</value>
                </enumeratedValue>
                <enumeratedValue>
                  <name>1100</name>
                  <description>Interrupt when logic 1.</description>
                  <value>#1100</value>
                </enumeratedValue>
              </enumeratedValues>
            </field>
            <field>
              <name>ISF</name>
              <description>Interrupt Status Flag</description>
              <bitOffset>24</bitOffset>
              <bitWidth>1</bitWidth>
              <access>read-write</access>
              <enumeratedValues>
                <enumeratedValue>
                  <name>0</name>
                  <description>Configured interrupt is not detected.</description>
                  <value>#0</value>
                </enumeratedValue>
                <enumeratedValue>
                  <name>1</name>
                  <description>Configured interrupt is detected. If the pin is configured to generate a DMA request, then the corresponding flag will be cleared automatically at the completion of the requested DMA transfer. Otherwise, the flag remains set until a logic 1 is written to the flag. If the pin is configured for a level sensitive interrupt and the pin remains asserted, then the flag is set again immediately after it is cleared.</description>
                  <value>#1</value>
                </enumeratedValue>
              </enumeratedValues>
            </field>
          </fields>
        </register>
        <register>
          <name>PCR16</name>
          <description>Pin Control Register n</description>
          <addressOffset>0x40</addressOffset>
          <size>32</size>
          <access>read-write</access>
          <resetValue>0x1</resetValue>
          <resetMask>0xFFFFFFFF</resetMask>
          <fields>
            <field>
              <name>PS</name>
              <description>Pull Select</description>
              <bitOffset>0</bitOffset>
              <bitWidth>1</bitWidth>
              <access>read-only</access>
              <enumeratedValues>
                <enumeratedValue>
                  <name>0</name>
                  <description>Internal pulldown resistor is enabled on the corresponding pin, if the corresponding PE field is set.</description>
                  <value>#0</value>
                </enumeratedValue>
                <enumeratedValue>
                  <name>1</name>
                  <description>Internal pullup resistor is enabled on the corresponding pin, if the corresponding PE field is set.</description>
                  <value>#1</value>
                </enumeratedValue>
              </enumeratedValues>
            </field>
            <field>
              <name>PE</name>
              <description>Pull Enable</description>
              <bitOffset>1</bitOffset>
              <bitWidth>1</bitWidth>
              <access>read-only</access>
              <enumeratedValues>
                <enumeratedValue>
                  <name>0</name>
                  <description>Internal pullup or pulldown resistor is not enabled on the corresponding pin.</description>
                  <value>#0</value>
                </enumeratedValue>
                <enumeratedValue>
                  <name>1</name>
                  <description>Internal pullup or pulldown resistor is enabled on the corresponding pin, if the pin is configured as a digital input.</description>
                  <value>#1</value>
                </enumeratedValue>
              </enumeratedValues>
            </field>
            <field>
              <name>SRE</name>
              <description>Slew Rate Enable</description>
              <bitOffset>2</bitOffset>
              <bitWidth>1</bitWidth>
              <access>read-only</access>
              <enumeratedValues>
                <enumeratedValue>
                  <name>0</name>
                  <description>Fast slew rate is configured on the corresponding pin, if the pin is configured as a digital output.</description>
                  <value>#0</value>
                </enumeratedValue>
                <enumeratedValue>
                  <name>1</name>
                  <description>Slow slew rate is configured on the corresponding pin, if the pin is configured as a digital output.</description>
                  <value>#1</value>
                </enumeratedValue>
              </enumeratedValues>
            </field>
            <field>
              <name>PFE</name>
              <description>Passive Filter Enable</description>
              <bitOffset>4</bitOffset>
              <bitWidth>1</bitWidth>
              <access>read-only</access>
              <enumeratedValues>
                <enumeratedValue>
                  <name>0</name>
                  <description>Passive input filter is disabled on the corresponding pin.</description>
                  <value>#0</value>
                </enumeratedValue>
                <enumeratedValue>
                  <name>1</name>
                  <description>Passive input filter is enabled on the corresponding pin, if the pin is configured as a digital input. Refer to the device data sheet for filter characteristics.</description>
                  <value>#1</value>
                </enumeratedValue>
              </enumeratedValues>
            </field>
            <field>
              <name>DSE</name>
              <description>Drive Strength Enable</description>
              <bitOffset>6</bitOffset>
              <bitWidth>1</bitWidth>
              <access>read-only</access>
              <enumeratedValues>
                <enumeratedValue>
                  <name>0</name>
                  <description>Low drive strength is configured on the corresponding pin, if pin is configured as a digital output.</description>
                  <value>#0</value>
                </enumeratedValue>
                <enumeratedValue>
                  <name>1</name>
                  <description>High drive strength is configured on the corresponding pin, if pin is configured as a digital output.</description>
                  <value>#1</value>
                </enumeratedValue>
              </enumeratedValues>
            </field>
            <field>
              <name>MUX</name>
              <description>Pin Mux Control</description>
              <bitOffset>8</bitOffset>
              <bitWidth>3</bitWidth>
              <access>read-write</access>
              <enumeratedValues>
                <enumeratedValue>
                  <name>000</name>
                  <description>Pin disabled (analog).</description>
                  <value>#000</value>
                </enumeratedValue>
                <enumeratedValue>
                  <name>001</name>
                  <description>Alternative 1 (GPIO).</description>
                  <value>#001</value>
                </enumeratedValue>
                <enumeratedValue>
                  <name>010</name>
                  <description>Alternative 2 (chip-specific).</description>
                  <value>#010</value>
                </enumeratedValue>
                <enumeratedValue>
                  <name>011</name>
                  <description>Alternative 3 (chip-specific).</description>
                  <value>#011</value>
                </enumeratedValue>
                <enumeratedValue>
                  <name>100</name>
                  <description>Alternative 4 (chip-specific).</description>
                  <value>#100</value>
                </enumeratedValue>
                <enumeratedValue>
                  <name>101</name>
                  <description>Alternative 5 (chip-specific).</description>
                  <value>#101</value>
                </enumeratedValue>
                <enumeratedValue>
                  <name>110</name>
                  <description>Alternative 6 (chip-specific).</description>
                  <value>#110</value>
                </enumeratedValue>
                <enumeratedValue>
                  <name>111</name>
                  <description>Alternative 7 (chip-specific).</description>
                  <value>#111</value>
                </enumeratedValue>
              </enumeratedValues>
            </field>
            <field>
              <name>IRQC</name>
              <description>Interrupt Configuration</description>
              <bitOffset>16</bitOffset>
              <bitWidth>4</bitWidth>
              <access>read-write</access>
              <enumeratedValues>
                <enumeratedValue>
                  <name>0000</name>
                  <description>Interrupt/DMA request disabled.</description>
                  <value>#0000</value>
                </enumeratedValue>
                <enumeratedValue>
                  <name>0001</name>
                  <description>DMA request on rising edge.</description>
                  <value>#0001</value>
                </enumeratedValue>
                <enumeratedValue>
                  <name>0010</name>
                  <description>DMA request on falling edge.</description>
                  <value>#0010</value>
                </enumeratedValue>
                <enumeratedValue>
                  <name>0011</name>
                  <description>DMA request on either edge.</description>
                  <value>#0011</value>
                </enumeratedValue>
                <enumeratedValue>
                  <name>1000</name>
                  <description>Interrupt when logic 0.</description>
                  <value>#1000</value>
                </enumeratedValue>
                <enumeratedValue>
                  <name>1001</name>
                  <description>Interrupt on rising-edge.</description>
                  <value>#1001</value>
                </enumeratedValue>
                <enumeratedValue>
                  <name>1010</name>
                  <description>Interrupt on falling-edge.</description>
                  <value>#1010</value>
                </enumeratedValue>
                <enumeratedValue>
                  <name>1011</name>
                  <description>Interrupt on either edge.</description>
                  <value>#1011</value>
                </enumeratedValue>
                <enumeratedValue>
                  <name>1100</name>
                  <description>Interrupt when logic 1.</description>
                  <value>#1100</value>
                </enumeratedValue>
              </enumeratedValues>
            </field>
            <field>
              <name>ISF</name>
              <description>Interrupt Status Flag</description>
              <bitOffset>24</bitOffset>
              <bitWidth>1</bitWidth>
              <access>read-write</access>
              <enumeratedValues>
                <enumeratedValue>
                  <name>0</name>
                  <description>Configured interrupt is not detected.</description>
                  <value>#0</value>
                </enumeratedValue>
                <enumeratedValue>
                  <name>1</name>
                  <description>Configured interrupt is detected. If the pin is configured to generate a DMA request, then the corresponding flag will be cleared automatically at the completion of the requested DMA transfer. Otherwise, the flag remains set until a logic 1 is written to the flag. If the pin is configured for a level sensitive interrupt and the pin remains asserted, then the flag is set again immediately after it is cleared.</description>
                  <value>#1</value>
                </enumeratedValue>
              </enumeratedValues>
            </field>
          </fields>
        </register>
        <register>
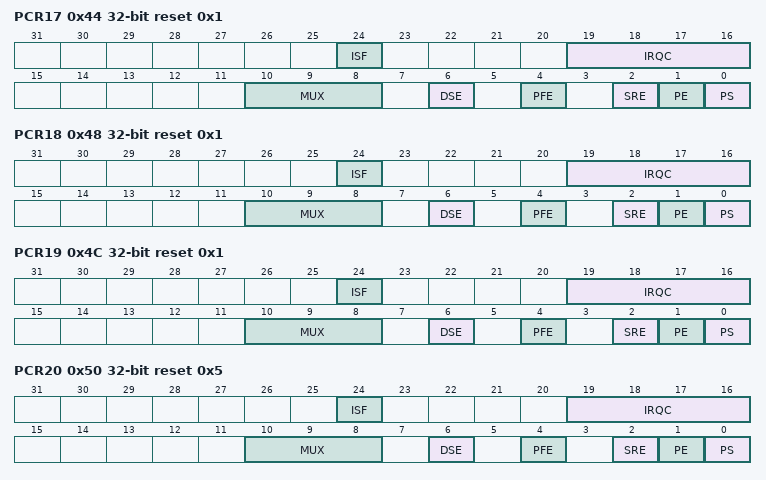
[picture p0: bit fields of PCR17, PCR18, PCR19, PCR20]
          <name>PCR17</name>
          <description>Pin Control Register n</description>
          <addressOffset>0x44</addressOffset>
          <size>32</size>
          <access>read-write</access>
          <resetValue>0x1</resetValue>
          <resetMask>0xFFFFFFFF</resetMask>
          <fields>
            <field>
              <name>PS</name>
              <description>Pull Select</description>
              <bitOffset>0</bitOffset>
              <bitWidth>1</bitWidth>
              <access>read-only</access>
              <enumeratedValues>
                <enumeratedValue>
                  <name>0</name>
                  <description>Internal pulldown resistor is enabled on the corresponding pin, if the corresponding PE field is set.</description>
                  <value>#0</value>
                </enumeratedValue>
                <enumeratedValue>
                  <name>1</name>
                  <description>Internal pullup resistor is enabled on the corresponding pin, if the corresponding PE field is set.</description>
                  <value>#1</value>
                </enumeratedValue>
              </enumeratedValues>
            </field>
            <field>
              <name>PE</name>
              <description>Pull Enable</description>
              <bitOffset>1</bitOffset>
              <bitWidth>1</bitWidth>
              <access>read-only</access>
              <enumeratedValues>
                <enumeratedValue>
                  <name>0</name>
                  <description>Internal pullup or pulldown resistor is not enabled on the corresponding pin.</description>
                  <value>#0</value>
                </enumeratedValue>
                <enumeratedValue>
                  <name>1</name>
                  <description>Internal pullup or pulldown resistor is enabled on the corresponding pin, if the pin is configured as a digital input.</description>
                  <value>#1</value>
                </enumeratedValue>
              </enumeratedValues>
            </field>
            <field>
              <name>SRE</name>
              <description>Slew Rate Enable</description>
              <bitOffset>2</bitOffset>
              <bitWidth>1</bitWidth>
              <access>read-only</access>
              <enumeratedValues>
                <enumeratedValue>
                  <name>0</name>
                  <description>Fast slew rate is configured on the corresponding pin, if the pin is configured as a digital output.</description>
                  <value>#0</value>
                </enumeratedValue>
                <enumeratedValue>
                  <name>1</name>
                  <description>Slow slew rate is configured on the corresponding pin, if the pin is configured as a digital output.</description>
                  <value>#1</value>
                </enumeratedValue>
              </enumeratedValues>
            </field>
            <field>
              <name>PFE</name>
              <description>Passive Filter Enable</description>
              <bitOffset>4</bitOffset>
              <bitWidth>1</bitWidth>
              <access>read-only</access>
              <enumeratedValues>
                <enumeratedValue>
                  <name>0</name>
                  <description>Passive input filter is disabled on the corresponding pin.</description>
                  <value>#0</value>
                </enumeratedValue>
                <enumeratedValue>
                  <name>1</name>
                  <description>Passive input filter is enabled on the corresponding pin, if the pin is configured as a digital input. Refer to the device data sheet for filter characteristics.</description>
                  <value>#1</value>
                </enumeratedValue>
              </enumeratedValues>
            </field>
            <field>
              <name>DSE</name>
              <description>Drive Strength Enable</description>
              <bitOffset>6</bitOffset>
              <bitWidth>1</bitWidth>
              <access>read-only</access>
              <enumeratedValues>
                <enumeratedValue>
                  <name>0</name>
                  <description>Low drive strength is configured on the corresponding pin, if pin is configured as a digital output.</description>
                  <value>#0</value>
                </enumeratedValue>
                <enumeratedValue>
                  <name>1</name>
                  <description>High drive strength is configured on the corresponding pin, if pin is configured as a digital output.</description>
                  <value>#1</value>
                </enumeratedValue>
              </enumeratedValues>
            </field>
            <field>
              <name>MUX</name>
              <description>Pin Mux Control</description>
              <bitOffset>8</bitOffset>
              <bitWidth>3</bitWidth>
              <access>read-write</access>
              <enumeratedValues>
                <enumeratedValue>
                  <name>000</name>
                  <description>Pin disabled (analog).</description>
                  <value>#000</value>
                </enumeratedValue>
                <enumeratedValue>
                  <name>001</name>
                  <description>Alternative 1 (GPIO).</description>
                  <value>#001</value>
                </enumeratedValue>
                <enumeratedValue>
                  <name>010</name>
                  <description>Alternative 2 (chip-specific).</description>
                  <value>#010</value>
                </enumeratedValue>
                <enumeratedValue>
                  <name>011</name>
                  <description>Alternative 3 (chip-specific).</description>
                  <value>#011</value>
                </enumeratedValue>
                <enumeratedValue>
                  <name>100</name>
                  <description>Alternative 4 (chip-specific).</description>
                  <value>#100</value>
                </enumeratedValue>
                <enumeratedValue>
                  <name>101</name>
                  <description>Alternative 5 (chip-specific).</description>
                  <value>#101</value>
                </enumeratedValue>
                <enumeratedValue>
                  <name>110</name>
                  <description>Alternative 6 (chip-specific).</description>
                  <value>#110</value>
                </enumeratedValue>
                <enumeratedValue>
                  <name>111</name>
                  <description>Alternative 7 (chip-specific).</description>
                  <value>#111</value>
                </enumeratedValue>
              </enumeratedValues>
            </field>
            <field>
              <name>IRQC</name>
              <description>Interrupt Configuration</description>
              <bitOffset>16</bitOffset>
              <bitWidth>4</bitWidth>
              <access>read-write</access>
              <enumeratedValues>
                <enumeratedValue>
                  <name>0000</name>
                  <description>Interrupt/DMA request disabled.</description>
                  <value>#0000</value>
                </enumeratedValue>
                <enumeratedValue>
                  <name>0001</name>
                  <description>DMA request on rising edge.</description>
                  <value>#0001</value>
                </enumeratedValue>
                <enumeratedValue>
                  <name>0010</name>
                  <description>DMA request on falling edge.</description>
                  <value>#0010</value>
                </enumeratedValue>
                <enumeratedValue>
                  <name>0011</name>
                  <description>DMA request on either edge.</description>
                  <value>#0011</value>
                </enumeratedValue>
                <enumeratedValue>
                  <name>1000</name>
                  <description>Interrupt when logic 0.</description>
                  <value>#1000</value>
                </enumeratedValue>
                <enumeratedValue>
                  <name>1001</name>
                  <description>Interrupt on rising-edge.</description>
                  <value>#1001</value>
                </enumeratedValue>
                <enumeratedValue>
                  <name>1010</name>
                  <description>Interrupt on falling-edge.</description>
                  <value>#1010</value>
                </enumeratedValue>
                <enumeratedValue>
                  <name>1011</name>
                  <description>Interrupt on either edge.</description>
                  <value>#1011</value>
                </enumeratedValue>
                <enumeratedValue>
                  <name>1100</name>
                  <description>Interrupt when logic 1.</description>
                  <value>#1100</value>
                </enumeratedValue>
              </enumeratedValues>
            </field>
            <field>
              <name>ISF</name>
              <description>Interrupt Status Flag</description>
              <bitOffset>24</bitOffset>
              <bitWidth>1</bitWidth>
              <access>read-write</access>
              <enumeratedValues>
                <enumeratedValue>
                  <name>0</name>
                  <description>Configured interrupt is not detected.</description>
                  <value>#0</value>
                </enumeratedValue>
                <enumeratedValue>
                  <name>1</name>
                  <description>Configured interrupt is detected. If the pin is configured to generate a DMA request, then the corresponding flag will be cleared automatically at the completion of the requested DMA transfer. Otherwise, the flag remains set until a logic 1 is written to the flag. If the pin is configured for a level sensitive interrupt and the pin remains asserted, then the flag is set again immediately after it is cleared.</description>
                  <value>#1</value>
                </enumeratedValue>
              </enumeratedValues>
            </field>
          </fields>
        </register>
        <register>
          <name>PCR18</name>
          <description>Pin Control Register n</description>
          <addressOffset>0x48</addressOffset>
          <size>32</size>
          <access>read-write</access>
          <resetValue>0x1</resetValue>
          <resetMask>0xFFFFFFFF</resetMask>
          <fields>
            <field>
              <name>PS</name>
              <description>Pull Select</description>
              <bitOffset>0</bitOffset>
              <bitWidth>1</bitWidth>
              <access>read-only</access>
              <enumeratedValues>
                <enumeratedValue>
                  <name>0</name>
                  <description>Internal pulldown resistor is enabled on the corresponding pin, if the corresponding PE field is set.</description>
                  <value>#0</value>
                </enumeratedValue>
                <enumeratedValue>
                  <name>1</name>
                  <description>Internal pullup resistor is enabled on the corresponding pin, if the corresponding PE field is set.</description>
                  <value>#1</value>
                </enumeratedValue>
              </enumeratedValues>
            </field>
            <field>
              <name>PE</name>
              <description>Pull Enable</description>
              <bitOffset>1</bitOffset>
              <bitWidth>1</bitWidth>
              <access>read-only</access>
              <enumeratedValues>
                <enumeratedValue>
                  <name>0</name>
                  <description>Internal pullup or pulldown resistor is not enabled on the corresponding pin.</description>
                  <value>#0</value>
                </enumeratedValue>
                <enumeratedValue>
                  <name>1</name>
                  <description>Internal pullup or pulldown resistor is enabled on the corresponding pin, if the pin is configured as a digital input.</description>
                  <value>#1</value>
                </enumeratedValue>
              </enumeratedValues>
            </field>
            <field>
              <name>SRE</name>
              <description>Slew Rate Enable</description>
              <bitOffset>2</bitOffset>
              <bitWidth>1</bitWidth>
              <access>read-only</access>
              <enumeratedValues>
                <enumeratedValue>
                  <name>0</name>
                  <description>Fast slew rate is configured on the corresponding pin, if the pin is configured as a digital output.</description>
                  <value>#0</value>
                </enumeratedValue>
                <enumeratedValue>
                  <name>1</name>
                  <description>Slow slew rate is configured on the corresponding pin, if the pin is configured as a digital output.</description>
                  <value>#1</value>
                </enumeratedValue>
              </enumeratedValues>
            </field>
            <field>
              <name>PFE</name>
              <description>Passive Filter Enable</description>
              <bitOffset>4</bitOffset>
              <bitWidth>1</bitWidth>
              <access>read-only</access>
              <enumeratedValues>
                <enumeratedValue>
                  <name>0</name>
                  <description>Passive input filter is disabled on the corresponding pin.</description>
                  <value>#0</value>
                </enumeratedValue>
                <enumeratedValue>
                  <name>1</name>
                  <description>Passive input filter is enabled on the corresponding pin, if the pin is configured as a digital input. Refer to the device data sheet for filter characteristics.</description>
                  <value>#1</value>
                </enumeratedValue>
              </enumeratedValues>
            </field>
            <field>
              <name>DSE</name>
              <description>Drive Strength Enable</description>
              <bitOffset>6</bitOffset>
              <bitWidth>1</bitWidth>
              <access>read-only</access>
              <enumeratedValues>
                <enumeratedValue>
                  <name>0</name>
                  <description>Low drive strength is configured on the corresponding pin, if pin is configured as a digital output.</description>
                  <value>#0</value>
                </enumeratedValue>
                <enumeratedValue>
                  <name>1</name>
                  <description>High drive strength is configured on the corresponding pin, if pin is configured as a digital output.</description>
                  <value>#1</value>
                </enumeratedValue>
              </enumeratedValues>
            </field>
            <field>
              <name>MUX</name>
              <description>Pin Mux Control</description>
              <bitOffset>8</bitOffset>
              <bitWidth>3</bitWidth>
              <access>read-write</access>
              <enumeratedValues>
                <enumeratedValue>
                  <name>000</name>
                  <description>Pin disabled (analog).</description>
                  <value>#000</value>
                </enumeratedValue>
                <enumeratedValue>
                  <name>001</name>
                  <description>Alternative 1 (GPIO).</description>
                  <value>#001</value>
                </enumeratedValue>
                <enumeratedValue>
                  <name>010</name>
                  <description>Alternative 2 (chip-specific).</description>
                  <value>#010</value>
                </enumeratedValue>
                <enumeratedValue>
                  <name>011</name>
                  <description>Alternative 3 (chip-specific).</description>
                  <value>#011</value>
                </enumeratedValue>
                <enumeratedValue>
                  <name>100</name>
                  <description>Alternative 4 (chip-specific).</description>
                  <value>#100</value>
                </enumeratedValue>
                <enumeratedValue>
                  <name>101</name>
                  <description>Alternative 5 (chip-specific).</description>
                  <value>#101</value>
                </enumeratedValue>
                <enumeratedValue>
                  <name>110</name>
                  <description>Alternative 6 (chip-specific).</description>
                  <value>#110</value>
                </enumeratedValue>
                <enumeratedValue>
                  <name>111</name>
                  <description>Alternative 7 (chip-specific).</description>
                  <value>#111</value>
                </enumeratedValue>
              </enumeratedValues>
            </field>
            <field>
              <name>IRQC</name>
              <description>Interrupt Configuration</description>
              <bitOffset>16</bitOffset>
              <bitWidth>4</bitWidth>
              <access>read-write</access>
              <enumeratedValues>
                <enumeratedValue>
                  <name>0000</name>
                  <description>Interrupt/DMA request disabled.</description>
                  <value>#0000</value>
                </enumeratedValue>
                <enumeratedValue>
                  <name>0001</name>
                  <description>DMA request on rising edge.</description>
                  <value>#0001</value>
                </enumeratedValue>
                <enumeratedValue>
                  <name>0010</name>
                  <description>DMA request on falling edge.</description>
                  <value>#0010</value>
                </enumeratedValue>
                <enumeratedValue>
                  <name>0011</name>
                  <description>DMA request on either edge.</description>
                  <value>#0011</value>
                </enumeratedValue>
                <enumeratedValue>
                  <name>1000</name>
                  <description>Interrupt when logic 0.</description>
                  <value>#1000</value>
                </enumeratedValue>
                <enumeratedValue>
                  <name>1001</name>
                  <description>Interrupt on rising-edge.</description>
                  <value>#1001</value>
                </enumeratedValue>
                <enumeratedValue>
                  <name>1010</name>
                  <description>Interrupt on falling-edge.</description>
                  <value>#1010</value>
                </enumeratedValue>
                <enumeratedValue>
                  <name>1011</name>
                  <description>Interrupt on either edge.</description>
                  <value>#1011</value>
                </enumeratedValue>
                <enumeratedValue>
                  <name>1100</name>
                  <description>Interrupt when logic 1.</description>
                  <value>#1100</value>
                </enumeratedValue>
              </enumeratedValues>
            </field>
            <field>
              <name>ISF</name>
              <description>Interrupt Status Flag</description>
              <bitOffset>24</bitOffset>
              <bitWidth>1</bitWidth>
              <access>read-write</access>
              <enumeratedValues>
                <enumeratedValue>
                  <name>0</name>
                  <description>Configured interrupt is not detected.</description>
                  <value>#0</value>
                </enumeratedValue>
                <enumeratedValue>
                  <name>1</name>
                  <description>Configured interrupt is detected. If the pin is configured to generate a DMA request, then the corresponding flag will be cleared automatically at the completion of the requested DMA transfer. Otherwise, the flag remains set until a logic 1 is written to the flag. If the pin is configured for a level sensitive interrupt and the pin remains asserted, then the flag is set again immediately after it is cleared.</description>
                  <value>#1</value>
                </enumeratedValue>
              </enumeratedValues>
            </field>
          </fields>
        </register>
        <register>
          <name>PCR19</name>
          <description>Pin Control Register n</description>
          <addressOffset>0x4C</addressOffset>
          <size>32</size>
          <access>read-write</access>
          <resetValue>0x1</resetValue>
          <resetMask>0xFFFFFFFF</resetMask>
          <fields>
            <field>
              <name>PS</name>
              <description>Pull Select</description>
              <bitOffset>0</bitOffset>
              <bitWidth>1</bitWidth>
              <access>read-only</access>
              <enumeratedValues>
                <enumeratedValue>
                  <name>0</name>
                  <description>Internal pulldown resistor is enabled on the corresponding pin, if the corresponding PE field is set.</description>
                  <value>#0</value>
                </enumeratedValue>
                <enumeratedValue>
                  <name>1</name>
                  <description>Internal pullup resistor is enabled on the corresponding pin, if the corresponding PE field is set.</description>
                  <value>#1</value>
                </enumeratedValue>
              </enumeratedValues>
            </field>
            <field>
              <name>PE</name>
              <description>Pull Enable</description>
              <bitOffset>1</bitOffset>
              <bitWidth>1</bitWidth>
              <access>read-only</access>
              <enumeratedValues>
                <enumeratedValue>
                  <name>0</name>
                  <description>Internal pullup or pulldown resistor is not enabled on the corresponding pin.</description>
                  <value>#0</value>
                </enumeratedValue>
                <enumeratedValue>
                  <name>1</name>
                  <description>Internal pullup or pulldown resistor is enabled on the corresponding pin, if the pin is configured as a digital input.</description>
                  <value>#1</value>
                </enumeratedValue>
              </enumeratedValues>
            </field>
            <field>
              <name>SRE</name>
              <description>Slew Rate Enable</description>
              <bitOffset>2</bitOffset>
              <bitWidth>1</bitWidth>
              <access>read-only</access>
              <enumeratedValues>
                <enumeratedValue>
                  <name>0</name>
                  <description>Fast slew rate is configured on the corresponding pin, if the pin is configured as a digital output.</description>
                  <value>#0</value>
                </enumeratedValue>
                <enumeratedValue>
                  <name>1</name>
                  <description>Slow slew rate is configured on the corresponding pin, if the pin is configured as a digital output.</description>
                  <value>#1</value>
                </enumeratedValue>
              </enumeratedValues>
            </field>
            <field>
              <name>PFE</name>
              <description>Passive Filter Enable</description>
              <bitOffset>4</bitOffset>
              <bitWidth>1</bitWidth>
              <access>read-only</access>
              <enumeratedValues>
                <enumeratedValue>
                  <name>0</name>
                  <description>Passive input filter is disabled on the corresponding pin.</description>
                  <value>#0</value>
                </enumeratedValue>
                <enumeratedValue>
                  <name>1</name>
                  <description>Passive input filter is enabled on the corresponding pin, if the pin is configured as a digital input. Refer to the device data sheet for filter characteristics.</description>
                  <value>#1</value>
                </enumeratedValue>
              </enumeratedValues>
            </field>
            <field>
              <name>DSE</name>
              <description>Drive Strength Enable</description>
              <bitOffset>6</bitOffset>
              <bitWidth>1</bitWidth>
              <access>read-only</access>
              <enumeratedValues>
                <enumeratedValue>
                  <name>0</name>
                  <description>Low drive strength is configured on the corresponding pin, if pin is configured as a digital output.</description>
                  <value>#0</value>
                </enumeratedValue>
                <enumeratedValue>
                  <name>1</name>
                  <description>High drive strength is configured on the corresponding pin, if pin is configured as a digital output.</description>
                  <value>#1</value>
                </enumeratedValue>
              </enumeratedValues>
            </field>
            <field>
              <name>MUX</name>
              <description>Pin Mux Control</description>
              <bitOffset>8</bitOffset>
              <bitWidth>3</bitWidth>
              <access>read-write</access>
              <enumeratedValues>
                <enumeratedValue>
                  <name>000</name>
                  <description>Pin disabled (analog).</description>
                  <value>#000</value>
                </enumeratedValue>
                <enumeratedValue>
                  <name>001</name>
                  <description>Alternative 1 (GPIO).</description>
                  <value>#001</value>
                </enumeratedValue>
                <enumeratedValue>
                  <name>010</name>
                  <description>Alternative 2 (chip-specific).</description>
                  <value>#010</value>
                </enumeratedValue>
                <enumeratedValue>
                  <name>011</name>
                  <description>Alternative 3 (chip-specific).</description>
                  <value>#011</value>
                </enumeratedValue>
                <enumeratedValue>
                  <name>100</name>
                  <description>Alternative 4 (chip-specific).</description>
                  <value>#100</value>
                </enumeratedValue>
                <enumeratedValue>
                  <name>101</name>
                  <description>Alternative 5 (chip-specific).</description>
                  <value>#101</value>
                </enumeratedValue>
                <enumeratedValue>
                  <name>110</name>
                  <description>Alternative 6 (chip-specific).</description>
                  <value>#110</value>
                </enumeratedValue>
                <enumeratedValue>
                  <name>111</name>
                  <description>Alternative 7 (chip-specific).</description>
                  <value>#111</value>
                </enumeratedValue>
              </enumeratedValues>
            </field>
            <field>
              <name>IRQC</name>
              <description>Interrupt Configuration</description>
              <bitOffset>16</bitOffset>
              <bitWidth>4</bitWidth>
              <access>read-write</access>
              <enumeratedValues>
                <enumeratedValue>
                  <name>0000</name>
                  <description>Interrupt/DMA request disabled.</description>
                  <value>#0000</value>
                </enumeratedValue>
                <enumeratedValue>
                  <name>0001</name>
                  <description>DMA request on rising edge.</description>
                  <value>#0001</value>
                </enumeratedValue>
                <enumeratedValue>
                  <name>0010</name>
                  <description>DMA request on falling edge.</description>
                  <value>#0010</value>
                </enumeratedValue>
                <enumeratedValue>
                  <name>0011</name>
                  <description>DMA request on either edge.</description>
                  <value>#0011</value>
                </enumeratedValue>
                <enumeratedValue>
                  <name>1000</name>
                  <description>Interrupt when logic 0.</description>
                  <value>#1000</value>
                </enumeratedValue>
                <enumeratedValue>
                  <name>1001</name>
                  <description>Interrupt on rising-edge.</description>
                  <value>#1001</value>
                </enumeratedValue>
                <enumeratedValue>
                  <name>1010</name>
                  <description>Interrupt on falling-edge.</description>
                  <value>#1010</value>
                </enumeratedValue>
                <enumeratedValue>
                  <name>1011</name>
                  <description>Interrupt on either edge.</description>
                  <value>#1011</value>
                </enumeratedValue>
                <enumeratedValue>
                  <name>1100</name>
                  <description>Interrupt when logic 1.</description>
                  <value>#1100</value>
                </enumeratedValue>
              </enumeratedValues>
            </field>
            <field>
              <name>ISF</name>
              <description>Interrupt Status Flag</description>
              <bitOffset>24</bitOffset>
              <bitWidth>1</bitWidth>
              <access>read-write</access>
              <enumeratedValues>
                <enumeratedValue>
                  <name>0</name>
                  <description>Configured interrupt is not detected.</description>
                  <value>#0</value>
                </enumeratedValue>
                <enumeratedValue>
                  <name>1</name>
                  <description>Configured interrupt is detected. If the pin is configured to generate a DMA request, then the corresponding flag will be cleared automatically at the completion of the requested DMA transfer. Otherwise, the flag remains set until a logic 1 is written to the flag. If the pin is configured for a level sensitive interrupt and the pin remains asserted, then the flag is set again immediately after it is cleared.</description>
                  <value>#1</value>
                </enumeratedValue>
              </enumeratedValues>
            </field>
          </fields>
        </register>
        <register>
          <name>PCR20</name>
          <description>Pin Control Register n</description>
          <addressOffset>0x50</addressOffset>
          <size>32</size>
          <access>read-write</access>
          <resetValue>0x5</resetValue>
          <resetMask>0xFFFFFFFF</resetMask>
          <fields>
            <field>
              <name>PS</name>
              <description>Pull Select</description>
              <bitOffset>0</bitOffset>
              <bitWidth>1</bitWidth>
              <access>read-write</access>
              <enumeratedValues>
                <enumeratedValue>
                  <name>0</name>
                  <description>Internal pulldown resistor is enabled on the corresponding pin, if the corresponding PE field is set.</description>
                  <value>#0</value>
                </enumeratedValue>
                <enumeratedValue>
                  <name>1</name>
                  <description>Internal pullup resistor is enabled on the corresponding pin, if the corresponding PE field is set.</description>
                  <value>#1</value>
                </enumeratedValue>
              </enumeratedValues>
            </field>
            <field>
              <name>PE</name>
              <description>Pull Enable</description>
              <bitOffset>1</bitOffset>
              <bitWidth>1</bitWidth>
              <access>read-write</access>
              <enumeratedValues>
                <enumeratedValue>
                  <name>0</name>
                  <description>Internal pullup or pulldown resistor is not enabled on the corresponding pin.</description>
                  <value>#0</value>
                </enumeratedValue>
                <enumeratedValue>
                  <name>1</name>
                  <description>Internal pullup or pulldown resistor is enabled on the corresponding pin, if the pin is configured as a digital input.</description>
                  <value>#1</value>
                </enumeratedValue>
              </enumeratedValues>
            </field>
            <field>
              <name>SRE</name>
              <description>Slew Rate Enable</description>
              <bitOffset>2</bitOffset>
              <bitWidth>1</bitWidth>
              <access>read-write</access>
              <enumeratedValues>
                <enumeratedValue>
                  <name>0</name>
                  <description>Fast slew rate is configured on the corresponding pin, if the pin is configured as a digital output.</description>
                  <value>#0</value>
                </enumeratedValue>
                <enumeratedValue>
                  <name>1</name>
                  <description>Slow slew rate is configured on the corresponding pin, if the pin is configured as a digital output.</description>
                  <value>#1</value>
                </enumeratedValue>
              </enumeratedValues>
            </field>
            <field>
              <name>PFE</name>
              <description>Passive Filter Enable</description>
              <bitOffset>4</bitOffset>
              <bitWidth>1</bitWidth>
              <access>read-only</access>
              <enumeratedValues>
                <enumeratedValue>
                  <name>0</name>
                  <description>Passive input filter is disabled on the corresponding pin.</description>
                  <value>#0</value>
                </enumeratedValue>
                <enumeratedValue>
                  <name>1</name>
                  <description>Passive input filter is enabled on the corresponding pin, if the pin is configured as a digital input. Refer to the device data sheet for filter characteristics.</description>
                  <value>#1</value>
                </enumeratedValue>
              </enumeratedValues>
            </field>
            <field>
              <name>DSE</name>
              <description>Drive Strength Enable</description>
              <bitOffset>6</bitOffset>
              <bitWidth>1</bitWidth>
              <access>read-only</access>
              <enumeratedValues>
                <enumeratedValue>
                  <name>0</name>
                  <description>Low drive strength is configured on the corresponding pin, if pin is configured as a digital output.</description>
                  <value>#0</value>
                </enumeratedValue>
                <enumeratedValue>
                  <name>1</name>
                  <description>High drive strength is configured on the corresponding pin, if pin is configured as a digital output.</description>
                  <value>#1</value>
                </enumeratedValue>
              </enumeratedValues>
            </field>
            <field>
              <name>MUX</name>
              <description>Pin Mux Control</description>
              <bitOffset>8</bitOffset>
              <bitWidth>3</bitWidth>
              <access>read-write</access>
              <enumeratedValues>
                <enumeratedValue>
                  <name>000</name>
                  <description>Pin disabled (analog).</description>
                  <value>#000</value>
                </enumeratedValue>
                <enumeratedValue>
                  <name>001</name>
                  <description>Alternative 1 (GPIO).</description>
                  <value>#001</value>
                </enumeratedValue>
                <enumeratedValue>
                  <name>010</name>
                  <description>Alternative 2 (chip-specific).</description>
                  <value>#010</value>
                </enumeratedValue>
                <enumeratedValue>
                  <name>011</name>
                  <description>Alternative 3 (chip-specific).</description>
                  <value>#011</value>
                </enumeratedValue>
                <enumeratedValue>
                  <name>100</name>
                  <description>Alternative 4 (chip-specific).</description>
                  <value>#100</value>
                </enumeratedValue>
                <enumeratedValue>
                  <name>101</name>
                  <description>Alternative 5 (chip-specific).</description>
                  <value>#101</value>
                </enumeratedValue>
                <enumeratedValue>
                  <name>110</name>
                  <description>Alternative 6 (chip-specific).</description>
                  <value>#110</value>
                </enumeratedValue>
                <enumeratedValue>
                  <name>111</name>
                  <description>Alternative 7 (chip-specific).</description>
                  <value>#111</value>
                </enumeratedValue>
              </enumeratedValues>
            </field>
            <field>
              <name>IRQC</name>
              <description>Interrupt Configuration</description>
              <bitOffset>16</bitOffset>
              <bitWidth>4</bitWidth>
              <access>read-write</access>
              <enumeratedValues>
                <enumeratedValue>
                  <name>0000</name>
                  <description>Interrupt/DMA request disabled.</description>
                  <value>#0000</value>
                </enumeratedValue>
                <enumeratedValue>
                  <name>0001</name>
                  <description>DMA request on rising edge.</description>
                  <value>#0001</value>
                </enumeratedValue>
                <enumeratedValue>
                  <name>0010</name>
                  <description>DMA request on falling edge.</description>
                  <value>#0010</value>
                </enumeratedValue>
                <enumeratedValue>
                  <name>0011</name>
                  <description>DMA request on either edge.</description>
                  <value>#0011</value>
                </enumeratedValue>
                <enumeratedValue>
                  <name>1000</name>
                  <description>Interrupt when logic 0.</description>
                  <value>#1000</value>
                </enumeratedValue>
                <enumeratedValue>
                  <name>1001</name>
                  <description>Interrupt on rising-edge.</description>
                  <value>#1001</value>
                </enumeratedValue>
                <enumeratedValue>
                  <name>1010</name>
                  <description>Interrupt on falling-edge.</description>
                  <value>#1010</value>
                </enumeratedValue>
                <enumeratedValue>
                  <name>1011</name>
                  <description>Interrupt on either edge.</description>
                  <value>#1011</value>
                </enumeratedValue>
                <enumeratedValue>
                  <name>1100</name>
                  <description>Interrupt when logic 1.</description>
                  <value>#1100</value>
                </enumeratedValue>
              </enumeratedValues>
            </field>
            <field>
              <name>ISF</name>
              <description>Interrupt Status Flag</description>
              <bitOffset>24</bitOffset>
              <bitWidth>1</bitWidth>
              <access>read-write</access>
              <enumeratedValues>
                <enumeratedValue>
                  <name>0</name>
                  <description>Configured interrupt is not detected.</description>
                  <value>#0</value>
                </enumeratedValue>
                <enumeratedValue>
                  <name>1</name>
                  <description>Configured interrupt is detected. If the pin is configured to generate a DMA request, then the corresponding flag will be cleared automatically at the completion of the requested DMA transfer. Otherwise, the flag remains set until a logic 1 is written to the flag. If the pin is configured for a level sensitive interrupt and the pin remains asserted, then the flag is set again immediately after it is cleared.</description>
                  <value>#1</value>
                </enumeratedValue>
              </enumeratedValues>
            </field>
          </fields>
        </register>
        <register>
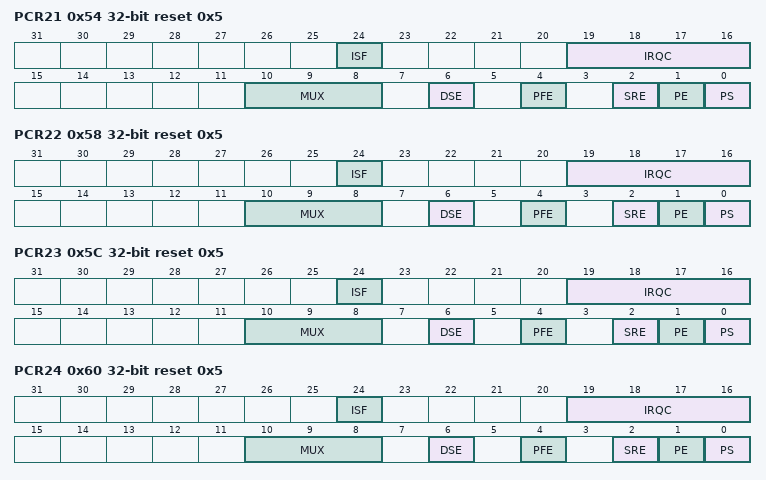
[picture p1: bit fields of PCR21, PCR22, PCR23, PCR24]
          <name>PCR21</name>
          <description>Pin Control Register n</description>
          <addressOffset>0x54</addressOffset>
          <size>32</size>
          <access>read-write</access>
          <resetValue>0x5</resetValue>
          <resetMask>0xFFFFFFFF</resetMask>
          <fields>
            <field>
              <name>PS</name>
              <description>Pull Select</description>
              <bitOffset>0</bitOffset>
              <bitWidth>1</bitWidth>
              <access>read-write</access>
              <enumeratedValues>
                <enumeratedValue>
                  <name>0</name>
                  <description>Internal pulldown resistor is enabled on the corresponding pin, if the corresponding PE field is set.</description>
                  <value>#0</value>
                </enumeratedValue>
                <enumeratedValue>
                  <name>1</name>
                  <description>Internal pullup resistor is enabled on the corresponding pin, if the corresponding PE field is set.</description>
                  <value>#1</value>
                </enumeratedValue>
              </enumeratedValues>
            </field>
            <field>
              <name>PE</name>
              <description>Pull Enable</description>
              <bitOffset>1</bitOffset>
              <bitWidth>1</bitWidth>
              <access>read-write</access>
              <enumeratedValues>
                <enumeratedValue>
                  <name>0</name>
                  <description>Internal pullup or pulldown resistor is not enabled on the corresponding pin.</description>
                  <value>#0</value>
                </enumeratedValue>
                <enumeratedValue>
                  <name>1</name>
                  <description>Internal pullup or pulldown resistor is enabled on the corresponding pin, if the pin is configured as a digital input.</description>
                  <value>#1</value>
                </enumeratedValue>
              </enumeratedValues>
            </field>
            <field>
              <name>SRE</name>
              <description>Slew Rate Enable</description>
              <bitOffset>2</bitOffset>
              <bitWidth>1</bitWidth>
              <access>read-write</access>
              <enumeratedValues>
                <enumeratedValue>
                  <name>0</name>
                  <description>Fast slew rate is configured on the corresponding pin, if the pin is configured as a digital output.</description>
                  <value>#0</value>
                </enumeratedValue>
                <enumeratedValue>
                  <name>1</name>
                  <description>Slow slew rate is configured on the corresponding pin, if the pin is configured as a digital output.</description>
                  <value>#1</value>
                </enumeratedValue>
              </enumeratedValues>
            </field>
            <field>
              <name>PFE</name>
              <description>Passive Filter Enable</description>
              <bitOffset>4</bitOffset>
              <bitWidth>1</bitWidth>
              <access>read-only</access>
              <enumeratedValues>
                <enumeratedValue>
                  <name>0</name>
                  <description>Passive input filter is disabled on the corresponding pin.</description>
                  <value>#0</value>
                </enumeratedValue>
                <enumeratedValue>
                  <name>1</name>
                  <description>Passive input filter is enabled on the corresponding pin, if the pin is configured as a digital input. Refer to the device data sheet for filter characteristics.</description>
                  <value>#1</value>
                </enumeratedValue>
              </enumeratedValues>
            </field>
            <field>
              <name>DSE</name>
              <description>Drive Strength Enable</description>
              <bitOffset>6</bitOffset>
              <bitWidth>1</bitWidth>
              <access>read-only</access>
              <enumeratedValues>
                <enumeratedValue>
                  <name>0</name>
                  <description>Low drive strength is configured on the corresponding pin, if pin is configured as a digital output.</description>
                  <value>#0</value>
                </enumeratedValue>
                <enumeratedValue>
                  <name>1</name>
                  <description>High drive strength is configured on the corresponding pin, if pin is configured as a digital output.</description>
                  <value>#1</value>
                </enumeratedValue>
              </enumeratedValues>
            </field>
            <field>
              <name>MUX</name>
              <description>Pin Mux Control</description>
              <bitOffset>8</bitOffset>
              <bitWidth>3</bitWidth>
              <access>read-write</access>
              <enumeratedValues>
                <enumeratedValue>
                  <name>000</name>
                  <description>Pin disabled (analog).</description>
                  <value>#000</value>
                </enumeratedValue>
                <enumeratedValue>
                  <name>001</name>
                  <description>Alternative 1 (GPIO).</description>
                  <value>#001</value>
                </enumeratedValue>
                <enumeratedValue>
                  <name>010</name>
                  <description>Alternative 2 (chip-specific).</description>
                  <value>#010</value>
                </enumeratedValue>
                <enumeratedValue>
                  <name>011</name>
                  <description>Alternative 3 (chip-specific).</description>
                  <value>#011</value>
                </enumeratedValue>
                <enumeratedValue>
                  <name>100</name>
                  <description>Alternative 4 (chip-specific).</description>
                  <value>#100</value>
                </enumeratedValue>
                <enumeratedValue>
                  <name>101</name>
                  <description>Alternative 5 (chip-specific).</description>
                  <value>#101</value>
                </enumeratedValue>
                <enumeratedValue>
                  <name>110</name>
                  <description>Alternative 6 (chip-specific).</description>
                  <value>#110</value>
                </enumeratedValue>
                <enumeratedValue>
                  <name>111</name>
                  <description>Alternative 7 (chip-specific).</description>
                  <value>#111</value>
                </enumeratedValue>
              </enumeratedValues>
            </field>
            <field>
              <name>IRQC</name>
              <description>Interrupt Configuration</description>
              <bitOffset>16</bitOffset>
              <bitWidth>4</bitWidth>
              <access>read-write</access>
              <enumeratedValues>
                <enumeratedValue>
                  <name>0000</name>
                  <description>Interrupt/DMA request disabled.</description>
                  <value>#0000</value>
                </enumeratedValue>
                <enumeratedValue>
                  <name>0001</name>
                  <description>DMA request on rising edge.</description>
                  <value>#0001</value>
                </enumeratedValue>
                <enumeratedValue>
                  <name>0010</name>
                  <description>DMA request on falling edge.</description>
                  <value>#0010</value>
                </enumeratedValue>
                <enumeratedValue>
                  <name>0011</name>
                  <description>DMA request on either edge.</description>
                  <value>#0011</value>
                </enumeratedValue>
                <enumeratedValue>
                  <name>1000</name>
                  <description>Interrupt when logic 0.</description>
                  <value>#1000</value>
                </enumeratedValue>
                <enumeratedValue>
                  <name>1001</name>
                  <description>Interrupt on rising-edge.</description>
                  <value>#1001</value>
                </enumeratedValue>
                <enumeratedValue>
                  <name>1010</name>
                  <description>Interrupt on falling-edge.</description>
                  <value>#1010</value>
                </enumeratedValue>
                <enumeratedValue>
                  <name>1011</name>
                  <description>Interrupt on either edge.</description>
                  <value>#1011</value>
                </enumeratedValue>
                <enumeratedValue>
                  <name>1100</name>
                  <description>Interrupt when logic 1.</description>
                  <value>#1100</value>
                </enumeratedValue>
              </enumeratedValues>
            </field>
            <field>
              <name>ISF</name>
              <description>Interrupt Status Flag</description>
              <bitOffset>24</bitOffset>
              <bitWidth>1</bitWidth>
              <access>read-write</access>
              <enumeratedValues>
                <enumeratedValue>
                  <name>0</name>
                  <description>Configured interrupt is not detected.</description>
                  <value>#0</value>
                </enumeratedValue>
                <enumeratedValue>
                  <name>1</name>
                  <description>Configured interrupt is detected. If the pin is configured to generate a DMA request, then the corresponding flag will be cleared automatically at the completion of the requested DMA transfer. Otherwise, the flag remains set until a logic 1 is written to the flag. If the pin is configured for a level sensitive interrupt and the pin remains asserted, then the flag is set again immediately after it is cleared.</description>
                  <value>#1</value>
                </enumeratedValue>
              </enumeratedValues>
            </field>
          </fields>
        </register>
        <register>
          <name>PCR22</name>
          <description>Pin Control Register n</description>
          <addressOffset>0x58</addressOffset>
          <size>32</size>
          <access>read-write</access>
          <resetValue>0x5</resetValue>
          <resetMask>0xFFFFFFFF</resetMask>
          <fields>
            <field>
              <name>PS</name>
              <description>Pull Select</description>
              <bitOffset>0</bitOffset>
              <bitWidth>1</bitWidth>
              <access>read-write</access>
              <enumeratedValues>
                <enumeratedValue>
                  <name>0</name>
                  <description>Internal pulldown resistor is enabled on the corresponding pin, if the corresponding PE field is set.</description>
                  <value>#0</value>
                </enumeratedValue>
                <enumeratedValue>
                  <name>1</name>
                  <description>Internal pullup resistor is enabled on the corresponding pin, if the corresponding PE field is set.</description>
                  <value>#1</value>
                </enumeratedValue>
              </enumeratedValues>
            </field>
            <field>
              <name>PE</name>
              <description>Pull Enable</description>
              <bitOffset>1</bitOffset>
              <bitWidth>1</bitWidth>
              <access>read-write</access>
              <enumeratedValues>
                <enumeratedValue>
                  <name>0</name>
                  <description>Internal pullup or pulldown resistor is not enabled on the corresponding pin.</description>
                  <value>#0</value>
                </enumeratedValue>
                <enumeratedValue>
                  <name>1</name>
                  <description>Internal pullup or pulldown resistor is enabled on the corresponding pin, if the pin is configured as a digital input.</description>
                  <value>#1</value>
                </enumeratedValue>
              </enumeratedValues>
            </field>
            <field>
              <name>SRE</name>
              <description>Slew Rate Enable</description>
              <bitOffset>2</bitOffset>
              <bitWidth>1</bitWidth>
              <access>read-write</access>
              <enumeratedValues>
                <enumeratedValue>
                  <name>0</name>
                  <description>Fast slew rate is configured on the corresponding pin, if the pin is configured as a digital output.</description>
                  <value>#0</value>
                </enumeratedValue>
                <enumeratedValue>
                  <name>1</name>
                  <description>Slow slew rate is configured on the corresponding pin, if the pin is configured as a digital output.</description>
                  <value>#1</value>
                </enumeratedValue>
              </enumeratedValues>
            </field>
            <field>
              <name>PFE</name>
              <description>Passive Filter Enable</description>
              <bitOffset>4</bitOffset>
              <bitWidth>1</bitWidth>
              <access>read-only</access>
              <enumeratedValues>
                <enumeratedValue>
                  <name>0</name>
                  <description>Passive input filter is disabled on the corresponding pin.</description>
                  <value>#0</value>
                </enumeratedValue>
                <enumeratedValue>
                  <name>1</name>
                  <description>Passive input filter is enabled on the corresponding pin, if the pin is configured as a digital input. Refer to the device data sheet for filter characteristics.</description>
                  <value>#1</value>
                </enumeratedValue>
              </enumeratedValues>
            </field>
            <field>
              <name>DSE</name>
              <description>Drive Strength Enable</description>
              <bitOffset>6</bitOffset>
              <bitWidth>1</bitWidth>
              <access>read-only</access>
              <enumeratedValues>
                <enumeratedValue>
                  <name>0</name>
                  <description>Low drive strength is configured on the corresponding pin, if pin is configured as a digital output.</description>
                  <value>#0</value>
                </enumeratedValue>
                <enumeratedValue>
                  <name>1</name>
                  <description>High drive strength is configured on the corresponding pin, if pin is configured as a digital output.</description>
                  <value>#1</value>
                </enumeratedValue>
              </enumeratedValues>
            </field>
            <field>
              <name>MUX</name>
              <description>Pin Mux Control</description>
              <bitOffset>8</bitOffset>
              <bitWidth>3</bitWidth>
              <access>read-write</access>
              <enumeratedValues>
                <enumeratedValue>
                  <name>000</name>
                  <description>Pin disabled (analog).</description>
                  <value>#000</value>
                </enumeratedValue>
                <enumeratedValue>
                  <name>001</name>
                  <description>Alternative 1 (GPIO).</description>
                  <value>#001</value>
                </enumeratedValue>
                <enumeratedValue>
                  <name>010</name>
                  <description>Alternative 2 (chip-specific).</description>
                  <value>#010</value>
                </enumeratedValue>
                <enumeratedValue>
                  <name>011</name>
                  <description>Alternative 3 (chip-specific).</description>
                  <value>#011</value>
                </enumeratedValue>
                <enumeratedValue>
                  <name>100</name>
                  <description>Alternative 4 (chip-specific).</description>
                  <value>#100</value>
                </enumeratedValue>
                <enumeratedValue>
                  <name>101</name>
                  <description>Alternative 5 (chip-specific).</description>
                  <value>#101</value>
                </enumeratedValue>
                <enumeratedValue>
                  <name>110</name>
                  <description>Alternative 6 (chip-specific).</description>
                  <value>#110</value>
                </enumeratedValue>
                <enumeratedValue>
                  <name>111</name>
                  <description>Alternative 7 (chip-specific).</description>
                  <value>#111</value>
                </enumeratedValue>
              </enumeratedValues>
            </field>
            <field>
              <name>IRQC</name>
              <description>Interrupt Configuration</description>
              <bitOffset>16</bitOffset>
              <bitWidth>4</bitWidth>
              <access>read-write</access>
              <enumeratedValues>
                <enumeratedValue>
                  <name>0000</name>
                  <description>Interrupt/DMA request disabled.</description>
                  <value>#0000</value>
                </enumeratedValue>
                <enumeratedValue>
                  <name>0001</name>
                  <description>DMA request on rising edge.</description>
                  <value>#0001</value>
                </enumeratedValue>
                <enumeratedValue>
                  <name>0010</name>
                  <description>DMA request on falling edge.</description>
                  <value>#0010</value>
                </enumeratedValue>
                <enumeratedValue>
                  <name>0011</name>
                  <description>DMA request on either edge.</description>
                  <value>#0011</value>
                </enumeratedValue>
                <enumeratedValue>
                  <name>1000</name>
                  <description>Interrupt when logic 0.</description>
                  <value>#1000</value>
                </enumeratedValue>
                <enumeratedValue>
                  <name>1001</name>
                  <description>Interrupt on rising-edge.</description>
                  <value>#1001</value>
                </enumeratedValue>
                <enumeratedValue>
                  <name>1010</name>
                  <description>Interrupt on falling-edge.</description>
                  <value>#1010</value>
                </enumeratedValue>
                <enumeratedValue>
                  <name>1011</name>
                  <description>Interrupt on either edge.</description>
                  <value>#1011</value>
                </enumeratedValue>
                <enumeratedValue>
                  <name>1100</name>
                  <description>Interrupt when logic 1.</description>
                  <value>#1100</value>
                </enumeratedValue>
              </enumeratedValues>
            </field>
            <field>
              <name>ISF</name>
              <description>Interrupt Status Flag</description>
              <bitOffset>24</bitOffset>
              <bitWidth>1</bitWidth>
              <access>read-write</access>
              <enumeratedValues>
                <enumeratedValue>
                  <name>0</name>
                  <description>Configured interrupt is not detected.</description>
                  <value>#0</value>
                </enumeratedValue>
                <enumeratedValue>
                  <name>1</name>
                  <description>Configured interrupt is detected. If the pin is configured to generate a DMA request, then the corresponding flag will be cleared automatically at the completion of the requested DMA transfer. Otherwise, the flag remains set until a logic 1 is written to the flag. If the pin is configured for a level sensitive interrupt and the pin remains asserted, then the flag is set again immediately after it is cleared.</description>
                  <value>#1</value>
                </enumeratedValue>
              </enumeratedValues>
            </field>
          </fields>
        </register>
        <register>
          <name>PCR23</name>
          <description>Pin Control Register n</description>
          <addressOffset>0x5C</addressOffset>
          <size>32</size>
          <access>read-write</access>
          <resetValue>0x5</resetValue>
          <resetMask>0xFFFFFFFF</resetMask>
          <fields>
            <field>
              <name>PS</name>
              <description>Pull Select</description>
              <bitOffset>0</bitOffset>
              <bitWidth>1</bitWidth>
              <access>read-write</access>
              <enumeratedValues>
                <enumeratedValue>
                  <name>0</name>
                  <description>Internal pulldown resistor is enabled on the corresponding pin, if the corresponding PE field is set.</description>
                  <value>#0</value>
                </enumeratedValue>
                <enumeratedValue>
                  <name>1</name>
                  <description>Internal pullup resistor is enabled on the corresponding pin, if the corresponding PE field is set.</description>
                  <value>#1</value>
                </enumeratedValue>
              </enumeratedValues>
            </field>
            <field>
              <name>PE</name>
              <description>Pull Enable</description>
              <bitOffset>1</bitOffset>
              <bitWidth>1</bitWidth>
              <access>read-write</access>
              <enumeratedValues>
                <enumeratedValue>
                  <name>0</name>
                  <description>Internal pullup or pulldown resistor is not enabled on the corresponding pin.</description>
                  <value>#0</value>
                </enumeratedValue>
                <enumeratedValue>
                  <name>1</name>
                  <description>Internal pullup or pulldown resistor is enabled on the corresponding pin, if the pin is configured as a digital input.</description>
                  <value>#1</value>
                </enumeratedValue>
              </enumeratedValues>
            </field>
            <field>
              <name>SRE</name>
              <description>Slew Rate Enable</description>
              <bitOffset>2</bitOffset>
              <bitWidth>1</bitWidth>
              <access>read-write</access>
              <enumeratedValues>
                <enumeratedValue>
                  <name>0</name>
                  <description>Fast slew rate is configured on the corresponding pin, if the pin is configured as a digital output.</description>
                  <value>#0</value>
                </enumeratedValue>
                <enumeratedValue>
                  <name>1</name>
                  <description>Slow slew rate is configured on the corresponding pin, if the pin is configured as a digital output.</description>
                  <value>#1</value>
                </enumeratedValue>
              </enumeratedValues>
            </field>
            <field>
              <name>PFE</name>
              <description>Passive Filter Enable</description>
              <bitOffset>4</bitOffset>
              <bitWidth>1</bitWidth>
              <access>read-only</access>
              <enumeratedValues>
                <enumeratedValue>
                  <name>0</name>
                  <description>Passive input filter is disabled on the corresponding pin.</description>
                  <value>#0</value>
                </enumeratedValue>
                <enumeratedValue>
                  <name>1</name>
                  <description>Passive input filter is enabled on the corresponding pin, if the pin is configured as a digital input. Refer to the device data sheet for filter characteristics.</description>
                  <value>#1</value>
                </enumeratedValue>
              </enumeratedValues>
            </field>
            <field>
              <name>DSE</name>
              <description>Drive Strength Enable</description>
              <bitOffset>6</bitOffset>
              <bitWidth>1</bitWidth>
              <access>read-only</access>
              <enumeratedValues>
                <enumeratedValue>
                  <name>0</name>
                  <description>Low drive strength is configured on the corresponding pin, if pin is configured as a digital output.</description>
                  <value>#0</value>
                </enumeratedValue>
                <enumeratedValue>
                  <name>1</name>
                  <description>High drive strength is configured on the corresponding pin, if pin is configured as a digital output.</description>
                  <value>#1</value>
                </enumeratedValue>
              </enumeratedValues>
            </field>
            <field>
              <name>MUX</name>
              <description>Pin Mux Control</description>
              <bitOffset>8</bitOffset>
              <bitWidth>3</bitWidth>
              <access>read-write</access>
              <enumeratedValues>
                <enumeratedValue>
                  <name>000</name>
                  <description>Pin disabled (analog).</description>
                  <value>#000</value>
                </enumeratedValue>
                <enumeratedValue>
                  <name>001</name>
                  <description>Alternative 1 (GPIO).</description>
                  <value>#001</value>
                </enumeratedValue>
                <enumeratedValue>
                  <name>010</name>
                  <description>Alternative 2 (chip-specific).</description>
                  <value>#010</value>
                </enumeratedValue>
                <enumeratedValue>
                  <name>011</name>
                  <description>Alternative 3 (chip-specific).</description>
                  <value>#011</value>
                </enumeratedValue>
                <enumeratedValue>
                  <name>100</name>
                  <description>Alternative 4 (chip-specific).</description>
                  <value>#100</value>
                </enumeratedValue>
                <enumeratedValue>
                  <name>101</name>
                  <description>Alternative 5 (chip-specific).</description>
                  <value>#101</value>
                </enumeratedValue>
                <enumeratedValue>
                  <name>110</name>
                  <description>Alternative 6 (chip-specific).</description>
                  <value>#110</value>
                </enumeratedValue>
                <enumeratedValue>
                  <name>111</name>
                  <description>Alternative 7 (chip-specific).</description>
                  <value>#111</value>
                </enumeratedValue>
              </enumeratedValues>
            </field>
            <field>
              <name>IRQC</name>
              <description>Interrupt Configuration</description>
              <bitOffset>16</bitOffset>
              <bitWidth>4</bitWidth>
              <access>read-write</access>
              <enumeratedValues>
                <enumeratedValue>
                  <name>0000</name>
                  <description>Interrupt/DMA request disabled.</description>
                  <value>#0000</value>
                </enumeratedValue>
                <enumeratedValue>
                  <name>0001</name>
                  <description>DMA request on rising edge.</description>
                  <value>#0001</value>
                </enumeratedValue>
                <enumeratedValue>
                  <name>0010</name>
                  <description>DMA request on falling edge.</description>
                  <value>#0010</value>
                </enumeratedValue>
                <enumeratedValue>
                  <name>0011</name>
                  <description>DMA request on either edge.</description>
                  <value>#0011</value>
                </enumeratedValue>
                <enumeratedValue>
                  <name>1000</name>
                  <description>Interrupt when logic 0.</description>
                  <value>#1000</value>
                </enumeratedValue>
                <enumeratedValue>
                  <name>1001</name>
                  <description>Interrupt on rising-edge.</description>
                  <value>#1001</value>
                </enumeratedValue>
                <enumeratedValue>
                  <name>1010</name>
                  <description>Interrupt on falling-edge.</description>
                  <value>#1010</value>
                </enumeratedValue>
                <enumeratedValue>
                  <name>1011</name>
                  <description>Interrupt on either edge.</description>
                  <value>#1011</value>
                </enumeratedValue>
                <enumeratedValue>
                  <name>1100</name>
                  <description>Interrupt when logic 1.</description>
                  <value>#1100</value>
                </enumeratedValue>
              </enumeratedValues>
            </field>
            <field>
              <name>ISF</name>
              <description>Interrupt Status Flag</description>
              <bitOffset>24</bitOffset>
              <bitWidth>1</bitWidth>
              <access>read-write</access>
              <enumeratedValues>
                <enumeratedValue>
                  <name>0</name>
                  <description>Configured interrupt is not detected.</description>
                  <value>#0</value>
                </enumeratedValue>
                <enumeratedValue>
                  <name>1</name>
                  <description>Configured interrupt is detected. If the pin is configured to generate a DMA request, then the corresponding flag will be cleared automatically at the completion of the requested DMA transfer. Otherwise, the flag remains set until a logic 1 is written to the flag. If the pin is configured for a level sensitive interrupt and the pin remains asserted, then the flag is set again immediately after it is cleared.</description>
                  <value>#1</value>
                </enumeratedValue>
              </enumeratedValues>
            </field>
          </fields>
        </register>
        <register>
          <name>PCR24</name>
          <description>Pin Control Register n</description>
          <addressOffset>0x60</addressOffset>
          <size>32</size>
          <access>read-write</access>
          <resetValue>0x5</resetValue>
          <resetMask>0xFFFFFFFF</resetMask>
          <fields>
            <field>
              <name>PS</name>
              <description>Pull Select</description>
              <bitOffset>0</bitOffset>
              <bitWidth>1</bitWidth>
              <access>read-write</access>
              <enumeratedValues>
                <enumeratedValue>
                  <name>0</name>
                  <description>Internal pulldown resistor is enabled on the corresponding pin, if the corresponding PE field is set.</description>
                  <value>#0</value>
                </enumeratedValue>
                <enumeratedValue>
                  <name>1</name>
                  <description>Internal pullup resistor is enabled on the corresponding pin, if the corresponding PE field is set.</description>
                  <value>#1</value>
                </enumeratedValue>
              </enumeratedValues>
            </field>
            <field>
              <name>PE</name>
              <description>Pull Enable</description>
              <bitOffset>1</bitOffset>
              <bitWidth>1</bitWidth>
              <access>read-write</access>
              <enumeratedValues>
                <enumeratedValue>
                  <name>0</name>
                  <description>Internal pullup or pulldown resistor is not enabled on the corresponding pin.</description>
                  <value>#0</value>
                </enumeratedValue>
                <enumeratedValue>
                  <name>1</name>
                  <description>Internal pullup or pulldown resistor is enabled on the corresponding pin, if the pin is configured as a digital input.</description>
                  <value>#1</value>
                </enumeratedValue>
              </enumeratedValues>
            </field>
            <field>
              <name>SRE</name>
              <description>Slew Rate Enable</description>
              <bitOffset>2</bitOffset>
              <bitWidth>1</bitWidth>
              <access>read-write</access>
              <enumeratedValues>
                <enumeratedValue>
                  <name>0</name>
                  <description>Fast slew rate is configured on the corresponding pin, if the pin is configured as a digital output.</description>
                  <value>#0</value>
                </enumeratedValue>
                <enumeratedValue>
                  <name>1</name>
                  <description>Slow slew rate is configured on the corresponding pin, if the pin is configured as a digital output.</description>
                  <value>#1</value>
                </enumeratedValue>
              </enumeratedValues>
            </field>
            <field>
              <name>PFE</name>
              <description>Passive Filter Enable</description>
              <bitOffset>4</bitOffset>
              <bitWidth>1</bitWidth>
              <access>read-only</access>
              <enumeratedValues>
                <enumeratedValue>
                  <name>0</name>
                  <description>Passive input filter is disabled on the corresponding pin.</description>
                  <value>#0</value>
                </enumeratedValue>
                <enumeratedValue>
                  <name>1</name>
                  <description>Passive input filter is enabled on the corresponding pin, if the pin is configured as a digital input. Refer to the device data sheet for filter characteristics.</description>
                  <value>#1</value>
                </enumeratedValue>
              </enumeratedValues>
            </field>
            <field>
              <name>DSE</name>
              <description>Drive Strength Enable</description>
              <bitOffset>6</bitOffset>
              <bitWidth>1</bitWidth>
              <access>read-only</access>
              <enumeratedValues>
                <enumeratedValue>
                  <name>0</name>
                  <description>Low drive strength is configured on the corresponding pin, if pin is configured as a digital output.</description>
                  <value>#0</value>
                </enumeratedValue>
                <enumeratedValue>
                  <name>1</name>
                  <description>High drive strength is configured on the corresponding pin, if pin is configured as a digital output.</description>
                  <value>#1</value>
                </enumeratedValue>
              </enumeratedValues>
            </field>
            <field>
              <name>MUX</name>
              <description>Pin Mux Control</description>
              <bitOffset>8</bitOffset>
              <bitWidth>3</bitWidth>
              <access>read-write</access>
              <enumeratedValues>
                <enumeratedValue>
                  <name>000</name>
                  <description>Pin disabled (analog).</description>
                  <value>#000</value>
                </enumeratedValue>
                <enumeratedValue>
                  <name>001</name>
                  <description>Alternative 1 (GPIO).</description>
                  <value>#001</value>
                </enumeratedValue>
                <enumeratedValue>
                  <name>010</name>
                  <description>Alternative 2 (chip-specific).</description>
                  <value>#010</value>
                </enumeratedValue>
                <enumeratedValue>
                  <name>011</name>
                  <description>Alternative 3 (chip-specific).</description>
                  <value>#011</value>
                </enumeratedValue>
                <enumeratedValue>
                  <name>100</name>
                  <description>Alternative 4 (chip-specific).</description>
                  <value>#100</value>
                </enumeratedValue>
                <enumeratedValue>
                  <name>101</name>
                  <description>Alternative 5 (chip-specific).</description>
                  <value>#101</value>
                </enumeratedValue>
                <enumeratedValue>
                  <name>110</name>
                  <description>Alternative 6 (chip-specific).</description>
                  <value>#110</value>
                </enumeratedValue>
                <enumeratedValue>
                  <name>111</name>
                  <description>Alternative 7 (chip-specific).</description>
                  <value>#111</value>
                </enumeratedValue>
              </enumeratedValues>
            </field>
            <field>
              <name>IRQC</name>
              <description>Interrupt Configuration</description>
              <bitOffset>16</bitOffset>
              <bitWidth>4</bitWidth>
              <access>read-write</access>
              <enumeratedValues>
                <enumeratedValue>
                  <name>0000</name>
                  <description>Interrupt/DMA request disabled.</description>
                  <value>#0000</value>
                </enumeratedValue>
                <enumeratedValue>
                  <name>0001</name>
                  <description>DMA request on rising edge.</description>
                  <value>#0001</value>
                </enumeratedValue>
                <enumeratedValue>
                  <name>0010</name>
                  <description>DMA request on falling edge.</description>
                  <value>#0010</value>
                </enumeratedValue>
                <enumeratedValue>
                  <name>0011</name>
                  <description>DMA request on either edge.</description>
                  <value>#0011</value>
                </enumeratedValue>
                <enumeratedValue>
                  <name>1000</name>
                  <description>Interrupt when logic 0.</description>
                  <value>#1000</value>
                </enumeratedValue>
                <enumeratedValue>
                  <name>1001</name>
                  <description>Interrupt on rising-edge.</description>
                  <value>#1001</value>
                </enumeratedValue>
                <enumeratedValue>
                  <name>1010</name>
                  <description>Interrupt on falling-edge.</description>
                  <value>#1010</value>
                </enumeratedValue>
                <enumeratedValue>
                  <name>1011</name>
                  <description>Interrupt on either edge.</description>
                  <value>#1011</value>
                </enumeratedValue>
                <enumeratedValue>
                  <name>1100</name>
                  <description>Interrupt when logic 1.</description>
                  <value>#1100</value>
                </enumeratedValue>
              </enumeratedValues>
            </field>
            <field>
              <name>ISF</name>
              <description>Interrupt Status Flag</description>
              <bitOffset>24</bitOffset>
              <bitWidth>1</bitWidth>
              <access>read-write</access>
              <enumeratedValues>
                <enumeratedValue>
                  <name>0</name>
                  <description>Configured interrupt is not detected.</description>
                  <value>#0</value>
                </enumeratedValue>
                <enumeratedValue>
                  <name>1</name>
                  <description>Configured interrupt is detected. If the pin is configured to generate a DMA request, then the corresponding flag will be cleared automatically at the completion of the requested DMA transfer. Otherwise, the flag remains set until a logic 1 is written to the flag. If the pin is configured for a level sensitive interrupt and the pin remains asserted, then the flag is set again immediately after it is cleared.</description>
                  <value>#1</value>
                </enumeratedValue>
              </enumeratedValues>
            </field>
          </fields>
        </register>
        <register>
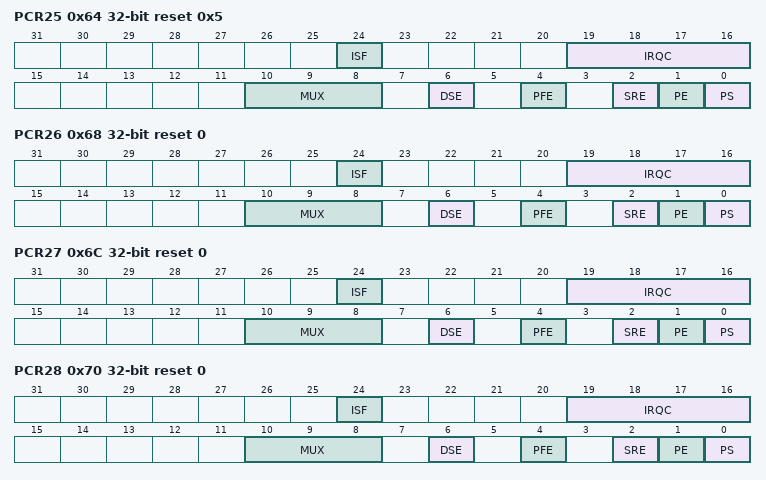
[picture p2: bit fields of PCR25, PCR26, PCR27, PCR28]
          <name>PCR25</name>
          <description>Pin Control Register n</description>
          <addressOffset>0x64</addressOffset>
          <size>32</size>
          <access>read-write</access>
          <resetValue>0x5</resetValue>
          <resetMask>0xFFFFFFFF</resetMask>
          <fields>
            <field>
              <name>PS</name>
              <description>Pull Select</description>
              <bitOffset>0</bitOffset>
              <bitWidth>1</bitWidth>
              <access>read-write</access>
              <enumeratedValues>
                <enumeratedValue>
                  <name>0</name>
                  <description>Internal pulldown resistor is enabled on the corresponding pin, if the corresponding PE field is set.</description>
                  <value>#0</value>
                </enumeratedValue>
                <enumeratedValue>
                  <name>1</name>
                  <description>Internal pullup resistor is enabled on the corresponding pin, if the corresponding PE field is set.</description>
                  <value>#1</value>
                </enumeratedValue>
              </enumeratedValues>
            </field>
            <field>
              <name>PE</name>
              <description>Pull Enable</description>
              <bitOffset>1</bitOffset>
              <bitWidth>1</bitWidth>
              <access>read-write</access>
              <enumeratedValues>
                <enumeratedValue>
                  <name>0</name>
                  <description>Internal pullup or pulldown resistor is not enabled on the corresponding pin.</description>
                  <value>#0</value>
                </enumeratedValue>
                <enumeratedValue>
                  <name>1</name>
                  <description>Internal pullup or pulldown resistor is enabled on the corresponding pin, if the pin is configured as a digital input.</description>
                  <value>#1</value>
                </enumeratedValue>
              </enumeratedValues>
            </field>
            <field>
              <name>SRE</name>
              <description>Slew Rate Enable</description>
              <bitOffset>2</bitOffset>
              <bitWidth>1</bitWidth>
              <access>read-write</access>
              <enumeratedValues>
                <enumeratedValue>
                  <name>0</name>
                  <description>Fast slew rate is configured on the corresponding pin, if the pin is configured as a digital output.</description>
                  <value>#0</value>
                </enumeratedValue>
                <enumeratedValue>
                  <name>1</name>
                  <description>Slow slew rate is configured on the corresponding pin, if the pin is configured as a digital output.</description>
                  <value>#1</value>
                </enumeratedValue>
              </enumeratedValues>
            </field>
            <field>
              <name>PFE</name>
              <description>Passive Filter Enable</description>
              <bitOffset>4</bitOffset>
              <bitWidth>1</bitWidth>
              <access>read-only</access>
              <enumeratedValues>
                <enumeratedValue>
                  <name>0</name>
                  <description>Passive input filter is disabled on the corresponding pin.</description>
                  <value>#0</value>
                </enumeratedValue>
                <enumeratedValue>
                  <name>1</name>
                  <description>Passive input filter is enabled on the corresponding pin, if the pin is configured as a digital input. Refer to the device data sheet for filter characteristics.</description>
                  <value>#1</value>
                </enumeratedValue>
              </enumeratedValues>
            </field>
            <field>
              <name>DSE</name>
              <description>Drive Strength Enable</description>
              <bitOffset>6</bitOffset>
              <bitWidth>1</bitWidth>
              <access>read-only</access>
              <enumeratedValues>
                <enumeratedValue>
                  <name>0</name>
                  <description>Low drive strength is configured on the corresponding pin, if pin is configured as a digital output.</description>
                  <value>#0</value>
                </enumeratedValue>
                <enumeratedValue>
                  <name>1</name>
                  <description>High drive strength is configured on the corresponding pin, if pin is configured as a digital output.</description>
                  <value>#1</value>
                </enumeratedValue>
              </enumeratedValues>
            </field>
            <field>
              <name>MUX</name>
              <description>Pin Mux Control</description>
              <bitOffset>8</bitOffset>
              <bitWidth>3</bitWidth>
              <access>read-write</access>
              <enumeratedValues>
                <enumeratedValue>
                  <name>000</name>
                  <description>Pin disabled (analog).</description>
                  <value>#000</value>
                </enumeratedValue>
                <enumeratedValue>
                  <name>001</name>
                  <description>Alternative 1 (GPIO).</description>
                  <value>#001</value>
                </enumeratedValue>
                <enumeratedValue>
                  <name>010</name>
                  <description>Alternative 2 (chip-specific).</description>
                  <value>#010</value>
                </enumeratedValue>
                <enumeratedValue>
                  <name>011</name>
                  <description>Alternative 3 (chip-specific).</description>
                  <value>#011</value>
                </enumeratedValue>
                <enumeratedValue>
                  <name>100</name>
                  <description>Alternative 4 (chip-specific).</description>
                  <value>#100</value>
                </enumeratedValue>
                <enumeratedValue>
                  <name>101</name>
                  <description>Alternative 5 (chip-specific).</description>
                  <value>#101</value>
                </enumeratedValue>
                <enumeratedValue>
                  <name>110</name>
                  <description>Alternative 6 (chip-specific).</description>
                  <value>#110</value>
                </enumeratedValue>
                <enumeratedValue>
                  <name>111</name>
                  <description>Alternative 7 (chip-specific).</description>
                  <value>#111</value>
                </enumeratedValue>
              </enumeratedValues>
            </field>
            <field>
              <name>IRQC</name>
              <description>Interrupt Configuration</description>
              <bitOffset>16</bitOffset>
              <bitWidth>4</bitWidth>
              <access>read-write</access>
              <enumeratedValues>
                <enumeratedValue>
                  <name>0000</name>
                  <description>Interrupt/DMA request disabled.</description>
                  <value>#0000</value>
                </enumeratedValue>
                <enumeratedValue>
                  <name>0001</name>
                  <description>DMA request on rising edge.</description>
                  <value>#0001</value>
                </enumeratedValue>
                <enumeratedValue>
                  <name>0010</name>
                  <description>DMA request on falling edge.</description>
                  <value>#0010</value>
                </enumeratedValue>
                <enumeratedValue>
                  <name>0011</name>
                  <description>DMA request on either edge.</description>
                  <value>#0011</value>
                </enumeratedValue>
                <enumeratedValue>
                  <name>1000</name>
                  <description>Interrupt when logic 0.</description>
                  <value>#1000</value>
                </enumeratedValue>
                <enumeratedValue>
                  <name>1001</name>
                  <description>Interrupt on rising-edge.</description>
                  <value>#1001</value>
                </enumeratedValue>
                <enumeratedValue>
                  <name>1010</name>
                  <description>Interrupt on falling-edge.</description>
                  <value>#1010</value>
                </enumeratedValue>
                <enumeratedValue>
                  <name>1011</name>
                  <description>Interrupt on either edge.</description>
                  <value>#1011</value>
                </enumeratedValue>
                <enumeratedValue>
                  <name>1100</name>
                  <description>Interrupt when logic 1.</description>
                  <value>#1100</value>
                </enumeratedValue>
              </enumeratedValues>
            </field>
            <field>
              <name>ISF</name>
              <description>Interrupt Status Flag</description>
              <bitOffset>24</bitOffset>
              <bitWidth>1</bitWidth>
              <access>read-write</access>
              <enumeratedValues>
                <enumeratedValue>
                  <name>0</name>
                  <description>Configured interrupt is not detected.</description>
                  <value>#0</value>
                </enumeratedValue>
                <enumeratedValue>
                  <name>1</name>
                  <description>Configured interrupt is detected. If the pin is configured to generate a DMA request, then the corresponding flag will be cleared automatically at the completion of the requested DMA transfer. Otherwise, the flag remains set until a logic 1 is written to the flag. If the pin is configured for a level sensitive interrupt and the pin remains asserted, then the flag is set again immediately after it is cleared.</description>
                  <value>#1</value>
                </enumeratedValue>
              </enumeratedValues>
            </field>
          </fields>
        </register>
        <register>
          <name>PCR26</name>
          <description>Pin Control Register n</description>
          <addressOffset>0x68</addressOffset>
          <size>32</size>
          <access>read-write</access>
          <resetValue>0</resetValue>
          <resetMask>0xFFFFFFFF</resetMask>
          <fields>
            <field>
              <name>PS</name>
              <description>Pull Select</description>
              <bitOffset>0</bitOffset>
              <bitWidth>1</bitWidth>
              <access>read-only</access>
              <enumeratedValues>
                <enumeratedValue>
                  <name>0</name>
                  <description>Internal pulldown resistor is enabled on the corresponding pin, if the corresponding PE field is set.</description>
                  <value>#0</value>
                </enumeratedValue>
                <enumeratedValue>
                  <name>1</name>
                  <description>Internal pullup resistor is enabled on the corresponding pin, if the corresponding PE field is set.</description>
                  <value>#1</value>
                </enumeratedValue>
              </enumeratedValues>
            </field>
            <field>
              <name>PE</name>
              <description>Pull Enable</description>
              <bitOffset>1</bitOffset>
              <bitWidth>1</bitWidth>
              <access>read-only</access>
              <enumeratedValues>
                <enumeratedValue>
                  <name>0</name>
                  <description>Internal pullup or pulldown resistor is not enabled on the corresponding pin.</description>
                  <value>#0</value>
                </enumeratedValue>
                <enumeratedValue>
                  <name>1</name>
                  <description>Internal pullup or pulldown resistor is enabled on the corresponding pin, if the pin is configured as a digital input.</description>
                  <value>#1</value>
                </enumeratedValue>
              </enumeratedValues>
            </field>
            <field>
              <name>SRE</name>
              <description>Slew Rate Enable</description>
              <bitOffset>2</bitOffset>
              <bitWidth>1</bitWidth>
              <access>read-only</access>
              <enumeratedValues>
                <enumeratedValue>
                  <name>0</name>
                  <description>Fast slew rate is configured on the corresponding pin, if the pin is configured as a digital output.</description>
                  <value>#0</value>
                </enumeratedValue>
                <enumeratedValue>
                  <name>1</name>
                  <description>Slow slew rate is configured on the corresponding pin, if the pin is configured as a digital output.</description>
                  <value>#1</value>
                </enumeratedValue>
              </enumeratedValues>
            </field>
            <field>
              <name>PFE</name>
              <description>Passive Filter Enable</description>
              <bitOffset>4</bitOffset>
              <bitWidth>1</bitWidth>
              <access>read-only</access>
              <enumeratedValues>
                <enumeratedValue>
                  <name>0</name>
                  <description>Passive input filter is disabled on the corresponding pin.</description>
                  <value>#0</value>
                </enumeratedValue>
                <enumeratedValue>
                  <name>1</name>
                  <description>Passive input filter is enabled on the corresponding pin, if the pin is configured as a digital input. Refer to the device data sheet for filter characteristics.</description>
                  <value>#1</value>
                </enumeratedValue>
              </enumeratedValues>
            </field>
            <field>
              <name>DSE</name>
              <description>Drive Strength Enable</description>
              <bitOffset>6</bitOffset>
              <bitWidth>1</bitWidth>
              <access>read-only</access>
              <enumeratedValues>
                <enumeratedValue>
                  <name>0</name>
                  <description>Low drive strength is configured on the corresponding pin, if pin is configured as a digital output.</description>
                  <value>#0</value>
                </enumeratedValue>
                <enumeratedValue>
                  <name>1</name>
                  <description>High drive strength is configured on the corresponding pin, if pin is configured as a digital output.</description>
                  <value>#1</value>
                </enumeratedValue>
              </enumeratedValues>
            </field>
            <field>
              <name>MUX</name>
              <description>Pin Mux Control</description>
              <bitOffset>8</bitOffset>
              <bitWidth>3</bitWidth>
              <access>read-write</access>
              <enumeratedValues>
                <enumeratedValue>
                  <name>000</name>
                  <description>Pin disabled (analog).</description>
                  <value>#000</value>
                </enumeratedValue>
                <enumeratedValue>
                  <name>001</name>
                  <description>Alternative 1 (GPIO).</description>
                  <value>#001</value>
                </enumeratedValue>
                <enumeratedValue>
                  <name>010</name>
                  <description>Alternative 2 (chip-specific).</description>
                  <value>#010</value>
                </enumeratedValue>
                <enumeratedValue>
                  <name>011</name>
                  <description>Alternative 3 (chip-specific).</description>
                  <value>#011</value>
                </enumeratedValue>
                <enumeratedValue>
                  <name>100</name>
                  <description>Alternative 4 (chip-specific).</description>
                  <value>#100</value>
                </enumeratedValue>
                <enumeratedValue>
                  <name>101</name>
                  <description>Alternative 5 (chip-specific).</description>
                  <value>#101</value>
                </enumeratedValue>
                <enumeratedValue>
                  <name>110</name>
                  <description>Alternative 6 (chip-specific).</description>
                  <value>#110</value>
                </enumeratedValue>
                <enumeratedValue>
                  <name>111</name>
                  <description>Alternative 7 (chip-specific).</description>
                  <value>#111</value>
                </enumeratedValue>
              </enumeratedValues>
            </field>
            <field>
              <name>IRQC</name>
              <description>Interrupt Configuration</description>
              <bitOffset>16</bitOffset>
              <bitWidth>4</bitWidth>
              <access>read-write</access>
              <enumeratedValues>
                <enumeratedValue>
                  <name>0000</name>
                  <description>Interrupt/DMA request disabled.</description>
                  <value>#0000</value>
                </enumeratedValue>
                <enumeratedValue>
                  <name>0001</name>
                  <description>DMA request on rising edge.</description>
                  <value>#0001</value>
                </enumeratedValue>
                <enumeratedValue>
                  <name>0010</name>
                  <description>DMA request on falling edge.</description>
                  <value>#0010</value>
                </enumeratedValue>
                <enumeratedValue>
                  <name>0011</name>
                  <description>DMA request on either edge.</description>
                  <value>#0011</value>
                </enumeratedValue>
                <enumeratedValue>
                  <name>1000</name>
                  <description>Interrupt when logic 0.</description>
                  <value>#1000</value>
                </enumeratedValue>
                <enumeratedValue>
                  <name>1001</name>
                  <description>Interrupt on rising-edge.</description>
                  <value>#1001</value>
                </enumeratedValue>
                <enumeratedValue>
                  <name>1010</name>
                  <description>Interrupt on falling-edge.</description>
                  <value>#1010</value>
                </enumeratedValue>
                <enumeratedValue>
                  <name>1011</name>
                  <description>Interrupt on either edge.</description>
                  <value>#1011</value>
                </enumeratedValue>
                <enumeratedValue>
                  <name>1100</name>
                  <description>Interrupt when logic 1.</description>
                  <value>#1100</value>
                </enumeratedValue>
              </enumeratedValues>
            </field>
            <field>
              <name>ISF</name>
              <description>Interrupt Status Flag</description>
              <bitOffset>24</bitOffset>
              <bitWidth>1</bitWidth>
              <access>read-write</access>
              <enumeratedValues>
                <enumeratedValue>
                  <name>0</name>
                  <description>Configured interrupt is not detected.</description>
                  <value>#0</value>
                </enumeratedValue>
                <enumeratedValue>
                  <name>1</name>
                  <description>Configured interrupt is detected. If the pin is configured to generate a DMA request, then the corresponding flag will be cleared automatically at the completion of the requested DMA transfer. Otherwise, the flag remains set until a logic 1 is written to the flag. If the pin is configured for a level sensitive interrupt and the pin remains asserted, then the flag is set again immediately after it is cleared.</description>
                  <value>#1</value>
                </enumeratedValue>
              </enumeratedValues>
            </field>
          </fields>
        </register>
        <register>
          <name>PCR27</name>
          <description>Pin Control Register n</description>
          <addressOffset>0x6C</addressOffset>
          <size>32</size>
          <access>read-write</access>
          <resetValue>0</resetValue>
          <resetMask>0xFFFFFFFF</resetMask>
          <fields>
            <field>
              <name>PS</name>
              <description>Pull Select</description>
              <bitOffset>0</bitOffset>
              <bitWidth>1</bitWidth>
              <access>read-only</access>
              <enumeratedValues>
                <enumeratedValue>
                  <name>0</name>
                  <description>Internal pulldown resistor is enabled on the corresponding pin, if the corresponding PE field is set.</description>
                  <value>#0</value>
                </enumeratedValue>
                <enumeratedValue>
                  <name>1</name>
                  <description>Internal pullup resistor is enabled on the corresponding pin, if the corresponding PE field is set.</description>
                  <value>#1</value>
                </enumeratedValue>
              </enumeratedValues>
            </field>
            <field>
              <name>PE</name>
              <description>Pull Enable</description>
              <bitOffset>1</bitOffset>
              <bitWidth>1</bitWidth>
              <access>read-only</access>
              <enumeratedValues>
                <enumeratedValue>
                  <name>0</name>
                  <description>Internal pullup or pulldown resistor is not enabled on the corresponding pin.</description>
                  <value>#0</value>
                </enumeratedValue>
                <enumeratedValue>
                  <name>1</name>
                  <description>Internal pullup or pulldown resistor is enabled on the corresponding pin, if the pin is configured as a digital input.</description>
                  <value>#1</value>
                </enumeratedValue>
              </enumeratedValues>
            </field>
            <field>
              <name>SRE</name>
              <description>Slew Rate Enable</description>
              <bitOffset>2</bitOffset>
              <bitWidth>1</bitWidth>
              <access>read-only</access>
              <enumeratedValues>
                <enumeratedValue>
                  <name>0</name>
                  <description>Fast slew rate is configured on the corresponding pin, if the pin is configured as a digital output.</description>
                  <value>#0</value>
                </enumeratedValue>
                <enumeratedValue>
                  <name>1</name>
                  <description>Slow slew rate is configured on the corresponding pin, if the pin is configured as a digital output.</description>
                  <value>#1</value>
                </enumeratedValue>
              </enumeratedValues>
            </field>
            <field>
              <name>PFE</name>
              <description>Passive Filter Enable</description>
              <bitOffset>4</bitOffset>
              <bitWidth>1</bitWidth>
              <access>read-only</access>
              <enumeratedValues>
                <enumeratedValue>
                  <name>0</name>
                  <description>Passive input filter is disabled on the corresponding pin.</description>
                  <value>#0</value>
                </enumeratedValue>
                <enumeratedValue>
                  <name>1</name>
                  <description>Passive input filter is enabled on the corresponding pin, if the pin is configured as a digital input. Refer to the device data sheet for filter characteristics.</description>
                  <value>#1</value>
                </enumeratedValue>
              </enumeratedValues>
            </field>
            <field>
              <name>DSE</name>
              <description>Drive Strength Enable</description>
              <bitOffset>6</bitOffset>
              <bitWidth>1</bitWidth>
              <access>read-only</access>
              <enumeratedValues>
                <enumeratedValue>
                  <name>0</name>
                  <description>Low drive strength is configured on the corresponding pin, if pin is configured as a digital output.</description>
                  <value>#0</value>
                </enumeratedValue>
                <enumeratedValue>
                  <name>1</name>
                  <description>High drive strength is configured on the corresponding pin, if pin is configured as a digital output.</description>
                  <value>#1</value>
                </enumeratedValue>
              </enumeratedValues>
            </field>
            <field>
              <name>MUX</name>
              <description>Pin Mux Control</description>
              <bitOffset>8</bitOffset>
              <bitWidth>3</bitWidth>
              <access>read-write</access>
              <enumeratedValues>
                <enumeratedValue>
                  <name>000</name>
                  <description>Pin disabled (analog).</description>
                  <value>#000</value>
                </enumeratedValue>
                <enumeratedValue>
                  <name>001</name>
                  <description>Alternative 1 (GPIO).</description>
                  <value>#001</value>
                </enumeratedValue>
                <enumeratedValue>
                  <name>010</name>
                  <description>Alternative 2 (chip-specific).</description>
                  <value>#010</value>
                </enumeratedValue>
                <enumeratedValue>
                  <name>011</name>
                  <description>Alternative 3 (chip-specific).</description>
                  <value>#011</value>
                </enumeratedValue>
                <enumeratedValue>
                  <name>100</name>
                  <description>Alternative 4 (chip-specific).</description>
                  <value>#100</value>
                </enumeratedValue>
                <enumeratedValue>
                  <name>101</name>
                  <description>Alternative 5 (chip-specific).</description>
                  <value>#101</value>
                </enumeratedValue>
                <enumeratedValue>
                  <name>110</name>
                  <description>Alternative 6 (chip-specific).</description>
                  <value>#110</value>
                </enumeratedValue>
                <enumeratedValue>
                  <name>111</name>
                  <description>Alternative 7 (chip-specific).</description>
                  <value>#111</value>
                </enumeratedValue>
              </enumeratedValues>
            </field>
            <field>
              <name>IRQC</name>
              <description>Interrupt Configuration</description>
              <bitOffset>16</bitOffset>
              <bitWidth>4</bitWidth>
              <access>read-write</access>
              <enumeratedValues>
                <enumeratedValue>
                  <name>0000</name>
                  <description>Interrupt/DMA request disabled.</description>
                  <value>#0000</value>
                </enumeratedValue>
                <enumeratedValue>
                  <name>0001</name>
                  <description>DMA request on rising edge.</description>
                  <value>#0001</value>
                </enumeratedValue>
                <enumeratedValue>
                  <name>0010</name>
                  <description>DMA request on falling edge.</description>
                  <value>#0010</value>
                </enumeratedValue>
                <enumeratedValue>
                  <name>0011</name>
                  <description>DMA request on either edge.</description>
                  <value>#0011</value>
                </enumeratedValue>
                <enumeratedValue>
                  <name>1000</name>
                  <description>Interrupt when logic 0.</description>
                  <value>#1000</value>
                </enumeratedValue>
                <enumeratedValue>
                  <name>1001</name>
                  <description>Interrupt on rising-edge.</description>
                  <value>#1001</value>
                </enumeratedValue>
                <enumeratedValue>
                  <name>1010</name>
                  <description>Interrupt on falling-edge.</description>
                  <value>#1010</value>
                </enumeratedValue>
                <enumeratedValue>
                  <name>1011</name>
                  <description>Interrupt on either edge.</description>
                  <value>#1011</value>
                </enumeratedValue>
                <enumeratedValue>
                  <name>1100</name>
                  <description>Interrupt when logic 1.</description>
                  <value>#1100</value>
                </enumeratedValue>
              </enumeratedValues>
            </field>
            <field>
              <name>ISF</name>
              <description>Interrupt Status Flag</description>
              <bitOffset>24</bitOffset>
              <bitWidth>1</bitWidth>
              <access>read-write</access>
              <enumeratedValues>
                <enumeratedValue>
                  <name>0</name>
                  <description>Configured interrupt is not detected.</description>
                  <value>#0</value>
                </enumeratedValue>
                <enumeratedValue>
                  <name>1</name>
                  <description>Configured interrupt is detected. If the pin is configured to generate a DMA request, then the corresponding flag will be cleared automatically at the completion of the requested DMA transfer. Otherwise, the flag remains set until a logic 1 is written to the flag. If the pin is configured for a level sensitive interrupt and the pin remains asserted, then the flag is set again immediately after it is cleared.</description>
                  <value>#1</value>
                </enumeratedValue>
              </enumeratedValues>
            </field>
          </fields>
        </register>
        <register>
          <name>PCR28</name>
          <description>Pin Control Register n</description>
          <addressOffset>0x70</addressOffset>
          <size>32</size>
          <access>read-write</access>
          <resetValue>0</resetValue>
          <resetMask>0xFFFFFFFF</resetMask>
          <fields>
            <field>
              <name>PS</name>
              <description>Pull Select</description>
              <bitOffset>0</bitOffset>
              <bitWidth>1</bitWidth>
              <access>read-only</access>
              <enumeratedValues>
                <enumeratedValue>
                  <name>0</name>
                  <description>Internal pulldown resistor is enabled on the corresponding pin, if the corresponding PE field is set.</description>
                  <value>#0</value>
                </enumeratedValue>
                <enumeratedValue>
                  <name>1</name>
                  <description>Internal pullup resistor is enabled on the corresponding pin, if the corresponding PE field is set.</description>
                  <value>#1</value>
                </enumeratedValue>
              </enumeratedValues>
            </field>
            <field>
              <name>PE</name>
              <description>Pull Enable</description>
              <bitOffset>1</bitOffset>
              <bitWidth>1</bitWidth>
              <access>read-only</access>
              <enumeratedValues>
                <enumeratedValue>
                  <name>0</name>
                  <description>Internal pullup or pulldown resistor is not enabled on the corresponding pin.</description>
                  <value>#0</value>
                </enumeratedValue>
                <enumeratedValue>
                  <name>1</name>
                  <description>Internal pullup or pulldown resistor is enabled on the corresponding pin, if the pin is configured as a digital input.</description>
                  <value>#1</value>
                </enumeratedValue>
              </enumeratedValues>
            </field>
            <field>
              <name>SRE</name>
              <description>Slew Rate Enable</description>
              <bitOffset>2</bitOffset>
              <bitWidth>1</bitWidth>
              <access>read-only</access>
              <enumeratedValues>
                <enumeratedValue>
                  <name>0</name>
                  <description>Fast slew rate is configured on the corresponding pin, if the pin is configured as a digital output.</description>
                  <value>#0</value>
                </enumeratedValue>
                <enumeratedValue>
                  <name>1</name>
                  <description>Slow slew rate is configured on the corresponding pin, if the pin is configured as a digital output.</description>
                  <value>#1</value>
                </enumeratedValue>
              </enumeratedValues>
            </field>
            <field>
              <name>PFE</name>
              <description>Passive Filter Enable</description>
              <bitOffset>4</bitOffset>
              <bitWidth>1</bitWidth>
              <access>read-only</access>
              <enumeratedValues>
                <enumeratedValue>
                  <name>0</name>
                  <description>Passive input filter is disabled on the corresponding pin.</description>
                  <value>#0</value>
                </enumeratedValue>
                <enumeratedValue>
                  <name>1</name>
                  <description>Passive input filter is enabled on the corresponding pin, if the pin is configured as a digital input. Refer to the device data sheet for filter characteristics.</description>
                  <value>#1</value>
                </enumeratedValue>
              </enumeratedValues>
            </field>
            <field>
              <name>DSE</name>
              <description>Drive Strength Enable</description>
              <bitOffset>6</bitOffset>
              <bitWidth>1</bitWidth>
              <access>read-only</access>
              <enumeratedValues>
                <enumeratedValue>
                  <name>0</name>
                  <description>Low drive strength is configured on the corresponding pin, if pin is configured as a digital output.</description>
                  <value>#0</value>
                </enumeratedValue>
                <enumeratedValue>
                  <name>1</name>
                  <description>High drive strength is configured on the corresponding pin, if pin is configured as a digital output.</description>
                  <value>#1</value>
                </enumeratedValue>
              </enumeratedValues>
            </field>
            <field>
              <name>MUX</name>
              <description>Pin Mux Control</description>
              <bitOffset>8</bitOffset>
              <bitWidth>3</bitWidth>
              <access>read-write</access>
              <enumeratedValues>
                <enumeratedValue>
                  <name>000</name>
                  <description>Pin disabled (analog).</description>
                  <value>#000</value>
                </enumeratedValue>
                <enumeratedValue>
                  <name>001</name>
                  <description>Alternative 1 (GPIO).</description>
                  <value>#001</value>
                </enumeratedValue>
                <enumeratedValue>
                  <name>010</name>
                  <description>Alternative 2 (chip-specific).</description>
                  <value>#010</value>
                </enumeratedValue>
                <enumeratedValue>
                  <name>011</name>
                  <description>Alternative 3 (chip-specific).</description>
                  <value>#011</value>
                </enumeratedValue>
                <enumeratedValue>
                  <name>100</name>
                  <description>Alternative 4 (chip-specific).</description>
                  <value>#100</value>
                </enumeratedValue>
                <enumeratedValue>
                  <name>101</name>
                  <description>Alternative 5 (chip-specific).</description>
                  <value>#101</value>
                </enumeratedValue>
                <enumeratedValue>
                  <name>110</name>
                  <description>Alternative 6 (chip-specific).</description>
                  <value>#110</value>
                </enumeratedValue>
                <enumeratedValue>
                  <name>111</name>
                  <description>Alternative 7 (chip-specific).</description>
                  <value>#111</value>
                </enumeratedValue>
              </enumeratedValues>
            </field>
            <field>
              <name>IRQC</name>
              <description>Interrupt Configuration</description>
              <bitOffset>16</bitOffset>
              <bitWidth>4</bitWidth>
              <access>read-write</access>
              <enumeratedValues>
                <enumeratedValue>
                  <name>0000</name>
                  <description>Interrupt/DMA request disabled.</description>
                  <value>#0000</value>
                </enumeratedValue>
                <enumeratedValue>
                  <name>0001</name>
                  <description>DMA request on rising edge.</description>
                  <value>#0001</value>
                </enumeratedValue>
                <enumeratedValue>
                  <name>0010</name>
                  <description>DMA request on falling edge.</description>
                  <value>#0010</value>
                </enumeratedValue>
                <enumeratedValue>
                  <name>0011</name>
                  <description>DMA request on either edge.</description>
                  <value>#0011</value>
                </enumeratedValue>
                <enumeratedValue>
                  <name>1000</name>
                  <description>Interrupt when logic 0.</description>
                  <value>#1000</value>
                </enumeratedValue>
                <enumeratedValue>
                  <name>1001</name>
                  <description>Interrupt on rising-edge.</description>
                  <value>#1001</value>
                </enumeratedValue>
                <enumeratedValue>
                  <name>1010</name>
                  <description>Interrupt on falling-edge.</description>
                  <value>#1010</value>
                </enumeratedValue>
                <enumeratedValue>
                  <name>1011</name>
                  <description>Interrupt on either edge.</description>
                  <value>#1011</value>
                </enumeratedValue>
                <enumeratedValue>
                  <name>1100</name>
                  <description>Interrupt when logic 1.</description>
                  <value>#1100</value>
                </enumeratedValue>
              </enumeratedValues>
            </field>
            <field>
              <name>ISF</name>
              <description>Interrupt Status Flag</description>
              <bitOffset>24</bitOffset>
              <bitWidth>1</bitWidth>
              <access>read-write</access>
              <enumeratedValues>
                <enumeratedValue>
                  <name>0</name>
                  <description>Configured interrupt is not detected.</description>
                  <value>#0</value>
                </enumeratedValue>
                <enumeratedValue>
                  <name>1</name>
                  <description>Configured interrupt is detected. If the pin is configured to generate a DMA request, then the corresponding flag will be cleared automatically at the completion of the requested DMA transfer. Otherwise, the flag remains set until a logic 1 is written to the flag. If the pin is configured for a level sensitive interrupt and the pin remains asserted, then the flag is set again immediately after it is cleared.</description>
                  <value>#1</value>
                </enumeratedValue>
              </enumeratedValues>
            </field>
          </fields>
        </register>
        <register>
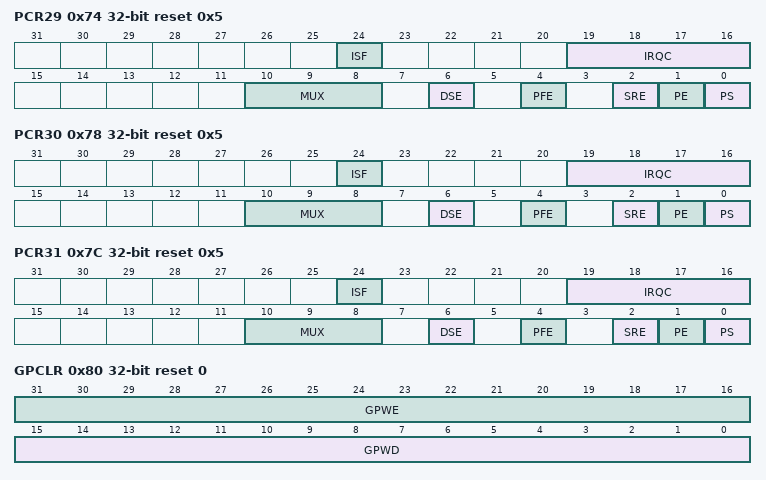
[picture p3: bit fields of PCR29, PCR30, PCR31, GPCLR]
          <name>PCR29</name>
          <description>Pin Control Register n</description>
          <addressOffset>0x74</addressOffset>
          <size>32</size>
          <access>read-write</access>
          <resetValue>0x5</resetValue>
          <resetMask>0xFFFFFFFF</resetMask>
          <fields>
            <field>
              <name>PS</name>
              <description>Pull Select</description>
              <bitOffset>0</bitOffset>
              <bitWidth>1</bitWidth>
              <access>read-write</access>
              <enumeratedValues>
                <enumeratedValue>
                  <name>0</name>
                  <description>Internal pulldown resistor is enabled on the corresponding pin, if the corresponding PE field is set.</description>
                  <value>#0</value>
                </enumeratedValue>
                <enumeratedValue>
                  <name>1</name>
                  <description>Internal pullup resistor is enabled on the corresponding pin, if the corresponding PE field is set.</description>
                  <value>#1</value>
                </enumeratedValue>
              </enumeratedValues>
            </field>
            <field>
              <name>PE</name>
              <description>Pull Enable</description>
              <bitOffset>1</bitOffset>
              <bitWidth>1</bitWidth>
              <access>read-write</access>
              <enumeratedValues>
                <enumeratedValue>
                  <name>0</name>
                  <description>Internal pullup or pulldown resistor is not enabled on the corresponding pin.</description>
                  <value>#0</value>
                </enumeratedValue>
                <enumeratedValue>
                  <name>1</name>
                  <description>Internal pullup or pulldown resistor is enabled on the corresponding pin, if the pin is configured as a digital input.</description>
                  <value>#1</value>
                </enumeratedValue>
              </enumeratedValues>
            </field>
            <field>
              <name>SRE</name>
              <description>Slew Rate Enable</description>
              <bitOffset>2</bitOffset>
              <bitWidth>1</bitWidth>
              <access>read-write</access>
              <enumeratedValues>
                <enumeratedValue>
                  <name>0</name>
                  <description>Fast slew rate is configured on the corresponding pin, if the pin is configured as a digital output.</description>
                  <value>#0</value>
                </enumeratedValue>
                <enumeratedValue>
                  <name>1</name>
                  <description>Slow slew rate is configured on the corresponding pin, if the pin is configured as a digital output.</description>
                  <value>#1</value>
                </enumeratedValue>
              </enumeratedValues>
            </field>
            <field>
              <name>PFE</name>
              <description>Passive Filter Enable</description>
              <bitOffset>4</bitOffset>
              <bitWidth>1</bitWidth>
              <access>read-only</access>
              <enumeratedValues>
                <enumeratedValue>
                  <name>0</name>
                  <description>Passive input filter is disabled on the corresponding pin.</description>
                  <value>#0</value>
                </enumeratedValue>
                <enumeratedValue>
                  <name>1</name>
                  <description>Passive input filter is enabled on the corresponding pin, if the pin is configured as a digital input. Refer to the device data sheet for filter characteristics.</description>
                  <value>#1</value>
                </enumeratedValue>
              </enumeratedValues>
            </field>
            <field>
              <name>DSE</name>
              <description>Drive Strength Enable</description>
              <bitOffset>6</bitOffset>
              <bitWidth>1</bitWidth>
              <access>read-only</access>
              <enumeratedValues>
                <enumeratedValue>
                  <name>0</name>
                  <description>Low drive strength is configured on the corresponding pin, if pin is configured as a digital output.</description>
                  <value>#0</value>
                </enumeratedValue>
                <enumeratedValue>
                  <name>1</name>
                  <description>High drive strength is configured on the corresponding pin, if pin is configured as a digital output.</description>
                  <value>#1</value>
                </enumeratedValue>
              </enumeratedValues>
            </field>
            <field>
              <name>MUX</name>
              <description>Pin Mux Control</description>
              <bitOffset>8</bitOffset>
              <bitWidth>3</bitWidth>
              <access>read-write</access>
              <enumeratedValues>
                <enumeratedValue>
                  <name>000</name>
                  <description>Pin disabled (analog).</description>
                  <value>#000</value>
                </enumeratedValue>
                <enumeratedValue>
                  <name>001</name>
                  <description>Alternative 1 (GPIO).</description>
                  <value>#001</value>
                </enumeratedValue>
                <enumeratedValue>
                  <name>010</name>
                  <description>Alternative 2 (chip-specific).</description>
                  <value>#010</value>
                </enumeratedValue>
                <enumeratedValue>
                  <name>011</name>
                  <description>Alternative 3 (chip-specific).</description>
                  <value>#011</value>
                </enumeratedValue>
                <enumeratedValue>
                  <name>100</name>
                  <description>Alternative 4 (chip-specific).</description>
                  <value>#100</value>
                </enumeratedValue>
                <enumeratedValue>
                  <name>101</name>
                  <description>Alternative 5 (chip-specific).</description>
                  <value>#101</value>
                </enumeratedValue>
                <enumeratedValue>
                  <name>110</name>
                  <description>Alternative 6 (chip-specific).</description>
                  <value>#110</value>
                </enumeratedValue>
                <enumeratedValue>
                  <name>111</name>
                  <description>Alternative 7 (chip-specific).</description>
                  <value>#111</value>
                </enumeratedValue>
              </enumeratedValues>
            </field>
            <field>
              <name>IRQC</name>
              <description>Interrupt Configuration</description>
              <bitOffset>16</bitOffset>
              <bitWidth>4</bitWidth>
              <access>read-write</access>
              <enumeratedValues>
                <enumeratedValue>
                  <name>0000</name>
                  <description>Interrupt/DMA request disabled.</description>
                  <value>#0000</value>
                </enumeratedValue>
                <enumeratedValue>
                  <name>0001</name>
                  <description>DMA request on rising edge.</description>
                  <value>#0001</value>
                </enumeratedValue>
                <enumeratedValue>
                  <name>0010</name>
                  <description>DMA request on falling edge.</description>
                  <value>#0010</value>
                </enumeratedValue>
                <enumeratedValue>
                  <name>0011</name>
                  <description>DMA request on either edge.</description>
                  <value>#0011</value>
                </enumeratedValue>
                <enumeratedValue>
                  <name>1000</name>
                  <description>Interrupt when logic 0.</description>
                  <value>#1000</value>
                </enumeratedValue>
                <enumeratedValue>
                  <name>1001</name>
                  <description>Interrupt on rising-edge.</description>
                  <value>#1001</value>
                </enumeratedValue>
                <enumeratedValue>
                  <name>1010</name>
                  <description>Interrupt on falling-edge.</description>
                  <value>#1010</value>
                </enumeratedValue>
                <enumeratedValue>
                  <name>1011</name>
                  <description>Interrupt on either edge.</description>
                  <value>#1011</value>
                </enumeratedValue>
                <enumeratedValue>
                  <name>1100</name>
                  <description>Interrupt when logic 1.</description>
                  <value>#1100</value>
                </enumeratedValue>
              </enumeratedValues>
            </field>
            <field>
              <name>ISF</name>
              <description>Interrupt Status Flag</description>
              <bitOffset>24</bitOffset>
              <bitWidth>1</bitWidth>
              <access>read-write</access>
              <enumeratedValues>
                <enumeratedValue>
                  <name>0</name>
                  <description>Configured interrupt is not detected.</description>
                  <value>#0</value>
                </enumeratedValue>
                <enumeratedValue>
                  <name>1</name>
                  <description>Configured interrupt is detected. If the pin is configured to generate a DMA request, then the corresponding flag will be cleared automatically at the completion of the requested DMA transfer. Otherwise, the flag remains set until a logic 1 is written to the flag. If the pin is configured for a level sensitive interrupt and the pin remains asserted, then the flag is set again immediately after it is cleared.</description>
                  <value>#1</value>
                </enumeratedValue>
              </enumeratedValues>
            </field>
          </fields>
        </register>
        <register>
          <name>PCR30</name>
          <description>Pin Control Register n</description>
          <addressOffset>0x78</addressOffset>
          <size>32</size>
          <access>read-write</access>
          <resetValue>0x5</resetValue>
          <resetMask>0xFFFFFFFF</resetMask>
          <fields>
            <field>
              <name>PS</name>
              <description>Pull Select</description>
              <bitOffset>0</bitOffset>
              <bitWidth>1</bitWidth>
              <access>read-write</access>
              <enumeratedValues>
                <enumeratedValue>
                  <name>0</name>
                  <description>Internal pulldown resistor is enabled on the corresponding pin, if the corresponding PE field is set.</description>
                  <value>#0</value>
                </enumeratedValue>
                <enumeratedValue>
                  <name>1</name>
                  <description>Internal pullup resistor is enabled on the corresponding pin, if the corresponding PE field is set.</description>
                  <value>#1</value>
                </enumeratedValue>
              </enumeratedValues>
            </field>
            <field>
              <name>PE</name>
              <description>Pull Enable</description>
              <bitOffset>1</bitOffset>
              <bitWidth>1</bitWidth>
              <access>read-write</access>
              <enumeratedValues>
                <enumeratedValue>
                  <name>0</name>
                  <description>Internal pullup or pulldown resistor is not enabled on the corresponding pin.</description>
                  <value>#0</value>
                </enumeratedValue>
                <enumeratedValue>
                  <name>1</name>
                  <description>Internal pullup or pulldown resistor is enabled on the corresponding pin, if the pin is configured as a digital input.</description>
                  <value>#1</value>
                </enumeratedValue>
              </enumeratedValues>
            </field>
            <field>
              <name>SRE</name>
              <description>Slew Rate Enable</description>
              <bitOffset>2</bitOffset>
              <bitWidth>1</bitWidth>
              <access>read-write</access>
              <enumeratedValues>
                <enumeratedValue>
                  <name>0</name>
                  <description>Fast slew rate is configured on the corresponding pin, if the pin is configured as a digital output.</description>
                  <value>#0</value>
                </enumeratedValue>
                <enumeratedValue>
                  <name>1</name>
                  <description>Slow slew rate is configured on the corresponding pin, if the pin is configured as a digital output.</description>
                  <value>#1</value>
                </enumeratedValue>
              </enumeratedValues>
            </field>
            <field>
              <name>PFE</name>
              <description>Passive Filter Enable</description>
              <bitOffset>4</bitOffset>
              <bitWidth>1</bitWidth>
              <access>read-only</access>
              <enumeratedValues>
                <enumeratedValue>
                  <name>0</name>
                  <description>Passive input filter is disabled on the corresponding pin.</description>
                  <value>#0</value>
                </enumeratedValue>
                <enumeratedValue>
                  <name>1</name>
                  <description>Passive input filter is enabled on the corresponding pin, if the pin is configured as a digital input. Refer to the device data sheet for filter characteristics.</description>
                  <value>#1</value>
                </enumeratedValue>
              </enumeratedValues>
            </field>
            <field>
              <name>DSE</name>
              <description>Drive Strength Enable</description>
              <bitOffset>6</bitOffset>
              <bitWidth>1</bitWidth>
              <access>read-only</access>
              <enumeratedValues>
                <enumeratedValue>
                  <name>0</name>
                  <description>Low drive strength is configured on the corresponding pin, if pin is configured as a digital output.</description>
                  <value>#0</value>
                </enumeratedValue>
                <enumeratedValue>
                  <name>1</name>
                  <description>High drive strength is configured on the corresponding pin, if pin is configured as a digital output.</description>
                  <value>#1</value>
                </enumeratedValue>
              </enumeratedValues>
            </field>
            <field>
              <name>MUX</name>
              <description>Pin Mux Control</description>
              <bitOffset>8</bitOffset>
              <bitWidth>3</bitWidth>
              <access>read-write</access>
              <enumeratedValues>
                <enumeratedValue>
                  <name>000</name>
                  <description>Pin disabled (analog).</description>
                  <value>#000</value>
                </enumeratedValue>
                <enumeratedValue>
                  <name>001</name>
                  <description>Alternative 1 (GPIO).</description>
                  <value>#001</value>
                </enumeratedValue>
                <enumeratedValue>
                  <name>010</name>
                  <description>Alternative 2 (chip-specific).</description>
                  <value>#010</value>
                </enumeratedValue>
                <enumeratedValue>
                  <name>011</name>
                  <description>Alternative 3 (chip-specific).</description>
                  <value>#011</value>
                </enumeratedValue>
                <enumeratedValue>
                  <name>100</name>
                  <description>Alternative 4 (chip-specific).</description>
                  <value>#100</value>
                </enumeratedValue>
                <enumeratedValue>
                  <name>101</name>
                  <description>Alternative 5 (chip-specific).</description>
                  <value>#101</value>
                </enumeratedValue>
                <enumeratedValue>
                  <name>110</name>
                  <description>Alternative 6 (chip-specific).</description>
                  <value>#110</value>
                </enumeratedValue>
                <enumeratedValue>
                  <name>111</name>
                  <description>Alternative 7 (chip-specific).</description>
                  <value>#111</value>
                </enumeratedValue>
              </enumeratedValues>
            </field>
            <field>
              <name>IRQC</name>
              <description>Interrupt Configuration</description>
              <bitOffset>16</bitOffset>
              <bitWidth>4</bitWidth>
              <access>read-write</access>
              <enumeratedValues>
                <enumeratedValue>
                  <name>0000</name>
                  <description>Interrupt/DMA request disabled.</description>
                  <value>#0000</value>
                </enumeratedValue>
                <enumeratedValue>
                  <name>0001</name>
                  <description>DMA request on rising edge.</description>
                  <value>#0001</value>
                </enumeratedValue>
                <enumeratedValue>
                  <name>0010</name>
                  <description>DMA request on falling edge.</description>
                  <value>#0010</value>
                </enumeratedValue>
                <enumeratedValue>
                  <name>0011</name>
                  <description>DMA request on either edge.</description>
                  <value>#0011</value>
                </enumeratedValue>
                <enumeratedValue>
                  <name>1000</name>
                  <description>Interrupt when logic 0.</description>
                  <value>#1000</value>
                </enumeratedValue>
                <enumeratedValue>
                  <name>1001</name>
                  <description>Interrupt on rising-edge.</description>
                  <value>#1001</value>
                </enumeratedValue>
                <enumeratedValue>
                  <name>1010</name>
                  <description>Interrupt on falling-edge.</description>
                  <value>#1010</value>
                </enumeratedValue>
                <enumeratedValue>
                  <name>1011</name>
                  <description>Interrupt on either edge.</description>
                  <value>#1011</value>
                </enumeratedValue>
                <enumeratedValue>
                  <name>1100</name>
                  <description>Interrupt when logic 1.</description>
                  <value>#1100</value>
                </enumeratedValue>
              </enumeratedValues>
            </field>
            <field>
              <name>ISF</name>
              <description>Interrupt Status Flag</description>
              <bitOffset>24</bitOffset>
              <bitWidth>1</bitWidth>
              <access>read-write</access>
              <enumeratedValues>
                <enumeratedValue>
                  <name>0</name>
                  <description>Configured interrupt is not detected.</description>
                  <value>#0</value>
                </enumeratedValue>
                <enumeratedValue>
                  <name>1</name>
                  <description>Configured interrupt is detected. If the pin is configured to generate a DMA request, then the corresponding flag will be cleared automatically at the completion of the requested DMA transfer. Otherwise, the flag remains set until a logic 1 is written to the flag. If the pin is configured for a level sensitive interrupt and the pin remains asserted, then the flag is set again immediately after it is cleared.</description>
                  <value>#1</value>
                </enumeratedValue>
              </enumeratedValues>
            </field>
          </fields>
        </register>
        <register>
          <name>PCR31</name>
          <description>Pin Control Register n</description>
          <addressOffset>0x7C</addressOffset>
          <size>32</size>
          <access>read-write</access>
          <resetValue>0x5</resetValue>
          <resetMask>0xFFFFFFFF</resetMask>
          <fields>
            <field>
              <name>PS</name>
              <description>Pull Select</description>
              <bitOffset>0</bitOffset>
              <bitWidth>1</bitWidth>
              <access>read-write</access>
              <enumeratedValues>
                <enumeratedValue>
                  <name>0</name>
                  <description>Internal pulldown resistor is enabled on the corresponding pin, if the corresponding PE field is set.</description>
                  <value>#0</value>
                </enumeratedValue>
                <enumeratedValue>
                  <name>1</name>
                  <description>Internal pullup resistor is enabled on the corresponding pin, if the corresponding PE field is set.</description>
                  <value>#1</value>
                </enumeratedValue>
              </enumeratedValues>
            </field>
            <field>
              <name>PE</name>
              <description>Pull Enable</description>
              <bitOffset>1</bitOffset>
              <bitWidth>1</bitWidth>
              <access>read-write</access>
              <enumeratedValues>
                <enumeratedValue>
                  <name>0</name>
                  <description>Internal pullup or pulldown resistor is not enabled on the corresponding pin.</description>
                  <value>#0</value>
                </enumeratedValue>
                <enumeratedValue>
                  <name>1</name>
                  <description>Internal pullup or pulldown resistor is enabled on the corresponding pin, if the pin is configured as a digital input.</description>
                  <value>#1</value>
                </enumeratedValue>
              </enumeratedValues>
            </field>
            <field>
              <name>SRE</name>
              <description>Slew Rate Enable</description>
              <bitOffset>2</bitOffset>
              <bitWidth>1</bitWidth>
              <access>read-write</access>
              <enumeratedValues>
                <enumeratedValue>
                  <name>0</name>
                  <description>Fast slew rate is configured on the corresponding pin, if the pin is configured as a digital output.</description>
                  <value>#0</value>
                </enumeratedValue>
                <enumeratedValue>
                  <name>1</name>
                  <description>Slow slew rate is configured on the corresponding pin, if the pin is configured as a digital output.</description>
                  <value>#1</value>
                </enumeratedValue>
              </enumeratedValues>
            </field>
            <field>
              <name>PFE</name>
              <description>Passive Filter Enable</description>
              <bitOffset>4</bitOffset>
              <bitWidth>1</bitWidth>
              <access>read-only</access>
              <enumeratedValues>
                <enumeratedValue>
                  <name>0</name>
                  <description>Passive input filter is disabled on the corresponding pin.</description>
                  <value>#0</value>
                </enumeratedValue>
                <enumeratedValue>
                  <name>1</name>
                  <description>Passive input filter is enabled on the corresponding pin, if the pin is configured as a digital input. Refer to the device data sheet for filter characteristics.</description>
                  <value>#1</value>
                </enumeratedValue>
              </enumeratedValues>
            </field>
            <field>
              <name>DSE</name>
              <description>Drive Strength Enable</description>
              <bitOffset>6</bitOffset>
              <bitWidth>1</bitWidth>
              <access>read-only</access>
              <enumeratedValues>
                <enumeratedValue>
                  <name>0</name>
                  <description>Low drive strength is configured on the corresponding pin, if pin is configured as a digital output.</description>
                  <value>#0</value>
                </enumeratedValue>
                <enumeratedValue>
                  <name>1</name>
                  <description>High drive strength is configured on the corresponding pin, if pin is configured as a digital output.</description>
                  <value>#1</value>
                </enumeratedValue>
              </enumeratedValues>
            </field>
            <field>
              <name>MUX</name>
              <description>Pin Mux Control</description>
              <bitOffset>8</bitOffset>
              <bitWidth>3</bitWidth>
              <access>read-write</access>
              <enumeratedValues>
                <enumeratedValue>
                  <name>000</name>
                  <description>Pin disabled (analog).</description>
                  <value>#000</value>
                </enumeratedValue>
                <enumeratedValue>
                  <name>001</name>
                  <description>Alternative 1 (GPIO).</description>
                  <value>#001</value>
                </enumeratedValue>
                <enumeratedValue>
                  <name>010</name>
                  <description>Alternative 2 (chip-specific).</description>
                  <value>#010</value>
                </enumeratedValue>
                <enumeratedValue>
                  <name>011</name>
                  <description>Alternative 3 (chip-specific).</description>
                  <value>#011</value>
                </enumeratedValue>
                <enumeratedValue>
                  <name>100</name>
                  <description>Alternative 4 (chip-specific).</description>
                  <value>#100</value>
                </enumeratedValue>
                <enumeratedValue>
                  <name>101</name>
                  <description>Alternative 5 (chip-specific).</description>
                  <value>#101</value>
                </enumeratedValue>
                <enumeratedValue>
                  <name>110</name>
                  <description>Alternative 6 (chip-specific).</description>
                  <value>#110</value>
                </enumeratedValue>
                <enumeratedValue>
                  <name>111</name>
                  <description>Alternative 7 (chip-specific).</description>
                  <value>#111</value>
                </enumeratedValue>
              </enumeratedValues>
            </field>
            <field>
              <name>IRQC</name>
              <description>Interrupt Configuration</description>
              <bitOffset>16</bitOffset>
              <bitWidth>4</bitWidth>
              <access>read-write</access>
              <enumeratedValues>
                <enumeratedValue>
                  <name>0000</name>
                  <description>Interrupt/DMA request disabled.</description>
                  <value>#0000</value>
                </enumeratedValue>
                <enumeratedValue>
                  <name>0001</name>
                  <description>DMA request on rising edge.</description>
                  <value>#0001</value>
                </enumeratedValue>
                <enumeratedValue>
                  <name>0010</name>
                  <description>DMA request on falling edge.</description>
                  <value>#0010</value>
                </enumeratedValue>
                <enumeratedValue>
                  <name>0011</name>
                  <description>DMA request on either edge.</description>
                  <value>#0011</value>
                </enumeratedValue>
                <enumeratedValue>
                  <name>1000</name>
                  <description>Interrupt when logic 0.</description>
                  <value>#1000</value>
                </enumeratedValue>
                <enumeratedValue>
                  <name>1001</name>
                  <description>Interrupt on rising-edge.</description>
                  <value>#1001</value>
                </enumeratedValue>
                <enumeratedValue>
                  <name>1010</name>
                  <description>Interrupt on falling-edge.</description>
                  <value>#1010</value>
                </enumeratedValue>
                <enumeratedValue>
                  <name>1011</name>
                  <description>Interrupt on either edge.</description>
                  <value>#1011</value>
                </enumeratedValue>
                <enumeratedValue>
                  <name>1100</name>
                  <description>Interrupt when logic 1.</description>
                  <value>#1100</value>
                </enumeratedValue>
              </enumeratedValues>
            </field>
            <field>
              <name>ISF</name>
              <description>Interrupt Status Flag</description>
              <bitOffset>24</bitOffset>
              <bitWidth>1</bitWidth>
              <access>read-write</access>
              <enumeratedValues>
                <enumeratedValue>
                  <name>0</name>
                  <description>Configured interrupt is not detected.</description>
                  <value>#0</value>
                </enumeratedValue>
                <enumeratedValue>
                  <name>1</name>
                  <description>Configured interrupt is detected. If the pin is configured to generate a DMA request, then the corresponding flag will be cleared automatically at the completion of the requested DMA transfer. Otherwise, the flag remains set until a logic 1 is written to the flag. If the pin is configured for a level sensitive interrupt and the pin remains asserted, then the flag is set again immediately after it is cleared.</description>
                  <value>#1</value>
                </enumeratedValue>
              </enumeratedValues>
            </field>
          </fields>
        </register>
        <register>
          <name>GPCLR</name>
          <description>Global Pin Control Low Register</description>
          <addressOffset>0x80</addressOffset>
          <size>32</size>
          <access>write-only</access>
          <resetValue>0</resetValue>
          <resetMask>0xFFFFFFFF</resetMask>
          <fields>
            <field>
              <name>GPWD</name>
              <description>Global Pin Write Data</description>
              <bitOffset>0</bitOffset>
              <bitWidth>16</bitWidth>
              <access>write-only</access>
            </field>
            <field>
              <name>GPWE</name>
              <description>Global Pin Write Enable</description>
              <bitOffset>16</bitOffset>
              <bitWidth>16</bitWidth>
              <access>write-only</access>
              <enumeratedValues>
                <enumeratedValue>
                  <name>0</name>
                  <description>Corresponding Pin Control Register is not updated with the value in GPWD.</description>
                  <value>#0</value>
                </enumeratedValue>
                <enumeratedValue>
                  <name>1</name>
                  <description>Corresponding Pin Control Register is updated with the value in GPWD.</description>
                  <value>#1</value>
                </enumeratedValue>
              </enumeratedValues>
            </field>
          </fields>
        </register>
        <register>
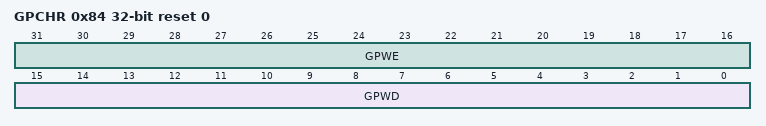
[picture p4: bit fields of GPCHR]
          <name>GPCHR</name>
          <description>Global Pin Control High Register</description>
          <addressOffset>0x84</addressOffset>
          <size>32</size>
          <access>write-only</access>
          <resetValue>0</resetValue>
          <resetMask>0xFFFFFFFF</resetMask>
          <fields>
            <field>
              <name>GPWD</name>
              <description>Global Pin Write Data</description>
              <bitOffset>0</bitOffset>
              <bitWidth>16</bitWidth>
              <access>write-only</access>
            </field>
            <field>
              <name>GPWE</name>
              <description>Global Pin Write Enable</description>
              <bitOffset>16</bitOffset>
              <bitWidth>16</bitWidth>
              <access>write-only</access>
              <enumeratedValues>
                <enumeratedValue>
                  <name>0</name>
                  <description>Corresponding Pin Control Register is not updated with the value in GPWD.</description>
                  <value>#0</value>
                </enumeratedValue>
                <enumeratedValue>
                  <name>1</name>
                  <description>Corresponding Pin Control Register is updated with the value in GPWD.</description>
                  <value>#1</value>
                </enumeratedValue>
              </enumeratedValues>
            </field>
          </fields>
        </register>
        <register>
          <name>ISFR</name>
          <description>Interrupt Status Flag Register</description>
          <addressOffset>0xA0</addressOffset>
          <size>32</size>
          <access>read-write</access>
          <resetValue>0</resetValue>
          <resetMask>0xFFFFFFFF</resetMask>
          <fields>
            <field>
              <name>ISF</name>
              <description>Interrupt Status Flag</description>
              <bitOffset>0</bitOffset>
              <bitWidth>32</bitWidth>
              <access>read-write</access>
              <enumeratedValues>
                <enumeratedValue>
                  <name>0</name>
                  <description>Configured interrupt is not detected.</description>
                  <value>#0</value>
                </enumeratedValue>
                <enumeratedValue>
                  <name>1</name>
                  <description>Configured interrupt is detected. If the pin is configured to generate a DMA request, then the corresponding flag will be cleared automatically at the completion of the requested DMA transfer. Otherwise, the flag remains set until a logic 1 is written to the flag. If the pin is configured for a level sensitive interrupt and the pin remains asserted, then the flag is set again immediately after it is cleared.</description>
                  <value>#1</value>
                </enumeratedValue>
              </enumeratedValues>
            </field>
          </fields>
        </register>
      </registers>
    </peripheral>
    <peripheral>
      <name>MCG</name>
      <description>Multipurpose Clock Generator module</description>
      <prependToName>MCG_</prependToName>
      <baseAddress>0x40064000</baseAddress>
      <addressBlock>
        <offset>0</offset>
        <size>0x10</size>
        <usage>registers</usage>
      </addressBlock>
      <interrupt>
        <name>MCG</name>
        <value>27</value>
      </interrupt>
      <registers>
        <register>
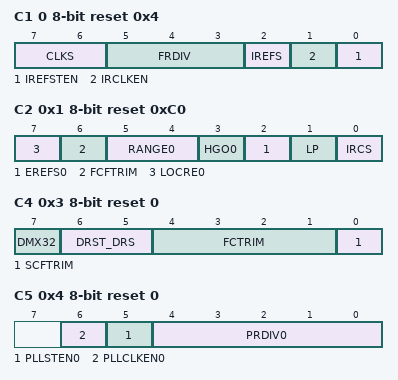
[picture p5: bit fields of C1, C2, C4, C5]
          <name>C1</name>
          <description>MCG Control 1 Register</description>
          <addressOffset>0</addressOffset>
          <size>8</size>
          <access>read-write</access>
          <resetValue>0x4</resetValue>
          <resetMask>0xFF</resetMask>
          <fields>
            <field>
              <name>IREFSTEN</name>
              <description>Internal Reference Stop Enable</description>
              <bitOffset>0</bitOffset>
              <bitWidth>1</bitWidth>
              <access>read-write</access>
              <enumeratedValues>
                <enumeratedValue>
                  <name>0</name>
                  <description>Internal reference clock is disabled in Stop mode.</description>
                  <value>#0</value>
                </enumeratedValue>
                <enumeratedValue>
                  <name>1</name>
                  <description>Internal reference clock is enabled in Stop mode if IRCLKEN is set or if MCG is in FEI, FBI, or BLPI modes before entering Stop mode.</description>
                  <value>#1</value>
                </enumeratedValue>
              </enumeratedValues>
            </field>
            <field>
              <name>IRCLKEN</name>
              <description>Internal Reference Clock Enable</description>
              <bitOffset>1</bitOffset>
              <bitWidth>1</bitWidth>
              <access>read-write</access>
              <enumeratedValues>
                <enumeratedValue>
                  <name>0</name>
                  <description>MCGIRCLK inactive.</description>
                  <value>#0</value>
                </enumeratedValue>
                <enumeratedValue>
                  <name>1</name>
                  <description>MCGIRCLK active.</description>
                  <value>#1</value>
                </enumeratedValue>
              </enumeratedValues>
            </field>
            <field>
              <name>IREFS</name>
              <description>Internal Reference Select</description>
              <bitOffset>2</bitOffset>
              <bitWidth>1</bitWidth>
              <access>read-write</access>
              <enumeratedValues>
                <enumeratedValue>
                  <name>0</name>
                  <description>External reference clock is selected.</description>
                  <value>#0</value>
                </enumeratedValue>
                <enumeratedValue>
                  <name>1</name>
                  <description>The slow internal reference clock is selected.</description>
                  <value>#1</value>
                </enumeratedValue>
              </enumeratedValues>
            </field>
            <field>
              <name>FRDIV</name>
              <description>FLL External Reference Divider</description>
              <bitOffset>3</bitOffset>
              <bitWidth>3</bitWidth>
              <access>read-write</access>
              <enumeratedValues>
                <enumeratedValue>
                  <name>000</name>
                  <description>If RANGE 0 = 0 or OSCSEL=1 , Divide Factor is 1; for all other RANGE 0 values, Divide Factor is 32.</description>
                  <value>#000</value>
                </enumeratedValue>
                <enumeratedValue>
                  <name>001</name>
                  <description>If RANGE 0 = 0 or OSCSEL=1 , Divide Factor is 2; for all other RANGE 0 values, Divide Factor is 64.</description>
                  <value>#001</value>
                </enumeratedValue>
                <enumeratedValue>
                  <name>010</name>
                  <description>If RANGE 0 = 0 or OSCSEL=1 , Divide Factor is 4; for all other RANGE 0 values, Divide Factor is 128.</description>
                  <value>#010</value>
                </enumeratedValue>
                <enumeratedValue>
                  <name>011</name>
                  <description>If RANGE 0 = 0 or OSCSEL=1 , Divide Factor is 8; for all other RANGE 0 values, Divide Factor is 256.</description>
                  <value>#011</value>
                </enumeratedValue>
                <enumeratedValue>
                  <name>100</name>
                  <description>If RANGE 0 = 0 or OSCSEL=1 , Divide Factor is 16; for all other RANGE 0 values, Divide Factor is 512.</description>
                  <value>#100</value>
                </enumeratedValue>
                <enumeratedValue>
                  <name>101</name>
                  <description>If RANGE 0 = 0 or OSCSEL=1 , Divide Factor is 32; for all other RANGE 0 values, Divide Factor is 1024.</description>
                  <value>#101</value>
                </enumeratedValue>
                <enumeratedValue>
                  <name>110</name>
                  <description>If RANGE 0 = 0 or OSCSEL=1 , Divide Factor is 64; for all other RANGE 0 values, Divide Factor is 1280 .</description>
                  <value>#110</value>
                </enumeratedValue>
                <enumeratedValue>
                  <name>111</name>
                  <description>If RANGE 0 = 0 or OSCSEL=1 , Divide Factor is 128; for all other RANGE 0 values, Divide Factor is 1536 .</description>
                  <value>#111</value>
                </enumeratedValue>
              </enumeratedValues>
            </field>
            <field>
              <name>CLKS</name>
              <description>Clock Source Select</description>
              <bitOffset>6</bitOffset>
              <bitWidth>2</bitWidth>
              <access>read-write</access>
              <enumeratedValues>
                <enumeratedValue>
                  <name>00</name>
                  <description>Encoding 0 - Output of FLL or PLL is selected (depends on PLLS control bit).</description>
                  <value>#00</value>
                </enumeratedValue>
                <enumeratedValue>
                  <name>01</name>
                  <description>Encoding 1 - Internal reference clock is selected.</description>
                  <value>#01</value>
                </enumeratedValue>
                <enumeratedValue>
                  <name>10</name>
                  <description>Encoding 2 - External reference clock is selected.</description>
                  <value>#10</value>
                </enumeratedValue>
                <enumeratedValue>
                  <name>11</name>
                  <description>Encoding 3 - Reserved.</description>
                  <value>#11</value>
                </enumeratedValue>
              </enumeratedValues>
            </field>
          </fields>
        </register>
        <register>
          <name>C2</name>
          <description>MCG Control 2 Register</description>
          <addressOffset>0x1</addressOffset>
          <size>8</size>
          <access>read-write</access>
          <resetValue>0xC0</resetValue>
          <resetMask>0xFF</resetMask>
          <fields>
            <field>
              <name>IRCS</name>
              <description>Internal Reference Clock Select</description>
              <bitOffset>0</bitOffset>
              <bitWidth>1</bitWidth>
              <access>read-write</access>
              <enumeratedValues>
                <enumeratedValue>
                  <name>0</name>
                  <description>Slow internal reference clock selected.</description>
                  <value>#0</value>
                </enumeratedValue>
                <enumeratedValue>
                  <name>1</name>
                  <description>Fast internal reference clock selected.</description>
                  <value>#1</value>
                </enumeratedValue>
              </enumeratedValues>
            </field>
            <field>
              <name>LP</name>
              <description>Low Power Select</description>
              <bitOffset>1</bitOffset>
              <bitWidth>1</bitWidth>
              <access>read-write</access>
              <enumeratedValues>
                <enumeratedValue>
                  <name>0</name>
                  <description>FLL or PLL is not disabled in bypass modes.</description>
                  <value>#0</value>
                </enumeratedValue>
                <enumeratedValue>
                  <name>1</name>
                  <description>FLL or PLL is disabled in bypass modes (lower power)</description>
                  <value>#1</value>
                </enumeratedValue>
              </enumeratedValues>
            </field>
            <field>
              <name>EREFS0</name>
              <description>External Reference Select</description>
              <bitOffset>2</bitOffset>
              <bitWidth>1</bitWidth>
              <access>read-write</access>
              <enumeratedValues>
                <enumeratedValue>
                  <name>0</name>
                  <description>External reference clock requested.</description>
                  <value>#0</value>
                </enumeratedValue>
                <enumeratedValue>
                  <name>1</name>
                  <description>Oscillator requested.</description>
                  <value>#1</value>
                </enumeratedValue>
              </enumeratedValues>
            </field>
            <field>
              <name>HGO0</name>
              <description>High Gain Oscillator Select</description>
              <bitOffset>3</bitOffset>
              <bitWidth>1</bitWidth>
              <access>read-write</access>
              <enumeratedValues>
                <enumeratedValue>
                  <name>0</name>
                  <description>Configure crystal oscillator for low-power operation.</description>
                  <value>#0</value>
                </enumeratedValue>
                <enumeratedValue>
                  <name>1</name>
                  <description>Configure crystal oscillator for high-gain operation.</description>
                  <value>#1</value>
                </enumeratedValue>
              </enumeratedValues>
            </field>
            <field>
              <name>RANGE0</name>
              <description>Frequency Range Select</description>
              <bitOffset>4</bitOffset>
              <bitWidth>2</bitWidth>
              <access>read-write</access>
              <enumeratedValues>
                <enumeratedValue>
                  <name>00</name>
                  <description>Encoding 0 - Low frequency range selected for the crystal oscillator .</description>
                  <value>#00</value>
                </enumeratedValue>
                <enumeratedValue>
                  <name>01</name>
                  <description>Encoding 1 - High frequency range selected for the crystal oscillator .</description>
                  <value>#01</value>
                </enumeratedValue>
                <enumeratedValue>
                  <name>1X</name>
                  <description>Encoding 2 - Very high frequency range selected for the crystal oscillator .</description>
                  <value>#1x</value>
                </enumeratedValue>
              </enumeratedValues>
            </field>
            <field>
              <name>FCFTRIM</name>
              <description>Fast Internal Reference Clock Fine Trim</description>
              <bitOffset>6</bitOffset>
              <bitWidth>1</bitWidth>
              <access>read-write</access>
            </field>
            <field>
              <name>LOCRE0</name>
              <description>Loss of Clock Reset Enable</description>
              <bitOffset>7</bitOffset>
              <bitWidth>1</bitWidth>
              <access>read-write</access>
              <enumeratedValues>
                <enumeratedValue>
                  <name>0</name>
                  <description>Interrupt request is generated on a loss of OSC0 external reference clock.</description>
                  <value>#0</value>
                </enumeratedValue>
                <enumeratedValue>
                  <name>1</name>
                  <description>Generate a reset request on a loss of OSC0 external reference clock.</description>
                  <value>#1</value>
                </enumeratedValue>
              </enumeratedValues>
            </field>
          </fields>
        </register>
        <register>
          <name>C3</name>
          <description>MCG Control 3 Register</description>
          <addressOffset>0x2</addressOffset>
          <size>8</size>
          <access>read-write</access>
          <resetValue>0</resetValue>
          <resetMask>0</resetMask>
          <fields>
            <field>
              <name>SCTRIM</name>
              <description>Slow Internal Reference Clock Trim Setting</description>
              <bitOffset>0</bitOffset>
              <bitWidth>8</bitWidth>
              <access>read-write</access>
            </field>
          </fields>
        </register>
        <register>
          <name>C4</name>
          <description>MCG Control 4 Register</description>
          <addressOffset>0x3</addressOffset>
          <size>8</size>
          <access>read-write</access>
          <resetValue>0</resetValue>
          <resetMask>0xE0</resetMask>
          <fields>
            <field>
              <name>SCFTRIM</name>
              <description>Slow Internal Reference Clock Fine Trim</description>
              <bitOffset>0</bitOffset>
              <bitWidth>1</bitWidth>
              <access>read-write</access>
            </field>
            <field>
              <name>FCTRIM</name>
              <description>Fast Internal Reference Clock Trim Setting</description>
              <bitOffset>1</bitOffset>
              <bitWidth>4</bitWidth>
              <access>read-write</access>
            </field>
            <field>
              <name>DRST_DRS</name>
              <description>DCO Range Select</description>
              <bitOffset>5</bitOffset>
              <bitWidth>2</bitWidth>
              <access>read-write</access>
              <enumeratedValues>
                <enumeratedValue>
                  <name>00</name>
                  <description>Encoding 0 - Low range (reset default).</description>
                  <value>#00</value>
                </enumeratedValue>
                <enumeratedValue>
                  <name>01</name>
                  <description>Encoding 1 - Mid range.</description>
                  <value>#01</value>
                </enumeratedValue>
                <enumeratedValue>
                  <name>10</name>
                  <description>Encoding 2 - Mid-high range.</description>
                  <value>#10</value>
                </enumeratedValue>
                <enumeratedValue>
                  <name>11</name>
                  <description>Encoding 3 - High range.</description>
                  <value>#11</value>
                </enumeratedValue>
              </enumeratedValues>
            </field>
            <field>
              <name>DMX32</name>
              <description>DCO Maximum Frequency with 32.768 kHz Reference</description>
              <bitOffset>7</bitOffset>
              <bitWidth>1</bitWidth>
              <access>read-write</access>
              <enumeratedValues>
                <enumeratedValue>
                  <name>0</name>
                  <description>DCO has a default range of 25%.</description>
                  <value>#0</value>
                </enumeratedValue>
                <enumeratedValue>
                  <name>1</name>
                  <description>DCO is fine-tuned for maximum frequency with 32.768 kHz reference.</description>
                  <value>#1</value>
                </enumeratedValue>
              </enumeratedValues>
            </field>
          </fields>
        </register>
        <register>
          <name>C5</name>
          <description>MCG Control 5 Register</description>
          <addressOffset>0x4</addressOffset>
          <size>8</size>
          <access>read-write</access>
          <resetValue>0</resetValue>
          <resetMask>0xFF</resetMask>
          <fields>
            <field>
              <name>PRDIV0</name>
              <description>PLL External Reference Divider</description>
              <bitOffset>0</bitOffset>
              <bitWidth>5</bitWidth>
              <access>read-write</access>
              <enumeratedValues>
                <enumeratedValue>
                  <name>0</name>
                  <description>Divide Factor is 1</description>
                  <value>#00000</value>
                </enumeratedValue>
                <enumeratedValue>
                  <name>1</name>
                  <description>Divide Factor is 2</description>
                  <value>#00001</value>
                </enumeratedValue>
                <enumeratedValue>
                  <name>2</name>
                  <description>Divide Factor is 3</description>
                  <value>#00010</value>
                </enumeratedValue>
                <enumeratedValue>
                  <name>3</name>
                  <description>Divide Factor is 4</description>
                  <value>#00011</value>
                </enumeratedValue>
                <enumeratedValue>
                  <name>4</name>
                  <description>Divide Factor is 5</description>
                  <value>#00100</value>
                </enumeratedValue>
                <enumeratedValue>
                  <name>5</name>
                  <description>Divide Factor is 6</description>
                  <value>#00101</value>
                </enumeratedValue>
                <enumeratedValue>
                  <name>6</name>
                  <description>Divide Factor is 7</description>
                  <value>#00110</value>
                </enumeratedValue>
                <enumeratedValue>
                  <name>7</name>
                  <description>Divide Factor is 8</description>
                  <value>#00111</value>
                </enumeratedValue>
                <enumeratedValue>
                  <name>8</name>
                  <description>Divide Factor is 9</description>
                  <value>#01000</value>
                </enumeratedValue>
                <enumeratedValue>
                  <name>9</name>
                  <description>Divide Factor is 10</description>
                  <value>#01001</value>
                </enumeratedValue>
                <enumeratedValue>
                  <name>10</name>
                  <description>Divide Factor is 11</description>
                  <value>#01010</value>
                </enumeratedValue>
                <enumeratedValue>
                  <name>11</name>
                  <description>Divide Factor is 12</description>
                  <value>#01011</value>
                </enumeratedValue>
                <enumeratedValue>
                  <name>12</name>
                  <description>Divide Factor is 13</description>
                  <value>#01100</value>
                </enumeratedValue>
                <enumeratedValue>
                  <name>13</name>
                  <description>Divide Factor is 14</description>
                  <value>#01101</value>
                </enumeratedValue>
                <enumeratedValue>
                  <name>14</name>
                  <description>Divide Factor is 15</description>
                  <value>#01110</value>
                </enumeratedValue>
                <enumeratedValue>
                  <name>15</name>
                  <description>Divide Factor is 16</description>
                  <value>#01111</value>
                </enumeratedValue>
                <enumeratedValue>
                  <name>16</name>
                  <description>Divide Factor is 17</description>
                  <value>#10000</value>
                </enumeratedValue>
                <enumeratedValue>
                  <name>17</name>
                  <description>Divide Factor is 18</description>
                  <value>#10001</value>
                </enumeratedValue>
                <enumeratedValue>
                  <name>18</name>
                  <description>Divide Factor is 19</description>
                  <value>#10010</value>
                </enumeratedValue>
                <enumeratedValue>
                  <name>19</name>
                  <description>Divide Factor is 20</description>
                  <value>#10011</value>
                </enumeratedValue>
                <enumeratedValue>
                  <name>20</name>
                  <description>Divide Factor is 21</description>
                  <value>#10100</value>
                </enumeratedValue>
                <enumeratedValue>
                  <name>21</name>
                  <description>Divide Factor is 22</description>
                  <value>#10101</value>
                </enumeratedValue>
                <enumeratedValue>
                  <name>22</name>
                  <description>Divide Factor is 23</description>
                  <value>#10110</value>
                </enumeratedValue>
                <enumeratedValue>
                  <name>23</name>
                  <description>Divide Factor is 24</description>
                  <value>#10111</value>
                </enumeratedValue>
                <enumeratedValue>
                  <name>24</name>
                  <description>Divide Factor is 25</description>
                  <value>#11000</value>
                </enumeratedValue>
                <enumeratedValue>
                  <name>25</name>
                  <description>Divide Factor is 26</description>
                  <value>#11001</value>
                </enumeratedValue>
                <enumeratedValue>
                  <name>26</name>
                  <description>Divide Factor is 27</description>
                  <value>#11010</value>
                </enumeratedValue>
                <enumeratedValue>
                  <name>27</name>
                  <description>Divide Factor is 28</description>
                  <value>#11011</value>
                </enumeratedValue>
                <enumeratedValue>
                  <name>28</name>
                  <description>Divide Factor is 29</description>
                  <value>#11100</value>
                </enumeratedValue>
                <enumeratedValue>
                  <name>29</name>
                  <description>Divide Factor is 30</description>
                  <value>#11101</value>
                </enumeratedValue>
                <enumeratedValue>
                  <name>30</name>
                  <description>Divide Factor is 31</description>
                  <value>#11110</value>
                </enumeratedValue>
                <enumeratedValue>
                  <name>31</name>
                  <description>Divide Factor is 32</description>
                  <value>#11111</value>
                </enumeratedValue>
              </enumeratedValues>
            </field>
            <field>
              <name>PLLSTEN0</name>
              <description>PLL Stop Enable</description>
              <bitOffset>5</bitOffset>
              <bitWidth>1</bitWidth>
              <access>read-write</access>
              <enumeratedValues>
                <enumeratedValue>
                  <name>0</name>
                  <description>MCGPLLCLK is disabled in any of the Stop modes.</description>
                  <value>#0</value>
                </enumeratedValue>
                <enumeratedValue>
                  <name>1</name>
                  <description>MCGPLLCLK is enabled if system is in Normal Stop mode.</description>
                  <value>#1</value>
                </enumeratedValue>
              </enumeratedValues>
            </field>
            <field>
              <name>PLLCLKEN0</name>
              <description>PLL Clock Enable</description>
              <bitOffset>6</bitOffset>
              <bitWidth>1</bitWidth>
              <access>read-write</access>
              <enumeratedValues>
                <enumeratedValue>
                  <name>0</name>
                  <description>MCGPLLCLK is inactive.</description>
                  <value>#0</value>
                </enumeratedValue>
                <enumeratedValue>
                  <name>1</name>
                  <description>MCGPLLCLK is active.</description>
                  <value>#1</value>
                </enumeratedValue>
              </enumeratedValues>
            </field>
          </fields>
        </register>
        <register>
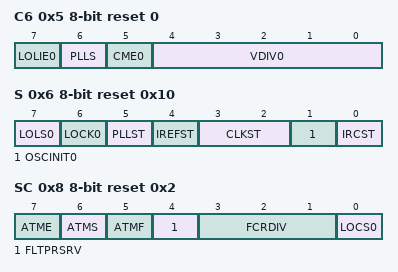
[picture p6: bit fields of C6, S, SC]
          <name>C6</name>
          <description>MCG Control 6 Register</description>
          <addressOffset>0x5</addressOffset>
          <size>8</size>
          <access>read-write</access>
          <resetValue>0</resetValue>
          <resetMask>0xFF</resetMask>
          <fields>
            <field>
              <name>VDIV0</name>
              <description>VCO 0 Divider</description>
              <bitOffset>0</bitOffset>
              <bitWidth>5</bitWidth>
              <access>read-write</access>
              <enumeratedValues>
                <enumeratedValue>
                  <name>0</name>
                  <description>Multiply Factor is 24</description>
                  <value>#00000</value>
                </enumeratedValue>
                <enumeratedValue>
                  <name>1</name>
                  <description>Multiply Factor is 25</description>
                  <value>#00001</value>
                </enumeratedValue>
                <enumeratedValue>
                  <name>2</name>
                  <description>Multiply Factor is 26</description>
                  <value>#00010</value>
                </enumeratedValue>
                <enumeratedValue>
                  <name>3</name>
                  <description>Multiply Factor is 27</description>
                  <value>#00011</value>
                </enumeratedValue>
                <enumeratedValue>
                  <name>4</name>
                  <description>Multiply Factor is 28</description>
                  <value>#00100</value>
                </enumeratedValue>
                <enumeratedValue>
                  <name>5</name>
                  <description>Multiply Factor is 29</description>
                  <value>#00101</value>
                </enumeratedValue>
                <enumeratedValue>
                  <name>6</name>
                  <description>Multiply Factor is 30</description>
                  <value>#00110</value>
                </enumeratedValue>
                <enumeratedValue>
                  <name>7</name>
                  <description>Multiply Factor is 31</description>
                  <value>#00111</value>
                </enumeratedValue>
                <enumeratedValue>
                  <name>8</name>
                  <description>Multiply Factor is 32</description>
                  <value>#01000</value>
                </enumeratedValue>
                <enumeratedValue>
                  <name>9</name>
                  <description>Multiply Factor is 33</description>
                  <value>#01001</value>
                </enumeratedValue>
                <enumeratedValue>
                  <name>10</name>
                  <description>Multiply Factor is 34</description>
                  <value>#01010</value>
                </enumeratedValue>
                <enumeratedValue>
                  <name>11</name>
                  <description>Multiply Factor is 35</description>
                  <value>#01011</value>
                </enumeratedValue>
                <enumeratedValue>
                  <name>12</name>
                  <description>Multiply Factor is 36</description>
                  <value>#01100</value>
                </enumeratedValue>
                <enumeratedValue>
                  <name>13</name>
                  <description>Multiply Factor is 37</description>
                  <value>#01101</value>
                </enumeratedValue>
                <enumeratedValue>
                  <name>14</name>
                  <description>Multiply Factor is 38</description>
                  <value>#01110</value>
                </enumeratedValue>
                <enumeratedValue>
                  <name>15</name>
                  <description>Multiply Factor is 39</description>
                  <value>#01111</value>
                </enumeratedValue>
                <enumeratedValue>
                  <name>16</name>
                  <description>Multiply Factor is 40</description>
                  <value>#10000</value>
                </enumeratedValue>
                <enumeratedValue>
                  <name>17</name>
                  <description>Multiply Factor is 41</description>
                  <value>#10001</value>
                </enumeratedValue>
                <enumeratedValue>
                  <name>18</name>
                  <description>Multiply Factor is 42</description>
                  <value>#10010</value>
                </enumeratedValue>
                <enumeratedValue>
                  <name>19</name>
                  <description>Multiply Factor is 43</description>
                  <value>#10011</value>
                </enumeratedValue>
                <enumeratedValue>
                  <name>20</name>
                  <description>Multiply Factor is 44</description>
                  <value>#10100</value>
                </enumeratedValue>
                <enumeratedValue>
                  <name>21</name>
                  <description>Multiply Factor is 45</description>
                  <value>#10101</value>
                </enumeratedValue>
                <enumeratedValue>
                  <name>22</name>
                  <description>Multiply Factor is 46</description>
                  <value>#10110</value>
                </enumeratedValue>
                <enumeratedValue>
                  <name>23</name>
                  <description>Multiply Factor is 47</description>
                  <value>#10111</value>
                </enumeratedValue>
                <enumeratedValue>
                  <name>24</name>
                  <description>Multiply Factor is 48</description>
                  <value>#11000</value>
                </enumeratedValue>
                <enumeratedValue>
                  <name>25</name>
                  <description>Multiply Factor is 49</description>
                  <value>#11001</value>
                </enumeratedValue>
                <enumeratedValue>
                  <name>26</name>
                  <description>Multiply Factor is 50</description>
                  <value>#11010</value>
                </enumeratedValue>
                <enumeratedValue>
                  <name>27</name>
                  <description>Multiply Factor is 51</description>
                  <value>#11011</value>
                </enumeratedValue>
                <enumeratedValue>
                  <name>28</name>
                  <description>Multiply Factor is 52</description>
                  <value>#11100</value>
                </enumeratedValue>
                <enumeratedValue>
                  <name>29</name>
                  <description>Multiply Factor is 53</description>
                  <value>#11101</value>
                </enumeratedValue>
                <enumeratedValue>
                  <name>30</name>
                  <description>Multiply Factor is 54</description>
                  <value>#11110</value>
                </enumeratedValue>
                <enumeratedValue>
                  <name>31</name>
                  <description>Multiply Factor is 55</description>
                  <value>#11111</value>
                </enumeratedValue>
              </enumeratedValues>
            </field>
            <field>
              <name>CME0</name>
              <description>Clock Monitor Enable</description>
              <bitOffset>5</bitOffset>
              <bitWidth>1</bitWidth>
              <access>read-write</access>
              <enumeratedValues>
                <enumeratedValue>
                  <name>0</name>
                  <description>External clock monitor is disabled for OSC0.</description>
                  <value>#0</value>
                </enumeratedValue>
                <enumeratedValue>
                  <name>1</name>
                  <description>External clock monitor is enabled for OSC0.</description>
                  <value>#1</value>
                </enumeratedValue>
              </enumeratedValues>
            </field>
            <field>
              <name>PLLS</name>
              <description>PLL Select</description>
              <bitOffset>6</bitOffset>
              <bitWidth>1</bitWidth>
              <access>read-write</access>
              <enumeratedValues>
                <enumeratedValue>
                  <name>0</name>
                  <description>FLL is selected.</description>
                  <value>#0</value>
                </enumeratedValue>
                <enumeratedValue>
                  <name>1</name>
                  <description>PLL is selected (PRDIV 0 need to be programmed to the correct divider to generate a PLL reference clock in the range of 2-4 MHz prior to setting the PLLS bit).</description>
                  <value>#1</value>
                </enumeratedValue>
              </enumeratedValues>
            </field>
            <field>
              <name>LOLIE0</name>
              <description>Loss of Lock Interrrupt Enable</description>
              <bitOffset>7</bitOffset>
              <bitWidth>1</bitWidth>
              <access>read-write</access>
              <enumeratedValues>
                <enumeratedValue>
                  <name>0</name>
                  <description>No interrupt request is generated on loss of lock.</description>
                  <value>#0</value>
                </enumeratedValue>
                <enumeratedValue>
                  <name>1</name>
                  <description>Generate an interrupt request on loss of lock.</description>
                  <value>#1</value>
                </enumeratedValue>
              </enumeratedValues>
            </field>
          </fields>
        </register>
        <register>
          <name>S</name>
          <description>MCG Status Register</description>
          <addressOffset>0x6</addressOffset>
          <size>8</size>
          <access>read-write</access>
          <resetValue>0x10</resetValue>
          <resetMask>0xFF</resetMask>
          <fields>
            <field>
              <name>IRCST</name>
              <description>Internal Reference Clock Status</description>
              <bitOffset>0</bitOffset>
              <bitWidth>1</bitWidth>
              <access>read-only</access>
              <enumeratedValues>
                <enumeratedValue>
                  <name>0</name>
                  <description>Source of internal reference clock is the slow clock (32 kHz IRC).</description>
                  <value>#0</value>
                </enumeratedValue>
                <enumeratedValue>
                  <name>1</name>
                  <description>Source of internal reference clock is the fast clock (4 MHz IRC).</description>
                  <value>#1</value>
                </enumeratedValue>
              </enumeratedValues>
            </field>
            <field>
              <name>OSCINIT0</name>
              <description>OSC Initialization</description>
              <bitOffset>1</bitOffset>
              <bitWidth>1</bitWidth>
              <access>read-only</access>
            </field>
            <field>
              <name>CLKST</name>
              <description>Clock Mode Status</description>
              <bitOffset>2</bitOffset>
              <bitWidth>2</bitWidth>
              <access>read-only</access>
              <enumeratedValues>
                <enumeratedValue>
                  <name>00</name>
                  <description>Encoding 0 - Output of the FLL is selected (reset default).</description>
                  <value>#00</value>
                </enumeratedValue>
                <enumeratedValue>
                  <name>01</name>
                  <description>Encoding 1 - Internal reference clock is selected.</description>
                  <value>#01</value>
                </enumeratedValue>
                <enumeratedValue>
                  <name>10</name>
                  <description>Encoding 2 - External reference clock is selected.</description>
                  <value>#10</value>
                </enumeratedValue>
                <enumeratedValue>
                  <name>11</name>
                  <description>Encoding 3 - Output of the PLL is selected.</description>
                  <value>#11</value>
                </enumeratedValue>
              </enumeratedValues>
            </field>
            <field>
              <name>IREFST</name>
              <description>Internal Reference Status</description>
              <bitOffset>4</bitOffset>
              <bitWidth>1</bitWidth>
              <access>read-only</access>
              <enumeratedValues>
                <enumeratedValue>
                  <name>0</name>
                  <description>Source of FLL reference clock is the external reference clock.</description>
                  <value>#0</value>
                </enumeratedValue>
                <enumeratedValue>
                  <name>1</name>
                  <description>Source of FLL reference clock is the internal reference clock.</description>
                  <value>#1</value>
                </enumeratedValue>
              </enumeratedValues>
            </field>
            <field>
              <name>PLLST</name>
              <description>PLL Select Status</description>
              <bitOffset>5</bitOffset>
              <bitWidth>1</bitWidth>
              <access>read-only</access>
              <enumeratedValues>
                <enumeratedValue>
                  <name>0</name>
                  <description>Source of PLLS clock is FLL clock.</description>
                  <value>#0</value>
                </enumeratedValue>
                <enumeratedValue>
                  <name>1</name>
                  <description>Source of PLLS clock is PLL output clock.</description>
                  <value>#1</value>
                </enumeratedValue>
              </enumeratedValues>
            </field>
            <field>
              <name>LOCK0</name>
              <description>Lock Status</description>
              <bitOffset>6</bitOffset>
              <bitWidth>1</bitWidth>
              <access>read-only</access>
              <enumeratedValues>
                <enumeratedValue>
                  <name>0</name>
                  <description>PLL is currently unlocked.</description>
                  <value>#0</value>
                </enumeratedValue>
                <enumeratedValue>
                  <name>1</name>
                  <description>PLL is currently locked.</description>
                  <value>#1</value>
                </enumeratedValue>
              </enumeratedValues>
            </field>
            <field>
              <name>LOLS0</name>
              <description>Loss of Lock Status</description>
              <bitOffset>7</bitOffset>
              <bitWidth>1</bitWidth>
              <access>read-write</access>
              <enumeratedValues>
                <enumeratedValue>
                  <name>0</name>
                  <description>PLL has not lost lock since LOLS 0 was last cleared.</description>
                  <value>#0</value>
                </enumeratedValue>
                <enumeratedValue>
                  <name>1</name>
                  <description>PLL has lost lock since LOLS 0 was last cleared.</description>
                  <value>#1</value>
                </enumeratedValue>
              </enumeratedValues>
            </field>
          </fields>
        </register>
        <register>
          <name>SC</name>
          <description>MCG Status and Control Register</description>
          <addressOffset>0x8</addressOffset>
          <size>8</size>
          <access>read-write</access>
          <resetValue>0x2</resetValue>
          <resetMask>0xFF</resetMask>
          <fields>
            <field>
              <name>LOCS0</name>
              <description>OSC0 Loss of Clock Status</description>
              <bitOffset>0</bitOffset>
              <bitWidth>1</bitWidth>
              <access>read-write</access>
              <enumeratedValues>
                <enumeratedValue>
                  <name>0</name>
                  <description>Loss of OSC0 has not occurred.</description>
                  <value>#0</value>
                </enumeratedValue>
                <enumeratedValue>
                  <name>1</name>
                  <description>Loss of OSC0 has occurred.</description>
                  <value>#1</value>
                </enumeratedValue>
              </enumeratedValues>
            </field>
            <field>
              <name>FCRDIV</name>
              <description>Fast Clock Internal Reference Divider</description>
              <bitOffset>1</bitOffset>
              <bitWidth>3</bitWidth>
              <access>read-write</access>
              <enumeratedValues>
                <enumeratedValue>
                  <name>000</name>
                  <description>Divide Factor is 1</description>
                  <value>#000</value>
                </enumeratedValue>
                <enumeratedValue>
                  <name>001</name>
                  <description>Divide Factor is 2.</description>
                  <value>#001</value>
                </enumeratedValue>
                <enumeratedValue>
                  <name>010</name>
                  <description>Divide Factor is 4.</description>
                  <value>#010</value>
                </enumeratedValue>
                <enumeratedValue>
                  <name>011</name>
                  <description>Divide Factor is 8.</description>
                  <value>#011</value>
                </enumeratedValue>
                <enumeratedValue>
                  <name>100</name>
                  <description>Divide Factor is 16</description>
                  <value>#100</value>
                </enumeratedValue>
                <enumeratedValue>
                  <name>101</name>
                  <description>Divide Factor is 32</description>
                  <value>#101</value>
                </enumeratedValue>
                <enumeratedValue>
                  <name>110</name>
                  <description>Divide Factor is 64</description>
                  <value>#110</value>
                </enumeratedValue>
                <enumeratedValue>
                  <name>111</name>
                  <description>Divide Factor is 128.</description>
                  <value>#111</value>
                </enumeratedValue>
              </enumeratedValues>
            </field>
            <field>
              <name>FLTPRSRV</name>
              <description>FLL Filter Preserve Enable</description>
              <bitOffset>4</bitOffset>
              <bitWidth>1</bitWidth>
              <access>read-write</access>
              <enumeratedValues>
                <enumeratedValue>
                  <name>0</name>
                  <description>FLL filter and FLL frequency will reset on changes to currect clock mode.</description>
                  <value>#0</value>
                </enumeratedValue>
                <enumeratedValue>
                  <name>1</name>
                  <description>Fll filter and FLL frequency retain their previous values during new clock mode change.</description>
                  <value>#1</value>
                </enumeratedValue>
              </enumeratedValues>
            </field>
            <field>
              <name>ATMF</name>
              <description>Automatic Trim Machine Fail Flag</description>
              <bitOffset>5</bitOffset>
              <bitWidth>1</bitWidth>
              <access>read-write</access>
              <enumeratedValues>
                <enumeratedValue>
                  <name>0</name>
                  <description>Automatic Trim Machine completed normally.</description>
                  <value>#0</value>
                </enumeratedValue>
                <enumeratedValue>
                  <name>1</name>
                  <description>Automatic Trim Machine failed.</description>
                  <value>#1</value>
                </enumeratedValue>
              </enumeratedValues>
            </field>
            <field>
              <name>ATMS</name>
              <description>Automatic Trim Machine Select</description>
              <bitOffset>6</bitOffset>
              <bitWidth>1</bitWidth>
              <access>read-write</access>
              <enumeratedValues>
                <enumeratedValue>
                  <name>0</name>
                  <description>32 kHz Internal Reference Clock selected.</description>
                  <value>#0</value>
                </enumeratedValue>
                <enumeratedValue>
                  <name>1</name>
                  <description>4 MHz Internal Reference Clock selected.</description>
                  <value>#1</value>
                </enumeratedValue>
              </enumeratedValues>
            </field>
            <field>
              <name>ATME</name>
              <description>Automatic Trim Machine Enable</description>
              <bitOffset>7</bitOffset>
              <bitWidth>1</bitWidth>
              <access>read-write</access>
              <enumeratedValues>
                <enumeratedValue>
                  <name>0</name>
                  <description>Auto Trim Machine disabled.</description>
                  <value>#0</value>
                </enumeratedValue>
                <enumeratedValue>
                  <name>1</name>
                  <description>Auto Trim Machine enabled.</description>
                  <value>#1</value>
                </enumeratedValue>
              </enumeratedValues>
            </field>
          </fields>
        </register>
        <register>
          <name>ATCVH</name>
          <description>MCG Auto Trim Compare Value High Register</description>
          <addressOffset>0xA</addressOffset>
          <size>8</size>
          <access>read-write</access>
          <resetValue>0</resetValue>
          <resetMask>0xFF</resetMask>
          <fields>
            <field>
              <name>ATCVH</name>
              <description>ATM Compare Value High</description>
              <bitOffset>0</bitOffset>
              <bitWidth>8</bitWidth>
              <access>read-write</access>
            </field>
          </fields>
        </register>
        <register>
          <name>ATCVL</name>
          <description>MCG Auto Trim Compare Value Low Register</description>
          <addressOffset>0xB</addressOffset>
          <size>8</size>
          <access>read-write</access>
          <resetValue>0</resetValue>
          <resetMask>0xFF</resetMask>
          <fields>
            <field>
              <name>ATCVL</name>
              <description>ATM Compare Value Low</description>
              <bitOffset>0</bitOffset>
              <bitWidth>8</bitWidth>
              <access>read-write</access>
            </field>
          </fields>
        </register>
        <register>
          <name>C7</name>
          <description>MCG Control 7 Register</description>
          <addressOffset>0xC</addressOffset>
          <size>8</size>
          <access>read-write</access>
          <resetValue>0</resetValue>
          <resetMask>0xFF</resetMask>
          <fields>
            <field>
              <name>OSCSEL</name>
              <description>MCG OSC Clock Select</description>
              <bitOffset>0</bitOffset>
              <bitWidth>1</bitWidth>
              <access>read-write</access>
              <enumeratedValues>
                <enumeratedValue>
                  <name>0</name>
                  <description>Selects System Oscillator (OSCCLK).</description>
                  <value>#0</value>
                </enumeratedValue>
                <enumeratedValue>
                  <name>1</name>
                  <description>Selects 32 kHz RTC Oscillator.</description>
                  <value>#1</value>
                </enumeratedValue>
              </enumeratedValues>
            </field>
          </fields>
        </register>
        <register>
          <name>C8</name>
          <description>MCG Control 8 Register</description>
          <addressOffset>0xD</addressOffset>
          <size>8</size>
          <access>read-write</access>
          <resetValue>0x80</resetValue>
          <resetMask>0xFF</resetMask>
          <fields>
            <field>
              <name>LOLRE</name>
              <description>PLL Loss of Lock Reset Enable</description>
              <bitOffset>6</bitOffset>
              <bitWidth>1</bitWidth>
              <access>read-write</access>
              <enumeratedValues>
                <enumeratedValue>
                  <name>0</name>
                  <description>Interrupt request is generated on a PLL loss of lock indication. The PLL loss of lock interrupt enable bit must also be set to generate the interrupt request.</description>
                  <value>#0</value>
                </enumeratedValue>
                <enumeratedValue>
                  <name>1</name>
                  <description>Generate a reset request on a PLL loss of lock indication.</description>
                  <value>#1</value>
                </enumeratedValue>
              </enumeratedValues>
            </field>
          </fields>
        </register>
        <register>
          <name>C9</name>
          <description>MCG Control 9 Register</description>
          <addressOffset>0xE</addressOffset>
          <size>8</size>
          <access>read-only</access>
          <resetValue>0</resetValue>
          <resetMask>0xFF</resetMask>
        </register>
        <register>
          <name>C10</name>
          <description>MCG Control 10 Register</description>
          <addressOffset>0xF</addressOffset>
          <size>8</size>
          <access>read-only</access>
          <resetValue>0</resetValue>
          <resetMask>0xFF</resetMask>
        </register>
      </registers>
    </peripheral>
    <peripheral>
      <name>OSC0</name>
      <description>Oscillator</description>
      <prependToName>OSC0_</prependToName>
      <baseAddress>0x40065000</baseAddress>
      <addressBlock>
        <offset>0</offset>
        <size>0x1</size>
        <usage>registers</usage>
      </addressBlock>
      <registers>
        <register>
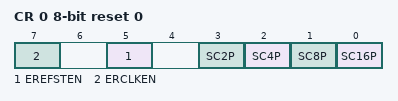
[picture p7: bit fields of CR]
          <name>CR</name>
          <description>OSC Control Register</description>
          <addressOffset>0</addressOffset>
          <size>8</size>
          <access>read-write</access>
          <resetValue>0</resetValue>
          <resetMask>0xFF</resetMask>
          <fields>
            <field>
              <name>SC16P</name>
              <description>Oscillator 16 pF Capacitor Load Configure</description>
              <bitOffset>0</bitOffset>
              <bitWidth>1</bitWidth>
              <access>read-write</access>
              <enumeratedValues>
                <enumeratedValue>
                  <name>0</name>
                  <description>Disable the selection.</description>
                  <value>#0</value>
                </enumeratedValue>
                <enumeratedValue>
                  <name>1</name>
                  <description>Add 16 pF capacitor to the oscillator load.</description>
                  <value>#1</value>
                </enumeratedValue>
              </enumeratedValues>
            </field>
            <field>
              <name>SC8P</name>
              <description>Oscillator 8 pF Capacitor Load Configure</description>
              <bitOffset>1</bitOffset>
              <bitWidth>1</bitWidth>
              <access>read-write</access>
              <enumeratedValues>
                <enumeratedValue>
                  <name>0</name>
                  <description>Disable the selection.</description>
                  <value>#0</value>
                </enumeratedValue>
                <enumeratedValue>
                  <name>1</name>
                  <description>Add 8 pF capacitor to the oscillator load.</description>
                  <value>#1</value>
                </enumeratedValue>
              </enumeratedValues>
            </field>
            <field>
              <name>SC4P</name>
              <description>Oscillator 4 pF Capacitor Load Configure</description>
              <bitOffset>2</bitOffset>
              <bitWidth>1</bitWidth>
              <access>read-write</access>
              <enumeratedValues>
                <enumeratedValue>
                  <name>0</name>
                  <description>Disable the selection.</description>
                  <value>#0</value>
                </enumeratedValue>
                <enumeratedValue>
                  <name>1</name>
                  <description>Add 4 pF capacitor to the oscillator load.</description>
                  <value>#1</value>
                </enumeratedValue>
              </enumeratedValues>
            </field>
            <field>
              <name>SC2P</name>
              <description>Oscillator 2 pF Capacitor Load Configure</description>
              <bitOffset>3</bitOffset>
              <bitWidth>1</bitWidth>
              <access>read-write</access>
              <enumeratedValues>
                <enumeratedValue>
                  <name>0</name>
                  <description>Disable the selection.</description>
                  <value>#0</value>
                </enumeratedValue>
                <enumeratedValue>
                  <name>1</name>
                  <description>Add 2 pF capacitor to the oscillator load.</description>
                  <value>#1</value>
                </enumeratedValue>
              </enumeratedValues>
            </field>
            <field>
              <name>EREFSTEN</name>
              <description>External Reference Stop Enable</description>
              <bitOffset>5</bitOffset>
              <bitWidth>1</bitWidth>
              <access>read-write</access>
              <enumeratedValues>
                <enumeratedValue>
                  <name>0</name>
                  <description>External reference clock is disabled in Stop mode.</description>
                  <value>#0</value>
                </enumeratedValue>
                <enumeratedValue>
                  <name>1</name>
                  <description>External reference clock stays enabled in Stop mode if ERCLKEN is set before entering Stop mode.</description>
                  <value>#1</value>
                </enumeratedValue>
              </enumeratedValues>
            </field>
            <field>
              <name>ERCLKEN</name>
              <description>External Reference Enable</description>
              <bitOffset>7</bitOffset>
              <bitWidth>1</bitWidth>
              <access>read-write</access>
              <enumeratedValues>
                <enumeratedValue>
                  <name>0</name>
                  <description>External reference clock is inactive.</description>
                  <value>#0</value>
                </enumeratedValue>
                <enumeratedValue>
                  <name>1</name>
                  <description>External reference clock is enabled.</description>
                  <value>#1</value>
                </enumeratedValue>
              </enumeratedValues>
            </field>
          </fields>
        </register>
      </registers>
    </peripheral>
    <peripheral>
      <name>I2C0</name>
      <description>Inter-Integrated Circuit</description>
      <groupName>I2C</groupName>
      <prependToName>I2C0_</prependToName>
      <baseAddress>0x40066000</baseAddress>
      <addressBlock>
        <offset>0</offset>
        <size>0xC</size>
        <usage>registers</usage>
      </addressBlock>
      <interrupt>
        <name>I2C0</name>
        <value>8</value>
      </interrupt>
      <registers>
        <register>
          <name>A1</name>
          <description>I2C Address Register 1</description>
          <addressOffset>0</addressOffset>
          <size>8</size>
          <access>read-write</access>
          <resetValue>0</resetValue>
          <resetMask>0xFF</resetMask>
          <fields>
            <field>
              <name>AD</name>
              <description>Address</description>
              <bitOffset>1</bitOffset>
              <bitWidth>7</bitWidth>
              <access>read-write</access>
            </field>
          </fields>
        </register>
        <register>
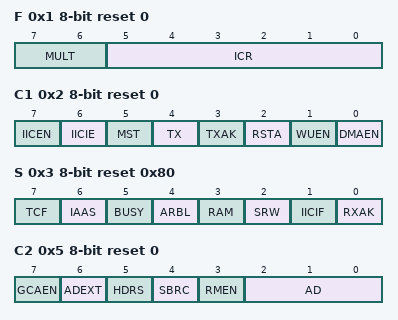
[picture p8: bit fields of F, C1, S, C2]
          <name>F</name>
          <description>I2C Frequency Divider register</description>
          <addressOffset>0x1</addressOffset>
          <size>8</size>
          <access>read-write</access>
          <resetValue>0</resetValue>
          <resetMask>0xFF</resetMask>
          <fields>
            <field>
              <name>ICR</name>
              <description>ClockRate</description>
              <bitOffset>0</bitOffset>
              <bitWidth>6</bitWidth>
              <access>read-write</access>
            </field>
            <field>
              <name>MULT</name>
              <description>Multiplier Factor</description>
              <bitOffset>6</bitOffset>
              <bitWidth>2</bitWidth>
              <access>read-write</access>
              <enumeratedValues>
                <enumeratedValue>
                  <name>00</name>
                  <description>mul = 1</description>
                  <value>#00</value>
                </enumeratedValue>
                <enumeratedValue>
                  <name>01</name>
                  <description>mul = 2</description>
                  <value>#01</value>
                </enumeratedValue>
                <enumeratedValue>
                  <name>10</name>
                  <description>mul = 4</description>
                  <value>#10</value>
                </enumeratedValue>
              </enumeratedValues>
            </field>
          </fields>
        </register>
        <register>
          <name>C1</name>
          <description>I2C Control Register 1</description>
          <addressOffset>0x2</addressOffset>
          <size>8</size>
          <access>read-write</access>
          <resetValue>0</resetValue>
          <resetMask>0xFF</resetMask>
          <fields>
            <field>
              <name>DMAEN</name>
              <description>DMA Enable</description>
              <bitOffset>0</bitOffset>
              <bitWidth>1</bitWidth>
              <access>read-write</access>
              <enumeratedValues>
                <enumeratedValue>
                  <name>0</name>
                  <description>All DMA signalling disabled.</description>
                  <value>#0</value>
                </enumeratedValue>
                <enumeratedValue>
                  <name>1</name>
                  <description>DMA transfer is enabled. While SMB[FACK] = 0, the following conditions trigger the DMA request: a data byte is received, and either address or data is transmitted. (ACK/NACK is automatic) the first byte received matches the A1 register or is a general call address. If any address matching occurs, S[IAAS] and S[TCF] are set. If the direction of transfer is known from master to slave, then it is not required to check S[SRW]. With this assumption, DMA can also be used in this case. In other cases, if the master reads data from the slave, then it is required to rewrite the C1 register operation. With this assumption, DMA cannot be used. When FACK = 1, an address or a data byte is transmitted.</description>
                  <value>#1</value>
                </enumeratedValue>
              </enumeratedValues>
            </field>
            <field>
              <name>WUEN</name>
              <description>Wakeup Enable</description>
              <bitOffset>1</bitOffset>
              <bitWidth>1</bitWidth>
              <access>read-write</access>
              <enumeratedValues>
                <enumeratedValue>
                  <name>0</name>
                  <description>Normal operation. No interrupt generated when address matching in low power mode.</description>
                  <value>#0</value>
                </enumeratedValue>
                <enumeratedValue>
                  <name>1</name>
                  <description>Enables the wakeup function in low power mode.</description>
                  <value>#1</value>
                </enumeratedValue>
              </enumeratedValues>
            </field>
            <field>
              <name>RSTA</name>
              <description>Repeat START</description>
              <bitOffset>2</bitOffset>
              <bitWidth>1</bitWidth>
              <access>write-only</access>
            </field>
            <field>
              <name>TXAK</name>
              <description>Transmit Acknowledge Enable</description>
              <bitOffset>3</bitOffset>
              <bitWidth>1</bitWidth>
              <access>read-write</access>
              <enumeratedValues>
                <enumeratedValue>
                  <name>0</name>
                  <description>An acknowledge signal is sent to the bus on the following receiving byte (if FACK is cleared) or the current receiving byte (if FACK is set).</description>
                  <value>#0</value>
                </enumeratedValue>
                <enumeratedValue>
                  <name>1</name>
                  <description>No acknowledge signal is sent to the bus on the following receiving data byte (if FACK is cleared) or the current receiving data byte (if FACK is set).</description>
                  <value>#1</value>
                </enumeratedValue>
              </enumeratedValues>
            </field>
            <field>
              <name>TX</name>
              <description>Transmit Mode Select</description>
              <bitOffset>4</bitOffset>
              <bitWidth>1</bitWidth>
              <access>read-write</access>
              <enumeratedValues>
                <enumeratedValue>
                  <name>0</name>
                  <description>Receive</description>
                  <value>#0</value>
                </enumeratedValue>
                <enumeratedValue>
                  <name>1</name>
                  <description>Transmit</description>
                  <value>#1</value>
                </enumeratedValue>
              </enumeratedValues>
            </field>
            <field>
              <name>MST</name>
              <description>Master Mode Select</description>
              <bitOffset>5</bitOffset>
              <bitWidth>1</bitWidth>
              <access>read-write</access>
              <enumeratedValues>
                <enumeratedValue>
                  <name>0</name>
                  <description>Slave mode</description>
                  <value>#0</value>
                </enumeratedValue>
                <enumeratedValue>
                  <name>1</name>
                  <description>Master mode</description>
                  <value>#1</value>
                </enumeratedValue>
              </enumeratedValues>
            </field>
            <field>
              <name>IICIE</name>
              <description>I2C Interrupt Enable</description>
              <bitOffset>6</bitOffset>
              <bitWidth>1</bitWidth>
              <access>read-write</access>
              <enumeratedValues>
                <enumeratedValue>
                  <name>0</name>
                  <description>Disabled</description>
                  <value>#0</value>
                </enumeratedValue>
                <enumeratedValue>
                  <name>1</name>
                  <description>Enabled</description>
                  <value>#1</value>
                </enumeratedValue>
              </enumeratedValues>
            </field>
            <field>
              <name>IICEN</name>
              <description>I2C Enable</description>
              <bitOffset>7</bitOffset>
              <bitWidth>1</bitWidth>
              <access>read-write</access>
              <enumeratedValues>
                <enumeratedValue>
                  <name>0</name>
                  <description>Disabled</description>
                  <value>#0</value>
                </enumeratedValue>
                <enumeratedValue>
                  <name>1</name>
                  <description>Enabled</description>
                  <value>#1</value>
                </enumeratedValue>
              </enumeratedValues>
            </field>
          </fields>
        </register>
        <register>
          <name>S</name>
          <description>I2C Status register</description>
          <addressOffset>0x3</addressOffset>
          <size>8</size>
          <access>read-write</access>
          <resetValue>0x80</resetValue>
          <resetMask>0xFF</resetMask>
          <fields>
            <field>
              <name>RXAK</name>
              <description>Receive Acknowledge</description>
              <bitOffset>0</bitOffset>
              <bitWidth>1</bitWidth>
              <access>read-only</access>
              <enumeratedValues>
                <enumeratedValue>
                  <name>0</name>
                  <description>Acknowledge signal was received after the completion of one byte of data transmission on the bus</description>
                  <value>#0</value>
                </enumeratedValue>
                <enumeratedValue>
                  <name>1</name>
                  <description>No acknowledge signal detected</description>
                  <value>#1</value>
                </enumeratedValue>
              </enumeratedValues>
            </field>
            <field>
              <name>IICIF</name>
              <description>Interrupt Flag</description>
              <bitOffset>1</bitOffset>
              <bitWidth>1</bitWidth>
              <access>read-write</access>
              <enumeratedValues>
                <enumeratedValue>
                  <name>0</name>
                  <description>No interrupt pending</description>
                  <value>#0</value>
                </enumeratedValue>
                <enumeratedValue>
                  <name>1</name>
                  <description>Interrupt pending</description>
                  <value>#1</value>
                </enumeratedValue>
              </enumeratedValues>
            </field>
            <field>
              <name>SRW</name>
              <description>Slave Read/Write</description>
              <bitOffset>2</bitOffset>
              <bitWidth>1</bitWidth>
              <access>read-only</access>
              <enumeratedValues>
                <enumeratedValue>
                  <name>0</name>
                  <description>Slave receive, master writing to slave</description>
                  <value>#0</value>
                </enumeratedValue>
                <enumeratedValue>
                  <name>1</name>
                  <description>Slave transmit, master reading from slave</description>
                  <value>#1</value>
                </enumeratedValue>
              </enumeratedValues>
            </field>
            <field>
              <name>RAM</name>
              <description>Range Address Match</description>
              <bitOffset>3</bitOffset>
              <bitWidth>1</bitWidth>
              <access>read-write</access>
              <enumeratedValues>
                <enumeratedValue>
                  <name>0</name>
                  <description>Not addressed</description>
                  <value>#0</value>
                </enumeratedValue>
                <enumeratedValue>
                  <name>1</name>
                  <description>Addressed as a slave</description>
                  <value>#1</value>
                </enumeratedValue>
              </enumeratedValues>
            </field>
            <field>
              <name>ARBL</name>
              <description>Arbitration Lost</description>
              <bitOffset>4</bitOffset>
              <bitWidth>1</bitWidth>
              <access>read-write</access>
              <enumeratedValues>
                <enumeratedValue>
                  <name>0</name>
                  <description>Standard bus operation.</description>
                  <value>#0</value>
                </enumeratedValue>
                <enumeratedValue>
                  <name>1</name>
                  <description>Loss of arbitration.</description>
                  <value>#1</value>
                </enumeratedValue>
              </enumeratedValues>
            </field>
            <field>
              <name>BUSY</name>
              <description>Bus Busy</description>
              <bitOffset>5</bitOffset>
              <bitWidth>1</bitWidth>
              <access>read-only</access>
              <enumeratedValues>
                <enumeratedValue>
                  <name>0</name>
                  <description>Bus is idle</description>
                  <value>#0</value>
                </enumeratedValue>
                <enumeratedValue>
                  <name>1</name>
                  <description>Bus is busy</description>
                  <value>#1</value>
                </enumeratedValue>
              </enumeratedValues>
            </field>
            <field>
              <name>IAAS</name>
              <description>Addressed As A Slave</description>
              <bitOffset>6</bitOffset>
              <bitWidth>1</bitWidth>
              <access>read-write</access>
              <enumeratedValues>
                <enumeratedValue>
                  <name>0</name>
                  <description>Not addressed</description>
                  <value>#0</value>
                </enumeratedValue>
                <enumeratedValue>
                  <name>1</name>
                  <description>Addressed as a slave</description>
                  <value>#1</value>
                </enumeratedValue>
              </enumeratedValues>
            </field>
            <field>
              <name>TCF</name>
              <description>Transfer Complete Flag</description>
              <bitOffset>7</bitOffset>
              <bitWidth>1</bitWidth>
              <access>read-only</access>
              <enumeratedValues>
                <enumeratedValue>
                  <name>0</name>
                  <description>Transfer in progress</description>
                  <value>#0</value>
                </enumeratedValue>
                <enumeratedValue>
                  <name>1</name>
                  <description>Transfer complete</description>
                  <value>#1</value>
                </enumeratedValue>
              </enumeratedValues>
            </field>
          </fields>
        </register>
        <register>
          <name>D</name>
          <description>I2C Data I/O register</description>
          <addressOffset>0x4</addressOffset>
          <size>8</size>
          <access>read-write</access>
          <resetValue>0</resetValue>
          <resetMask>0xFF</resetMask>
          <fields>
            <field>
              <name>DATA</name>
              <description>Data</description>
              <bitOffset>0</bitOffset>
              <bitWidth>8</bitWidth>
              <access>read-write</access>
            </field>
          </fields>
        </register>
        <register>
          <name>C2</name>
          <description>I2C Control Register 2</description>
          <addressOffset>0x5</addressOffset>
          <size>8</size>
          <access>read-write</access>
          <resetValue>0</resetValue>
          <resetMask>0xFF</resetMask>
          <fields>
            <field>
              <name>AD</name>
              <description>Slave Address</description>
              <bitOffset>0</bitOffset>
              <bitWidth>3</bitWidth>
              <access>read-write</access>
            </field>
            <field>
              <name>RMEN</name>
              <description>Range Address Matching Enable</description>
              <bitOffset>3</bitOffset>
              <bitWidth>1</bitWidth>
              <access>read-write</access>
              <enumeratedValues>
                <enumeratedValue>
                  <name>0</name>
                  <description>Range mode disabled. No address match occurs for an address within the range of values of the A1 and RA registers.</description>
                  <value>#0</value>
                </enumeratedValue>
                <enumeratedValue>
                  <name>1</name>
                  <description>Range mode enabled. Address matching occurs when a slave receives an address within the range of values of the A1 and RA registers.</description>
                  <value>#1</value>
                </enumeratedValue>
              </enumeratedValues>
            </field>
            <field>
              <name>SBRC</name>
              <description>Slave Baud Rate Control</description>
              <bitOffset>4</bitOffset>
              <bitWidth>1</bitWidth>
              <access>read-write</access>
              <enumeratedValues>
                <enumeratedValue>
                  <name>0</name>
                  <description>The slave baud rate follows the master baud rate and clock stretching may occur</description>
                  <value>#0</value>
                </enumeratedValue>
                <enumeratedValue>
                  <name>1</name>
                  <description>Slave baud rate is independent of the master baud rate</description>
                  <value>#1</value>
                </enumeratedValue>
              </enumeratedValues>
            </field>
            <field>
              <name>HDRS</name>
              <description>High Drive Select</description>
              <bitOffset>5</bitOffset>
              <bitWidth>1</bitWidth>
              <access>read-write</access>
              <enumeratedValues>
                <enumeratedValue>
                  <name>0</name>
                  <description>Normal drive mode</description>
                  <value>#0</value>
                </enumeratedValue>
                <enumeratedValue>
                  <name>1</name>
                  <description>High drive mode</description>
                  <value>#1</value>
                </enumeratedValue>
              </enumeratedValues>
            </field>
            <field>
              <name>ADEXT</name>
              <description>Address Extension</description>
              <bitOffset>6</bitOffset>
              <bitWidth>1</bitWidth>
              <access>read-write</access>
              <enumeratedValues>
                <enumeratedValue>
                  <name>0</name>
                  <description>7-bit address scheme</description>
                  <value>#0</value>
                </enumeratedValue>
                <enumeratedValue>
                  <name>1</name>
                  <description>10-bit address scheme</description>
                  <value>#1</value>
                </enumeratedValue>
              </enumeratedValues>
            </field>
            <field>
              <name>GCAEN</name>
              <description>General Call Address Enable</description>
              <bitOffset>7</bitOffset>
              <bitWidth>1</bitWidth>
              <access>read-write</access>
              <enumeratedValues>
                <enumeratedValue>
                  <name>0</name>
                  <description>Disabled</description>
                  <value>#0</value>
                </enumeratedValue>
                <enumeratedValue>
                  <name>1</name>
                  <description>Enabled</description>
                  <value>#1</value>
                </enumeratedValue>
              </enumeratedValues>
            </field>
          </fields>
        </register>
        <register>
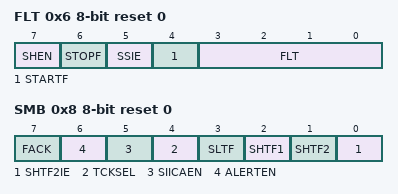
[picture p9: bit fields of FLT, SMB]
          <name>FLT</name>
          <description>I2C Programmable Input Glitch Filter register</description>
          <addressOffset>0x6</addressOffset>
          <size>8</size>
          <access>read-write</access>
          <resetValue>0</resetValue>
          <resetMask>0xFF</resetMask>
          <fields>
            <field>
              <name>FLT</name>
              <description>I2C Programmable Filter Factor</description>
              <bitOffset>0</bitOffset>
              <bitWidth>4</bitWidth>
              <access>read-write</access>
              <enumeratedValues>
                <enumeratedValue>
                  <name>0</name>
                  <description>No filter/bypass</description>
                  <value>#0000</value>
                </enumeratedValue>
              </enumeratedValues>
            </field>
            <field>
              <name>STARTF</name>
              <description>I2C Bus Start Detect Flag</description>
              <bitOffset>4</bitOffset>
              <bitWidth>1</bitWidth>
              <access>read-write</access>
              <enumeratedValues>
                <enumeratedValue>
                  <name>0</name>
                  <description>No start happens on I2C bus</description>
                  <value>#0</value>
                </enumeratedValue>
                <enumeratedValue>
                  <name>1</name>
                  <description>Start detected on I2C bus</description>
                  <value>#1</value>
                </enumeratedValue>
              </enumeratedValues>
            </field>
            <field>
              <name>SSIE</name>
              <description>I2C Bus Stop or Start Interrupt Enable</description>
              <bitOffset>5</bitOffset>
              <bitWidth>1</bitWidth>
              <access>read-write</access>
              <enumeratedValues>
                <enumeratedValue>
                  <name>0</name>
                  <description>Stop or start detection interrupt is disabled</description>
                  <value>#0</value>
                </enumeratedValue>
                <enumeratedValue>
                  <name>1</name>
                  <description>Stop or start detection interrupt is enabled</description>
                  <value>#1</value>
                </enumeratedValue>
              </enumeratedValues>
            </field>
            <field>
              <name>STOPF</name>
              <description>I2C Bus Stop Detect Flag</description>
              <bitOffset>6</bitOffset>
              <bitWidth>1</bitWidth>
              <access>read-write</access>
              <enumeratedValues>
                <enumeratedValue>
                  <name>0</name>
                  <description>No stop happens on I2C bus</description>
                  <value>#0</value>
                </enumeratedValue>
                <enumeratedValue>
                  <name>1</name>
                  <description>Stop detected on I2C bus</description>
                  <value>#1</value>
                </enumeratedValue>
              </enumeratedValues>
            </field>
            <field>
              <name>SHEN</name>
              <description>Stop Hold Enable</description>
              <bitOffset>7</bitOffset>
              <bitWidth>1</bitWidth>
              <access>read-write</access>
              <enumeratedValues>
                <enumeratedValue>
                  <name>0</name>
                  <description>Stop holdoff is disabled. The MCU&apos;s entry to stop mode is not gated.</description>
                  <value>#0</value>
                </enumeratedValue>
                <enumeratedValue>
                  <name>1</name>
                  <description>Stop holdoff is enabled.</description>
                  <value>#1</value>
                </enumeratedValue>
              </enumeratedValues>
            </field>
          </fields>
        </register>
        <register>
          <name>RA</name>
          <description>I2C Range Address register</description>
          <addressOffset>0x7</addressOffset>
          <size>8</size>
          <access>read-write</access>
          <resetValue>0</resetValue>
          <resetMask>0xFF</resetMask>
          <fields>
            <field>
              <name>RAD</name>
              <description>Range Slave Address</description>
              <bitOffset>1</bitOffset>
              <bitWidth>7</bitWidth>
              <access>read-write</access>
            </field>
          </fields>
        </register>
        <register>
          <name>SMB</name>
          <description>I2C SMBus Control and Status register</description>
          <addressOffset>0x8</addressOffset>
          <size>8</size>
          <access>read-write</access>
          <resetValue>0</resetValue>
          <resetMask>0xFF</resetMask>
          <fields>
            <field>
              <name>SHTF2IE</name>
              <description>SHTF2 Interrupt Enable</description>
              <bitOffset>0</bitOffset>
              <bitWidth>1</bitWidth>
              <access>read-write</access>
              <enumeratedValues>
                <enumeratedValue>
                  <name>0</name>
                  <description>SHTF2 interrupt is disabled</description>
                  <value>#0</value>
                </enumeratedValue>
                <enumeratedValue>
                  <name>1</name>
                  <description>SHTF2 interrupt is enabled</description>
                  <value>#1</value>
                </enumeratedValue>
              </enumeratedValues>
            </field>
            <field>
              <name>SHTF2</name>
              <description>SCL High Timeout Flag 2</description>
              <bitOffset>1</bitOffset>
              <bitWidth>1</bitWidth>
              <access>read-write</access>
              <enumeratedValues>
                <enumeratedValue>
                  <name>0</name>
                  <description>No SCL high and SDA low timeout occurs</description>
                  <value>#0</value>
                </enumeratedValue>
                <enumeratedValue>
                  <name>1</name>
                  <description>SCL high and SDA low timeout occurs</description>
                  <value>#1</value>
                </enumeratedValue>
              </enumeratedValues>
            </field>
            <field>
              <name>SHTF1</name>
              <description>SCL High Timeout Flag 1</description>
              <bitOffset>2</bitOffset>
              <bitWidth>1</bitWidth>
              <access>read-only</access>
              <enumeratedValues>
                <enumeratedValue>
                  <name>0</name>
                  <description>No SCL high and SDA high timeout occurs</description>
                  <value>#0</value>
                </enumeratedValue>
                <enumeratedValue>
                  <name>1</name>
                  <description>SCL high and SDA high timeout occurs</description>
                  <value>#1</value>
                </enumeratedValue>
              </enumeratedValues>
            </field>
            <field>
              <name>SLTF</name>
              <description>SCL Low Timeout Flag</description>
              <bitOffset>3</bitOffset>
              <bitWidth>1</bitWidth>
              <access>read-write</access>
              <enumeratedValues>
                <enumeratedValue>
                  <name>0</name>
                  <description>No low timeout occurs</description>
                  <value>#0</value>
                </enumeratedValue>
                <enumeratedValue>
                  <name>1</name>
                  <description>Low timeout occurs</description>
                  <value>#1</value>
                </enumeratedValue>
              </enumeratedValues>
            </field>
            <field>
              <name>TCKSEL</name>
              <description>Timeout Counter Clock Select</description>
              <bitOffset>4</bitOffset>
              <bitWidth>1</bitWidth>
              <access>read-write</access>
              <enumeratedValues>
                <enumeratedValue>
                  <name>0</name>
                  <description>Timeout counter counts at the frequency of the I2C module clock / 64</description>
                  <value>#0</value>
                </enumeratedValue>
                <enumeratedValue>
                  <name>1</name>
                  <description>Timeout counter counts at the frequency of the I2C module clock</description>
                  <value>#1</value>
                </enumeratedValue>
              </enumeratedValues>
            </field>
            <field>
              <name>SIICAEN</name>
              <description>Second I2C Address Enable</description>
              <bitOffset>5</bitOffset>
              <bitWidth>1</bitWidth>
              <access>read-write</access>
              <enumeratedValues>
                <enumeratedValue>
                  <name>0</name>
                  <description>I2C address register 2 matching is disabled</description>
                  <value>#0</value>
                </enumeratedValue>
                <enumeratedValue>
                  <name>1</name>
                  <description>I2C address register 2 matching is enabled</description>
                  <value>#1</value>
                </enumeratedValue>
              </enumeratedValues>
            </field>
            <field>
              <name>ALERTEN</name>
              <description>SMBus Alert Response Address Enable</description>
              <bitOffset>6</bitOffset>
              <bitWidth>1</bitWidth>
              <access>read-write</access>
              <enumeratedValues>
                <enumeratedValue>
                  <name>0</name>
                  <description>SMBus alert response address matching is disabled</description>
                  <value>#0</value>
                </enumeratedValue>
                <enumeratedValue>
                  <name>1</name>
                  <description>SMBus alert response address matching is enabled</description>
                  <value>#1</value>
                </enumeratedValue>
              </enumeratedValues>
            </field>
            <field>
              <name>FACK</name>
              <description>Fast NACK/ACK Enable</description>
              <bitOffset>7</bitOffset>
              <bitWidth>1</bitWidth>
              <access>read-write</access>
              <enumeratedValues>
                <enumeratedValue>
                  <name>0</name>
                  <description>An ACK or NACK is sent on the following receiving data byte</description>
                  <value>#0</value>
                </enumeratedValue>
                <enumeratedValue>
                  <name>1</name>
                  <description>Writing 0 to TXAK after receiving a data byte generates an ACK. Writing 1 to TXAK after receiving a data byte generates a NACK.</description>
                  <value>#1</value>
                </enumeratedValue>
              </enumeratedValues>
            </field>
          </fields>
        </register>
        <register>
          <name>A2</name>
          <description>I2C Address Register 2</description>
          <addressOffset>0x9</addressOffset>
          <size>8</size>
          <access>read-write</access>
          <resetValue>0xC2</resetValue>
          <resetMask>0xFF</resetMask>
          <fields>
            <field>
              <name>SAD</name>
              <description>SMBus Address</description>
              <bitOffset>1</bitOffset>
              <bitWidth>7</bitWidth>
              <access>read-write</access>
            </field>
          </fields>
        </register>
        <register>
          <name>SLTH</name>
          <description>I2C SCL Low Timeout Register High</description>
          <addressOffset>0xA</addressOffset>
          <size>8</size>
          <access>read-write</access>
          <resetValue>0</resetValue>
          <resetMask>0xFF</resetMask>
          <fields>
            <field>
              <name>SSLT</name>
              <description>Most significant byte of SCL low timeout value that determines the timeout period of SCL low.</description>
              <bitOffset>0</bitOffset>
              <bitWidth>8</bitWidth>
              <access>read-write</access>
            </field>
          </fields>
        </register>
        <register>
          <name>SLTL</name>
          <description>I2C SCL Low Timeout Register Low</description>
          <addressOffset>0xB</addressOffset>
          <size>8</size>
          <access>read-write</access>
          <resetValue>0</resetValue>
          <resetMask>0xFF</resetMask>
          <fields>
            <field>
              <name>SSLT</name>
              <description>Least significant byte of SCL low timeout value that determines the timeout period of SCL low.</description>
              <bitOffset>0</bitOffset>
              <bitWidth>8</bitWidth>
              <access>read-write</access>
            </field>
          </fields>
        </register>
      </registers>
    </peripheral>
    <peripheral>
      <name>I2C1</name>
      <description>Inter-Integrated Circuit</description>
      <groupName>I2C</groupName>
      <prependToName>I2C1_</prependToName>
      <baseAddress>0x40067000</baseAddress>
      <addressBlock>
        <offset>0</offset>
        <size>0xC</size>
        <usage>registers</usage>
      </addressBlock>
      <interrupt>
        <name>I2C1</name>
        <value>9</value>
      </interrupt>
      <registers>
        <register>
          <name>A1</name>
          <description>I2C Address Register 1</description>
          <addressOffset>0</addressOffset>
          <size>8</size>
          <access>read-write</access>
          <resetValue>0</resetValue>
          <resetMask>0xFF</resetMask>
          <fields>
            <field>
              <name>AD</name>
              <description>Address</description>
              <bitOffset>1</bitOffset>
              <bitWidth>7</bitWidth>
              <access>read-write</access>
            </field>
          </fields>
        </register>
        <register>
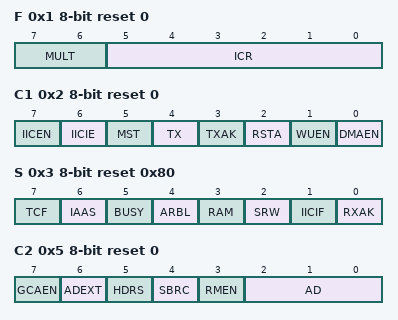
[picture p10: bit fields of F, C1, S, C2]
          <name>F</name>
          <description>I2C Frequency Divider register</description>
          <addressOffset>0x1</addressOffset>
          <size>8</size>
          <access>read-write</access>
          <resetValue>0</resetValue>
          <resetMask>0xFF</resetMask>
          <fields>
            <field>
              <name>ICR</name>
              <description>ClockRate</description>
              <bitOffset>0</bitOffset>
              <bitWidth>6</bitWidth>
              <access>read-write</access>
            </field>
            <field>
              <name>MULT</name>
              <description>Multiplier Factor</description>
              <bitOffset>6</bitOffset>
              <bitWidth>2</bitWidth>
              <access>read-write</access>
              <enumeratedValues>
                <enumeratedValue>
                  <name>00</name>
                  <description>mul = 1</description>
                  <value>#00</value>
                </enumeratedValue>
                <enumeratedValue>
                  <name>01</name>
                  <description>mul = 2</description>
                  <value>#01</value>
                </enumeratedValue>
                <enumeratedValue>
                  <name>10</name>
                  <description>mul = 4</description>
                  <value>#10</value>
                </enumeratedValue>
              </enumeratedValues>
            </field>
          </fields>
        </register>
        <register>
          <name>C1</name>
          <description>I2C Control Register 1</description>
          <addressOffset>0x2</addressOffset>
          <size>8</size>
          <access>read-write</access>
          <resetValue>0</resetValue>
          <resetMask>0xFF</resetMask>
          <fields>
            <field>
              <name>DMAEN</name>
              <description>DMA Enable</description>
              <bitOffset>0</bitOffset>
              <bitWidth>1</bitWidth>
              <access>read-write</access>
              <enumeratedValues>
                <enumeratedValue>
                  <name>0</name>
                  <description>All DMA signalling disabled.</description>
                  <value>#0</value>
                </enumeratedValue>
                <enumeratedValue>
                  <name>1</name>
                  <description>DMA transfer is enabled. While SMB[FACK] = 0, the following conditions trigger the DMA request: a data byte is received, and either address or data is transmitted. (ACK/NACK is automatic) the first byte received matches the A1 register or is a general call address. If any address matching occurs, S[IAAS] and S[TCF] are set. If the direction of transfer is known from master to slave, then it is not required to check S[SRW]. With this assumption, DMA can also be used in this case. In other cases, if the master reads data from the slave, then it is required to rewrite the C1 register operation. With this assumption, DMA cannot be used. When FACK = 1, an address or a data byte is transmitted.</description>
                  <value>#1</value>
                </enumeratedValue>
              </enumeratedValues>
            </field>
            <field>
              <name>WUEN</name>
              <description>Wakeup Enable</description>
              <bitOffset>1</bitOffset>
              <bitWidth>1</bitWidth>
              <access>read-write</access>
              <enumeratedValues>
                <enumeratedValue>
                  <name>0</name>
                  <description>Normal operation. No interrupt generated when address matching in low power mode.</description>
                  <value>#0</value>
                </enumeratedValue>
                <enumeratedValue>
                  <name>1</name>
                  <description>Enables the wakeup function in low power mode.</description>
                  <value>#1</value>
                </enumeratedValue>
              </enumeratedValues>
            </field>
            <field>
              <name>RSTA</name>
              <description>Repeat START</description>
              <bitOffset>2</bitOffset>
              <bitWidth>1</bitWidth>
              <access>write-only</access>
            </field>
            <field>
              <name>TXAK</name>
              <description>Transmit Acknowledge Enable</description>
              <bitOffset>3</bitOffset>
              <bitWidth>1</bitWidth>
              <access>read-write</access>
              <enumeratedValues>
                <enumeratedValue>
                  <name>0</name>
                  <description>An acknowledge signal is sent to the bus on the following receiving byte (if FACK is cleared) or the current receiving byte (if FACK is set).</description>
                  <value>#0</value>
                </enumeratedValue>
                <enumeratedValue>
                  <name>1</name>
                  <description>No acknowledge signal is sent to the bus on the following receiving data byte (if FACK is cleared) or the current receiving data byte (if FACK is set).</description>
                  <value>#1</value>
                </enumeratedValue>
              </enumeratedValues>
            </field>
            <field>
              <name>TX</name>
              <description>Transmit Mode Select</description>
              <bitOffset>4</bitOffset>
              <bitWidth>1</bitWidth>
              <access>read-write</access>
              <enumeratedValues>
                <enumeratedValue>
                  <name>0</name>
                  <description>Receive</description>
                  <value>#0</value>
                </enumeratedValue>
                <enumeratedValue>
                  <name>1</name>
                  <description>Transmit</description>
                  <value>#1</value>
                </enumeratedValue>
              </enumeratedValues>
            </field>
            <field>
              <name>MST</name>
              <description>Master Mode Select</description>
              <bitOffset>5</bitOffset>
              <bitWidth>1</bitWidth>
              <access>read-write</access>
              <enumeratedValues>
                <enumeratedValue>
                  <name>0</name>
                  <description>Slave mode</description>
                  <value>#0</value>
                </enumeratedValue>
                <enumeratedValue>
                  <name>1</name>
                  <description>Master mode</description>
                  <value>#1</value>
                </enumeratedValue>
              </enumeratedValues>
            </field>
            <field>
              <name>IICIE</name>
              <description>I2C Interrupt Enable</description>
              <bitOffset>6</bitOffset>
              <bitWidth>1</bitWidth>
              <access>read-write</access>
              <enumeratedValues>
                <enumeratedValue>
                  <name>0</name>
                  <description>Disabled</description>
                  <value>#0</value>
                </enumeratedValue>
                <enumeratedValue>
                  <name>1</name>
                  <description>Enabled</description>
                  <value>#1</value>
                </enumeratedValue>
              </enumeratedValues>
            </field>
            <field>
              <name>IICEN</name>
              <description>I2C Enable</description>
              <bitOffset>7</bitOffset>
              <bitWidth>1</bitWidth>
              <access>read-write</access>
              <enumeratedValues>
                <enumeratedValue>
                  <name>0</name>
                  <description>Disabled</description>
                  <value>#0</value>
                </enumeratedValue>
                <enumeratedValue>
                  <name>1</name>
                  <description>Enabled</description>
                  <value>#1</value>
                </enumeratedValue>
              </enumeratedValues>
            </field>
          </fields>
        </register>
        <register>
          <name>S</name>
          <description>I2C Status register</description>
          <addressOffset>0x3</addressOffset>
          <size>8</size>
          <access>read-write</access>
          <resetValue>0x80</resetValue>
          <resetMask>0xFF</resetMask>
          <fields>
            <field>
              <name>RXAK</name>
              <description>Receive Acknowledge</description>
              <bitOffset>0</bitOffset>
              <bitWidth>1</bitWidth>
              <access>read-only</access>
              <enumeratedValues>
                <enumeratedValue>
                  <name>0</name>
                  <description>Acknowledge signal was received after the completion of one byte of data transmission on the bus</description>
                  <value>#0</value>
                </enumeratedValue>
                <enumeratedValue>
                  <name>1</name>
                  <description>No acknowledge signal detected</description>
                  <value>#1</value>
                </enumeratedValue>
              </enumeratedValues>
            </field>
            <field>
              <name>IICIF</name>
              <description>Interrupt Flag</description>
              <bitOffset>1</bitOffset>
              <bitWidth>1</bitWidth>
              <access>read-write</access>
              <enumeratedValues>
                <enumeratedValue>
                  <name>0</name>
                  <description>No interrupt pending</description>
                  <value>#0</value>
                </enumeratedValue>
                <enumeratedValue>
                  <name>1</name>
                  <description>Interrupt pending</description>
                  <value>#1</value>
                </enumeratedValue>
              </enumeratedValues>
            </field>
            <field>
              <name>SRW</name>
              <description>Slave Read/Write</description>
              <bitOffset>2</bitOffset>
              <bitWidth>1</bitWidth>
              <access>read-only</access>
              <enumeratedValues>
                <enumeratedValue>
                  <name>0</name>
                  <description>Slave receive, master writing to slave</description>
                  <value>#0</value>
                </enumeratedValue>
                <enumeratedValue>
                  <name>1</name>
                  <description>Slave transmit, master reading from slave</description>
                  <value>#1</value>
                </enumeratedValue>
              </enumeratedValues>
            </field>
            <field>
              <name>RAM</name>
              <description>Range Address Match</description>
              <bitOffset>3</bitOffset>
              <bitWidth>1</bitWidth>
              <access>read-write</access>
              <enumeratedValues>
                <enumeratedValue>
                  <name>0</name>
                  <description>Not addressed</description>
                  <value>#0</value>
                </enumeratedValue>
                <enumeratedValue>
                  <name>1</name>
                  <description>Addressed as a slave</description>
                  <value>#1</value>
                </enumeratedValue>
              </enumeratedValues>
            </field>
            <field>
              <name>ARBL</name>
              <description>Arbitration Lost</description>
              <bitOffset>4</bitOffset>
              <bitWidth>1</bitWidth>
              <access>read-write</access>
              <enumeratedValues>
                <enumeratedValue>
                  <name>0</name>
                  <description>Standard bus operation.</description>
                  <value>#0</value>
                </enumeratedValue>
                <enumeratedValue>
                  <name>1</name>
                  <description>Loss of arbitration.</description>
                  <value>#1</value>
                </enumeratedValue>
              </enumeratedValues>
            </field>
            <field>
              <name>BUSY</name>
              <description>Bus Busy</description>
              <bitOffset>5</bitOffset>
              <bitWidth>1</bitWidth>
              <access>read-only</access>
              <enumeratedValues>
                <enumeratedValue>
                  <name>0</name>
                  <description>Bus is idle</description>
                  <value>#0</value>
                </enumeratedValue>
                <enumeratedValue>
                  <name>1</name>
                  <description>Bus is busy</description>
                  <value>#1</value>
                </enumeratedValue>
              </enumeratedValues>
            </field>
            <field>
              <name>IAAS</name>
              <description>Addressed As A Slave</description>
              <bitOffset>6</bitOffset>
              <bitWidth>1</bitWidth>
              <access>read-write</access>
              <enumeratedValues>
                <enumeratedValue>
                  <name>0</name>
                  <description>Not addressed</description>
                  <value>#0</value>
                </enumeratedValue>
                <enumeratedValue>
                  <name>1</name>
                  <description>Addressed as a slave</description>
                  <value>#1</value>
                </enumeratedValue>
              </enumeratedValues>
            </field>
            <field>
              <name>TCF</name>
              <description>Transfer Complete Flag</description>
              <bitOffset>7</bitOffset>
              <bitWidth>1</bitWidth>
              <access>read-only</access>
              <enumeratedValues>
                <enumeratedValue>
                  <name>0</name>
                  <description>Transfer in progress</description>
                  <value>#0</value>
                </enumeratedValue>
                <enumeratedValue>
                  <name>1</name>
                  <description>Transfer complete</description>
                  <value>#1</value>
                </enumeratedValue>
              </enumeratedValues>
            </field>
          </fields>
        </register>
        <register>
          <name>D</name>
          <description>I2C Data I/O register</description>
          <addressOffset>0x4</addressOffset>
          <size>8</size>
          <access>read-write</access>
          <resetValue>0</resetValue>
          <resetMask>0xFF</resetMask>
          <fields>
            <field>
              <name>DATA</name>
              <description>Data</description>
              <bitOffset>0</bitOffset>
              <bitWidth>8</bitWidth>
              <access>read-write</access>
            </field>
          </fields>
        </register>
        <register>
          <name>C2</name>
          <description>I2C Control Register 2</description>
          <addressOffset>0x5</addressOffset>
          <size>8</size>
          <access>read-write</access>
          <resetValue>0</resetValue>
          <resetMask>0xFF</resetMask>
          <fields>
            <field>
              <name>AD</name>
              <description>Slave Address</description>
              <bitOffset>0</bitOffset>
              <bitWidth>3</bitWidth>
              <access>read-write</access>
            </field>
            <field>
              <name>RMEN</name>
              <description>Range Address Matching Enable</description>
              <bitOffset>3</bitOffset>
              <bitWidth>1</bitWidth>
              <access>read-write</access>
              <enumeratedValues>
                <enumeratedValue>
                  <name>0</name>
                  <description>Range mode disabled. No address match occurs for an address within the range of values of the A1 and RA registers.</description>
                  <value>#0</value>
                </enumeratedValue>
                <enumeratedValue>
                  <name>1</name>
                  <description>Range mode enabled. Address matching occurs when a slave receives an address within the range of values of the A1 and RA registers.</description>
                  <value>#1</value>
                </enumeratedValue>
              </enumeratedValues>
            </field>
            <field>
              <name>SBRC</name>
              <description>Slave Baud Rate Control</description>
              <bitOffset>4</bitOffset>
              <bitWidth>1</bitWidth>
              <access>read-write</access>
              <enumeratedValues>
                <enumeratedValue>
                  <name>0</name>
                  <description>The slave baud rate follows the master baud rate and clock stretching may occur</description>
                  <value>#0</value>
                </enumeratedValue>
                <enumeratedValue>
                  <name>1</name>
                  <description>Slave baud rate is independent of the master baud rate</description>
                  <value>#1</value>
                </enumeratedValue>
              </enumeratedValues>
            </field>
            <field>
              <name>HDRS</name>
              <description>High Drive Select</description>
              <bitOffset>5</bitOffset>
              <bitWidth>1</bitWidth>
              <access>read-write</access>
              <enumeratedValues>
                <enumeratedValue>
                  <name>0</name>
                  <description>Normal drive mode</description>
                  <value>#0</value>
                </enumeratedValue>
                <enumeratedValue>
                  <name>1</name>
                  <description>High drive mode</description>
                  <value>#1</value>
                </enumeratedValue>
              </enumeratedValues>
            </field>
            <field>
              <name>ADEXT</name>
              <description>Address Extension</description>
              <bitOffset>6</bitOffset>
              <bitWidth>1</bitWidth>
              <access>read-write</access>
              <enumeratedValues>
                <enumeratedValue>
                  <name>0</name>
                  <description>7-bit address scheme</description>
                  <value>#0</value>
                </enumeratedValue>
                <enumeratedValue>
                  <name>1</name>
                  <description>10-bit address scheme</description>
                  <value>#1</value>
                </enumeratedValue>
              </enumeratedValues>
            </field>
            <field>
              <name>GCAEN</name>
              <description>General Call Address Enable</description>
              <bitOffset>7</bitOffset>
              <bitWidth>1</bitWidth>
              <access>read-write</access>
              <enumeratedValues>
                <enumeratedValue>
                  <name>0</name>
                  <description>Disabled</description>
                  <value>#0</value>
                </enumeratedValue>
                <enumeratedValue>
                  <name>1</name>
                  <description>Enabled</description>
                  <value>#1</value>
                </enumeratedValue>
              </enumeratedValues>
            </field>
          </fields>
        </register>
        <register>
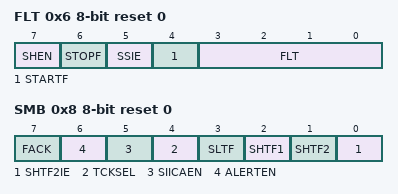
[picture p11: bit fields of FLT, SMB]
          <name>FLT</name>
          <description>I2C Programmable Input Glitch Filter register</description>
          <addressOffset>0x6</addressOffset>
          <size>8</size>
          <access>read-write</access>
          <resetValue>0</resetValue>
          <resetMask>0xFF</resetMask>
          <fields>
            <field>
              <name>FLT</name>
              <description>I2C Programmable Filter Factor</description>
              <bitOffset>0</bitOffset>
              <bitWidth>4</bitWidth>
              <access>read-write</access>
              <enumeratedValues>
                <enumeratedValue>
                  <name>0</name>
                  <description>No filter/bypass</description>
                  <value>#0000</value>
                </enumeratedValue>
              </enumeratedValues>
            </field>
            <field>
              <name>STARTF</name>
              <description>I2C Bus Start Detect Flag</description>
              <bitOffset>4</bitOffset>
              <bitWidth>1</bitWidth>
              <access>read-write</access>
              <enumeratedValues>
                <enumeratedValue>
                  <name>0</name>
                  <description>No start happens on I2C bus</description>
                  <value>#0</value>
                </enumeratedValue>
                <enumeratedValue>
                  <name>1</name>
                  <description>Start detected on I2C bus</description>
                  <value>#1</value>
                </enumeratedValue>
              </enumeratedValues>
            </field>
            <field>
              <name>SSIE</name>
              <description>I2C Bus Stop or Start Interrupt Enable</description>
              <bitOffset>5</bitOffset>
              <bitWidth>1</bitWidth>
              <access>read-write</access>
              <enumeratedValues>
                <enumeratedValue>
                  <name>0</name>
                  <description>Stop or start detection interrupt is disabled</description>
                  <value>#0</value>
                </enumeratedValue>
                <enumeratedValue>
                  <name>1</name>
                  <description>Stop or start detection interrupt is enabled</description>
                  <value>#1</value>
                </enumeratedValue>
              </enumeratedValues>
            </field>
            <field>
              <name>STOPF</name>
              <description>I2C Bus Stop Detect Flag</description>
              <bitOffset>6</bitOffset>
              <bitWidth>1</bitWidth>
              <access>read-write</access>
              <enumeratedValues>
                <enumeratedValue>
                  <name>0</name>
                  <description>No stop happens on I2C bus</description>
                  <value>#0</value>
                </enumeratedValue>
                <enumeratedValue>
                  <name>1</name>
                  <description>Stop detected on I2C bus</description>
                  <value>#1</value>
                </enumeratedValue>
              </enumeratedValues>
            </field>
            <field>
              <name>SHEN</name>
              <description>Stop Hold Enable</description>
              <bitOffset>7</bitOffset>
              <bitWidth>1</bitWidth>
              <access>read-write</access>
              <enumeratedValues>
                <enumeratedValue>
                  <name>0</name>
                  <description>Stop holdoff is disabled. The MCU&apos;s entry to stop mode is not gated.</description>
                  <value>#0</value>
                </enumeratedValue>
                <enumeratedValue>
                  <name>1</name>
                  <description>Stop holdoff is enabled.</description>
                  <value>#1</value>
                </enumeratedValue>
              </enumeratedValues>
            </field>
          </fields>
        </register>
        <register>
          <name>RA</name>
          <description>I2C Range Address register</description>
          <addressOffset>0x7</addressOffset>
          <size>8</size>
          <access>read-write</access>
          <resetValue>0</resetValue>
          <resetMask>0xFF</resetMask>
          <fields>
            <field>
              <name>RAD</name>
              <description>Range Slave Address</description>
              <bitOffset>1</bitOffset>
              <bitWidth>7</bitWidth>
              <access>read-write</access>
            </field>
          </fields>
        </register>
        <register>
          <name>SMB</name>
          <description>I2C SMBus Control and Status register</description>
          <addressOffset>0x8</addressOffset>
          <size>8</size>
          <access>read-write</access>
          <resetValue>0</resetValue>
          <resetMask>0xFF</resetMask>
          <fields>
            <field>
              <name>SHTF2IE</name>
              <description>SHTF2 Interrupt Enable</description>
              <bitOffset>0</bitOffset>
              <bitWidth>1</bitWidth>
              <access>read-write</access>
              <enumeratedValues>
                <enumeratedValue>
                  <name>0</name>
                  <description>SHTF2 interrupt is disabled</description>
                  <value>#0</value>
                </enumeratedValue>
                <enumeratedValue>
                  <name>1</name>
                  <description>SHTF2 interrupt is enabled</description>
                  <value>#1</value>
                </enumeratedValue>
              </enumeratedValues>
            </field>
            <field>
              <name>SHTF2</name>
              <description>SCL High Timeout Flag 2</description>
              <bitOffset>1</bitOffset>
              <bitWidth>1</bitWidth>
              <access>read-write</access>
              <enumeratedValues>
                <enumeratedValue>
                  <name>0</name>
                  <description>No SCL high and SDA low timeout occurs</description>
                  <value>#0</value>
                </enumeratedValue>
                <enumeratedValue>
                  <name>1</name>
                  <description>SCL high and SDA low timeout occurs</description>
                  <value>#1</value>
                </enumeratedValue>
              </enumeratedValues>
            </field>
            <field>
              <name>SHTF1</name>
              <description>SCL High Timeout Flag 1</description>
              <bitOffset>2</bitOffset>
              <bitWidth>1</bitWidth>
              <access>read-only</access>
              <enumeratedValues>
                <enumeratedValue>
                  <name>0</name>
                  <description>No SCL high and SDA high timeout occurs</description>
                  <value>#0</value>
                </enumeratedValue>
                <enumeratedValue>
                  <name>1</name>
                  <description>SCL high and SDA high timeout occurs</description>
                  <value>#1</value>
                </enumeratedValue>
              </enumeratedValues>
            </field>
            <field>
              <name>SLTF</name>
              <description>SCL Low Timeout Flag</description>
              <bitOffset>3</bitOffset>
              <bitWidth>1</bitWidth>
              <access>read-write</access>
              <enumeratedValues>
                <enumeratedValue>
                  <name>0</name>
                  <description>No low timeout occurs</description>
                  <value>#0</value>
                </enumeratedValue>
                <enumeratedValue>
                  <name>1</name>
                  <description>Low timeout occurs</description>
                  <value>#1</value>
                </enumeratedValue>
              </enumeratedValues>
            </field>
            <field>
              <name>TCKSEL</name>
              <description>Timeout Counter Clock Select</description>
              <bitOffset>4</bitOffset>
              <bitWidth>1</bitWidth>
              <access>read-write</access>
              <enumeratedValues>
                <enumeratedValue>
                  <name>0</name>
                  <description>Timeout counter counts at the frequency of the I2C module clock / 64</description>
                  <value>#0</value>
                </enumeratedValue>
                <enumeratedValue>
                  <name>1</name>
                  <description>Timeout counter counts at the frequency of the I2C module clock</description>
                  <value>#1</value>
                </enumeratedValue>
              </enumeratedValues>
            </field>
            <field>
              <name>SIICAEN</name>
              <description>Second I2C Address Enable</description>
              <bitOffset>5</bitOffset>
              <bitWidth>1</bitWidth>
              <access>read-write</access>
              <enumeratedValues>
                <enumeratedValue>
                  <name>0</name>
                  <description>I2C address register 2 matching is disabled</description>
                  <value>#0</value>
                </enumeratedValue>
                <enumeratedValue>
                  <name>1</name>
                  <description>I2C address register 2 matching is enabled</description>
                  <value>#1</value>
                </enumeratedValue>
              </enumeratedValues>
            </field>
            <field>
              <name>ALERTEN</name>
              <description>SMBus Alert Response Address Enable</description>
              <bitOffset>6</bitOffset>
              <bitWidth>1</bitWidth>
              <access>read-write</access>
              <enumeratedValues>
                <enumeratedValue>
                  <name>0</name>
                  <description>SMBus alert response address matching is disabled</description>
                  <value>#0</value>
                </enumeratedValue>
                <enumeratedValue>
                  <name>1</name>
                  <description>SMBus alert response address matching is enabled</description>
                  <value>#1</value>
                </enumeratedValue>
              </enumeratedValues>
            </field>
            <field>
              <name>FACK</name>
              <description>Fast NACK/ACK Enable</description>
              <bitOffset>7</bitOffset>
              <bitWidth>1</bitWidth>
              <access>read-write</access>
              <enumeratedValues>
                <enumeratedValue>
                  <name>0</name>
                  <description>An ACK or NACK is sent on the following receiving data byte</description>
                  <value>#0</value>
                </enumeratedValue>
                <enumeratedValue>
                  <name>1</name>
                  <description>Writing 0 to TXAK after receiving a data byte generates an ACK. Writing 1 to TXAK after receiving a data byte generates a NACK.</description>
                  <value>#1</value>
                </enumeratedValue>
              </enumeratedValues>
            </field>
          </fields>
        </register>
        <register>
          <name>A2</name>
          <description>I2C Address Register 2</description>
          <addressOffset>0x9</addressOffset>
          <size>8</size>
          <access>read-write</access>
          <resetValue>0xC2</resetValue>
          <resetMask>0xFF</resetMask>
          <fields>
            <field>
              <name>SAD</name>
              <description>SMBus Address</description>
              <bitOffset>1</bitOffset>
              <bitWidth>7</bitWidth>
              <access>read-write</access>
            </field>
          </fields>
        </register>
        <register>
          <name>SLTH</name>
          <description>I2C SCL Low Timeout Register High</description>
          <addressOffset>0xA</addressOffset>
          <size>8</size>
          <access>read-write</access>
          <resetValue>0</resetValue>
          <resetMask>0xFF</resetMask>
          <fields>
            <field>
              <name>SSLT</name>
              <description>Most significant byte of SCL low timeout value that determines the timeout period of SCL low.</description>
              <bitOffset>0</bitOffset>
              <bitWidth>8</bitWidth>
              <access>read-write</access>
            </field>
          </fields>
        </register>
        <register>
          <name>SLTL</name>
          <description>I2C SCL Low Timeout Register Low</description>
          <addressOffset>0xB</addressOffset>
          <size>8</size>
          <access>read-write</access>
          <resetValue>0</resetValue>
          <resetMask>0xFF</resetMask>
          <fields>
            <field>
              <name>SSLT</name>
              <description>Least significant byte of SCL low timeout value that determines the timeout period of SCL low.</description>
              <bitOffset>0</bitOffset>
              <bitWidth>8</bitWidth>
              <access>read-write</access>
            </field>
          </fields>
        </register>
      </registers>
    </peripheral>
    <peripheral>
      <name>UART0</name>
      <description>Universal Asynchronous Receiver/Transmitter</description>
      <prependToName>UART0_</prependToName>
      <baseAddress>0x4006A000</baseAddress>
      <addressBlock>
        <offset>0</offset>
        <size>0xC</size>
        <usage>registers</usage>
      </addressBlock>
      <interrupt>
        <name>UART0</name>
        <value>12</value>
      </interrupt>
      <registers>
        <register>
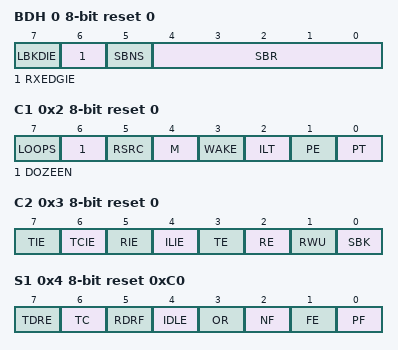
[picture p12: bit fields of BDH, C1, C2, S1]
          <name>BDH</name>
          <description>UART Baud Rate Register High</description>
          <addressOffset>0</addressOffset>
          <size>8</size>
          <access>read-write</access>
          <resetValue>0</resetValue>
          <resetMask>0xFF</resetMask>
          <fields>
            <field>
              <name>SBR</name>
              <description>Baud Rate Modulo Divisor.</description>
              <bitOffset>0</bitOffset>
              <bitWidth>5</bitWidth>
              <access>read-write</access>
            </field>
            <field>
              <name>SBNS</name>
              <description>Stop Bit Number Select</description>
              <bitOffset>5</bitOffset>
              <bitWidth>1</bitWidth>
              <access>read-write</access>
              <enumeratedValues>
                <enumeratedValue>
                  <name>0</name>
                  <description>One stop bit.</description>
                  <value>#0</value>
                </enumeratedValue>
                <enumeratedValue>
                  <name>1</name>
                  <description>Two stop bit.</description>
                  <value>#1</value>
                </enumeratedValue>
              </enumeratedValues>
            </field>
            <field>
              <name>RXEDGIE</name>
              <description>RX Input Active Edge Interrupt Enable (for RXEDGIF)</description>
              <bitOffset>6</bitOffset>
              <bitWidth>1</bitWidth>
              <access>read-write</access>
              <enumeratedValues>
                <enumeratedValue>
                  <name>0</name>
                  <description>Hardware interrupts from UART_S2[RXEDGIF] disabled (use polling).</description>
                  <value>#0</value>
                </enumeratedValue>
                <enumeratedValue>
                  <name>1</name>
                  <description>Hardware interrupt requested when UART_S2[RXEDGIF] flag is 1.</description>
                  <value>#1</value>
                </enumeratedValue>
              </enumeratedValues>
            </field>
            <field>
              <name>LBKDIE</name>
              <description>LIN Break Detect Interrupt Enable (for LBKDIF)</description>
              <bitOffset>7</bitOffset>
              <bitWidth>1</bitWidth>
              <access>read-write</access>
              <enumeratedValues>
                <enumeratedValue>
                  <name>0</name>
                  <description>Hardware interrupts from UART_S2[LBKDIF] disabled (use polling).</description>
                  <value>#0</value>
                </enumeratedValue>
                <enumeratedValue>
                  <name>1</name>
                  <description>Hardware interrupt requested when UART_S2[LBKDIF] flag is 1.</description>
                  <value>#1</value>
                </enumeratedValue>
              </enumeratedValues>
            </field>
          </fields>
        </register>
        <register>
          <name>BDL</name>
          <description>UART Baud Rate Register Low</description>
          <addressOffset>0x1</addressOffset>
          <size>8</size>
          <access>read-write</access>
          <resetValue>0x4</resetValue>
          <resetMask>0xFF</resetMask>
          <fields>
            <field>
              <name>SBR</name>
              <description>Baud Rate Modulo Divisor</description>
              <bitOffset>0</bitOffset>
              <bitWidth>8</bitWidth>
              <access>read-write</access>
            </field>
          </fields>
        </register>
        <register>
          <name>C1</name>
          <description>UART Control Register 1</description>
          <addressOffset>0x2</addressOffset>
          <size>8</size>
          <access>read-write</access>
          <resetValue>0</resetValue>
          <resetMask>0xFF</resetMask>
          <fields>
            <field>
              <name>PT</name>
              <description>Parity Type</description>
              <bitOffset>0</bitOffset>
              <bitWidth>1</bitWidth>
              <access>read-write</access>
              <enumeratedValues>
                <enumeratedValue>
                  <name>0</name>
                  <description>Even parity.</description>
                  <value>#0</value>
                </enumeratedValue>
                <enumeratedValue>
                  <name>1</name>
                  <description>Odd parity.</description>
                  <value>#1</value>
                </enumeratedValue>
              </enumeratedValues>
            </field>
            <field>
              <name>PE</name>
              <description>Parity Enable</description>
              <bitOffset>1</bitOffset>
              <bitWidth>1</bitWidth>
              <access>read-write</access>
              <enumeratedValues>
                <enumeratedValue>
                  <name>0</name>
                  <description>No hardware parity generation or checking.</description>
                  <value>#0</value>
                </enumeratedValue>
                <enumeratedValue>
                  <name>1</name>
                  <description>Parity enabled.</description>
                  <value>#1</value>
                </enumeratedValue>
              </enumeratedValues>
            </field>
            <field>
              <name>ILT</name>
              <description>Idle Line Type Select</description>
              <bitOffset>2</bitOffset>
              <bitWidth>1</bitWidth>
              <access>read-write</access>
              <enumeratedValues>
                <enumeratedValue>
                  <name>0</name>
                  <description>Idle character bit count starts after start bit.</description>
                  <value>#0</value>
                </enumeratedValue>
                <enumeratedValue>
                  <name>1</name>
                  <description>Idle character bit count starts after stop bit.</description>
                  <value>#1</value>
                </enumeratedValue>
              </enumeratedValues>
            </field>
            <field>
              <name>WAKE</name>
              <description>Receiver Wakeup Method Select</description>
              <bitOffset>3</bitOffset>
              <bitWidth>1</bitWidth>
              <access>read-write</access>
              <enumeratedValues>
                <enumeratedValue>
                  <name>0</name>
                  <description>Idle-line wakeup.</description>
                  <value>#0</value>
                </enumeratedValue>
                <enumeratedValue>
                  <name>1</name>
                  <description>Address-mark wakeup.</description>
                  <value>#1</value>
                </enumeratedValue>
              </enumeratedValues>
            </field>
            <field>
              <name>M</name>
              <description>9-Bit or 8-Bit Mode Select</description>
              <bitOffset>4</bitOffset>
              <bitWidth>1</bitWidth>
              <access>read-write</access>
              <enumeratedValues>
                <enumeratedValue>
                  <name>0</name>
                  <description>Receiver and transmitter use 8-bit data characters.</description>
                  <value>#0</value>
                </enumeratedValue>
                <enumeratedValue>
                  <name>1</name>
                  <description>Receiver and transmitter use 9-bit data characters.</description>
                  <value>#1</value>
                </enumeratedValue>
              </enumeratedValues>
            </field>
            <field>
              <name>RSRC</name>
              <description>Receiver Source Select</description>
              <bitOffset>5</bitOffset>
              <bitWidth>1</bitWidth>
              <access>read-write</access>
              <enumeratedValues>
                <enumeratedValue>
                  <name>0</name>
                  <description>Provided LOOPS is set, RSRC is cleared, selects internal loop back mode and the UART does not use the UART_RX pins.</description>
                  <value>#0</value>
                </enumeratedValue>
                <enumeratedValue>
                  <name>1</name>
                  <description>Single-wire UART mode where the UART_TX pin is connected to the transmitter output and receiver input.</description>
                  <value>#1</value>
                </enumeratedValue>
              </enumeratedValues>
            </field>
            <field>
              <name>DOZEEN</name>
              <description>Doze Enable</description>
              <bitOffset>6</bitOffset>
              <bitWidth>1</bitWidth>
              <access>read-write</access>
              <enumeratedValues>
                <enumeratedValue>
                  <name>0</name>
                  <description>UART is enabled in Wait mode.</description>
                  <value>#0</value>
                </enumeratedValue>
                <enumeratedValue>
                  <name>1</name>
                  <description>UART is disabled in Wait mode.</description>
                  <value>#1</value>
                </enumeratedValue>
              </enumeratedValues>
            </field>
            <field>
              <name>LOOPS</name>
              <description>Loop Mode Select</description>
              <bitOffset>7</bitOffset>
              <bitWidth>1</bitWidth>
              <access>read-write</access>
              <enumeratedValues>
                <enumeratedValue>
                  <name>0</name>
                  <description>Normal operation - UART_RX and UART_TX use separate pins.</description>
                  <value>#0</value>
                </enumeratedValue>
                <enumeratedValue>
                  <name>1</name>
                  <description>Loop mode or single-wire mode where transmitter outputs are internally connected to receiver input. (See RSRC bit.) UART_RX pin is not used by UART.</description>
                  <value>#1</value>
                </enumeratedValue>
              </enumeratedValues>
            </field>
          </fields>
        </register>
        <register>
          <name>C2</name>
          <description>UART Control Register 2</description>
          <addressOffset>0x3</addressOffset>
          <size>8</size>
          <access>read-write</access>
          <resetValue>0</resetValue>
          <resetMask>0xFF</resetMask>
          <fields>
            <field>
              <name>SBK</name>
              <description>Send Break</description>
              <bitOffset>0</bitOffset>
              <bitWidth>1</bitWidth>
              <access>read-write</access>
              <enumeratedValues>
                <enumeratedValue>
                  <name>0</name>
                  <description>Normal transmitter operation.</description>
                  <value>#0</value>
                </enumeratedValue>
                <enumeratedValue>
                  <name>1</name>
                  <description>Queue break character(s) to be sent.</description>
                  <value>#1</value>
                </enumeratedValue>
              </enumeratedValues>
            </field>
            <field>
              <name>RWU</name>
              <description>Receiver Wakeup Control</description>
              <bitOffset>1</bitOffset>
              <bitWidth>1</bitWidth>
              <access>read-write</access>
              <enumeratedValues>
                <enumeratedValue>
                  <name>0</name>
                  <description>Normal UART receiver operation.</description>
                  <value>#0</value>
                </enumeratedValue>
                <enumeratedValue>
                  <name>1</name>
                  <description>UART receiver in standby waiting for wakeup condition.</description>
                  <value>#1</value>
                </enumeratedValue>
              </enumeratedValues>
            </field>
            <field>
              <name>RE</name>
              <description>Receiver Enable</description>
              <bitOffset>2</bitOffset>
              <bitWidth>1</bitWidth>
              <access>read-write</access>
              <enumeratedValues>
                <enumeratedValue>
                  <name>0</name>
                  <description>Receiver disabled.</description>
                  <value>#0</value>
                </enumeratedValue>
                <enumeratedValue>
                  <name>1</name>
                  <description>Receiver enabled.</description>
                  <value>#1</value>
                </enumeratedValue>
              </enumeratedValues>
            </field>
            <field>
              <name>TE</name>
              <description>Transmitter Enable</description>
              <bitOffset>3</bitOffset>
              <bitWidth>1</bitWidth>
              <access>read-write</access>
              <enumeratedValues>
                <enumeratedValue>
                  <name>0</name>
                  <description>Transmitter disabled.</description>
                  <value>#0</value>
                </enumeratedValue>
                <enumeratedValue>
                  <name>1</name>
                  <description>Transmitter enabled.</description>
                  <value>#1</value>
                </enumeratedValue>
              </enumeratedValues>
            </field>
            <field>
              <name>ILIE</name>
              <description>Idle Line Interrupt Enable for IDLE</description>
              <bitOffset>4</bitOffset>
              <bitWidth>1</bitWidth>
              <access>read-write</access>
              <enumeratedValues>
                <enumeratedValue>
                  <name>0</name>
                  <description>Hardware interrupts from IDLE disabled; use polling.</description>
                  <value>#0</value>
                </enumeratedValue>
                <enumeratedValue>
                  <name>1</name>
                  <description>Hardware interrupt requested when IDLE flag is 1.</description>
                  <value>#1</value>
                </enumeratedValue>
              </enumeratedValues>
            </field>
            <field>
              <name>RIE</name>
              <description>Receiver Interrupt Enable for RDRF</description>
              <bitOffset>5</bitOffset>
              <bitWidth>1</bitWidth>
              <access>read-write</access>
              <enumeratedValues>
                <enumeratedValue>
                  <name>0</name>
                  <description>Hardware interrupts from RDRF disabled; use polling.</description>
                  <value>#0</value>
                </enumeratedValue>
                <enumeratedValue>
                  <name>1</name>
                  <description>Hardware interrupt requested when RDRF flag is 1.</description>
                  <value>#1</value>
                </enumeratedValue>
              </enumeratedValues>
            </field>
            <field>
              <name>TCIE</name>
              <description>Transmission Complete Interrupt Enable for TC</description>
              <bitOffset>6</bitOffset>
              <bitWidth>1</bitWidth>
              <access>read-write</access>
              <enumeratedValues>
                <enumeratedValue>
                  <name>0</name>
                  <description>Hardware interrupts from TC disabled; use polling.</description>
                  <value>#0</value>
                </enumeratedValue>
                <enumeratedValue>
                  <name>1</name>
                  <description>Hardware interrupt requested when TC flag is 1.</description>
                  <value>#1</value>
                </enumeratedValue>
              </enumeratedValues>
            </field>
            <field>
              <name>TIE</name>
              <description>Transmit Interrupt Enable for TDRE</description>
              <bitOffset>7</bitOffset>
              <bitWidth>1</bitWidth>
              <access>read-write</access>
              <enumeratedValues>
                <enumeratedValue>
                  <name>0</name>
                  <description>Hardware interrupts from TDRE disabled; use polling.</description>
                  <value>#0</value>
                </enumeratedValue>
                <enumeratedValue>
                  <name>1</name>
                  <description>Hardware interrupt requested when TDRE flag is 1.</description>
                  <value>#1</value>
                </enumeratedValue>
              </enumeratedValues>
            </field>
          </fields>
        </register>
        <register>
          <name>S1</name>
          <description>UART Status Register 1</description>
          <addressOffset>0x4</addressOffset>
          <size>8</size>
          <access>read-write</access>
          <resetValue>0xC0</resetValue>
          <resetMask>0xFF</resetMask>
          <fields>
            <field>
              <name>PF</name>
              <description>Parity Error Flag</description>
              <bitOffset>0</bitOffset>
              <bitWidth>1</bitWidth>
              <access>read-write</access>
              <enumeratedValues>
                <enumeratedValue>
                  <name>0</name>
                  <description>No parity error.</description>
                  <value>#0</value>
                </enumeratedValue>
                <enumeratedValue>
                  <name>1</name>
                  <description>Parity error.</description>
                  <value>#1</value>
                </enumeratedValue>
              </enumeratedValues>
            </field>
            <field>
              <name>FE</name>
              <description>Framing Error Flag</description>
              <bitOffset>1</bitOffset>
              <bitWidth>1</bitWidth>
              <access>read-write</access>
              <enumeratedValues>
                <enumeratedValue>
                  <name>0</name>
                  <description>No framing error detected. This does not guarantee the framing is correct.</description>
                  <value>#0</value>
                </enumeratedValue>
                <enumeratedValue>
                  <name>1</name>
                  <description>Framing error.</description>
                  <value>#1</value>
                </enumeratedValue>
              </enumeratedValues>
            </field>
            <field>
              <name>NF</name>
              <description>Noise Flag</description>
              <bitOffset>2</bitOffset>
              <bitWidth>1</bitWidth>
              <access>read-write</access>
              <enumeratedValues>
                <enumeratedValue>
                  <name>0</name>
                  <description>No noise detected.</description>
                  <value>#0</value>
                </enumeratedValue>
                <enumeratedValue>
                  <name>1</name>
                  <description>Noise detected in the received character in UART_D.</description>
                  <value>#1</value>
                </enumeratedValue>
              </enumeratedValues>
            </field>
            <field>
              <name>OR</name>
              <description>Receiver Overrun Flag</description>
              <bitOffset>3</bitOffset>
              <bitWidth>1</bitWidth>
              <access>read-write</access>
              <enumeratedValues>
                <enumeratedValue>
                  <name>0</name>
                  <description>No overrun.</description>
                  <value>#0</value>
                </enumeratedValue>
                <enumeratedValue>
                  <name>1</name>
                  <description>Receive overrun (new UART data lost).</description>
                  <value>#1</value>
                </enumeratedValue>
              </enumeratedValues>
            </field>
            <field>
              <name>IDLE</name>
              <description>Idle Line Flag</description>
              <bitOffset>4</bitOffset>
              <bitWidth>1</bitWidth>
              <access>read-write</access>
              <enumeratedValues>
                <enumeratedValue>
                  <name>0</name>
                  <description>No idle line detected.</description>
                  <value>#0</value>
                </enumeratedValue>
                <enumeratedValue>
                  <name>1</name>
                  <description>Idle line was detected.</description>
                  <value>#1</value>
                </enumeratedValue>
              </enumeratedValues>
            </field>
            <field>
              <name>RDRF</name>
              <description>Receive Data Register Full Flag</description>
              <bitOffset>5</bitOffset>
              <bitWidth>1</bitWidth>
              <access>read-only</access>
              <enumeratedValues>
                <enumeratedValue>
                  <name>0</name>
                  <description>Receive data buffer empty.</description>
                  <value>#0</value>
                </enumeratedValue>
                <enumeratedValue>
                  <name>1</name>
                  <description>Receive data buffer full.</description>
                  <value>#1</value>
                </enumeratedValue>
              </enumeratedValues>
            </field>
            <field>
              <name>TC</name>
              <description>Transmission Complete Flag</description>
              <bitOffset>6</bitOffset>
              <bitWidth>1</bitWidth>
              <access>read-only</access>
              <enumeratedValues>
                <enumeratedValue>
                  <name>0</name>
                  <description>Transmitter active (sending data, a preamble, or a break).</description>
                  <value>#0</value>
                </enumeratedValue>
                <enumeratedValue>
                  <name>1</name>
                  <description>Transmitter idle (transmission activity complete).</description>
                  <value>#1</value>
                </enumeratedValue>
              </enumeratedValues>
            </field>
            <field>
              <name>TDRE</name>
              <description>Transmit Data Register Empty Flag</description>
              <bitOffset>7</bitOffset>
              <bitWidth>1</bitWidth>
              <access>read-only</access>
              <enumeratedValues>
                <enumeratedValue>
                  <name>0</name>
                  <description>Transmit data buffer full.</description>
                  <value>#0</value>
                </enumeratedValue>
                <enumeratedValue>
                  <name>1</name>
                  <description>Transmit data buffer empty.</description>
                  <value>#1</value>
                </enumeratedValue>
              </enumeratedValues>
            </field>
          </fields>
        </register>
        <register>
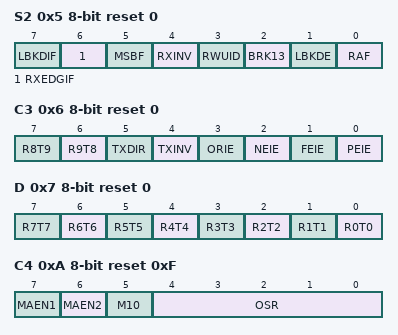
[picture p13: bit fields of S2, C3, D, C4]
          <name>S2</name>
          <description>UART Status Register 2</description>
          <addressOffset>0x5</addressOffset>
          <size>8</size>
          <access>read-write</access>
          <resetValue>0</resetValue>
          <resetMask>0xFF</resetMask>
          <fields>
            <field>
              <name>RAF</name>
              <description>Receiver Active Flag</description>
              <bitOffset>0</bitOffset>
              <bitWidth>1</bitWidth>
              <access>read-only</access>
              <enumeratedValues>
                <enumeratedValue>
                  <name>0</name>
                  <description>UART receiver idle waiting for a start bit.</description>
                  <value>#0</value>
                </enumeratedValue>
                <enumeratedValue>
                  <name>1</name>
                  <description>UART receiver active ( UART_RXD input not idle).</description>
                  <value>#1</value>
                </enumeratedValue>
              </enumeratedValues>
            </field>
            <field>
              <name>LBKDE</name>
              <description>LIN Break Detection Enable</description>
              <bitOffset>1</bitOffset>
              <bitWidth>1</bitWidth>
              <access>read-write</access>
              <enumeratedValues>
                <enumeratedValue>
                  <name>0</name>
                  <description>Break character is detected at length 10 bit times (if M = 0, SBNS = 0) or 11 (if M = 1, SBNS = 0 or M = 0, SBNS = 1) or 12 (if M = 1, SBNS = 1 or M10 = 1, SNBS = 0) or 13 (if M10 = 1, SNBS = 1).</description>
                  <value>#0</value>
                </enumeratedValue>
                <enumeratedValue>
                  <name>1</name>
                  <description>Break character is detected at length of 11 bit times (if M = 0, SBNS = 0) or 12 (if M = 1, SBNS = 0 or M = 0, SBNS = 1) or 14 (if M = 1, SBNS = 1 or M10 = 1, SNBS = 0) or 15 (if M10 = 1, SNBS = 1).</description>
                  <value>#1</value>
                </enumeratedValue>
              </enumeratedValues>
            </field>
            <field>
              <name>BRK13</name>
              <description>Break Character Generation Length</description>
              <bitOffset>2</bitOffset>
              <bitWidth>1</bitWidth>
              <access>read-write</access>
              <enumeratedValues>
                <enumeratedValue>
                  <name>0</name>
                  <description>Break character is transmitted with length of 10 bit times (if M = 0, SBNS = 0) or 11 (if M = 1, SBNS = 0 or M = 0, SBNS = 1) or 12 (if M = 1, SBNS = 1 or M10 = 1, SNBS = 0) or 13 (if M10 = 1, SNBS = 1).</description>
                  <value>#0</value>
                </enumeratedValue>
                <enumeratedValue>
                  <name>1</name>
                  <description>Break character is transmitted with length of 13 bit times (if M = 0, SBNS = 0) or 14 (if M = 1, SBNS = 0 or M = 0, SBNS = 1) or 15 (if M = 1, SBNS = 1 or M10 = 1, SNBS = 0) or 16 (if M10 = 1, SNBS = 1).</description>
                  <value>#1</value>
                </enumeratedValue>
              </enumeratedValues>
            </field>
            <field>
              <name>RWUID</name>
              <description>Receive Wake Up Idle Detect</description>
              <bitOffset>3</bitOffset>
              <bitWidth>1</bitWidth>
              <access>read-write</access>
              <enumeratedValues>
                <enumeratedValue>
                  <name>0</name>
                  <description>During receive standby state (RWU = 1), the IDLE bit does not get set upon detection of an idle character.</description>
                  <value>#0</value>
                </enumeratedValue>
                <enumeratedValue>
                  <name>1</name>
                  <description>During receive standby state (RWU = 1), the IDLE bit gets set upon detection of an idle character.</description>
                  <value>#1</value>
                </enumeratedValue>
              </enumeratedValues>
            </field>
            <field>
              <name>RXINV</name>
              <description>Receive Data Inversion</description>
              <bitOffset>4</bitOffset>
              <bitWidth>1</bitWidth>
              <access>read-write</access>
              <enumeratedValues>
                <enumeratedValue>
                  <name>0</name>
                  <description>Receive data not inverted.</description>
                  <value>#0</value>
                </enumeratedValue>
                <enumeratedValue>
                  <name>1</name>
                  <description>Receive data inverted.</description>
                  <value>#1</value>
                </enumeratedValue>
              </enumeratedValues>
            </field>
            <field>
              <name>MSBF</name>
              <description>MSB First</description>
              <bitOffset>5</bitOffset>
              <bitWidth>1</bitWidth>
              <access>read-write</access>
              <enumeratedValues>
                <enumeratedValue>
                  <name>0</name>
                  <description>LSB (bit0) is the first bit that is transmitted following the start bit. Further, the first bit received after the start bit is identified as bit0.</description>
                  <value>#0</value>
                </enumeratedValue>
                <enumeratedValue>
                  <name>1</name>
                  <description>MSB (bit9, bit8, bit7 or bit6) is the first bit that is transmitted following the start bit depending on the setting of C1[M], C1[PE] and C4[M10]. Further, the first bit received after the start bit is identified as bit9, bit8, bit7 or bit6 depending on the setting of C1[M] and C1[PE].</description>
                  <value>#1</value>
                </enumeratedValue>
              </enumeratedValues>
            </field>
            <field>
              <name>RXEDGIF</name>
              <description>UART_RX Pin Active Edge Interrupt Flag</description>
              <bitOffset>6</bitOffset>
              <bitWidth>1</bitWidth>
              <access>read-write</access>
              <enumeratedValues>
                <enumeratedValue>
                  <name>0</name>
                  <description>No active edge on the receive pin has occurred.</description>
                  <value>#0</value>
                </enumeratedValue>
                <enumeratedValue>
                  <name>1</name>
                  <description>An active edge on the receive pin has occurred.</description>
                  <value>#1</value>
                </enumeratedValue>
              </enumeratedValues>
            </field>
            <field>
              <name>LBKDIF</name>
              <description>LIN Break Detect Interrupt Flag</description>
              <bitOffset>7</bitOffset>
              <bitWidth>1</bitWidth>
              <access>read-write</access>
              <enumeratedValues>
                <enumeratedValue>
                  <name>0</name>
                  <description>No LIN break character has been detected.</description>
                  <value>#0</value>
                </enumeratedValue>
                <enumeratedValue>
                  <name>1</name>
                  <description>LIN break character has been detected.</description>
                  <value>#1</value>
                </enumeratedValue>
              </enumeratedValues>
            </field>
          </fields>
        </register>
        <register>
          <name>C3</name>
          <description>UART Control Register 3</description>
          <addressOffset>0x6</addressOffset>
          <size>8</size>
          <access>read-write</access>
          <resetValue>0</resetValue>
          <resetMask>0xFF</resetMask>
          <fields>
            <field>
              <name>PEIE</name>
              <description>Parity Error Interrupt Enable</description>
              <bitOffset>0</bitOffset>
              <bitWidth>1</bitWidth>
              <access>read-write</access>
              <enumeratedValues>
                <enumeratedValue>
                  <name>0</name>
                  <description>PF interrupts disabled; use polling).</description>
                  <value>#0</value>
                </enumeratedValue>
                <enumeratedValue>
                  <name>1</name>
                  <description>Hardware interrupt requested when PF is set.</description>
                  <value>#1</value>
                </enumeratedValue>
              </enumeratedValues>
            </field>
            <field>
              <name>FEIE</name>
              <description>Framing Error Interrupt Enable</description>
              <bitOffset>1</bitOffset>
              <bitWidth>1</bitWidth>
              <access>read-write</access>
              <enumeratedValues>
                <enumeratedValue>
                  <name>0</name>
                  <description>FE interrupts disabled; use polling.</description>
                  <value>#0</value>
                </enumeratedValue>
                <enumeratedValue>
                  <name>1</name>
                  <description>Hardware interrupt requested when FE is set.</description>
                  <value>#1</value>
                </enumeratedValue>
              </enumeratedValues>
            </field>
            <field>
              <name>NEIE</name>
              <description>Noise Error Interrupt Enable</description>
              <bitOffset>2</bitOffset>
              <bitWidth>1</bitWidth>
              <access>read-write</access>
              <enumeratedValues>
                <enumeratedValue>
                  <name>0</name>
                  <description>NF interrupts disabled; use polling.</description>
                  <value>#0</value>
                </enumeratedValue>
                <enumeratedValue>
                  <name>1</name>
                  <description>Hardware interrupt requested when NF is set.</description>
                  <value>#1</value>
                </enumeratedValue>
              </enumeratedValues>
            </field>
            <field>
              <name>ORIE</name>
              <description>Overrun Interrupt Enable</description>
              <bitOffset>3</bitOffset>
              <bitWidth>1</bitWidth>
              <access>read-write</access>
              <enumeratedValues>
                <enumeratedValue>
                  <name>0</name>
                  <description>OR interrupts disabled; use polling.</description>
                  <value>#0</value>
                </enumeratedValue>
                <enumeratedValue>
                  <name>1</name>
                  <description>Hardware interrupt requested when OR is set.</description>
                  <value>#1</value>
                </enumeratedValue>
              </enumeratedValues>
            </field>
            <field>
              <name>TXINV</name>
              <description>Transmit Data Inversion</description>
              <bitOffset>4</bitOffset>
              <bitWidth>1</bitWidth>
              <access>read-write</access>
              <enumeratedValues>
                <enumeratedValue>
                  <name>0</name>
                  <description>Transmit data not inverted.</description>
                  <value>#0</value>
                </enumeratedValue>
                <enumeratedValue>
                  <name>1</name>
                  <description>Transmit data inverted.</description>
                  <value>#1</value>
                </enumeratedValue>
              </enumeratedValues>
            </field>
            <field>
              <name>TXDIR</name>
              <description>UART_TX Pin Direction in Single-Wire Mode</description>
              <bitOffset>5</bitOffset>
              <bitWidth>1</bitWidth>
              <access>read-write</access>
              <enumeratedValues>
                <enumeratedValue>
                  <name>0</name>
                  <description>UART_TXD pin is an input in single-wire mode.</description>
                  <value>#0</value>
                </enumeratedValue>
                <enumeratedValue>
                  <name>1</name>
                  <description>UART_TXD pin is an output in single-wire mode.</description>
                  <value>#1</value>
                </enumeratedValue>
              </enumeratedValues>
            </field>
            <field>
              <name>R9T8</name>
              <description>Receive Bit 9 / Transmit Bit 8</description>
              <bitOffset>6</bitOffset>
              <bitWidth>1</bitWidth>
              <access>read-write</access>
            </field>
            <field>
              <name>R8T9</name>
              <description>Receive Bit 8 / Transmit Bit 9</description>
              <bitOffset>7</bitOffset>
              <bitWidth>1</bitWidth>
              <access>read-write</access>
            </field>
          </fields>
        </register>
        <register>
          <name>D</name>
          <description>UART Data Register</description>
          <addressOffset>0x7</addressOffset>
          <size>8</size>
          <access>read-write</access>
          <resetValue>0</resetValue>
          <resetMask>0xFF</resetMask>
          <fields>
            <field>
              <name>R0T0</name>
              <description>Read receive data buffer 0 or write transmit data buffer 0.</description>
              <bitOffset>0</bitOffset>
              <bitWidth>1</bitWidth>
              <access>read-write</access>
            </field>
            <field>
              <name>R1T1</name>
              <description>Read receive data buffer 1 or write transmit data buffer 1.</description>
              <bitOffset>1</bitOffset>
              <bitWidth>1</bitWidth>
              <access>read-write</access>
            </field>
            <field>
              <name>R2T2</name>
              <description>Read receive data buffer 2 or write transmit data buffer 2.</description>
              <bitOffset>2</bitOffset>
              <bitWidth>1</bitWidth>
              <access>read-write</access>
            </field>
            <field>
              <name>R3T3</name>
              <description>Read receive data buffer 3 or write transmit data buffer 3.</description>
              <bitOffset>3</bitOffset>
              <bitWidth>1</bitWidth>
              <access>read-write</access>
            </field>
            <field>
              <name>R4T4</name>
              <description>Read receive data buffer 4 or write transmit data buffer 4.</description>
              <bitOffset>4</bitOffset>
              <bitWidth>1</bitWidth>
              <access>read-write</access>
            </field>
            <field>
              <name>R5T5</name>
              <description>Read receive data buffer 5 or write transmit data buffer 5.</description>
              <bitOffset>5</bitOffset>
              <bitWidth>1</bitWidth>
              <access>read-write</access>
            </field>
            <field>
              <name>R6T6</name>
              <description>Read receive data buffer 6 or write transmit data buffer 6.</description>
              <bitOffset>6</bitOffset>
              <bitWidth>1</bitWidth>
              <access>read-write</access>
            </field>
            <field>
              <name>R7T7</name>
              <description>Read receive data buffer 7 or write transmit data buffer 7.</description>
              <bitOffset>7</bitOffset>
              <bitWidth>1</bitWidth>
              <access>read-write</access>
            </field>
          </fields>
        </register>
        <register>
          <name>MA1</name>
          <description>UART Match Address Registers 1</description>
          <addressOffset>0x8</addressOffset>
          <size>8</size>
          <access>read-write</access>
          <resetValue>0</resetValue>
          <resetMask>0xFF</resetMask>
          <fields>
            <field>
              <name>MA</name>
              <description>Match Address</description>
              <bitOffset>0</bitOffset>
              <bitWidth>8</bitWidth>
              <access>read-write</access>
            </field>
          </fields>
        </register>
        <register>
          <name>MA2</name>
          <description>UART Match Address Registers 2</description>
          <addressOffset>0x9</addressOffset>
          <size>8</size>
          <access>read-write</access>
          <resetValue>0</resetValue>
          <resetMask>0xFF</resetMask>
          <fields>
            <field>
              <name>MA</name>
              <description>Match Address</description>
              <bitOffset>0</bitOffset>
              <bitWidth>8</bitWidth>
              <access>read-write</access>
            </field>
          </fields>
        </register>
        <register>
          <name>C4</name>
          <description>UART Control Register 4</description>
          <addressOffset>0xA</addressOffset>
          <size>8</size>
          <access>read-write</access>
          <resetValue>0xF</resetValue>
          <resetMask>0xFF</resetMask>
          <fields>
            <field>
              <name>OSR</name>
              <description>Over Sampling Ratio</description>
              <bitOffset>0</bitOffset>
              <bitWidth>5</bitWidth>
              <access>read-write</access>
            </field>
            <field>
              <name>M10</name>
              <description>10-bit Mode select</description>
              <bitOffset>5</bitOffset>
              <bitWidth>1</bitWidth>
              <access>read-write</access>
              <enumeratedValues>
                <enumeratedValue>
                  <name>0</name>
                  <description>Receiver and transmitter use 8-bit or 9-bit data characters.</description>
                  <value>#0</value>
                </enumeratedValue>
                <enumeratedValue>
                  <name>1</name>
                  <description>Receiver and transmitter use 10-bit data characters.</description>
                  <value>#1</value>
                </enumeratedValue>
              </enumeratedValues>
            </field>
            <field>
              <name>MAEN2</name>
              <description>Match Address Mode Enable 2</description>
              <bitOffset>6</bitOffset>
              <bitWidth>1</bitWidth>
              <access>read-write</access>
              <enumeratedValues>
                <enumeratedValue>
                  <name>0</name>
                  <description>All data received is transferred to the data buffer if MAEN1 is cleared.</description>
                  <value>#0</value>
                </enumeratedValue>
                <enumeratedValue>
                  <name>1</name>
                  <description>All data received with the most significant bit cleared, is discarded. All data received with the most significant bit set, is compared with contents of MA2 register. If no match occurs, the data is discarded. If match occurs, data is transferred to the data buffer.</description>
                  <value>#1</value>
                </enumeratedValue>
              </enumeratedValues>
            </field>
            <field>
              <name>MAEN1</name>
              <description>Match Address Mode Enable 1</description>
              <bitOffset>7</bitOffset>
              <bitWidth>1</bitWidth>
              <access>read-write</access>
              <enumeratedValues>
                <enumeratedValue>
                  <name>0</name>
                  <description>All data received is transferred to the data buffer if MAEN2 is cleared.</description>
                  <value>#0</value>
                </enumeratedValue>
                <enumeratedValue>
                  <name>1</name>
                  <description>All data received with the most significant bit cleared, is discarded. All data received with the most significant bit set, is compared with contents of MA1 register. If no match occurs, the data is discarded. If match occurs, data is transferred to the data buffer.</description>
                  <value>#1</value>
                </enumeratedValue>
              </enumeratedValues>
            </field>
          </fields>
        </register>
        <register>
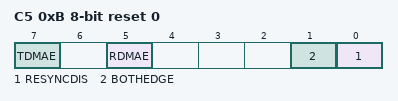
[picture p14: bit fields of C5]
          <name>C5</name>
          <description>UART Control Register 5</description>
          <addressOffset>0xB</addressOffset>
          <size>8</size>
          <access>read-write</access>
          <resetValue>0</resetValue>
          <resetMask>0xFF</resetMask>
          <fields>
            <field>
              <name>RESYNCDIS</name>
              <description>Resynchronization Disable</description>
              <bitOffset>0</bitOffset>
              <bitWidth>1</bitWidth>
              <access>read-write</access>
              <enumeratedValues>
                <enumeratedValue>
                  <name>0</name>
                  <description>Resynchronization during received data word is supported</description>
                  <value>#0</value>
                </enumeratedValue>
                <enumeratedValue>
                  <name>1</name>
                  <description>Resynchronization during received data word is disabled</description>
                  <value>#1</value>
                </enumeratedValue>
              </enumeratedValues>
            </field>
            <field>
              <name>BOTHEDGE</name>
              <description>Both Edge Sampling</description>
              <bitOffset>1</bitOffset>
              <bitWidth>1</bitWidth>
              <access>read-write</access>
              <enumeratedValues>
                <enumeratedValue>
                  <name>0</name>
                  <description>Receiver samples input data using the rising edge of the baud rate clock.</description>
                  <value>#0</value>
                </enumeratedValue>
                <enumeratedValue>
                  <name>1</name>
                  <description>Receiver samples input data using the rising and falling edge of the baud rate clock.</description>
                  <value>#1</value>
                </enumeratedValue>
              </enumeratedValues>
            </field>
            <field>
              <name>RDMAE</name>
              <description>Receiver Full DMA Enable</description>
              <bitOffset>5</bitOffset>
              <bitWidth>1</bitWidth>
              <access>read-write</access>
              <enumeratedValues>
                <enumeratedValue>
                  <name>0</name>
                  <description>DMA request disabled.</description>
                  <value>#0</value>
                </enumeratedValue>
                <enumeratedValue>
                  <name>1</name>
                  <description>DMA request enabled.</description>
                  <value>#1</value>
                </enumeratedValue>
              </enumeratedValues>
            </field>
            <field>
              <name>TDMAE</name>
              <description>Transmitter DMA Enable</description>
              <bitOffset>7</bitOffset>
              <bitWidth>1</bitWidth>
              <access>read-write</access>
              <enumeratedValues>
                <enumeratedValue>
                  <name>0</name>
                  <description>DMA request disabled.</description>
                  <value>#0</value>
                </enumeratedValue>
                <enumeratedValue>
                  <name>1</name>
                  <description>DMA request enabled.</description>
                  <value>#1</value>
                </enumeratedValue>
              </enumeratedValues>
            </field>
          </fields>
        </register>
      </registers>
    </peripheral>
    <peripheral>
      <name>UART1</name>
      <description>Universal Asynchronous Receiver/Transmitter (UART)</description>
      <groupName>UART</groupName>
      <prependToName>UART1_</prependToName>
      <baseAddress>0x4006B000</baseAddress>
      <addressBlock>
        <offset>0</offset>
        <size>0x9</size>
        <usage>registers</usage>
      </addressBlock>
      <interrupt>
        <name>UART1</name>
        <value>13</value>
      </interrupt>
      <registers>
        <register>
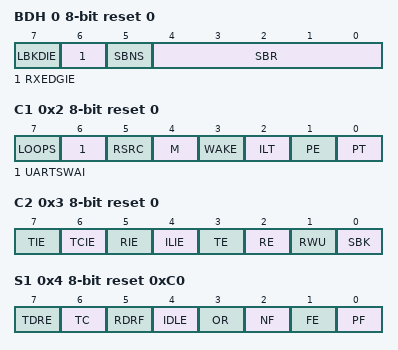
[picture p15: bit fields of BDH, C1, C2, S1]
          <name>BDH</name>
          <description>UART Baud Rate Register: High</description>
          <addressOffset>0</addressOffset>
          <size>8</size>
          <access>read-write</access>
          <resetValue>0</resetValue>
          <resetMask>0xFF</resetMask>
          <fields>
            <field>
              <name>SBR</name>
              <description>Baud Rate Modulo Divisor.</description>
              <bitOffset>0</bitOffset>
              <bitWidth>5</bitWidth>
              <access>read-write</access>
            </field>
            <field>
              <name>SBNS</name>
              <description>Stop Bit Number Select</description>
              <bitOffset>5</bitOffset>
              <bitWidth>1</bitWidth>
              <access>read-write</access>
              <enumeratedValues>
                <enumeratedValue>
                  <name>0</name>
                  <description>One stop bit.</description>
                  <value>#0</value>
                </enumeratedValue>
                <enumeratedValue>
                  <name>1</name>
                  <description>Two stop bit.</description>
                  <value>#1</value>
                </enumeratedValue>
              </enumeratedValues>
            </field>
            <field>
              <name>RXEDGIE</name>
              <description>RxD Input Active Edge Interrupt Enable (for RXEDGIF)</description>
              <bitOffset>6</bitOffset>
              <bitWidth>1</bitWidth>
              <access>read-write</access>
              <enumeratedValues>
                <enumeratedValue>
                  <name>0</name>
                  <description>Hardware interrupts from UART_S2[RXEDGIF] disabled (use polling).</description>
                  <value>#0</value>
                </enumeratedValue>
                <enumeratedValue>
                  <name>1</name>
                  <description>Hardware interrupt requested when UART_S2[RXEDGIF] flag is 1.</description>
                  <value>#1</value>
                </enumeratedValue>
              </enumeratedValues>
            </field>
            <field>
              <name>LBKDIE</name>
              <description>LIN Break Detect Interrupt Enable (for LBKDIF)</description>
              <bitOffset>7</bitOffset>
              <bitWidth>1</bitWidth>
              <access>read-write</access>
              <enumeratedValues>
                <enumeratedValue>
                  <name>0</name>
                  <description>Hardware interrupts from UART_S2[LBKDIF] disabled (use polling).</description>
                  <value>#0</value>
                </enumeratedValue>
                <enumeratedValue>
                  <name>1</name>
                  <description>Hardware interrupt requested when UART_S2[LBKDIF] flag is 1.</description>
                  <value>#1</value>
                </enumeratedValue>
              </enumeratedValues>
            </field>
          </fields>
        </register>
        <register>
          <name>BDL</name>
          <description>UART Baud Rate Register: Low</description>
          <addressOffset>0x1</addressOffset>
          <size>8</size>
          <access>read-write</access>
          <resetValue>0x4</resetValue>
          <resetMask>0xFF</resetMask>
          <fields>
            <field>
              <name>SBR</name>
              <description>Baud Rate Modulo Divisor</description>
              <bitOffset>0</bitOffset>
              <bitWidth>8</bitWidth>
              <access>read-write</access>
            </field>
          </fields>
        </register>
        <register>
          <name>C1</name>
          <description>UART Control Register 1</description>
          <addressOffset>0x2</addressOffset>
          <size>8</size>
          <access>read-write</access>
          <resetValue>0</resetValue>
          <resetMask>0xFF</resetMask>
          <fields>
            <field>
              <name>PT</name>
              <description>Parity Type</description>
              <bitOffset>0</bitOffset>
              <bitWidth>1</bitWidth>
              <access>read-write</access>
              <enumeratedValues>
                <enumeratedValue>
                  <name>0</name>
                  <description>Even parity.</description>
                  <value>#0</value>
                </enumeratedValue>
                <enumeratedValue>
                  <name>1</name>
                  <description>Odd parity.</description>
                  <value>#1</value>
                </enumeratedValue>
              </enumeratedValues>
            </field>
            <field>
              <name>PE</name>
              <description>Parity Enable</description>
              <bitOffset>1</bitOffset>
              <bitWidth>1</bitWidth>
              <access>read-write</access>
              <enumeratedValues>
                <enumeratedValue>
                  <name>0</name>
                  <description>No hardware parity generation or checking.</description>
                  <value>#0</value>
                </enumeratedValue>
                <enumeratedValue>
                  <name>1</name>
                  <description>Parity enabled.</description>
                  <value>#1</value>
                </enumeratedValue>
              </enumeratedValues>
            </field>
            <field>
              <name>ILT</name>
              <description>Idle Line Type Select</description>
              <bitOffset>2</bitOffset>
              <bitWidth>1</bitWidth>
              <access>read-write</access>
              <enumeratedValues>
                <enumeratedValue>
                  <name>0</name>
                  <description>Idle character bit count starts after start bit.</description>
                  <value>#0</value>
                </enumeratedValue>
                <enumeratedValue>
                  <name>1</name>
                  <description>Idle character bit count starts after stop bit.</description>
                  <value>#1</value>
                </enumeratedValue>
              </enumeratedValues>
            </field>
            <field>
              <name>WAKE</name>
              <description>Receiver Wakeup Method Select</description>
              <bitOffset>3</bitOffset>
              <bitWidth>1</bitWidth>
              <access>read-write</access>
              <enumeratedValues>
                <enumeratedValue>
                  <name>0</name>
                  <description>Idle-line wake-up.</description>
                  <value>#0</value>
                </enumeratedValue>
                <enumeratedValue>
                  <name>1</name>
                  <description>Address-mark wake-up.</description>
                  <value>#1</value>
                </enumeratedValue>
              </enumeratedValues>
            </field>
            <field>
              <name>M</name>
              <description>9-Bit or 8-Bit Mode Select</description>
              <bitOffset>4</bitOffset>
              <bitWidth>1</bitWidth>
              <access>read-write</access>
              <enumeratedValues>
                <enumeratedValue>
                  <name>0</name>
                  <description>Normal - start + 8 data bits (lsb first) + stop.</description>
                  <value>#0</value>
                </enumeratedValue>
                <enumeratedValue>
                  <name>1</name>
                  <description>Receiver and transmitter use 9-bit data characters start + 8 data bits (lsb first) + 9th data bit + stop.</description>
                  <value>#1</value>
                </enumeratedValue>
              </enumeratedValues>
            </field>
            <field>
              <name>RSRC</name>
              <description>Receiver Source Select</description>
              <bitOffset>5</bitOffset>
              <bitWidth>1</bitWidth>
              <access>read-write</access>
              <enumeratedValues>
                <enumeratedValue>
                  <name>0</name>
                  <description>Provided LOOPS is set, RSRC is cleared, selects internal loop back mode and the UART does not use the RxD pins.</description>
                  <value>#0</value>
                </enumeratedValue>
                <enumeratedValue>
                  <name>1</name>
                  <description>Single-wire UART mode where the TxD pin is connected to the transmitter output and receiver input.</description>
                  <value>#1</value>
                </enumeratedValue>
              </enumeratedValues>
            </field>
            <field>
              <name>UARTSWAI</name>
              <description>UART Stops in Wait Mode</description>
              <bitOffset>6</bitOffset>
              <bitWidth>1</bitWidth>
              <access>read-write</access>
              <enumeratedValues>
                <enumeratedValue>
                  <name>0</name>
                  <description>UART clocks continue to run in Wait mode so the UART can be the source of an interrupt that wakes up the CPU.</description>
                  <value>#0</value>
                </enumeratedValue>
                <enumeratedValue>
                  <name>1</name>
                  <description>UART clocks freeze while CPU is in Wait mode.</description>
                  <value>#1</value>
                </enumeratedValue>
              </enumeratedValues>
            </field>
            <field>
              <name>LOOPS</name>
              <description>Loop Mode Select</description>
              <bitOffset>7</bitOffset>
              <bitWidth>1</bitWidth>
              <access>read-write</access>
              <enumeratedValues>
                <enumeratedValue>
                  <name>0</name>
                  <description>Normal operation - RxD and TxD use separate pins.</description>
                  <value>#0</value>
                </enumeratedValue>
                <enumeratedValue>
                  <name>1</name>
                  <description>Loop mode or single-wire mode where transmitter outputs are internally connected to receiver input. (See RSRC bit.) RxD pin is not used by UART.</description>
                  <value>#1</value>
                </enumeratedValue>
              </enumeratedValues>
            </field>
          </fields>
        </register>
        <register>
          <name>C2</name>
          <description>UART Control Register 2</description>
          <addressOffset>0x3</addressOffset>
          <size>8</size>
          <access>read-write</access>
          <resetValue>0</resetValue>
          <resetMask>0xFF</resetMask>
          <fields>
            <field>
              <name>SBK</name>
              <description>Send Break</description>
              <bitOffset>0</bitOffset>
              <bitWidth>1</bitWidth>
              <access>read-write</access>
              <enumeratedValues>
                <enumeratedValue>
                  <name>0</name>
                  <description>Normal transmitter operation.</description>
                  <value>#0</value>
                </enumeratedValue>
                <enumeratedValue>
                  <name>1</name>
                  <description>Queue break character(s) to be sent.</description>
                  <value>#1</value>
                </enumeratedValue>
              </enumeratedValues>
            </field>
            <field>
              <name>RWU</name>
              <description>Receiver Wakeup Control</description>
              <bitOffset>1</bitOffset>
              <bitWidth>1</bitWidth>
              <access>read-write</access>
              <enumeratedValues>
                <enumeratedValue>
                  <name>0</name>
                  <description>Normal UART receiver operation.</description>
                  <value>#0</value>
                </enumeratedValue>
                <enumeratedValue>
                  <name>1</name>
                  <description>UART receiver in standby waiting for wake-up condition.</description>
                  <value>#1</value>
                </enumeratedValue>
              </enumeratedValues>
            </field>
            <field>
              <name>RE</name>
              <description>Receiver Enable</description>
              <bitOffset>2</bitOffset>
              <bitWidth>1</bitWidth>
              <access>read-write</access>
              <enumeratedValues>
                <enumeratedValue>
                  <name>0</name>
                  <description>Receiver off.</description>
                  <value>#0</value>
                </enumeratedValue>
                <enumeratedValue>
                  <name>1</name>
                  <description>Receiver on.</description>
                  <value>#1</value>
                </enumeratedValue>
              </enumeratedValues>
            </field>
            <field>
              <name>TE</name>
              <description>Transmitter Enable</description>
              <bitOffset>3</bitOffset>
              <bitWidth>1</bitWidth>
              <access>read-write</access>
              <enumeratedValues>
                <enumeratedValue>
                  <name>0</name>
                  <description>Transmitter off.</description>
                  <value>#0</value>
                </enumeratedValue>
                <enumeratedValue>
                  <name>1</name>
                  <description>Transmitter on.</description>
                  <value>#1</value>
                </enumeratedValue>
              </enumeratedValues>
            </field>
            <field>
              <name>ILIE</name>
              <description>Idle Line Interrupt Enable for IDLE</description>
              <bitOffset>4</bitOffset>
              <bitWidth>1</bitWidth>
              <access>read-write</access>
              <enumeratedValues>
                <enumeratedValue>
                  <name>0</name>
                  <description>Hardware interrupts from S1[IDLE] disabled; use polling.</description>
                  <value>#0</value>
                </enumeratedValue>
                <enumeratedValue>
                  <name>1</name>
                  <description>Hardware interrupt requested when S1[IDLE] flag is 1.</description>
                  <value>#1</value>
                </enumeratedValue>
              </enumeratedValues>
            </field>
            <field>
              <name>RIE</name>
              <description>Receiver Interrupt Enable for RDRF</description>
              <bitOffset>5</bitOffset>
              <bitWidth>1</bitWidth>
              <access>read-write</access>
              <enumeratedValues>
                <enumeratedValue>
                  <name>0</name>
                  <description>Hardware interrupts from S1[RDRF] disabled; use polling.</description>
                  <value>#0</value>
                </enumeratedValue>
                <enumeratedValue>
                  <name>1</name>
                  <description>Hardware interrupt requested when S1[RDRF] flag is 1.</description>
                  <value>#1</value>
                </enumeratedValue>
              </enumeratedValues>
            </field>
            <field>
              <name>TCIE</name>
              <description>Transmission Complete Interrupt Enable for TC</description>
              <bitOffset>6</bitOffset>
              <bitWidth>1</bitWidth>
              <access>read-write</access>
              <enumeratedValues>
                <enumeratedValue>
                  <name>0</name>
                  <description>Hardware interrupts from TC disabled; use polling.</description>
                  <value>#0</value>
                </enumeratedValue>
                <enumeratedValue>
                  <name>1</name>
                  <description>Hardware interrupt requested when TC flag is 1.</description>
                  <value>#1</value>
                </enumeratedValue>
              </enumeratedValues>
            </field>
            <field>
              <name>TIE</name>
              <description>Transmit Interrupt Enable for TDRE</description>
              <bitOffset>7</bitOffset>
              <bitWidth>1</bitWidth>
              <access>read-write</access>
              <enumeratedValues>
                <enumeratedValue>
                  <name>0</name>
                  <description>Hardware interrupts from TDRE disabled; use polling.</description>
                  <value>#0</value>
                </enumeratedValue>
                <enumeratedValue>
                  <name>1</name>
                  <description>Hardware interrupt requested when TDRE flag is 1.</description>
                  <value>#1</value>
                </enumeratedValue>
              </enumeratedValues>
            </field>
          </fields>
        </register>
        <register>
          <name>S1</name>
          <description>UART Status Register 1</description>
          <addressOffset>0x4</addressOffset>
          <size>8</size>
          <access>read-only</access>
          <resetValue>0xC0</resetValue>
          <resetMask>0xFF</resetMask>
          <fields>
            <field>
              <name>PF</name>
              <description>Parity Error Flag</description>
              <bitOffset>0</bitOffset>
              <bitWidth>1</bitWidth>
              <access>read-only</access>
              <enumeratedValues>
                <enumeratedValue>
                  <name>0</name>
                  <description>No parity error.</description>
                  <value>#0</value>
                </enumeratedValue>
                <enumeratedValue>
                  <name>1</name>
                  <description>Parity error.</description>
                  <value>#1</value>
                </enumeratedValue>
              </enumeratedValues>
            </field>
            <field>
              <name>FE</name>
              <description>Framing Error Flag</description>
              <bitOffset>1</bitOffset>
              <bitWidth>1</bitWidth>
              <access>read-only</access>
              <enumeratedValues>
                <enumeratedValue>
                  <name>0</name>
                  <description>No framing error detected. This does not guarantee the framing is correct.</description>
                  <value>#0</value>
                </enumeratedValue>
                <enumeratedValue>
                  <name>1</name>
                  <description>Framing error.</description>
                  <value>#1</value>
                </enumeratedValue>
              </enumeratedValues>
            </field>
            <field>
              <name>NF</name>
              <description>Noise Flag</description>
              <bitOffset>2</bitOffset>
              <bitWidth>1</bitWidth>
              <access>read-only</access>
              <enumeratedValues>
                <enumeratedValue>
                  <name>0</name>
                  <description>No noise detected.</description>
                  <value>#0</value>
                </enumeratedValue>
                <enumeratedValue>
                  <name>1</name>
                  <description>Noise detected in the received character in UART_D.</description>
                  <value>#1</value>
                </enumeratedValue>
              </enumeratedValues>
            </field>
            <field>
              <name>OR</name>
              <description>Receiver Overrun Flag</description>
              <bitOffset>3</bitOffset>
              <bitWidth>1</bitWidth>
              <access>read-only</access>
              <enumeratedValues>
                <enumeratedValue>
                  <name>0</name>
                  <description>No overrun.</description>
                  <value>#0</value>
                </enumeratedValue>
                <enumeratedValue>
                  <name>1</name>
                  <description>Receive overrun (new UART data lost).</description>
                  <value>#1</value>
                </enumeratedValue>
              </enumeratedValues>
            </field>
            <field>
              <name>IDLE</name>
              <description>Idle Line Flag</description>
              <bitOffset>4</bitOffset>
              <bitWidth>1</bitWidth>
              <access>read-only</access>
              <enumeratedValues>
                <enumeratedValue>
                  <name>0</name>
                  <description>No idle line detected.</description>
                  <value>#0</value>
                </enumeratedValue>
                <enumeratedValue>
                  <name>1</name>
                  <description>Idle line was detected.</description>
                  <value>#1</value>
                </enumeratedValue>
              </enumeratedValues>
            </field>
            <field>
              <name>RDRF</name>
              <description>Receive Data Register Full Flag</description>
              <bitOffset>5</bitOffset>
              <bitWidth>1</bitWidth>
              <access>read-only</access>
              <enumeratedValues>
                <enumeratedValue>
                  <name>0</name>
                  <description>Receive data register empty.</description>
                  <value>#0</value>
                </enumeratedValue>
                <enumeratedValue>
                  <name>1</name>
                  <description>Receive data register full.</description>
                  <value>#1</value>
                </enumeratedValue>
              </enumeratedValues>
            </field>
            <field>
              <name>TC</name>
              <description>Transmission Complete Flag</description>
              <bitOffset>6</bitOffset>
              <bitWidth>1</bitWidth>
              <access>read-only</access>
              <enumeratedValues>
                <enumeratedValue>
                  <name>0</name>
                  <description>Transmitter active (sending data, a preamble, or a break).</description>
                  <value>#0</value>
                </enumeratedValue>
                <enumeratedValue>
                  <name>1</name>
                  <description>Transmitter idle (transmission activity complete).</description>
                  <value>#1</value>
                </enumeratedValue>
              </enumeratedValues>
            </field>
            <field>
              <name>TDRE</name>
              <description>Transmit Data Register Empty Flag</description>
              <bitOffset>7</bitOffset>
              <bitWidth>1</bitWidth>
              <access>read-only</access>
              <enumeratedValues>
                <enumeratedValue>
                  <name>0</name>
                  <description>Transmit data register (buffer) full.</description>
                  <value>#0</value>
                </enumeratedValue>
                <enumeratedValue>
                  <name>1</name>
                  <description>Transmit data register (buffer) empty.</description>
                  <value>#1</value>
                </enumeratedValue>
              </enumeratedValues>
            </field>
          </fields>
        </register>
        <register>
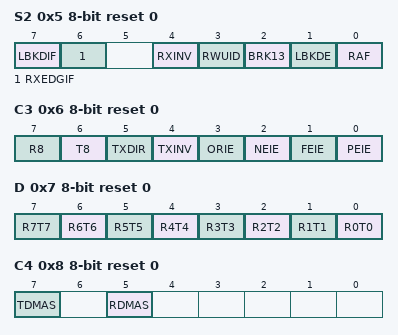
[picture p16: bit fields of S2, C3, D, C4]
          <name>S2</name>
          <description>UART Status Register 2</description>
          <addressOffset>0x5</addressOffset>
          <size>8</size>
          <access>read-write</access>
          <resetValue>0</resetValue>
          <resetMask>0xFF</resetMask>
          <fields>
            <field>
              <name>RAF</name>
              <description>Receiver Active Flag</description>
              <bitOffset>0</bitOffset>
              <bitWidth>1</bitWidth>
              <access>read-only</access>
              <enumeratedValues>
                <enumeratedValue>
                  <name>0</name>
                  <description>UART receiver idle waiting for a start bit.</description>
                  <value>#0</value>
                </enumeratedValue>
                <enumeratedValue>
                  <name>1</name>
                  <description>UART receiver active (RxD input not idle).</description>
                  <value>#1</value>
                </enumeratedValue>
              </enumeratedValues>
            </field>
            <field>
              <name>LBKDE</name>
              <description>LIN Break Detection Enable</description>
              <bitOffset>1</bitOffset>
              <bitWidth>1</bitWidth>
              <access>read-write</access>
              <enumeratedValues>
                <enumeratedValue>
                  <name>0</name>
                  <description>Break detection is disabled.</description>
                  <value>#0</value>
                </enumeratedValue>
                <enumeratedValue>
                  <name>1</name>
                  <description>Break detection is enabled (Break character is detected at length 11 bit times (if C1[M] = 0, BDH[SBNS] = 0) or 12 (if C1[M] = 1, BDH[SBNS] = 0 or C1[M] = 0, BDH[SBNS] = 1) or 13 (if C1[M] = 1, BDH[SBNS] = 1)).</description>
                  <value>#1</value>
                </enumeratedValue>
              </enumeratedValues>
            </field>
            <field>
              <name>BRK13</name>
              <description>Break Character Generation Length</description>
              <bitOffset>2</bitOffset>
              <bitWidth>1</bitWidth>
              <access>read-write</access>
              <enumeratedValues>
                <enumeratedValue>
                  <name>0</name>
                  <description>Break character is transmitted with length of 10 bit times (if M = 0, SBNS = 0) or 11 (if M = 1, SBNS = 0 or M = 0, SBNS = 1) or 12 (if M = 1, SBNS = 1).</description>
                  <value>#0</value>
                </enumeratedValue>
                <enumeratedValue>
                  <name>1</name>
                  <description>Break character is transmitted with length of 13 bit times (if M = 0, SBNS = 0) or 14 (if M = 1, SBNS = 0 or M = 0, SBNS = 1) or 15 (if M = 1, SBNS = 1).</description>
                  <value>#1</value>
                </enumeratedValue>
              </enumeratedValues>
            </field>
            <field>
              <name>RWUID</name>
              <description>Receive Wake Up Idle Detect</description>
              <bitOffset>3</bitOffset>
              <bitWidth>1</bitWidth>
              <access>read-write</access>
              <enumeratedValues>
                <enumeratedValue>
                  <name>0</name>
                  <description>During receive standby state (RWU = 1), S1[IDLE] does not get set upon detection of an idle character.</description>
                  <value>#0</value>
                </enumeratedValue>
                <enumeratedValue>
                  <name>1</name>
                  <description>During receive standby state (RWU = 1), S1[IDLE] gets set upon detection of an idle character.</description>
                  <value>#1</value>
                </enumeratedValue>
              </enumeratedValues>
            </field>
            <field>
              <name>RXINV</name>
              <description>Receive Data Inversion</description>
              <bitOffset>4</bitOffset>
              <bitWidth>1</bitWidth>
              <access>read-write</access>
              <enumeratedValues>
                <enumeratedValue>
                  <name>0</name>
                  <description>Receive data not inverted.</description>
                  <value>#0</value>
                </enumeratedValue>
                <enumeratedValue>
                  <name>1</name>
                  <description>Receive data inverted.</description>
                  <value>#1</value>
                </enumeratedValue>
              </enumeratedValues>
            </field>
            <field>
              <name>RXEDGIF</name>
              <description>RxD Pin Active Edge Interrupt Flag</description>
              <bitOffset>6</bitOffset>
              <bitWidth>1</bitWidth>
              <access>read-write</access>
              <enumeratedValues>
                <enumeratedValue>
                  <name>0</name>
                  <description>No active edge on the receive pin has occurred.</description>
                  <value>#0</value>
                </enumeratedValue>
                <enumeratedValue>
                  <name>1</name>
                  <description>An active edge on the receive pin has occurred.</description>
                  <value>#1</value>
                </enumeratedValue>
              </enumeratedValues>
            </field>
            <field>
              <name>LBKDIF</name>
              <description>LIN Break Detect Interrupt Flag</description>
              <bitOffset>7</bitOffset>
              <bitWidth>1</bitWidth>
              <access>read-write</access>
              <enumeratedValues>
                <enumeratedValue>
                  <name>0</name>
                  <description>No LIN break character has been detected.</description>
                  <value>#0</value>
                </enumeratedValue>
                <enumeratedValue>
                  <name>1</name>
                  <description>LIN break character has been detected.</description>
                  <value>#1</value>
                </enumeratedValue>
              </enumeratedValues>
            </field>
          </fields>
        </register>
        <register>
          <name>C3</name>
          <description>UART Control Register 3</description>
          <addressOffset>0x6</addressOffset>
          <size>8</size>
          <access>read-write</access>
          <resetValue>0</resetValue>
          <resetMask>0xFF</resetMask>
          <fields>
            <field>
              <name>PEIE</name>
              <description>Parity Error Interrupt Enable</description>
              <bitOffset>0</bitOffset>
              <bitWidth>1</bitWidth>
              <access>read-write</access>
              <enumeratedValues>
                <enumeratedValue>
                  <name>0</name>
                  <description>PF interrupts disabled; use polling).</description>
                  <value>#0</value>
                </enumeratedValue>
                <enumeratedValue>
                  <name>1</name>
                  <description>Hardware interrupt requested when PF is set.</description>
                  <value>#1</value>
                </enumeratedValue>
              </enumeratedValues>
            </field>
            <field>
              <name>FEIE</name>
              <description>Framing Error Interrupt Enable</description>
              <bitOffset>1</bitOffset>
              <bitWidth>1</bitWidth>
              <access>read-write</access>
              <enumeratedValues>
                <enumeratedValue>
                  <name>0</name>
                  <description>FE interrupts disabled; use polling).</description>
                  <value>#0</value>
                </enumeratedValue>
                <enumeratedValue>
                  <name>1</name>
                  <description>Hardware interrupt requested when FE is set.</description>
                  <value>#1</value>
                </enumeratedValue>
              </enumeratedValues>
            </field>
            <field>
              <name>NEIE</name>
              <description>Noise Error Interrupt Enable</description>
              <bitOffset>2</bitOffset>
              <bitWidth>1</bitWidth>
              <access>read-write</access>
              <enumeratedValues>
                <enumeratedValue>
                  <name>0</name>
                  <description>NF interrupts disabled; use polling).</description>
                  <value>#0</value>
                </enumeratedValue>
                <enumeratedValue>
                  <name>1</name>
                  <description>Hardware interrupt requested when NF is set.</description>
                  <value>#1</value>
                </enumeratedValue>
              </enumeratedValues>
            </field>
            <field>
              <name>ORIE</name>
              <description>Overrun Interrupt Enable</description>
              <bitOffset>3</bitOffset>
              <bitWidth>1</bitWidth>
              <access>read-write</access>
              <enumeratedValues>
                <enumeratedValue>
                  <name>0</name>
                  <description>OR interrupts disabled; use polling.</description>
                  <value>#0</value>
                </enumeratedValue>
                <enumeratedValue>
                  <name>1</name>
                  <description>Hardware interrupt requested when OR is set.</description>
                  <value>#1</value>
                </enumeratedValue>
              </enumeratedValues>
            </field>
            <field>
              <name>TXINV</name>
              <description>Transmit Data Inversion</description>
              <bitOffset>4</bitOffset>
              <bitWidth>1</bitWidth>
              <access>read-write</access>
              <enumeratedValues>
                <enumeratedValue>
                  <name>0</name>
                  <description>Transmit data not inverted.</description>
                  <value>#0</value>
                </enumeratedValue>
                <enumeratedValue>
                  <name>1</name>
                  <description>Transmit data inverted.</description>
                  <value>#1</value>
                </enumeratedValue>
              </enumeratedValues>
            </field>
            <field>
              <name>TXDIR</name>
              <description>TxD Pin Direction in Single-Wire Mode</description>
              <bitOffset>5</bitOffset>
              <bitWidth>1</bitWidth>
              <access>read-write</access>
              <enumeratedValues>
                <enumeratedValue>
                  <name>0</name>
                  <description>TxD pin is an input in single-wire mode.</description>
                  <value>#0</value>
                </enumeratedValue>
                <enumeratedValue>
                  <name>1</name>
                  <description>TxD pin is an output in single-wire mode.</description>
                  <value>#1</value>
                </enumeratedValue>
              </enumeratedValues>
            </field>
            <field>
              <name>T8</name>
              <description>Ninth Data Bit for Transmitter</description>
              <bitOffset>6</bitOffset>
              <bitWidth>1</bitWidth>
              <access>read-write</access>
            </field>
            <field>
              <name>R8</name>
              <description>Ninth Data Bit for Receiver</description>
              <bitOffset>7</bitOffset>
              <bitWidth>1</bitWidth>
              <access>read-only</access>
            </field>
          </fields>
        </register>
        <register>
          <name>D</name>
          <description>UART Data Register</description>
          <addressOffset>0x7</addressOffset>
          <size>8</size>
          <access>read-write</access>
          <resetValue>0</resetValue>
          <resetMask>0xFF</resetMask>
          <fields>
            <field>
              <name>R0T0</name>
              <description>Read receive data buffer 0 or write transmit data buffer 0.</description>
              <bitOffset>0</bitOffset>
              <bitWidth>1</bitWidth>
              <access>read-write</access>
            </field>
            <field>
              <name>R1T1</name>
              <description>Read receive data buffer 1 or write transmit data buffer 1.</description>
              <bitOffset>1</bitOffset>
              <bitWidth>1</bitWidth>
              <access>read-write</access>
            </field>
            <field>
              <name>R2T2</name>
              <description>Read receive data buffer 2 or write transmit data buffer 2.</description>
              <bitOffset>2</bitOffset>
              <bitWidth>1</bitWidth>
              <access>read-write</access>
            </field>
            <field>
              <name>R3T3</name>
              <description>Read receive data buffer 3 or write transmit data buffer 3.</description>
              <bitOffset>3</bitOffset>
              <bitWidth>1</bitWidth>
              <access>read-write</access>
            </field>
            <field>
              <name>R4T4</name>
              <description>Read receive data buffer 4 or write transmit data buffer 4.</description>
              <bitOffset>4</bitOffset>
              <bitWidth>1</bitWidth>
              <access>read-write</access>
            </field>
            <field>
              <name>R5T5</name>
              <description>Read receive data buffer 5 or write transmit data buffer 5.</description>
              <bitOffset>5</bitOffset>
              <bitWidth>1</bitWidth>
              <access>read-write</access>
            </field>
            <field>
              <name>R6T6</name>
              <description>Read receive data buffer 6 or write transmit data buffer 6.</description>
              <bitOffset>6</bitOffset>
              <bitWidth>1</bitWidth>
              <access>read-write</access>
            </field>
            <field>
              <name>R7T7</name>
              <description>Read receive data buffer 7 or write transmit data buffer 7.</description>
              <bitOffset>7</bitOffset>
              <bitWidth>1</bitWidth>
              <access>read-write</access>
            </field>
          </fields>
        </register>
        <register>
          <name>C4</name>
          <description>UART Control Register 4</description>
          <addressOffset>0x8</addressOffset>
          <size>8</size>
          <access>read-write</access>
          <resetValue>0</resetValue>
          <resetMask>0xFF</resetMask>
          <fields>
            <field>
              <name>RDMAS</name>
              <description>Receiver Full DMA Select</description>
              <bitOffset>5</bitOffset>
              <bitWidth>1</bitWidth>
              <access>read-write</access>
              <enumeratedValues>
                <enumeratedValue>
                  <name>0</name>
                  <description>If RIE is set and the RDRF flag is set, the RDRF interrupt request signal is asserted to request interrupt service.</description>
                  <value>#0</value>
                </enumeratedValue>
                <enumeratedValue>
                  <name>1</name>
                  <description>If RIE is set and the RDRF flag is set, the RDRF DMA request signal is asserted to request a DMA transfer.</description>
                  <value>#1</value>
                </enumeratedValue>
              </enumeratedValues>
            </field>
            <field>
              <name>TDMAS</name>
              <description>Transmitter DMA Select</description>
              <bitOffset>7</bitOffset>
              <bitWidth>1</bitWidth>
              <access>read-write</access>
              <enumeratedValues>
                <enumeratedValue>
                  <name>0</name>
                  <description>If TIE is set and the TDRE flag is set, the TDRE interrupt request signal is asserted to request interrupt service.</description>
                  <value>#0</value>
                </enumeratedValue>
                <enumeratedValue>
                  <name>1</name>
                  <description>If TIE is set and the TDRE flag is set, the TDRE DMA request signal is asserted to request a DMA transfer.</description>
                  <value>#1</value>
                </enumeratedValue>
              </enumeratedValues>
            </field>
          </fields>
        </register>
      </registers>
    </peripheral>
    <peripheral>
      <name>UART2</name>
      <description>Universal Asynchronous Receiver/Transmitter (UART)</description>
      <groupName>UART</groupName>
      <prependToName>UART2_</prependToName>
      <baseAddress>0x4006C000</baseAddress>
      <addressBlock>
        <offset>0</offset>
        <size>0x9</size>
        <usage>registers</usage>
      </addressBlock>
      <interrupt>
        <name>UART2</name>
        <value>14</value>
      </interrupt>
      <registers>
        <register>
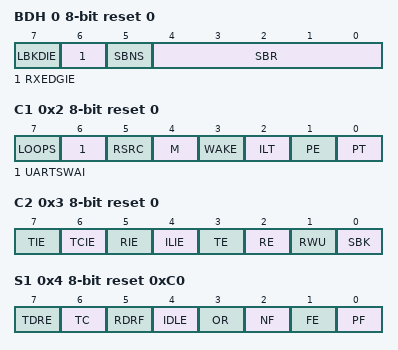
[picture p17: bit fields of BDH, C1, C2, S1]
          <name>BDH</name>
          <description>UART Baud Rate Register: High</description>
          <addressOffset>0</addressOffset>
          <size>8</size>
          <access>read-write</access>
          <resetValue>0</resetValue>
          <resetMask>0xFF</resetMask>
          <fields>
            <field>
              <name>SBR</name>
              <description>Baud Rate Modulo Divisor.</description>
              <bitOffset>0</bitOffset>
              <bitWidth>5</bitWidth>
              <access>read-write</access>
            </field>
            <field>
              <name>SBNS</name>
              <description>Stop Bit Number Select</description>
              <bitOffset>5</bitOffset>
              <bitWidth>1</bitWidth>
              <access>read-write</access>
              <enumeratedValues>
                <enumeratedValue>
                  <name>0</name>
                  <description>One stop bit.</description>
                  <value>#0</value>
                </enumeratedValue>
                <enumeratedValue>
                  <name>1</name>
                  <description>Two stop bit.</description>
                  <value>#1</value>
                </enumeratedValue>
              </enumeratedValues>
            </field>
            <field>
              <name>RXEDGIE</name>
              <description>RxD Input Active Edge Interrupt Enable (for RXEDGIF)</description>
              <bitOffset>6</bitOffset>
              <bitWidth>1</bitWidth>
              <access>read-write</access>
              <enumeratedValues>
                <enumeratedValue>
                  <name>0</name>
                  <description>Hardware interrupts from UART_S2[RXEDGIF] disabled (use polling).</description>
                  <value>#0</value>
                </enumeratedValue>
                <enumeratedValue>
                  <name>1</name>
                  <description>Hardware interrupt requested when UART_S2[RXEDGIF] flag is 1.</description>
                  <value>#1</value>
                </enumeratedValue>
              </enumeratedValues>
            </field>
            <field>
              <name>LBKDIE</name>
              <description>LIN Break Detect Interrupt Enable (for LBKDIF)</description>
              <bitOffset>7</bitOffset>
              <bitWidth>1</bitWidth>
              <access>read-write</access>
              <enumeratedValues>
                <enumeratedValue>
                  <name>0</name>
                  <description>Hardware interrupts from UART_S2[LBKDIF] disabled (use polling).</description>
                  <value>#0</value>
                </enumeratedValue>
                <enumeratedValue>
                  <name>1</name>
                  <description>Hardware interrupt requested when UART_S2[LBKDIF] flag is 1.</description>
                  <value>#1</value>
                </enumeratedValue>
              </enumeratedValues>
            </field>
          </fields>
        </register>
        <register>
          <name>BDL</name>
          <description>UART Baud Rate Register: Low</description>
          <addressOffset>0x1</addressOffset>
          <size>8</size>
          <access>read-write</access>
          <resetValue>0x4</resetValue>
          <resetMask>0xFF</resetMask>
          <fields>
            <field>
              <name>SBR</name>
              <description>Baud Rate Modulo Divisor</description>
              <bitOffset>0</bitOffset>
              <bitWidth>8</bitWidth>
              <access>read-write</access>
            </field>
          </fields>
        </register>
        <register>
          <name>C1</name>
          <description>UART Control Register 1</description>
          <addressOffset>0x2</addressOffset>
          <size>8</size>
          <access>read-write</access>
          <resetValue>0</resetValue>
          <resetMask>0xFF</resetMask>
          <fields>
            <field>
              <name>PT</name>
              <description>Parity Type</description>
              <bitOffset>0</bitOffset>
              <bitWidth>1</bitWidth>
              <access>read-write</access>
              <enumeratedValues>
                <enumeratedValue>
                  <name>0</name>
                  <description>Even parity.</description>
                  <value>#0</value>
                </enumeratedValue>
                <enumeratedValue>
                  <name>1</name>
                  <description>Odd parity.</description>
                  <value>#1</value>
                </enumeratedValue>
              </enumeratedValues>
            </field>
            <field>
              <name>PE</name>
              <description>Parity Enable</description>
              <bitOffset>1</bitOffset>
              <bitWidth>1</bitWidth>
              <access>read-write</access>
              <enumeratedValues>
                <enumeratedValue>
                  <name>0</name>
                  <description>No hardware parity generation or checking.</description>
                  <value>#0</value>
                </enumeratedValue>
                <enumeratedValue>
                  <name>1</name>
                  <description>Parity enabled.</description>
                  <value>#1</value>
                </enumeratedValue>
              </enumeratedValues>
            </field>
            <field>
              <name>ILT</name>
              <description>Idle Line Type Select</description>
              <bitOffset>2</bitOffset>
              <bitWidth>1</bitWidth>
              <access>read-write</access>
              <enumeratedValues>
                <enumeratedValue>
                  <name>0</name>
                  <description>Idle character bit count starts after start bit.</description>
                  <value>#0</value>
                </enumeratedValue>
                <enumeratedValue>
                  <name>1</name>
                  <description>Idle character bit count starts after stop bit.</description>
                  <value>#1</value>
                </enumeratedValue>
              </enumeratedValues>
            </field>
            <field>
              <name>WAKE</name>
              <description>Receiver Wakeup Method Select</description>
              <bitOffset>3</bitOffset>
              <bitWidth>1</bitWidth>
              <access>read-write</access>
              <enumeratedValues>
                <enumeratedValue>
                  <name>0</name>
                  <description>Idle-line wake-up.</description>
                  <value>#0</value>
                </enumeratedValue>
                <enumeratedValue>
                  <name>1</name>
                  <description>Address-mark wake-up.</description>
                  <value>#1</value>
                </enumeratedValue>
              </enumeratedValues>
            </field>
            <field>
              <name>M</name>
              <description>9-Bit or 8-Bit Mode Select</description>
              <bitOffset>4</bitOffset>
              <bitWidth>1</bitWidth>
              <access>read-write</access>
              <enumeratedValues>
                <enumeratedValue>
                  <name>0</name>
                  <description>Normal - start + 8 data bits (lsb first) + stop.</description>
                  <value>#0</value>
                </enumeratedValue>
                <enumeratedValue>
                  <name>1</name>
                  <description>Receiver and transmitter use 9-bit data characters start + 8 data bits (lsb first) + 9th data bit + stop.</description>
                  <value>#1</value>
                </enumeratedValue>
              </enumeratedValues>
            </field>
            <field>
              <name>RSRC</name>
              <description>Receiver Source Select</description>
              <bitOffset>5</bitOffset>
              <bitWidth>1</bitWidth>
              <access>read-write</access>
              <enumeratedValues>
                <enumeratedValue>
                  <name>0</name>
                  <description>Provided LOOPS is set, RSRC is cleared, selects internal loop back mode and the UART does not use the RxD pins.</description>
                  <value>#0</value>
                </enumeratedValue>
                <enumeratedValue>
                  <name>1</name>
                  <description>Single-wire UART mode where the TxD pin is connected to the transmitter output and receiver input.</description>
                  <value>#1</value>
                </enumeratedValue>
              </enumeratedValues>
            </field>
            <field>
              <name>UARTSWAI</name>
              <description>UART Stops in Wait Mode</description>
              <bitOffset>6</bitOffset>
              <bitWidth>1</bitWidth>
              <access>read-write</access>
              <enumeratedValues>
                <enumeratedValue>
                  <name>0</name>
                  <description>UART clocks continue to run in Wait mode so the UART can be the source of an interrupt that wakes up the CPU.</description>
                  <value>#0</value>
                </enumeratedValue>
                <enumeratedValue>
                  <name>1</name>
                  <description>UART clocks freeze while CPU is in Wait mode.</description>
                  <value>#1</value>
                </enumeratedValue>
              </enumeratedValues>
            </field>
            <field>
              <name>LOOPS</name>
              <description>Loop Mode Select</description>
              <bitOffset>7</bitOffset>
              <bitWidth>1</bitWidth>
              <access>read-write</access>
              <enumeratedValues>
                <enumeratedValue>
                  <name>0</name>
                  <description>Normal operation - RxD and TxD use separate pins.</description>
                  <value>#0</value>
                </enumeratedValue>
                <enumeratedValue>
                  <name>1</name>
                  <description>Loop mode or single-wire mode where transmitter outputs are internally connected to receiver input. (See RSRC bit.) RxD pin is not used by UART.</description>
                  <value>#1</value>
                </enumeratedValue>
              </enumeratedValues>
            </field>
          </fields>
        </register>
        <register>
          <name>C2</name>
          <description>UART Control Register 2</description>
          <addressOffset>0x3</addressOffset>
          <size>8</size>
          <access>read-write</access>
          <resetValue>0</resetValue>
          <resetMask>0xFF</resetMask>
          <fields>
            <field>
              <name>SBK</name>
              <description>Send Break</description>
              <bitOffset>0</bitOffset>
              <bitWidth>1</bitWidth>
              <access>read-write</access>
              <enumeratedValues>
                <enumeratedValue>
                  <name>0</name>
                  <description>Normal transmitter operation.</description>
                  <value>#0</value>
                </enumeratedValue>
                <enumeratedValue>
                  <name>1</name>
                  <description>Queue break character(s) to be sent.</description>
                  <value>#1</value>
                </enumeratedValue>
              </enumeratedValues>
            </field>
            <field>
              <name>RWU</name>
              <description>Receiver Wakeup Control</description>
              <bitOffset>1</bitOffset>
              <bitWidth>1</bitWidth>
              <access>read-write</access>
              <enumeratedValues>
                <enumeratedValue>
                  <name>0</name>
                  <description>Normal UART receiver operation.</description>
                  <value>#0</value>
                </enumeratedValue>
                <enumeratedValue>
                  <name>1</name>
                  <description>UART receiver in standby waiting for wake-up condition.</description>
                  <value>#1</value>
                </enumeratedValue>
              </enumeratedValues>
            </field>
            <field>
              <name>RE</name>
              <description>Receiver Enable</description>
              <bitOffset>2</bitOffset>
              <bitWidth>1</bitWidth>
              <access>read-write</access>
              <enumeratedValues>
                <enumeratedValue>
                  <name>0</name>
                  <description>Receiver off.</description>
                  <value>#0</value>
                </enumeratedValue>
                <enumeratedValue>
                  <name>1</name>
                  <description>Receiver on.</description>
                  <value>#1</value>
                </enumeratedValue>
              </enumeratedValues>
            </field>
            <field>
              <name>TE</name>
              <description>Transmitter Enable</description>
              <bitOffset>3</bitOffset>
              <bitWidth>1</bitWidth>
              <access>read-write</access>
              <enumeratedValues>
                <enumeratedValue>
                  <name>0</name>
                  <description>Transmitter off.</description>
                  <value>#0</value>
                </enumeratedValue>
                <enumeratedValue>
                  <name>1</name>
                  <description>Transmitter on.</description>
                  <value>#1</value>
                </enumeratedValue>
              </enumeratedValues>
            </field>
            <field>
              <name>ILIE</name>
              <description>Idle Line Interrupt Enable for IDLE</description>
              <bitOffset>4</bitOffset>
              <bitWidth>1</bitWidth>
              <access>read-write</access>
              <enumeratedValues>
                <enumeratedValue>
                  <name>0</name>
                  <description>Hardware interrupts from S1[IDLE] disabled; use polling.</description>
                  <value>#0</value>
                </enumeratedValue>
                <enumeratedValue>
                  <name>1</name>
                  <description>Hardware interrupt requested when S1[IDLE] flag is 1.</description>
                  <value>#1</value>
                </enumeratedValue>
              </enumeratedValues>
            </field>
            <field>
              <name>RIE</name>
              <description>Receiver Interrupt Enable for RDRF</description>
              <bitOffset>5</bitOffset>
              <bitWidth>1</bitWidth>
              <access>read-write</access>
              <enumeratedValues>
                <enumeratedValue>
                  <name>0</name>
                  <description>Hardware interrupts from S1[RDRF] disabled; use polling.</description>
                  <value>#0</value>
                </enumeratedValue>
                <enumeratedValue>
                  <name>1</name>
                  <description>Hardware interrupt requested when S1[RDRF] flag is 1.</description>
                  <value>#1</value>
                </enumeratedValue>
              </enumeratedValues>
            </field>
            <field>
              <name>TCIE</name>
              <description>Transmission Complete Interrupt Enable for TC</description>
              <bitOffset>6</bitOffset>
              <bitWidth>1</bitWidth>
              <access>read-write</access>
              <enumeratedValues>
                <enumeratedValue>
                  <name>0</name>
                  <description>Hardware interrupts from TC disabled; use polling.</description>
                  <value>#0</value>
                </enumeratedValue>
                <enumeratedValue>
                  <name>1</name>
                  <description>Hardware interrupt requested when TC flag is 1.</description>
                  <value>#1</value>
                </enumeratedValue>
              </enumeratedValues>
            </field>
            <field>
              <name>TIE</name>
              <description>Transmit Interrupt Enable for TDRE</description>
              <bitOffset>7</bitOffset>
              <bitWidth>1</bitWidth>
              <access>read-write</access>
              <enumeratedValues>
                <enumeratedValue>
                  <name>0</name>
                  <description>Hardware interrupts from TDRE disabled; use polling.</description>
                  <value>#0</value>
                </enumeratedValue>
                <enumeratedValue>
                  <name>1</name>
                  <description>Hardware interrupt requested when TDRE flag is 1.</description>
                  <value>#1</value>
                </enumeratedValue>
              </enumeratedValues>
            </field>
          </fields>
        </register>
        <register>
          <name>S1</name>
          <description>UART Status Register 1</description>
          <addressOffset>0x4</addressOffset>
          <size>8</size>
          <access>read-only</access>
          <resetValue>0xC0</resetValue>
          <resetMask>0xFF</resetMask>
          <fields>
            <field>
              <name>PF</name>
              <description>Parity Error Flag</description>
              <bitOffset>0</bitOffset>
              <bitWidth>1</bitWidth>
              <access>read-only</access>
              <enumeratedValues>
                <enumeratedValue>
                  <name>0</name>
                  <description>No parity error.</description>
                  <value>#0</value>
                </enumeratedValue>
                <enumeratedValue>
                  <name>1</name>
                  <description>Parity error.</description>
                  <value>#1</value>
                </enumeratedValue>
              </enumeratedValues>
            </field>
            <field>
              <name>FE</name>
              <description>Framing Error Flag</description>
              <bitOffset>1</bitOffset>
              <bitWidth>1</bitWidth>
              <access>read-only</access>
              <enumeratedValues>
                <enumeratedValue>
                  <name>0</name>
                  <description>No framing error detected. This does not guarantee the framing is correct.</description>
                  <value>#0</value>
                </enumeratedValue>
                <enumeratedValue>
                  <name>1</name>
                  <description>Framing error.</description>
                  <value>#1</value>
                </enumeratedValue>
              </enumeratedValues>
            </field>
            <field>
              <name>NF</name>
              <description>Noise Flag</description>
              <bitOffset>2</bitOffset>
              <bitWidth>1</bitWidth>
              <access>read-only</access>
              <enumeratedValues>
                <enumeratedValue>
                  <name>0</name>
                  <description>No noise detected.</description>
                  <value>#0</value>
                </enumeratedValue>
                <enumeratedValue>
                  <name>1</name>
                  <description>Noise detected in the received character in UART_D.</description>
                  <value>#1</value>
                </enumeratedValue>
              </enumeratedValues>
            </field>
            <field>
              <name>OR</name>
              <description>Receiver Overrun Flag</description>
              <bitOffset>3</bitOffset>
              <bitWidth>1</bitWidth>
              <access>read-only</access>
              <enumeratedValues>
                <enumeratedValue>
                  <name>0</name>
                  <description>No overrun.</description>
                  <value>#0</value>
                </enumeratedValue>
                <enumeratedValue>
                  <name>1</name>
                  <description>Receive overrun (new UART data lost).</description>
                  <value>#1</value>
                </enumeratedValue>
              </enumeratedValues>
            </field>
            <field>
              <name>IDLE</name>
              <description>Idle Line Flag</description>
              <bitOffset>4</bitOffset>
              <bitWidth>1</bitWidth>
              <access>read-only</access>
              <enumeratedValues>
                <enumeratedValue>
                  <name>0</name>
                  <description>No idle line detected.</description>
                  <value>#0</value>
                </enumeratedValue>
                <enumeratedValue>
                  <name>1</name>
                  <description>Idle line was detected.</description>
                  <value>#1</value>
                </enumeratedValue>
              </enumeratedValues>
            </field>
            <field>
              <name>RDRF</name>
              <description>Receive Data Register Full Flag</description>
              <bitOffset>5</bitOffset>
              <bitWidth>1</bitWidth>
              <access>read-only</access>
              <enumeratedValues>
                <enumeratedValue>
                  <name>0</name>
                  <description>Receive data register empty.</description>
                  <value>#0</value>
                </enumeratedValue>
                <enumeratedValue>
                  <name>1</name>
                  <description>Receive data register full.</description>
                  <value>#1</value>
                </enumeratedValue>
              </enumeratedValues>
            </field>
            <field>
              <name>TC</name>
              <description>Transmission Complete Flag</description>
              <bitOffset>6</bitOffset>
              <bitWidth>1</bitWidth>
              <access>read-only</access>
              <enumeratedValues>
                <enumeratedValue>
                  <name>0</name>
                  <description>Transmitter active (sending data, a preamble, or a break).</description>
                  <value>#0</value>
                </enumeratedValue>
                <enumeratedValue>
                  <name>1</name>
                  <description>Transmitter idle (transmission activity complete).</description>
                  <value>#1</value>
                </enumeratedValue>
              </enumeratedValues>
            </field>
            <field>
              <name>TDRE</name>
              <description>Transmit Data Register Empty Flag</description>
              <bitOffset>7</bitOffset>
              <bitWidth>1</bitWidth>
              <access>read-only</access>
              <enumeratedValues>
                <enumeratedValue>
                  <name>0</name>
                  <description>Transmit data register (buffer) full.</description>
                  <value>#0</value>
                </enumeratedValue>
                <enumeratedValue>
                  <name>1</name>
                  <description>Transmit data register (buffer) empty.</description>
                  <value>#1</value>
                </enumeratedValue>
              </enumeratedValues>
            </field>
          </fields>
        </register>
        <register>
          <name>S2</name>
          <description>UART Status Register 2</description>
          <addressOffset>0x5</addressOffset>
          <size>8</size>
          <access>read-write</access>
          <resetValue>0</resetValue>
          <resetMask>0xFF</resetMask>
          <fields>
            <field>
              <name>RAF</name>
              <description>Receiver Active Flag</description>
              <bitOffset>0</bitOffset>
              <bitWidth>1</bitWidth>
              <access>read-only</access>
              <enumeratedValues>
                <enumeratedValue>
                  <name>0</name>
                  <description>UART receiver idle waiting for a start bit.</description>
                  <value>#0</value>
                </enumeratedValue>
                <enumeratedValue>
                  <name>1</name>
                  <description>UART receiver active (RxD input not idle).</description>
                  <value>#1</value>
                </enumeratedValue>
              </enumeratedValues>
            </field>
            <field>
              <name>LBKDE</name>
              <description>LIN Break Detection Enable</description>
              <bitOffset>1</bitOffset>
              <bitWidth>1</bitWidth>
              <access>read-write</access>
              <enumeratedValues>
                <enumeratedValue>
                  <name>0</name>
                  <description>Break detection is disabled.</description>
                  <value>#0</value>
                </enumeratedValue>
                <enumeratedValue>
                  <name>1</name>
                  <description>Break detection is enabled (Break character is detected at length 11 bit times (if C1[M] = 0, BDH[SBNS] = 0) or 12 (if C1[M] = 1, BDH[SBNS] = 0 or C1[M] = 0, BDH[SBNS] = 1) or 13 (if C1[M] = 1, BDH[SBNS] = 1)).</description>
                  <value>#1</value>
                </enumeratedValue>
              </enumeratedValues>
            </field>
            <field>
              <name>BRK13</name>
              <description>Break Character Generation Length</description>
              <bitOffset>2</bitOffset>
              <bitWidth>1</bitWidth>
              <access>read-write</access>
              <enumeratedValues>
                <enumeratedValue>
                  <name>0</name>
                  <description>Break character is transmitted with length of 10 bit times (if M = 0, SBNS = 0) or 11 (if M = 1, SBNS = 0 or M = 0, SBNS = 1) or 12 (if M = 1, SBNS = 1).</description>
                  <value>#0</value>
                </enumeratedValue>
                <enumeratedValue>
                  <name>1</name>
                  <description>Break character is transmitted with length of 13 bit times (if M = 0, SBNS = 0) or 14 (if M = 1, SBNS = 0 or M = 0, SBNS = 1) or 15 (if M = 1, SBNS = 1).</description>
                  <value>#1</value>
                </enumeratedValue>
              </enumeratedValues>
            </field>
            <field>
              <name>RWUID</name>
              <description>Receive Wake Up Idle Detect</description>
              <bitOffset>3</bitOffset>
              <bitWidth>1</bitWidth>
              <access>read-write</access>
              <enumeratedValues>
                <enumeratedValue>
                  <name>0</name>
                  <description>During receive standby state (RWU = 1), S1[IDLE] does not get set upon detection of an idle character.</description>
                  <value>#0</value>
                </enumeratedValue>
                <enumeratedValue>
                  <name>1</name>
                  <description>During receive standby state (RWU = 1), S1[IDLE] gets set upon detection of an idle character.</description>
                  <value>#1</value>
                </enumeratedValue>
              </enumeratedValues>
            </field>
            <field>
              <name>RXINV</name>
              <description>Receive Data Inversion</description>
              <bitOffset>4</bitOffset>
              <bitWidth>1</bitWidth>
              <access>read-write</access>
              <enumeratedValues>
                <enumeratedValue>
                  <name>0</name>
                  <description>Receive data not inverted.</description>
                  <value>#0</value>
                </enumeratedValue>
                <enumeratedValue>
                  <name>1</name>
                  <description>Receive data inverted.</description>
                  <value>#1</value>
                </enumeratedValue>
              </enumeratedValues>
            </field>
            <field>
              <name>RXEDGIF</name>
              <description>RxD Pin Active Edge Interrupt Flag</description>
              <bitOffset>6</bitOffset>
              <bitWidth>1</bitWidth>
              <access>read-write</access>
              <enumeratedValues>
                <enumeratedValue>
                  <name>0</name>
                  <description>No active edge on the receive pin has occurred.</description>
                  <value>#0</value>
                </enumeratedValue>
                <enumeratedValue>
                  <name>1</name>
                  <description>An active edge on the receive pin has occurred.</description>
                  <value>#1</value>
                </enumeratedValue>
              </enumeratedValues>
            </field>
            <field>
              <name>LBKDIF</name>
              <description>LIN Break Detect Interrupt Flag</description>
              <bitOffset>7</bitOffset>
              <bitWidth>1</bitWidth>
              <access>read-write</access>
              <enumeratedValues>
                <enumeratedValue>
                  <name>0</name>
                  <description>No LIN break character has been detected.</description>
                  <value>#0</value>
                </enumeratedValue>
                <enumeratedValue>
                  <name>1</name>
                  <description>LIN break character has been detected.</description>
                  <value>#1</value>
                </enumeratedValue>
              </enumeratedValues>
            </field>
          </fields>
        </register>
        <register>
          <name>C3</name>
          <description>UART Control Register 3</description>
          <addressOffset>0x6</addressOffset>
          <size>8</size>
          <access>read-write</access>
          <resetValue>0</resetValue>
          <resetMask>0xFF</resetMask>
          <fields>
            <field>
              <name>PEIE</name>
              <description>Parity Error Interrupt Enable</description>
              <bitOffset>0</bitOffset>
              <bitWidth>1</bitWidth>
              <access>read-write</access>
              <enumeratedValues>
                <enumeratedValue>
                  <name>0</name>
                  <description>PF interrupts disabled; use polling).</description>
                  <value>#0</value>
                </enumeratedValue>
                <enumeratedValue>
                  <name>1</name>
                  <description>Hardware interrupt requested when PF is set.</description>
                  <value>#1</value>
                </enumeratedValue>
              </enumeratedValues>
            </field>
            <field>
              <name>FEIE</name>
              <description>Framing Error Interrupt Enable</description>
              <bitOffset>1</bitOffset>
              <bitWidth>1</bitWidth>
              <access>read-write</access>
              <enumeratedValues>
                <enumeratedValue>
                  <name>0</name>
                  <description>FE interrupts disabled; use polling).</description>
                  <value>#0</value>
                </enumeratedValue>
                <enumeratedValue>
                  <name>1</name>
                  <description>Hardware interrupt requested when FE is set.</description>
                  <value>#1</value>
                </enumeratedValue>
              </enumeratedValues>
            </field>
            <field>
              <name>NEIE</name>
              <description>Noise Error Interrupt Enable</description>
              <bitOffset>2</bitOffset>
              <bitWidth>1</bitWidth>
              <access>read-write</access>
              <enumeratedValues>
                <enumeratedValue>
                  <name>0</name>
                  <description>NF interrupts disabled; use polling).</description>
                  <value>#0</value>
                </enumeratedValue>
                <enumeratedValue>
                  <name>1</name>
                  <description>Hardware interrupt requested when NF is set.</description>
                  <value>#1</value>
                </enumeratedValue>
              </enumeratedValues>
            </field>
            <field>
              <name>ORIE</name>
              <description>Overrun Interrupt Enable</description>
              <bitOffset>3</bitOffset>
              <bitWidth>1</bitWidth>
              <access>read-write</access>
              <enumeratedValues>
                <enumeratedValue>
                  <name>0</name>
                  <description>OR interrupts disabled; use polling.</description>
                  <value>#0</value>
                </enumeratedValue>
                <enumeratedValue>
                  <name>1</name>
                  <description>Hardware interrupt requested when OR is set.</description>
                  <value>#1</value>
                </enumeratedValue>
              </enumeratedValues>
            </field>
            <field>
              <name>TXINV</name>
              <description>Transmit Data Inversion</description>
              <bitOffset>4</bitOffset>
              <bitWidth>1</bitWidth>
              <access>read-write</access>
              <enumeratedValues>
                <enumeratedValue>
                  <name>0</name>
                  <description>Transmit data not inverted.</description>
                  <value>#0</value>
                </enumeratedValue>
                <enumeratedValue>
                  <name>1</name>
                  <description>Transmit data inverted.</description>
                  <value>#1</value>
                </enumeratedValue>
              </enumeratedValues>
            </field>
            <field>
              <name>TXDIR</name>
              <description>TxD Pin Direction in Single-Wire Mode</description>
              <bitOffset>5</bitOffset>
              <bitWidth>1</bitWidth>
              <access>read-write</access>
              <enumeratedValues>
                <enumeratedValue>
                  <name>0</name>
                  <description>TxD pin is an input in single-wire mode.</description>
                  <value>#0</value>
                </enumeratedValue>
                <enumeratedValue>
                  <name>1</name>
                  <description>TxD pin is an output in single-wire mode.</description>
                  <value>#1</value>
                </enumeratedValue>
              </enumeratedValues>
            </field>
            <field>
              <name>T8</name>
              <description>Ninth Data Bit for Transmitter</description>
              <bitOffset>6</bitOffset>
              <bitWidth>1</bitWidth>
              <access>read-write</access>
            </field>
            <field>
              <name>R8</name>
              <description>Ninth Data Bit for Receiver</description>
              <bitOffset>7</bitOffset>
              <bitWidth>1</bitWidth>
              <access>read-only</access>
            </field>
          </fields>
        </register>
        <register>
          <name>D</name>
          <description>UART Data Register</description>
          <addressOffset>0x7</addressOffset>
          <size>8</size>
          <access>read-write</access>
          <resetValue>0</resetValue>
          <resetMask>0xFF</resetMask>
          <fields>
            <field>
              <name>R0T0</name>
              <description>Read receive data buffer 0 or write transmit data buffer 0.</description>
              <bitOffset>0</bitOffset>
              <bitWidth>1</bitWidth>
              <access>read-write</access>
            </field>
            <field>
              <name>R1T1</name>
              <description>Read receive data buffer 1 or write transmit data buffer 1.</description>
              <bitOffset>1</bitOffset>
              <bitWidth>1</bitWidth>
              <access>read-write</access>
            </field>
            <field>
              <name>R2T2</name>
              <description>Read receive data buffer 2 or write transmit data buffer 2.</description>
              <bitOffset>2</bitOffset>
              <bitWidth>1</bitWidth>
              <access>read-write</access>
            </field>
            <field>
              <name>R3T3</name>
              <description>Read receive data buffer 3 or write transmit data buffer 3.</description>
              <bitOffset>3</bitOffset>
              <bitWidth>1</bitWidth>
              <access>read-write</access>
            </field>
            <field>
              <name>R4T4</name>
              <description>Read receive data buffer 4 or write transmit data buffer 4.</description>
              <bitOffset>4</bitOffset>
              <bitWidth>1</bitWidth>
              <access>read-write</access>
            </field>
            <field>
              <name>R5T5</name>
              <description>Read receive data buffer 5 or write transmit data buffer 5.</description>
              <bitOffset>5</bitOffset>
              <bitWidth>1</bitWidth>
              <access>read-write</access>
            </field>
            <field>
              <name>R6T6</name>
              <description>Read receive data buffer 6 or write transmit data buffer 6.</description>
              <bitOffset>6</bitOffset>
              <bitWidth>1</bitWidth>
              <access>read-write</access>
            </field>
            <field>
              <name>R7T7</name>
              <description>Read receive data buffer 7 or write transmit data buffer 7.</description>
              <bitOffset>7</bitOffset>
              <bitWidth>1</bitWidth>
              <access>read-write</access>
            </field>
          </fields>
        </register>
        <register>
          <name>C4</name>
          <description>UART Control Register 4</description>
          <addressOffset>0x8</addressOffset>
          <size>8</size>
          <access>read-write</access>
          <resetValue>0</resetValue>
          <resetMask>0xFF</resetMask>
          <fields>
            <field>
              <name>RDMAS</name>
              <description>Receiver Full DMA Select</description>
              <bitOffset>5</bitOffset>
              <bitWidth>1</bitWidth>
              <access>read-write</access>
              <enumeratedValues>
                <enumeratedValue>
                  <name>0</name>
                  <description>If RIE is set and the RDRF flag is set, the RDRF interrupt request signal is asserted to request interrupt service.</description>
                  <value>#0</value>
                </enumeratedValue>
                <enumeratedValue>
                  <name>1</name>
                  <description>If RIE is set and the RDRF flag is set, the RDRF DMA request signal is asserted to request a DMA transfer.</description>
                  <value>#1</value>
                </enumeratedValue>
              </enumeratedValues>
            </field>
            <field>
              <name>TDMAS</name>
              <description>Transmitter DMA Select</description>
              <bitOffset>7</bitOffset>
              <bitWidth>1</bitWidth>
              <access>read-write</access>
              <enumeratedValues>
                <enumeratedValue>
                  <name>0</name>
                  <description>If TIE is set and the TDRE flag is set, the TDRE interrupt request signal is asserted to request interrupt service.</description>
                  <value>#0</value>
                </enumeratedValue>
                <enumeratedValue>
                  <name>1</name>
                  <description>If TIE is set and the TDRE flag is set, the TDRE DMA request signal is asserted to request a DMA transfer.</description>
                  <value>#1</value>
                </enumeratedValue>
              </enumeratedValues>
            </field>
          </fields>
        </register>
      </registers>
    </peripheral>
    <peripheral>
      <name>USB0</name>
      <description>Universal Serial Bus, OTG Capable Controller</description>
      <prependToName>USB0_</prependToName>
      <baseAddress>0x40072000</baseAddress>
      <addressBlock>
        <offset>0</offset>
        <size>0x115</size>
        <usage>registers</usage>
      </addressBlock>
      <interrupt>
        <name>USB0</name>
        <value>24</value>
      </interrupt>
      <registers>
        <register>
          <name>PERID</name>
          <description>Peripheral ID register</description>
          <addressOffset>0</addressOffset>
          <size>8</size>
          <access>read-only</access>
          <resetValue>0x4</resetValue>
          <resetMask>0xFF</resetMask>
          <fields>
            <field>
              <name>ID</name>
              <description>Peripheral Identification</description>
              <bitOffset>0</bitOffset>
              <bitWidth>6</bitWidth>
              <access>read-only</access>
            </field>
          </fields>
        </register>
        <register>
          <name>IDCOMP</name>
          <description>Peripheral ID Complement register</description>
          <addressOffset>0x4</addressOffset>
          <size>8</size>
          <access>read-only</access>
          <resetValue>0xFB</resetValue>
          <resetMask>0xFF</resetMask>
          <fields>
            <field>
              <name>NID</name>
              <description>Ones complement of peripheral identification bits.</description>
              <bitOffset>0</bitOffset>
              <bitWidth>6</bitWidth>
              <access>read-only</access>
            </field>
          </fields>
        </register>
        <register>
          <name>REV</name>
          <description>Peripheral Revision register</description>
          <addressOffset>0x8</addressOffset>
          <size>8</size>
          <access>read-only</access>
          <resetValue>0x33</resetValue>
          <resetMask>0xFF</resetMask>
          <fields>
            <field>
              <name>REV</name>
              <description>Revision</description>
              <bitOffset>0</bitOffset>
              <bitWidth>8</bitWidth>
              <access>read-only</access>
            </field>
          </fields>
        </register>
        <register>
          <name>ADDINFO</name>
          <description>Peripheral Additional Info register</description>
          <addressOffset>0xC</addressOffset>
          <size>8</size>
          <access>read-only</access>
          <resetValue>0x1</resetValue>
          <resetMask>0xFF</resetMask>
          <fields>
            <field>
              <name>IEHOST</name>
              <description>When this bit is set, the USB peripheral is operating in host mode.</description>
              <bitOffset>0</bitOffset>
              <bitWidth>1</bitWidth>
              <access>read-only</access>
            </field>
            <field>
              <name>IRQNUM</name>
              <description>Assigned Interrupt Request Number</description>
              <bitOffset>3</bitOffset>
              <bitWidth>5</bitWidth>
              <access>read-only</access>
            </field>
          </fields>
        </register>
        <register>
          <name>OTGISTAT</name>
          <description>OTG Interrupt Status register</description>
          <addressOffset>0x10</addressOffset>
          <size>8</size>
          <access>read-write</access>
          <resetValue>0</resetValue>
          <resetMask>0xFF</resetMask>
          <fields>
            <field>
              <name>AVBUSCHG</name>
              <description>This bit is set when a change in VBUS is detected on an A device.</description>
              <bitOffset>0</bitOffset>
              <bitWidth>1</bitWidth>
              <access>read-write</access>
            </field>
            <field>
              <name>B_SESS_CHG</name>
              <description>This bit is set when a change in VBUS is detected on a B device.</description>
              <bitOffset>2</bitOffset>
              <bitWidth>1</bitWidth>
              <access>read-write</access>
            </field>
            <field>
              <name>SESSVLDCHG</name>
              <description>This bit is set when a change in VBUS is detected indicating a session valid or a session no longer valid</description>
              <bitOffset>3</bitOffset>
              <bitWidth>1</bitWidth>
              <access>read-write</access>
            </field>
            <field>
              <name>LINE_STATE_CHG</name>
              <description>This bit is set when the USB line state changes</description>
              <bitOffset>5</bitOffset>
              <bitWidth>1</bitWidth>
              <access>read-write</access>
            </field>
            <field>
              <name>ONEMSEC</name>
              <description>This bit is set when the 1 millisecond timer expires</description>
              <bitOffset>6</bitOffset>
              <bitWidth>1</bitWidth>
              <access>read-write</access>
            </field>
            <field>
              <name>IDCHG</name>
              <description>This bit is set when a change in the ID Signal from the USB connector is sensed.</description>
              <bitOffset>7</bitOffset>
              <bitWidth>1</bitWidth>
              <access>read-write</access>
            </field>
          </fields>
        </register>
        <register>
          <name>OTGICR</name>
          <description>OTG Interrupt Control register</description>
          <addressOffset>0x14</addressOffset>
          <size>8</size>
          <access>read-write</access>
          <resetValue>0</resetValue>
          <resetMask>0xFF</resetMask>
          <fields>
            <field>
              <name>AVBUSEN</name>
              <description>A VBUS Valid Interrupt Enable</description>
              <bitOffset>0</bitOffset>
              <bitWidth>1</bitWidth>
              <access>read-write</access>
              <enumeratedValues>
                <enumeratedValue>
                  <name>0</name>
                  <description>Disables the AVBUSCHG interrupt.</description>
                  <value>#0</value>
                </enumeratedValue>
                <enumeratedValue>
                  <name>1</name>
                  <description>Enables the AVBUSCHG interrupt.</description>
                  <value>#1</value>
                </enumeratedValue>
              </enumeratedValues>
            </field>
            <field>
              <name>BSESSEN</name>
              <description>B Session END Interrupt Enable</description>
              <bitOffset>2</bitOffset>
              <bitWidth>1</bitWidth>
              <access>read-write</access>
              <enumeratedValues>
                <enumeratedValue>
                  <name>0</name>
                  <description>Disables the B_SESS_CHG interrupt.</description>
                  <value>#0</value>
                </enumeratedValue>
                <enumeratedValue>
                  <name>1</name>
                  <description>Enables the B_SESS_CHG interrupt.</description>
                  <value>#1</value>
                </enumeratedValue>
              </enumeratedValues>
            </field>
            <field>
              <name>SESSVLDEN</name>
              <description>Session Valid Interrupt Enable</description>
              <bitOffset>3</bitOffset>
              <bitWidth>1</bitWidth>
              <access>read-write</access>
              <enumeratedValues>
                <enumeratedValue>
                  <name>0</name>
                  <description>Disables the SESSVLDCHG interrupt.</description>
                  <value>#0</value>
                </enumeratedValue>
                <enumeratedValue>
                  <name>1</name>
                  <description>Enables the SESSVLDCHG interrupt.</description>
                  <value>#1</value>
                </enumeratedValue>
              </enumeratedValues>
            </field>
            <field>
              <name>LINESTATEEN</name>
              <description>Line State Change Interrupt Enable</description>
              <bitOffset>5</bitOffset>
              <bitWidth>1</bitWidth>
              <access>read-write</access>
              <enumeratedValues>
                <enumeratedValue>
                  <name>0</name>
                  <description>Disables the LINE_STAT_CHG interrupt.</description>
                  <value>#0</value>
                </enumeratedValue>
                <enumeratedValue>
                  <name>1</name>
                  <description>Enables the LINE_STAT_CHG interrupt.</description>
                  <value>#1</value>
                </enumeratedValue>
              </enumeratedValues>
            </field>
            <field>
              <name>ONEMSECEN</name>
              <description>One Millisecond Interrupt Enable</description>
              <bitOffset>6</bitOffset>
              <bitWidth>1</bitWidth>
              <access>read-write</access>
              <enumeratedValues>
                <enumeratedValue>
                  <name>0</name>
                  <description>Diables the 1ms timer interrupt.</description>
                  <value>#0</value>
                </enumeratedValue>
                <enumeratedValue>
                  <name>1</name>
                  <description>Enables the 1ms timer interrupt.</description>
                  <value>#1</value>
                </enumeratedValue>
              </enumeratedValues>
            </field>
            <field>
              <name>IDEN</name>
              <description>ID Interrupt Enable</description>
              <bitOffset>7</bitOffset>
              <bitWidth>1</bitWidth>
              <access>read-write</access>
              <enumeratedValues>
                <enumeratedValue>
                  <name>0</name>
                  <description>The ID interrupt is disabled</description>
                  <value>#0</value>
                </enumeratedValue>
                <enumeratedValue>
                  <name>1</name>
                  <description>The ID interrupt is enabled</description>
                  <value>#1</value>
                </enumeratedValue>
              </enumeratedValues>
            </field>
          </fields>
        </register>
        <register>
          <name>OTGSTAT</name>
          <description>OTG Status register</description>
          <addressOffset>0x18</addressOffset>
          <size>8</size>
          <access>read-write</access>
          <resetValue>0</resetValue>
          <resetMask>0xFF</resetMask>
          <fields>
            <field>
              <name>AVBUSVLD</name>
              <description>A VBUS Valid</description>
              <bitOffset>0</bitOffset>
              <bitWidth>1</bitWidth>
              <access>read-write</access>
              <enumeratedValues>
                <enumeratedValue>
                  <name>0</name>
                  <description>The VBUS voltage is below the A VBUS Valid threshold.</description>
                  <value>#0</value>
                </enumeratedValue>
                <enumeratedValue>
                  <name>1</name>
                  <description>The VBUS voltage is above the A VBUS Valid threshold.</description>
                  <value>#1</value>
                </enumeratedValue>
              </enumeratedValues>
            </field>
            <field>
              <name>BSESSEND</name>
              <description>B Session End</description>
              <bitOffset>2</bitOffset>
              <bitWidth>1</bitWidth>
              <access>read-write</access>
              <enumeratedValues>
                <enumeratedValue>
                  <name>0</name>
                  <description>The VBUS voltage is above the B session end threshold.</description>
                  <value>#0</value>
                </enumeratedValue>
                <enumeratedValue>
                  <name>1</name>
                  <description>The VBUS voltage is below the B session end threshold.</description>
                  <value>#1</value>
                </enumeratedValue>
              </enumeratedValues>
            </field>
            <field>
              <name>SESS_VLD</name>
              <description>Session Valid</description>
              <bitOffset>3</bitOffset>
              <bitWidth>1</bitWidth>
              <access>read-write</access>
              <enumeratedValues>
                <enumeratedValue>
                  <name>0</name>
                  <description>The VBUS voltage is below the B session valid threshold</description>
                  <value>#0</value>
                </enumeratedValue>
                <enumeratedValue>
                  <name>1</name>
                  <description>The VBUS voltage is above the B session valid threshold.</description>
                  <value>#1</value>
                </enumeratedValue>
              </enumeratedValues>
            </field>
            <field>
              <name>LINESTATESTABLE</name>
              <description>Indicates that the internal signals that control the LINE_STATE_CHG field of OTGISTAT are stable for at least 1 millisecond</description>
              <bitOffset>5</bitOffset>
              <bitWidth>1</bitWidth>
              <access>read-write</access>
              <enumeratedValues>
                <enumeratedValue>
                  <name>0</name>
                  <description>The LINE_STAT_CHG bit is not yet stable.</description>
                  <value>#0</value>
                </enumeratedValue>
                <enumeratedValue>
                  <name>1</name>
                  <description>The LINE_STAT_CHG bit has been debounced and is stable.</description>
                  <value>#1</value>
                </enumeratedValue>
              </enumeratedValues>
            </field>
            <field>
              <name>ONEMSECEN</name>
              <description>This bit is reserved for the 1ms count, but it is not useful to software.</description>
              <bitOffset>6</bitOffset>
              <bitWidth>1</bitWidth>
              <access>read-write</access>
            </field>
            <field>
              <name>ID</name>
              <description>Indicates the current state of the ID pin on the USB connector</description>
              <bitOffset>7</bitOffset>
              <bitWidth>1</bitWidth>
              <access>read-write</access>
              <enumeratedValues>
                <enumeratedValue>
                  <name>0</name>
                  <description>Indicates a Type A cable is plugged into the USB connector.</description>
                  <value>#0</value>
                </enumeratedValue>
                <enumeratedValue>
                  <name>1</name>
                  <description>Indicates no cable is attached or a Type B cable is plugged into the USB connector.</description>
                  <value>#1</value>
                </enumeratedValue>
              </enumeratedValues>
            </field>
          </fields>
        </register>
        <register>
          <name>OTGCTL</name>
          <description>OTG Control register</description>
          <addressOffset>0x1C</addressOffset>
          <size>8</size>
          <access>read-write</access>
          <resetValue>0</resetValue>
          <resetMask>0xFF</resetMask>
          <fields>
            <field>
              <name>OTGEN</name>
              <description>On-The-Go pullup/pulldown resistor enable</description>
              <bitOffset>2</bitOffset>
              <bitWidth>1</bitWidth>
              <access>read-write</access>
              <enumeratedValues>
                <enumeratedValue>
                  <name>0</name>
                  <description>If USB_EN is 1 and HOST_MODE is 0 in the Control Register (CTL), then the D+ Data Line pull-up resistors are enabled. If HOST_MODE is 1 the D+ and D- Data Line pull-down resistors are engaged.</description>
                  <value>#0</value>
                </enumeratedValue>
                <enumeratedValue>
                  <name>1</name>
                  <description>The pull-up and pull-down controls in this register are used.</description>
                  <value>#1</value>
                </enumeratedValue>
              </enumeratedValues>
            </field>
            <field>
              <name>DMLOW</name>
              <description>D- Data Line pull-down resistor enable</description>
              <bitOffset>4</bitOffset>
              <bitWidth>1</bitWidth>
              <access>read-write</access>
              <enumeratedValues>
                <enumeratedValue>
                  <name>0</name>
                  <description>D- pulldown resistor is not enabled.</description>
                  <value>#0</value>
                </enumeratedValue>
                <enumeratedValue>
                  <name>1</name>
                  <description>D- pulldown resistor is enabled.</description>
                  <value>#1</value>
                </enumeratedValue>
              </enumeratedValues>
            </field>
            <field>
              <name>DPLOW</name>
              <description>D+ Data Line pull-down resistor enable</description>
              <bitOffset>5</bitOffset>
              <bitWidth>1</bitWidth>
              <access>read-write</access>
              <enumeratedValues>
                <enumeratedValue>
                  <name>0</name>
                  <description>D+ pulldown resistor is not enabled.</description>
                  <value>#0</value>
                </enumeratedValue>
                <enumeratedValue>
                  <name>1</name>
                  <description>D+ pulldown resistor is enabled.</description>
                  <value>#1</value>
                </enumeratedValue>
              </enumeratedValues>
            </field>
            <field>
              <name>DPHIGH</name>
              <description>D+ Data Line pullup resistor enable</description>
              <bitOffset>7</bitOffset>
              <bitWidth>1</bitWidth>
              <access>read-write</access>
              <enumeratedValues>
                <enumeratedValue>
                  <name>0</name>
                  <description>D+ pullup resistor is not enabled</description>
                  <value>#0</value>
                </enumeratedValue>
                <enumeratedValue>
                  <name>1</name>
                  <description>D+ pullup resistor is enabled</description>
                  <value>#1</value>
                </enumeratedValue>
              </enumeratedValues>
            </field>
          </fields>
        </register>
        <register>
          <name>ISTAT</name>
          <description>Interrupt Status register</description>
          <addressOffset>0x80</addressOffset>
          <size>8</size>
          <access>read-write</access>
          <resetValue>0</resetValue>
          <resetMask>0xFF</resetMask>
          <fields>
            <field>
              <name>USBRST</name>
              <description>This bit is set when the USB Module has decoded a valid USB reset</description>
              <bitOffset>0</bitOffset>
              <bitWidth>1</bitWidth>
              <access>read-write</access>
            </field>
            <field>
              <name>ERROR</name>
              <description>This bit is set when any of the error conditions within Error Interrupt Status (ERRSTAT) register occur</description>
              <bitOffset>1</bitOffset>
              <bitWidth>1</bitWidth>
              <access>read-write</access>
            </field>
            <field>
              <name>SOFTOK</name>
              <description>This bit is set when the USB Module receives a Start Of Frame (SOF) token</description>
              <bitOffset>2</bitOffset>
              <bitWidth>1</bitWidth>
              <access>read-write</access>
            </field>
            <field>
              <name>TOKDNE</name>
              <description>This bit is set when the current token being processed has completed</description>
              <bitOffset>3</bitOffset>
              <bitWidth>1</bitWidth>
              <access>read-write</access>
            </field>
            <field>
              <name>SLEEP</name>
              <description>This bit is set when the USB Module detects a constant idle on the USB bus for 3 ms</description>
              <bitOffset>4</bitOffset>
              <bitWidth>1</bitWidth>
              <access>read-write</access>
            </field>
            <field>
              <name>RESUME</name>
              <description>This bit is set depending upon the DP/DM signals, and can be used to signal remote wake-up signaling on the USB bus</description>
              <bitOffset>5</bitOffset>
              <bitWidth>1</bitWidth>
              <access>read-write</access>
            </field>
            <field>
              <name>ATTACH</name>
              <description>Attach Interrupt</description>
              <bitOffset>6</bitOffset>
              <bitWidth>1</bitWidth>
              <access>read-write</access>
            </field>
            <field>
              <name>STALL</name>
              <description>Stall Interrupt</description>
              <bitOffset>7</bitOffset>
              <bitWidth>1</bitWidth>
              <access>read-write</access>
            </field>
          </fields>
        </register>
        <register>
          <name>INTEN</name>
          <description>Interrupt Enable register</description>
          <addressOffset>0x84</addressOffset>
          <size>8</size>
          <access>read-write</access>
          <resetValue>0</resetValue>
          <resetMask>0xFF</resetMask>
          <fields>
            <field>
              <name>USBRSTEN</name>
              <description>USBRST Interrupt Enable</description>
              <bitOffset>0</bitOffset>
              <bitWidth>1</bitWidth>
              <access>read-write</access>
              <enumeratedValues>
                <enumeratedValue>
                  <name>0</name>
                  <description>Disables the USBRST interrupt.</description>
                  <value>#0</value>
                </enumeratedValue>
                <enumeratedValue>
                  <name>1</name>
                  <description>Enables the USBRST interrupt.</description>
                  <value>#1</value>
                </enumeratedValue>
              </enumeratedValues>
            </field>
            <field>
              <name>ERROREN</name>
              <description>ERROR Interrupt Enable</description>
              <bitOffset>1</bitOffset>
              <bitWidth>1</bitWidth>
              <access>read-write</access>
              <enumeratedValues>
                <enumeratedValue>
                  <name>0</name>
                  <description>Disables the ERROR interrupt.</description>
                  <value>#0</value>
                </enumeratedValue>
                <enumeratedValue>
                  <name>1</name>
                  <description>Enables the ERROR interrupt.</description>
                  <value>#1</value>
                </enumeratedValue>
              </enumeratedValues>
            </field>
            <field>
              <name>SOFTOKEN</name>
              <description>SOFTOK Interrupt Enable</description>
              <bitOffset>2</bitOffset>
              <bitWidth>1</bitWidth>
              <access>read-write</access>
              <enumeratedValues>
                <enumeratedValue>
                  <name>0</name>
                  <description>Disbles the SOFTOK interrupt.</description>
                  <value>#0</value>
                </enumeratedValue>
                <enumeratedValue>
                  <name>1</name>
                  <description>Enables the SOFTOK interrupt.</description>
                  <value>#1</value>
                </enumeratedValue>
              </enumeratedValues>
            </field>
            <field>
              <name>TOKDNEEN</name>
              <description>TOKDNE Interrupt Enable</description>
              <bitOffset>3</bitOffset>
              <bitWidth>1</bitWidth>
              <access>read-write</access>
              <enumeratedValues>
                <enumeratedValue>
                  <name>0</name>
                  <description>Disables the TOKDNE interrupt.</description>
                  <value>#0</value>
                </enumeratedValue>
                <enumeratedValue>
                  <name>1</name>
                  <description>Enables the TOKDNE interrupt.</description>
                  <value>#1</value>
                </enumeratedValue>
              </enumeratedValues>
            </field>
            <field>
              <name>SLEEPEN</name>
              <description>SLEEP Interrupt Enable</description>
              <bitOffset>4</bitOffset>
              <bitWidth>1</bitWidth>
              <access>read-write</access>
              <enumeratedValues>
                <enumeratedValue>
                  <name>0</name>
                  <description>Disables the SLEEP interrupt.</description>
                  <value>#0</value>
                </enumeratedValue>
                <enumeratedValue>
                  <name>1</name>
                  <description>Enables the SLEEP interrupt.</description>
                  <value>#1</value>
                </enumeratedValue>
              </enumeratedValues>
            </field>
            <field>
              <name>RESUMEEN</name>
              <description>RESUME Interrupt Enable</description>
              <bitOffset>5</bitOffset>
              <bitWidth>1</bitWidth>
              <access>read-write</access>
              <enumeratedValues>
                <enumeratedValue>
                  <name>0</name>
                  <description>Disables the RESUME interrupt.</description>
                  <value>#0</value>
                </enumeratedValue>
                <enumeratedValue>
                  <name>1</name>
                  <description>Enables the RESUME interrupt.</description>
                  <value>#1</value>
                </enumeratedValue>
              </enumeratedValues>
            </field>
            <field>
              <name>ATTACHEN</name>
              <description>ATTACH Interrupt Enable</description>
              <bitOffset>6</bitOffset>
              <bitWidth>1</bitWidth>
              <access>read-write</access>
              <enumeratedValues>
                <enumeratedValue>
                  <name>0</name>
                  <description>Disables the ATTACH interrupt.</description>
                  <value>#0</value>
                </enumeratedValue>
                <enumeratedValue>
                  <name>1</name>
                  <description>Enables the ATTACH interrupt.</description>
                  <value>#1</value>
                </enumeratedValue>
              </enumeratedValues>
            </field>
            <field>
              <name>STALLEN</name>
              <description>STALL Interrupt Enable</description>
              <bitOffset>7</bitOffset>
              <bitWidth>1</bitWidth>
              <access>read-write</access>
              <enumeratedValues>
                <enumeratedValue>
                  <name>0</name>
                  <description>Diasbles the STALL interrupt.</description>
                  <value>#0</value>
                </enumeratedValue>
                <enumeratedValue>
                  <name>1</name>
                  <description>Enables the STALL interrupt.</description>
                  <value>#1</value>
                </enumeratedValue>
              </enumeratedValues>
            </field>
          </fields>
        </register>
        <register>
          <name>ERRSTAT</name>
          <description>Error Interrupt Status register</description>
          <addressOffset>0x88</addressOffset>
          <size>8</size>
          <access>read-write</access>
          <resetValue>0</resetValue>
          <resetMask>0xFF</resetMask>
          <fields>
            <field>
              <name>PIDERR</name>
              <description>This bit is set when the PID check field fails.</description>
              <bitOffset>0</bitOffset>
              <bitWidth>1</bitWidth>
              <access>read-write</access>
            </field>
            <field>
              <name>CRC5EOF</name>
              <description>This error interrupt has two functions</description>
              <bitOffset>1</bitOffset>
              <bitWidth>1</bitWidth>
              <access>read-write</access>
            </field>
            <field>
              <name>CRC16</name>
              <description>This bit is set when a data packet is rejected due to a CRC16 error.</description>
              <bitOffset>2</bitOffset>
              <bitWidth>1</bitWidth>
              <access>read-write</access>
            </field>
            <field>
              <name>DFN8</name>
              <description>This bit is set if the data field received was not 8 bits in length</description>
              <bitOffset>3</bitOffset>
              <bitWidth>1</bitWidth>
              <access>read-write</access>
            </field>
            <field>
              <name>BTOERR</name>
              <description>This bit is set when a bus turnaround timeout error occurs</description>
              <bitOffset>4</bitOffset>
              <bitWidth>1</bitWidth>
              <access>read-write</access>
            </field>
            <field>
              <name>DMAERR</name>
              <description>This bit is set if the USB Module has requested a DMA access to read a new BDT but has not been given the bus before it needs to receive or transmit data</description>
              <bitOffset>5</bitOffset>
              <bitWidth>1</bitWidth>
              <access>read-write</access>
            </field>
            <field>
              <name>BTSERR</name>
              <description>This bit is set when a bit stuff error is detected</description>
              <bitOffset>7</bitOffset>
              <bitWidth>1</bitWidth>
              <access>read-write</access>
            </field>
          </fields>
        </register>
        <register>
          <name>ERREN</name>
          <description>Error Interrupt Enable register</description>
          <addressOffset>0x8C</addressOffset>
          <size>8</size>
          <access>read-write</access>
          <resetValue>0</resetValue>
          <resetMask>0xFF</resetMask>
          <fields>
            <field>
              <name>PIDERREN</name>
              <description>PIDERR Interrupt Enable</description>
              <bitOffset>0</bitOffset>
              <bitWidth>1</bitWidth>
              <access>read-write</access>
              <enumeratedValues>
                <enumeratedValue>
                  <name>0</name>
                  <description>Disables the PIDERR interrupt.</description>
                  <value>#0</value>
                </enumeratedValue>
                <enumeratedValue>
                  <name>1</name>
                  <description>Enters the PIDERR interrupt.</description>
                  <value>#1</value>
                </enumeratedValue>
              </enumeratedValues>
            </field>
            <field>
              <name>CRC5EOFEN</name>
              <description>CRC5/EOF Interrupt Enable</description>
              <bitOffset>1</bitOffset>
              <bitWidth>1</bitWidth>
              <access>read-write</access>
              <enumeratedValues>
                <enumeratedValue>
                  <name>0</name>
                  <description>Disables the CRC5/EOF interrupt.</description>
                  <value>#0</value>
                </enumeratedValue>
                <enumeratedValue>
                  <name>1</name>
                  <description>Enables the CRC5/EOF interrupt.</description>
                  <value>#1</value>
                </enumeratedValue>
              </enumeratedValues>
            </field>
            <field>
              <name>CRC16EN</name>
              <description>CRC16 Interrupt Enable</description>
              <bitOffset>2</bitOffset>
              <bitWidth>1</bitWidth>
              <access>read-write</access>
              <enumeratedValues>
                <enumeratedValue>
                  <name>0</name>
                  <description>Disables the CRC16 interrupt.</description>
                  <value>#0</value>
                </enumeratedValue>
                <enumeratedValue>
                  <name>1</name>
                  <description>Enables the CRC16 interrupt.</description>
                  <value>#1</value>
                </enumeratedValue>
              </enumeratedValues>
            </field>
            <field>
              <name>DFN8EN</name>
              <description>DFN8 Interrupt Enable</description>
              <bitOffset>3</bitOffset>
              <bitWidth>1</bitWidth>
              <access>read-write</access>
              <enumeratedValues>
                <enumeratedValue>
                  <name>0</name>
                  <description>Disables the DFN8 interrupt.</description>
                  <value>#0</value>
                </enumeratedValue>
                <enumeratedValue>
                  <name>1</name>
                  <description>Enables the DFN8 interrupt.</description>
                  <value>#1</value>
                </enumeratedValue>
              </enumeratedValues>
            </field>
            <field>
              <name>BTOERREN</name>
              <description>BTOERR Interrupt Enable</description>
              <bitOffset>4</bitOffset>
              <bitWidth>1</bitWidth>
              <access>read-write</access>
              <enumeratedValues>
                <enumeratedValue>
                  <name>0</name>
                  <description>Disables the BTOERR interrupt.</description>
                  <value>#0</value>
                </enumeratedValue>
                <enumeratedValue>
                  <name>1</name>
                  <description>Enables the BTOERR interrupt.</description>
                  <value>#1</value>
                </enumeratedValue>
              </enumeratedValues>
            </field>
            <field>
              <name>DMAERREN</name>
              <description>DMAERR Interrupt Enable</description>
              <bitOffset>5</bitOffset>
              <bitWidth>1</bitWidth>
              <access>read-write</access>
              <enumeratedValues>
                <enumeratedValue>
                  <name>0</name>
                  <description>Disables the DMAERR interrupt.</description>
                  <value>#0</value>
                </enumeratedValue>
                <enumeratedValue>
                  <name>1</name>
                  <description>Enables the DMAERR interrupt.</description>
                  <value>#1</value>
                </enumeratedValue>
              </enumeratedValues>
            </field>
            <field>
              <name>BTSERREN</name>
              <description>BTSERR Interrupt Enable</description>
              <bitOffset>7</bitOffset>
              <bitWidth>1</bitWidth>
              <access>read-write</access>
              <enumeratedValues>
                <enumeratedValue>
                  <name>0</name>
                  <description>Disables the BTSERR interrupt.</description>
                  <value>#0</value>
                </enumeratedValue>
                <enumeratedValue>
                  <name>1</name>
                  <description>Enables the BTSERR interrupt.</description>
                  <value>#1</value>
                </enumeratedValue>
              </enumeratedValues>
            </field>
          </fields>
        </register>
        <register>
          <name>STAT</name>
          <description>Status register</description>
          <addressOffset>0x90</addressOffset>
          <size>8</size>
          <access>read-only</access>
          <resetValue>0</resetValue>
          <resetMask>0xFF</resetMask>
          <fields>
            <field>
              <name>ODD</name>
              <description>This bit is set if the last buffer descriptor updated was in the odd bank of the BDT.</description>
              <bitOffset>2</bitOffset>
              <bitWidth>1</bitWidth>
              <access>read-only</access>
            </field>
            <field>
              <name>TX</name>
              <description>Transmit Indicator</description>
              <bitOffset>3</bitOffset>
              <bitWidth>1</bitWidth>
              <access>read-only</access>
              <enumeratedValues>
                <enumeratedValue>
                  <name>0</name>
                  <description>The most recent transaction was a receive operation.</description>
                  <value>#0</value>
                </enumeratedValue>
                <enumeratedValue>
                  <name>1</name>
                  <description>The most recent transaction was a transmit operation.</description>
                  <value>#1</value>
                </enumeratedValue>
              </enumeratedValues>
            </field>
            <field>
              <name>ENDP</name>
              <description>This four-bit field encodes the endpoint address that received or transmitted the previous token</description>
              <bitOffset>4</bitOffset>
              <bitWidth>4</bitWidth>
              <access>read-only</access>
            </field>
          </fields>
        </register>
        <register>
          <name>CTL</name>
          <description>Control register</description>
          <addressOffset>0x94</addressOffset>
          <size>8</size>
          <access>read-write</access>
          <resetValue>0</resetValue>
          <resetMask>0xFF</resetMask>
          <fields>
            <field>
              <name>USBENSOFEN</name>
              <description>USB Enable</description>
              <bitOffset>0</bitOffset>
              <bitWidth>1</bitWidth>
              <access>read-write</access>
              <enumeratedValues>
                <enumeratedValue>
                  <name>0</name>
                  <description>Disables the USB Module.</description>
                  <value>#0</value>
                </enumeratedValue>
                <enumeratedValue>
                  <name>1</name>
                  <description>Enables the USB Module.</description>
                  <value>#1</value>
                </enumeratedValue>
              </enumeratedValues>
            </field>
            <field>
              <name>ODDRST</name>
              <description>Setting this bit to 1 resets all the BDT ODD ping/pong fields to 0, which then specifies the EVEN BDT bank</description>
              <bitOffset>1</bitOffset>
              <bitWidth>1</bitWidth>
              <access>read-write</access>
            </field>
            <field>
              <name>RESUME</name>
              <description>When set to 1 this bit enables the USB Module to execute resume signaling</description>
              <bitOffset>2</bitOffset>
              <bitWidth>1</bitWidth>
              <access>read-write</access>
            </field>
            <field>
              <name>HOSTMODEEN</name>
              <description>When set to 1, this bit enables the USB Module to operate in Host mode</description>
              <bitOffset>3</bitOffset>
              <bitWidth>1</bitWidth>
              <access>read-write</access>
            </field>
            <field>
              <name>RESET</name>
              <description>Setting this bit enables the USB Module to generate USB reset signaling</description>
              <bitOffset>4</bitOffset>
              <bitWidth>1</bitWidth>
              <access>read-write</access>
            </field>
            <field>
              <name>TXSUSPENDTOKENBUSY</name>
              <description>In Host mode, TOKEN_BUSY is set when the USB module is busy executing a USB token</description>
              <bitOffset>5</bitOffset>
              <bitWidth>1</bitWidth>
              <access>read-write</access>
            </field>
            <field>
              <name>SE0</name>
              <description>Live USB Single Ended Zero signal</description>
              <bitOffset>6</bitOffset>
              <bitWidth>1</bitWidth>
              <access>read-write</access>
            </field>
            <field>
              <name>JSTATE</name>
              <description>Live USB differential receiver JSTATE signal</description>
              <bitOffset>7</bitOffset>
              <bitWidth>1</bitWidth>
              <access>read-write</access>
            </field>
          </fields>
        </register>
        <register>
          <name>ADDR</name>
          <description>Address register</description>
          <addressOffset>0x98</addressOffset>
          <size>8</size>
          <access>read-write</access>
          <resetValue>0</resetValue>
          <resetMask>0xFF</resetMask>
          <fields>
            <field>
              <name>ADDR</name>
              <description>USB Address</description>
              <bitOffset>0</bitOffset>
              <bitWidth>7</bitWidth>
              <access>read-write</access>
            </field>
            <field>
              <name>LSEN</name>
              <description>Low Speed Enable bit</description>
              <bitOffset>7</bitOffset>
              <bitWidth>1</bitWidth>
              <access>read-write</access>
            </field>
          </fields>
        </register>
        <register>
          <name>BDTPAGE1</name>
          <description>BDT Page register 1</description>
          <addressOffset>0x9C</addressOffset>
          <size>8</size>
          <access>read-write</access>
          <resetValue>0</resetValue>
          <resetMask>0xFF</resetMask>
          <fields>
            <field>
              <name>BDTBA</name>
              <description>Provides address bits 15 through 9 of the BDT base address.</description>
              <bitOffset>1</bitOffset>
              <bitWidth>7</bitWidth>
              <access>read-write</access>
            </field>
          </fields>
        </register>
        <register>
          <name>FRMNUML</name>
          <description>Frame Number register Low</description>
          <addressOffset>0xA0</addressOffset>
          <size>8</size>
          <access>read-write</access>
          <resetValue>0</resetValue>
          <resetMask>0xFF</resetMask>
          <fields>
            <field>
              <name>FRM</name>
              <description>This 8-bit field and the 3-bit field in the Frame Number Register High are used to compute the address where the current Buffer Descriptor Table (BDT) resides in system memory</description>
              <bitOffset>0</bitOffset>
              <bitWidth>8</bitWidth>
              <access>read-write</access>
            </field>
          </fields>
        </register>
        <register>
          <name>FRMNUMH</name>
          <description>Frame Number register High</description>
          <addressOffset>0xA4</addressOffset>
          <size>8</size>
          <access>read-write</access>
          <resetValue>0</resetValue>
          <resetMask>0xFF</resetMask>
          <fields>
            <field>
              <name>FRM</name>
              <description>This 3-bit field and the 8-bit field in the Frame Number Register Low are used to compute the address where the current Buffer Descriptor Table (BDT) resides in system memory</description>
              <bitOffset>0</bitOffset>
              <bitWidth>3</bitWidth>
              <access>read-write</access>
            </field>
          </fields>
        </register>
        <register>
          <name>TOKEN</name>
          <description>Token register</description>
          <addressOffset>0xA8</addressOffset>
          <size>8</size>
          <access>read-write</access>
          <resetValue>0</resetValue>
          <resetMask>0xFF</resetMask>
          <fields>
            <field>
              <name>TOKENENDPT</name>
              <description>Holds the Endpoint address for the token command</description>
              <bitOffset>0</bitOffset>
              <bitWidth>4</bitWidth>
              <access>read-write</access>
            </field>
            <field>
              <name>TOKENPID</name>
              <description>Contains the token type executed by the USB module.</description>
              <bitOffset>4</bitOffset>
              <bitWidth>4</bitWidth>
              <access>read-write</access>
              <enumeratedValues>
                <enumeratedValue>
                  <name>0001</name>
                  <description>OUT Token. USB Module performs an OUT (TX) transaction.</description>
                  <value>#0001</value>
                </enumeratedValue>
                <enumeratedValue>
                  <name>1001</name>
                  <description>IN Token. USB Module performs an In (RX) transaction.</description>
                  <value>#1001</value>
                </enumeratedValue>
                <enumeratedValue>
                  <name>1101</name>
                  <description>SETUP Token. USB Module performs a SETUP (TX) transaction</description>
                  <value>#1101</value>
                </enumeratedValue>
              </enumeratedValues>
            </field>
          </fields>
        </register>
        <register>
          <name>SOFTHLD</name>
          <description>SOF Threshold register</description>
          <addressOffset>0xAC</addressOffset>
          <size>8</size>
          <access>read-write</access>
          <resetValue>0</resetValue>
          <resetMask>0xFF</resetMask>
          <fields>
            <field>
              <name>CNT</name>
              <description>Represents the SOF count threshold in byte times.</description>
              <bitOffset>0</bitOffset>
              <bitWidth>8</bitWidth>
              <access>read-write</access>
            </field>
          </fields>
        </register>
        <register>
          <name>BDTPAGE2</name>
          <description>BDT Page Register 2</description>
          <addressOffset>0xB0</addressOffset>
          <size>8</size>
          <access>read-write</access>
          <resetValue>0</resetValue>
          <resetMask>0xFF</resetMask>
          <fields>
            <field>
              <name>BDTBA</name>
              <description>Provides address bits 23 through 16 of the BDT base address that defines the location of Buffer Descriptor Table resides in system memory</description>
              <bitOffset>0</bitOffset>
              <bitWidth>8</bitWidth>
              <access>read-write</access>
            </field>
          </fields>
        </register>
        <register>
          <name>BDTPAGE3</name>
          <description>BDT Page Register 3</description>
          <addressOffset>0xB4</addressOffset>
          <size>8</size>
          <access>read-write</access>
          <resetValue>0</resetValue>
          <resetMask>0xFF</resetMask>
          <fields>
            <field>
              <name>BDTBA</name>
              <description>Provides address bits 31 through 24 of the BDT base address that defines the location of Buffer Descriptor Table resides in system memory</description>
              <bitOffset>0</bitOffset>
              <bitWidth>8</bitWidth>
              <access>read-write</access>
            </field>
          </fields>
        </register>
        <register>
          <dim>16</dim>
          <dimIncrement>0x4</dimIncrement>
          <dimIndex>0,1,2,3,4,5,6,7,8,9,10,11,12,13,14,15</dimIndex>
          <name>ENDPT%s</name>
          <description>Endpoint Control register</description>
          <addressOffset>0xC0</addressOffset>
          <size>8</size>
          <access>read-write</access>
          <resetValue>0</resetValue>
          <resetMask>0xFF</resetMask>
          <fields>
            <field>
              <name>EPHSHK</name>
              <description>When set this bit enables an endpoint to perform handshaking during a transaction to this endpoint</description>
              <bitOffset>0</bitOffset>
              <bitWidth>1</bitWidth>
              <access>read-write</access>
            </field>
            <field>
              <name>EPSTALL</name>
              <description>When set this bit indicates that the endpoint is called</description>
              <bitOffset>1</bitOffset>
              <bitWidth>1</bitWidth>
              <access>read-write</access>
            </field>
            <field>
              <name>EPTXEN</name>
              <description>This bit, when set, enables the endpoint for TX transfers.</description>
              <bitOffset>2</bitOffset>
              <bitWidth>1</bitWidth>
              <access>read-write</access>
            </field>
            <field>
              <name>EPRXEN</name>
              <description>This bit, when set, enables the endpoint for RX transfers.</description>
              <bitOffset>3</bitOffset>
              <bitWidth>1</bitWidth>
              <access>read-write</access>
            </field>
            <field>
              <name>EPCTLDIS</name>
              <description>This bit, when set, disables control (SETUP) transfers</description>
              <bitOffset>4</bitOffset>
              <bitWidth>1</bitWidth>
              <access>read-write</access>
            </field>
            <field>
              <name>RETRYDIS</name>
              <description>This is a Host mode only bit and is present in the control register for endpoint 0 (ENDPT0) only</description>
              <bitOffset>6</bitOffset>
              <bitWidth>1</bitWidth>
              <access>read-write</access>
            </field>
            <field>
              <name>HOSTWOHUB</name>
              <description>This is a Host mode only field and is present in the control register for endpoint 0 (ENDPT0) only</description>
              <bitOffset>7</bitOffset>
              <bitWidth>1</bitWidth>
              <access>read-write</access>
            </field>
          </fields>
        </register>
        <register>
          <name>USBCTRL</name>
          <description>USB Control register</description>
          <addressOffset>0x100</addressOffset>
          <size>8</size>
          <access>read-write</access>
          <resetValue>0xC0</resetValue>
          <resetMask>0xFF</resetMask>
          <fields>
            <field>
              <name>PDE</name>
              <description>Enables the weak pulldowns on the USB transceiver.</description>
              <bitOffset>6</bitOffset>
              <bitWidth>1</bitWidth>
              <access>read-write</access>
              <enumeratedValues>
                <enumeratedValue>
                  <name>0</name>
                  <description>Weak pulldowns are disabled on D+ and D-.</description>
                  <value>#0</value>
                </enumeratedValue>
                <enumeratedValue>
                  <name>1</name>
                  <description>Weak pulldowns are enabled on D+ and D-.</description>
                  <value>#1</value>
                </enumeratedValue>
              </enumeratedValues>
            </field>
            <field>
              <name>SUSP</name>
              <description>Places the USB transceiver into the suspend state.</description>
              <bitOffset>7</bitOffset>
              <bitWidth>1</bitWidth>
              <access>read-write</access>
              <enumeratedValues>
                <enumeratedValue>
                  <name>0</name>
                  <description>USB transceiver is not in suspend state.</description>
                  <value>#0</value>
                </enumeratedValue>
                <enumeratedValue>
                  <name>1</name>
                  <description>USB transceiver is in suspend state.</description>
                  <value>#1</value>
                </enumeratedValue>
              </enumeratedValues>
            </field>
          </fields>
        </register>
        <register>
          <name>OBSERVE</name>
          <description>USB OTG Observe register</description>
          <addressOffset>0x104</addressOffset>
          <size>8</size>
          <access>read-only</access>
          <resetValue>0x50</resetValue>
          <resetMask>0xFF</resetMask>
          <fields>
            <field>
              <name>DMPD</name>
              <description>Provides observability of the D- Pulldown signal output from the USB OTG module</description>
              <bitOffset>4</bitOffset>
              <bitWidth>1</bitWidth>
              <access>read-only</access>
              <enumeratedValues>
                <enumeratedValue>
                  <name>0</name>
                  <description>D- pulldown disabled.</description>
                  <value>#0</value>
                </enumeratedValue>
                <enumeratedValue>
                  <name>1</name>
                  <description>D- pulldown enabled.</description>
                  <value>#1</value>
                </enumeratedValue>
              </enumeratedValues>
            </field>
            <field>
              <name>DPPD</name>
              <description>Provides observability of the D+ Pulldown . signal output from the USB OTG module</description>
              <bitOffset>6</bitOffset>
              <bitWidth>1</bitWidth>
              <access>read-only</access>
              <enumeratedValues>
                <enumeratedValue>
                  <name>0</name>
                  <description>D+ pulldown disabled.</description>
                  <value>#0</value>
                </enumeratedValue>
                <enumeratedValue>
                  <name>1</name>
                  <description>D+ pulldown enabled.</description>
                  <value>#1</value>
                </enumeratedValue>
              </enumeratedValues>
            </field>
            <field>
              <name>DPPU</name>
              <description>Provides observability of the D+ Pullup . signal output from the USB OTG module</description>
              <bitOffset>7</bitOffset>
              <bitWidth>1</bitWidth>
              <access>read-only</access>
              <enumeratedValues>
                <enumeratedValue>
                  <name>0</name>
                  <description>D+ pullup disabled.</description>
                  <value>#0</value>
                </enumeratedValue>
                <enumeratedValue>
                  <name>1</name>
                  <description>D+ pullup enabled.</description>
                  <value>#1</value>
                </enumeratedValue>
              </enumeratedValues>
            </field>
          </fields>
        </register>
        <register>
          <name>CONTROL</name>
          <description>USB OTG Control register</description>
          <addressOffset>0x108</addressOffset>
          <size>8</size>
          <access>read-write</access>
          <resetValue>0</resetValue>
          <resetMask>0xFF</resetMask>
          <fields>
            <field>
              <name>DPPULLUPNONOTG</name>
              <description>Provides control of the DP Pullup in the USB OTG module, if USB is configured in non-OTG device mode</description>
              <bitOffset>4</bitOffset>
              <bitWidth>1</bitWidth>
              <access>read-write</access>
              <enumeratedValues>
                <enumeratedValue>
                  <name>0</name>
                  <description>DP Pullup in non-OTG device mode is not enabled.</description>
                  <value>#0</value>
                </enumeratedValue>
                <enumeratedValue>
                  <name>1</name>
                  <description>DP Pullup in non-OTG device mode is enabled.</description>
                  <value>#1</value>
                </enumeratedValue>
              </enumeratedValues>
            </field>
          </fields>
        </register>
        <register>
          <name>USBTRC0</name>
          <description>USB Transceiver Control register 0</description>
          <addressOffset>0x10C</addressOffset>
          <size>8</size>
          <access>read-write</access>
          <resetValue>0</resetValue>
          <resetMask>0xFF</resetMask>
          <fields>
            <field>
              <name>USB_RESUME_INT</name>
              <description>USB Asynchronous Interrupt</description>
              <bitOffset>0</bitOffset>
              <bitWidth>1</bitWidth>
              <access>read-only</access>
              <enumeratedValues>
                <enumeratedValue>
                  <name>0</name>
                  <description>No interrupt was generated.</description>
                  <value>#0</value>
                </enumeratedValue>
                <enumeratedValue>
                  <name>1</name>
                  <description>Interrupt was generated because of the USB asynchronous interrupt.</description>
                  <value>#1</value>
                </enumeratedValue>
              </enumeratedValues>
            </field>
            <field>
              <name>SYNC_DET</name>
              <description>Synchronous USB Interrupt Detect</description>
              <bitOffset>1</bitOffset>
              <bitWidth>1</bitWidth>
              <access>read-only</access>
              <enumeratedValues>
                <enumeratedValue>
                  <name>0</name>
                  <description>Synchronous interrupt has not been detected.</description>
                  <value>#0</value>
                </enumeratedValue>
                <enumeratedValue>
                  <name>1</name>
                  <description>Synchronous interrupt has been detected.</description>
                  <value>#1</value>
                </enumeratedValue>
              </enumeratedValues>
            </field>
            <field>
              <name>USBRESMEN</name>
              <description>Asynchronous Resume Interrupt Enable</description>
              <bitOffset>5</bitOffset>
              <bitWidth>1</bitWidth>
              <access>read-write</access>
              <enumeratedValues>
                <enumeratedValue>
                  <name>0</name>
                  <description>USB asynchronous wakeup from suspend mode disabled.</description>
                  <value>#0</value>
                </enumeratedValue>
                <enumeratedValue>
                  <name>1</name>
                  <description>USB asynchronous wakeup from suspend mode enabled. The asynchronous resume interrupt differs from the synchronous resume interrupt in that it asynchronously detects K-state using the unfiltered state of the D+ and D- pins. This interupt should only be enabled when the Transceiver is suspended.</description>
                  <value>#1</value>
                </enumeratedValue>
              </enumeratedValues>
            </field>
            <field>
              <name>USBRESET</name>
              <description>USB Reset</description>
              <bitOffset>7</bitOffset>
              <bitWidth>1</bitWidth>
              <access>write-only</access>
              <enumeratedValues>
                <enumeratedValue>
                  <name>0</name>
                  <description>Normal USB module operation.</description>
                  <value>#0</value>
                </enumeratedValue>
                <enumeratedValue>
                  <name>1</name>
                  <description>Returns the USB module to its reset state.</description>
                  <value>#1</value>
                </enumeratedValue>
              </enumeratedValues>
            </field>
          </fields>
        </register>
        <register>
          <name>USBFRMADJUST</name>
          <description>Frame Adjust Register</description>
          <addressOffset>0x114</addressOffset>
          <size>8</size>
          <access>read-write</access>
          <resetValue>0</resetValue>
          <resetMask>0xFF</resetMask>
          <fields>
            <field>
              <name>ADJ</name>
              <description>Frame Adjustment</description>
              <bitOffset>0</bitOffset>
              <bitWidth>8</bitWidth>
              <access>read-write</access>
            </field>
          </fields>
        </register>
      </registers>
    </peripheral>
    <peripheral>
      <name>CMP0</name>
      <description>High-Speed Comparator (CMP), Voltage Reference (VREF) Digital-to-Analog Converter (DAC), and Analog Mux (ANMUX)</description>
      <prependToName>CMP0_</prependToName>
      <baseAddress>0x40073000</baseAddress>
      <addressBlock>
        <offset>0</offset>
        <size>0x6</size>
        <usage>registers</usage>
      </addressBlock>
      <interrupt>
        <name>CMP0</name>
        <value>16</value>
      </interrupt>
      <registers>
        <register>
          <name>CR0</name>
          <description>CMP Control Register 0</description>
          <addressOffset>0</addressOffset>
          <size>8</size>
          <access>read-write</access>
          <resetValue>0</resetValue>
          <resetMask>0xFF</resetMask>
          <fields>
            <field>
              <name>HYSTCTR</name>
              <description>Comparator hard block hysteresis control</description>
              <bitOffset>0</bitOffset>
              <bitWidth>2</bitWidth>
              <access>read-write</access>
              <enumeratedValues>
                <enumeratedValue>
                  <name>00</name>
                  <description>Level 0</description>
                  <value>#00</value>
                </enumeratedValue>
                <enumeratedValue>
                  <name>01</name>
                  <description>Level 1</description>
                  <value>#01</value>
                </enumeratedValue>
                <enumeratedValue>
                  <name>10</name>
                  <description>Level 2</description>
                  <value>#10</value>
                </enumeratedValue>
                <enumeratedValue>
                  <name>11</name>
                  <description>Level 3</description>
                  <value>#11</value>
                </enumeratedValue>
              </enumeratedValues>
            </field>
            <field>
              <name>FILTER_CNT</name>
              <description>Filter Sample Count</description>
              <bitOffset>4</bitOffset>
              <bitWidth>3</bitWidth>
              <access>read-write</access>
              <enumeratedValues>
                <enumeratedValue>
                  <name>000</name>
                  <description>Filter is disabled. If SE = 1, then COUT is a logic 0. This is not a legal state, and is not recommended. If SE = 0, COUT = COUTA.</description>
                  <value>#000</value>
                </enumeratedValue>
                <enumeratedValue>
                  <name>001</name>
                  <description>One sample must agree. The comparator output is simply sampled.</description>
                  <value>#001</value>
                </enumeratedValue>
                <enumeratedValue>
                  <name>010</name>
                  <description>2 consecutive samples must agree.</description>
                  <value>#010</value>
                </enumeratedValue>
                <enumeratedValue>
                  <name>011</name>
                  <description>3 consecutive samples must agree.</description>
                  <value>#011</value>
                </enumeratedValue>
                <enumeratedValue>
                  <name>100</name>
                  <description>4 consecutive samples must agree.</description>
                  <value>#100</value>
                </enumeratedValue>
                <enumeratedValue>
                  <name>101</name>
                  <description>5 consecutive samples must agree.</description>
                  <value>#101</value>
                </enumeratedValue>
                <enumeratedValue>
                  <name>110</name>
                  <description>6 consecutive samples must agree.</description>
                  <value>#110</value>
                </enumeratedValue>
                <enumeratedValue>
                  <name>111</name>
                  <description>7 consecutive samples must agree.</description>
                  <value>#111</value>
                </enumeratedValue>
              </enumeratedValues>
            </field>
          </fields>
        </register>
        <register>
          <name>CR1</name>
          <description>CMP Control Register 1</description>
          <addressOffset>0x1</addressOffset>
          <size>8</size>
          <access>read-write</access>
          <resetValue>0</resetValue>
          <resetMask>0xFF</resetMask>
          <fields>
            <field>
              <name>EN</name>
              <description>Comparator Module Enable</description>
              <bitOffset>0</bitOffset>
              <bitWidth>1</bitWidth>
              <access>read-write</access>
              <enumeratedValues>
                <enumeratedValue>
                  <name>0</name>
                  <description>Analog Comparator is disabled.</description>
                  <value>#0</value>
                </enumeratedValue>
                <enumeratedValue>
                  <name>1</name>
                  <description>Analog Comparator is enabled.</description>
                  <value>#1</value>
                </enumeratedValue>
              </enumeratedValues>
            </field>
            <field>
              <name>OPE</name>
              <description>Comparator Output Pin Enable</description>
              <bitOffset>1</bitOffset>
              <bitWidth>1</bitWidth>
              <access>read-write</access>
              <enumeratedValues>
                <enumeratedValue>
                  <name>0</name>
                  <description>CMPO is not available on the associated CMPO output pin. If the comparator does not own the pin, this field has no effect.</description>
                  <value>#0</value>
                </enumeratedValue>
                <enumeratedValue>
                  <name>1</name>
                  <description>CMPO is available on the associated CMPO output pin. The comparator output (CMPO) is driven out on the associated CMPO output pin if the comparator owns the pin. If the comparator does not own the field, this bit has no effect.</description>
                  <value>#1</value>
                </enumeratedValue>
              </enumeratedValues>
            </field>
            <field>
              <name>COS</name>
              <description>Comparator Output Select</description>
              <bitOffset>2</bitOffset>
              <bitWidth>1</bitWidth>
              <access>read-write</access>
              <enumeratedValues>
                <enumeratedValue>
                  <name>0</name>
                  <description>Set the filtered comparator output (CMPO) to equal COUT.</description>
                  <value>#0</value>
                </enumeratedValue>
                <enumeratedValue>
                  <name>1</name>
                  <description>Set the unfiltered comparator output (CMPO) to equal COUTA.</description>
                  <value>#1</value>
                </enumeratedValue>
              </enumeratedValues>
            </field>
            <field>
              <name>INV</name>
              <description>Comparator INVERT</description>
              <bitOffset>3</bitOffset>
              <bitWidth>1</bitWidth>
              <access>read-write</access>
              <enumeratedValues>
                <enumeratedValue>
                  <name>0</name>
                  <description>Does not invert the comparator output.</description>
                  <value>#0</value>
                </enumeratedValue>
                <enumeratedValue>
                  <name>1</name>
                  <description>Inverts the comparator output.</description>
                  <value>#1</value>
                </enumeratedValue>
              </enumeratedValues>
            </field>
            <field>
              <name>PMODE</name>
              <description>Power Mode Select</description>
              <bitOffset>4</bitOffset>
              <bitWidth>1</bitWidth>
              <access>read-write</access>
              <enumeratedValues>
                <enumeratedValue>
                  <name>0</name>
                  <description>Low-Speed (LS) Comparison mode selected. In this mode, CMP has slower output propagation delay and lower current consumption.</description>
                  <value>#0</value>
                </enumeratedValue>
                <enumeratedValue>
                  <name>1</name>
                  <description>High-Speed (HS) Comparison mode selected. In this mode, CMP has faster output propagation delay and higher current consumption.</description>
                  <value>#1</value>
                </enumeratedValue>
              </enumeratedValues>
            </field>
            <field>
              <name>TRIGM</name>
              <description>Trigger Mode Enable</description>
              <bitOffset>5</bitOffset>
              <bitWidth>1</bitWidth>
              <access>read-write</access>
              <enumeratedValues>
                <enumeratedValue>
                  <name>0</name>
                  <description>Trigger mode is disabled.</description>
                  <value>#0</value>
                </enumeratedValue>
                <enumeratedValue>
                  <name>1</name>
                  <description>Trigger mode is enabled.</description>
                  <value>#1</value>
                </enumeratedValue>
              </enumeratedValues>
            </field>
            <field>
              <name>WE</name>
              <description>Windowing Enable</description>
              <bitOffset>6</bitOffset>
              <bitWidth>1</bitWidth>
              <access>read-write</access>
              <enumeratedValues>
                <enumeratedValue>
                  <name>0</name>
                  <description>Windowing mode is not selected.</description>
                  <value>#0</value>
                </enumeratedValue>
                <enumeratedValue>
                  <name>1</name>
                  <description>Windowing mode is selected.</description>
                  <value>#1</value>
                </enumeratedValue>
              </enumeratedValues>
            </field>
            <field>
              <name>SE</name>
              <description>Sample Enable</description>
              <bitOffset>7</bitOffset>
              <bitWidth>1</bitWidth>
              <access>read-write</access>
              <enumeratedValues>
                <enumeratedValue>
                  <name>0</name>
                  <description>Sampling mode is not selected.</description>
                  <value>#0</value>
                </enumeratedValue>
                <enumeratedValue>
                  <name>1</name>
                  <description>Sampling mode is selected.</description>
                  <value>#1</value>
                </enumeratedValue>
              </enumeratedValues>
            </field>
          </fields>
        </register>
        <register>
          <name>FPR</name>
          <description>CMP Filter Period Register</description>
          <addressOffset>0x2</addressOffset>
          <size>8</size>
          <access>read-write</access>
          <resetValue>0</resetValue>
          <resetMask>0xFF</resetMask>
          <fields>
            <field>
              <name>FILT_PER</name>
              <description>Filter Sample Period</description>
              <bitOffset>0</bitOffset>
              <bitWidth>8</bitWidth>
              <access>read-write</access>
            </field>
          </fields>
        </register>
        <register>
          <name>SCR</name>
          <description>CMP Status and Control Register</description>
          <addressOffset>0x3</addressOffset>
          <size>8</size>
          <access>read-write</access>
          <resetValue>0</resetValue>
          <resetMask>0xFF</resetMask>
          <fields>
            <field>
              <name>COUT</name>
              <description>Analog Comparator Output</description>
              <bitOffset>0</bitOffset>
              <bitWidth>1</bitWidth>
              <access>read-only</access>
            </field>
            <field>
              <name>CFF</name>
              <description>Analog Comparator Flag Falling</description>
              <bitOffset>1</bitOffset>
              <bitWidth>1</bitWidth>
              <access>read-write</access>
              <enumeratedValues>
                <enumeratedValue>
                  <name>0</name>
                  <description>Falling-edge on COUT has not been detected.</description>
                  <value>#0</value>
                </enumeratedValue>
                <enumeratedValue>
                  <name>1</name>
                  <description>Falling-edge on COUT has occurred.</description>
                  <value>#1</value>
                </enumeratedValue>
              </enumeratedValues>
            </field>
            <field>
              <name>CFR</name>
              <description>Analog Comparator Flag Rising</description>
              <bitOffset>2</bitOffset>
              <bitWidth>1</bitWidth>
              <access>read-write</access>
              <enumeratedValues>
                <enumeratedValue>
                  <name>0</name>
                  <description>Rising-edge on COUT has not been detected.</description>
                  <value>#0</value>
                </enumeratedValue>
                <enumeratedValue>
                  <name>1</name>
                  <description>Rising-edge on COUT has occurred.</description>
                  <value>#1</value>
                </enumeratedValue>
              </enumeratedValues>
            </field>
            <field>
              <name>IEF</name>
              <description>Comparator Interrupt Enable Falling</description>
              <bitOffset>3</bitOffset>
              <bitWidth>1</bitWidth>
              <access>read-write</access>
              <enumeratedValues>
                <enumeratedValue>
                  <name>0</name>
                  <description>Interrupt is disabled.</description>
                  <value>#0</value>
                </enumeratedValue>
                <enumeratedValue>
                  <name>1</name>
                  <description>Interrupt is enabled.</description>
                  <value>#1</value>
                </enumeratedValue>
              </enumeratedValues>
            </field>
            <field>
              <name>IER</name>
              <description>Comparator Interrupt Enable Rising</description>
              <bitOffset>4</bitOffset>
              <bitWidth>1</bitWidth>
              <access>read-write</access>
              <enumeratedValues>
                <enumeratedValue>
                  <name>0</name>
                  <description>Interrupt is disabled.</description>
                  <value>#0</value>
                </enumeratedValue>
                <enumeratedValue>
                  <name>1</name>
                  <description>Interrupt is enabled.</description>
                  <value>#1</value>
                </enumeratedValue>
              </enumeratedValues>
            </field>
            <field>
              <name>DMAEN</name>
              <description>DMA Enable Control</description>
              <bitOffset>6</bitOffset>
              <bitWidth>1</bitWidth>
              <access>read-write</access>
              <enumeratedValues>
                <enumeratedValue>
                  <name>0</name>
                  <description>DMA is disabled.</description>
                  <value>#0</value>
                </enumeratedValue>
                <enumeratedValue>
                  <name>1</name>
                  <description>DMA is enabled.</description>
                  <value>#1</value>
                </enumeratedValue>
              </enumeratedValues>
            </field>
          </fields>
        </register>
        <register>
          <name>DACCR</name>
          <description>DAC Control Register</description>
          <addressOffset>0x4</addressOffset>
          <size>8</size>
          <access>read-write</access>
          <resetValue>0</resetValue>
          <resetMask>0xFF</resetMask>
          <fields>
            <field>
              <name>VOSEL</name>
              <description>DAC Output Voltage Select</description>
              <bitOffset>0</bitOffset>
              <bitWidth>6</bitWidth>
              <access>read-write</access>
            </field>
            <field>
              <name>VRSEL</name>
              <description>Supply Voltage Reference Source Select</description>
              <bitOffset>6</bitOffset>
              <bitWidth>1</bitWidth>
              <access>read-write</access>
              <enumeratedValues>
                <enumeratedValue>
                  <name>0</name>
                  <description>V is selected as resistor ladder network supply reference V. in1 in</description>
                  <value>#0</value>
                </enumeratedValue>
                <enumeratedValue>
                  <name>1</name>
                  <description>V is selected as resistor ladder network supply reference V. in2 in</description>
                  <value>#1</value>
                </enumeratedValue>
              </enumeratedValues>
            </field>
            <field>
              <name>DACEN</name>
              <description>DAC Enable</description>
              <bitOffset>7</bitOffset>
              <bitWidth>1</bitWidth>
              <access>read-write</access>
              <enumeratedValues>
                <enumeratedValue>
                  <name>0</name>
                  <description>DAC is disabled.</description>
                  <value>#0</value>
                </enumeratedValue>
                <enumeratedValue>
                  <name>1</name>
                  <description>DAC is enabled.</description>
                  <value>#1</value>
                </enumeratedValue>
              </enumeratedValues>
            </field>
          </fields>
        </register>
        <register>
          <name>MUXCR</name>
          <description>MUX Control Register</description>
          <addressOffset>0x5</addressOffset>
          <size>8</size>
          <access>read-write</access>
          <resetValue>0</resetValue>
          <resetMask>0xFF</resetMask>
          <fields>
            <field>
              <name>MSEL</name>
              <description>Minus Input Mux Control</description>
              <bitOffset>0</bitOffset>
              <bitWidth>3</bitWidth>
              <access>read-write</access>
              <enumeratedValues>
                <enumeratedValue>
                  <name>000</name>
                  <description>IN0</description>
                  <value>#000</value>
                </enumeratedValue>
                <enumeratedValue>
                  <name>001</name>
                  <description>IN1</description>
                  <value>#001</value>
                </enumeratedValue>
                <enumeratedValue>
                  <name>010</name>
                  <description>IN2</description>
                  <value>#010</value>
                </enumeratedValue>
                <enumeratedValue>
                  <name>011</name>
                  <description>IN3</description>
                  <value>#011</value>
                </enumeratedValue>
                <enumeratedValue>
                  <name>100</name>
                  <description>IN4</description>
                  <value>#100</value>
                </enumeratedValue>
                <enumeratedValue>
                  <name>101</name>
                  <description>IN5</description>
                  <value>#101</value>
                </enumeratedValue>
                <enumeratedValue>
                  <name>110</name>
                  <description>IN6</description>
                  <value>#110</value>
                </enumeratedValue>
                <enumeratedValue>
                  <name>111</name>
                  <description>IN7</description>
                  <value>#111</value>
                </enumeratedValue>
              </enumeratedValues>
            </field>
            <field>
              <name>PSEL</name>
              <description>Plus Input Mux Control</description>
              <bitOffset>3</bitOffset>
              <bitWidth>3</bitWidth>
              <access>read-write</access>
              <enumeratedValues>
                <enumeratedValue>
                  <name>000</name>
                  <description>IN0</description>
                  <value>#000</value>
                </enumeratedValue>
                <enumeratedValue>
                  <name>001</name>
                  <description>IN1</description>
                  <value>#001</value>
                </enumeratedValue>
                <enumeratedValue>
                  <name>010</name>
                  <description>IN2</description>
                  <value>#010</value>
                </enumeratedValue>
                <enumeratedValue>
                  <name>011</name>
                  <description>IN3</description>
                  <value>#011</value>
                </enumeratedValue>
                <enumeratedValue>
                  <name>100</name>
                  <description>IN4</description>
                  <value>#100</value>
                </enumeratedValue>
                <enumeratedValue>
                  <name>101</name>
                  <description>IN5</description>
                  <value>#101</value>
                </enumeratedValue>
                <enumeratedValue>
                  <name>110</name>
                  <description>IN6</description>
                  <value>#110</value>
                </enumeratedValue>
                <enumeratedValue>
                  <name>111</name>
                  <description>IN7</description>
                  <value>#111</value>
                </enumeratedValue>
              </enumeratedValues>
            </field>
            <field>
              <name>PSTM</name>
              <description>Pass Through Mode Enable</description>
              <bitOffset>7</bitOffset>
              <bitWidth>1</bitWidth>
              <access>read-write</access>
              <enumeratedValues>
                <enumeratedValue>
                  <name>0</name>
                  <description>Pass Through Mode is disabled.</description>
                  <value>#0</value>
                </enumeratedValue>
                <enumeratedValue>
                  <name>1</name>
                  <description>Pass Through Mode is enabled.</description>
                  <value>#1</value>
                </enumeratedValue>
              </enumeratedValues>
            </field>
          </fields>
        </register>
      </registers>
    </peripheral>
    <peripheral>
      <name>SPI0</name>
      <description>Serial Peripheral Interface</description>
      <groupName>SPI</groupName>
      <prependToName>SPI0_</prependToName>
      <baseAddress>0x40076000</baseAddress>
      <addressBlock>
        <offset>0</offset>
        <size>0x8</size>
        <usage>registers</usage>
      </addressBlock>
      <interrupt>
        <name>SPI0</name>
        <value>10</value>
      </interrupt>
      <registers>
        <register>
          <name>S</name>
          <description>SPI Status Register</description>
          <addressOffset>0</addressOffset>
          <size>8</size>
          <access>read-write</access>
          <resetValue>0x20</resetValue>
          <resetMask>0xFF</resetMask>
          <fields>
            <field>
              <name>MODF</name>
              <description>Master Mode Fault Flag</description>
              <bitOffset>4</bitOffset>
              <bitWidth>1</bitWidth>
              <access>read-only</access>
              <enumeratedValues>
                <enumeratedValue>
                  <name>0</name>
                  <description>No mode fault error</description>
                  <value>#0</value>
                </enumeratedValue>
                <enumeratedValue>
                  <name>1</name>
                  <description>Mode fault error detected</description>
                  <value>#1</value>
                </enumeratedValue>
              </enumeratedValues>
            </field>
            <field>
              <name>SPTEF</name>
              <description>SPI Transmit Buffer Empty Flag (when FIFO is not supported or not enabled) or SPI transmit FIFO empty flag (when FIFO is supported and enabled)</description>
              <bitOffset>5</bitOffset>
              <bitWidth>1</bitWidth>
              <access>read-only</access>
              <enumeratedValues>
                <enumeratedValue>
                  <name>0</name>
                  <description>SPI transmit buffer not empty (when FIFOMODE is not present or is 0) or SPI FIFO not empty (when FIFOMODE is 1)</description>
                  <value>#0</value>
                </enumeratedValue>
                <enumeratedValue>
                  <name>1</name>
                  <description>SPI transmit buffer empty (when FIFOMODE is not present or is 0) or SPI FIFO empty (when FIFOMODE is 1)</description>
                  <value>#1</value>
                </enumeratedValue>
              </enumeratedValues>
            </field>
            <field>
              <name>SPMF</name>
              <description>SPI Match Flag</description>
              <bitOffset>6</bitOffset>
              <bitWidth>1</bitWidth>
              <access>read-write</access>
              <enumeratedValues>
                <enumeratedValue>
                  <name>0</name>
                  <description>Value in the receive data buffer does not match the value in the MH:ML registers</description>
                  <value>#0</value>
                </enumeratedValue>
                <enumeratedValue>
                  <name>1</name>
                  <description>Value in the receive data buffer matches the value in the MH:ML registers</description>
                  <value>#1</value>
                </enumeratedValue>
              </enumeratedValues>
            </field>
            <field>
              <name>SPRF</name>
              <description>SPI Read Buffer Full Flag (when FIFO is not supported or not enabled) or SPI read FIFO FULL flag (when FIFO is supported and enabled)</description>
              <bitOffset>7</bitOffset>
              <bitWidth>1</bitWidth>
              <access>read-only</access>
              <enumeratedValues>
                <enumeratedValue>
                  <name>0</name>
                  <description>No data available in the receive data buffer (when FIFOMODE is not present or is 0) or Read FIFO is not full (when FIFOMODE is 1)</description>
                  <value>#0</value>
                </enumeratedValue>
                <enumeratedValue>
                  <name>1</name>
                  <description>Data available in the receive data buffer (when FIFOMODE is not present or is 0) or Read FIFO is full (when FIFOMODE is 1)</description>
                  <value>#1</value>
                </enumeratedValue>
              </enumeratedValues>
            </field>
          </fields>
        </register>
        <register>
          <name>BR</name>
          <description>SPI Baud Rate Register</description>
          <addressOffset>0x1</addressOffset>
          <size>8</size>
          <access>read-write</access>
          <resetValue>0</resetValue>
          <resetMask>0xFF</resetMask>
          <fields>
            <field>
              <name>SPR</name>
              <description>SPI Baud Rate Divisor</description>
              <bitOffset>0</bitOffset>
              <bitWidth>4</bitWidth>
              <access>read-write</access>
              <enumeratedValues>
                <enumeratedValue>
                  <name>0000</name>
                  <description>Baud rate divisor is 2.</description>
                  <value>#0000</value>
                </enumeratedValue>
                <enumeratedValue>
                  <name>0001</name>
                  <description>Baud rate divisor is 4.</description>
                  <value>#0001</value>
                </enumeratedValue>
                <enumeratedValue>
                  <name>0010</name>
                  <description>Baud rate divisor is 8.</description>
                  <value>#0010</value>
                </enumeratedValue>
                <enumeratedValue>
                  <name>0011</name>
                  <description>Baud rate divisor is 16.</description>
                  <value>#0011</value>
                </enumeratedValue>
                <enumeratedValue>
                  <name>0100</name>
                  <description>Baud rate divisor is 32.</description>
                  <value>#0100</value>
                </enumeratedValue>
                <enumeratedValue>
                  <name>0101</name>
                  <description>Baud rate divisor is 64.</description>
                  <value>#0101</value>
                </enumeratedValue>
                <enumeratedValue>
                  <name>0110</name>
                  <description>Baud rate divisor is 128.</description>
                  <value>#0110</value>
                </enumeratedValue>
                <enumeratedValue>
                  <name>0111</name>
                  <description>Baud rate divisor is 256.</description>
                  <value>#0111</value>
                </enumeratedValue>
                <enumeratedValue>
                  <name>1000</name>
                  <description>Baud rate divisor is 512.</description>
                  <value>#1000</value>
                </enumeratedValue>
              </enumeratedValues>
            </field>
            <field>
              <name>SPPR</name>
              <description>SPI Baud Rate Prescale Divisor</description>
              <bitOffset>4</bitOffset>
              <bitWidth>3</bitWidth>
              <access>read-write</access>
              <enumeratedValues>
                <enumeratedValue>
                  <name>000</name>
                  <description>Baud rate prescaler divisor is 1.</description>
                  <value>#000</value>
                </enumeratedValue>
                <enumeratedValue>
                  <name>001</name>
                  <description>Baud rate prescaler divisor is 2.</description>
                  <value>#001</value>
                </enumeratedValue>
                <enumeratedValue>
                  <name>010</name>
                  <description>Baud rate prescaler divisor is 3.</description>
                  <value>#010</value>
                </enumeratedValue>
                <enumeratedValue>
                  <name>011</name>
                  <description>Baud rate prescaler divisor is 4.</description>
                  <value>#011</value>
                </enumeratedValue>
                <enumeratedValue>
                  <name>100</name>
                  <description>Baud rate prescaler divisor is 5.</description>
                  <value>#100</value>
                </enumeratedValue>
                <enumeratedValue>
                  <name>101</name>
                  <description>Baud rate prescaler divisor is 6.</description>
                  <value>#101</value>
                </enumeratedValue>
                <enumeratedValue>
                  <name>110</name>
                  <description>Baud rate prescaler divisor is 7.</description>
                  <value>#110</value>
                </enumeratedValue>
                <enumeratedValue>
                  <name>111</name>
                  <description>Baud rate prescaler divisor is 8.</description>
                  <value>#111</value>
                </enumeratedValue>
              </enumeratedValues>
            </field>
          </fields>
        </register>
        <register>
          <name>C2</name>
          <description>SPI Control Register 2</description>
          <addressOffset>0x2</addressOffset>
          <size>8</size>
          <access>read-write</access>
          <resetValue>0</resetValue>
          <resetMask>0xFF</resetMask>
          <fields>
            <field>
              <name>SPC0</name>
              <description>SPI Pin Control 0</description>
              <bitOffset>0</bitOffset>
              <bitWidth>1</bitWidth>
              <access>read-write</access>
              <enumeratedValues>
                <enumeratedValue>
                  <name>0</name>
                  <description>SPI uses separate pins for data input and data output (pin mode is normal). In master mode of operation: MISO is master in and MOSI is master out. In slave mode of operation: MISO is slave out and MOSI is slave in.</description>
                  <value>#0</value>
                </enumeratedValue>
                <enumeratedValue>
                  <name>1</name>
                  <description>SPI configured for single-wire bidirectional operation (pin mode is bidirectional). In master mode of operation: MISO is not used by SPI; MOSI is master in when BIDIROE is 0 or master I/O when BIDIROE is 1. In slave mode of operation: MISO is slave in when BIDIROE is 0 or slave I/O when BIDIROE is 1; MOSI is not used by SPI.</description>
                  <value>#1</value>
                </enumeratedValue>
              </enumeratedValues>
            </field>
            <field>
              <name>SPISWAI</name>
              <description>SPI Stop in Wait Mode</description>
              <bitOffset>1</bitOffset>
              <bitWidth>1</bitWidth>
              <access>read-write</access>
              <enumeratedValues>
                <enumeratedValue>
                  <name>0</name>
                  <description>SPI clocks continue to operate in Wait mode.</description>
                  <value>#0</value>
                </enumeratedValue>
                <enumeratedValue>
                  <name>1</name>
                  <description>SPI clocks stop when the MCU enters Wait mode.</description>
                  <value>#1</value>
                </enumeratedValue>
              </enumeratedValues>
            </field>
            <field>
              <name>RXDMAE</name>
              <description>Receive DMA enable</description>
              <bitOffset>2</bitOffset>
              <bitWidth>1</bitWidth>
              <access>read-write</access>
              <enumeratedValues>
                <enumeratedValue>
                  <name>0</name>
                  <description>DMA request for receive is disabled and interrupt from SPRF is allowed</description>
                  <value>#0</value>
                </enumeratedValue>
                <enumeratedValue>
                  <name>1</name>
                  <description>DMA request for receive is enabled and interrupt from SPRF is disabled</description>
                  <value>#1</value>
                </enumeratedValue>
              </enumeratedValues>
            </field>
            <field>
              <name>BIDIROE</name>
              <description>Bidirectional Mode Output Enable</description>
              <bitOffset>3</bitOffset>
              <bitWidth>1</bitWidth>
              <access>read-write</access>
              <enumeratedValues>
                <enumeratedValue>
                  <name>0</name>
                  <description>Output driver disabled so SPI data I/O pin acts as an input</description>
                  <value>#0</value>
                </enumeratedValue>
                <enumeratedValue>
                  <name>1</name>
                  <description>SPI I/O pin enabled as an output</description>
                  <value>#1</value>
                </enumeratedValue>
              </enumeratedValues>
            </field>
            <field>
              <name>MODFEN</name>
              <description>Master Mode-Fault Function Enable</description>
              <bitOffset>4</bitOffset>
              <bitWidth>1</bitWidth>
              <access>read-write</access>
              <enumeratedValues>
                <enumeratedValue>
                  <name>0</name>
                  <description>Mode fault function disabled, master SS pin reverts to general-purpose I/O not controlled by SPI</description>
                  <value>#0</value>
                </enumeratedValue>
                <enumeratedValue>
                  <name>1</name>
                  <description>Mode fault function enabled, master SS pin acts as the mode fault input or the slave select output</description>
                  <value>#1</value>
                </enumeratedValue>
              </enumeratedValues>
            </field>
            <field>
              <name>TXDMAE</name>
              <description>Transmit DMA enable</description>
              <bitOffset>5</bitOffset>
              <bitWidth>1</bitWidth>
              <access>read-write</access>
              <enumeratedValues>
                <enumeratedValue>
                  <name>0</name>
                  <description>DMA request for transmit is disabled and interrupt from SPTEF is allowed</description>
                  <value>#0</value>
                </enumeratedValue>
                <enumeratedValue>
                  <name>1</name>
                  <description>DMA request for transmit is enabled and interrupt from SPTEF is disabled</description>
                  <value>#1</value>
                </enumeratedValue>
              </enumeratedValues>
            </field>
            <field>
              <name>SPIMODE</name>
              <description>SPI 8-bit or 16-bit mode</description>
              <bitOffset>6</bitOffset>
              <bitWidth>1</bitWidth>
              <access>read-write</access>
              <enumeratedValues>
                <enumeratedValue>
                  <name>0</name>
                  <description>8-bit SPI shift register, match register, and buffers</description>
                  <value>#0</value>
                </enumeratedValue>
                <enumeratedValue>
                  <name>1</name>
                  <description>16-bit SPI shift register, match register, and buffers</description>
                  <value>#1</value>
                </enumeratedValue>
              </enumeratedValues>
            </field>
            <field>
              <name>SPMIE</name>
              <description>SPI Match Interrupt Enable</description>
              <bitOffset>7</bitOffset>
              <bitWidth>1</bitWidth>
              <access>read-write</access>
              <enumeratedValues>
                <enumeratedValue>
                  <name>0</name>
                  <description>Interrupts from SPMF inhibited (use polling)</description>
                  <value>#0</value>
                </enumeratedValue>
                <enumeratedValue>
                  <name>1</name>
                  <description>When SPMF is 1, requests a hardware interrupt</description>
                  <value>#1</value>
                </enumeratedValue>
              </enumeratedValues>
            </field>
          </fields>
        </register>
        <register>
          <name>C1</name>
          <description>SPI Control Register 1</description>
          <addressOffset>0x3</addressOffset>
          <size>8</size>
          <access>read-write</access>
          <resetValue>0x4</resetValue>
          <resetMask>0xFF</resetMask>
          <fields>
            <field>
              <name>LSBFE</name>
              <description>LSB First (shifter direction)</description>
              <bitOffset>0</bitOffset>
              <bitWidth>1</bitWidth>
              <access>read-write</access>
              <enumeratedValues>
                <enumeratedValue>
                  <name>0</name>
                  <description>SPI serial data transfers start with the most significant bit.</description>
                  <value>#0</value>
                </enumeratedValue>
                <enumeratedValue>
                  <name>1</name>
                  <description>SPI serial data transfers start with the least significant bit.</description>
                  <value>#1</value>
                </enumeratedValue>
              </enumeratedValues>
            </field>
            <field>
              <name>SSOE</name>
              <description>Slave Select Output Enable</description>
              <bitOffset>1</bitOffset>
              <bitWidth>1</bitWidth>
              <access>read-write</access>
              <enumeratedValues>
                <enumeratedValue>
                  <name>0</name>
                  <description>When C2[MODFEN] is 0: In master mode, SS pin function is general-purpose I/O (not SPI). In slave mode, SS pin function is slave select input. When C2[MODFEN] is 1: In master mode, SS pin function is SS input for mode fault. In slave mode, SS pin function is slave select input.</description>
                  <value>#0</value>
                </enumeratedValue>
                <enumeratedValue>
                  <name>1</name>
                  <description>When C2[MODFEN] is 0: In master mode, SS pin function is general-purpose I/O (not SPI). In slave mode, SS pin function is slave select input. When C2[MODFEN] is 1: In master mode, SS pin function is automatic SS output. In slave mode: SS pin function is slave select input.</description>
                  <value>#1</value>
                </enumeratedValue>
              </enumeratedValues>
            </field>
            <field>
              <name>CPHA</name>
              <description>Clock Phase</description>
              <bitOffset>2</bitOffset>
              <bitWidth>1</bitWidth>
              <access>read-write</access>
              <enumeratedValues>
                <enumeratedValue>
                  <name>0</name>
                  <description>First edge on SPSCK occurs at the middle of the first cycle of a data transfer.</description>
                  <value>#0</value>
                </enumeratedValue>
                <enumeratedValue>
                  <name>1</name>
                  <description>First edge on SPSCK occurs at the start of the first cycle of a data transfer.</description>
                  <value>#1</value>
                </enumeratedValue>
              </enumeratedValues>
            </field>
            <field>
              <name>CPOL</name>
              <description>Clock Polarity</description>
              <bitOffset>3</bitOffset>
              <bitWidth>1</bitWidth>
              <access>read-write</access>
              <enumeratedValues>
                <enumeratedValue>
                  <name>0</name>
                  <description>Active-high SPI clock (idles low)</description>
                  <value>#0</value>
                </enumeratedValue>
                <enumeratedValue>
                  <name>1</name>
                  <description>Active-low SPI clock (idles high)</description>
                  <value>#1</value>
                </enumeratedValue>
              </enumeratedValues>
            </field>
            <field>
              <name>MSTR</name>
              <description>Master/Slave Mode Select</description>
              <bitOffset>4</bitOffset>
              <bitWidth>1</bitWidth>
              <access>read-write</access>
              <enumeratedValues>
                <enumeratedValue>
                  <name>0</name>
                  <description>SPI module configured as a slave SPI device</description>
                  <value>#0</value>
                </enumeratedValue>
                <enumeratedValue>
                  <name>1</name>
                  <description>SPI module configured as a master SPI device</description>
                  <value>#1</value>
                </enumeratedValue>
              </enumeratedValues>
            </field>
            <field>
              <name>SPTIE</name>
              <description>SPI Transmit Interrupt Enable</description>
              <bitOffset>5</bitOffset>
              <bitWidth>1</bitWidth>
              <access>read-write</access>
              <enumeratedValues>
                <enumeratedValue>
                  <name>0</name>
                  <description>Interrupts from SPTEF inhibited (use polling)</description>
                  <value>#0</value>
                </enumeratedValue>
                <enumeratedValue>
                  <name>1</name>
                  <description>When SPTEF is 1, hardware interrupt requested</description>
                  <value>#1</value>
                </enumeratedValue>
              </enumeratedValues>
            </field>
            <field>
              <name>SPE</name>
              <description>SPI System Enable</description>
              <bitOffset>6</bitOffset>
              <bitWidth>1</bitWidth>
              <access>read-write</access>
              <enumeratedValues>
                <enumeratedValue>
                  <name>0</name>
                  <description>SPI system inactive</description>
                  <value>#0</value>
                </enumeratedValue>
                <enumeratedValue>
                  <name>1</name>
                  <description>SPI system enabled</description>
                  <value>#1</value>
                </enumeratedValue>
              </enumeratedValues>
            </field>
            <field>
              <name>SPIE</name>
              <description>SPI Interrupt Enable: for SPRF and MODF (when FIFO is not supported or not enabled) or for read FIFO (when FIFO is supported and enabled)</description>
              <bitOffset>7</bitOffset>
              <bitWidth>1</bitWidth>
              <access>read-write</access>
              <enumeratedValues>
                <enumeratedValue>
                  <name>0</name>
                  <description>Interrupts from SPRF and MODF are inhibited-use polling (when FIFOMODE is not present or is 0) or Read FIFO Full Interrupts are disabled (when FIFOMODE is 1)</description>
                  <value>#0</value>
                </enumeratedValue>
                <enumeratedValue>
                  <name>1</name>
                  <description>Request a hardware interrupt when SPRF or MODF is 1 (when FIFOMODE is not present or is 0) or Read FIFO Full Interrupts are enabled (when FIFOMODE is 1)</description>
                  <value>#1</value>
                </enumeratedValue>
              </enumeratedValues>
            </field>
          </fields>
        </register>
        <register>
          <name>ML</name>
          <description>SPI Match Register low</description>
          <addressOffset>0x4</addressOffset>
          <size>8</size>
          <access>read-write</access>
          <resetValue>0</resetValue>
          <resetMask>0xFF</resetMask>
          <fields>
            <field>
              <name>Bits</name>
              <description>Hardware compare value (low byte)</description>
              <bitOffset>0</bitOffset>
              <bitWidth>8</bitWidth>
              <access>read-write</access>
            </field>
          </fields>
        </register>
        <register>
          <name>MH</name>
          <description>SPI match register high</description>
          <addressOffset>0x5</addressOffset>
          <size>8</size>
          <access>read-write</access>
          <resetValue>0</resetValue>
          <resetMask>0xFF</resetMask>
          <fields>
            <field>
              <name>Bits</name>
              <description>Hardware compare value (high byte)</description>
              <bitOffset>0</bitOffset>
              <bitWidth>8</bitWidth>
              <access>read-write</access>
            </field>
          </fields>
        </register>
        <register>
          <name>DL</name>
          <description>SPI Data Register low</description>
          <addressOffset>0x6</addressOffset>
          <size>8</size>
          <access>read-write</access>
          <resetValue>0</resetValue>
          <resetMask>0xFF</resetMask>
          <fields>
            <field>
              <name>Bits</name>
              <description>Data (low byte)</description>
              <bitOffset>0</bitOffset>
              <bitWidth>8</bitWidth>
              <access>read-write</access>
            </field>
          </fields>
        </register>
        <register>
          <name>DH</name>
          <description>SPI data register high</description>
          <addressOffset>0x7</addressOffset>
          <size>8</size>
          <access>read-write</access>
          <resetValue>0</resetValue>
          <resetMask>0xFF</resetMask>
          <fields>
            <field>
              <name>Bits</name>
              <description>Data (high byte)</description>
              <bitOffset>0</bitOffset>
              <bitWidth>8</bitWidth>
              <access>read-write</access>
            </field>
          </fields>
        </register>
      </registers>
    </peripheral>
    <peripheral>
      <name>SPI1</name>
      <description>Serial Peripheral Interface</description>
      <groupName>SPI</groupName>
      <prependToName>SPI1_</prependToName>
      <baseAddress>0x40077000</baseAddress>
      <addressBlock>
        <offset>0</offset>
        <size>0xC</size>
        <usage>registers</usage>
      </addressBlock>
      <interrupt>
        <name>SPI1</name>
        <value>11</value>
      </interrupt>
      <registers>
        <register>
          <name>S</name>
          <description>SPI Status Register</description>
          <addressOffset>0</addressOffset>
          <size>8</size>
          <access>read-write</access>
          <resetValue>0x20</resetValue>
          <resetMask>0xFF</resetMask>
          <fields>
            <field>
              <name>RFIFOEF</name>
              <description>SPI read FIFO empty flag</description>
              <bitOffset>0</bitOffset>
              <bitWidth>1</bitWidth>
              <access>read-only</access>
              <enumeratedValues>
                <enumeratedValue>
                  <name>0</name>
                  <description>Read FIFO has data. Reads of the DH:DL registers in 16-bit mode or the DL register in 8-bit mode will empty the read FIFO.</description>
                  <value>#0</value>
                </enumeratedValue>
                <enumeratedValue>
                  <name>1</name>
                  <description>Read FIFO is empty.</description>
                  <value>#1</value>
                </enumeratedValue>
              </enumeratedValues>
            </field>
            <field>
              <name>TXFULLF</name>
              <description>Transmit FIFO full flag</description>
              <bitOffset>1</bitOffset>
              <bitWidth>1</bitWidth>
              <access>read-only</access>
              <enumeratedValues>
                <enumeratedValue>
                  <name>0</name>
                  <description>Transmit FIFO has less than 8 bytes</description>
                  <value>#0</value>
                </enumeratedValue>
                <enumeratedValue>
                  <name>1</name>
                  <description>Transmit FIFO has 8 bytes of data</description>
                  <value>#1</value>
                </enumeratedValue>
              </enumeratedValues>
            </field>
            <field>
              <name>TNEAREF</name>
              <description>Transmit FIFO nearly empty flag</description>
              <bitOffset>2</bitOffset>
              <bitWidth>1</bitWidth>
              <access>read-only</access>
              <enumeratedValues>
                <enumeratedValue>
                  <name>0</name>
                  <description>Transmit FIFO has more than 16 bits (when C3[TNEAREF_MARK] is 0) or more than 32 bits (when C3[TNEAREF_MARK] is 1) remaining to transmit</description>
                  <value>#0</value>
                </enumeratedValue>
                <enumeratedValue>
                  <name>1</name>
                  <description>Transmit FIFO has an amount of data equal to or less than 16 bits (when C3[TNEAREF_MARK] is 0) or 32 bits (when C3[TNEAREF_MARK] is 1) remaining to transmit</description>
                  <value>#1</value>
                </enumeratedValue>
              </enumeratedValues>
            </field>
            <field>
              <name>RNFULLF</name>
              <description>Receive FIFO nearly full flag</description>
              <bitOffset>3</bitOffset>
              <bitWidth>1</bitWidth>
              <access>read-only</access>
              <enumeratedValues>
                <enumeratedValue>
                  <name>0</name>
                  <description>Receive FIFO has received less than 48 bits (when C3[RNFULLF_MARK] is 0) or less than 32 bits (when C3[RNFULLF_MARK] is 1)</description>
                  <value>#0</value>
                </enumeratedValue>
                <enumeratedValue>
                  <name>1</name>
                  <description>Receive FIFO has received data of an amount equal to or greater than 48 bits (when C3[RNFULLF_MARK] is 0) or 32 bits (when C3[RNFULLF_MARK] is 1)</description>
                  <value>#1</value>
                </enumeratedValue>
              </enumeratedValues>
            </field>
            <field>
              <name>MODF</name>
              <description>Master Mode Fault Flag</description>
              <bitOffset>4</bitOffset>
              <bitWidth>1</bitWidth>
              <access>read-only</access>
              <enumeratedValues>
                <enumeratedValue>
                  <name>0</name>
                  <description>No mode fault error</description>
                  <value>#0</value>
                </enumeratedValue>
                <enumeratedValue>
                  <name>1</name>
                  <description>Mode fault error detected</description>
                  <value>#1</value>
                </enumeratedValue>
              </enumeratedValues>
            </field>
            <field>
              <name>SPTEF</name>
              <description>SPI Transmit Buffer Empty Flag (when FIFO is not supported or not enabled) or SPI transmit FIFO empty flag (when FIFO is supported and enabled)</description>
              <bitOffset>5</bitOffset>
              <bitWidth>1</bitWidth>
              <access>read-only</access>
              <enumeratedValues>
                <enumeratedValue>
                  <name>0</name>
                  <description>SPI transmit buffer not empty (when FIFOMODE is not present or is 0) or SPI FIFO not empty (when FIFOMODE is 1)</description>
                  <value>#0</value>
                </enumeratedValue>
                <enumeratedValue>
                  <name>1</name>
                  <description>SPI transmit buffer empty (when FIFOMODE is not present or is 0) or SPI FIFO empty (when FIFOMODE is 1)</description>
                  <value>#1</value>
                </enumeratedValue>
              </enumeratedValues>
            </field>
            <field>
              <name>SPMF</name>
              <description>SPI Match Flag</description>
              <bitOffset>6</bitOffset>
              <bitWidth>1</bitWidth>
              <access>read-write</access>
              <enumeratedValues>
                <enumeratedValue>
                  <name>0</name>
                  <description>Value in the receive data buffer does not match the value in the MH:ML registers</description>
                  <value>#0</value>
                </enumeratedValue>
                <enumeratedValue>
                  <name>1</name>
                  <description>Value in the receive data buffer matches the value in the MH:ML registers</description>
                  <value>#1</value>
                </enumeratedValue>
              </enumeratedValues>
            </field>
            <field>
              <name>SPRF</name>
              <description>SPI Read Buffer Full Flag (when FIFO is not supported or not enabled) or SPI read FIFO FULL flag (when FIFO is supported and enabled)</description>
              <bitOffset>7</bitOffset>
              <bitWidth>1</bitWidth>
              <access>read-only</access>
              <enumeratedValues>
                <enumeratedValue>
                  <name>0</name>
                  <description>No data available in the receive data buffer (when FIFOMODE is not present or is 0) or Read FIFO is not full (when FIFOMODE is 1)</description>
                  <value>#0</value>
                </enumeratedValue>
                <enumeratedValue>
                  <name>1</name>
                  <description>Data available in the receive data buffer (when FIFOMODE is not present or is 0) or Read FIFO is full (when FIFOMODE is 1)</description>
                  <value>#1</value>
                </enumeratedValue>
              </enumeratedValues>
            </field>
          </fields>
        </register>
        <register>
          <name>BR</name>
          <description>SPI Baud Rate Register</description>
          <addressOffset>0x1</addressOffset>
          <size>8</size>
          <access>read-write</access>
          <resetValue>0</resetValue>
          <resetMask>0xFF</resetMask>
          <fields>
            <field>
              <name>SPR</name>
              <description>SPI Baud Rate Divisor</description>
              <bitOffset>0</bitOffset>
              <bitWidth>4</bitWidth>
              <access>read-write</access>
              <enumeratedValues>
                <enumeratedValue>
                  <name>0000</name>
                  <description>Baud rate divisor is 2.</description>
                  <value>#0000</value>
                </enumeratedValue>
                <enumeratedValue>
                  <name>0001</name>
                  <description>Baud rate divisor is 4.</description>
                  <value>#0001</value>
                </enumeratedValue>
                <enumeratedValue>
                  <name>0010</name>
                  <description>Baud rate divisor is 8.</description>
                  <value>#0010</value>
                </enumeratedValue>
                <enumeratedValue>
                  <name>0011</name>
                  <description>Baud rate divisor is 16.</description>
                  <value>#0011</value>
                </enumeratedValue>
                <enumeratedValue>
                  <name>0100</name>
                  <description>Baud rate divisor is 32.</description>
                  <value>#0100</value>
                </enumeratedValue>
                <enumeratedValue>
                  <name>0101</name>
                  <description>Baud rate divisor is 64.</description>
                  <value>#0101</value>
                </enumeratedValue>
                <enumeratedValue>
                  <name>0110</name>
                  <description>Baud rate divisor is 128.</description>
                  <value>#0110</value>
                </enumeratedValue>
                <enumeratedValue>
                  <name>0111</name>
                  <description>Baud rate divisor is 256.</description>
                  <value>#0111</value>
                </enumeratedValue>
                <enumeratedValue>
                  <name>1000</name>
                  <description>Baud rate divisor is 512.</description>
                  <value>#1000</value>
                </enumeratedValue>
              </enumeratedValues>
            </field>
            <field>
              <name>SPPR</name>
              <description>SPI Baud Rate Prescale Divisor</description>
              <bitOffset>4</bitOffset>
              <bitWidth>3</bitWidth>
              <access>read-write</access>
              <enumeratedValues>
                <enumeratedValue>
                  <name>000</name>
                  <description>Baud rate prescaler divisor is 1.</description>
                  <value>#000</value>
                </enumeratedValue>
                <enumeratedValue>
                  <name>001</name>
                  <description>Baud rate prescaler divisor is 2.</description>
                  <value>#001</value>
                </enumeratedValue>
                <enumeratedValue>
                  <name>010</name>
                  <description>Baud rate prescaler divisor is 3.</description>
                  <value>#010</value>
                </enumeratedValue>
                <enumeratedValue>
                  <name>011</name>
                  <description>Baud rate prescaler divisor is 4.</description>
                  <value>#011</value>
                </enumeratedValue>
                <enumeratedValue>
                  <name>100</name>
                  <description>Baud rate prescaler divisor is 5.</description>
                  <value>#100</value>
                </enumeratedValue>
                <enumeratedValue>
                  <name>101</name>
                  <description>Baud rate prescaler divisor is 6.</description>
                  <value>#101</value>
                </enumeratedValue>
                <enumeratedValue>
                  <name>110</name>
                  <description>Baud rate prescaler divisor is 7.</description>
                  <value>#110</value>
                </enumeratedValue>
                <enumeratedValue>
                  <name>111</name>
                  <description>Baud rate prescaler divisor is 8.</description>
                  <value>#111</value>
                </enumeratedValue>
              </enumeratedValues>
            </field>
          </fields>
        </register>
        <register>
          <name>C2</name>
          <description>SPI Control Register 2</description>
          <addressOffset>0x2</addressOffset>
          <size>8</size>
          <access>read-write</access>
          <resetValue>0</resetValue>
          <resetMask>0xFF</resetMask>
          <fields>
            <field>
              <name>SPC0</name>
              <description>SPI Pin Control 0</description>
              <bitOffset>0</bitOffset>
              <bitWidth>1</bitWidth>
              <access>read-write</access>
              <enumeratedValues>
                <enumeratedValue>
                  <name>0</name>
                  <description>SPI uses separate pins for data input and data output (pin mode is normal). In master mode of operation: MISO is master in and MOSI is master out. In slave mode of operation: MISO is slave out and MOSI is slave in.</description>
                  <value>#0</value>
                </enumeratedValue>
                <enumeratedValue>
                  <name>1</name>
                  <description>SPI configured for single-wire bidirectional operation (pin mode is bidirectional). In master mode of operation: MISO is not used by SPI; MOSI is master in when BIDIROE is 0 or master I/O when BIDIROE is 1. In slave mode of operation: MISO is slave in when BIDIROE is 0 or slave I/O when BIDIROE is 1; MOSI is not used by SPI.</description>
                  <value>#1</value>
                </enumeratedValue>
              </enumeratedValues>
            </field>
            <field>
              <name>SPISWAI</name>
              <description>SPI Stop in Wait Mode</description>
              <bitOffset>1</bitOffset>
              <bitWidth>1</bitWidth>
              <access>read-write</access>
              <enumeratedValues>
                <enumeratedValue>
                  <name>0</name>
                  <description>SPI clocks continue to operate in Wait mode.</description>
                  <value>#0</value>
                </enumeratedValue>
                <enumeratedValue>
                  <name>1</name>
                  <description>SPI clocks stop when the MCU enters Wait mode.</description>
                  <value>#1</value>
                </enumeratedValue>
              </enumeratedValues>
            </field>
            <field>
              <name>RXDMAE</name>
              <description>Receive DMA enable</description>
              <bitOffset>2</bitOffset>
              <bitWidth>1</bitWidth>
              <access>read-write</access>
              <enumeratedValues>
                <enumeratedValue>
                  <name>0</name>
                  <description>DMA request for receive is disabled and interrupt from SPRF is allowed</description>
                  <value>#0</value>
                </enumeratedValue>
                <enumeratedValue>
                  <name>1</name>
                  <description>DMA request for receive is enabled and interrupt from SPRF is disabled</description>
                  <value>#1</value>
                </enumeratedValue>
              </enumeratedValues>
            </field>
            <field>
              <name>BIDIROE</name>
              <description>Bidirectional Mode Output Enable</description>
              <bitOffset>3</bitOffset>
              <bitWidth>1</bitWidth>
              <access>read-write</access>
              <enumeratedValues>
                <enumeratedValue>
                  <name>0</name>
                  <description>Output driver disabled so SPI data I/O pin acts as an input</description>
                  <value>#0</value>
                </enumeratedValue>
                <enumeratedValue>
                  <name>1</name>
                  <description>SPI I/O pin enabled as an output</description>
                  <value>#1</value>
                </enumeratedValue>
              </enumeratedValues>
            </field>
            <field>
              <name>MODFEN</name>
              <description>Master Mode-Fault Function Enable</description>
              <bitOffset>4</bitOffset>
              <bitWidth>1</bitWidth>
              <access>read-write</access>
              <enumeratedValues>
                <enumeratedValue>
                  <name>0</name>
                  <description>Mode fault function disabled, master SS pin reverts to general-purpose I/O not controlled by SPI</description>
                  <value>#0</value>
                </enumeratedValue>
                <enumeratedValue>
                  <name>1</name>
                  <description>Mode fault function enabled, master SS pin acts as the mode fault input or the slave select output</description>
                  <value>#1</value>
                </enumeratedValue>
              </enumeratedValues>
            </field>
            <field>
              <name>TXDMAE</name>
              <description>Transmit DMA enable</description>
              <bitOffset>5</bitOffset>
              <bitWidth>1</bitWidth>
              <access>read-write</access>
              <enumeratedValues>
                <enumeratedValue>
                  <name>0</name>
                  <description>DMA request for transmit is disabled and interrupt from SPTEF is allowed</description>
                  <value>#0</value>
                </enumeratedValue>
                <enumeratedValue>
                  <name>1</name>
                  <description>DMA request for transmit is enabled and interrupt from SPTEF is disabled</description>
                  <value>#1</value>
                </enumeratedValue>
              </enumeratedValues>
            </field>
            <field>
              <name>SPIMODE</name>
              <description>SPI 8-bit or 16-bit mode</description>
              <bitOffset>6</bitOffset>
              <bitWidth>1</bitWidth>
              <access>read-write</access>
              <enumeratedValues>
                <enumeratedValue>
                  <name>0</name>
                  <description>8-bit SPI shift register, match register, and buffers</description>
                  <value>#0</value>
                </enumeratedValue>
                <enumeratedValue>
                  <name>1</name>
                  <description>16-bit SPI shift register, match register, and buffers</description>
                  <value>#1</value>
                </enumeratedValue>
              </enumeratedValues>
            </field>
            <field>
              <name>SPMIE</name>
              <description>SPI Match Interrupt Enable</description>
              <bitOffset>7</bitOffset>
              <bitWidth>1</bitWidth>
              <access>read-write</access>
              <enumeratedValues>
                <enumeratedValue>
                  <name>0</name>
                  <description>Interrupts from SPMF inhibited (use polling)</description>
                  <value>#0</value>
                </enumeratedValue>
                <enumeratedValue>
                  <name>1</name>
                  <description>When SPMF is 1, requests a hardware interrupt</description>
                  <value>#1</value>
                </enumeratedValue>
              </enumeratedValues>
            </field>
          </fields>
        </register>
        <register>
          <name>C1</name>
          <description>SPI Control Register 1</description>
          <addressOffset>0x3</addressOffset>
          <size>8</size>
          <access>read-write</access>
          <resetValue>0x4</resetValue>
          <resetMask>0xFF</resetMask>
          <fields>
            <field>
              <name>LSBFE</name>
              <description>LSB First (shifter direction)</description>
              <bitOffset>0</bitOffset>
              <bitWidth>1</bitWidth>
              <access>read-write</access>
              <enumeratedValues>
                <enumeratedValue>
                  <name>0</name>
                  <description>SPI serial data transfers start with the most significant bit.</description>
                  <value>#0</value>
                </enumeratedValue>
                <enumeratedValue>
                  <name>1</name>
                  <description>SPI serial data transfers start with the least significant bit.</description>
                  <value>#1</value>
                </enumeratedValue>
              </enumeratedValues>
            </field>
            <field>
              <name>SSOE</name>
              <description>Slave Select Output Enable</description>
              <bitOffset>1</bitOffset>
              <bitWidth>1</bitWidth>
              <access>read-write</access>
              <enumeratedValues>
                <enumeratedValue>
                  <name>0</name>
                  <description>When C2[MODFEN] is 0: In master mode, SS pin function is general-purpose I/O (not SPI). In slave mode, SS pin function is slave select input. When C2[MODFEN] is 1: In master mode, SS pin function is SS input for mode fault. In slave mode, SS pin function is slave select input.</description>
                  <value>#0</value>
                </enumeratedValue>
                <enumeratedValue>
                  <name>1</name>
                  <description>When C2[MODFEN] is 0: In master mode, SS pin function is general-purpose I/O (not SPI). In slave mode, SS pin function is slave select input. When C2[MODFEN] is 1: In master mode, SS pin function is automatic SS output. In slave mode: SS pin function is slave select input.</description>
                  <value>#1</value>
                </enumeratedValue>
              </enumeratedValues>
            </field>
            <field>
              <name>CPHA</name>
              <description>Clock Phase</description>
              <bitOffset>2</bitOffset>
              <bitWidth>1</bitWidth>
              <access>read-write</access>
              <enumeratedValues>
                <enumeratedValue>
                  <name>0</name>
                  <description>First edge on SPSCK occurs at the middle of the first cycle of a data transfer.</description>
                  <value>#0</value>
                </enumeratedValue>
                <enumeratedValue>
                  <name>1</name>
                  <description>First edge on SPSCK occurs at the start of the first cycle of a data transfer.</description>
                  <value>#1</value>
                </enumeratedValue>
              </enumeratedValues>
            </field>
            <field>
              <name>CPOL</name>
              <description>Clock Polarity</description>
              <bitOffset>3</bitOffset>
              <bitWidth>1</bitWidth>
              <access>read-write</access>
              <enumeratedValues>
                <enumeratedValue>
                  <name>0</name>
                  <description>Active-high SPI clock (idles low)</description>
                  <value>#0</value>
                </enumeratedValue>
                <enumeratedValue>
                  <name>1</name>
                  <description>Active-low SPI clock (idles high)</description>
                  <value>#1</value>
                </enumeratedValue>
              </enumeratedValues>
            </field>
            <field>
              <name>MSTR</name>
              <description>Master/Slave Mode Select</description>
              <bitOffset>4</bitOffset>
              <bitWidth>1</bitWidth>
              <access>read-write</access>
              <enumeratedValues>
                <enumeratedValue>
                  <name>0</name>
                  <description>SPI module configured as a slave SPI device</description>
                  <value>#0</value>
                </enumeratedValue>
                <enumeratedValue>
                  <name>1</name>
                  <description>SPI module configured as a master SPI device</description>
                  <value>#1</value>
                </enumeratedValue>
              </enumeratedValues>
            </field>
            <field>
              <name>SPTIE</name>
              <description>SPI Transmit Interrupt Enable</description>
              <bitOffset>5</bitOffset>
              <bitWidth>1</bitWidth>
              <access>read-write</access>
              <enumeratedValues>
                <enumeratedValue>
                  <name>0</name>
                  <description>Interrupts from SPTEF inhibited (use polling)</description>
                  <value>#0</value>
                </enumeratedValue>
                <enumeratedValue>
                  <name>1</name>
                  <description>When SPTEF is 1, hardware interrupt requested</description>
                  <value>#1</value>
                </enumeratedValue>
              </enumeratedValues>
            </field>
            <field>
              <name>SPE</name>
              <description>SPI System Enable</description>
              <bitOffset>6</bitOffset>
              <bitWidth>1</bitWidth>
              <access>read-write</access>
              <enumeratedValues>
                <enumeratedValue>
                  <name>0</name>
                  <description>SPI system inactive</description>
                  <value>#0</value>
                </enumeratedValue>
                <enumeratedValue>
                  <name>1</name>
                  <description>SPI system enabled</description>
                  <value>#1</value>
                </enumeratedValue>
              </enumeratedValues>
            </field>
            <field>
              <name>SPIE</name>
              <description>SPI Interrupt Enable: for SPRF and MODF (when FIFO is not supported or not enabled) or for read FIFO (when FIFO is supported and enabled)</description>
              <bitOffset>7</bitOffset>
              <bitWidth>1</bitWidth>
              <access>read-write</access>
              <enumeratedValues>
                <enumeratedValue>
                  <name>0</name>
                  <description>Interrupts from SPRF and MODF are inhibited-use polling (when FIFOMODE is not present or is 0) or Read FIFO Full Interrupts are disabled (when FIFOMODE is 1)</description>
                  <value>#0</value>
                </enumeratedValue>
                <enumeratedValue>
                  <name>1</name>
                  <description>Request a hardware interrupt when SPRF or MODF is 1 (when FIFOMODE is not present or is 0) or Read FIFO Full Interrupts are enabled (when FIFOMODE is 1)</description>
                  <value>#1</value>
                </enumeratedValue>
              </enumeratedValues>
            </field>
          </fields>
        </register>
        <register>
          <name>ML</name>
          <description>SPI Match Register low</description>
          <addressOffset>0x4</addressOffset>
          <size>8</size>
          <access>read-write</access>
          <resetValue>0</resetValue>
          <resetMask>0xFF</resetMask>
          <fields>
            <field>
              <name>Bits</name>
              <description>Hardware compare value (low byte)</description>
              <bitOffset>0</bitOffset>
              <bitWidth>8</bitWidth>
              <access>read-write</access>
            </field>
          </fields>
        </register>
        <register>
          <name>MH</name>
          <description>SPI match register high</description>
          <addressOffset>0x5</addressOffset>
          <size>8</size>
          <access>read-write</access>
          <resetValue>0</resetValue>
          <resetMask>0xFF</resetMask>
          <fields>
            <field>
              <name>Bits</name>
              <description>Hardware compare value (high byte)</description>
              <bitOffset>0</bitOffset>
              <bitWidth>8</bitWidth>
              <access>read-write</access>
            </field>
          </fields>
        </register>
        <register>
          <name>DL</name>
          <description>SPI Data Register low</description>
          <addressOffset>0x6</addressOffset>
          <size>8</size>
          <access>read-write</access>
          <resetValue>0</resetValue>
          <resetMask>0xFF</resetMask>
          <fields>
            <field>
              <name>Bits</name>
              <description>Data (low byte)</description>
              <bitOffset>0</bitOffset>
              <bitWidth>8</bitWidth>
              <access>read-write</access>
            </field>
          </fields>
        </register>
        <register>
          <name>DH</name>
          <description>SPI data register high</description>
          <addressOffset>0x7</addressOffset>
          <size>8</size>
          <access>read-write</access>
          <resetValue>0</resetValue>
          <resetMask>0xFF</resetMask>
          <fields>
            <field>
              <name>Bits</name>
              <description>Data (high byte)</description>
              <bitOffset>0</bitOffset>
              <bitWidth>8</bitWidth>
              <access>read-write</access>
            </field>
          </fields>
        </register>
        <register>
          <name>CI</name>
          <description>SPI clear interrupt register</description>
          <addressOffset>0xA</addressOffset>
          <size>8</size>
          <access>read-write</access>
          <resetValue>0</resetValue>
          <resetMask>0xFF</resetMask>
          <fields>
            <field>
              <name>SPRFCI</name>
              <description>Receive FIFO full flag clear interrupt</description>
              <bitOffset>0</bitOffset>
              <bitWidth>1</bitWidth>
              <access>write-only</access>
            </field>
            <field>
              <name>SPTEFCI</name>
              <description>Transmit FIFO empty flag clear interrupt</description>
              <bitOffset>1</bitOffset>
              <bitWidth>1</bitWidth>
              <access>write-only</access>
            </field>
            <field>
              <name>RNFULLFCI</name>
              <description>Receive FIFO nearly full flag clear interrupt</description>
              <bitOffset>2</bitOffset>
              <bitWidth>1</bitWidth>
              <access>write-only</access>
            </field>
            <field>
              <name>TNEAREFCI</name>
              <description>Transmit FIFO nearly empty flag clear interrupt</description>
              <bitOffset>3</bitOffset>
              <bitWidth>1</bitWidth>
              <access>write-only</access>
            </field>
            <field>
              <name>RXFOF</name>
              <description>Receive FIFO overflow flag</description>
              <bitOffset>4</bitOffset>
              <bitWidth>1</bitWidth>
              <access>read-only</access>
              <enumeratedValues>
                <enumeratedValue>
                  <name>0</name>
                  <description>Receive FIFO overflow condition has not occurred</description>
                  <value>#0</value>
                </enumeratedValue>
                <enumeratedValue>
                  <name>1</name>
                  <description>Receive FIFO overflow condition occurred</description>
                  <value>#1</value>
                </enumeratedValue>
              </enumeratedValues>
            </field>
            <field>
              <name>TXFOF</name>
              <description>Transmit FIFO overflow flag</description>
              <bitOffset>5</bitOffset>
              <bitWidth>1</bitWidth>
              <access>read-only</access>
              <enumeratedValues>
                <enumeratedValue>
                  <name>0</name>
                  <description>Transmit FIFO overflow condition has not occurred</description>
                  <value>#0</value>
                </enumeratedValue>
                <enumeratedValue>
                  <name>1</name>
                  <description>Transmit FIFO overflow condition occurred</description>
                  <value>#1</value>
                </enumeratedValue>
              </enumeratedValues>
            </field>
            <field>
              <name>RXFERR</name>
              <description>Receive FIFO error flag</description>
              <bitOffset>6</bitOffset>
              <bitWidth>1</bitWidth>
              <access>read-only</access>
              <enumeratedValues>
                <enumeratedValue>
                  <name>0</name>
                  <description>No receive FIFO error occurred</description>
                  <value>#0</value>
                </enumeratedValue>
                <enumeratedValue>
                  <name>1</name>
                  <description>A receive FIFO error occurred</description>
                  <value>#1</value>
                </enumeratedValue>
              </enumeratedValues>
            </field>
            <field>
              <name>TXFERR</name>
              <description>Transmit FIFO error flag</description>
              <bitOffset>7</bitOffset>
              <bitWidth>1</bitWidth>
              <access>read-only</access>
              <enumeratedValues>
                <enumeratedValue>
                  <name>0</name>
                  <description>No transmit FIFO error occurred</description>
                  <value>#0</value>
                </enumeratedValue>
                <enumeratedValue>
                  <name>1</name>
                  <description>A transmit FIFO error occurred</description>
                  <value>#1</value>
                </enumeratedValue>
              </enumeratedValues>
            </field>
          </fields>
        </register>
        <register>
          <name>C3</name>
          <description>SPI control register 3</description>
          <addressOffset>0xB</addressOffset>
          <size>8</size>
          <access>read-write</access>
          <resetValue>0</resetValue>
          <resetMask>0xFF</resetMask>
          <fields>
            <field>
              <name>FIFOMODE</name>
              <description>FIFO mode enable</description>
              <bitOffset>0</bitOffset>
              <bitWidth>1</bitWidth>
              <access>read-write</access>
              <enumeratedValues>
                <enumeratedValue>
                  <name>0</name>
                  <description>Buffer mode disabled</description>
                  <value>#0</value>
                </enumeratedValue>
                <enumeratedValue>
                  <name>1</name>
                  <description>Data available in the receive data buffer</description>
                  <value>#1</value>
                </enumeratedValue>
              </enumeratedValues>
            </field>
            <field>
              <name>RNFULLIEN</name>
              <description>Receive FIFO nearly full interrupt enable</description>
              <bitOffset>1</bitOffset>
              <bitWidth>1</bitWidth>
              <access>read-write</access>
              <enumeratedValues>
                <enumeratedValue>
                  <name>0</name>
                  <description>No interrupt upon RNFULLF being set</description>
                  <value>#0</value>
                </enumeratedValue>
                <enumeratedValue>
                  <name>1</name>
                  <description>Enable interrupts upon RNFULLF being set</description>
                  <value>#1</value>
                </enumeratedValue>
              </enumeratedValues>
            </field>
            <field>
              <name>TNEARIEN</name>
              <description>Transmit FIFO nearly empty interrupt enable</description>
              <bitOffset>2</bitOffset>
              <bitWidth>1</bitWidth>
              <access>read-write</access>
              <enumeratedValues>
                <enumeratedValue>
                  <name>0</name>
                  <description>No interrupt upon TNEAREF being set</description>
                  <value>#0</value>
                </enumeratedValue>
                <enumeratedValue>
                  <name>1</name>
                  <description>Enable interrupts upon TNEAREF being set</description>
                  <value>#1</value>
                </enumeratedValue>
              </enumeratedValues>
            </field>
            <field>
              <name>INTCLR</name>
              <description>Interrupt clearing mechanism select</description>
              <bitOffset>3</bitOffset>
              <bitWidth>1</bitWidth>
              <access>read-write</access>
              <enumeratedValues>
                <enumeratedValue>
                  <name>0</name>
                  <description>These interrupts are cleared when the corresponding flags are cleared depending on the state of the FIFOs</description>
                  <value>#0</value>
                </enumeratedValue>
                <enumeratedValue>
                  <name>1</name>
                  <description>These interrupts are cleared by writing the corresponding bits in the CI register</description>
                  <value>#1</value>
                </enumeratedValue>
              </enumeratedValues>
            </field>
            <field>
              <name>RNFULLF_MARK</name>
              <description>Receive FIFO nearly full watermark</description>
              <bitOffset>4</bitOffset>
              <bitWidth>1</bitWidth>
              <access>read-write</access>
              <enumeratedValues>
                <enumeratedValue>
                  <name>0</name>
                  <description>RNFULLF is set when the receive FIFO has 48 bits or more</description>
                  <value>#0</value>
                </enumeratedValue>
                <enumeratedValue>
                  <name>1</name>
                  <description>RNFULLF is set when the receive FIFO has 32 bits or more</description>
                  <value>#1</value>
                </enumeratedValue>
              </enumeratedValues>
            </field>
            <field>
              <name>TNEAREF_MARK</name>
              <description>Transmit FIFO nearly empty watermark</description>
              <bitOffset>5</bitOffset>
              <bitWidth>1</bitWidth>
              <access>read-write</access>
              <enumeratedValues>
                <enumeratedValue>
                  <name>0</name>
                  <description>TNEAREF is set when the transmit FIFO has 16 bits or less</description>
                  <value>#0</value>
                </enumeratedValue>
                <enumeratedValue>
                  <name>1</name>
                  <description>TNEAREF is set when the transmit FIFO has 32 bits or less</description>
                  <value>#1</value>
                </enumeratedValue>
              </enumeratedValues>
            </field>
          </fields>
        </register>
      </registers>
    </peripheral>
    <peripheral>
      <name>LLWU</name>
      <description>Low leakage wakeup unit</description>
      <prependToName>LLWU_</prependToName>
      <baseAddress>0x4007C000</baseAddress>
      <addressBlock>
        <offset>0</offset>
        <size>0xA</size>
        <usage>registers</usage>
      </addressBlock>
      <interrupt>
        <name>LLWU</name>
        <value>7</value>
      </interrupt>
      <registers>
        <register>
          <name>PE1</name>
          <description>LLWU Pin Enable 1 register</description>
          <addressOffset>0</addressOffset>
          <size>8</size>
          <access>read-write</access>
          <resetValue>0</resetValue>
          <resetMask>0xFF</resetMask>
          <fields>
            <field>
              <name>WUPE0</name>
              <description>Wakeup Pin Enable For LLWU_P0</description>
              <bitOffset>0</bitOffset>
              <bitWidth>2</bitWidth>
              <access>read-write</access>
              <enumeratedValues>
                <enumeratedValue>
                  <name>00</name>
                  <description>External input pin disabled as wakeup input</description>
                  <value>#00</value>
                </enumeratedValue>
                <enumeratedValue>
                  <name>01</name>
                  <description>External input pin enabled with rising edge detection</description>
                  <value>#01</value>
                </enumeratedValue>
                <enumeratedValue>
                  <name>10</name>
                  <description>External input pin enabled with falling edge detection</description>
                  <value>#10</value>
                </enumeratedValue>
                <enumeratedValue>
                  <name>11</name>
                  <description>External input pin enabled with any change detection</description>
                  <value>#11</value>
                </enumeratedValue>
              </enumeratedValues>
            </field>
            <field>
              <name>WUPE1</name>
              <description>Wakeup Pin Enable For LLWU_P1</description>
              <bitOffset>2</bitOffset>
              <bitWidth>2</bitWidth>
              <access>read-write</access>
              <enumeratedValues>
                <enumeratedValue>
                  <name>00</name>
                  <description>External input pin disabled as wakeup input</description>
                  <value>#00</value>
                </enumeratedValue>
                <enumeratedValue>
                  <name>01</name>
                  <description>External input pin enabled with rising edge detection</description>
                  <value>#01</value>
                </enumeratedValue>
                <enumeratedValue>
                  <name>10</name>
                  <description>External input pin enabled with falling edge detection</description>
                  <value>#10</value>
                </enumeratedValue>
                <enumeratedValue>
                  <name>11</name>
                  <description>External input pin enabled with any change detection</description>
                  <value>#11</value>
                </enumeratedValue>
              </enumeratedValues>
            </field>
            <field>
              <name>WUPE2</name>
              <description>Wakeup Pin Enable For LLWU_P2</description>
              <bitOffset>4</bitOffset>
              <bitWidth>2</bitWidth>
              <access>read-write</access>
              <enumeratedValues>
                <enumeratedValue>
                  <name>00</name>
                  <description>External input pin disabled as wakeup input</description>
                  <value>#00</value>
                </enumeratedValue>
                <enumeratedValue>
                  <name>01</name>
                  <description>External input pin enabled with rising edge detection</description>
                  <value>#01</value>
                </enumeratedValue>
                <enumeratedValue>
                  <name>10</name>
                  <description>External input pin enabled with falling edge detection</description>
                  <value>#10</value>
                </enumeratedValue>
                <enumeratedValue>
                  <name>11</name>
                  <description>External input pin enabled with any change detection</description>
                  <value>#11</value>
                </enumeratedValue>
              </enumeratedValues>
            </field>
            <field>
              <name>WUPE3</name>
              <description>Wakeup Pin Enable For LLWU_P3</description>
              <bitOffset>6</bitOffset>
              <bitWidth>2</bitWidth>
              <access>read-write</access>
              <enumeratedValues>
                <enumeratedValue>
                  <name>00</name>
                  <description>External input pin disabled as wakeup input</description>
                  <value>#00</value>
                </enumeratedValue>
                <enumeratedValue>
                  <name>01</name>
                  <description>External input pin enabled with rising edge detection</description>
                  <value>#01</value>
                </enumeratedValue>
                <enumeratedValue>
                  <name>10</name>
                  <description>External input pin enabled with falling edge detection</description>
                  <value>#10</value>
                </enumeratedValue>
                <enumeratedValue>
                  <name>11</name>
                  <description>External input pin enabled with any change detection</description>
                  <value>#11</value>
                </enumeratedValue>
              </enumeratedValues>
            </field>
          </fields>
        </register>
        <register>
          <name>PE2</name>
          <description>LLWU Pin Enable 2 register</description>
          <addressOffset>0x1</addressOffset>
          <size>8</size>
          <access>read-write</access>
          <resetValue>0</resetValue>
          <resetMask>0xFF</resetMask>
          <fields>
            <field>
              <name>WUPE4</name>
              <description>Wakeup Pin Enable For LLWU_P4</description>
              <bitOffset>0</bitOffset>
              <bitWidth>2</bitWidth>
              <access>read-write</access>
              <enumeratedValues>
                <enumeratedValue>
                  <name>00</name>
                  <description>External input pin disabled as wakeup input</description>
                  <value>#00</value>
                </enumeratedValue>
                <enumeratedValue>
                  <name>01</name>
                  <description>External input pin enabled with rising edge detection</description>
                  <value>#01</value>
                </enumeratedValue>
                <enumeratedValue>
                  <name>10</name>
                  <description>External input pin enabled with falling edge detection</description>
                  <value>#10</value>
                </enumeratedValue>
                <enumeratedValue>
                  <name>11</name>
                  <description>External input pin enabled with any change detection</description>
                  <value>#11</value>
                </enumeratedValue>
              </enumeratedValues>
            </field>
            <field>
              <name>WUPE5</name>
              <description>Wakeup Pin Enable For LLWU_P5</description>
              <bitOffset>2</bitOffset>
              <bitWidth>2</bitWidth>
              <access>read-write</access>
              <enumeratedValues>
                <enumeratedValue>
                  <name>00</name>
                  <description>External input pin disabled as wakeup input</description>
                  <value>#00</value>
                </enumeratedValue>
                <enumeratedValue>
                  <name>01</name>
                  <description>External input pin enabled with rising edge detection</description>
                  <value>#01</value>
                </enumeratedValue>
                <enumeratedValue>
                  <name>10</name>
                  <description>External input pin enabled with falling edge detection</description>
                  <value>#10</value>
                </enumeratedValue>
                <enumeratedValue>
                  <name>11</name>
                  <description>External input pin enabled with any change detection</description>
                  <value>#11</value>
                </enumeratedValue>
              </enumeratedValues>
            </field>
            <field>
              <name>WUPE6</name>
              <description>Wakeup Pin Enable For LLWU_P6</description>
              <bitOffset>4</bitOffset>
              <bitWidth>2</bitWidth>
              <access>read-write</access>
              <enumeratedValues>
                <enumeratedValue>
                  <name>00</name>
                  <description>External input pin disabled as wakeup input</description>
                  <value>#00</value>
                </enumeratedValue>
                <enumeratedValue>
                  <name>01</name>
                  <description>External input pin enabled with rising edge detection</description>
                  <value>#01</value>
                </enumeratedValue>
                <enumeratedValue>
                  <name>10</name>
                  <description>External input pin enabled with falling edge detection</description>
                  <value>#10</value>
                </enumeratedValue>
                <enumeratedValue>
                  <name>11</name>
                  <description>External input pin enabled with any change detection</description>
                  <value>#11</value>
                </enumeratedValue>
              </enumeratedValues>
            </field>
            <field>
              <name>WUPE7</name>
              <description>Wakeup Pin Enable For LLWU_P7</description>
              <bitOffset>6</bitOffset>
              <bitWidth>2</bitWidth>
              <access>read-write</access>
              <enumeratedValues>
                <enumeratedValue>
                  <name>00</name>
                  <description>External input pin disabled as wakeup input</description>
                  <value>#00</value>
                </enumeratedValue>
                <enumeratedValue>
                  <name>01</name>
                  <description>External input pin enabled with rising edge detection</description>
                  <value>#01</value>
                </enumeratedValue>
                <enumeratedValue>
                  <name>10</name>
                  <description>External input pin enabled with falling edge detection</description>
                  <value>#10</value>
                </enumeratedValue>
                <enumeratedValue>
                  <name>11</name>
                  <description>External input pin enabled with any change detection</description>
                  <value>#11</value>
                </enumeratedValue>
              </enumeratedValues>
            </field>
          </fields>
        </register>
        <register>
          <name>PE3</name>
          <description>LLWU Pin Enable 3 register</description>
          <addressOffset>0x2</addressOffset>
          <size>8</size>
          <access>read-write</access>
          <resetValue>0</resetValue>
          <resetMask>0xFF</resetMask>
          <fields>
            <field>
              <name>WUPE8</name>
              <description>Wakeup Pin Enable For LLWU_P8</description>
              <bitOffset>0</bitOffset>
              <bitWidth>2</bitWidth>
              <access>read-write</access>
              <enumeratedValues>
                <enumeratedValue>
                  <name>00</name>
                  <description>External input pin disabled as wakeup input</description>
                  <value>#00</value>
                </enumeratedValue>
                <enumeratedValue>
                  <name>01</name>
                  <description>External input pin enabled with rising edge detection</description>
                  <value>#01</value>
                </enumeratedValue>
                <enumeratedValue>
                  <name>10</name>
                  <description>External input pin enabled with falling edge detection</description>
                  <value>#10</value>
                </enumeratedValue>
                <enumeratedValue>
                  <name>11</name>
                  <description>External input pin enabled with any change detection</description>
                  <value>#11</value>
                </enumeratedValue>
              </enumeratedValues>
            </field>
            <field>
              <name>WUPE9</name>
              <description>Wakeup Pin Enable For LLWU_P9</description>
              <bitOffset>2</bitOffset>
              <bitWidth>2</bitWidth>
              <access>read-write</access>
              <enumeratedValues>
                <enumeratedValue>
                  <name>00</name>
                  <description>External input pin disabled as wakeup input</description>
                  <value>#00</value>
                </enumeratedValue>
                <enumeratedValue>
                  <name>01</name>
                  <description>External input pin enabled with rising edge detection</description>
                  <value>#01</value>
                </enumeratedValue>
                <enumeratedValue>
                  <name>10</name>
                  <description>External input pin enabled with falling edge detection</description>
                  <value>#10</value>
                </enumeratedValue>
                <enumeratedValue>
                  <name>11</name>
                  <description>External input pin enabled with any change detection</description>
                  <value>#11</value>
                </enumeratedValue>
              </enumeratedValues>
            </field>
            <field>
              <name>WUPE10</name>
              <description>Wakeup Pin Enable For LLWU_P10</description>
              <bitOffset>4</bitOffset>
              <bitWidth>2</bitWidth>
              <access>read-write</access>
              <enumeratedValues>
                <enumeratedValue>
                  <name>00</name>
                  <description>External input pin disabled as wakeup input</description>
                  <value>#00</value>
                </enumeratedValue>
                <enumeratedValue>
                  <name>01</name>
                  <description>External input pin enabled with rising edge detection</description>
                  <value>#01</value>
                </enumeratedValue>
                <enumeratedValue>
                  <name>10</name>
                  <description>External input pin enabled with falling edge detection</description>
                  <value>#10</value>
                </enumeratedValue>
                <enumeratedValue>
                  <name>11</name>
                  <description>External input pin enabled with any change detection</description>
                  <value>#11</value>
                </enumeratedValue>
              </enumeratedValues>
            </field>
            <field>
              <name>WUPE11</name>
              <description>Wakeup Pin Enable For LLWU_P11</description>
              <bitOffset>6</bitOffset>
              <bitWidth>2</bitWidth>
              <access>read-write</access>
              <enumeratedValues>
                <enumeratedValue>
                  <name>00</name>
                  <description>External input pin disabled as wakeup input</description>
                  <value>#00</value>
                </enumeratedValue>
                <enumeratedValue>
                  <name>01</name>
                  <description>External input pin enabled with rising edge detection</description>
                  <value>#01</value>
                </enumeratedValue>
                <enumeratedValue>
                  <name>10</name>
                  <description>External input pin enabled with falling edge detection</description>
                  <value>#10</value>
                </enumeratedValue>
                <enumeratedValue>
                  <name>11</name>
                  <description>External input pin enabled with any change detection</description>
                  <value>#11</value>
                </enumeratedValue>
              </enumeratedValues>
            </field>
          </fields>
        </register>
        <register>
          <name>PE4</name>
          <description>LLWU Pin Enable 4 register</description>
          <addressOffset>0x3</addressOffset>
          <size>8</size>
          <access>read-write</access>
          <resetValue>0</resetValue>
          <resetMask>0xFF</resetMask>
          <fields>
            <field>
              <name>WUPE12</name>
              <description>Wakeup Pin Enable For LLWU_P12</description>
              <bitOffset>0</bitOffset>
              <bitWidth>2</bitWidth>
              <access>read-write</access>
              <enumeratedValues>
                <enumeratedValue>
                  <name>00</name>
                  <description>External input pin disabled as wakeup input</description>
                  <value>#00</value>
                </enumeratedValue>
                <enumeratedValue>
                  <name>01</name>
                  <description>External input pin enabled with rising edge detection</description>
                  <value>#01</value>
                </enumeratedValue>
                <enumeratedValue>
                  <name>10</name>
                  <description>External input pin enabled with falling edge detection</description>
                  <value>#10</value>
                </enumeratedValue>
                <enumeratedValue>
                  <name>11</name>
                  <description>External input pin enabled with any change detection</description>
                  <value>#11</value>
                </enumeratedValue>
              </enumeratedValues>
            </field>
            <field>
              <name>WUPE13</name>
              <description>Wakeup Pin Enable For LLWU_P13</description>
              <bitOffset>2</bitOffset>
              <bitWidth>2</bitWidth>
              <access>read-write</access>
              <enumeratedValues>
                <enumeratedValue>
                  <name>00</name>
                  <description>External input pin disabled as wakeup input</description>
                  <value>#00</value>
                </enumeratedValue>
                <enumeratedValue>
                  <name>01</name>
                  <description>External input pin enabled with rising edge detection</description>
                  <value>#01</value>
                </enumeratedValue>
                <enumeratedValue>
                  <name>10</name>
                  <description>External input pin enabled with falling edge detection</description>
                  <value>#10</value>
                </enumeratedValue>
                <enumeratedValue>
                  <name>11</name>
                  <description>External input pin enabled with any change detection</description>
                  <value>#11</value>
                </enumeratedValue>
              </enumeratedValues>
            </field>
            <field>
              <name>WUPE14</name>
              <description>Wakeup Pin Enable For LLWU_P14</description>
              <bitOffset>4</bitOffset>
              <bitWidth>2</bitWidth>
              <access>read-write</access>
              <enumeratedValues>
                <enumeratedValue>
                  <name>00</name>
                  <description>External input pin disabled as wakeup input</description>
                  <value>#00</value>
                </enumeratedValue>
                <enumeratedValue>
                  <name>01</name>
                  <description>External input pin enabled with rising edge detection</description>
                  <value>#01</value>
                </enumeratedValue>
                <enumeratedValue>
                  <name>10</name>
                  <description>External input pin enabled with falling edge detection</description>
                  <value>#10</value>
                </enumeratedValue>
                <enumeratedValue>
                  <name>11</name>
                  <description>External input pin enabled with any change detection</description>
                  <value>#11</value>
                </enumeratedValue>
              </enumeratedValues>
            </field>
            <field>
              <name>WUPE15</name>
              <description>Wakeup Pin Enable For LLWU_P15</description>
              <bitOffset>6</bitOffset>
              <bitWidth>2</bitWidth>
              <access>read-write</access>
              <enumeratedValues>
                <enumeratedValue>
                  <name>00</name>
                  <description>External input pin disabled as wakeup input</description>
                  <value>#00</value>
                </enumeratedValue>
                <enumeratedValue>
                  <name>01</name>
                  <description>External input pin enabled with rising edge detection</description>
                  <value>#01</value>
                </enumeratedValue>
                <enumeratedValue>
                  <name>10</name>
                  <description>External input pin enabled with falling edge detection</description>
                  <value>#10</value>
                </enumeratedValue>
                <enumeratedValue>
                  <name>11</name>
                  <description>External input pin enabled with any change detection</description>
                  <value>#11</value>
                </enumeratedValue>
              </enumeratedValues>
            </field>
          </fields>
        </register>
        <register>
          <name>ME</name>
          <description>LLWU Module Enable register</description>
          <addressOffset>0x4</addressOffset>
          <size>8</size>
          <access>read-write</access>
          <resetValue>0</resetValue>
          <resetMask>0xFF</resetMask>
          <fields>
            <field>
              <name>WUME0</name>
              <description>Wakeup Module Enable For Module 0</description>
              <bitOffset>0</bitOffset>
              <bitWidth>1</bitWidth>
              <access>read-write</access>
              <enumeratedValues>
                <enumeratedValue>
                  <name>0</name>
                  <description>Internal module flag not used as wakeup source</description>
                  <value>#0</value>
                </enumeratedValue>
                <enumeratedValue>
                  <name>1</name>
                  <description>Internal module flag used as wakeup source</description>
                  <value>#1</value>
                </enumeratedValue>
              </enumeratedValues>
            </field>
            <field>
              <name>WUME1</name>
              <description>Wakeup Module Enable for Module 1</description>
              <bitOffset>1</bitOffset>
              <bitWidth>1</bitWidth>
              <access>read-write</access>
              <enumeratedValues>
                <enumeratedValue>
                  <name>0</name>
                  <description>Internal module flag not used as wakeup source</description>
                  <value>#0</value>
                </enumeratedValue>
                <enumeratedValue>
                  <name>1</name>
                  <description>Internal module flag used as wakeup source</description>
                  <value>#1</value>
                </enumeratedValue>
              </enumeratedValues>
            </field>
            <field>
              <name>WUME2</name>
              <description>Wakeup Module Enable For Module 2</description>
              <bitOffset>2</bitOffset>
              <bitWidth>1</bitWidth>
              <access>read-write</access>
              <enumeratedValues>
                <enumeratedValue>
                  <name>0</name>
                  <description>Internal module flag not used as wakeup source</description>
                  <value>#0</value>
                </enumeratedValue>
                <enumeratedValue>
                  <name>1</name>
                  <description>Internal module flag used as wakeup source</description>
                  <value>#1</value>
                </enumeratedValue>
              </enumeratedValues>
            </field>
            <field>
              <name>WUME3</name>
              <description>Wakeup Module Enable For Module 3</description>
              <bitOffset>3</bitOffset>
              <bitWidth>1</bitWidth>
              <access>read-write</access>
              <enumeratedValues>
                <enumeratedValue>
                  <name>0</name>
                  <description>Internal module flag not used as wakeup source</description>
                  <value>#0</value>
                </enumeratedValue>
                <enumeratedValue>
                  <name>1</name>
                  <description>Internal module flag used as wakeup source</description>
                  <value>#1</value>
                </enumeratedValue>
              </enumeratedValues>
            </field>
            <field>
              <name>WUME4</name>
              <description>Wakeup Module Enable For Module 4</description>
              <bitOffset>4</bitOffset>
              <bitWidth>1</bitWidth>
              <access>read-write</access>
              <enumeratedValues>
                <enumeratedValue>
                  <name>0</name>
                  <description>Internal module flag not used as wakeup source</description>
                  <value>#0</value>
                </enumeratedValue>
                <enumeratedValue>
                  <name>1</name>
                  <description>Internal module flag used as wakeup source</description>
                  <value>#1</value>
                </enumeratedValue>
              </enumeratedValues>
            </field>
            <field>
              <name>WUME5</name>
              <description>Wakeup Module Enable For Module 5</description>
              <bitOffset>5</bitOffset>
              <bitWidth>1</bitWidth>
              <access>read-write</access>
              <enumeratedValues>
                <enumeratedValue>
                  <name>0</name>
                  <description>Internal module flag not used as wakeup source</description>
                  <value>#0</value>
                </enumeratedValue>
                <enumeratedValue>
                  <name>1</name>
                  <description>Internal module flag used as wakeup source</description>
                  <value>#1</value>
                </enumeratedValue>
              </enumeratedValues>
            </field>
            <field>
              <name>WUME6</name>
              <description>Wakeup Module Enable For Module 6</description>
              <bitOffset>6</bitOffset>
              <bitWidth>1</bitWidth>
              <access>read-write</access>
              <enumeratedValues>
                <enumeratedValue>
                  <name>0</name>
                  <description>Internal module flag not used as wakeup source</description>
                  <value>#0</value>
                </enumeratedValue>
                <enumeratedValue>
                  <name>1</name>
                  <description>Internal module flag used as wakeup source</description>
                  <value>#1</value>
                </enumeratedValue>
              </enumeratedValues>
            </field>
            <field>
              <name>WUME7</name>
              <description>Wakeup Module Enable For Module 7</description>
              <bitOffset>7</bitOffset>
              <bitWidth>1</bitWidth>
              <access>read-write</access>
              <enumeratedValues>
                <enumeratedValue>
                  <name>0</name>
                  <description>Internal module flag not used as wakeup source</description>
                  <value>#0</value>
                </enumeratedValue>
                <enumeratedValue>
                  <name>1</name>
                  <description>Internal module flag used as wakeup source</description>
                  <value>#1</value>
                </enumeratedValue>
              </enumeratedValues>
            </field>
          </fields>
        </register>
        <register>
          <name>F1</name>
          <description>LLWU Flag 1 register</description>
          <addressOffset>0x5</addressOffset>
          <size>8</size>
          <access>read-write</access>
          <resetValue>0</resetValue>
          <resetMask>0xFF</resetMask>
          <fields>
            <field>
              <name>WUF0</name>
              <description>Wakeup Flag For LLWU_P0</description>
              <bitOffset>0</bitOffset>
              <bitWidth>1</bitWidth>
              <access>read-write</access>
              <enumeratedValues>
                <enumeratedValue>
                  <name>0</name>
                  <description>LLWU_P0 input was not a wakeup source</description>
                  <value>#0</value>
                </enumeratedValue>
                <enumeratedValue>
                  <name>1</name>
                  <description>LLWU_P0 input was a wakeup source</description>
                  <value>#1</value>
                </enumeratedValue>
              </enumeratedValues>
            </field>
            <field>
              <name>WUF1</name>
              <description>Wakeup Flag For LLWU_P1</description>
              <bitOffset>1</bitOffset>
              <bitWidth>1</bitWidth>
              <access>read-write</access>
              <enumeratedValues>
                <enumeratedValue>
                  <name>0</name>
                  <description>LLWU_P1 input was not a wakeup source</description>
                  <value>#0</value>
                </enumeratedValue>
                <enumeratedValue>
                  <name>1</name>
                  <description>LLWU_P1 input was a wakeup source</description>
                  <value>#1</value>
                </enumeratedValue>
              </enumeratedValues>
            </field>
            <field>
              <name>WUF2</name>
              <description>Wakeup Flag For LLWU_P2</description>
              <bitOffset>2</bitOffset>
              <bitWidth>1</bitWidth>
              <access>read-write</access>
              <enumeratedValues>
                <enumeratedValue>
                  <name>0</name>
                  <description>LLWU_P2 input was not a wakeup source</description>
                  <value>#0</value>
                </enumeratedValue>
                <enumeratedValue>
                  <name>1</name>
                  <description>LLWU_P2 input was a wakeup source</description>
                  <value>#1</value>
                </enumeratedValue>
              </enumeratedValues>
            </field>
            <field>
              <name>WUF3</name>
              <description>Wakeup Flag For LLWU_P3</description>
              <bitOffset>3</bitOffset>
              <bitWidth>1</bitWidth>
              <access>read-write</access>
              <enumeratedValues>
                <enumeratedValue>
                  <name>0</name>
                  <description>LLWU_P3 input was not a wake-up source</description>
                  <value>#0</value>
                </enumeratedValue>
                <enumeratedValue>
                  <name>1</name>
                  <description>LLWU_P3 input was a wake-up source</description>
                  <value>#1</value>
                </enumeratedValue>
              </enumeratedValues>
            </field>
            <field>
              <name>WUF4</name>
              <description>Wakeup Flag For LLWU_P4</description>
              <bitOffset>4</bitOffset>
              <bitWidth>1</bitWidth>
              <access>read-write</access>
              <enumeratedValues>
                <enumeratedValue>
                  <name>0</name>
                  <description>LLWU_P4 input was not a wakeup source</description>
                  <value>#0</value>
                </enumeratedValue>
                <enumeratedValue>
                  <name>1</name>
                  <description>LLWU_P4 input was a wakeup source</description>
                  <value>#1</value>
                </enumeratedValue>
              </enumeratedValues>
            </field>
            <field>
              <name>WUF5</name>
              <description>Wakeup Flag For LLWU_P5</description>
              <bitOffset>5</bitOffset>
              <bitWidth>1</bitWidth>
              <access>read-write</access>
              <enumeratedValues>
                <enumeratedValue>
                  <name>0</name>
                  <description>LLWU_P5 input was not a wakeup source</description>
                  <value>#0</value>
                </enumeratedValue>
                <enumeratedValue>
                  <name>1</name>
                  <description>LLWU_P5 input was a wakeup source</description>
                  <value>#1</value>
                </enumeratedValue>
              </enumeratedValues>
            </field>
            <field>
              <name>WUF6</name>
              <description>Wakeup Flag For LLWU_P6</description>
              <bitOffset>6</bitOffset>
              <bitWidth>1</bitWidth>
              <access>read-write</access>
              <enumeratedValues>
                <enumeratedValue>
                  <name>0</name>
                  <description>LLWU_P6 input was not a wakeup source</description>
                  <value>#0</value>
                </enumeratedValue>
                <enumeratedValue>
                  <name>1</name>
                  <description>LLWU_P6 input was a wakeup source</description>
                  <value>#1</value>
                </enumeratedValue>
              </enumeratedValues>
            </field>
            <field>
              <name>WUF7</name>
              <description>Wakeup Flag For LLWU_P7</description>
              <bitOffset>7</bitOffset>
              <bitWidth>1</bitWidth>
              <access>read-write</access>
              <enumeratedValues>
                <enumeratedValue>
                  <name>0</name>
                  <description>LLWU_P7 input was not a wakeup source</description>
                  <value>#0</value>
                </enumeratedValue>
                <enumeratedValue>
                  <name>1</name>
                  <description>LLWU_P7 input was a wakeup source</description>
                  <value>#1</value>
                </enumeratedValue>
              </enumeratedValues>
            </field>
          </fields>
        </register>
        <register>
          <name>F2</name>
          <description>LLWU Flag 2 register</description>
          <addressOffset>0x6</addressOffset>
          <size>8</size>
          <access>read-write</access>
          <resetValue>0</resetValue>
          <resetMask>0xFF</resetMask>
          <fields>
            <field>
              <name>WUF8</name>
              <description>Wakeup Flag For LLWU_P8</description>
              <bitOffset>0</bitOffset>
              <bitWidth>1</bitWidth>
              <access>read-write</access>
              <enumeratedValues>
                <enumeratedValue>
                  <name>0</name>
                  <description>LLWU_P8 input was not a wakeup source</description>
                  <value>#0</value>
                </enumeratedValue>
                <enumeratedValue>
                  <name>1</name>
                  <description>LLWU_P8 input was a wakeup source</description>
                  <value>#1</value>
                </enumeratedValue>
              </enumeratedValues>
            </field>
            <field>
              <name>WUF9</name>
              <description>Wakeup Flag For LLWU_P9</description>
              <bitOffset>1</bitOffset>
              <bitWidth>1</bitWidth>
              <access>read-write</access>
              <enumeratedValues>
                <enumeratedValue>
                  <name>0</name>
                  <description>LLWU_P9 input was not a wakeup source</description>
                  <value>#0</value>
                </enumeratedValue>
                <enumeratedValue>
                  <name>1</name>
                  <description>LLWU_P9 input was a wakeup source</description>
                  <value>#1</value>
                </enumeratedValue>
              </enumeratedValues>
            </field>
            <field>
              <name>WUF10</name>
              <description>Wakeup Flag For LLWU_P10</description>
              <bitOffset>2</bitOffset>
              <bitWidth>1</bitWidth>
              <access>read-write</access>
              <enumeratedValues>
                <enumeratedValue>
                  <name>0</name>
                  <description>LLWU_P10 input was not a wakeup source</description>
                  <value>#0</value>
                </enumeratedValue>
                <enumeratedValue>
                  <name>1</name>
                  <description>LLWU_P10 input was a wakeup source</description>
                  <value>#1</value>
                </enumeratedValue>
              </enumeratedValues>
            </field>
            <field>
              <name>WUF11</name>
              <description>Wakeup Flag For LLWU_P11</description>
              <bitOffset>3</bitOffset>
              <bitWidth>1</bitWidth>
              <access>read-write</access>
              <enumeratedValues>
                <enumeratedValue>
                  <name>0</name>
                  <description>LLWU_P11 input was not a wakeup source</description>
                  <value>#0</value>
                </enumeratedValue>
                <enumeratedValue>
                  <name>1</name>
                  <description>LLWU_P11 input was a wakeup source</description>
                  <value>#1</value>
                </enumeratedValue>
              </enumeratedValues>
            </field>
            <field>
              <name>WUF12</name>
              <description>Wakeup Flag For LLWU_P12</description>
              <bitOffset>4</bitOffset>
              <bitWidth>1</bitWidth>
              <access>read-write</access>
              <enumeratedValues>
                <enumeratedValue>
                  <name>0</name>
                  <description>LLWU_P12 input was not a wakeup source</description>
                  <value>#0</value>
                </enumeratedValue>
                <enumeratedValue>
                  <name>1</name>
                  <description>LLWU_P12 input was a wakeup source</description>
                  <value>#1</value>
                </enumeratedValue>
              </enumeratedValues>
            </field>
            <field>
              <name>WUF13</name>
              <description>Wakeup Flag For LLWU_P13</description>
              <bitOffset>5</bitOffset>
              <bitWidth>1</bitWidth>
              <access>read-write</access>
              <enumeratedValues>
                <enumeratedValue>
                  <name>0</name>
                  <description>LLWU_P13 input was not a wakeup source</description>
                  <value>#0</value>
                </enumeratedValue>
                <enumeratedValue>
                  <name>1</name>
                  <description>LLWU_P13 input was a wakeup source</description>
                  <value>#1</value>
                </enumeratedValue>
              </enumeratedValues>
            </field>
            <field>
              <name>WUF14</name>
              <description>Wakeup Flag For LLWU_P14</description>
              <bitOffset>6</bitOffset>
              <bitWidth>1</bitWidth>
              <access>read-write</access>
              <enumeratedValues>
                <enumeratedValue>
                  <name>0</name>
                  <description>LLWU_P14 input was not a wakeup source</description>
                  <value>#0</value>
                </enumeratedValue>
                <enumeratedValue>
                  <name>1</name>
                  <description>LLWU_P14 input was a wakeup source</description>
                  <value>#1</value>
                </enumeratedValue>
              </enumeratedValues>
            </field>
            <field>
              <name>WUF15</name>
              <description>Wakeup Flag For LLWU_P15</description>
              <bitOffset>7</bitOffset>
              <bitWidth>1</bitWidth>
              <access>read-write</access>
              <enumeratedValues>
                <enumeratedValue>
                  <name>0</name>
                  <description>LLWU_P15 input was not a wakeup source</description>
                  <value>#0</value>
                </enumeratedValue>
                <enumeratedValue>
                  <name>1</name>
                  <description>LLWU_P15 input was a wakeup source</description>
                  <value>#1</value>
                </enumeratedValue>
              </enumeratedValues>
            </field>
          </fields>
        </register>
        <register>
          <name>F3</name>
          <description>LLWU Flag 3 register</description>
          <addressOffset>0x7</addressOffset>
          <size>8</size>
          <access>read-only</access>
          <resetValue>0</resetValue>
          <resetMask>0xFF</resetMask>
          <fields>
            <field>
              <name>MWUF0</name>
              <description>Wakeup flag For module 0</description>
              <bitOffset>0</bitOffset>
              <bitWidth>1</bitWidth>
              <access>read-only</access>
              <enumeratedValues>
                <enumeratedValue>
                  <name>0</name>
                  <description>Module 0 input was not a wakeup source</description>
                  <value>#0</value>
                </enumeratedValue>
                <enumeratedValue>
                  <name>1</name>
                  <description>Module 0 input was a wakeup source</description>
                  <value>#1</value>
                </enumeratedValue>
              </enumeratedValues>
            </field>
            <field>
              <name>MWUF1</name>
              <description>Wakeup flag For module 1</description>
              <bitOffset>1</bitOffset>
              <bitWidth>1</bitWidth>
              <access>read-only</access>
              <enumeratedValues>
                <enumeratedValue>
                  <name>0</name>
                  <description>Module 1 input was not a wakeup source</description>
                  <value>#0</value>
                </enumeratedValue>
                <enumeratedValue>
                  <name>1</name>
                  <description>Module 1 input was a wakeup source</description>
                  <value>#1</value>
                </enumeratedValue>
              </enumeratedValues>
            </field>
            <field>
              <name>MWUF2</name>
              <description>Wakeup flag For module 2</description>
              <bitOffset>2</bitOffset>
              <bitWidth>1</bitWidth>
              <access>read-only</access>
              <enumeratedValues>
                <enumeratedValue>
                  <name>0</name>
                  <description>Module 2 input was not a wakeup source</description>
                  <value>#0</value>
                </enumeratedValue>
                <enumeratedValue>
                  <name>1</name>
                  <description>Module 2 input was a wakeup source</description>
                  <value>#1</value>
                </enumeratedValue>
              </enumeratedValues>
            </field>
            <field>
              <name>MWUF3</name>
              <description>Wakeup flag For module 3</description>
              <bitOffset>3</bitOffset>
              <bitWidth>1</bitWidth>
              <access>read-only</access>
              <enumeratedValues>
                <enumeratedValue>
                  <name>0</name>
                  <description>Module 3 input was not a wakeup source</description>
                  <value>#0</value>
                </enumeratedValue>
                <enumeratedValue>
                  <name>1</name>
                  <description>Module 3 input was a wakeup source</description>
                  <value>#1</value>
                </enumeratedValue>
              </enumeratedValues>
            </field>
            <field>
              <name>MWUF4</name>
              <description>Wakeup flag For module 4</description>
              <bitOffset>4</bitOffset>
              <bitWidth>1</bitWidth>
              <access>read-only</access>
              <enumeratedValues>
                <enumeratedValue>
                  <name>0</name>
                  <description>Module 4 input was not a wakeup source</description>
                  <value>#0</value>
                </enumeratedValue>
                <enumeratedValue>
                  <name>1</name>
                  <description>Module 4 input was a wakeup source</description>
                  <value>#1</value>
                </enumeratedValue>
              </enumeratedValues>
            </field>
            <field>
              <name>MWUF5</name>
              <description>Wakeup flag For module 5</description>
              <bitOffset>5</bitOffset>
              <bitWidth>1</bitWidth>
              <access>read-only</access>
              <enumeratedValues>
                <enumeratedValue>
                  <name>0</name>
                  <description>Module 5 input was not a wakeup source</description>
                  <value>#0</value>
                </enumeratedValue>
                <enumeratedValue>
                  <name>1</name>
                  <description>Module 5 input was a wakeup source</description>
                  <value>#1</value>
                </enumeratedValue>
              </enumeratedValues>
            </field>
            <field>
              <name>MWUF6</name>
              <description>Wakeup flag For module 6</description>
              <bitOffset>6</bitOffset>
              <bitWidth>1</bitWidth>
              <access>read-only</access>
              <enumeratedValues>
                <enumeratedValue>
                  <name>0</name>
                  <description>Module 6 input was not a wakeup source</description>
                  <value>#0</value>
                </enumeratedValue>
                <enumeratedValue>
                  <name>1</name>
                  <description>Module 6 input was a wakeup source</description>
                  <value>#1</value>
                </enumeratedValue>
              </enumeratedValues>
            </field>
            <field>
              <name>MWUF7</name>
              <description>Wakeup flag For module 7</description>
              <bitOffset>7</bitOffset>
              <bitWidth>1</bitWidth>
              <access>read-only</access>
              <enumeratedValues>
                <enumeratedValue>
                  <name>0</name>
                  <description>Module 7 input was not a wakeup source</description>
                  <value>#0</value>
                </enumeratedValue>
                <enumeratedValue>
                  <name>1</name>
                  <description>Module 7 input was a wakeup source</description>
                  <value>#1</value>
                </enumeratedValue>
              </enumeratedValues>
            </field>
          </fields>
        </register>
        <register>
          <name>FILT1</name>
          <description>LLWU Pin Filter 1 register</description>
          <addressOffset>0x8</addressOffset>
          <size>8</size>
          <access>read-write</access>
          <resetValue>0</resetValue>
          <resetMask>0xFF</resetMask>
          <fields>
            <field>
              <name>FILTSEL</name>
              <description>Filter Pin Select</description>
              <bitOffset>0</bitOffset>
              <bitWidth>4</bitWidth>
              <access>read-write</access>
              <enumeratedValues>
                <enumeratedValue>
                  <name>0000</name>
                  <description>Select LLWU_P0 for filter</description>
                  <value>#0000</value>
                </enumeratedValue>
                <enumeratedValue>
                  <name>1111</name>
                  <description>Select LLWU_P15 for filter</description>
                  <value>#1111</value>
                </enumeratedValue>
              </enumeratedValues>
            </field>
            <field>
              <name>FILTE</name>
              <description>Digital Filter On External Pin</description>
              <bitOffset>5</bitOffset>
              <bitWidth>2</bitWidth>
              <access>read-write</access>
              <enumeratedValues>
                <enumeratedValue>
                  <name>00</name>
                  <description>Filter disabled</description>
                  <value>#00</value>
                </enumeratedValue>
                <enumeratedValue>
                  <name>01</name>
                  <description>Filter posedge detect enabled</description>
                  <value>#01</value>
                </enumeratedValue>
                <enumeratedValue>
                  <name>10</name>
                  <description>Filter negedge detect enabled</description>
                  <value>#10</value>
                </enumeratedValue>
                <enumeratedValue>
                  <name>11</name>
                  <description>Filter any edge detect enabled</description>
                  <value>#11</value>
                </enumeratedValue>
              </enumeratedValues>
            </field>
            <field>
              <name>FILTF</name>
              <description>Filter Detect Flag</description>
              <bitOffset>7</bitOffset>
              <bitWidth>1</bitWidth>
              <access>read-write</access>
              <enumeratedValues>
                <enumeratedValue>
                  <name>0</name>
                  <description>Pin Filter 1 was not a wakeup source</description>
                  <value>#0</value>
                </enumeratedValue>
                <enumeratedValue>
                  <name>1</name>
                  <description>Pin Filter 1 was a wakeup source</description>
                  <value>#1</value>
                </enumeratedValue>
              </enumeratedValues>
            </field>
          </fields>
        </register>
        <register>
          <name>FILT2</name>
          <description>LLWU Pin Filter 2 register</description>
          <addressOffset>0x9</addressOffset>
          <size>8</size>
          <access>read-write</access>
          <resetValue>0</resetValue>
          <resetMask>0xFF</resetMask>
          <fields>
            <field>
              <name>FILTSEL</name>
              <description>Filter Pin Select</description>
              <bitOffset>0</bitOffset>
              <bitWidth>4</bitWidth>
              <access>read-write</access>
              <enumeratedValues>
                <enumeratedValue>
                  <name>0000</name>
                  <description>Select LLWU_P0 for filter</description>
                  <value>#0000</value>
                </enumeratedValue>
                <enumeratedValue>
                  <name>1111</name>
                  <description>Select LLWU_P15 for filter</description>
                  <value>#1111</value>
                </enumeratedValue>
              </enumeratedValues>
            </field>
            <field>
              <name>FILTE</name>
              <description>Digital Filter On External Pin</description>
              <bitOffset>5</bitOffset>
              <bitWidth>2</bitWidth>
              <access>read-write</access>
              <enumeratedValues>
                <enumeratedValue>
                  <name>00</name>
                  <description>Filter disabled</description>
                  <value>#00</value>
                </enumeratedValue>
                <enumeratedValue>
                  <name>01</name>
                  <description>Filter posedge detect enabled</description>
                  <value>#01</value>
                </enumeratedValue>
                <enumeratedValue>
                  <name>10</name>
                  <description>Filter negedge detect enabled</description>
                  <value>#10</value>
                </enumeratedValue>
                <enumeratedValue>
                  <name>11</name>
                  <description>Filter any edge detect enabled</description>
                  <value>#11</value>
                </enumeratedValue>
              </enumeratedValues>
            </field>
            <field>
              <name>FILTF</name>
              <description>Filter Detect Flag</description>
              <bitOffset>7</bitOffset>
              <bitWidth>1</bitWidth>
              <access>read-write</access>
              <enumeratedValues>
                <enumeratedValue>
                  <name>0</name>
                  <description>Pin Filter 2 was not a wakeup source</description>
                  <value>#0</value>
                </enumeratedValue>
                <enumeratedValue>
                  <name>1</name>
                  <description>Pin Filter 2 was a wakeup source</description>
                  <value>#1</value>
                </enumeratedValue>
              </enumeratedValues>
            </field>
          </fields>
        </register>
      </registers>
    </peripheral>
    <peripheral>
      <name>PMC</name>
      <description>Power Management Controller</description>
      <prependToName>PMC_</prependToName>
      <baseAddress>0x4007D000</baseAddress>
      <addressBlock>
        <offset>0</offset>
        <size>0x3</size>
        <usage>registers</usage>
      </addressBlock>
      <interrupt>
        <name>LVD_LVW</name>
        <value>6</value>
      </interrupt>
      <registers>
        <register>
          <name>LVDSC1</name>
          <description>Low Voltage Detect Status And Control 1 register</description>
          <addressOffset>0</addressOffset>
          <size>8</size>
          <access>read-write</access>
          <resetValue>0x10</resetValue>
          <resetMask>0xFF</resetMask>
          <fields>
            <field>
              <name>LVDV</name>
              <description>Low-Voltage Detect Voltage Select</description>
              <bitOffset>0</bitOffset>
              <bitWidth>2</bitWidth>
              <access>read-write</access>
              <enumeratedValues>
                <enumeratedValue>
                  <name>00</name>
                  <description>Low trip point selected (V LVD = V LVDL )</description>
                  <value>#00</value>
                </enumeratedValue>
                <enumeratedValue>
                  <name>01</name>
                  <description>High trip point selected (V LVD = V LVDH )</description>
                  <value>#01</value>
                </enumeratedValue>
              </enumeratedValues>
            </field>
            <field>
              <name>LVDRE</name>
              <description>Low-Voltage Detect Reset Enable</description>
              <bitOffset>4</bitOffset>
              <bitWidth>1</bitWidth>
              <access>read-write</access>
              <enumeratedValues>
                <enumeratedValue>
                  <name>0</name>
                  <description>LVDF does not generate hardware resets</description>
                  <value>#0</value>
                </enumeratedValue>
                <enumeratedValue>
                  <name>1</name>
                  <description>Force an MCU reset when LVDF = 1</description>
                  <value>#1</value>
                </enumeratedValue>
              </enumeratedValues>
            </field>
            <field>
              <name>LVDIE</name>
              <description>Low-Voltage Detect Interrupt Enable</description>
              <bitOffset>5</bitOffset>
              <bitWidth>1</bitWidth>
              <access>read-write</access>
              <enumeratedValues>
                <enumeratedValue>
                  <name>0</name>
                  <description>Hardware interrupt disabled (use polling)</description>
                  <value>#0</value>
                </enumeratedValue>
                <enumeratedValue>
                  <name>1</name>
                  <description>Request a hardware interrupt when LVDF = 1</description>
                  <value>#1</value>
                </enumeratedValue>
              </enumeratedValues>
            </field>
            <field>
              <name>LVDACK</name>
              <description>Low-Voltage Detect Acknowledge</description>
              <bitOffset>6</bitOffset>
              <bitWidth>1</bitWidth>
              <access>write-only</access>
            </field>
            <field>
              <name>LVDF</name>
              <description>Low-Voltage Detect Flag</description>
              <bitOffset>7</bitOffset>
              <bitWidth>1</bitWidth>
              <access>read-only</access>
              <enumeratedValues>
                <enumeratedValue>
                  <name>0</name>
                  <description>Low-voltage event not detected</description>
                  <value>#0</value>
                </enumeratedValue>
                <enumeratedValue>
                  <name>1</name>
                  <description>Low-voltage event detected</description>
                  <value>#1</value>
                </enumeratedValue>
              </enumeratedValues>
            </field>
          </fields>
        </register>
        <register>
          <name>LVDSC2</name>
          <description>Low Voltage Detect Status And Control 2 register</description>
          <addressOffset>0x1</addressOffset>
          <size>8</size>
          <access>read-write</access>
          <resetValue>0</resetValue>
          <resetMask>0xFF</resetMask>
          <fields>
            <field>
              <name>LVWV</name>
              <description>Low-Voltage Warning Voltage Select</description>
              <bitOffset>0</bitOffset>
              <bitWidth>2</bitWidth>
              <access>read-write</access>
              <enumeratedValues>
                <enumeratedValue>
                  <name>00</name>
                  <description>Low trip point selected (VLVW = VLVW1)</description>
                  <value>#00</value>
                </enumeratedValue>
                <enumeratedValue>
                  <name>01</name>
                  <description>Mid 1 trip point selected (VLVW = VLVW2)</description>
                  <value>#01</value>
                </enumeratedValue>
                <enumeratedValue>
                  <name>10</name>
                  <description>Mid 2 trip point selected (VLVW = VLVW3)</description>
                  <value>#10</value>
                </enumeratedValue>
                <enumeratedValue>
                  <name>11</name>
                  <description>High trip point selected (VLVW = VLVW4)</description>
                  <value>#11</value>
                </enumeratedValue>
              </enumeratedValues>
            </field>
            <field>
              <name>LVWIE</name>
              <description>Low-Voltage Warning Interrupt Enable</description>
              <bitOffset>5</bitOffset>
              <bitWidth>1</bitWidth>
              <access>read-write</access>
              <enumeratedValues>
                <enumeratedValue>
                  <name>0</name>
                  <description>Hardware interrupt disabled (use polling)</description>
                  <value>#0</value>
                </enumeratedValue>
                <enumeratedValue>
                  <name>1</name>
                  <description>Request a hardware interrupt when LVWF = 1</description>
                  <value>#1</value>
                </enumeratedValue>
              </enumeratedValues>
            </field>
            <field>
              <name>LVWACK</name>
              <description>Low-Voltage Warning Acknowledge</description>
              <bitOffset>6</bitOffset>
              <bitWidth>1</bitWidth>
              <access>write-only</access>
            </field>
            <field>
              <name>LVWF</name>
              <description>Low-Voltage Warning Flag</description>
              <bitOffset>7</bitOffset>
              <bitWidth>1</bitWidth>
              <access>read-only</access>
              <enumeratedValues>
                <enumeratedValue>
                  <name>0</name>
                  <description>Low-voltage warning event not detected</description>
                  <value>#0</value>
                </enumeratedValue>
                <enumeratedValue>
                  <name>1</name>
                  <description>Low-voltage warning event detected</description>
                  <value>#1</value>
                </enumeratedValue>
              </enumeratedValues>
            </field>
          </fields>
        </register>
        <register>
          <name>REGSC</name>
          <description>Regulator Status And Control register</description>
          <addressOffset>0x2</addressOffset>
          <size>8</size>
          <access>read-write</access>
          <resetValue>0x4</resetValue>
          <resetMask>0xFF</resetMask>
          <fields>
            <field>
              <name>BGBE</name>
              <description>Bandgap Buffer Enable</description>
              <bitOffset>0</bitOffset>
              <bitWidth>1</bitWidth>
              <access>read-write</access>
              <enumeratedValues>
                <enumeratedValue>
                  <name>0</name>
                  <description>Bandgap buffer not enabled</description>
                  <value>#0</value>
                </enumeratedValue>
                <enumeratedValue>
                  <name>1</name>
                  <description>Bandgap buffer enabled</description>
                  <value>#1</value>
                </enumeratedValue>
              </enumeratedValues>
            </field>
            <field>
              <name>REGONS</name>
              <description>Regulator In Run Regulation Status</description>
              <bitOffset>2</bitOffset>
              <bitWidth>1</bitWidth>
              <access>read-only</access>
              <enumeratedValues>
                <enumeratedValue>
                  <name>0</name>
                  <description>Regulator is in stop regulation or in transition to/from it</description>
                  <value>#0</value>
                </enumeratedValue>
                <enumeratedValue>
                  <name>1</name>
                  <description>Regulator is in run regulation</description>
                  <value>#1</value>
                </enumeratedValue>
              </enumeratedValues>
            </field>
            <field>
              <name>ACKISO</name>
              <description>Acknowledge Isolation</description>
              <bitOffset>3</bitOffset>
              <bitWidth>1</bitWidth>
              <access>read-write</access>
              <enumeratedValues>
                <enumeratedValue>
                  <name>0</name>
                  <description>Peripherals and I/O pads are in normal run state.</description>
                  <value>#0</value>
                </enumeratedValue>
                <enumeratedValue>
                  <name>1</name>
                  <description>Certain peripherals and I/O pads are in an isolated and latched state.</description>
                  <value>#1</value>
                </enumeratedValue>
              </enumeratedValues>
            </field>
            <field>
              <name>BGEN</name>
              <description>Bandgap Enable In VLPx Operation</description>
              <bitOffset>4</bitOffset>
              <bitWidth>1</bitWidth>
              <access>read-write</access>
              <enumeratedValues>
                <enumeratedValue>
                  <name>0</name>
                  <description>Bandgap voltage reference is disabled in VLPx , LLS , and VLLSx modes.</description>
                  <value>#0</value>
                </enumeratedValue>
                <enumeratedValue>
                  <name>1</name>
                  <description>Bandgap voltage reference is enabled in VLPx , LLS , and VLLSx modes.</description>
                  <value>#1</value>
                </enumeratedValue>
              </enumeratedValues>
            </field>
          </fields>
        </register>
      </registers>
    </peripheral>
    <peripheral>
      <name>SMC</name>
      <description>System Mode Controller</description>
      <prependToName>SMC_</prependToName>
      <baseAddress>0x4007E000</baseAddress>
      <addressBlock>
        <offset>0</offset>
        <size>0x4</size>
        <usage>registers</usage>
      </addressBlock>
      <registers>
        <register>
          <name>PMPROT</name>
          <description>Power Mode Protection register</description>
          <addressOffset>0</addressOffset>
          <size>8</size>
          <access>read-write</access>
          <resetValue>0</resetValue>
          <resetMask>0xFF</resetMask>
          <fields>
            <field>
              <name>AVLLS</name>
              <description>Allow Very-Low-Leakage Stop Mode</description>
              <bitOffset>1</bitOffset>
              <bitWidth>1</bitWidth>
              <access>read-write</access>
              <enumeratedValues>
                <enumeratedValue>
                  <name>0</name>
                  <description>Any VLLSx mode is not allowed</description>
                  <value>#0</value>
                </enumeratedValue>
                <enumeratedValue>
                  <name>1</name>
                  <description>Any VLLSx mode is allowed</description>
                  <value>#1</value>
                </enumeratedValue>
              </enumeratedValues>
            </field>
            <field>
              <name>ALLS</name>
              <description>Allow Low-Leakage Stop Mode</description>
              <bitOffset>3</bitOffset>
              <bitWidth>1</bitWidth>
              <access>read-write</access>
              <enumeratedValues>
                <enumeratedValue>
                  <name>0</name>
                  <description>LLS is not allowed</description>
                  <value>#0</value>
                </enumeratedValue>
                <enumeratedValue>
                  <name>1</name>
                  <description>LLS is allowed</description>
                  <value>#1</value>
                </enumeratedValue>
              </enumeratedValues>
            </field>
            <field>
              <name>AVLP</name>
              <description>Allow Very-Low-Power Modes</description>
              <bitOffset>5</bitOffset>
              <bitWidth>1</bitWidth>
              <access>read-write</access>
              <enumeratedValues>
                <enumeratedValue>
                  <name>0</name>
                  <description>VLPR, VLPW, and VLPS are not allowed.</description>
                  <value>#0</value>
                </enumeratedValue>
                <enumeratedValue>
                  <name>1</name>
                  <description>VLPR, VLPW, and VLPS are allowed.</description>
                  <value>#1</value>
                </enumeratedValue>
              </enumeratedValues>
            </field>
          </fields>
        </register>
        <register>
          <name>PMCTRL</name>
          <description>Power Mode Control register</description>
          <addressOffset>0x1</addressOffset>
          <size>8</size>
          <access>read-write</access>
          <resetValue>0</resetValue>
          <resetMask>0xFF</resetMask>
          <fields>
            <field>
              <name>STOPM</name>
              <description>Stop Mode Control</description>
              <bitOffset>0</bitOffset>
              <bitWidth>3</bitWidth>
              <access>read-write</access>
              <enumeratedValues>
                <enumeratedValue>
                  <name>000</name>
                  <description>Normal Stop (STOP)</description>
                  <value>#000</value>
                </enumeratedValue>
                <enumeratedValue>
                  <name>010</name>
                  <description>Very-Low-Power Stop (VLPS)</description>
                  <value>#010</value>
                </enumeratedValue>
                <enumeratedValue>
                  <name>011</name>
                  <description>Low-Leakage Stop (LLS)</description>
                  <value>#011</value>
                </enumeratedValue>
                <enumeratedValue>
                  <name>100</name>
                  <description>Very-Low-Leakage Stop (VLLSx)</description>
                  <value>#100</value>
                </enumeratedValue>
                <enumeratedValue>
                  <name>110</name>
                  <description>Reseved</description>
                  <value>#110</value>
                </enumeratedValue>
              </enumeratedValues>
            </field>
            <field>
              <name>STOPA</name>
              <description>Stop Aborted</description>
              <bitOffset>3</bitOffset>
              <bitWidth>1</bitWidth>
              <access>read-only</access>
              <enumeratedValues>
                <enumeratedValue>
                  <name>0</name>
                  <description>The previous stop mode entry was successsful.</description>
                  <value>#0</value>
                </enumeratedValue>
                <enumeratedValue>
                  <name>1</name>
                  <description>The previous stop mode entry was aborted.</description>
                  <value>#1</value>
                </enumeratedValue>
              </enumeratedValues>
            </field>
            <field>
              <name>RUNM</name>
              <description>Run Mode Control</description>
              <bitOffset>5</bitOffset>
              <bitWidth>2</bitWidth>
              <access>read-write</access>
              <enumeratedValues>
                <enumeratedValue>
                  <name>00</name>
                  <description>Normal Run mode (RUN)</description>
                  <value>#00</value>
                </enumeratedValue>
                <enumeratedValue>
                  <name>10</name>
                  <description>Very-Low-Power Run mode (VLPR)</description>
                  <value>#10</value>
                </enumeratedValue>
              </enumeratedValues>
            </field>
          </fields>
        </register>
        <register>
          <name>STOPCTRL</name>
          <description>Stop Control Register</description>
          <addressOffset>0x2</addressOffset>
          <size>8</size>
          <access>read-write</access>
          <resetValue>0x3</resetValue>
          <resetMask>0xFF</resetMask>
          <fields>
            <field>
              <name>VLLSM</name>
              <description>VLLS Mode Control</description>
              <bitOffset>0</bitOffset>
              <bitWidth>3</bitWidth>
              <access>read-write</access>
              <enumeratedValues>
                <enumeratedValue>
                  <name>000</name>
                  <description>VLLS0</description>
                  <value>#000</value>
                </enumeratedValue>
                <enumeratedValue>
                  <name>001</name>
                  <description>VLLS1</description>
                  <value>#001</value>
                </enumeratedValue>
                <enumeratedValue>
                  <name>011</name>
                  <description>VLLS3</description>
                  <value>#011</value>
                </enumeratedValue>
              </enumeratedValues>
            </field>
            <field>
              <name>PORPO</name>
              <description>POR Power Option</description>
              <bitOffset>5</bitOffset>
              <bitWidth>1</bitWidth>
              <access>read-write</access>
              <enumeratedValues>
                <enumeratedValue>
                  <name>0</name>
                  <description>POR detect circuit is enabled in VLLS0</description>
                  <value>#0</value>
                </enumeratedValue>
                <enumeratedValue>
                  <name>1</name>
                  <description>POR detect circuit is disabled in VLLS0</description>
                  <value>#1</value>
                </enumeratedValue>
              </enumeratedValues>
            </field>
            <field>
              <name>PSTOPO</name>
              <description>Partial Stop Option</description>
              <bitOffset>6</bitOffset>
              <bitWidth>2</bitWidth>
              <access>read-write</access>
              <enumeratedValues>
                <enumeratedValue>
                  <name>00</name>
                  <description>STOP - Normal Stop mode</description>
                  <value>#00</value>
                </enumeratedValue>
                <enumeratedValue>
                  <name>01</name>
                  <description>PSTOP1 - Partial Stop with both system and bus clocks disabled</description>
                  <value>#01</value>
                </enumeratedValue>
                <enumeratedValue>
                  <name>10</name>
                  <description>PSTOP2 - Partial Stop with system clock disabled and bus clock enabled</description>
                  <value>#10</value>
                </enumeratedValue>
              </enumeratedValues>
            </field>
          </fields>
        </register>
        <register>
          <name>PMSTAT</name>
          <description>Power Mode Status register</description>
          <addressOffset>0x3</addressOffset>
          <size>8</size>
          <access>read-only</access>
          <resetValue>0x1</resetValue>
          <resetMask>0xFF</resetMask>
          <fields>
            <field>
              <name>PMSTAT</name>
              <description>When debug is enabled, the PMSTAT will not update to STOP or VLPS When a PSTOP mode is enabled, the PMSTAT will not update to STOP or VLPS</description>
              <bitOffset>0</bitOffset>
              <bitWidth>7</bitWidth>
              <access>read-only</access>
            </field>
          </fields>
        </register>
      </registers>
    </peripheral>
    <peripheral>
      <name>RCM</name>
      <description>Reset Control Module</description>
      <prependToName>RCM_</prependToName>
      <baseAddress>0x4007F000</baseAddress>
      <addressBlock>
        <offset>0</offset>
        <size>0x6</size>
        <usage>registers</usage>
      </addressBlock>
      <registers>
        <register>
          <name>SRS0</name>
          <description>System Reset Status Register 0</description>
          <addressOffset>0</addressOffset>
          <size>8</size>
          <access>read-only</access>
          <resetValue>0x82</resetValue>
          <resetMask>0xFF</resetMask>
          <fields>
            <field>
              <name>WAKEUP</name>
              <description>Low Leakage Wakeup Reset</description>
              <bitOffset>0</bitOffset>
              <bitWidth>1</bitWidth>
              <access>read-only</access>
              <enumeratedValues>
                <enumeratedValue>
                  <name>0</name>
                  <description>Reset not caused by LLWU module wakeup source</description>
                  <value>#0</value>
                </enumeratedValue>
                <enumeratedValue>
                  <name>1</name>
                  <description>Reset caused by LLWU module wakeup source</description>
                  <value>#1</value>
                </enumeratedValue>
              </enumeratedValues>
            </field>
            <field>
              <name>LVD</name>
              <description>Low-Voltage Detect Reset</description>
              <bitOffset>1</bitOffset>
              <bitWidth>1</bitWidth>
              <access>read-only</access>
              <enumeratedValues>
                <enumeratedValue>
                  <name>0</name>
                  <description>Reset not caused by LVD trip or POR</description>
                  <value>#0</value>
                </enumeratedValue>
                <enumeratedValue>
                  <name>1</name>
                  <description>Reset caused by LVD trip or POR</description>
                  <value>#1</value>
                </enumeratedValue>
              </enumeratedValues>
            </field>
            <field>
              <name>LOC</name>
              <description>Loss-of-Clock Reset</description>
              <bitOffset>2</bitOffset>
              <bitWidth>1</bitWidth>
              <access>read-only</access>
              <enumeratedValues>
                <enumeratedValue>
                  <name>0</name>
                  <description>Reset not caused by a loss of external clock.</description>
                  <value>#0</value>
                </enumeratedValue>
                <enumeratedValue>
                  <name>1</name>
                  <description>Reset caused by a loss of external clock.</description>
                  <value>#1</value>
                </enumeratedValue>
              </enumeratedValues>
            </field>
            <field>
              <name>LOL</name>
              <description>Loss-of-Lock Reset</description>
              <bitOffset>3</bitOffset>
              <bitWidth>1</bitWidth>
              <access>read-only</access>
              <enumeratedValues>
                <enumeratedValue>
                  <name>0</name>
                  <description>Reset not caused by a loss of lock in the PLL</description>
                  <value>#0</value>
                </enumeratedValue>
                <enumeratedValue>
                  <name>1</name>
                  <description>Reset caused by a loss of lock in the PLL</description>
                  <value>#1</value>
                </enumeratedValue>
              </enumeratedValues>
            </field>
            <field>
              <name>WDOG</name>
              <description>Watchdog</description>
              <bitOffset>5</bitOffset>
              <bitWidth>1</bitWidth>
              <access>read-only</access>
              <enumeratedValues>
                <enumeratedValue>
                  <name>0</name>
                  <description>Reset not caused by watchdog timeout</description>
                  <value>#0</value>
                </enumeratedValue>
                <enumeratedValue>
                  <name>1</name>
                  <description>Reset caused by watchdog timeout</description>
                  <value>#1</value>
                </enumeratedValue>
              </enumeratedValues>
            </field>
            <field>
              <name>PIN</name>
              <description>External Reset Pin</description>
              <bitOffset>6</bitOffset>
              <bitWidth>1</bitWidth>
              <access>read-only</access>
              <enumeratedValues>
                <enumeratedValue>
                  <name>0</name>
                  <description>Reset not caused by external reset pin</description>
                  <value>#0</value>
                </enumeratedValue>
                <enumeratedValue>
                  <name>1</name>
                  <description>Reset caused by external reset pin</description>
                  <value>#1</value>
                </enumeratedValue>
              </enumeratedValues>
            </field>
            <field>
              <name>POR</name>
              <description>Power-On Reset</description>
              <bitOffset>7</bitOffset>
              <bitWidth>1</bitWidth>
              <access>read-only</access>
              <enumeratedValues>
                <enumeratedValue>
                  <name>0</name>
                  <description>Reset not caused by POR</description>
                  <value>#0</value>
                </enumeratedValue>
                <enumeratedValue>
                  <name>1</name>
                  <description>Reset caused by POR</description>
                  <value>#1</value>
                </enumeratedValue>
              </enumeratedValues>
            </field>
          </fields>
        </register>
        <register>
          <name>SRS1</name>
          <description>System Reset Status Register 1</description>
          <addressOffset>0x1</addressOffset>
          <size>8</size>
          <access>read-only</access>
          <resetValue>0</resetValue>
          <resetMask>0xFF</resetMask>
          <fields>
            <field>
              <name>LOCKUP</name>
              <description>Core Lockup</description>
              <bitOffset>1</bitOffset>
              <bitWidth>1</bitWidth>
              <access>read-only</access>
              <enumeratedValues>
                <enumeratedValue>
                  <name>0</name>
                  <description>Reset not caused by core LOCKUP event</description>
                  <value>#0</value>
                </enumeratedValue>
                <enumeratedValue>
                  <name>1</name>
                  <description>Reset caused by core LOCKUP event</description>
                  <value>#1</value>
                </enumeratedValue>
              </enumeratedValues>
            </field>
            <field>
              <name>SW</name>
              <description>Software</description>
              <bitOffset>2</bitOffset>
              <bitWidth>1</bitWidth>
              <access>read-only</access>
              <enumeratedValues>
                <enumeratedValue>
                  <name>0</name>
                  <description>Reset not caused by software setting of SYSRESETREQ bit</description>
                  <value>#0</value>
                </enumeratedValue>
                <enumeratedValue>
                  <name>1</name>
                  <description>Reset caused by software setting of SYSRESETREQ bit</description>
                  <value>#1</value>
                </enumeratedValue>
              </enumeratedValues>
            </field>
            <field>
              <name>MDM_AP</name>
              <description>MDM-AP System Reset Request</description>
              <bitOffset>3</bitOffset>
              <bitWidth>1</bitWidth>
              <access>read-only</access>
              <enumeratedValues>
                <enumeratedValue>
                  <name>0</name>
                  <description>Reset not caused by host debugger system setting of the System Reset Request bit</description>
                  <value>#0</value>
                </enumeratedValue>
                <enumeratedValue>
                  <name>1</name>
                  <description>Reset caused by host debugger system setting of the System Reset Request bit</description>
                  <value>#1</value>
                </enumeratedValue>
              </enumeratedValues>
            </field>
            <field>
              <name>SACKERR</name>
              <description>Stop Mode Acknowledge Error Reset</description>
              <bitOffset>5</bitOffset>
              <bitWidth>1</bitWidth>
              <access>read-only</access>
              <enumeratedValues>
                <enumeratedValue>
                  <name>0</name>
                  <description>Reset not caused by peripheral failure to acknowledge attempt to enter stop mode</description>
                  <value>#0</value>
                </enumeratedValue>
                <enumeratedValue>
                  <name>1</name>
                  <description>Reset caused by peripheral failure to acknowledge attempt to enter stop mode</description>
                  <value>#1</value>
                </enumeratedValue>
              </enumeratedValues>
            </field>
          </fields>
        </register>
        <register>
          <name>RPFC</name>
          <description>Reset Pin Filter Control register</description>
          <addressOffset>0x4</addressOffset>
          <size>8</size>
          <access>read-write</access>
          <resetValue>0</resetValue>
          <resetMask>0xFF</resetMask>
          <fields>
            <field>
              <name>RSTFLTSRW</name>
              <description>Reset Pin Filter Select in Run and Wait Modes</description>
              <bitOffset>0</bitOffset>
              <bitWidth>2</bitWidth>
              <access>read-write</access>
              <enumeratedValues>
                <enumeratedValue>
                  <name>00</name>
                  <description>All filtering disabled</description>
                  <value>#00</value>
                </enumeratedValue>
                <enumeratedValue>
                  <name>01</name>
                  <description>Bus clock filter enabled for normal operation</description>
                  <value>#01</value>
                </enumeratedValue>
                <enumeratedValue>
                  <name>10</name>
                  <description>LPO clock filter enabled for normal operation</description>
                  <value>#10</value>
                </enumeratedValue>
              </enumeratedValues>
            </field>
            <field>
              <name>RSTFLTSS</name>
              <description>Reset Pin Filter Select in Stop Mode</description>
              <bitOffset>2</bitOffset>
              <bitWidth>1</bitWidth>
              <access>read-write</access>
              <enumeratedValues>
                <enumeratedValue>
                  <name>0</name>
                  <description>All filtering disabled</description>
                  <value>#0</value>
                </enumeratedValue>
                <enumeratedValue>
                  <name>1</name>
                  <description>LPO clock filter enabled</description>
                  <value>#1</value>
                </enumeratedValue>
              </enumeratedValues>
            </field>
          </fields>
        </register>
        <register>
          <name>RPFW</name>
          <description>Reset Pin Filter Width register</description>
          <addressOffset>0x5</addressOffset>
          <size>8</size>
          <access>read-write</access>
          <resetValue>0</resetValue>
          <resetMask>0xFF</resetMask>
          <fields>
            <field>
              <name>RSTFLTSEL</name>
              <description>Reset Pin Filter Bus Clock Select</description>
              <bitOffset>0</bitOffset>
              <bitWidth>5</bitWidth>
              <access>read-write</access>
              <enumeratedValues>
                <enumeratedValue>
                  <name>00000</name>
                  <description>Bus clock filter count is 1</description>
                  <value>#00000</value>
                </enumeratedValue>
                <enumeratedValue>
                  <name>00001</name>
                  <description>Bus clock filter count is 2</description>
                  <value>#00001</value>
                </enumeratedValue>
                <enumeratedValue>
                  <name>00010</name>
                  <description>Bus clock filter count is 3</description>
                  <value>#00010</value>
                </enumeratedValue>
                <enumeratedValue>
                  <name>00011</name>
                  <description>Bus clock filter count is 4</description>
                  <value>#00011</value>
                </enumeratedValue>
                <enumeratedValue>
                  <name>00100</name>
                  <description>Bus clock filter count is 5</description>
                  <value>#00100</value>
                </enumeratedValue>
                <enumeratedValue>
                  <name>00101</name>
                  <description>Bus clock filter count is 6</description>
                  <value>#00101</value>
                </enumeratedValue>
                <enumeratedValue>
                  <name>00110</name>
                  <description>Bus clock filter count is 7</description>
                  <value>#00110</value>
                </enumeratedValue>
                <enumeratedValue>
                  <name>00111</name>
                  <description>Bus clock filter count is 8</description>
                  <value>#00111</value>
                </enumeratedValue>
                <enumeratedValue>
                  <name>01000</name>
                  <description>Bus clock filter count is 9</description>
                  <value>#01000</value>
                </enumeratedValue>
                <enumeratedValue>
                  <name>01001</name>
                  <description>Bus clock filter count is 10</description>
                  <value>#01001</value>
                </enumeratedValue>
                <enumeratedValue>
                  <name>01010</name>
                  <description>Bus clock filter count is 11</description>
                  <value>#01010</value>
                </enumeratedValue>
                <enumeratedValue>
                  <name>01011</name>
                  <description>Bus clock filter count is 12</description>
                  <value>#01011</value>
                </enumeratedValue>
                <enumeratedValue>
                  <name>01100</name>
                  <description>Bus clock filter count is 13</description>
                  <value>#01100</value>
                </enumeratedValue>
                <enumeratedValue>
                  <name>01101</name>
                  <description>Bus clock filter count is 14</description>
                  <value>#01101</value>
                </enumeratedValue>
                <enumeratedValue>
                  <name>01110</name>
                  <description>Bus clock filter count is 15</description>
                  <value>#01110</value>
                </enumeratedValue>
                <enumeratedValue>
                  <name>01111</name>
                  <description>Bus clock filter count is 16</description>
                  <value>#01111</value>
                </enumeratedValue>
                <enumeratedValue>
                  <name>10000</name>
                  <description>Bus clock filter count is 17</description>
                  <value>#10000</value>
                </enumeratedValue>
                <enumeratedValue>
                  <name>10001</name>
                  <description>Bus clock filter count is 18</description>
                  <value>#10001</value>
                </enumeratedValue>
                <enumeratedValue>
                  <name>10010</name>
                  <description>Bus clock filter count is 19</description>
                  <value>#10010</value>
                </enumeratedValue>
                <enumeratedValue>
                  <name>10011</name>
                  <description>Bus clock filter count is 20</description>
                  <value>#10011</value>
                </enumeratedValue>
                <enumeratedValue>
                  <name>10100</name>
                  <description>Bus clock filter count is 21</description>
                  <value>#10100</value>
                </enumeratedValue>
                <enumeratedValue>
                  <name>10101</name>
                  <description>Bus clock filter count is 22</description>
                  <value>#10101</value>
                </enumeratedValue>
                <enumeratedValue>
                  <name>10110</name>
                  <description>Bus clock filter count is 23</description>
                  <value>#10110</value>
                </enumeratedValue>
                <enumeratedValue>
                  <name>10111</name>
                  <description>Bus clock filter count is 24</description>
                  <value>#10111</value>
                </enumeratedValue>
                <enumeratedValue>
                  <name>11000</name>
                  <description>Bus clock filter count is 25</description>
                  <value>#11000</value>
                </enumeratedValue>
                <enumeratedValue>
                  <name>11001</name>
                  <description>Bus clock filter count is 26</description>
                  <value>#11001</value>
                </enumeratedValue>
                <enumeratedValue>
                  <name>11010</name>
                  <description>Bus clock filter count is 27</description>
                  <value>#11010</value>
                </enumeratedValue>
                <enumeratedValue>
                  <name>11011</name>
                  <description>Bus clock filter count is 28</description>
                  <value>#11011</value>
                </enumeratedValue>
                <enumeratedValue>
                  <name>11100</name>
                  <description>Bus clock filter count is 29</description>
                  <value>#11100</value>
                </enumeratedValue>
                <enumeratedValue>
                  <name>11101</name>
                  <description>Bus clock filter count is 30</description>
                  <value>#11101</value>
                </enumeratedValue>
                <enumeratedValue>
                  <name>11110</name>
                  <description>Bus clock filter count is 31</description>
                  <value>#11110</value>
                </enumeratedValue>
                <enumeratedValue>
                  <name>11111</name>
                  <description>Bus clock filter count is 32</description>
                  <value>#11111</value>
                </enumeratedValue>
              </enumeratedValues>
            </field>
          </fields>
        </register>
      </registers>
    </peripheral>
    <peripheral>
      <name>GPIOA</name>
      <description>General Purpose Input/Output</description>
      <groupName>GPIO</groupName>
      <prependToName>GPIOA_</prependToName>
      <baseAddress>0x400FF000</baseAddress>
      <addressBlock>
        <offset>0</offset>
        <size>0x18</size>
        <usage>registers</usage>
      </addressBlock>
      <interrupt>
        <name>PORTA</name>
        <value>30</value>
      </interrupt>
      <registers>
        <register>
          <name>PDOR</name>
          <description>Port Data Output Register</description>
          <addressOffset>0</addressOffset>
          <size>32</size>
          <access>read-write</access>
          <resetValue>0</resetValue>
          <resetMask>0xFFFFFFFF</resetMask>
          <fields>
            <field>
              <name>PDO</name>
              <description>Port Data Output</description>
              <bitOffset>0</bitOffset>
              <bitWidth>32</bitWidth>
              <access>read-write</access>
              <enumeratedValues>
                <enumeratedValue>
                  <name>0</name>
                  <description>Logic level 0 is driven on pin, provided pin is configured for general-purpose output.</description>
                  <value>#0</value>
                </enumeratedValue>
                <enumeratedValue>
                  <name>1</name>
                  <description>Logic level 1 is driven on pin, provided pin is configured for general-purpose output.</description>
                  <value>#1</value>
                </enumeratedValue>
              </enumeratedValues>
            </field>
          </fields>
        </register>
        <register>
          <name>PSOR</name>
          <description>Port Set Output Register</description>
          <addressOffset>0x4</addressOffset>
          <size>32</size>
          <access>write-only</access>
          <resetValue>0</resetValue>
          <resetMask>0xFFFFFFFF</resetMask>
          <fields>
            <field>
              <name>PTSO</name>
              <description>Port Set Output</description>
              <bitOffset>0</bitOffset>
              <bitWidth>32</bitWidth>
              <access>write-only</access>
              <enumeratedValues>
                <enumeratedValue>
                  <name>0</name>
                  <description>Corresponding bit in PDORn does not change.</description>
                  <value>#0</value>
                </enumeratedValue>
                <enumeratedValue>
                  <name>1</name>
                  <description>Corresponding bit in PDORn is set to logic 1.</description>
                  <value>#1</value>
                </enumeratedValue>
              </enumeratedValues>
            </field>
          </fields>
        </register>
        <register>
          <name>PCOR</name>
          <description>Port Clear Output Register</description>
          <addressOffset>0x8</addressOffset>
          <size>32</size>
          <access>write-only</access>
          <resetValue>0</resetValue>
          <resetMask>0xFFFFFFFF</resetMask>
          <fields>
            <field>
              <name>PTCO</name>
              <description>Port Clear Output</description>
              <bitOffset>0</bitOffset>
              <bitWidth>32</bitWidth>
              <access>write-only</access>
              <enumeratedValues>
                <enumeratedValue>
                  <name>0</name>
                  <description>Corresponding bit in PDORn does not change.</description>
                  <value>#0</value>
                </enumeratedValue>
                <enumeratedValue>
                  <name>1</name>
                  <description>Corresponding bit in PDORn is cleared to logic 0.</description>
                  <value>#1</value>
                </enumeratedValue>
              </enumeratedValues>
            </field>
          </fields>
        </register>
        <register>
          <name>PTOR</name>
          <description>Port Toggle Output Register</description>
          <addressOffset>0xC</addressOffset>
          <size>32</size>
          <access>write-only</access>
          <resetValue>0</resetValue>
          <resetMask>0xFFFFFFFF</resetMask>
          <fields>
            <field>
              <name>PTTO</name>
              <description>Port Toggle Output</description>
              <bitOffset>0</bitOffset>
              <bitWidth>32</bitWidth>
              <access>write-only</access>
              <enumeratedValues>
                <enumeratedValue>
                  <name>0</name>
                  <description>Corresponding bit in PDORn does not change.</description>
                  <value>#0</value>
                </enumeratedValue>
                <enumeratedValue>
                  <name>1</name>
                  <description>Corresponding bit in PDORn is set to the inverse of its existing logic state.</description>
                  <value>#1</value>
                </enumeratedValue>
              </enumeratedValues>
            </field>
          </fields>
        </register>
        <register>
          <name>PDIR</name>
          <description>Port Data Input Register</description>
          <addressOffset>0x10</addressOffset>
          <size>32</size>
          <access>read-only</access>
          <resetValue>0</resetValue>
          <resetMask>0xFFFFFFFF</resetMask>
          <fields>
            <field>
              <name>PDI</name>
              <description>Port Data Input</description>
              <bitOffset>0</bitOffset>
              <bitWidth>32</bitWidth>
              <access>read-only</access>
              <enumeratedValues>
                <enumeratedValue>
                  <name>0</name>
                  <description>Pin logic level is logic 0, or is not configured for use by digital function.</description>
                  <value>#0</value>
                </enumeratedValue>
                <enumeratedValue>
                  <name>1</name>
                  <description>Pin logic level is logic 1.</description>
                  <value>#1</value>
                </enumeratedValue>
              </enumeratedValues>
            </field>
          </fields>
        </register>
        <register>
          <name>PDDR</name>
          <description>Port Data Direction Register</description>
          <addressOffset>0x14</addressOffset>
          <size>32</size>
          <access>read-write</access>
          <resetValue>0</resetValue>
          <resetMask>0xFFFFFFFF</resetMask>
          <fields>
            <field>
              <name>PDD</name>
              <description>Port Data Direction</description>
              <bitOffset>0</bitOffset>
              <bitWidth>32</bitWidth>
              <access>read-write</access>
              <enumeratedValues>
                <enumeratedValue>
                  <name>0</name>
                  <description>Pin is configured as general-purpose input, for the GPIO function.</description>
                  <value>#0</value>
                </enumeratedValue>
                <enumeratedValue>
                  <name>1</name>
                  <description>Pin is configured as general-purpose output, for the GPIO function.</description>
                  <value>#1</value>
                </enumeratedValue>
              </enumeratedValues>
            </field>
          </fields>
        </register>
      </registers>
    </peripheral>
    <peripheral>
      <name>GPIOB</name>
      <description>General Purpose Input/Output</description>
      <groupName>GPIO</groupName>
      <prependToName>GPIOB_</prependToName>
      <baseAddress>0x400FF040</baseAddress>
      <addressBlock>
        <offset>0</offset>
        <size>0x18</size>
        <usage>registers</usage>
      </addressBlock>
      <registers>
        <register>
          <name>PDOR</name>
          <description>Port Data Output Register</description>
          <addressOffset>0</addressOffset>
          <size>32</size>
          <access>read-write</access>
          <resetValue>0</resetValue>
          <resetMask>0xFFFFFFFF</resetMask>
          <fields>
            <field>
              <name>PDO</name>
              <description>Port Data Output</description>
              <bitOffset>0</bitOffset>
              <bitWidth>32</bitWidth>
              <access>read-write</access>
              <enumeratedValues>
                <enumeratedValue>
                  <name>0</name>
                  <description>Logic level 0 is driven on pin, provided pin is configured for general-purpose output.</description>
                  <value>#0</value>
                </enumeratedValue>
                <enumeratedValue>
                  <name>1</name>
                  <description>Logic level 1 is driven on pin, provided pin is configured for general-purpose output.</description>
                  <value>#1</value>
                </enumeratedValue>
              </enumeratedValues>
            </field>
          </fields>
        </register>
        <register>
          <name>PSOR</name>
          <description>Port Set Output Register</description>
          <addressOffset>0x4</addressOffset>
          <size>32</size>
          <access>write-only</access>
          <resetValue>0</resetValue>
          <resetMask>0xFFFFFFFF</resetMask>
          <fields>
            <field>
              <name>PTSO</name>
              <description>Port Set Output</description>
              <bitOffset>0</bitOffset>
              <bitWidth>32</bitWidth>
              <access>write-only</access>
              <enumeratedValues>
                <enumeratedValue>
                  <name>0</name>
                  <description>Corresponding bit in PDORn does not change.</description>
                  <value>#0</value>
                </enumeratedValue>
                <enumeratedValue>
                  <name>1</name>
                  <description>Corresponding bit in PDORn is set to logic 1.</description>
                  <value>#1</value>
                </enumeratedValue>
              </enumeratedValues>
            </field>
          </fields>
        </register>
        <register>
          <name>PCOR</name>
          <description>Port Clear Output Register</description>
          <addressOffset>0x8</addressOffset>
          <size>32</size>
          <access>write-only</access>
          <resetValue>0</resetValue>
          <resetMask>0xFFFFFFFF</resetMask>
          <fields>
            <field>
              <name>PTCO</name>
              <description>Port Clear Output</description>
              <bitOffset>0</bitOffset>
              <bitWidth>32</bitWidth>
              <access>write-only</access>
              <enumeratedValues>
                <enumeratedValue>
                  <name>0</name>
                  <description>Corresponding bit in PDORn does not change.</description>
                  <value>#0</value>
                </enumeratedValue>
                <enumeratedValue>
                  <name>1</name>
                  <description>Corresponding bit in PDORn is cleared to logic 0.</description>
                  <value>#1</value>
                </enumeratedValue>
              </enumeratedValues>
            </field>
          </fields>
        </register>
        <register>
          <name>PTOR</name>
          <description>Port Toggle Output Register</description>
          <addressOffset>0xC</addressOffset>
          <size>32</size>
          <access>write-only</access>
          <resetValue>0</resetValue>
          <resetMask>0xFFFFFFFF</resetMask>
          <fields>
            <field>
              <name>PTTO</name>
              <description>Port Toggle Output</description>
              <bitOffset>0</bitOffset>
              <bitWidth>32</bitWidth>
              <access>write-only</access>
              <enumeratedValues>
                <enumeratedValue>
                  <name>0</name>
                  <description>Corresponding bit in PDORn does not change.</description>
                  <value>#0</value>
                </enumeratedValue>
                <enumeratedValue>
                  <name>1</name>
                  <description>Corresponding bit in PDORn is set to the inverse of its existing logic state.</description>
                  <value>#1</value>
                </enumeratedValue>
              </enumeratedValues>
            </field>
          </fields>
        </register>
        <register>
          <name>PDIR</name>
          <description>Port Data Input Register</description>
          <addressOffset>0x10</addressOffset>
          <size>32</size>
          <access>read-only</access>
          <resetValue>0</resetValue>
          <resetMask>0xFFFFFFFF</resetMask>
          <fields>
            <field>
              <name>PDI</name>
              <description>Port Data Input</description>
              <bitOffset>0</bitOffset>
              <bitWidth>32</bitWidth>
              <access>read-only</access>
              <enumeratedValues>
                <enumeratedValue>
                  <name>0</name>
                  <description>Pin logic level is logic 0, or is not configured for use by digital function.</description>
                  <value>#0</value>
                </enumeratedValue>
                <enumeratedValue>
                  <name>1</name>
                  <description>Pin logic level is logic 1.</description>
                  <value>#1</value>
                </enumeratedValue>
              </enumeratedValues>
            </field>
          </fields>
        </register>
        <register>
          <name>PDDR</name>
          <description>Port Data Direction Register</description>
          <addressOffset>0x14</addressOffset>
          <size>32</size>
          <access>read-write</access>
          <resetValue>0</resetValue>
          <resetMask>0xFFFFFFFF</resetMask>
          <fields>
            <field>
              <name>PDD</name>
              <description>Port Data Direction</description>
              <bitOffset>0</bitOffset>
              <bitWidth>32</bitWidth>
              <access>read-write</access>
              <enumeratedValues>
                <enumeratedValue>
                  <name>0</name>
                  <description>Pin is configured as general-purpose input, for the GPIO function.</description>
                  <value>#0</value>
                </enumeratedValue>
                <enumeratedValue>
                  <name>1</name>
                  <description>Pin is configured as general-purpose output, for the GPIO function.</description>
                  <value>#1</value>
                </enumeratedValue>
              </enumeratedValues>
            </field>
          </fields>
        </register>
      </registers>
    </peripheral>
    <peripheral>
      <name>GPIOC</name>
      <description>General Purpose Input/Output</description>
      <groupName>GPIO</groupName>
      <prependToName>GPIOC_</prependToName>
      <baseAddress>0x400FF080</baseAddress>
      <addressBlock>
        <offset>0</offset>
        <size>0x18</size>
        <usage>registers</usage>
      </addressBlock>
      <interrupt>
        <name>PORTC_PORTD</name>
        <value>31</value>
      </interrupt>
      <registers>
        <register>
          <name>PDOR</name>
          <description>Port Data Output Register</description>
          <addressOffset>0</addressOffset>
          <size>32</size>
          <access>read-write</access>
          <resetValue>0</resetValue>
          <resetMask>0xFFFFFFFF</resetMask>
          <fields>
            <field>
              <name>PDO</name>
              <description>Port Data Output</description>
              <bitOffset>0</bitOffset>
              <bitWidth>32</bitWidth>
              <access>read-write</access>
              <enumeratedValues>
                <enumeratedValue>
                  <name>0</name>
                  <description>Logic level 0 is driven on pin, provided pin is configured for general-purpose output.</description>
                  <value>#0</value>
                </enumeratedValue>
                <enumeratedValue>
                  <name>1</name>
                  <description>Logic level 1 is driven on pin, provided pin is configured for general-purpose output.</description>
                  <value>#1</value>
                </enumeratedValue>
              </enumeratedValues>
            </field>
          </fields>
        </register>
        <register>
          <name>PSOR</name>
          <description>Port Set Output Register</description>
          <addressOffset>0x4</addressOffset>
          <size>32</size>
          <access>write-only</access>
          <resetValue>0</resetValue>
          <resetMask>0xFFFFFFFF</resetMask>
          <fields>
            <field>
              <name>PTSO</name>
              <description>Port Set Output</description>
              <bitOffset>0</bitOffset>
              <bitWidth>32</bitWidth>
              <access>write-only</access>
              <enumeratedValues>
                <enumeratedValue>
                  <name>0</name>
                  <description>Corresponding bit in PDORn does not change.</description>
                  <value>#0</value>
                </enumeratedValue>
                <enumeratedValue>
                  <name>1</name>
                  <description>Corresponding bit in PDORn is set to logic 1.</description>
                  <value>#1</value>
                </enumeratedValue>
              </enumeratedValues>
            </field>
          </fields>
        </register>
        <register>
          <name>PCOR</name>
          <description>Port Clear Output Register</description>
          <addressOffset>0x8</addressOffset>
          <size>32</size>
          <access>write-only</access>
          <resetValue>0</resetValue>
          <resetMask>0xFFFFFFFF</resetMask>
          <fields>
            <field>
              <name>PTCO</name>
              <description>Port Clear Output</description>
              <bitOffset>0</bitOffset>
              <bitWidth>32</bitWidth>
              <access>write-only</access>
              <enumeratedValues>
                <enumeratedValue>
                  <name>0</name>
                  <description>Corresponding bit in PDORn does not change.</description>
                  <value>#0</value>
                </enumeratedValue>
                <enumeratedValue>
                  <name>1</name>
                  <description>Corresponding bit in PDORn is cleared to logic 0.</description>
                  <value>#1</value>
                </enumeratedValue>
              </enumeratedValues>
            </field>
          </fields>
        </register>
        <register>
          <name>PTOR</name>
          <description>Port Toggle Output Register</description>
          <addressOffset>0xC</addressOffset>
          <size>32</size>
          <access>write-only</access>
          <resetValue>0</resetValue>
          <resetMask>0xFFFFFFFF</resetMask>
          <fields>
            <field>
              <name>PTTO</name>
              <description>Port Toggle Output</description>
              <bitOffset>0</bitOffset>
              <bitWidth>32</bitWidth>
              <access>write-only</access>
              <enumeratedValues>
                <enumeratedValue>
                  <name>0</name>
                  <description>Corresponding bit in PDORn does not change.</description>
                  <value>#0</value>
                </enumeratedValue>
                <enumeratedValue>
                  <name>1</name>
                  <description>Corresponding bit in PDORn is set to the inverse of its existing logic state.</description>
                  <value>#1</value>
                </enumeratedValue>
              </enumeratedValues>
            </field>
          </fields>
        </register>
        <register>
          <name>PDIR</name>
          <description>Port Data Input Register</description>
          <addressOffset>0x10</addressOffset>
          <size>32</size>
          <access>read-only</access>
          <resetValue>0</resetValue>
          <resetMask>0xFFFFFFFF</resetMask>
          <fields>
            <field>
              <name>PDI</name>
              <description>Port Data Input</description>
              <bitOffset>0</bitOffset>
              <bitWidth>32</bitWidth>
              <access>read-only</access>
              <enumeratedValues>
                <enumeratedValue>
                  <name>0</name>
                  <description>Pin logic level is logic 0, or is not configured for use by digital function.</description>
                  <value>#0</value>
                </enumeratedValue>
                <enumeratedValue>
                  <name>1</name>
                  <description>Pin logic level is logic 1.</description>
                  <value>#1</value>
                </enumeratedValue>
              </enumeratedValues>
            </field>
          </fields>
        </register>
        <register>
          <name>PDDR</name>
          <description>Port Data Direction Register</description>
          <addressOffset>0x14</addressOffset>
          <size>32</size>
          <access>read-write</access>
          <resetValue>0</resetValue>
          <resetMask>0xFFFFFFFF</resetMask>
          <fields>
            <field>
              <name>PDD</name>
              <description>Port Data Direction</description>
              <bitOffset>0</bitOffset>
              <bitWidth>32</bitWidth>
              <access>read-write</access>
              <enumeratedValues>
                <enumeratedValue>
                  <name>0</name>
                  <description>Pin is configured as general-purpose input, for the GPIO function.</description>
                  <value>#0</value>
                </enumeratedValue>
                <enumeratedValue>
                  <name>1</name>
                  <description>Pin is configured as general-purpose output, for the GPIO function.</description>
                  <value>#1</value>
                </enumeratedValue>
              </enumeratedValues>
            </field>
          </fields>
        </register>
      </registers>
    </peripheral>
    <peripheral>
      <name>GPIOD</name>
      <description>General Purpose Input/Output</description>
      <groupName>GPIO</groupName>
      <prependToName>GPIOD_</prependToName>
      <baseAddress>0x400FF0C0</baseAddress>
      <addressBlock>
        <offset>0</offset>
        <size>0x18</size>
        <usage>registers</usage>
      </addressBlock>
      <interrupt>
        <name>PORTC_PORTD</name>
        <value>31</value>
      </interrupt>
      <registers>
        <register>
          <name>PDOR</name>
          <description>Port Data Output Register</description>
          <addressOffset>0</addressOffset>
          <size>32</size>
          <access>read-write</access>
          <resetValue>0</resetValue>
          <resetMask>0xFFFFFFFF</resetMask>
          <fields>
            <field>
              <name>PDO</name>
              <description>Port Data Output</description>
              <bitOffset>0</bitOffset>
              <bitWidth>32</bitWidth>
              <access>read-write</access>
              <enumeratedValues>
                <enumeratedValue>
                  <name>0</name>
                  <description>Logic level 0 is driven on pin, provided pin is configured for general-purpose output.</description>
                  <value>#0</value>
                </enumeratedValue>
                <enumeratedValue>
                  <name>1</name>
                  <description>Logic level 1 is driven on pin, provided pin is configured for general-purpose output.</description>
                  <value>#1</value>
                </enumeratedValue>
              </enumeratedValues>
            </field>
          </fields>
        </register>
        <register>
          <name>PSOR</name>
          <description>Port Set Output Register</description>
          <addressOffset>0x4</addressOffset>
          <size>32</size>
          <access>write-only</access>
          <resetValue>0</resetValue>
          <resetMask>0xFFFFFFFF</resetMask>
          <fields>
            <field>
              <name>PTSO</name>
              <description>Port Set Output</description>
              <bitOffset>0</bitOffset>
              <bitWidth>32</bitWidth>
              <access>write-only</access>
              <enumeratedValues>
                <enumeratedValue>
                  <name>0</name>
                  <description>Corresponding bit in PDORn does not change.</description>
                  <value>#0</value>
                </enumeratedValue>
                <enumeratedValue>
                  <name>1</name>
                  <description>Corresponding bit in PDORn is set to logic 1.</description>
                  <value>#1</value>
                </enumeratedValue>
              </enumeratedValues>
            </field>
          </fields>
        </register>
        <register>
          <name>PCOR</name>
          <description>Port Clear Output Register</description>
          <addressOffset>0x8</addressOffset>
          <size>32</size>
          <access>write-only</access>
          <resetValue>0</resetValue>
          <resetMask>0xFFFFFFFF</resetMask>
          <fields>
            <field>
              <name>PTCO</name>
              <description>Port Clear Output</description>
              <bitOffset>0</bitOffset>
              <bitWidth>32</bitWidth>
              <access>write-only</access>
              <enumeratedValues>
                <enumeratedValue>
                  <name>0</name>
                  <description>Corresponding bit in PDORn does not change.</description>
                  <value>#0</value>
                </enumeratedValue>
                <enumeratedValue>
                  <name>1</name>
                  <description>Corresponding bit in PDORn is cleared to logic 0.</description>
                  <value>#1</value>
                </enumeratedValue>
              </enumeratedValues>
            </field>
          </fields>
        </register>
        <register>
          <name>PTOR</name>
          <description>Port Toggle Output Register</description>
          <addressOffset>0xC</addressOffset>
          <size>32</size>
          <access>write-only</access>
          <resetValue>0</resetValue>
          <resetMask>0xFFFFFFFF</resetMask>
          <fields>
            <field>
              <name>PTTO</name>
              <description>Port Toggle Output</description>
              <bitOffset>0</bitOffset>
              <bitWidth>32</bitWidth>
              <access>write-only</access>
              <enumeratedValues>
                <enumeratedValue>
                  <name>0</name>
                  <description>Corresponding bit in PDORn does not change.</description>
                  <value>#0</value>
                </enumeratedValue>
                <enumeratedValue>
                  <name>1</name>
                  <description>Corresponding bit in PDORn is set to the inverse of its existing logic state.</description>
                  <value>#1</value>
                </enumeratedValue>
              </enumeratedValues>
            </field>
          </fields>
        </register>
        <register>
          <name>PDIR</name>
          <description>Port Data Input Register</description>
          <addressOffset>0x10</addressOffset>
          <size>32</size>
          <access>read-only</access>
          <resetValue>0</resetValue>
          <resetMask>0xFFFFFFFF</resetMask>
          <fields>
            <field>
              <name>PDI</name>
              <description>Port Data Input</description>
              <bitOffset>0</bitOffset>
              <bitWidth>32</bitWidth>
              <access>read-only</access>
              <enumeratedValues>
                <enumeratedValue>
                  <name>0</name>
                  <description>Pin logic level is logic 0, or is not configured for use by digital function.</description>
                  <value>#0</value>
                </enumeratedValue>
                <enumeratedValue>
                  <name>1</name>
                  <description>Pin logic level is logic 1.</description>
                  <value>#1</value>
                </enumeratedValue>
              </enumeratedValues>
            </field>
          </fields>
        </register>
        <register>
          <name>PDDR</name>
          <description>Port Data Direction Register</description>
          <addressOffset>0x14</addressOffset>
          <size>32</size>
          <access>read-write</access>
          <resetValue>0</resetValue>
          <resetMask>0xFFFFFFFF</resetMask>
          <fields>
            <field>
              <name>PDD</name>
              <description>Port Data Direction</description>
              <bitOffset>0</bitOffset>
              <bitWidth>32</bitWidth>
              <access>read-write</access>
              <enumeratedValues>
                <enumeratedValue>
                  <name>0</name>
                  <description>Pin is configured as general-purpose input, for the GPIO function.</description>
                  <value>#0</value>
                </enumeratedValue>
                <enumeratedValue>
                  <name>1</name>
                  <description>Pin is configured as general-purpose output, for the GPIO function.</description>
                  <value>#1</value>
                </enumeratedValue>
              </enumeratedValues>
            </field>
          </fields>
        </register>
      </registers>
    </peripheral>
    <peripheral>
      <name>GPIOE</name>
      <description>General Purpose Input/Output</description>
      <groupName>GPIO</groupName>
      <prependToName>GPIOE_</prependToName>
      <baseAddress>0x400FF100</baseAddress>
      <addressBlock>
        <offset>0</offset>
        <size>0x18</size>
        <usage>registers</usage>
      </addressBlock>
      <registers>
        <register>
          <name>PDOR</name>
          <description>Port Data Output Register</description>
          <addressOffset>0</addressOffset>
          <size>32</size>
          <access>read-write</access>
          <resetValue>0</resetValue>
          <resetMask>0xFFFFFFFF</resetMask>
          <fields>
            <field>
              <name>PDO</name>
              <description>Port Data Output</description>
              <bitOffset>0</bitOffset>
              <bitWidth>32</bitWidth>
              <access>read-write</access>
              <enumeratedValues>
                <enumeratedValue>
                  <name>0</name>
                  <description>Logic level 0 is driven on pin, provided pin is configured for general-purpose output.</description>
                  <value>#0</value>
                </enumeratedValue>
                <enumeratedValue>
                  <name>1</name>
                  <description>Logic level 1 is driven on pin, provided pin is configured for general-purpose output.</description>
                  <value>#1</value>
                </enumeratedValue>
              </enumeratedValues>
            </field>
          </fields>
        </register>
        <register>
          <name>PSOR</name>
          <description>Port Set Output Register</description>
          <addressOffset>0x4</addressOffset>
          <size>32</size>
          <access>write-only</access>
          <resetValue>0</resetValue>
          <resetMask>0xFFFFFFFF</resetMask>
          <fields>
            <field>
              <name>PTSO</name>
              <description>Port Set Output</description>
              <bitOffset>0</bitOffset>
              <bitWidth>32</bitWidth>
              <access>write-only</access>
              <enumeratedValues>
                <enumeratedValue>
                  <name>0</name>
                  <description>Corresponding bit in PDORn does not change.</description>
                  <value>#0</value>
                </enumeratedValue>
                <enumeratedValue>
                  <name>1</name>
                  <description>Corresponding bit in PDORn is set to logic 1.</description>
                  <value>#1</value>
                </enumeratedValue>
              </enumeratedValues>
            </field>
          </fields>
        </register>
        <register>
          <name>PCOR</name>
          <description>Port Clear Output Register</description>
          <addressOffset>0x8</addressOffset>
          <size>32</size>
          <access>write-only</access>
          <resetValue>0</resetValue>
          <resetMask>0xFFFFFFFF</resetMask>
          <fields>
            <field>
              <name>PTCO</name>
              <description>Port Clear Output</description>
              <bitOffset>0</bitOffset>
              <bitWidth>32</bitWidth>
              <access>write-only</access>
              <enumeratedValues>
                <enumeratedValue>
                  <name>0</name>
                  <description>Corresponding bit in PDORn does not change.</description>
                  <value>#0</value>
                </enumeratedValue>
                <enumeratedValue>
                  <name>1</name>
                  <description>Corresponding bit in PDORn is cleared to logic 0.</description>
                  <value>#1</value>
                </enumeratedValue>
              </enumeratedValues>
            </field>
          </fields>
        </register>
        <register>
          <name>PTOR</name>
          <description>Port Toggle Output Register</description>
          <addressOffset>0xC</addressOffset>
          <size>32</size>
          <access>write-only</access>
          <resetValue>0</resetValue>
          <resetMask>0xFFFFFFFF</resetMask>
          <fields>
            <field>
              <name>PTTO</name>
              <description>Port Toggle Output</description>
              <bitOffset>0</bitOffset>
              <bitWidth>32</bitWidth>
              <access>write-only</access>
              <enumeratedValues>
                <enumeratedValue>
                  <name>0</name>
                  <description>Corresponding bit in PDORn does not change.</description>
                  <value>#0</value>
                </enumeratedValue>
                <enumeratedValue>
                  <name>1</name>
                  <description>Corresponding bit in PDORn is set to the inverse of its existing logic state.</description>
                  <value>#1</value>
                </enumeratedValue>
              </enumeratedValues>
            </field>
          </fields>
        </register>
        <register>
          <name>PDIR</name>
          <description>Port Data Input Register</description>
          <addressOffset>0x10</addressOffset>
          <size>32</size>
          <access>read-only</access>
          <resetValue>0</resetValue>
          <resetMask>0xFFFFFFFF</resetMask>
          <fields>
            <field>
              <name>PDI</name>
              <description>Port Data Input</description>
              <bitOffset>0</bitOffset>
              <bitWidth>32</bitWidth>
              <access>read-only</access>
              <enumeratedValues>
                <enumeratedValue>
                  <name>0</name>
                  <description>Pin logic level is logic 0, or is not configured for use by digital function.</description>
                  <value>#0</value>
                </enumeratedValue>
                <enumeratedValue>
                  <name>1</name>
                  <description>Pin logic level is logic 1.</description>
                  <value>#1</value>
                </enumeratedValue>
              </enumeratedValues>
            </field>
          </fields>
        </register>
        <register>
          <name>PDDR</name>
          <description>Port Data Direction Register</description>
          <addressOffset>0x14</addressOffset>
          <size>32</size>
          <access>read-write</access>
          <resetValue>0</resetValue>
          <resetMask>0xFFFFFFFF</resetMask>
          <fields>
            <field>
              <name>PDD</name>
              <description>Port Data Direction</description>
              <bitOffset>0</bitOffset>
              <bitWidth>32</bitWidth>
              <access>read-write</access>
              <enumeratedValues>
                <enumeratedValue>
                  <name>0</name>
                  <description>Pin is configured as general-purpose input, for the GPIO function.</description>
                  <value>#0</value>
                </enumeratedValue>
                <enumeratedValue>
                  <name>1</name>
                  <description>Pin is configured as general-purpose output, for the GPIO function.</description>
                  <value>#1</value>
                </enumeratedValue>
              </enumeratedValues>
            </field>
          </fields>
        </register>
      </registers>
    </peripheral>
    <peripheral>
      <name>MTB</name>
      <description>Micro Trace Buffer</description>
      <prependToName>MTB_</prependToName>
      <baseAddress>0xF0000000</baseAddress>
      <addressBlock>
        <offset>0</offset>
        <size>0x1000</size>
        <usage>registers</usage>
      </addressBlock>
      <registers>
        <register>
          <name>POSITION</name>
          <description>MTB Position Register</description>
          <addressOffset>0</addressOffset>
          <size>32</size>
          <access>read-write</access>
          <resetValue>0</resetValue>
          <resetMask>0x3</resetMask>
          <fields>
            <field>
              <name>WRAP</name>
              <description>This field is set to 1 automatically when the POINTER value wraps as determined by the MTB_MASTER[MASK] field in the MASTER Trace Control Register</description>
              <bitOffset>2</bitOffset>
              <bitWidth>1</bitWidth>
              <access>read-write</access>
            </field>
            <field>
              <name>POINTER</name>
              <description>Trace Packet Address Pointer[28:0]</description>
              <bitOffset>3</bitOffset>
              <bitWidth>29</bitWidth>
              <access>read-write</access>
            </field>
          </fields>
        </register>
        <register>
          <name>MASTER</name>
          <description>MTB Master Register</description>
          <addressOffset>0x4</addressOffset>
          <size>32</size>
          <access>read-write</access>
          <resetValue>0x80</resetValue>
          <resetMask>0xFFFFFFE0</resetMask>
          <fields>
            <field>
              <name>MASK</name>
              <description>Mask</description>
              <bitOffset>0</bitOffset>
              <bitWidth>5</bitWidth>
              <access>read-write</access>
            </field>
            <field>
              <name>TSTARTEN</name>
              <description>Trace Start Input Enable</description>
              <bitOffset>5</bitOffset>
              <bitWidth>1</bitWidth>
              <access>read-write</access>
            </field>
            <field>
              <name>TSTOPEN</name>
              <description>Trace Stop Input Enable</description>
              <bitOffset>6</bitOffset>
              <bitWidth>1</bitWidth>
              <access>read-write</access>
            </field>
            <field>
              <name>SFRWPRIV</name>
              <description>Special Function Register Write Privilege</description>
              <bitOffset>7</bitOffset>
              <bitWidth>1</bitWidth>
              <access>read-write</access>
            </field>
            <field>
              <name>RAMPRIV</name>
              <description>RAM Privilege</description>
              <bitOffset>8</bitOffset>
              <bitWidth>1</bitWidth>
              <access>read-write</access>
            </field>
            <field>
              <name>HALTREQ</name>
              <description>Halt Request</description>
              <bitOffset>9</bitOffset>
              <bitWidth>1</bitWidth>
              <access>read-write</access>
            </field>
            <field>
              <name>EN</name>
              <description>Main Trace Enable</description>
              <bitOffset>31</bitOffset>
              <bitWidth>1</bitWidth>
              <access>read-write</access>
            </field>
          </fields>
        </register>
        <register>
          <name>FLOW</name>
          <description>MTB Flow Register</description>
          <addressOffset>0x8</addressOffset>
          <size>32</size>
          <access>read-write</access>
          <resetValue>0</resetValue>
          <resetMask>0x4</resetMask>
          <fields>
            <field>
              <name>AUTOSTOP</name>
              <description>If this field is 1 and WATERMARK is equal to MTB_POSITION[POINTER], then MTB_MASTER[EN] is automatically set to 0</description>
              <bitOffset>0</bitOffset>
              <bitWidth>1</bitWidth>
              <access>read-write</access>
            </field>
            <field>
              <name>AUTOHALT</name>
              <description>If this field is 1 and WATERMARK is equal to MTB_POSITION[POINTER], then MTB_MASTER[HALTREQ] is automatically set to 1</description>
              <bitOffset>1</bitOffset>
              <bitWidth>1</bitWidth>
              <access>read-write</access>
            </field>
            <field>
              <name>WATERMARK</name>
              <description>WATERMARK[28:0]</description>
              <bitOffset>3</bitOffset>
              <bitWidth>29</bitWidth>
              <access>read-write</access>
            </field>
          </fields>
        </register>
        <register>
          <name>BASE</name>
          <description>MTB Base Register</description>
          <addressOffset>0xC</addressOffset>
          <size>32</size>
          <access>read-only</access>
          <resetValue>0</resetValue>
          <resetMask>0</resetMask>
          <fields>
            <field>
              <name>BASEADDR</name>
              <description>This value is defined with a hardwired signal and the expression: 0x2000_0000 - (RAM_Size/4)</description>
              <bitOffset>0</bitOffset>
              <bitWidth>32</bitWidth>
              <access>read-only</access>
            </field>
          </fields>
        </register>
        <register>
          <name>MODECTRL</name>
          <description>Integration Mode Control Register</description>
          <addressOffset>0xF00</addressOffset>
          <size>32</size>
          <access>read-only</access>
          <resetValue>0</resetValue>
          <resetMask>0xFFFFFFFF</resetMask>
          <fields>
            <field>
              <name>MODECTRL</name>
              <description>Hardwired to 0x0000_0000</description>
              <bitOffset>0</bitOffset>
              <bitWidth>32</bitWidth>
              <access>read-only</access>
            </field>
          </fields>
        </register>
        <register>
          <name>TAGSET</name>
          <description>Claim TAG Set Register</description>
          <addressOffset>0xFA0</addressOffset>
          <size>32</size>
          <access>read-only</access>
          <resetValue>0</resetValue>
          <resetMask>0xFFFFFFFF</resetMask>
          <fields>
            <field>
              <name>TAGSET</name>
              <description>Hardwired to 0x0000_0000</description>
              <bitOffset>0</bitOffset>
              <bitWidth>32</bitWidth>
              <access>read-only</access>
            </field>
          </fields>
        </register>
        <register>
          <name>TAGCLEAR</name>
          <description>Claim TAG Clear Register</description>
          <addressOffset>0xFA4</addressOffset>
          <size>32</size>
          <access>read-only</access>
          <resetValue>0</resetValue>
          <resetMask>0xFFFFFFFF</resetMask>
          <fields>
            <field>
              <name>TAGCLEAR</name>
              <description>Hardwired to 0x0000_0000</description>
              <bitOffset>0</bitOffset>
              <bitWidth>32</bitWidth>
              <access>read-only</access>
            </field>
          </fields>
        </register>
        <register>
          <name>LOCKACCESS</name>
          <description>Lock Access Register</description>
          <addressOffset>0xFB0</addressOffset>
          <size>32</size>
          <access>read-only</access>
          <resetValue>0</resetValue>
          <resetMask>0xFFFFFFFF</resetMask>
          <fields>
            <field>
              <name>LOCKACCESS</name>
              <description>Hardwired to 0x0000_0000</description>
              <bitOffset>0</bitOffset>
              <bitWidth>32</bitWidth>
              <access>read-only</access>
            </field>
          </fields>
        </register>
        <register>
          <name>LOCKSTAT</name>
          <description>Lock Status Register</description>
          <addressOffset>0xFB4</addressOffset>
          <size>32</size>
          <access>read-only</access>
          <resetValue>0</resetValue>
          <resetMask>0xFFFFFFFF</resetMask>
          <fields>
            <field>
              <name>LOCKSTAT</name>
              <description>Hardwired to 0x0000_0000</description>
              <bitOffset>0</bitOffset>
              <bitWidth>32</bitWidth>
              <access>read-only</access>
            </field>
          </fields>
        </register>
        <register>
          <name>AUTHSTAT</name>
          <description>Authentication Status Register</description>
          <addressOffset>0xFB8</addressOffset>
          <size>32</size>
          <access>read-only</access>
          <resetValue>0</resetValue>
          <resetMask>0xFFFFFFFF</resetMask>
          <fields>
            <field>
              <name>BIT0</name>
              <description>Connected to DBGEN.</description>
              <bitOffset>0</bitOffset>
              <bitWidth>1</bitWidth>
              <access>read-only</access>
            </field>
            <field>
              <name>BIT1</name>
              <description>Hardwired to 1.</description>
              <bitOffset>1</bitOffset>
              <bitWidth>1</bitWidth>
              <access>read-only</access>
            </field>
            <field>
              <name>BIT2</name>
              <description>Connected to NIDEN or DBGEN signal.</description>
              <bitOffset>2</bitOffset>
              <bitWidth>1</bitWidth>
              <access>read-only</access>
            </field>
            <field>
              <name>BIT3</name>
              <description>Hardwired to 1.</description>
              <bitOffset>3</bitOffset>
              <bitWidth>1</bitWidth>
              <access>read-only</access>
            </field>
          </fields>
        </register>
        <register>
          <name>DEVICEARCH</name>
          <description>Device Architecture Register</description>
          <addressOffset>0xFBC</addressOffset>
          <size>32</size>
          <access>read-only</access>
          <resetValue>0x47700A31</resetValue>
          <resetMask>0xFFFFFFFF</resetMask>
          <fields>
            <field>
              <name>DEVICEARCH</name>
              <description>Hardwired to 0x4770_0A31.</description>
              <bitOffset>0</bitOffset>
              <bitWidth>32</bitWidth>
              <access>read-only</access>
            </field>
          </fields>
        </register>
        <register>
          <name>DEVICECFG</name>
          <description>Device Configuration Register</description>
          <addressOffset>0xFC8</addressOffset>
          <size>32</size>
          <access>read-only</access>
          <resetValue>0</resetValue>
          <resetMask>0xFFFFFFFF</resetMask>
          <fields>
            <field>
              <name>DEVICECFG</name>
              <description>Hardwired to 0x0000_0000.</description>
              <bitOffset>0</bitOffset>
              <bitWidth>32</bitWidth>
              <access>read-only</access>
            </field>
          </fields>
        </register>
        <register>
          <name>DEVICETYPID</name>
          <description>Device Type Identifier Register</description>
          <addressOffset>0xFCC</addressOffset>
          <size>32</size>
          <access>read-only</access>
          <resetValue>0x31</resetValue>
          <resetMask>0xFFFFFFFF</resetMask>
          <fields>
            <field>
              <name>DEVICETYPID</name>
              <description>Hardwired to 0x0000_0031.</description>
              <bitOffset>0</bitOffset>
              <bitWidth>32</bitWidth>
              <access>read-only</access>
            </field>
          </fields>
        </register>
        <register>
          <dim>8</dim>
          <dimIncrement>0x4</dimIncrement>
          <dimIndex>4,5,6,7,0,1,2,3</dimIndex>
          <name>PERIPHID%s</name>
          <description>Peripheral ID Register</description>
          <addressOffset>0xFD0</addressOffset>
          <size>32</size>
          <access>read-only</access>
          <resetValue>0</resetValue>
          <resetMask>0</resetMask>
          <fields>
            <field>
              <name>PERIPHID</name>
              <description>Peripheral ID4 is hardwired to 0x0000_0004; ID0 to 0x0000_0032; ID1 to 0x0000_00B9; ID2 to 0x0000_000B; and all the others to 0x0000_0000</description>
              <bitOffset>0</bitOffset>
              <bitWidth>32</bitWidth>
              <access>read-only</access>
            </field>
          </fields>
        </register>
        <register>
          <dim>4</dim>
          <dimIncrement>0x4</dimIncrement>
          <dimIndex>0,1,2,3</dimIndex>
          <name>COMPID%s</name>
          <description>Component ID Register</description>
          <addressOffset>0xFF0</addressOffset>
          <size>32</size>
          <access>read-only</access>
          <resetValue>0</resetValue>
          <resetMask>0</resetMask>
          <fields>
            <field>
              <name>COMPID</name>
              <description>Component ID</description>
              <bitOffset>0</bitOffset>
              <bitWidth>32</bitWidth>
              <access>read-only</access>
            </field>
          </fields>
        </register>
      </registers>
    </peripheral>
    <peripheral>
      <name>MTBDWT</name>
      <description>MTB data watchpoint and trace</description>
      <prependToName>MTBDWT_</prependToName>
      <baseAddress>0xF0001000</baseAddress>
      <addressBlock>
        <offset>0</offset>
        <size>0x1000</size>
        <usage>registers</usage>
      </addressBlock>
      <registers>
        <register>
          <name>CTRL</name>
          <description>MTB DWT Control Register</description>
          <addressOffset>0</addressOffset>
          <size>32</size>
          <access>read-only</access>
          <resetValue>0x2F000000</resetValue>
          <resetMask>0xFFFFFFFF</resetMask>
          <fields>
            <field>
              <name>DWTCFGCTRL</name>
              <description>DWT configuration controls</description>
              <bitOffset>0</bitOffset>
              <bitWidth>28</bitWidth>
              <access>read-only</access>
            </field>
            <field>
              <name>NUMCMP</name>
              <description>Number of comparators</description>
              <bitOffset>28</bitOffset>
              <bitWidth>4</bitWidth>
              <access>read-only</access>
            </field>
          </fields>
        </register>
        <register>
          <dim>2</dim>
          <dimIncrement>0x10</dimIncrement>
          <dimIndex>0,1</dimIndex>
          <name>COMP%s</name>
          <description>MTB_DWT Comparator Register</description>
          <addressOffset>0x20</addressOffset>
          <size>32</size>
          <access>read-write</access>
          <resetValue>0</resetValue>
          <resetMask>0xFFFFFFFF</resetMask>
          <fields>
            <field>
              <name>COMP</name>
              <description>Reference value for comparison</description>
              <bitOffset>0</bitOffset>
              <bitWidth>32</bitWidth>
              <access>read-write</access>
            </field>
          </fields>
        </register>
        <register>
          <dim>2</dim>
          <dimIncrement>0x10</dimIncrement>
          <dimIndex>0,1</dimIndex>
          <name>MASK%s</name>
          <description>MTB_DWT Comparator Mask Register</description>
          <addressOffset>0x24</addressOffset>
          <size>32</size>
          <access>read-write</access>
          <resetValue>0</resetValue>
          <resetMask>0xFFFFFFFF</resetMask>
          <fields>
            <field>
              <name>MASK</name>
              <description>MASK</description>
              <bitOffset>0</bitOffset>
              <bitWidth>5</bitWidth>
              <access>read-write</access>
            </field>
          </fields>
        </register>
        <register>
          <name>FCT0</name>
          <description>MTB_DWT Comparator Function Register 0</description>
          <addressOffset>0x28</addressOffset>
          <size>32</size>
          <access>read-write</access>
          <resetValue>0</resetValue>
          <resetMask>0xFFFFFFFF</resetMask>
          <fields>
            <field>
              <name>FUNCTION</name>
              <description>Function</description>
              <bitOffset>0</bitOffset>
              <bitWidth>4</bitWidth>
              <access>read-write</access>
              <enumeratedValues>
                <enumeratedValue>
                  <name>0000</name>
                  <description>Disabled.</description>
                  <value>#0000</value>
                </enumeratedValue>
                <enumeratedValue>
                  <name>0100</name>
                  <description>Instruction fetch.</description>
                  <value>#0100</value>
                </enumeratedValue>
                <enumeratedValue>
                  <name>0101</name>
                  <description>Data operand read.</description>
                  <value>#0101</value>
                </enumeratedValue>
                <enumeratedValue>
                  <name>0110</name>
                  <description>Data operand write.</description>
                  <value>#0110</value>
                </enumeratedValue>
                <enumeratedValue>
                  <name>0111</name>
                  <description>Data operand (read + write).</description>
                  <value>#0111</value>
                </enumeratedValue>
              </enumeratedValues>
            </field>
            <field>
              <name>DATAVMATCH</name>
              <description>Data Value Match</description>
              <bitOffset>8</bitOffset>
              <bitWidth>1</bitWidth>
              <access>read-write</access>
              <enumeratedValues>
                <enumeratedValue>
                  <name>0</name>
                  <description>Perform address comparison.</description>
                  <value>#0</value>
                </enumeratedValue>
                <enumeratedValue>
                  <name>1</name>
                  <description>Perform data value comparison.</description>
                  <value>#1</value>
                </enumeratedValue>
              </enumeratedValues>
            </field>
            <field>
              <name>DATAVSIZE</name>
              <description>Data Value Size</description>
              <bitOffset>10</bitOffset>
              <bitWidth>2</bitWidth>
              <access>read-write</access>
              <enumeratedValues>
                <enumeratedValue>
                  <name>00</name>
                  <description>Byte.</description>
                  <value>#00</value>
                </enumeratedValue>
                <enumeratedValue>
                  <name>01</name>
                  <description>Halfword.</description>
                  <value>#01</value>
                </enumeratedValue>
                <enumeratedValue>
                  <name>10</name>
                  <description>Word.</description>
                  <value>#10</value>
                </enumeratedValue>
                <enumeratedValue>
                  <name>11</name>
                  <description>Reserved. Any attempts to use this value results in UNPREDICTABLE behavior.</description>
                  <value>#11</value>
                </enumeratedValue>
              </enumeratedValues>
            </field>
            <field>
              <name>DATAVADDR0</name>
              <description>Data Value Address 0</description>
              <bitOffset>12</bitOffset>
              <bitWidth>4</bitWidth>
              <access>read-write</access>
            </field>
            <field>
              <name>MATCHED</name>
              <description>Comparator match</description>
              <bitOffset>24</bitOffset>
              <bitWidth>1</bitWidth>
              <access>read-only</access>
              <enumeratedValues>
                <enumeratedValue>
                  <name>0</name>
                  <description>No match.</description>
                  <value>#0</value>
                </enumeratedValue>
                <enumeratedValue>
                  <name>1</name>
                  <description>Match occurred.</description>
                  <value>#1</value>
                </enumeratedValue>
              </enumeratedValues>
            </field>
          </fields>
        </register>
        <register>
          <name>FCT1</name>
          <description>MTB_DWT Comparator Function Register 1</description>
          <addressOffset>0x38</addressOffset>
          <size>32</size>
          <access>read-write</access>
          <resetValue>0</resetValue>
          <resetMask>0xFFFFFFFF</resetMask>
          <fields>
            <field>
              <name>FUNCTION</name>
              <description>Function</description>
              <bitOffset>0</bitOffset>
              <bitWidth>4</bitWidth>
              <access>read-write</access>
              <enumeratedValues>
                <enumeratedValue>
                  <name>0000</name>
                  <description>Disabled.</description>
                  <value>#0000</value>
                </enumeratedValue>
                <enumeratedValue>
                  <name>0100</name>
                  <description>Instruction fetch.</description>
                  <value>#0100</value>
                </enumeratedValue>
                <enumeratedValue>
                  <name>0101</name>
                  <description>Data operand read.</description>
                  <value>#0101</value>
                </enumeratedValue>
                <enumeratedValue>
                  <name>0110</name>
                  <description>Data operand write.</description>
                  <value>#0110</value>
                </enumeratedValue>
                <enumeratedValue>
                  <name>0111</name>
                  <description>Data operand (read + write).</description>
                  <value>#0111</value>
                </enumeratedValue>
              </enumeratedValues>
            </field>
            <field>
              <name>MATCHED</name>
              <description>Comparator match</description>
              <bitOffset>24</bitOffset>
              <bitWidth>1</bitWidth>
              <access>read-only</access>
              <enumeratedValues>
                <enumeratedValue>
                  <name>0</name>
                  <description>No match.</description>
                  <value>#0</value>
                </enumeratedValue>
                <enumeratedValue>
                  <name>1</name>
                  <description>Match occurred.</description>
                  <value>#1</value>
                </enumeratedValue>
              </enumeratedValues>
            </field>
          </fields>
        </register>
        <register>
          <name>TBCTRL</name>
          <description>MTB_DWT Trace Buffer Control Register</description>
          <addressOffset>0x200</addressOffset>
          <size>32</size>
          <access>read-write</access>
          <resetValue>0x20000000</resetValue>
          <resetMask>0xFFFFFFFF</resetMask>
          <fields>
            <field>
              <name>ACOMP0</name>
              <description>Action based on Comparator 0 match</description>
              <bitOffset>0</bitOffset>
              <bitWidth>1</bitWidth>
              <access>read-write</access>
              <enumeratedValues>
                <enumeratedValue>
                  <name>0</name>
                  <description>Trigger TSTOP based on the assertion of MTBDWT_FCT0[MATCHED].</description>
                  <value>#0</value>
                </enumeratedValue>
                <enumeratedValue>
                  <name>1</name>
                  <description>Trigger TSTART based on the assertion of MTBDWT_FCT0[MATCHED].</description>
                  <value>#1</value>
                </enumeratedValue>
              </enumeratedValues>
            </field>
            <field>
              <name>ACOMP1</name>
              <description>Action based on Comparator 1 match</description>
              <bitOffset>1</bitOffset>
              <bitWidth>1</bitWidth>
              <access>read-write</access>
              <enumeratedValues>
                <enumeratedValue>
                  <name>0</name>
                  <description>Trigger TSTOP based on the assertion of MTBDWT_FCT1[MATCHED].</description>
                  <value>#0</value>
                </enumeratedValue>
                <enumeratedValue>
                  <name>1</name>
                  <description>Trigger TSTART based on the assertion of MTBDWT_FCT1[MATCHED].</description>
                  <value>#1</value>
                </enumeratedValue>
              </enumeratedValues>
            </field>
            <field>
              <name>NUMCOMP</name>
              <description>Number of Comparators</description>
              <bitOffset>28</bitOffset>
              <bitWidth>4</bitWidth>
              <access>read-only</access>
            </field>
          </fields>
        </register>
        <register>
          <name>DEVICECFG</name>
          <description>Device Configuration Register</description>
          <addressOffset>0xFC8</addressOffset>
          <size>32</size>
          <access>read-only</access>
          <resetValue>0</resetValue>
          <resetMask>0xFFFFFFFF</resetMask>
          <fields>
            <field>
              <name>DEVICECFG</name>
              <description>Hardwired to 0x0000_0000.</description>
              <bitOffset>0</bitOffset>
              <bitWidth>32</bitWidth>
              <access>read-only</access>
            </field>
          </fields>
        </register>
        <register>
          <name>DEVICETYPID</name>
          <description>Device Type Identifier Register</description>
          <addressOffset>0xFCC</addressOffset>
          <size>32</size>
          <access>read-only</access>
          <resetValue>0x4</resetValue>
          <resetMask>0xFFFFFFFF</resetMask>
          <fields>
            <field>
              <name>DEVICETYPID</name>
              <description>Hardwired to 0x0000_0004.</description>
              <bitOffset>0</bitOffset>
              <bitWidth>32</bitWidth>
              <access>read-only</access>
            </field>
          </fields>
        </register>
        <register>
          <dim>8</dim>
          <dimIncrement>0x4</dimIncrement>
          <dimIndex>4,5,6,7,0,1,2,3</dimIndex>
          <name>PERIPHID%s</name>
          <description>Peripheral ID Register</description>
          <addressOffset>0xFD0</addressOffset>
          <size>32</size>
          <access>read-only</access>
          <resetValue>0</resetValue>
          <resetMask>0</resetMask>
          <fields>
            <field>
              <name>PERIPHID</name>
              <description>Peripheral ID1 is hardwired to 0x0000_00E0; ID2 to 0x0000_0008; and all the others to 0x0000_0000.</description>
              <bitOffset>0</bitOffset>
              <bitWidth>32</bitWidth>
              <access>read-only</access>
            </field>
          </fields>
        </register>
        <register>
          <dim>4</dim>
          <dimIncrement>0x4</dimIncrement>
          <dimIndex>0,1,2,3</dimIndex>
          <name>COMPID%s</name>
          <description>Component ID Register</description>
          <addressOffset>0xFF0</addressOffset>
          <size>32</size>
          <access>read-only</access>
          <resetValue>0</resetValue>
          <resetMask>0</resetMask>
          <fields>
            <field>
              <name>COMPID</name>
              <description>Component ID</description>
              <bitOffset>0</bitOffset>
              <bitWidth>32</bitWidth>
              <access>read-only</access>
            </field>
          </fields>
        </register>
      </registers>
    </peripheral>
    <peripheral>
      <name>ROM</name>
      <description>System ROM</description>
      <prependToName>ROM_</prependToName>
      <baseAddress>0xF0002000</baseAddress>
      <addressBlock>
        <offset>0</offset>
        <size>0x1000</size>
        <usage>registers</usage>
      </addressBlock>
      <registers>
        <register>
          <dim>3</dim>
          <dimIncrement>0x4</dimIncrement>
          <dimIndex>0,1,2</dimIndex>
          <name>ENTRY%s</name>
          <description>Entry</description>
          <addressOffset>0</addressOffset>
          <size>32</size>
          <access>read-only</access>
          <resetValue>0</resetValue>
          <resetMask>0</resetMask>
          <fields>
            <field>
              <name>ENTRY</name>
              <description>ENTRY</description>
              <bitOffset>0</bitOffset>
              <bitWidth>32</bitWidth>
              <access>read-only</access>
            </field>
          </fields>
        </register>
        <register>
          <name>TABLEMARK</name>
          <description>End of Table Marker Register</description>
          <addressOffset>0xC</addressOffset>
          <size>32</size>
          <access>read-only</access>
          <resetValue>0</resetValue>
          <resetMask>0xFFFFFFFF</resetMask>
          <fields>
            <field>
              <name>MARK</name>
              <description>Hardwired to 0x0000_0000</description>
              <bitOffset>0</bitOffset>
              <bitWidth>32</bitWidth>
              <access>read-only</access>
            </field>
          </fields>
        </register>
        <register>
          <name>SYSACCESS</name>
          <description>System Access Register</description>
          <addressOffset>0xFCC</addressOffset>
          <size>32</size>
          <access>read-only</access>
          <resetValue>0x1</resetValue>
          <resetMask>0xFFFFFFFF</resetMask>
          <fields>
            <field>
              <name>SYSACCESS</name>
              <description>Hardwired to 0x0000_0001</description>
              <bitOffset>0</bitOffset>
              <bitWidth>32</bitWidth>
              <access>read-only</access>
            </field>
          </fields>
        </register>
        <register>
          <dim>8</dim>
          <dimIncrement>0x4</dimIncrement>
          <dimIndex>4,5,6,7,0,1,2,3</dimIndex>
          <name>PERIPHID%s</name>
          <description>Peripheral ID Register</description>
          <addressOffset>0xFD0</addressOffset>
          <size>32</size>
          <access>read-only</access>
          <resetValue>0</resetValue>
          <resetMask>0</resetMask>
          <fields>
            <field>
              <name>PERIPHID</name>
              <description>Peripheral ID1 is hardwired to 0x0000_00E0; ID2 to 0x0000_0008; and all the others to 0x0000_0000.</description>
              <bitOffset>0</bitOffset>
              <bitWidth>32</bitWidth>
              <access>read-only</access>
            </field>
          </fields>
        </register>
        <register>
          <dim>4</dim>
          <dimIncrement>0x4</dimIncrement>
          <dimIndex>0,1,2,3</dimIndex>
          <name>COMPID%s</name>
          <description>Component ID Register</description>
          <addressOffset>0xFF0</addressOffset>
          <size>32</size>
          <access>read-only</access>
          <resetValue>0</resetValue>
          <resetMask>0</resetMask>
          <fields>
            <field>
              <name>COMPID</name>
              <description>Component ID</description>
              <bitOffset>0</bitOffset>
              <bitWidth>32</bitWidth>
              <access>read-only</access>
            </field>
          </fields>
        </register>
      </registers>
    </peripheral>
    <peripheral>
      <name>MCM</name>
      <description>Core Platform Miscellaneous Control Module</description>
      <prependToName>MCM_</prependToName>
      <baseAddress>0xF0003000</baseAddress>
      <addressBlock>
        <offset>0x8</offset>
        <size>0x3C</size>
        <usage>registers</usage>
      </addressBlock>
      <registers>
        <register>
          <name>PLASC</name>
          <description>Crossbar Switch (AXBS) Slave Configuration</description>
          <addressOffset>0x8</addressOffset>
          <size>16</size>
          <access>read-only</access>
          <resetValue>0x7</resetValue>
          <resetMask>0xFFFF</resetMask>
          <fields>
            <field>
              <name>ASC</name>
              <description>Each bit in the ASC field indicates whether there is a corresponding connection to the crossbar switch&apos;s slave input port.</description>
              <bitOffset>0</bitOffset>
              <bitWidth>8</bitWidth>
              <access>read-only</access>
              <enumeratedValues>
                <enumeratedValue>
                  <name>0</name>
                  <description>A bus slave connection to AXBS input port n is absent.</description>
                  <value>#0</value>
                </enumeratedValue>
                <enumeratedValue>
                  <name>1</name>
                  <description>A bus slave connection to AXBS input port n is present.</description>
                  <value>#1</value>
                </enumeratedValue>
              </enumeratedValues>
            </field>
          </fields>
        </register>
        <register>
          <name>PLAMC</name>
          <description>Crossbar Switch (AXBS) Master Configuration</description>
          <addressOffset>0xA</addressOffset>
          <size>16</size>
          <access>read-only</access>
          <resetValue>0xD</resetValue>
          <resetMask>0xFFFF</resetMask>
          <fields>
            <field>
              <name>AMC</name>
              <description>Each bit in the AMC field indicates whether there is a corresponding connection to the AXBS master input port.</description>
              <bitOffset>0</bitOffset>
              <bitWidth>8</bitWidth>
              <access>read-only</access>
              <enumeratedValues>
                <enumeratedValue>
                  <name>0</name>
                  <description>A bus master connection to AXBS input port n is absent</description>
                  <value>#0</value>
                </enumeratedValue>
                <enumeratedValue>
                  <name>1</name>
                  <description>A bus master connection to AXBS input port n is present</description>
                  <value>#1</value>
                </enumeratedValue>
              </enumeratedValues>
            </field>
          </fields>
        </register>
        <register>
          <name>PLACR</name>
          <description>Platform Control Register</description>
          <addressOffset>0xC</addressOffset>
          <size>32</size>
          <access>read-write</access>
          <resetValue>0</resetValue>
          <resetMask>0xFFFFFFFF</resetMask>
          <fields>
            <field>
              <name>ARB</name>
              <description>Arbitration select</description>
              <bitOffset>9</bitOffset>
              <bitWidth>1</bitWidth>
              <access>read-write</access>
              <enumeratedValues>
                <enumeratedValue>
                  <name>0</name>
                  <description>Fixed-priority arbitration for the crossbar masters</description>
                  <value>#0</value>
                </enumeratedValue>
                <enumeratedValue>
                  <name>1</name>
                  <description>Round-robin arbitration for the crossbar masters</description>
                  <value>#1</value>
                </enumeratedValue>
              </enumeratedValues>
            </field>
            <field>
              <name>CFCC</name>
              <description>Clear Flash Controller Cache</description>
              <bitOffset>10</bitOffset>
              <bitWidth>1</bitWidth>
              <access>write-only</access>
            </field>
            <field>
              <name>DFCDA</name>
              <description>Disable Flash Controller Data Caching</description>
              <bitOffset>11</bitOffset>
              <bitWidth>1</bitWidth>
              <access>read-write</access>
              <enumeratedValues>
                <enumeratedValue>
                  <name>0</name>
                  <description>Enable flash controller data caching</description>
                  <value>#0</value>
                </enumeratedValue>
                <enumeratedValue>
                  <name>1</name>
                  <description>Disable flash controller data caching.</description>
                  <value>#1</value>
                </enumeratedValue>
              </enumeratedValues>
            </field>
            <field>
              <name>DFCIC</name>
              <description>Disable Flash Controller Instruction Caching</description>
              <bitOffset>12</bitOffset>
              <bitWidth>1</bitWidth>
              <access>read-write</access>
              <enumeratedValues>
                <enumeratedValue>
                  <name>0</name>
                  <description>Enable flash controller instruction caching.</description>
                  <value>#0</value>
                </enumeratedValue>
                <enumeratedValue>
                  <name>1</name>
                  <description>Disable flash controller instruction caching.</description>
                  <value>#1</value>
                </enumeratedValue>
              </enumeratedValues>
            </field>
            <field>
              <name>DFCC</name>
              <description>Disable Flash Controller Cache</description>
              <bitOffset>13</bitOffset>
              <bitWidth>1</bitWidth>
              <access>read-write</access>
              <enumeratedValues>
                <enumeratedValue>
                  <name>0</name>
                  <description>Enable flash controller cache.</description>
                  <value>#0</value>
                </enumeratedValue>
                <enumeratedValue>
                  <name>1</name>
                  <description>Disable flash controller cache.</description>
                  <value>#1</value>
                </enumeratedValue>
              </enumeratedValues>
            </field>
            <field>
              <name>EFDS</name>
              <description>Enable Flash Data Speculation</description>
              <bitOffset>14</bitOffset>
              <bitWidth>1</bitWidth>
              <access>read-write</access>
              <enumeratedValues>
                <enumeratedValue>
                  <name>0</name>
                  <description>Disable flash data speculation.</description>
                  <value>#0</value>
                </enumeratedValue>
                <enumeratedValue>
                  <name>1</name>
                  <description>Enable flash data speculation.</description>
                  <value>#1</value>
                </enumeratedValue>
              </enumeratedValues>
            </field>
            <field>
              <name>DFCS</name>
              <description>Disable Flash Controller Speculation</description>
              <bitOffset>15</bitOffset>
              <bitWidth>1</bitWidth>
              <access>read-write</access>
              <enumeratedValues>
                <enumeratedValue>
                  <name>0</name>
                  <description>Enable flash controller speculation.</description>
                  <value>#0</value>
                </enumeratedValue>
                <enumeratedValue>
                  <name>1</name>
                  <description>Disable flash controller speculation.</description>
                  <value>#1</value>
                </enumeratedValue>
              </enumeratedValues>
            </field>
            <field>
              <name>ESFC</name>
              <description>Enable Stalling Flash Controller</description>
              <bitOffset>16</bitOffset>
              <bitWidth>1</bitWidth>
              <access>read-write</access>
              <enumeratedValues>
                <enumeratedValue>
                  <name>0</name>
                  <description>Disable stalling flash controller when flash is busy.</description>
                  <value>#0</value>
                </enumeratedValue>
                <enumeratedValue>
                  <name>1</name>
                  <description>Enable stalling flash controller when flash is busy.</description>
                  <value>#1</value>
                </enumeratedValue>
              </enumeratedValues>
            </field>
          </fields>
        </register>
        <register>
          <name>CPO</name>
          <description>Compute Operation Control Register</description>
          <addressOffset>0x40</addressOffset>
          <size>32</size>
          <access>read-write</access>
          <resetValue>0</resetValue>
          <resetMask>0xFFFFFFFF</resetMask>
          <fields>
            <field>
              <name>CPOREQ</name>
              <description>Compute Operation Request</description>
              <bitOffset>0</bitOffset>
              <bitWidth>1</bitWidth>
              <access>read-write</access>
              <enumeratedValues>
                <enumeratedValue>
                  <name>0</name>
                  <description>Request is cleared.</description>
                  <value>#0</value>
                </enumeratedValue>
                <enumeratedValue>
                  <name>1</name>
                  <description>Request Compute Operation.</description>
                  <value>#1</value>
                </enumeratedValue>
              </enumeratedValues>
            </field>
            <field>
              <name>CPOACK</name>
              <description>Compute Operation Acknowledge</description>
              <bitOffset>1</bitOffset>
              <bitWidth>1</bitWidth>
              <access>read-only</access>
              <enumeratedValues>
                <enumeratedValue>
                  <name>0</name>
                  <description>Compute operation entry has not completed or compute operation exit has completed.</description>
                  <value>#0</value>
                </enumeratedValue>
                <enumeratedValue>
                  <name>1</name>
                  <description>Compute operation entry has completed or compute operation exit has not completed.</description>
                  <value>#1</value>
                </enumeratedValue>
              </enumeratedValues>
            </field>
            <field>
              <name>CPOWOI</name>
              <description>Compute Operation Wake-up on Interrupt</description>
              <bitOffset>2</bitOffset>
              <bitWidth>1</bitWidth>
              <access>read-write</access>
              <enumeratedValues>
                <enumeratedValue>
                  <name>0</name>
                  <description>No effect.</description>
                  <value>#0</value>
                </enumeratedValue>
                <enumeratedValue>
                  <name>1</name>
                  <description>When set, the CPOREQ is cleared on any interrupt or exception vector fetch.</description>
                  <value>#1</value>
                </enumeratedValue>
              </enumeratedValues>
            </field>
          </fields>
        </register>
      </registers>
    </peripheral>
    <peripheral>
      <name>FGPIOA</name>
      <description>General Purpose Input/Output</description>
      <groupName>FGPIO</groupName>
      <prependToName>FGPIOA_</prependToName>
      <baseAddress>0xF8000000</baseAddress>
      <addressBlock>
        <offset>0</offset>
        <size>0x18</size>
        <usage>registers</usage>
      </addressBlock>
      <registers>
        <register>
          <name>PDOR</name>
          <description>Port Data Output Register</description>
          <addressOffset>0</addressOffset>
          <size>32</size>
          <access>read-write</access>
          <resetValue>0</resetValue>
          <resetMask>0xFFFFFFFF</resetMask>
          <fields>
            <field>
              <name>PDO</name>
              <description>Port Data Output</description>
              <bitOffset>0</bitOffset>
              <bitWidth>32</bitWidth>
              <access>read-write</access>
              <enumeratedValues>
                <enumeratedValue>
                  <name>0</name>
                  <description>Logic level 0 is driven on pin, provided pin is configured for general-purpose output.</description>
                  <value>#0</value>
                </enumeratedValue>
                <enumeratedValue>
                  <name>1</name>
                  <description>Logic level 1 is driven on pin, provided pin is configured for general-purpose output.</description>
                  <value>#1</value>
                </enumeratedValue>
              </enumeratedValues>
            </field>
          </fields>
        </register>
        <register>
          <name>PSOR</name>
          <description>Port Set Output Register</description>
          <addressOffset>0x4</addressOffset>
          <size>32</size>
          <access>write-only</access>
          <resetValue>0</resetValue>
          <resetMask>0xFFFFFFFF</resetMask>
          <fields>
            <field>
              <name>PTSO</name>
              <description>Port Set Output</description>
              <bitOffset>0</bitOffset>
              <bitWidth>32</bitWidth>
              <access>write-only</access>
              <enumeratedValues>
                <enumeratedValue>
                  <name>0</name>
                  <description>Corresponding bit in PDORn does not change.</description>
                  <value>#0</value>
                </enumeratedValue>
                <enumeratedValue>
                  <name>1</name>
                  <description>Corresponding bit in PDORn is set to logic 1.</description>
                  <value>#1</value>
                </enumeratedValue>
              </enumeratedValues>
            </field>
          </fields>
        </register>
        <register>
          <name>PCOR</name>
          <description>Port Clear Output Register</description>
          <addressOffset>0x8</addressOffset>
          <size>32</size>
          <access>write-only</access>
          <resetValue>0</resetValue>
          <resetMask>0xFFFFFFFF</resetMask>
          <fields>
            <field>
              <name>PTCO</name>
              <description>Port Clear Output</description>
              <bitOffset>0</bitOffset>
              <bitWidth>32</bitWidth>
              <access>write-only</access>
              <enumeratedValues>
                <enumeratedValue>
                  <name>0</name>
                  <description>Corresponding bit in PDORn does not change.</description>
                  <value>#0</value>
                </enumeratedValue>
                <enumeratedValue>
                  <name>1</name>
                  <description>Corresponding bit in PDORn is cleared to logic 0.</description>
                  <value>#1</value>
                </enumeratedValue>
              </enumeratedValues>
            </field>
          </fields>
        </register>
        <register>
          <name>PTOR</name>
          <description>Port Toggle Output Register</description>
          <addressOffset>0xC</addressOffset>
          <size>32</size>
          <access>write-only</access>
          <resetValue>0</resetValue>
          <resetMask>0xFFFFFFFF</resetMask>
          <fields>
            <field>
              <name>PTTO</name>
              <description>Port Toggle Output</description>
              <bitOffset>0</bitOffset>
              <bitWidth>32</bitWidth>
              <access>write-only</access>
              <enumeratedValues>
                <enumeratedValue>
                  <name>0</name>
                  <description>Corresponding bit in PDORn does not change.</description>
                  <value>#0</value>
                </enumeratedValue>
                <enumeratedValue>
                  <name>1</name>
                  <description>Corresponding bit in PDORn is set to the inverse of its existing logic state.</description>
                  <value>#1</value>
                </enumeratedValue>
              </enumeratedValues>
            </field>
          </fields>
        </register>
        <register>
          <name>PDIR</name>
          <description>Port Data Input Register</description>
          <addressOffset>0x10</addressOffset>
          <size>32</size>
          <access>read-only</access>
          <resetValue>0</resetValue>
          <resetMask>0xFFFFFFFF</resetMask>
          <fields>
            <field>
              <name>PDI</name>
              <description>Port Data Input</description>
              <bitOffset>0</bitOffset>
              <bitWidth>32</bitWidth>
              <access>read-only</access>
              <enumeratedValues>
                <enumeratedValue>
                  <name>0</name>
                  <description>Pin logic level is logic 0, or is not configured for use by digital function.</description>
                  <value>#0</value>
                </enumeratedValue>
                <enumeratedValue>
                  <name>1</name>
                  <description>Pin logic level is logic 1.</description>
                  <value>#1</value>
                </enumeratedValue>
              </enumeratedValues>
            </field>
          </fields>
        </register>
        <register>
          <name>PDDR</name>
          <description>Port Data Direction Register</description>
          <addressOffset>0x14</addressOffset>
          <size>32</size>
          <access>read-write</access>
          <resetValue>0</resetValue>
          <resetMask>0xFFFFFFFF</resetMask>
          <fields>
            <field>
              <name>PDD</name>
              <description>Port Data Direction</description>
              <bitOffset>0</bitOffset>
              <bitWidth>32</bitWidth>
              <access>read-write</access>
              <enumeratedValues>
                <enumeratedValue>
                  <name>0</name>
                  <description>Pin is configured as general-purpose input, for the GPIO function.</description>
                  <value>#0</value>
                </enumeratedValue>
                <enumeratedValue>
                  <name>1</name>
                  <description>Pin is configured as general-purpose output, for the GPIO function.</description>
                  <value>#1</value>
                </enumeratedValue>
              </enumeratedValues>
            </field>
          </fields>
        </register>
      </registers>
    </peripheral>
    <peripheral>
      <name>FGPIOB</name>
      <description>General Purpose Input/Output</description>
      <groupName>FGPIO</groupName>
      <prependToName>FGPIOB_</prependToName>
      <baseAddress>0xF8000040</baseAddress>
      <addressBlock>
        <offset>0</offset>
        <size>0x18</size>
        <usage>registers</usage>
      </addressBlock>
      <registers>
        <register>
          <name>PDOR</name>
          <description>Port Data Output Register</description>
          <addressOffset>0</addressOffset>
          <size>32</size>
          <access>read-write</access>
          <resetValue>0</resetValue>
          <resetMask>0xFFFFFFFF</resetMask>
          <fields>
            <field>
              <name>PDO</name>
              <description>Port Data Output</description>
              <bitOffset>0</bitOffset>
              <bitWidth>32</bitWidth>
              <access>read-write</access>
              <enumeratedValues>
                <enumeratedValue>
                  <name>0</name>
                  <description>Logic level 0 is driven on pin, provided pin is configured for general-purpose output.</description>
                  <value>#0</value>
                </enumeratedValue>
                <enumeratedValue>
                  <name>1</name>
                  <description>Logic level 1 is driven on pin, provided pin is configured for general-purpose output.</description>
                  <value>#1</value>
                </enumeratedValue>
              </enumeratedValues>
            </field>
          </fields>
        </register>
        <register>
          <name>PSOR</name>
          <description>Port Set Output Register</description>
          <addressOffset>0x4</addressOffset>
          <size>32</size>
          <access>write-only</access>
          <resetValue>0</resetValue>
          <resetMask>0xFFFFFFFF</resetMask>
          <fields>
            <field>
              <name>PTSO</name>
              <description>Port Set Output</description>
              <bitOffset>0</bitOffset>
              <bitWidth>32</bitWidth>
              <access>write-only</access>
              <enumeratedValues>
                <enumeratedValue>
                  <name>0</name>
                  <description>Corresponding bit in PDORn does not change.</description>
                  <value>#0</value>
                </enumeratedValue>
                <enumeratedValue>
                  <name>1</name>
                  <description>Corresponding bit in PDORn is set to logic 1.</description>
                  <value>#1</value>
                </enumeratedValue>
              </enumeratedValues>
            </field>
          </fields>
        </register>
        <register>
          <name>PCOR</name>
          <description>Port Clear Output Register</description>
          <addressOffset>0x8</addressOffset>
          <size>32</size>
          <access>write-only</access>
          <resetValue>0</resetValue>
          <resetMask>0xFFFFFFFF</resetMask>
          <fields>
            <field>
              <name>PTCO</name>
              <description>Port Clear Output</description>
              <bitOffset>0</bitOffset>
              <bitWidth>32</bitWidth>
              <access>write-only</access>
              <enumeratedValues>
                <enumeratedValue>
                  <name>0</name>
                  <description>Corresponding bit in PDORn does not change.</description>
                  <value>#0</value>
                </enumeratedValue>
                <enumeratedValue>
                  <name>1</name>
                  <description>Corresponding bit in PDORn is cleared to logic 0.</description>
                  <value>#1</value>
                </enumeratedValue>
              </enumeratedValues>
            </field>
          </fields>
        </register>
        <register>
          <name>PTOR</name>
          <description>Port Toggle Output Register</description>
          <addressOffset>0xC</addressOffset>
          <size>32</size>
          <access>write-only</access>
          <resetValue>0</resetValue>
          <resetMask>0xFFFFFFFF</resetMask>
          <fields>
            <field>
              <name>PTTO</name>
              <description>Port Toggle Output</description>
              <bitOffset>0</bitOffset>
              <bitWidth>32</bitWidth>
              <access>write-only</access>
              <enumeratedValues>
                <enumeratedValue>
                  <name>0</name>
                  <description>Corresponding bit in PDORn does not change.</description>
                  <value>#0</value>
                </enumeratedValue>
                <enumeratedValue>
                  <name>1</name>
                  <description>Corresponding bit in PDORn is set to the inverse of its existing logic state.</description>
                  <value>#1</value>
                </enumeratedValue>
              </enumeratedValues>
            </field>
          </fields>
        </register>
        <register>
          <name>PDIR</name>
          <description>Port Data Input Register</description>
          <addressOffset>0x10</addressOffset>
          <size>32</size>
          <access>read-only</access>
          <resetValue>0</resetValue>
          <resetMask>0xFFFFFFFF</resetMask>
          <fields>
            <field>
              <name>PDI</name>
              <description>Port Data Input</description>
              <bitOffset>0</bitOffset>
              <bitWidth>32</bitWidth>
              <access>read-only</access>
              <enumeratedValues>
                <enumeratedValue>
                  <name>0</name>
                  <description>Pin logic level is logic 0, or is not configured for use by digital function.</description>
                  <value>#0</value>
                </enumeratedValue>
                <enumeratedValue>
                  <name>1</name>
                  <description>Pin logic level is logic 1.</description>
                  <value>#1</value>
                </enumeratedValue>
              </enumeratedValues>
            </field>
          </fields>
        </register>
        <register>
          <name>PDDR</name>
          <description>Port Data Direction Register</description>
          <addressOffset>0x14</addressOffset>
          <size>32</size>
          <access>read-write</access>
          <resetValue>0</resetValue>
          <resetMask>0xFFFFFFFF</resetMask>
          <fields>
            <field>
              <name>PDD</name>
              <description>Port Data Direction</description>
              <bitOffset>0</bitOffset>
              <bitWidth>32</bitWidth>
              <access>read-write</access>
              <enumeratedValues>
                <enumeratedValue>
                  <name>0</name>
                  <description>Pin is configured as general-purpose input, for the GPIO function.</description>
                  <value>#0</value>
                </enumeratedValue>
                <enumeratedValue>
                  <name>1</name>
                  <description>Pin is configured as general-purpose output, for the GPIO function.</description>
                  <value>#1</value>
                </enumeratedValue>
              </enumeratedValues>
            </field>
          </fields>
        </register>
      </registers>
    </peripheral>
    <peripheral>
      <name>FGPIOC</name>
      <description>General Purpose Input/Output</description>
      <groupName>FGPIO</groupName>
      <prependToName>FGPIOC_</prependToName>
      <baseAddress>0xF8000080</baseAddress>
      <addressBlock>
        <offset>0</offset>
        <size>0x18</size>
        <usage>registers</usage>
      </addressBlock>
      <registers>
        <register>
          <name>PDOR</name>
          <description>Port Data Output Register</description>
          <addressOffset>0</addressOffset>
          <size>32</size>
          <access>read-write</access>
          <resetValue>0</resetValue>
          <resetMask>0xFFFFFFFF</resetMask>
          <fields>
            <field>
              <name>PDO</name>
              <description>Port Data Output</description>
              <bitOffset>0</bitOffset>
              <bitWidth>32</bitWidth>
              <access>read-write</access>
              <enumeratedValues>
                <enumeratedValue>
                  <name>0</name>
                  <description>Logic level 0 is driven on pin, provided pin is configured for general-purpose output.</description>
                  <value>#0</value>
                </enumeratedValue>
                <enumeratedValue>
                  <name>1</name>
                  <description>Logic level 1 is driven on pin, provided pin is configured for general-purpose output.</description>
                  <value>#1</value>
                </enumeratedValue>
              </enumeratedValues>
            </field>
          </fields>
        </register>
        <register>
          <name>PSOR</name>
          <description>Port Set Output Register</description>
          <addressOffset>0x4</addressOffset>
          <size>32</size>
          <access>write-only</access>
          <resetValue>0</resetValue>
          <resetMask>0xFFFFFFFF</resetMask>
          <fields>
            <field>
              <name>PTSO</name>
              <description>Port Set Output</description>
              <bitOffset>0</bitOffset>
              <bitWidth>32</bitWidth>
              <access>write-only</access>
              <enumeratedValues>
                <enumeratedValue>
                  <name>0</name>
                  <description>Corresponding bit in PDORn does not change.</description>
                  <value>#0</value>
                </enumeratedValue>
                <enumeratedValue>
                  <name>1</name>
                  <description>Corresponding bit in PDORn is set to logic 1.</description>
                  <value>#1</value>
                </enumeratedValue>
              </enumeratedValues>
            </field>
          </fields>
        </register>
        <register>
          <name>PCOR</name>
          <description>Port Clear Output Register</description>
          <addressOffset>0x8</addressOffset>
          <size>32</size>
          <access>write-only</access>
          <resetValue>0</resetValue>
          <resetMask>0xFFFFFFFF</resetMask>
          <fields>
            <field>
              <name>PTCO</name>
              <description>Port Clear Output</description>
              <bitOffset>0</bitOffset>
              <bitWidth>32</bitWidth>
              <access>write-only</access>
              <enumeratedValues>
                <enumeratedValue>
                  <name>0</name>
                  <description>Corresponding bit in PDORn does not change.</description>
                  <value>#0</value>
                </enumeratedValue>
                <enumeratedValue>
                  <name>1</name>
                  <description>Corresponding bit in PDORn is cleared to logic 0.</description>
                  <value>#1</value>
                </enumeratedValue>
              </enumeratedValues>
            </field>
          </fields>
        </register>
        <register>
          <name>PTOR</name>
          <description>Port Toggle Output Register</description>
          <addressOffset>0xC</addressOffset>
          <size>32</size>
          <access>write-only</access>
          <resetValue>0</resetValue>
          <resetMask>0xFFFFFFFF</resetMask>
          <fields>
            <field>
              <name>PTTO</name>
              <description>Port Toggle Output</description>
              <bitOffset>0</bitOffset>
              <bitWidth>32</bitWidth>
              <access>write-only</access>
              <enumeratedValues>
                <enumeratedValue>
                  <name>0</name>
                  <description>Corresponding bit in PDORn does not change.</description>
                  <value>#0</value>
                </enumeratedValue>
                <enumeratedValue>
                  <name>1</name>
                  <description>Corresponding bit in PDORn is set to the inverse of its existing logic state.</description>
                  <value>#1</value>
                </enumeratedValue>
              </enumeratedValues>
            </field>
          </fields>
        </register>
        <register>
          <name>PDIR</name>
          <description>Port Data Input Register</description>
          <addressOffset>0x10</addressOffset>
          <size>32</size>
          <access>read-only</access>
          <resetValue>0</resetValue>
          <resetMask>0xFFFFFFFF</resetMask>
          <fields>
            <field>
              <name>PDI</name>
              <description>Port Data Input</description>
              <bitOffset>0</bitOffset>
              <bitWidth>32</bitWidth>
              <access>read-only</access>
              <enumeratedValues>
                <enumeratedValue>
                  <name>0</name>
                  <description>Pin logic level is logic 0, or is not configured for use by digital function.</description>
                  <value>#0</value>
                </enumeratedValue>
                <enumeratedValue>
                  <name>1</name>
                  <description>Pin logic level is logic 1.</description>
                  <value>#1</value>
                </enumeratedValue>
              </enumeratedValues>
            </field>
          </fields>
        </register>
        <register>
          <name>PDDR</name>
          <description>Port Data Direction Register</description>
          <addressOffset>0x14</addressOffset>
          <size>32</size>
          <access>read-write</access>
          <resetValue>0</resetValue>
          <resetMask>0xFFFFFFFF</resetMask>
          <fields>
            <field>
              <name>PDD</name>
              <description>Port Data Direction</description>
              <bitOffset>0</bitOffset>
              <bitWidth>32</bitWidth>
              <access>read-write</access>
              <enumeratedValues>
                <enumeratedValue>
                  <name>0</name>
                  <description>Pin is configured as general-purpose input, for the GPIO function.</description>
                  <value>#0</value>
                </enumeratedValue>
                <enumeratedValue>
                  <name>1</name>
                  <description>Pin is configured as general-purpose output, for the GPIO function.</description>
                  <value>#1</value>
                </enumeratedValue>
              </enumeratedValues>
            </field>
          </fields>
        </register>
      </registers>
    </peripheral>
    <peripheral>
      <name>FGPIOD</name>
      <description>General Purpose Input/Output</description>
      <groupName>FGPIO</groupName>
      <prependToName>FGPIOD_</prependToName>
      <baseAddress>0xF80000C0</baseAddress>
      <addressBlock>
        <offset>0</offset>
        <size>0x18</size>
        <usage>registers</usage>
      </addressBlock>
      <registers>
        <register>
          <name>PDOR</name>
          <description>Port Data Output Register</description>
          <addressOffset>0</addressOffset>
          <size>32</size>
          <access>read-write</access>
          <resetValue>0</resetValue>
          <resetMask>0xFFFFFFFF</resetMask>
          <fields>
            <field>
              <name>PDO</name>
              <description>Port Data Output</description>
              <bitOffset>0</bitOffset>
              <bitWidth>32</bitWidth>
              <access>read-write</access>
              <enumeratedValues>
                <enumeratedValue>
                  <name>0</name>
                  <description>Logic level 0 is driven on pin, provided pin is configured for general-purpose output.</description>
                  <value>#0</value>
                </enumeratedValue>
                <enumeratedValue>
                  <name>1</name>
                  <description>Logic level 1 is driven on pin, provided pin is configured for general-purpose output.</description>
                  <value>#1</value>
                </enumeratedValue>
              </enumeratedValues>
            </field>
          </fields>
        </register>
        <register>
          <name>PSOR</name>
          <description>Port Set Output Register</description>
          <addressOffset>0x4</addressOffset>
          <size>32</size>
          <access>write-only</access>
          <resetValue>0</resetValue>
          <resetMask>0xFFFFFFFF</resetMask>
          <fields>
            <field>
              <name>PTSO</name>
              <description>Port Set Output</description>
              <bitOffset>0</bitOffset>
              <bitWidth>32</bitWidth>
              <access>write-only</access>
              <enumeratedValues>
                <enumeratedValue>
                  <name>0</name>
                  <description>Corresponding bit in PDORn does not change.</description>
                  <value>#0</value>
                </enumeratedValue>
                <enumeratedValue>
                  <name>1</name>
                  <description>Corresponding bit in PDORn is set to logic 1.</description>
                  <value>#1</value>
                </enumeratedValue>
              </enumeratedValues>
            </field>
          </fields>
        </register>
        <register>
          <name>PCOR</name>
          <description>Port Clear Output Register</description>
          <addressOffset>0x8</addressOffset>
          <size>32</size>
          <access>write-only</access>
          <resetValue>0</resetValue>
          <resetMask>0xFFFFFFFF</resetMask>
          <fields>
            <field>
              <name>PTCO</name>
              <description>Port Clear Output</description>
              <bitOffset>0</bitOffset>
              <bitWidth>32</bitWidth>
              <access>write-only</access>
              <enumeratedValues>
                <enumeratedValue>
                  <name>0</name>
                  <description>Corresponding bit in PDORn does not change.</description>
                  <value>#0</value>
                </enumeratedValue>
                <enumeratedValue>
                  <name>1</name>
                  <description>Corresponding bit in PDORn is cleared to logic 0.</description>
                  <value>#1</value>
                </enumeratedValue>
              </enumeratedValues>
            </field>
          </fields>
        </register>
        <register>
          <name>PTOR</name>
          <description>Port Toggle Output Register</description>
          <addressOffset>0xC</addressOffset>
          <size>32</size>
          <access>write-only</access>
          <resetValue>0</resetValue>
          <resetMask>0xFFFFFFFF</resetMask>
          <fields>
            <field>
              <name>PTTO</name>
              <description>Port Toggle Output</description>
              <bitOffset>0</bitOffset>
              <bitWidth>32</bitWidth>
              <access>write-only</access>
              <enumeratedValues>
                <enumeratedValue>
                  <name>0</name>
                  <description>Corresponding bit in PDORn does not change.</description>
                  <value>#0</value>
                </enumeratedValue>
                <enumeratedValue>
                  <name>1</name>
                  <description>Corresponding bit in PDORn is set to the inverse of its existing logic state.</description>
                  <value>#1</value>
                </enumeratedValue>
              </enumeratedValues>
            </field>
          </fields>
        </register>
        <register>
          <name>PDIR</name>
          <description>Port Data Input Register</description>
          <addressOffset>0x10</addressOffset>
          <size>32</size>
          <access>read-only</access>
          <resetValue>0</resetValue>
          <resetMask>0xFFFFFFFF</resetMask>
          <fields>
            <field>
              <name>PDI</name>
              <description>Port Data Input</description>
              <bitOffset>0</bitOffset>
              <bitWidth>32</bitWidth>
              <access>read-only</access>
              <enumeratedValues>
                <enumeratedValue>
                  <name>0</name>
                  <description>Pin logic level is logic 0, or is not configured for use by digital function.</description>
                  <value>#0</value>
                </enumeratedValue>
                <enumeratedValue>
                  <name>1</name>
                  <description>Pin logic level is logic 1.</description>
                  <value>#1</value>
                </enumeratedValue>
              </enumeratedValues>
            </field>
          </fields>
        </register>
        <register>
          <name>PDDR</name>
          <description>Port Data Direction Register</description>
          <addressOffset>0x14</addressOffset>
          <size>32</size>
          <access>read-write</access>
          <resetValue>0</resetValue>
          <resetMask>0xFFFFFFFF</resetMask>
          <fields>
            <field>
              <name>PDD</name>
              <description>Port Data Direction</description>
              <bitOffset>0</bitOffset>
              <bitWidth>32</bitWidth>
              <access>read-write</access>
              <enumeratedValues>
                <enumeratedValue>
                  <name>0</name>
                  <description>Pin is configured as general-purpose input, for the GPIO function.</description>
                  <value>#0</value>
                </enumeratedValue>
                <enumeratedValue>
                  <name>1</name>
                  <description>Pin is configured as general-purpose output, for the GPIO function.</description>
                  <value>#1</value>
                </enumeratedValue>
              </enumeratedValues>
            </field>
          </fields>
        </register>
      </registers>
    </peripheral>
    <peripheral>
      <name>FGPIOE</name>
      <description>General Purpose Input/Output</description>
      <groupName>FGPIO</groupName>
      <prependToName>FGPIOE_</prependToName>
      <baseAddress>0xF8000100</baseAddress>
      <addressBlock>
        <offset>0</offset>
        <size>0x18</size>
        <usage>registers</usage>
      </addressBlock>
      <registers>
        <register>
          <name>PDOR</name>
          <description>Port Data Output Register</description>
          <addressOffset>0</addressOffset>
          <size>32</size>
          <access>read-write</access>
          <resetValue>0</resetValue>
          <resetMask>0xFFFFFFFF</resetMask>
          <fields>
            <field>
              <name>PDO</name>
              <description>Port Data Output</description>
              <bitOffset>0</bitOffset>
              <bitWidth>32</bitWidth>
              <access>read-write</access>
              <enumeratedValues>
                <enumeratedValue>
                  <name>0</name>
                  <description>Logic level 0 is driven on pin, provided pin is configured for general-purpose output.</description>
                  <value>#0</value>
                </enumeratedValue>
                <enumeratedValue>
                  <name>1</name>
                  <description>Logic level 1 is driven on pin, provided pin is configured for general-purpose output.</description>
                  <value>#1</value>
                </enumeratedValue>
              </enumeratedValues>
            </field>
          </fields>
        </register>
        <register>
          <name>PSOR</name>
          <description>Port Set Output Register</description>
          <addressOffset>0x4</addressOffset>
          <size>32</size>
          <access>write-only</access>
          <resetValue>0</resetValue>
          <resetMask>0xFFFFFFFF</resetMask>
          <fields>
            <field>
              <name>PTSO</name>
              <description>Port Set Output</description>
              <bitOffset>0</bitOffset>
              <bitWidth>32</bitWidth>
              <access>write-only</access>
              <enumeratedValues>
                <enumeratedValue>
                  <name>0</name>
                  <description>Corresponding bit in PDORn does not change.</description>
                  <value>#0</value>
                </enumeratedValue>
                <enumeratedValue>
                  <name>1</name>
                  <description>Corresponding bit in PDORn is set to logic 1.</description>
                  <value>#1</value>
                </enumeratedValue>
              </enumeratedValues>
            </field>
          </fields>
        </register>
        <register>
          <name>PCOR</name>
          <description>Port Clear Output Register</description>
          <addressOffset>0x8</addressOffset>
          <size>32</size>
          <access>write-only</access>
          <resetValue>0</resetValue>
          <resetMask>0xFFFFFFFF</resetMask>
          <fields>
            <field>
              <name>PTCO</name>
              <description>Port Clear Output</description>
              <bitOffset>0</bitOffset>
              <bitWidth>32</bitWidth>
              <access>write-only</access>
              <enumeratedValues>
                <enumeratedValue>
                  <name>0</name>
                  <description>Corresponding bit in PDORn does not change.</description>
                  <value>#0</value>
                </enumeratedValue>
                <enumeratedValue>
                  <name>1</name>
                  <description>Corresponding bit in PDORn is cleared to logic 0.</description>
                  <value>#1</value>
                </enumeratedValue>
              </enumeratedValues>
            </field>
          </fields>
        </register>
        <register>
          <name>PTOR</name>
          <description>Port Toggle Output Register</description>
          <addressOffset>0xC</addressOffset>
          <size>32</size>
          <access>write-only</access>
          <resetValue>0</resetValue>
          <resetMask>0xFFFFFFFF</resetMask>
          <fields>
            <field>
              <name>PTTO</name>
              <description>Port Toggle Output</description>
              <bitOffset>0</bitOffset>
              <bitWidth>32</bitWidth>
              <access>write-only</access>
              <enumeratedValues>
                <enumeratedValue>
                  <name>0</name>
                  <description>Corresponding bit in PDORn does not change.</description>
                  <value>#0</value>
                </enumeratedValue>
                <enumeratedValue>
                  <name>1</name>
                  <description>Corresponding bit in PDORn is set to the inverse of its existing logic state.</description>
                  <value>#1</value>
                </enumeratedValue>
              </enumeratedValues>
            </field>
          </fields>
        </register>
        <register>
          <name>PDIR</name>
          <description>Port Data Input Register</description>
          <addressOffset>0x10</addressOffset>
          <size>32</size>
          <access>read-only</access>
          <resetValue>0</resetValue>
          <resetMask>0xFFFFFFFF</resetMask>
          <fields>
            <field>
              <name>PDI</name>
              <description>Port Data Input</description>
              <bitOffset>0</bitOffset>
              <bitWidth>32</bitWidth>
              <access>read-only</access>
              <enumeratedValues>
                <enumeratedValue>
                  <name>0</name>
                  <description>Pin logic level is logic 0, or is not configured for use by digital function.</description>
                  <value>#0</value>
                </enumeratedValue>
                <enumeratedValue>
                  <name>1</name>
                  <description>Pin logic level is logic 1.</description>
                  <value>#1</value>
                </enumeratedValue>
              </enumeratedValues>
            </field>
          </fields>
        </register>
        <register>
          <name>PDDR</name>
          <description>Port Data Direction Register</description>
          <addressOffset>0x14</addressOffset>
          <size>32</size>
          <access>read-write</access>
          <resetValue>0</resetValue>
          <resetMask>0xFFFFFFFF</resetMask>
          <fields>
            <field>
              <name>PDD</name>
              <description>Port Data Direction</description>
              <bitOffset>0</bitOffset>
              <bitWidth>32</bitWidth>
              <access>read-write</access>
              <enumeratedValues>
                <enumeratedValue>
                  <name>0</name>
                  <description>Pin is configured as general-purpose input, for the GPIO function.</description>
                  <value>#0</value>
                </enumeratedValue>
                <enumeratedValue>
                  <name>1</name>
                  <description>Pin is configured as general-purpose output, for the GPIO function.</description>
                  <value>#1</value>
                </enumeratedValue>
              </enumeratedValues>
            </field>
          </fields>
        </register>
      </registers>
    </peripheral>
  </peripherals>
</device>
